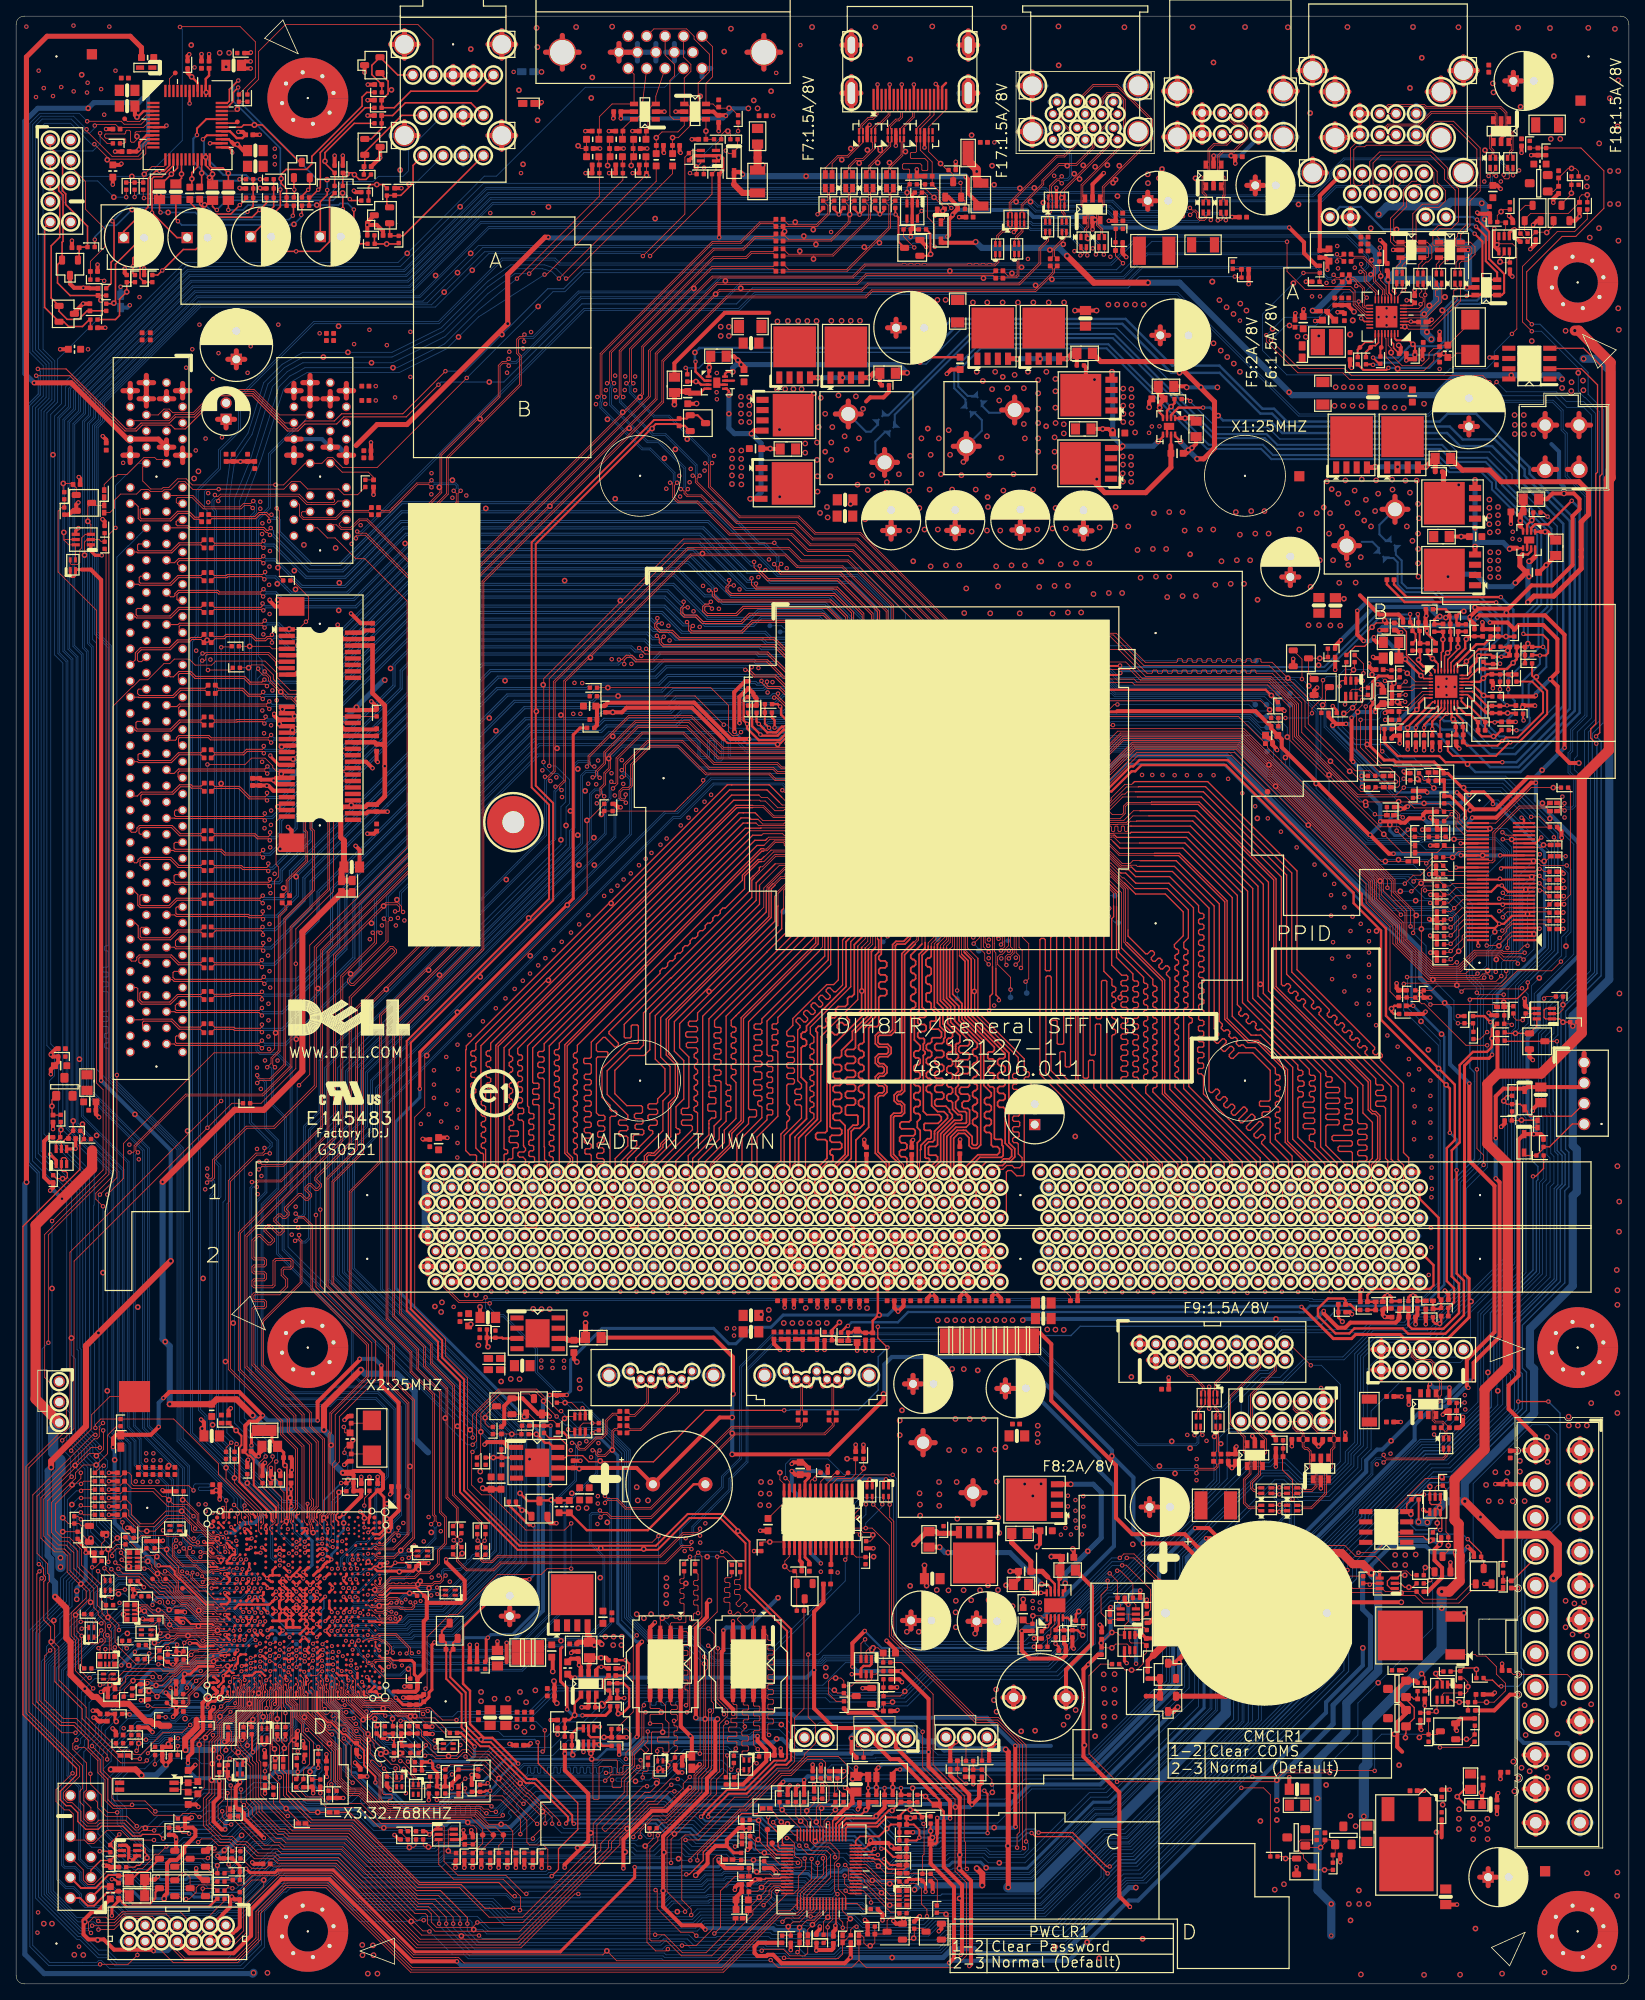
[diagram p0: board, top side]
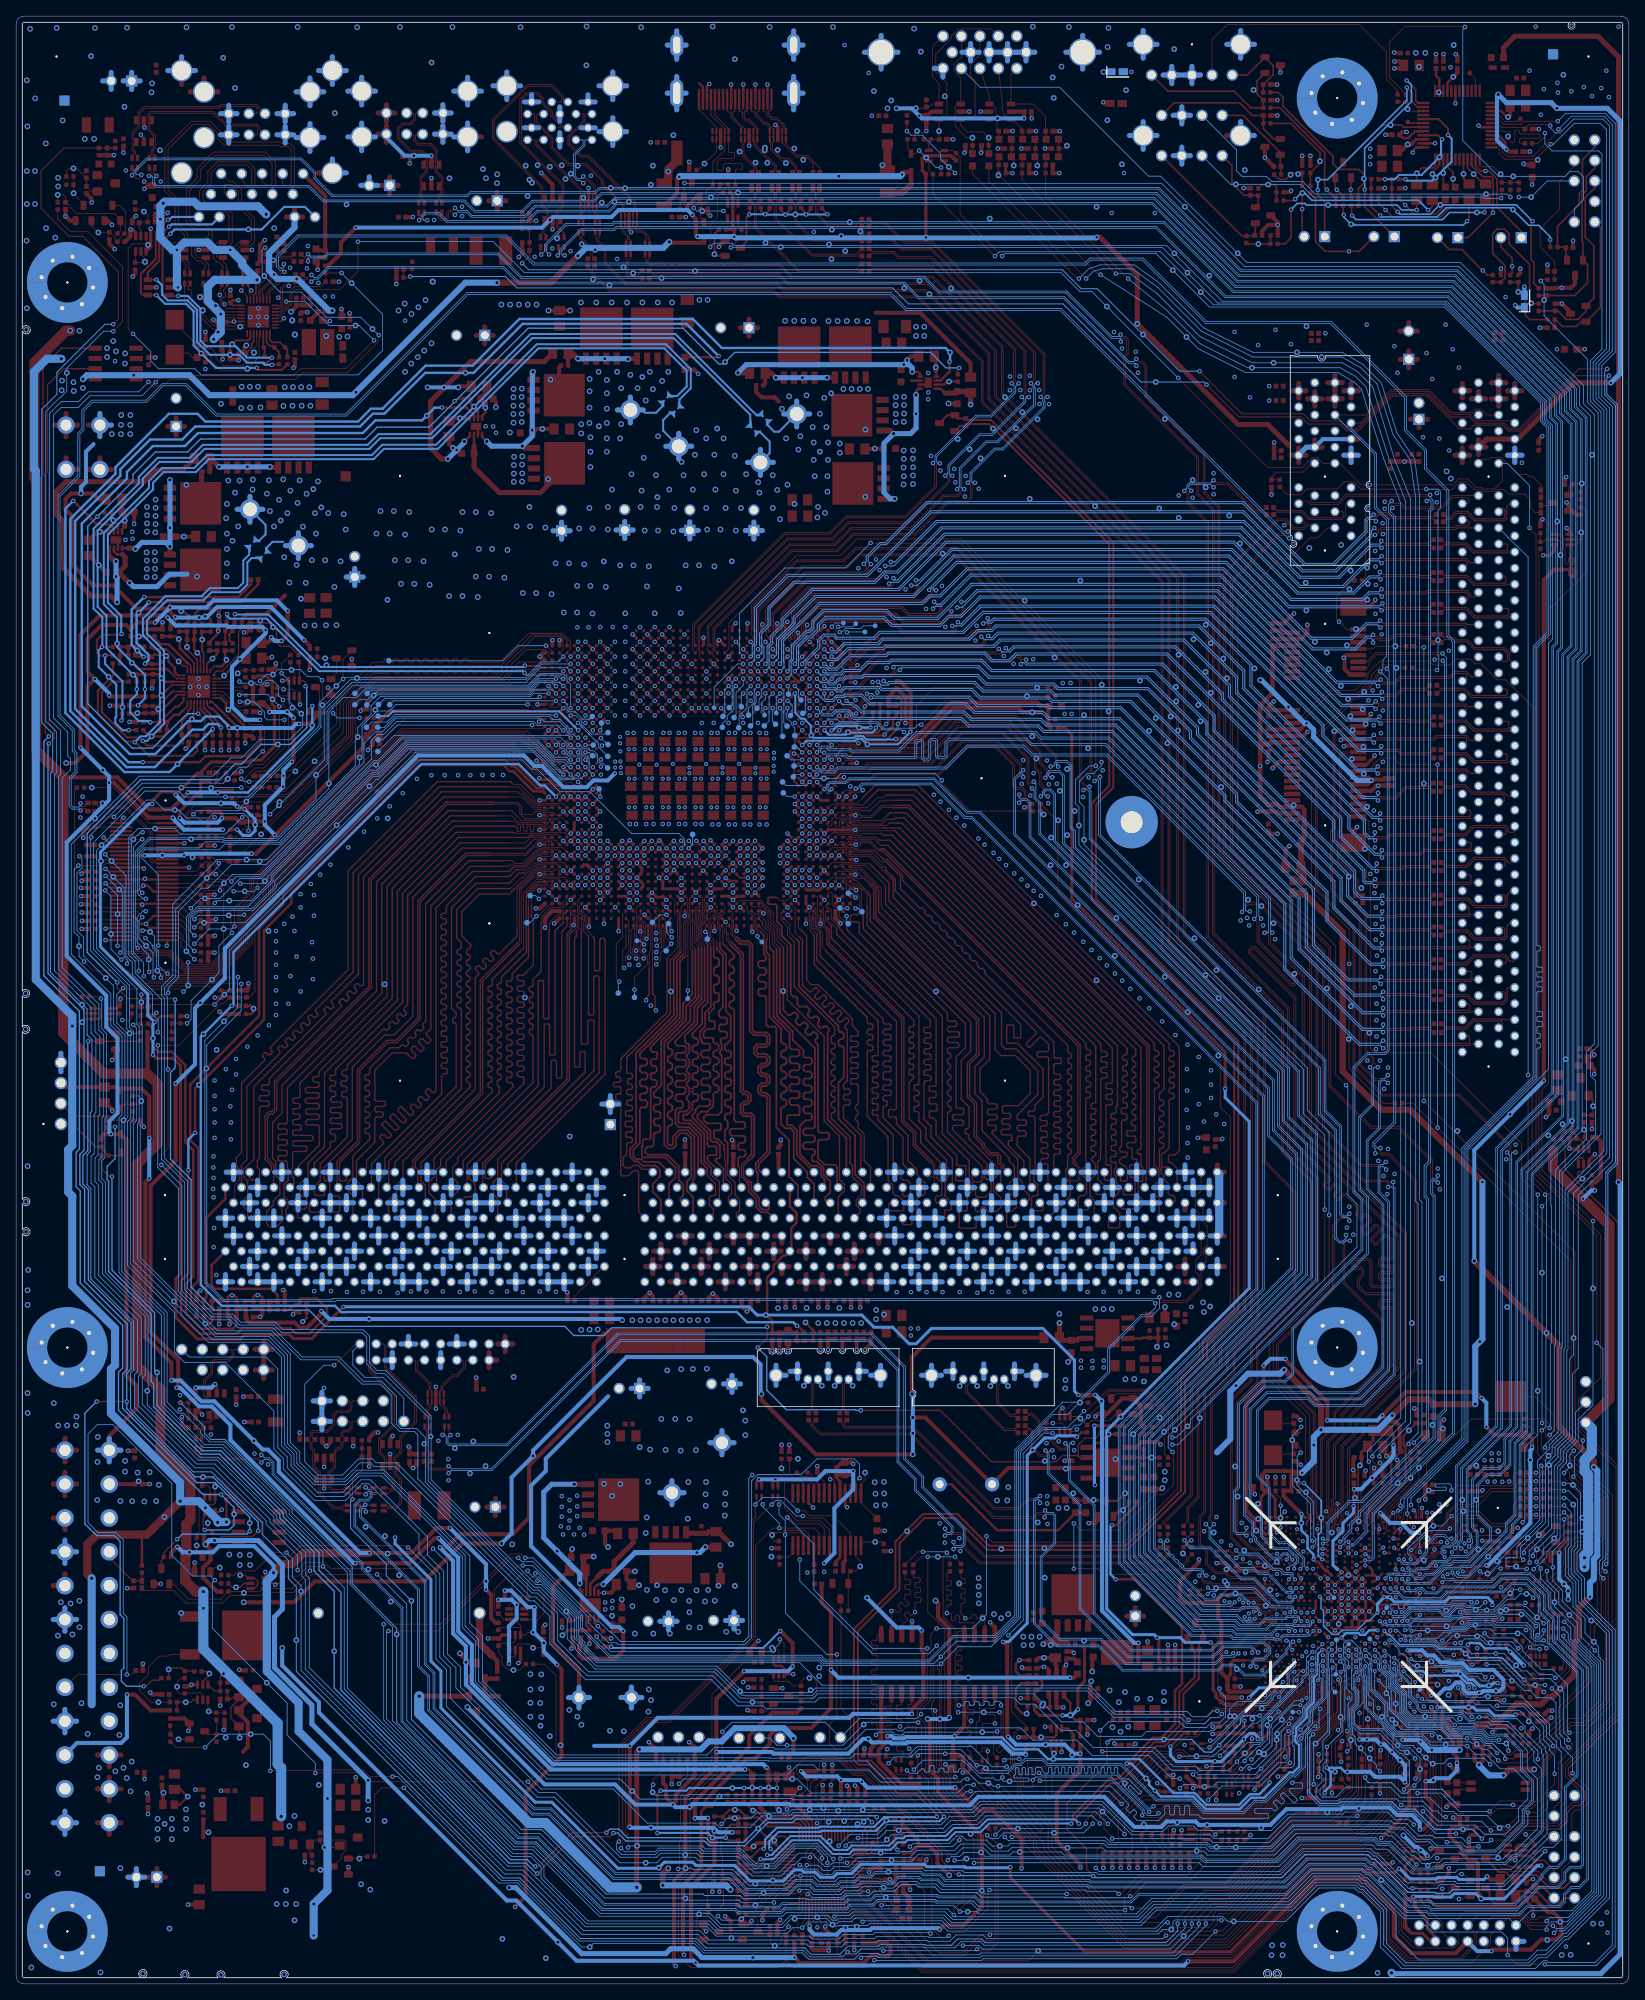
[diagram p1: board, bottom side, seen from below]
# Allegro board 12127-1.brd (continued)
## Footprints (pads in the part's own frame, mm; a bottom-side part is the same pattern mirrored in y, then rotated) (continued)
SLP2510P8-1H22
  rect 0.305x0.762 smd: 1(-1,-0.5) 5(1,-0.5) 6(1,0.5) 10(-1,0.5)
  rect 0.203x0.762 smd: 2(-0.5,-0.5) 4(0.5,-0.5) 7(0.5,0.5) 9(-0.5,0.5)
  rect 0.406x0.762 smd: 3(0,-0.5) 8(0,0.5)
SMD49-4H56
  rect 2.438x2.261 smd: 1(-2.165,0) 2(2.165,0)
SMD49-6914-0403H56
  rect 1.168x0.559 smd: 1(-3.38,-0.427) 2(3.38,-0.427) 3(3.38,0.427) 4(-3.38,0.427)
SMD-ARES4
  rect 0.356x0.66 smd: 1(-0.325,-0.599) 2(0.325,-0.599) 3(0.325,0.599) 4(-0.325,0.599)
SMD-ARES4H18
  rect 0.356x0.66 smd: 1(-0.325,-0.599) 2(0.325,-0.599) 3(0.325,0.599) 4(-0.325,0.599)
SMD-TO-252-4H94
  rect 1.6x2.997 smd: 1(-2.286,0) 3(2.286,0)
  rect 6.756x6.756 smd: 2(0,6.807)
SMD-TO-252-DGS6698H99
  rect 6.172x5.588 smd: D(0,6.808)
  rect 1.295x2.438 smd: G(-2.35,0) S(2.35,0)
SOD323AKH38
  rect 0.559x1.016 smd: A(0,1.143) K(0,-1.143)
SOD323AKH42
  rect 0.559x1.016 smd: A(0,1.143) K(0,-1.143)
SOD523AKH28
  rect 0.559x1.016 smd: A(0,0.762) K(0,-0.762)
SOIC8-1H86
  rect 0.635x1.651 smd: 1(-1.905,-3.493) 2(-0.635,-3.493) 3(0.635,-3.493) 4(1.905,-3.493) 5(1.905,3.493) 6(0.635,3.493) 7(-0.635,3.493) 8(-1.905,3.493)
SOIC8-G3530H63
  rect 0.635x1.651 smd: 1(-1.905,-2.555) 2(-0.635,-2.555) 3(0.635,-2.555) 4(1.905,-2.555) 5(1.905,2.555) 6(0.635,2.555) 7(-0.635,2.555) 8(-1.905,2.555)
  rect 3.505x2.997 smd: 9(0,0)
SOIC8H79
  rect 0.635x1.651 smd: 1(-1.905,-2.54) 2(-0.635,-2.54) 3(0.635,-2.54) 4(1.905,-2.54) 5(1.905,2.54) 6(0.635,2.54) 7(-0.635,2.54) 8(-1.905,2.54)
SOT23-2D4-312H44
  custom 0.191x0.191 smd: 1(-0.984,-0.953) 2(0.984,-0.953) 3(0,0.953)
SOT23-2D4-312H46
  custom 0.191x0.191 smd: 1(-0.984,-0.953) 2(0.984,-0.953) 3(0,0.953)
SOT23-2D4-312H48
  custom 0.191x0.191 smd: 1(-0.984,-0.953) 2(0.984,-0.953) 3(0,0.953)
SOT23CBE2D4H44
  custom 0.191x0.191 smd: B(-0.984,-0.953) C(0,0.953) E(0.984,-0.953)
SOT23DGS2D4H44
  custom 0.191x0.191 smd: D(0,0.953) G(-0.984,-0.953) S(0.984,-0.953)
SOT23DGS2D8H50
  custom 0.254x0.254 smd: D(0,1.118) G(-1.016,-1.118) S(1.016,-1.118)
SOT-6H58
  rect 0.584x1.016 smd: 1(-0.953,-1.346) 2(0,-1.346) 3(0.953,-1.346) 4(0.953,1.346) 5(0,1.346) 6(-0.953,1.346)
SOT-363H44
  rect 0.406x1.016 smd: 1(-0.65,-0.94) 2(0,-0.94) 3(0.65,-0.94) 4(0.65,0.94) 5(0,0.94) 6(-0.65,0.94)
STF256R107H132
  round 6.502 hole 2.718: 1(0,0)
T11-0061-1A40-4-U
  round 1.422 hole 1.016: 1(-5.08,-1.27) 2(-5.08,1.27) 3(-2.54,-1.27) 4(-2.54,1.27) 5(0,-1.27) 6(0,1.27) 7(2.54,-1.27) 9(5.08,-1.27) 10(5.08,1.27)
  rect 0.025x0.025 smd: 8(2.54,1.27)
TPAD24
  round 0.61 smd: 1(0,0)
TPAD28
  round 0.711 smd: 1(0,0)
TPAD385X385
  rect 3.861x3.861 smd: 1(0,0)
TSOIC28-3H44
  rect 0.356x1.524 smd: 1(-4.225,-3.669) 2(-3.575,-3.669) 3(-2.925,-3.669) 4(-2.275,-3.669) 5(-1.626,-3.669) 6(-0.975,-3.669) 7(-0.325,-3.669) 8(0.325,-3.669) 9(0.975,-3.669) 10(1.626,-3.669) 11(2.275,-3.669) 12(2.925,-3.669) 13(3.575,-3.669) 14(4.225,-3.669) 15(4.225,3.669) 16(3.575,3.669) 17(2.925,3.669) 18(2.275,3.669) 19(1.626,3.669) 20(0.975,3.669) 21(0.325,3.669) 22(-0.325,3.669) 23(-0.975,3.669) 24(-1.626,3.669) 25(-2.275,3.669) 26(-2.925,3.669) 27(-3.575,3.669) 28(-4.225,3.669)
TSOIC28H48
  rect 0.356x1.524 smd: 1(-4.225,-2.805) 2(-3.575,-2.805) 3(-2.925,-2.805) 4(-2.275,-2.805) 5(-1.626,-2.805) 6(-0.975,-2.805) 7(-0.325,-2.805) 8(0.325,-2.805) 9(0.975,-2.805) 10(1.626,-2.805) 11(2.275,-2.805) 12(2.925,-2.805) 13(3.575,-2.805) 14(4.225,-2.805) 15(4.225,2.805) 16(3.575,2.805) 17(2.925,2.805) 18(2.275,2.805) 19(1.626,2.805) 20(0.975,2.805) 21(0.325,2.805) 22(-0.325,2.805) 23(-0.975,2.805) 24(-1.626,2.805) 25(-2.275,2.805) 26(-2.925,2.805) 27(-3.575,2.805) 28(-4.225,2.805)
unnamed
  round 0.254 hole 3.099 unplated: (0,0)

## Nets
5V_DUAL: L45.2 PR83.2 Q46.D Q47.D Q51.D R736.1 R739.2
5VDDCCL: C20.1 R13.2 U24.6 VGA1.15
5VDDCCL_R: R13.1 R15.2 U4.6
5VDDCDA: C21.1 R14.2 U24.4 VGA1.12
5VDDCDA_R: R14.1 R16.2 U4.3
5VDUAL_NCH: Q49.6 R468.2 R2238.1
5VDUAL_PCH: Q49.3 R131.1 R471.2
5VDUAL_PCH_R: C96.1 Q46.G Q47.G R131.2
5VDUAL_USB_F: C410.1 F8.1 F9.2 R644.1 R734.1 U31.5 U31.6 U31.7 U31.8
5VDUAL_USB_R: C111.1 F5.1 F6.2 F18.2 U14.5 U14.6 U14.7 U14.8
+5V_VGA: C9.1 C12.1 C65.1 L4.1 U1.5 U24.5 VGA1.9
+12V: ATX1.10 ATX1.11 C121.1 C122.1 C124.1 C125.1 C146.1 C184.1 C304.1 C382.1 C408.1 D37.K FNCPU1.2 G5.2 Q38.G R352.1 R468.1 R688.1 R773.1 R2246.1 SLOT1.A2 SLOT1.A3 SLOT1.B1 SLOT1.B2 SLOT1.B3 SLOT2.A2 SLOT2.A3 SLOT2.B1 SLOT2.B2 SLOT2.B3 TC11.1
-12V: ATX1.14 C407.1
AGND: AUDF1.2 AUDF1.7 AUDJK1.1 AUDJK1.4 AUDJK1.24 AUDJK1.34 AUDJK1.G1 AUDJK1.G2 AUDJK1.G3 AUDJK1.G4 C1.2 C2.2 C3.2 C5.2 C6.2 C8.2 C13.2 C17.2 C28.2 C38.2 C55.2 C60.2 C73.1 C80.1 C82.2 C92.2 C102.2 H1.1 H1.2 H1.3 H1.4 H1.5 H1.6 H1.7 H1.8 Q9.3 Q10.3 Q11.3 Q14.3 Q17.3 R6.2 R7.2 R11.2 R12.2 R29.2 R43.2 R44.2 R77.2 R90.2 R92.2 R110.2 R117.2 R130.2 R171.2 R777.2 U2.26 U2.42
GND: ATX1.3 ATX1.5 ATX1.7 ATX1.15 ATX1.17 ATX1.18 ATX1.19 ATX1.24 ATX12V.1 ATX12V.2 BT1.2 C4.2 C9.2 C12.2 C14.2 C15.2 C18.2 C19.2 C20.2 C21.2 C22.2 C23.2 C24.2 C25.2 C26.2 C27.2 C31.2 C34.2 C35.2 C36.2 C42.2 C51.2 C53.2 C54.2 C56.2 C57.2 C59.2 C64.2 C65.2 C70.2 C71.2 C72.2 C74.2 C75.2 C76.2 C77.2 C83.2 C86.2 C88.2 C89.2 C90.2 C91.2 C93.2 C94.2 C95.2 C96.2 C97.2 C100.2 C103.2 C108.2 C111.2 C112.2 C113.2 C114.2 C119.2 C120.2 C121.2 C122.2 C123.2 C124.2 C125.2 C127.2 C128.1 C129.2 C132.2 C133.2 C134.2 C135.2 C136.2 C137.2 C139.2 C140.2 C141.2 C142.2 C143.2 C144.2 C145.2 C146.2 C151.2 C152.2 C153.2 C172.2 C174.2 C177.1 C179.2 C180.1 C181.2 C183.2 C184.2 C186.2 C187.2 C191.2 C194.2 C195.2 C198.2 C200.2 C202.2 C205.2 C213.2 C227.2 C229.2 C231.2 C232.2 C235.2 C236.2 C237.1 C239.2 C240.2 C252.2 C253.2 C254.2 C266.2 C267.2 C270.2 C271.2 C304.2 C306.2 C308.2 C310.2 C315.2 C350.2 C352.2 C353.2 C354.2 C355.2 C366.2 C368.2 C369.2 C370.2 C373.2 C374.2 C375.2 C376.2 C377.2 C378.2 C379.2 C380.2 C381.2 C382.2 C385.2 C386.2 C387.2 C388.2 C389.2 C390.2 C391.2 C392.2 C393.2 C394.2 C395.2 C396.2 C397.2 C398.2 C399.2 C400.2 C402.2 C404.2 C407.2 C408.2 C410.2 C411.2 C412.2 C414.2 C415.2 C417.2 C418.2 C420.2 C421.2 C422.2 C423.2 C424.2 C429.2 C433.2 C434.2 C435.2 C436.2 C438.2 C440.2 C441.2 C443.2 C445.2 C446.2 C447.2 C451.2 C456.2 C460.2 C461.2 C462.2 C463.2 C466.2 C467.2 C469.2 C470.2 C472.2 C475.2 C477.2 C478.2 C479.2 C483.2 C484.2 C489.2 C491.2 C496.2 C499.2 C500.2 C501.2 C502.2 C503.2 C504.2 C505.2 C506.2 C512.2 C516.2 C518.2 C520.2 C521.2 C522.2 C523.2 C524.2 C525.2 C526.2 C527.2 C528.2 C536.2 C537.2 C540.2 C541.2 C542.2 C544.2 C545.2 C546.2 C547.2 C548.2 C549.2 C550.2 C551.2 C552.2 C556.2 C557.2 C558.2 C560.2 C561.2 C562.2 C563.2 C564.2 C565.2 C566.2 C567.2 C568.2 C569.2 C570.2 C571.2 C572.2 C573.2 C574.2 C575.2 C576.2 C577.2 C578.2 C579.2 C580.2 C581.2 C582.2 C583.2 C584.2 C585.2 C586.2 C587.2 C588.2 C589.2 C590.2 C591.2 C592.2 C593.2 C594.2 C595.2 C596.2 C597.2 C598.2 C599.2 C600.2 C601.2 C602.2 C603.2 C604.2 C605.2 C606.2 C607.2 C608.2 C609.2 C610.2 C611.2 C612.2 C613.2 C614.2 C615.2 C616.2 C678.2 C680.2 C1669.2 C1671.2 C1672.2 C1673.2 C3315.2 C3316.1 C3317.1 C3318.1 C3319.1 C3320.2 C3321.2 C3322.1 C3323.1 C3324.2 C3325.2 C3326.2 C3327.2 D2.A DB1.2 DIMM1.2 DIMM1.5 DIMM1.8 DIMM1.11 DIMM1.14 DIMM1.17 DIMM1.20 DIMM1.23 DIMM1.26 DIMM1.29 DIMM1.32 DIMM1.35 DIMM1.38 DIMM1.41 DIMM1.44 DIMM1.47 DIMM1.80 DIMM1.83 DIMM1.86 DIMM1.89 DIMM1.92 DIMM1.95 DIMM1.98 DIMM1.101 DIMM1.104 DIMM1.107 DIMM1.110 DIMM1.113 DIMM1.116 DIMM1.117 DIMM1.119 DIMM1.121 DIMM1.124 DIMM1.125 DIMM1.127 DIMM1.130 DIMM1.133 DIMM1.134 DIMM1.136 DIMM1.139 DIMM1.142 DIMM1.143 DIMM1.145 DIMM1.148 DIMM1.151 DIMM1.152 DIMM1.154 DIMM1.157 DIMM1.160 DIMM1.161 DIMM1.163 DIMM1.166 DIMM1.199 DIMM1.202 DIMM1.203 DIMM1.205 DIMM1.208 DIMM1.211 DIMM1.212 DIMM1.214 DIMM1.217 DIMM1.220 DIMM1.221 DIMM1.223 DIMM1.226 DIMM1.229 DIMM1.230 DIMM1.232 DIMM1.235 DIMM1.237 DIMM1.239 DIMM2.2 DIMM2.5 DIMM2.8 DIMM2.11 DIMM2.14 DIMM2.17 DIMM2.20 DIMM2.23 DIMM2.26 DIMM2.29 DIMM2.32 DIMM2.35 DIMM2.38 DIMM2.41 DIMM2.44 DIMM2.47 DIMM2.80 DIMM2.83 DIMM2.86 DIMM2.89 DIMM2.92 DIMM2.95 DIMM2.98 DIMM2.101 DIMM2.104 DIMM2.107 DIMM2.110 DIMM2.113 DIMM2.116 DIMM2.117 DIMM2.119 DIMM2.121 DIMM2.124 DIMM2.125 DIMM2.127 DIMM2.130 DIMM2.133 DIMM2.134 DIMM2.136 DIMM2.139 DIMM2.142 DIMM2.143 DIMM2.145 DIMM2.148 DIMM2.151 DIMM2.152 DIMM2.154 DIMM2.157 DIMM2.160 DIMM2.161 DIMM2.163 DIMM2.166 DIMM2.199 DIMM2.202 DIMM2.203 DIMM2.205 DIMM2.208 DIMM2.211 DIMM2.212 DIMM2.214 DIMM2.217 DIMM2.220 DIMM2.221 DIMM2.223 DIMM2.226 DIMM2.229 DIMM2.230 DIMM2.232 DIMM2.235 DIMM2.239 DQ61.E FNCPU1.1 G7.1 H2.1 H2.2 H2.3 H2.4 H2.5 H2.6 H2.7 H2.8 H3.1 H3.2 H3.3 H3.4 H3.5 H3.6 H3.7 H3.8 H4.1 H4.2 H4.3 H4.4 H4.5 H4.6 H4.7 H4.8 H5.1 H5.2 H5.3 H5.4 H5.5 H5.6 H5.7 H5.8 H6.1 H6.2 H6.3 H6.4 H6.5 H6.6 H6.7 H6.8 H7.1 HDMI1.2 HDMI1.5 HDMI1.8 HDMI1.11 HDMI1.17 HDMI1.20 HDMI1.21 HDMI1.22 HDMI1.23 LED1.1 LEDH1.5 LEDH1.12 LPC1.12 LPC1.14 MINI1.4 MINI1.9 MINI1.15 MINI1.18 MINI1.21 MINI1.26 MINI1.27 MINI1.29 MINI1.34 MINI1.35 MINI1.43 MINI1.50 MINI1.53 MINI1.54 PC65.2 PC72.2 PC73.2 PC352.2 PR84.2 PR85.2 PR106.2 PU8.11 PWCLR1.1 Q4.S Q15.1 Q15.2 Q15.3 Q22.1 Q22.2 Q22.3 Q23.1 Q23.2 Q23.3 Q28.1 Q28.2 Q28.3 Q29.1 Q29.2 Q29.3 Q30.1 Q30.2 Q30.3 Q37.1 Q37.4 Q40.4 Q42.4 Q43.1 Q43.2 Q43.3 Q44.E Q45.E Q48.1 Q48.4 Q49.1 Q50.4 Q53.E Q54.S Q55.1 Q55.4 Q56.S Q57.E Q58.S Q59.E Q60.E Q62.1 Q62.4 Q64.1 Q64.4 Q67.1 Q70.E Q72.E Q73.1 Q73.4 Q74.E Q77.S Q78.S Q79.E Q80.S Q108.1 Q108.4 Q109.E Q110.E QF2.1 QF2.4 R11.1 R20.1 R21.1 R25.2 R29.1 R30.1 R31.1 R32.1 R67.1 R105.2 R108.2 R110.1 R111.2 R117.1 R133.1 R140.1 R145.1 R171.1 R172.1 R207.2 R209.2 R219.2 R220.2 R221.2 R225.2 R231.2 R239.2 R261.2 R288.2 R299.2 R341.1 R351.2 R358.2 R388.1 R393.2 R395.2 R398.2 R401.2 R403.2 R410.1 R412.2 R413.2 R417.2 R425.2 R426.2 R428.2 R438.2 R442.1 R445.2 R457.2 R464.2 R472.2 R476.2 R492.2 R498.2 R514.1 R518.2 R538.2 R541.2 R552.2 R554.2 R559.2 R562.2 R564.2 R571.2 R572.2 R579.1 R596.2 R597.1 R617.2 R620.2 R624.2 R633.2 R641.2 R643.2 R649.2 R650.2 R655.2 R657.2 R659.2 R661.1 R662.2 R663.1 R665.2 R668.2 R687.2 R712.2 R717.2 R736.2 R747.2 R755.2 R764.2 R793.2 R794.2 R796.2 R797.2 R798.2 R804.2 R812.2 R816.2 R818.2 R824.1 R826.1 R827.1 R828.1 R829.1 R830.1 R831.1 R832.1 R833.1 R834.1 R835.1 R836.1 R837.1 R838.1 R839.1 R840.2 R841.2 R842.1 R844.1 R845.1 R848.1 R849.1 R853.2 R856.2 R859.2 R864.2 R1248.2 R1549.2 R2215.2 R2217.2 R2219.2 R2226.2 R2231.2 RJ45.G1 RJ45.G2 RJ45.G3 RJ45.G4 RJ45.G5 RJ45.G6 RJ45.G7 RJ45.G8 RJ45.R10 RJ45.U4 RJ45.U8 RN31.3(B) RN31.4(B) RN32.3(B) RN32.4(B) RN33.1(A) RN33.2(A) RN34.3(B) RN34.4(B) SATA0.1 SATA0.4 SATA0.7 SATA0.8 SATA0.9 SATA1.1 SATA1.4 SATA1.7 SATA1.8 SATA1.9 SLOT1.A4 SLOT1.A12 SLOT1.A15 SLOT1.A18 SLOT1.B4 SLOT1.B7 SLOT1.B13 SLOT1.B16 SLOT1.B18 SLOT2.A4 SLOT2.A12 SLOT2.A15 SLOT2.A18 SLOT2.A20 SLOT2.A23 SLOT2.A24 SLOT2.A27 SLOT2.A28 SLOT2.A31 SLOT2.A34 SLOT2.A37 SLOT2.A38 SLOT2.A41 SLOT2.A42 SLOT2.A45 SLOT2.A46 SLOT2.A49 SLOT2.A51 SLOT2.A54 SLOT2.A55 SLOT2.A58 SLOT2.A59 SLOT2.A62 SLOT2.A63 SLOT2.A66 SLOT2.A67 SLOT2.A70 SLOT2.A71 SLOT2.A74 SLOT2.A75 SLOT2.A78 SLOT2.A79 SLOT2.A82 SLOT2.B4 SLOT2.B7 SLOT2.B13 SLOT2.B16 SLOT2.B18 SLOT2.B21 SLOT2.B22 SLOT2.B25 SLOT2.B26 SLOT2.B29 SLOT2.B32 SLOT2.B35 SLOT2.B36 SLOT2.B39 SLOT2.B40 SLOT2.B43 SLOT2.B44 SLOT2.B47 SLOT2.B49 SLOT2.B52 SLOT2.B53 SLOT2.B56 SLOT2.B57 SLOT2.B60 SLOT2.B61 SLOT2.B64 SLOT2.B65 SLOT2.B68 SLOT2.B69 SLOT2.B72 SLOT2.B73 SLOT2.B76 SLOT2.B77 SLOT2.B80 TC1.2 TC2.2 TC3.2 TC9.2 TC10.2 TC11.2 TC12.2 TC13.2 TC15.2 TC22.2 TC29.2 TC34.2 TC38.2 TC40.2 TC41.2 TC42.2 TC45.2 U1.2 U2.7 U6.2 U8.6 U8.9 U9.2 U10.3 U10.8 U11.2 U12.33 U13.2 U13.9 U15.3 U15.8 U16.6 U16.9 U17.2 U18.6 U18.9 U22.4 U22.11 U22.18 U23.4 U23.11 U23.18 U24.2 U25.3 U25.8 U26.2 U27.A5 U27.A7 U27.A11 U27.A13 U27.A15 U27.A17 U27.A23 U27.AA3 U27.AA6 U27.AA7 U27.AA8 U27.AA33 U27.AA35 U27.AA38 U27.AB5 U27.AB7 U27.AB34 U27.AB37 U27.AC3 U27.AC6 U27.AC7 U27.AC33 U27.AC34 U27.AC35 U27.AC36 U27.AC37 U27.AC38 U27.AC39 U27.AC40 U27.AD1 U27.AD2 U27.AD3 U27.AD4 U27.AD5 U27.AD6 U27.AD7 U27.AD8 U27.AD33 U27.AD36 U27.AE5 U27.AE8 U27.AE33 U27.AE36 U27.AE37 U27.AE40 U27.AF1 U27.AF4 U27.AF5 U27.AF8 U27.AF33 U27.AF36 U27.AG5 U27.AG8 U27.AG33 U27.AG36 U27.AG37 U27.AG38 U27.AG39 U27.AG40 U27.AH1 U27.AH2 U27.AH3 U27.AH4 U27.AH5 U27.AH8 U27.AH33 U27.AH36 U27.AJ5 U27.AJ8 U27.AJ11 U27.AJ14 U27.AJ16 U27.AJ18 U27.AJ19 U27.AJ22 U27.AJ23 U27.AJ26 U27.AJ27 U27.AJ30 U27.AJ31 U27.AJ32 U27.AJ33 U27.AJ34 U27.AJ35 U27.AJ36 U27.AJ37 U27.AJ40 U27.AK1 U27.AK4 U27.AK5 U27.AK6 U27.AK7 U27.AK8 U27.AK9 U27.AK10 U27.AK11 U27.AK12 U27.AK13 U27.AK14 U27.AK18 U27.AK19 U27.AK24 U27.AK25 U27.AK26 U27.AK27 U27.AK28 U27.AK29 U27.AK30 U27.AK36 U27.AL5 U27.AL11 U27.AL14 U27.AL17 U27.AL21 U27.AL22 U27.AL24 U27.AL27 U27.AL30 U27.AL36 U27.AL37 U27.AL38 U27.AL39 U27.AL40 U27.AM1 U27.AM2 U27.AM3 U27.AM4 U27.AM5 U27.AM11 U27.AM14 U27.AM15 U27.AM19 U27.AM24 U27.AM27 U27.AM30 U27.AM31 U27.AM32 U27.AM33 U27.AM34 U27.AM35 U27.AM36 U27.AN5 U27.AN6 U27.AN7 U27.AN8 U27.AN9 U27.AN10 U27.AN11 U27.AN14 U27.AN16 U27.AN18 U27.AN19 U27.AN22 U27.AN23 U27.AN24 U27.AN27 U27.AN30 U27.AN36 U27.AN37 U27.AN40 U27.AP1 U27.AP4 U27.AP5 U27.AP11 U27.AP14 U27.AP15 U27.AP24 U27.AP27 U27.AP30 U27.AP36 U27.AR5 U27.AR11 U27.AR14 U27.AR16 U27.AR17 U27.AR18 U27.AR19 U27.AR20 U27.AR21 U27.AR22 U27.AR23 U27.AR24 U27.AR27 U27.AR30 U27.AR31 U27.AR32 U27.AR33 U27.AR34 U27.AR35 U27.AR36 U27.AR37 U27.AR38 U27.AR39 U27.AR40 U27.AT1 U27.AT2 U27.AT3 U27.AT4 U27.AT5 U27.AT6 U27.AT7 U27.AT8 U27.AT9 U27.AT10 U27.AT11 U27.AT12 U27.AT13 U27.AT14 U27.AT15 U27.AT16 U27.AT24 U27.AT25 U27.AT26 U27.AT27 U27.AT28 U27.AT29 U27.AT30 U27.AT32 U27.AT34 U27.AT36 U27.AT38 U27.AT39 U27.AU2 U27.AU3 U27.AU5 U27.AU7 U27.AU25 U27.AU30 U27.AU34 U27.AU38 U27.AU40 U27.AV3 U27.AV7 U27.AV21 U27.AV28 U27.AV30 U27.AV34 U27.AV38 U27.AV39 U27.AW3 U27.AW7 U27.AW26 U27.AW30 U27.AW32 U27.AW34 U27.AW36 U27.AW38 U27.AY3 U27.AY5 U27.AY7 U27.AY17 U27.AY23 U27.AY26 U27.AY27 U27.AY30 U27.B4 U27.B8 U27.B10 U27.B23 U27.B24 U27.B26 U27.B28 U27.B30 U27.B32 U27.B34 U27.B36 U27.B38 U27.B39 U27.C3 U27.C4 U27.C6 U27.C12 U27.C14 U27.C16 U27.C18 U27.C19 U27.C21 U27.C23 U27.C36 U27.C40 U27.D2 U27.D5 U27.D6 U27.D7 U27.D9 U27.D11 U27.D13 U27.D15 U27.D17 U27.D23 U27.D24 U27.D26 U27.D28 U27.D30 U27.D32 U27.D34 U27.D36 U27.D37 U27.D40 U27.E3 U27.E6 U27.E7 U27.E8 U27.E10 U27.E18 U27.E20 U27.E22 U27.E23 U27.E36 U27.E38 U27.F1 U27.F4 U27.F7 U27.F12 U27.F14 U27.F16 U27.F19 U27.F21 U27.F22 U27.F24 U27.F26 U27.F28 U27.F30 U27.F32 U27.F34 U27.F36 U27.G3 U27.G6 U27.G7 U27.G9 U27.G11 U27.G12 U27.G13 U27.G14 U27.G15 U27.G16 U27.G17 U27.G21 U27.G36 U27.G37 U27.H1 U27.H4 U27.H7 U27.H8 U27.H9 U27.H10 U27.H11 U27.H13 U27.H17 U27.H18 U27.H20 U27.H21 U27.H22 U27.H24 U27.H26 U27.H28 U27.H30 U27.H32 U27.H34 U27.H36 U27.H39 U27.J3 U27.J6 U27.J7 U27.J11 U27.J14 U27.J18 U27.J19 U27.J20 U27.J36 U27.J37 U27.K1 U27.K4 U27.K7 U27.K10 U27.K14 U27.K15 U27.K16 U27.K17 U27.K18 U27.K20 U27.K22 U27.K24 U27.K26 U27.K28 U27.K30 U27.K32 U27.K34 U27.K36 U27.K40 U27.L3 U27.L6 U27.L7 U27.L8 U27.L9 U27.L11 U27.L13 U27.L14 U27.L35 U27.L36 U27.L38 U27.M1 U27.M4 U27.M5 U27.M6 U27.M7 U27.M9 U27.M12 U27.M14 U27.M16 U27.M18 U27.M20 U27.M22 U27.M24 U27.M26 U27.M28 U27.M30 U27.M32 U27.M34 U27.M35 U27.M37 U27.M40 U27.N1 U27.N2 U27.N3 U27.N4 U27.N6 U27.N7 U27.N8 U27.N33 U27.N34 U27.N39 U27.P2 U27.P5 U27.P7 U27.P34 U27.P35 U27.P38 U27.P39 U27.P40 U27.R3 U27.R5 U27.R6 U27.R7 U27.R8 U27.R35 U27.R37 U27.R38 U27.R39 U27.R40 U27.T1 U27.T2 U27.T4 U27.T5 U27.T6 U27.T7 U27.T33 U27.T36 U27.T37 U27.T38 U27.T39 U27.U2 U27.U4 U27.U7 U27.U33 U27.U34 U27.U35 U27.U36 U27.U37 U27.V3 U27.V6 U27.V8 U27.V33 U27.V34 U27.V40 U27.W1 U27.W4 U27.W7 U27.W33 U27.W35 U27.W37 U27.Y4 U27.Y5 U27.Y6 U27.Y33 U29.A12 U29.A16 U29.A21 U29.A35 U29.AA5 U29.AA8 U29.AA10 U29.AA11 U29.AA12 U29.AA14 U29.AA17 U29.AA22 U29.AA28 U29.AA30 U29.AA34 U29.AB4 U29.AB14 U29.AB28 U29.AC5 U29.AC8 U29.AC30 U29.AC31 U29.AC34 U29.AC38 U29.AD14 U29.AD26 U29.AD28 U29.AE4 U29.AE8 U29.AE12 U29.AE31 U29.AE41 U29.AF3 U29.AF14 U29.AF16 U29.AF17 U29.AF28 U29.AG2 U29.AG4 U29.AG8 U29.AG30 U29.AG34 U29.AG38 U29.AH14 U29.AH16 U29.AJ1 U29.AJ28 U29.AK9 U29.AK24 U29.AK37 U29.AL5 U29.AL11 U29.AL37 U29.AM4 U29.AM6 U29.AM8 U29.AM14 U29.AM16 U29.AM18 U29.AM20 U29.AM24 U29.AM26 U29.AM35 U29.AM38 U29.AN28 U29.AP4 U29.AP9 U29.AR11 U29.AR35 U29.AR37 U29.AT1 U29.AT7 U29.AT8 U29.AT10 U29.AT11 U29.AT14 U29.AT15 U29.AT16 U29.AT18 U29.AT20 U29.AT21 U29.AT23 U29.AT24 U29.AT28 U29.AT29 U29.AT33 U29.AT36 U29.AT38 U29.AT41 U29.AU1 U29.AU3 U29.AU39 U29.AV1 U29.AV2 U29.AV12 U29.AV17 U29.AV21 U29.AV33 U29.AV40 U29.AV41 U29.AW2 U29.AW7 U29.AW30 U29.AW40 U29.B3 U29.B25 U29.B30 U29.B33 U29.B38 U29.B40 U29.B41 U29.C6 U29.C25 U29.C37 U29.C41 U29.D1 U29.D4 U29.D6 U29.D7 U29.D8 U29.D9 U29.D12 U29.D13 U29.D14 U29.D16 U29.D18 U29.D19 U29.D20 U29.D22 U29.D24 U29.D25 U29.D26 U29.D27 U29.D28 U29.D31 U29.D32 U29.D34 U29.D37 U29.D41 U29.E3 U29.E4 U29.E5 U29.E7 U29.E12 U29.E31 U29.E35 U29.E38 U29.F18 U29.F24 U29.F35 U29.F37 U29.F38 U29.G2 U29.H4 U29.H6 U29.H8 U29.H9 U29.H14 U29.H16 U29.H20 U29.H22 U29.H26 U29.H28 U29.H33 U29.H34 U29.H38 U29.J5 U29.J31 U29.J37 U29.K4 U29.K9 U29.K31 U29.L37 U29.L41 U29.M16 U29.M18 U29.M20 U29.M22 U29.M24 U29.M26 U29.M28 U29.N4 U29.N8 U29.N31 U29.N35 U29.N38 U29.R1 U29.R8 U29.R10 U29.R34 U29.T17 U29.T22 U29.T23 U29.T25 U29.T26 U29.T28 U29.U1 U29.U4 U29.U8 U29.U31 U29.U32 U29.V26 U29.V28 U29.V38 U29.V40 U29.W3 U29.W5 U29.W8 U29.W12 U29.W20 U29.W22 U29.W28 U29.Y1 U29.Y41 U30CN1.4 U32.3 U32.8 U33.4 U34.3 U34.8 U35CN1.4 U39.4 U47.3 U47.8 U51.1 U52.33 U53.1 U53.4 U61.54 UC22.2 UC62.2 UC63.2 UC75.2 UC76.2 UC78.2 UC79.2 UC80.2 UC97.2 UC103.2 UC104.2 UC107.2 UC117.2 UC118.2 UC132.2 UC133.2 UR106.2 UR107.2 UR119.2 USB3R1.4 USB3R1.7 USB3R1.13 USB3R1.16 USB3R1.19 USB3R1.20 USB3R1.21 USB3R1.22 USBCN1.4 USBCN1.8 USBCN1.9 USBCN1.10 USBCN1.11 USBCN1.12 USBF1.7 USBF1.8 USBF2.7 USBF2.8 USBF3.4 USBF3.7 USBF3.13 USBF3.16 UTC5.2 UTC6.2 UTC7.2 UTC9.2 UU12.2 UU37.2 UU38.2 UU42.2 UU43.2 VGA1.5 VGA1.6 VGA1.7 VGA1.8 VGA1.10 VGA1.16 VGA1.17 XDPC1.1 XDPC1.2 XDPC1.7 XDPC1.8 XDPC1.13 XDPC1.14 XDPC1.19 XDPC1.20 XDPC1.25 XDPC1.26 XDPC1.31 XDPC1.32 XDPC1.37 XDPC1.38 XDPC1.49 XDPC1.50 XDPC1.59
V1P05PCH_CNTRL_INPUT: Q55.6 R243.1 R607.2
V1P05PCH_FET_CNTRL_PINS: Q55.2 Q55.3 R606.2
VBAT1: BT1.1 R392.1 TP10.1
VBAT1_R: D23.1 D26.2 R392.2 TP42.1
VBAT2: C483.1 D23.3 U61.29
VCC: ATX1.4 ATX1.6 ATX1.21 ATX1.22 ATX1.23 BZ1.1 C31.1 C456.1 C523.1 D8.A D18.A F7.2 F17.2 G6.2 LPC1.8 Q51.S R87.1 R241.2 R242.1 R293.1 R415.1 R722.1 U14.1 U31.1 U51.6
VCC3: ATX1.1 ATX1.2 ATX1.12 ATX1.13 C42.1 C54.1 C56.1 C132.1 C133.1 C134.1 C135.1 C139.1 C355.1 C366.1 C385.1 C386.1 C389.1 C394.1 C395.1 C396.1 C399.1 C402.1 C411.1 C433.1 C434.1 C467.1 C475.1 C477.1 C478.1 D21.K DIMM1.236 DIMM2.236 DIMM2.237 LPC1.4 PR134.1 Q5.G R41.1 R45.2 R50.1 R51.1 R65.1 R66.1 R78.2 R84.1 R97.2 R144.2 R257.1 R362.1 R409.2 R420.2 R423.2 R427.2 R439.2 R441.2 R458.1 R470.1 R524.2 R534.2 R560.2 R566.2 R577.1 R580.2 R583.2 R584.2 R585.2 R590.1 R593.2 R595.2 R598.1 R601.2 R609.2 R613.2 R615.2 R619.2 R627.1 R634.2 R638.1 R642.2 R647.2 R651.1 R658.2 R679.2 R683.2 R685.2 R701.1 R751.1 R752.1 R754.2 R790.1 R2218.1 R2220.1 R2235.1 R2236.1 R2243.2 RN2.5(B) RN2.6(B) RN2.7(B) RN2.8(B) RN3.5(B) RN3.6(B) RN3.7(B) RN3.8(B) RN7.5(B) RN7.6(B) RN7.7(B) RN7.8(B) RN35.3(B) RN35.4(B) RN40.1(A) RN40.2(A) RN41.1(A) RN41.2(A) RN64.3(B) RN64.4(B) RN65.3(B) RN65.4(B) RN66.3(B) RN66.4(B) SLOT1.A9 SLOT1.A10 SLOT1.B8 SLOT2.A9 SLOT2.A10 SLOT2.B8 TC13.1 U2.1 U2.9 U3.2 U3.5 U4.2 U4.5 U22.10 U22.19 U22.24 U23.10 U23.19 U23.24 U29.AF26 U29.AG1 U29.AG12 U29.AK11 U29.AM7 U29.AM9 U29.AP5 U29.AP7 U29.AR4 U29.AT5 U29.AV3 U29.AV4 U29.AW3 U29.AW4 U29.AW9 U29.U30 U29.W30 U51.5 U51.9 U61.53
VCC3_3SBREF: R537.2 R559.1 U36.1
VCC5_DDC_HDMI: C53.1 D18.K R17.1 R18.1
VCC12CPU: ATX12V.3 ATX12V.4 C179.1 C181.1 C183.1 C186.1 C200.1 C232.1 C253.1 Q13.5 Q13.6 Q13.7 Q13.8 Q16.5 Q16.6 Q16.7 Q16.8 Q26.5 Q26.6 Q26.7 Q26.8 Q27.5 Q27.6 Q27.7 Q27.8 Q31.5 Q31.6 Q31.7 Q31.8 Q32.5 Q32.6 Q32.7 Q32.8 R88.1 R182.1 R248.1 R259.1 R298.1 TC9.1 TC34.1 TC40.1
VCC_SENSE: R119.2 R229.2 R799.2 U27.E40
VCCIO2PCH: R807.2 U27.AB8
VCCST: C88.1 C141.1 R200.2 R807.1 U27.K9
VCCST_PWRGD: R2230.2 R2231.1 U27.Y7
VSS_SENSE: C130.2 R111.1 R116.2 R799.1 U27.F40
1D5V_S0_EP/SP: C266.1 C267.1 C376.1 C377.1 MINI1.6 MINI1.28 MINI1.48 R99.2 R104.2
1P05_PCH_DRV: R251.1 R283.1 U17.5
1P05_PCH_DRV_1: C208.1 R283.2
1P5_PCH_EN: R792.1 U51.8
1P05_PCH_EN: PC352.1 PR134.2 R243.2 U17.1
1P5_PCH_EN_R: Q77.D R198.2
1P05_PCH_EN_R: Q78.D R791.2
1P5_PCH_EN_R_1: C254.1 R198.1 R792.2 R2220.2
1P5_PCH_FB: PC78.2 R209.1 R222.2 U51.2
1P05_PCH_FB: C199.2 C208.2 R261.1 R279.2 U17.3
1P05_PCH_G: C209.1 Q35.4 R251.2
1P05_PCH_S1: C199.1 R277.2
1P05_PCH_S1_U: R277.1 R279.1 R287.1
1P05_PCH_SS: C194.1 U17.4
1P5V_AUX: C123.1 C202.1 L50.2 PC63.1 PR87.1 PR109.1 R173.1 R178.1 R184.1 R185.1 R186.1 R187.1 R280.1 R281.1 R290.1 TC15.1 TC42.1
100M_DMI_PCH_DN: RN33.3(B) U29.G22
100M_DMI_PCH_DP: RN33.4(B) U29.F22
5337_CTRL: C198.1 R293.2 U13.6
5337_VREF: C205.1 R286.2 R288.1 U13.3
81102_COMP: C176.2 C233.2 R139.1 U52.28
81102_COMP_1: C126.1 R126.1
81102_COMP_2: C176.1 R139.2 R212.1
81102_CSCCOMP: C185.1 C234.1 R103.2 R113.2 R120.2 U52.24
81102_CSCM_1: R113.1 R120.1 R235.1
81102_CSREF: C129.1 R96.2 R98.2 R100.2 U52.22
81102_CSSUM: C185.2 C234.2 R93.1 R94.1 R95.1 R235.2 U52.23
81102_DIFF: R126.2 R233.2 U52.30
81102_FB: C126.2 C233.1 R212.2 R220.1 R233.1 U52.29
81102_ILIM: R103.1 U52.25
81102_IOUT: C174.1 R231.1 R241.1 U52.26
81102_RAMP: C145.1 R88.2 U52.27
81102_TSENSE: C172.1 R124.1 U52.8
81102_TSENSE_R: R105.1 R124.2 R207.1
81102_VCC: C72.1 R87.2 U52.2
81102_VSN: C128.2 R116.1 U52.31
81102_VSP: C130.1 R229.1 U52.32
A20GATE: R593.1 U29.N30 U61.21
ADDR: R239.1 U16.2 U52.12
ANTI-POP_GPIO1: TP40.1 U2.4
ATX_ON*: ATX1.16 C414.1 R489.2 R495.2
AUD_AVDD: C2.1 C13.1 C17.1 U2.25 U2.38
AUD_IN_L: C11.1 U2.23
AUD_IN_LL: L16.1 R76.2 R77.1
AUD_IN_LL_1: C11.2 R76.1
AUD_IN_R: C7.1 U2.24
AUD_IN_RR: L21.1 R91.2 R92.1
AUD_IN_RR_1: C7.2 R91.1
AUD_LINK_BCLK: C59.1 RN46.2(A) U2.6
AUD_LINK_BCLK_R: RN46.7(B) U29.AV23
AUD_LINK_RST_N: RN46.3(A) U2.11
AUD_LINK_RST_R_N: RN46.6(B) U29.AU24
AUD_LINK_SDIN: R74.2 U29.AT22
AUD_LINK_SDIN_1: R74.1 U2.8
AUD_LINK_SDO: RN46.1(A) U2.5
AUD_LINK_SDO_R: Q82.C R20.2 R456.2 R618.1 RN46.8(B) U29.AU22
AUD_LINK_SDO_R1: MECLR1.2 R618.2
AUD_LINK_SYNC: RN46.4(A) U2.10
AUD_LINK_SYNC_R: RN46.5(B) U29.AV24
AUD_MIC2_L: C41.1 U2.16
AUD_MIC2_L_C: C41.2 R48.1
AUD_MIC2_R: C37.1 U2.17
AUD_MIC2_R_C: C37.2 R26.1
AUD_MIC_2L: AUDJK1.2 C73.2 FL1.2 Q17.2
AUD_MIC_2R: AUDJK1.5 C80.2 FL2.2 Q17.1
AUD_REGREF: C57.1 U2.3
AUDAMPIN_L: TC5.1 U2.35
AUDAMPIN_L_C: R53.1 TC5.2
AUDAMPIN_R: TC6.1 U2.36
AUDAMPIN_R_C: R52.1 TC6.2
AUDIN_L: AUDJK1.32 C55.1 L16.2 Q11.2
AUDIN_R: AUDJK1.35 C60.1 L21.2 Q11.1
AUDIO_VREF: C1.1 U2.27
BL_CUT1: Q40.2 R402.1
BL_CUT2: Q40.1 Q40.3 R419.2
BL_CUT3: Q40.5 R401.1 R404.2
BLUE_CRT: C22.1 L5.2 U1.3 VGA1.3
BOARD_ID_0: R650.1 R651.2 U29.M37
BOARD_ID_1: R403.1 R405.2 U29.AA40
BT_RADIO_CL: MINI1.51 R420.1 U29.AV9
BV_5VDUAL_BACKFEED_CUT_L: R465.1 R466.2 R2237.1
BV_Q49_PIN5: Q49.2 R466.1
BZ_ON: Q53.C R653.1 R654.1
BZ_ON1: BZ1.2 R653.2 R654.2
CHASSIS_ID_0: LEDH1.8 R613.1 U29.AT31
CHASSIS_ID_1: LEDH1.9 R584.1 U29.AP28
CK_14M_FLEX3: C3323.2 R153.2 U29.AU8
CK_14M_TPM: R153.1 U22.13 U23.13
CK_33M_PCI0: C3316.2 R408.2 U29.AV5
CK_33M_PCI1: C3322.2 R421.2 U29.AV7
CK_33M_PCI2: C3317.2 R396.2 U29.AU2
CK_33M_PCI3: C3318.2 R406.2 U29.AN9
CK_48M_PCH: C3319.2 R407.2 U29.AT9
CK_48M_SIO2: R407.1 U61.24
CK_96M_DREF_DN: RN34.2(A) U29.AP11
CK_96M_DREF_DP: RN34.1(A) U29.AM11
CK_100M_CPU_XDP_DN: R820.1 U29.U6
CK_100M_CPU_XDP_DP: R821.1 U29.U7
CK_CSI_PCH_IN_DN: RN31.1(A) U29.G16
CK_CSI_PCH_IN_DP: RN31.2(A) U29.F16
CK_DP_DN: U27.U5 U29.T3
CK_DP_DP: U27.U6 U29.T5
CK_DPNS_R_DN: U27.W6 U29.W2
CK_DPNS_R_DP: U27.W5 U29.U2
CK_GLAN_DN: U12.16 U29.AC11
CK_GLAN_DP: U12.15 U29.AC10
CK_M_DDR0_A_DN: DIMM1.185 U27.AY16
CK_M_DDR0_A_DP: DIMM1.184 U27.AY15
CK_M_DDR0_B_DN: DIMM2.185 U27.AM21
CK_M_DDR0_B_DP: DIMM2.184 U27.AM20
CK_M_DDR1_A_DN: DIMM1.64 U27.AV15
CK_M_DDR1_A_DP: DIMM1.63 U27.AW15
CK_M_DDR1_B_DN: DIMM2.64 U27.AP21
CK_M_DDR1_B_DP: DIMM2.63 U27.AP22
CK_P_33M_LPCP80: LPC1.1 R408.1
CK_P_33M_SIO: R406.1 U61.22
CK_P_33M_TPM: R421.1 U22.21 U23.21
CK_PCH_33M_FB: R396.1 U29.AM22
CK_PCIE_1PCIEX1_DN: SLOT1.A14 U29.R6
CK_PCIE_1PCIEX1_DP: SLOT1.A13 U29.R7
CK_PCIEX1_WLAN_DN: MINI1.11 U29.W7
CK_PCIEX1_WLAN_DP: MINI1.13 U29.W6
CK_PE_100M_16PORT_DN: SLOT2.A14 U29.AA3
CK_PE_100M_16PORT_DP: SLOT2.A13 U29.AA2
CK_PE_100M_MCP_DN: U27.V4 U29.R2
CK_PE_100M_MCP_DP: U27.V5 U29.T2
CK_REFCLK_PCH: R410.2 U29.AR7
CK_SATA_PCH_DN: RN32.1(A) U29.H35
CK_SATA_PCH_DP: RN32.2(A) U29.H36
CK_XDP_S_DN: R820.2 XDPC1.42
CK_XDP_S_DP: R821.2 XDPC1.40
CLINK_CLK: TP66.1 U29.U36
CLINK_DATA: TP67.1 U29.U35
CLINK_RST_N: TP68.1 U29.U34
COPEN*: R717.1 U61.28
CPU_FAN_CTRL_CONN: D21.A FNCPU1.4 R360.1 R362.2
CPU_FAN_CTRL_SIO: R360.2 U61.2
CPU_FAN_TACH_1: D37.A FNCPU1.3 R352.2 R356.2
CPU_FAN_TACH_L: R356.1 R357.1 R358.1
CPU_FAN_TACH_SIO: R357.2 U61.1
CPU_THERMDA: C497.1 Q12.B Q12.C U61.46
CPU_THERMTRIP_N: R127.2 R411.2 U27.F37
CPU_VSS_T8: R1248.1 U27.T8
CSN1: C103.1 C157.2 G2.2 R96.1 R240.1 U52.15
CSN2: C108.1 C164.2 G11.2 R98.1 R114.1 U52.19
CSN3: C113.1 C169.2 G9.2 R100.1 R115.1 U52.17
CSP1: G1.2 R93.2 R163.1
CSP1_R: C157.1 R163.2 R240.2 U52.14
CSP2: G10.2 R94.2 R164.1
CSP2_R: C164.1 R114.2 R164.2 U52.18
CSP3: G8.2 R95.2 R165.1
CSP3_R: C169.1 R115.2 R165.2 U52.16
DDPC_CTRL_CLK: R51.2 U3.4 U29.AN3
DDPC_CTRL_CLK_CONN: C26.1 HDMI1.15 R17.2 U3.3 U34.1 U34.10
DDPC_CTRL_DATA: R50.2 U3.1 U29.AM2
DDPC_CTRL_DATA_CONN: C27.1 HDMI1.16 R18.2 U3.6 U34.2 U34.9
DDR3_DRAMRST_N: C520.1 DIMM1.168 DIMM2.168 U27.AK22
DDR_RCOMP_0: R541.1 U27.R1
DDR_RCOMP_1: R417.1 U27.P1
DDR_RCOMP_2: R796.1 U27.R2
DDR_SHDN: R311.2 R414.2 R415.2 U53.5 U53.6
DDSP_C_HPD: Q5.S R78.1 R599.1 U29.AH5
DDSP_C_HPD_CONN: HDMI1.19 Q5.D R67.2 U34.4 U34.7
DDSP_C_TX_DN_0: C44.1 U27.E19
DDSP_C_TX_DN_1: C46.1 U27.D20
DDSP_C_TX_DN_2: C48.1 U27.E21
DDSP_C_TX_DN_3: C50.1 U27.D22
DDSP_C_TX_DP_0: C43.1 U27.D19
DDSP_C_TX_DP_1: C45.1 U27.C20
DDSP_C_TX_DP_2: C47.1 U27.D21
DDSP_C_TX_DP_3: C49.1 U27.C22
DDSP_D_TX_N0: Q4.D R57.2 R58.2 R59.2 R60.2 R61.2 R62.2 R63.2 R64.2
DDSP_D_TX_N2: Q4.G R41.2
DIMM_CA_CPU_VREF_A: C3312.1 R265.1 U27.AB38
DIMM_CA_CPU_VREF_RC: C3312.2 R793.1
DIMM_CA_VREF_A: C489.1 C607.1 C3324.1 DIMM1.67 DIMM2.67 R265.2 R851.2
DIMM_CA_VREF_A_L: R704.2 R851.1 R853.1
DIMM_DQ_CPU_VREF_A: C3310.1 R855.1 U27.AB39
DIMM_DQ_CPU_VREF_B: C3311.1 R863.1 U27.AB40
DIMM_DQ_CPU_VREF_B_RC: C3311.2 R864.1
DIMM_DQ_CPU_VREF_RC: C3310.2 R856.1
DIMM_DQ_VREF_A: C580.1 C592.1 DIMM1.1 R854.2 R855.2
DIMM_DQ_VREF_A_L: R664.2 R665.1 R854.1
DIMM_DQ_VREF_B: C591.1 C616.1 DIMM2.1 R858.2 R863.2
DIMM_DQ_VREF_B_L: R857.2 R858.1 R859.1
DISP_UTIL_CPU: TP80.1 U27.E16
DMI_IT_MR_DN0: U27.T3 U29.C20
DMI_IT_MR_DN1: U27.V1 U29.D21
DMI_IT_MR_DN2: U27.V2 U29.B22
DMI_IT_MR_DN3: U27.W3 U29.A24
DMI_IT_MR_DP0: U27.U3 U29.B20
DMI_IT_MR_DP1: U27.U1 U29.B21
DMI_IT_MR_DP2: U27.W2 U29.C22
DMI_IT_MR_DP3: U27.Y3 U29.B24
DMI_MT_IR_DN0: U27.AA5 U29.L24
DMI_MT_IR_DN1: U27.AB4 U29.G24
DMI_MT_IR_DN2: U27.AC4 U29.F26
DMI_MT_IR_DN3: U27.AC2 U29.K26
DMI_MT_IR_DP0: U27.AA4 U29.K24
DMI_MT_IR_DP1: U27.AB3 U29.H24
DMI_MT_IR_DP2: U27.AC5 U29.G26
DMI_MT_IR_DP3: U27.AC1 U29.L26
DMIRCOMP: R697.2 U29.B19
DP_COMP: R805.2 U27.R4
DRVON: C227.1 R156.2 R177.1 R203.2 U52.13
DSWVRMEN: R494.2 U29.AM41
DTR1#: R633.1 R634.1 U61.61
DUAL_V: C89.1 Q51.G R2238.2
DUAL_V_1: Q58.D R688.2 U14.2 U31.2
DUAL_V_AND: Q50.1 Q50.3
DUAL_V_AND_R: Q50.5 R486.2
DUAL_V_U: Q42.6 R459.2 U14.4 U31.4
DUAL_V_U_AND: Q42.1 Q42.3
DUAL_V_U_INV_R: Q50.2 R491.2
EAPD_DEPOP: TP48.1 U2.47
EXP_A_RX_DN0: SLOT2.A17 U27.F15
EXP_A_RX_DN1: SLOT2.A22 U27.E14
EXP_A_RX_DN2: SLOT2.A26 U27.F13
EXP_A_RX_DN3: SLOT2.A30 U27.E12
EXP_A_RX_DN4: SLOT2.A36 U27.F11
EXP_A_RX_DN5: SLOT2.A40 U27.G10
EXP_A_RX_DN6: SLOT2.A44 U27.F9
EXP_A_RX_DN7: SLOT2.A48 U27.G8
EXP_A_RX_DN8: SLOT2.A53 U27.D4
EXP_A_RX_DN9: SLOT2.A57 U27.E5
EXP_A_RX_DN10: SLOT2.A61 U27.F6
EXP_A_RX_DN11: SLOT2.A65 U27.G5
EXP_A_RX_DN12: SLOT2.A69 U27.H6
EXP_A_RX_DN13: SLOT2.A73 U27.J5
EXP_A_RX_DN14: SLOT2.A77 U27.K6
EXP_A_RX_DN15: SLOT2.A81 U27.L5
EXP_A_RX_DP0: SLOT2.A16 U27.E15
EXP_A_RX_DP1: SLOT2.A21 U27.D14
EXP_A_RX_DP2: SLOT2.A25 U27.E13
EXP_A_RX_DP3: SLOT2.A29 U27.D12
EXP_A_RX_DP4: SLOT2.A35 U27.E11
EXP_A_RX_DP5: SLOT2.A39 U27.F10
EXP_A_RX_DP6: SLOT2.A43 U27.E9
EXP_A_RX_DP7: SLOT2.A47 U27.F8
EXP_A_RX_DP8: SLOT2.A52 U27.D3
EXP_A_RX_DP9: SLOT2.A56 U27.E4
EXP_A_RX_DP10: SLOT2.A60 U27.F5
EXP_A_RX_DP11: SLOT2.A64 U27.G4
EXP_A_RX_DP12: SLOT2.A68 U27.H5
EXP_A_RX_DP13: SLOT2.A72 U27.J4
EXP_A_RX_DP14: SLOT2.A76 U27.K5
EXP_A_RX_DP15: SLOT2.A80 U27.L4
EXP_A_TX_0_C_DN: C148.2 SLOT2.B15
EXP_A_TX_0_C_DP: C149.2 SLOT2.B14
EXP_A_TX_1_C_DN: C162.2 SLOT2.B20
EXP_A_TX_1_C_DP: C158.2 SLOT2.B19
EXP_A_TX_2_C_DN: C167.2 SLOT2.B24
EXP_A_TX_2_C_DP: C165.2 SLOT2.B23
EXP_A_TX_3_C_DN: C175.2 SLOT2.B28
EXP_A_TX_3_C_DP: C173.2 SLOT2.B27
EXP_A_TX_4_C_DN: C188.2 SLOT2.B34
EXP_A_TX_4_C_DP: C193.2 SLOT2.B33
EXP_A_TX_5_C_DN: C210.2 SLOT2.B38
EXP_A_TX_5_C_DP: C207.2 SLOT2.B37
EXP_A_TX_6_C_DN: C230.2 SLOT2.B42
EXP_A_TX_6_C_DP: C216.2 SLOT2.B41
EXP_A_TX_7_C_DN: C255.2 SLOT2.B46
EXP_A_TX_7_C_DP: C244.2 SLOT2.B45
EXP_A_TX_8_C_DN: C269.2 SLOT2.B51
EXP_A_TX_8_C_DP: C265.2 SLOT2.B50
EXP_A_TX_9_C_DN: C280.2 SLOT2.B55
EXP_A_TX_9_C_DP: C279.2 SLOT2.B54
EXP_A_TX_10_C_DN: C284.2 SLOT2.B59
EXP_A_TX_10_C_DP: C281.2 SLOT2.B58
EXP_A_TX_11_C_DN: C290.2 SLOT2.B63
EXP_A_TX_11_C_DP: C291.2 SLOT2.B62
EXP_A_TX_12_C_DN: C294.2 SLOT2.B67
EXP_A_TX_12_C_DP: C292.2 SLOT2.B66
EXP_A_TX_13_C_DN: C296.2 SLOT2.B71
EXP_A_TX_13_C_DP: C295.2 SLOT2.B70
EXP_A_TX_14_C_DN: C297.2 SLOT2.B75
EXP_A_TX_14_C_DP: C299.2 SLOT2.B74
EXP_A_TX_15_C_DN: C300.2 SLOT2.B79
EXP_A_TX_15_C_DP: C301.2 SLOT2.B78
EXP_A_TX_DN0: C148.1 U27.B12
EXP_A_TX_DN1: C162.1 U27.C11
EXP_A_TX_DN2: C167.1 U27.D10
EXP_A_TX_DN3: C175.1 U27.C9
EXP_A_TX_DN4: C188.1 U27.D8
EXP_A_TX_DN5: C210.1 U27.C7
EXP_A_TX_DN6: C230.1 U27.B6
EXP_A_TX_DN7: C255.1 U27.C5
EXP_A_TX_DN8: C269.1 U27.E2
EXP_A_TX_DN9: C280.1 U27.F3
EXP_A_TX_DN10: C284.1 U27.G2
EXP_A_TX_DN11: C290.1 U27.H3
EXP_A_TX_DN12: C294.1 U27.J2
EXP_A_TX_DN13: C296.1 U27.K3
EXP_A_TX_DN14: C297.1 U27.M3
EXP_A_TX_DN15: C300.1 U27.L2
EXP_A_TX_DP0: C149.1 U27.A12
EXP_A_TX_DP1: C158.1 U27.B11
EXP_A_TX_DP2: C165.1 U27.C10
EXP_A_TX_DP3: C173.1 U27.B9
EXP_A_TX_DP4: C193.1 U27.C8
EXP_A_TX_DP5: C207.1 U27.B7
EXP_A_TX_DP6: C216.1 U27.A6
EXP_A_TX_DP7: C244.1 U27.B5
EXP_A_TX_DP8: C265.1 U27.E1
EXP_A_TX_DP9: C279.1 U27.F2
EXP_A_TX_DP10: C281.1 U27.G1
EXP_A_TX_DP11: C291.1 U27.H2
EXP_A_TX_DP12: C292.1 U27.J1
EXP_A_TX_DP13: C295.1 U27.K2
EXP_A_TX_DP14: C299.1 U27.M2
EXP_A_TX_DP15: C301.1 U27.L1
FB_AUDOUT_L: AUDJK1.22 C28.1 L14.2 Q14.2
FB_AUDOUT_R: AUDJK1.25 C38.1 L15.2 Q14.1
FB_AUDOUTR_L: L14.1 R44.1 R53.2
FB_AUDOUTR_R: L15.1 R43.1 R52.2
FB_USBF1_DET: R595.1 U29.N32 USBF1.10
FB_USBF2_DET: R685.1 U29.N34 USBF2.10 USBF3.10
FDI_CSYNC: U27.D16 U29.L2
FDI_INT: U27.D18 U29.L3
FDI_RCOMP: R694.1 U29.K2
FDI_TX_DN0: U27.B14 U29.N1
FDI_TX_DN1: U27.C13 U29.P2
FDI_TX_DP0: U27.A14 U29.N2
FDI_TX_DP1: U27.B13 U29.P3
FET_CNTRL_PIN: C470.1 Q55.5 R623.2
FP_AUD_DETECT: FL5.2 R441.1 U29.R31
FP_AUDIO_PRESENCE*_C: AUDF1.4 C82.1 FL5.1
FP_MIC1_L: C29.1 U2.21
FP_MIC1_LL: L1.1 R3.2 R6.1 R9.2
FP_MIC1_LL_1: C29.2 R3.1
FP_MIC1_R: C16.1 U2.22
FP_MIC1_RR: L2.1 R4.2 R7.1 R10.2
FP_MIC1_RR_1: C16.2 R4.1
FP_MICVREF_D1: D1.1 R49.1
FP_MICVREF_D2: D1.2 R27.1
FP_OUT_L: TC7.1 U2.14
FP_OUT_L_C: R118.1 TC7.2
FP_OUT_R: TC4.1 U2.15
FP_OUT_R_C: R75.1 TC4.2
FP_OUTR_L: AUDF1.9 C102.1 FL4.2 Q10.2
FP_OUTR_LL: FL4.1 R118.2 R130.1
FP_OUTR_R: AUDF1.5 C92.1 FL3.2 Q10.1
FP_OUTR_RR: FL3.1 R75.2 R90.1
FP_RST_DBR_N: R264.1 R761.2
FP_RST_PCH_N: LEDH1.7 R45.1 R761.1 U29.N36
FRONT_JD: AUDJK1.23 R73.2
FRONT_USB3_RX2+: L51.3 U47.4 U47.7 USBF3.17
FRONT_USB3_RX2-: L51.4 U47.5 U47.6 USBF3.18
FRONT_USB3_TX2+: L32.3 U47.1 U47.10 USBF3.14
FRONT_USB3_TX2-: L32.4 U47.2 U47.9 USBF3.15
FWH_ID0: LPC1.6 R662.1
GPIO_PCIE_RESET: R525.1 R659.1 U29.AN22
GPO50/JP1: R635.1 R643.1 U61.23
GREEN_CRT: C15.1 L7.2 U1.6 VGA1.2
H_CPURST_N: C567.1 R416.2 U27.M39
H_DRAMPWRGD: R138.1 R404.1 R2226.1 R2227.2 U29.AE38
H_DRAMPWRGD_CPU: R138.2 U27.AK21
H_PECI: R578.2 R674.1 U27.N37
H_PM_SYNC_0: U27.P36 U29.F40
H_PRDY_N: U27.L39 XDPC1.5
H_PREQ_N: U27.L37 XDPC1.3
H_PROCHOT_N: R112.2 R263.1 R340.1
H_PROCHOT_N_R: C153.1 R109.2 R112.1 U52.3
H_PROCHOT_R_N: R263.2 U27.K38
H_PWRGD: C512.1 R140.2 R519.1 U27.AB35 U29.D40
H_RSTOUT_XDP_N: R660.2 XDPC1.46
H_SKTOCC_N: Q54.G R795.1 U27.D38 U29.AE34
H_SKTOCC_VCORE: Q54.D Q56.G R298.2 R299.1
H_TCK: R663.2 U27.D39 XDPC1.57
H_TDI: R640.2 U27.F38 XDPC1.56
H_TDO: R2216.2 R2217.1 R2218.2 R2219.1 U27.F39 XDPC1.52
H_THERMTRIP_N: R127.1 U29.C40
H_TMS: R639.2 U27.E39 XDPC1.58
H_TRST_N: R661.2 U27.E37 XDPC1.54
H_VIDALERT_N: R128.2 R424.2 R516.1
H_VIDALERT_N_1: R341.2 R516.2 U27.B37
H_VIDALERT_N_VR: R128.1 R353.2 U52.5
H_VIDSCK: R136.2 R482.2 U27.C38
H_VIDSCK_VR: R136.1 R226.2 U52.6
H_VIDSOUT: R129.2 R800.2 U27.C37
H_VIDSOUT_VR: R102.2 R129.1 U52.4
H_VTTPWRGD: C71.1 R257.2 R258.2 U52.1
H_VTTPWRGD_R: Q37.3 R258.1 R790.2 U51.7
HD_LED_PWR1: LEDH1.1 R722.2
HDMI_DETECT: R445.1 R599.2 R2243.1 U29.AV29
HDMI_LANE0_DN: HDMI1.3 TR1.2 U32.2 U32.9
HDMI_LANE0_DN_C: C44.2 R58.1 TR1.1
HDMI_LANE0_DP: HDMI1.1 TR1.3 U32.1 U32.10
HDMI_LANE0_DP_C: C43.2 R57.1 TR1.4
HDMI_LANE1_DN: HDMI1.6 TR2.2 U32.5 U32.6
HDMI_LANE1_DN_C: C46.2 R60.1 TR2.1
HDMI_LANE1_DP: HDMI1.4 TR2.3 U32.4 U32.7
HDMI_LANE1_DP_C: C45.2 R59.1 TR2.4
HDMI_LANE2_DN: HDMI1.9 TR3.2 U25.2 U25.9
HDMI_LANE2_DN_C: C48.2 R62.1 TR3.1
HDMI_LANE2_DP: HDMI1.7 TR3.3 U25.1 U25.10
HDMI_LANE2_DP_C: C47.2 R61.1 TR3.4
HDMI_LANE3_DN: HDMI1.12 TR4.2 U25.5 U25.6
HDMI_LANE3_DN_C: C50.2 R64.1 TR4.1
HDMI_LANE3_DP: HDMI1.10 TR4.3 U25.4 U25.7
HDMI_LANE3_DP_C: C49.2 R63.1 TR4.4
HSI_DN3: SLOT1.A17 U29.F11
HSI_DN4: C85.2 U29.J11
HSI_DN5: MINI1.23 U29.G9
HSI_DP3: SLOT1.A16 U29.H11
HSI_DP4: C81.2 U29.L11
HSI_DP5: MINI1.25 U29.F9
HSI_LAN_DN4_R: C85.1 U12.18
HSI_LAN_DP4_R: C81.1 U12.17
HSO_C_DN3: C159.1 SLOT1.B15
HSO_C_DN4: C406.2 U29.B8
HSO_C_DN5: C539.1 MINI1.31
HSO_C_DP3: C160.1 SLOT1.B14
HSO_C_DP4: C405.2 U29.C8
HSO_C_DP5: C538.1 MINI1.33
HSO_C_LAN_DN4: C406.1 U12.14
HSO_C_LAN_DP4: C405.1 U12.13
HSO_DN3: C159.2 U29.B9
HSO_DN5: C539.2 U29.B7
HSO_DP3: C160.2 U29.A9
HSO_DP5: C538.2 U29.A7
HSW_PCUDEBUG_0: R826.2 U27.AA37 XDPC1.9
HSW_PCUDEBUG_1: R827.2 U27.Y38 XDPC1.11
HSW_PCUDEBUG_2: R828.2 U27.AA36 XDPC1.15
HSW_PCUDEBUG_3: R829.2 R867.2 U27.W38 XDPC1.17
HSW_PCUDEBUG_4: R830.2 U27.V39 XDPC1.27
HSW_PCUDEBUG_5: R831.2 U27.U39 XDPC1.29
HSW_PCUDEBUG_6: R832.2 U27.U40 XDPC1.33
HSW_PCUDEBUG_7: R833.2 U27.V38 XDPC1.35
HSW_PCUDEBUG_8: R834.2 U27.T40 XDPC1.10
HSW_PCUDEBUG_9: R835.2 U27.Y35 XDPC1.12
HSW_PCUDEBUG_10: R836.2 U27.AA34 XDPC1.16
HSW_PCUDEBUG_11: R837.2 U27.V37 XDPC1.18
HSW_PCUDEBUG_12: R838.2 U27.Y34 XDPC1.28
HSW_PCUDEBUG_13: R843.2 U27.U38 XDPC1.30
HSW_PCUDEBUG_14: R839.2 U27.W34 XDPC1.34
HSW_PCUDEBUG_15: R842.2 U27.V35 XDPC1.36
HSW_PCUSTB_0_DN: R845.2 U27.Y37 XDPC1.6
HSW_PCUSTB_0_DP: R844.2 U27.Y36 XDPC1.4
HSW_PCUSTB_1_DN: R849.2 U27.W36 XDPC1.24
HSW_PCUSTB_1_DP: R848.2 U27.V36 XDPC1.22
HSW_STRAP_13: QF2.3 R843.1
HSW_XDP_MBP_0: U27.G39 XDPC1.21
HSW_XDP_MBP_1: U27.J39 XDPC1.23
HWM_REF: C493.1 U61.47
IGC_EN_N: R71.1 R398.1 U29.AC40
IMAX: R225.1 U18.2 U52.11
INIT_3V: LPC1.2 R638.2
IO_SMI_N: R564.1 R580.1 U29.P37 U61.8
JDREF: R12.1 U2.40
KBRST_N: R609.1 U29.K36 U61.20
KCLK: RN7.3(A) U61.39
KDAT: RN7.4(A) U61.38
L_AD0: LPC1.5 RN40.3(B) RN58.4(B) U22.26 U23.26 U61.16
L_AD0_R: RN58.1(A) U29.AN24
L_AD1: LPC1.7 RN41.3(B) RN57.4(B) U22.23 U23.23 U61.17
L_AD1_R: RN57.1(A) U29.AP26
L_AD2: LPC1.9 RN40.4(B) RN58.3(B) U22.20 U23.20 U61.18
L_AD2_R: RN58.2(A) U29.AJ24
L_AD3: LPC1.11 RN41.4(B) RN57.3(B) U22.17 U23.17 U61.19
L_AD3_R: RN57.2(A) U29.AN26
L_BACKFEED_CUT: Q40.6 Q74.B R399.2
L_FRAME_N: LPC1.13 R439.1 R652.1 U22.22 U23.22 U61.15
L_FRAME_N_R: R652.2 U29.AP24
L_PWRDWN_N: R470.2 U22.28 U23.28
LAN_1P05_OUT: C120.1 L23.1 R80.1 U12.24
LAN_CONN_CVT: RJ45.R1 UC103.1 UC104.1
LAN_DISABLE_N: R107.1 RN42.3(B) U29.AL40
LAN_MDI0_DN: TR14.4 U12.2
LAN_MDI0_DN_C: RJ45.R3 TR14.3 U6.4
LAN_MDI0_DP: TR14.1 U12.1
LAN_MDI0_DP_C: RJ45.R2 TR14.2 U6.6
LAN_MDI1_DN: TR13.4 U12.5
LAN_MDI1_DN_C: RJ45.R5 TR13.3 U6.3
LAN_MDI1_DP: TR13.1 U12.4
LAN_MDI1_DP_C: RJ45.R4 TR13.2 U6.1
LAN_MDI2_DN: TR12.4 U12.7
LAN_MDI2_DN_C: RJ45.R7 TR12.3 U9.4
LAN_MDI2_DP: TR12.1 U12.6
LAN_MDI2_DP_C: RJ45.R6 TR12.2 U9.6
LAN_MDI3_DN: TR11.4 U12.10
LAN_MDI3_DN_C: RJ45.R9 TR11.3 U9.3
LAN_MDI3_DP: TR11.1 U12.9
LAN_MDI3_DP_C: RJ45.R8 TR11.2 U9.1
LAN_RSET: R172.2 U12.31
LAN_XTALI: C112.1 R162.2 U12.28 X1.1
LAN_XTALO: C97.1 R162.1 U12.29 X1.2
LANCLK_REQ_N: R132.2 R571.1 R573.1 U29.AA39
LANCLK_REQ_U_N: R132.1 U12.12
LANWAKE_N: R83.1 U29.AU34
LATCHED_BACKFEED_CUT: Q74.C R400.2 R467.2 R2237.2
LATCHED_BACKFEED_CUT_R: Q49.5 R464.1 R465.2
LED_L: LED1.2 R549.2
LINE2_JD: AUDF1.10 R8.2
LINE2_VREFO: TP1.1 U2.31
LINEIN_JD: AUDJK1.33 R79.2
LINK_ACTIVITY: RJ45.L1 U11.6 UR112.1
LINK_ACTIVITY_N: TP5.1 U12.27 UR112.2
LPC_DRQ0_N: R524.1 U29.AK22
LPC_DRQ1_N: FVS1.1 R534.1 U29.AK26
LPC_PME_N: R556.1 U29.AG31 U61.32
M_CAS_A_N: DIMM1.74 U27.AU9
M_CAS_B_N: DIMM2.74 U27.AP16
M_DATA_A0: DIMM1.3 U27.AD38
M_DATA_A1: DIMM1.4 U27.AD39
M_DATA_A2: DIMM1.9 U27.AF38
M_DATA_A3: DIMM1.10 U27.AF39
M_DATA_A4: DIMM1.122 U27.AD37
M_DATA_A5: DIMM1.123 U27.AD40
M_DATA_A6: DIMM1.128 U27.AF37
M_DATA_A7: DIMM1.129 U27.AF40
M_DATA_A8: DIMM1.12 U27.AH38
M_DATA_A9: DIMM1.13 U27.AH40
M_DATA_A10: DIMM1.18 U27.AK38
M_DATA_A11: DIMM1.19 U27.AK39
M_DATA_A12: DIMM1.131 U27.AH37
M_DATA_A13: DIMM1.132 U27.AH39
M_DATA_A14: DIMM1.137 U27.AK37
M_DATA_A15: DIMM1.138 U27.AK40
M_DATA_A16: DIMM1.21 U27.AM38
M_DATA_A17: DIMM1.22 U27.AM40
M_DATA_A18: DIMM1.27 U27.AP38
M_DATA_A19: DIMM1.28 U27.AP39
M_DATA_A20: DIMM1.140 U27.AM37
M_DATA_A21: DIMM1.141 U27.AM39
M_DATA_A22: DIMM1.146 U27.AP37
M_DATA_A23: DIMM1.147 U27.AP40
M_DATA_A24: DIMM1.30 U27.AU37
M_DATA_A25: DIMM1.31 U27.AV37
M_DATA_A26: DIMM1.36 U27.AU35
M_DATA_A27: DIMM1.37 U27.AV35
M_DATA_A28: DIMM1.149 U27.AT37
M_DATA_A29: DIMM1.150 U27.AW37
M_DATA_A30: DIMM1.155 U27.AT35
M_DATA_A31: DIMM1.156 U27.AW35
M_DATA_A32: DIMM1.81 U27.AV6
M_DATA_A33: DIMM1.82 U27.AY6
M_DATA_A34: DIMM1.87 U27.AV4
M_DATA_A35: DIMM1.88 U27.AU4
M_DATA_A36: DIMM1.200 U27.AW6
M_DATA_A37: DIMM1.201 U27.AU6
M_DATA_A38: DIMM1.206 U27.AW4
M_DATA_A39: DIMM1.207 U27.AY4
M_DATA_A40: DIMM1.90 U27.AR3
M_DATA_A41: DIMM1.91 U27.AR1
M_DATA_A42: DIMM1.96 U27.AN3
M_DATA_A43: DIMM1.97 U27.AN4
M_DATA_A44: DIMM1.209 U27.AR2
M_DATA_A45: DIMM1.210 U27.AR4
M_DATA_A46: DIMM1.215 U27.AN2
M_DATA_A47: DIMM1.216 U27.AN1
M_DATA_A48: DIMM1.99 U27.AL3
M_DATA_A49: DIMM1.100 U27.AL1
M_DATA_A50: DIMM1.105 U27.AJ3
M_DATA_A51: DIMM1.106 U27.AJ4
M_DATA_A52: DIMM1.218 U27.AL2
M_DATA_A53: DIMM1.219 U27.AL4
M_DATA_A54: DIMM1.224 U27.AJ2
M_DATA_A55: DIMM1.225 U27.AJ1
M_DATA_A56: DIMM1.108 U27.AG3
M_DATA_A57: DIMM1.109 U27.AG1
M_DATA_A58: DIMM1.114 U27.AE3
M_DATA_A59: DIMM1.115 U27.AE4
M_DATA_A60: DIMM1.227 U27.AG2
M_DATA_A61: DIMM1.228 U27.AG4
M_DATA_A62: DIMM1.233 U27.AE2
M_DATA_A63: DIMM1.234 U27.AE1
M_DATA_B0: DIMM2.3 U27.AE34
M_DATA_B1: DIMM2.4 U27.AE35
M_DATA_B2: DIMM2.9 U27.AG35
M_DATA_B3: DIMM2.10 U27.AH35
M_DATA_B4: DIMM2.122 U27.AD34
M_DATA_B5: DIMM2.123 U27.AD35
M_DATA_B6: DIMM2.128 U27.AG34
M_DATA_B7: DIMM2.129 U27.AH34
M_DATA_B8: DIMM2.12 U27.AL34
M_DATA_B9: DIMM2.13 U27.AL35
M_DATA_B10: DIMM2.18 U27.AK31
M_DATA_B11: DIMM2.19 U27.AL31
M_DATA_B12: DIMM2.131 U27.AK34
M_DATA_B13: DIMM2.132 U27.AK35
M_DATA_B14: DIMM2.137 U27.AK32
M_DATA_B15: DIMM2.138 U27.AL32
M_DATA_B16: DIMM2.21 U27.AP35
M_DATA_B17: DIMM2.22 U27.AN34
M_DATA_B18: DIMM2.27 U27.AN32
M_DATA_B19: DIMM2.28 U27.AN31
M_DATA_B20: DIMM2.140 U27.AN35
M_DATA_B21: DIMM2.141 U27.AP34
M_DATA_B22: DIMM2.146 U27.AP32
M_DATA_B23: DIMM2.147 U27.AP31
M_DATA_B24: DIMM2.30 U27.AL29
M_DATA_B25: DIMM2.31 U27.AM29
M_DATA_B26: DIMM2.36 U27.AP29
M_DATA_B27: DIMM2.37 U27.AR29
M_DATA_B28: DIMM2.149 U27.AM28
M_DATA_B29: DIMM2.150 U27.AL28
M_DATA_B30: DIMM2.155 U27.AR28
M_DATA_B31: DIMM2.156 U27.AP28
M_DATA_B32: DIMM2.81 U27.AR12
M_DATA_B33: DIMM2.82 U27.AP12
M_DATA_B34: DIMM2.87 U27.AL13
M_DATA_B35: DIMM2.88 U27.AL12
M_DATA_B36: DIMM2.200 U27.AR13
M_DATA_B37: DIMM2.201 U27.AP13
M_DATA_B38: DIMM2.206 U27.AM13
M_DATA_B39: DIMM2.207 U27.AM12
M_DATA_B40: DIMM2.90 U27.AP10
M_DATA_B41: DIMM2.91 U27.AP9
M_DATA_B42: DIMM2.96 U27.AP7
M_DATA_B43: DIMM2.97 U27.AP6
M_DATA_B44: DIMM2.209 U27.AR10
M_DATA_B45: DIMM2.210 U27.AR9
M_DATA_B46: DIMM2.215 U27.AR7
M_DATA_B47: DIMM2.216 U27.AR6
M_DATA_B48: DIMM2.99 U27.AM10
M_DATA_B49: DIMM2.100 U27.AL10
M_DATA_B50: DIMM2.105 U27.AL6
M_DATA_B51: DIMM2.106 U27.AM7
M_DATA_B52: DIMM2.218 U27.AM9
M_DATA_B53: DIMM2.219 U27.AL9
M_DATA_B54: DIMM2.224 U27.AM6
M_DATA_B55: DIMM2.225 U27.AL7
M_DATA_B56: DIMM2.108 U27.AJ6
M_DATA_B57: DIMM2.109 U27.AJ7
M_DATA_B58: DIMM2.114 U27.AF6
M_DATA_B59: DIMM2.115 U27.AE6
M_DATA_B60: DIMM2.227 U27.AH7
M_DATA_B61: DIMM2.228 U27.AH6
M_DATA_B62: DIMM2.233 U27.AF7
M_DATA_B63: DIMM2.234 U27.AE7
M_DQS_A_DN0: DIMM1.6 U27.AE38
M_DQS_A_DN1: DIMM1.15 U27.AJ38
M_DQS_A_DN2: DIMM1.24 U27.AN38
M_DQS_A_DN3: DIMM1.33 U27.AU36
M_DQS_A_DN4: DIMM1.84 U27.AW5
M_DQS_A_DN5: DIMM1.93 U27.AP2
M_DQS_A_DN6: DIMM1.102 U27.AK2
M_DQS_A_DN7: DIMM1.111 U27.AF2
M_DQS_A_DP0: DIMM1.7 U27.AE39
M_DQS_A_DP1: DIMM1.16 U27.AJ39
M_DQS_A_DP2: DIMM1.25 U27.AN39
M_DQS_A_DP3: DIMM1.34 U27.AV36
M_DQS_A_DP4: DIMM1.85 U27.AV5
M_DQS_A_DP5: DIMM1.94 U27.AP3
M_DQS_A_DP6: DIMM1.103 U27.AK3
M_DQS_A_DP7: DIMM1.112 U27.AF3
M_DQS_B_DN0: DIMM2.6 U27.AF34
M_DQS_B_DN1: DIMM2.15 U27.AK33
M_DQS_B_DN2: DIMM2.24 U27.AN33
M_DQS_B_DN3: DIMM2.33 U27.AN29
M_DQS_B_DN4: DIMM2.84 U27.AN13
M_DQS_B_DN5: DIMM2.93 U27.AR8
M_DQS_B_DN6: DIMM2.102 U27.AM8
M_DQS_B_DN7: DIMM2.111 U27.AG6
M_DQS_B_DP0: DIMM2.7 U27.AF35
M_DQS_B_DP1: DIMM2.16 U27.AL33
M_DQS_B_DP2: DIMM2.25 U27.AP33
M_DQS_B_DP3: DIMM2.34 U27.AN28
M_DQS_B_DP4: DIMM2.85 U27.AN12
M_DQS_B_DP5: DIMM2.94 U27.AP8
M_DQS_B_DP6: DIMM2.103 U27.AL8
M_DQS_B_DP7: DIMM2.112 U27.AG7
M_MAA_A0: DIMM1.188 U27.AU13
M_MAA_A1: DIMM1.181 U27.AV16
M_MAA_A2: DIMM1.61 U27.AU16
M_MAA_A3: DIMM1.180 U27.AW17
M_MAA_A4: DIMM1.59 U27.AU17
M_MAA_A5: DIMM1.58 U27.AW18
M_MAA_A6: DIMM1.178 U27.AV17
M_MAA_A7: DIMM1.56 U27.AT18
M_MAA_A8: DIMM1.177 U27.AU18
M_MAA_A9: DIMM1.175 U27.AT19
M_MAA_A10: DIMM1.70 U27.AW11
M_MAA_A11: DIMM1.55 U27.AV19
M_MAA_A12: DIMM1.174 U27.AU19
M_MAA_A13: DIMM1.196 U27.AY10
M_MAA_A14: DIMM1.172 U27.AT20
M_MAA_A15: DIMM1.171 U27.AU21
M_MAA_B0: DIMM2.188 U27.AL19
M_MAA_B1: DIMM2.181 U27.AK23
M_MAA_B2: DIMM2.61 U27.AM22
M_MAA_B3: DIMM2.180 U27.AM23
M_MAA_B4: DIMM2.59 U27.AP23
M_MAA_B5: DIMM2.58 U27.AL23
M_MAA_B6: DIMM2.178 U27.AY24
M_MAA_B7: DIMM2.56 U27.AV25
M_MAA_B8: DIMM2.177 U27.AU26
M_MAA_B9: DIMM2.175 U27.AW25
M_MAA_B10: DIMM2.70 U27.AP18
M_MAA_B11: DIMM2.55 U27.AY25
M_MAA_B12: DIMM2.174 U27.AV26
M_MAA_B13: DIMM2.196 U27.AR15
M_MAA_B14: DIMM2.172 U27.AV27
M_MAA_B15: DIMM2.171 U27.AY28
M_ODT_A0: DIMM1.195 U27.AW10
M_ODT_A1: DIMM1.77 U27.AY8
M_ODT_B0: DIMM2.195 U27.AM17
M_ODT_B1: DIMM2.77 U27.AL16
M_RAS_A_N: DIMM1.192 U27.AU12
M_RAS_B_N: DIMM2.192 U27.AM18
M_SBS_A0: DIMM1.71 U27.AV12
M_SBS_A1: DIMM1.190 U27.AY11
M_SBS_A2: DIMM1.52 U27.AT21
M_SBS_B0: DIMM2.71 U27.AK17
M_SBS_B1: DIMM2.190 U27.AL18
M_SBS_B2: DIMM2.52 U27.AW28
M_SCKE_A0: DIMM1.50 U27.AV22
M_SCKE_A1: DIMM1.169 U27.AT23
M_SCKE_B0: DIMM2.50 U27.AW29
M_SCKE_B1: DIMM2.169 U27.AY29
M_SCS_A_N0: DIMM1.193 U27.AU14
M_SCS_A_N1: DIMM1.76 U27.AV9
M_SCS_B_N0: DIMM2.193 U27.AP17
M_SCS_B_N1: DIMM2.76 U27.AN15
M_WE_A_N: DIMM1.73 U27.AU11
M_WE_B_N: DIMM2.73 U27.AK16
MCLK: RN7.1(A) U61.41
MDAT: RN7.2(A) U61.40
ME_CNTL: R636.1 R846.1 U29.W35
ME_CNTL_1: Q82.B R846.2
ME_CNTL_2: Q82.E R847.2
MEM_BOOT: PR111.1 PU8.10
MEM_BOOT_1: PC69.1 PR111.2
MEM_COMP_3: PC63.2 PR86.1
MEM_CS: PR106.1 PU8.2
MEM_EN: PU8.3 R422.2 U53.3
MEM_FB: PR85.1 PR86.2 PR87.2 PU8.4
MEM_HG: PR127.1 PU8.9
MEM_HG_1: PR126.1 PR127.2 Q34.4
MEM_LG: PU8.6 Q43.4
MEM_LX: L50.1 PC69.2 PR110.1 PR126.2 PU8.8 Q34.1 Q34.2 Q34.3 Q43.5 Q43.6 Q43.7 Q43.8
MEM_PG: PC72.1 PR109.2 PU8.1
MEM_RF: PR84.1 PU8.5
MEM_SNB: PC73.1 PR110.2
MEM_VCC: PC65.1 PR83.1 PU8.7
MEM_VIN: C144.1 L45.1 Q34.5 Q34.6 Q34.7 Q34.8 TC29.1 TC41.1
MIC1_JD: AUDF1.6 R68.2
MIC1_L: AUDF1.1 C5.1 L1.2 Q9.1
MIC1_R: AUDF1.3 C6.1 L2.2 Q9.2
MIC1_VREFO_L: R9.1 U2.28
MIC1_VREFO_R: R10.1 U2.32
MIC2-VREFO: D1.3 U2.30
MIC2_JD: AUDJK1.3 R5.2
MIC2_LL: FL1.1 R48.2 R49.2
MIC2_RR: FL2.1 R26.2 R27.2
MINI1_WAKE#: MINI1.1 R269.1
MINI_CLKREQ#_WLAN: R304.2 R554.1 R560.1 U29.P39
MINI_CLKREQ#_WLAN_C: MINI1.7 R304.1
MINI_POWER_CTRL: R713.1 R2239.1 U29.V41
MINI_POWER_CTRL_1: C680.1 Q108.5 R2239.2
MINI_POWER_CTRL_2: Q108.2 Q108.3 R368.2
MINI_POWER_CTRL_3: Q108.6 R369.2 R2240.1
MTST_ID: LEDH1.11 R565.1 U29.W34
P25_GND: R472.1 U22.25 U23.25
P_GNT_N1: R413.1 U29.AU31
P_GNT_N2: R841.1 U29.AV31
P_GNT_N3: R840.1 U29.R30
P_INTA_N: RN65.1(A) U29.AU29
P_INTB_N: RN3.4(A) U29.AU27
P_INTC_N: RN65.2(A) U29.AW28
P_INTD_N: RN3.3(A) U29.AV27
P_INTH_N: RN3.2(A) U29.AT27
P_PME#: R698.2 U29.AA31
P_REQ_N1: RN2.1(A) U29.AH26
P_REQ_N2: RN2.2(A) U29.AJ26
P_REQ_N3: RN2.3(A) U29.AW33
PCH_CONFIG_JUMPER: R683.1 U29.L38
PCH_GP8: R71.2 R458.2 R707.1
PCH_GP15: R72.2 U29.AC32
PCH_GP35: TP90.1 U29.M40
PCH_GP38: RN64.1(A) U29.H41
PCH_GP44: R395.1 RN42.4(B) U29.AA36
PCH_GP45: R655.1 R676.1 U29.W32
PCH_GP48: RN64.2(A) U29.L40
PCH_GP69: R615.1 R1549.1 U29.AV35
PCH_GP70_PU: RN35.2(A) U29.AK28
PCH_GP71_PU: RN35.1(A) U29.AT34
PCH_GP72_PU: R646.1 U29.AJ40
PCH_GP74_PU: R508.1 U29.AJ39
PCH_GPIO16: RN66.2(A) U29.M39
PCH_INTRUDER_N: R502.1 U29.AR41
PCH_INTVRMEN: R514.2 R515.2 U29.AV36
PCH_JTAG_RST_R: C1672.1 R562.1 R712.1 R765.2 U29.W37
PCH_JTAG_TCK: C575.1 R816.1 U29.Y40
PCH_JTAG_TDI: R764.1 R817.2 TP105.1 U29.W39
PCH_JTAG_TDO: R811.2 R818.1 TP87.1 U29.Y38
PCH_JTAG_TMS: R766.2 R812.1 TP104.1 U29.W40
PCH_MEPWROK_R: R581.2 U29.AA32
PCH_RI: R536.1 U29.AE36
PCH_RTCRST_DOWN: CMCLR1.1 R492.1
PCH_RTCRST_PULLUP: C422.1 CMCLR1.2 R497.1 R499.2 U29.AR38
PCH_RTCX1: C443.1 R553.1 U29.AN40 X3.1
PCH_RTCX2: C423.1 R553.2 U29.AN39 X3.4
PCH_SATA_LED_N: R583.1 R2234.1 SR732.1 U29.J39
PCH_SIO_DPWROK: R572.1 R604.1 R708.1 U61.7
PCH_SIO_DPWROK_1: R708.2 U29.AV38
PCH_SPKR1: Q53.B R648.2
PCH_SRTCRSTB_PULLUP: C420.1 R481.2 R497.2 R498.1 U29.AR39
PCH_SYSPWROK: C3315.1 R590.2 R759.2 U29.W31
PCIE_RCOMP: R695.2 U29.C13
PCIEX1_PRSNT2_N: R687.1 RN66.1(A) SLOT1.B17 U29.N40
PCIEX16_PRSNT2_N: R427.1 SLOT2.B17 U29.AT30
PCIRST1#: R568.2 R601.1 U61.10
PCIRST3#: LPC1.3 Q38.D R429.1 R756.1 U61.42
PECI_PCH: R578.1 U29.G40
PECI_REQ_N: R566.1 U29.G38
PECI_SIO_R: R674.2 U61.26
PEG_COMP: R307.2 U27.P3
PLTRST*_LPC: C484.1 R600.1 U61.13
PLTRST_CPU_N: R416.1 R660.1 U29.F41
PLTRST_LAN_N: R568.1 U12.19
PLTRST_MINI_N: MINI1.22 R478.2
PLTRST_N: R24.1 R600.2 U29.AA37
PLTRST_PCIE_SLOTS_N: R478.1 R488.2 R561.2
PLTRST_PEG_PCIE_SLOTS_N: Q44.C Q48.3 R533.1 R561.1 RN22.4(B)
PLTRST_PEG_SLOTS_N: R533.2 SLOT2.A11
PLTRST_SL_X1_N: C140.1 R488.1 SLOT1.A11
PLTRST_TPM_N: Q38.S R429.2 R442.2 U22.16 U23.16
PRIVACY_MSR_EN_N: R867.1 XDPC1.60
PS_ON_N: R489.1 U61.34
PSPWRGD: ATX1.8 C438.1 R491.1 R778.1 U61.6
PSPWRGD_INV: Q50.6 Q58.G R402.2 R477.2
PSPWRGD_INV_B1: Q42.5 R467.1
PSPWRGD_L: C3320.1 Q73.2 R778.2
PW_CLEAR: PWCLR1.2 R367.2 U29.AM36
PWM1_BT: R266.2 U16.1
PWM1_BT_1: C201.1 R266.1
PWM1_EN: R156.1 U16.3
PWM1_HG: R268.2 U16.8
PWM1_HG_1: Q27.4 Q31.4 R197.2 R268.1
PWM1_LG: Q28.4 Q30.4 U16.5
PWM1_LX: C201.2 G1.1 L27.1 Q27.1 Q27.2 Q27.3 Q28.5 Q28.6 Q28.7 Q28.8 Q30.5 Q30.6 Q30.7 Q30.8 Q31.1 Q31.2 Q31.3 R190.1 R197.1 U16.7
PWM1_SNB: C235.1 R190.2
PWM1_VCC: C237.2 R182.2 U16.4
PWM2_BT: R270.2 U8.1
PWM2_BT_1: C241.1 R270.1
PWM2_EN: R177.2 U8.3
PWM2_HG: R180.2 U8.8
PWM2_HG_1: Q13.4 Q16.4 R180.1 R181.2
PWM2_LG: Q15.4 Q29.4 U8.5
PWM2_LX: C241.2 G10.1 L40.1 Q13.1 Q13.2 Q13.3 Q15.5 Q15.6 Q15.7 Q15.8 Q16.1 Q16.2 Q16.3 Q29.5 Q29.6 Q29.7 Q29.8 R181.1 R196.1 U8.7
PWM2_SNB: C239.1 R196.2
PWM2_VCC: C180.2 R259.2 U8.4
PWM3_BT: R267.2 U18.1
PWM3_BT_1: C204.1 R267.1
PWM3_EN: R203.1 U18.3
PWM3_HG: R195.2 U18.8
PWM3_HG_1: Q26.4 Q32.4 R193.2 R195.1
PWM3_LG: Q22.4 Q23.4 U18.5
PWM3_LX: C204.2 G8.1 L39.1 Q22.5 Q22.6 Q22.7 Q22.8 Q23.5 Q23.6 Q23.7 Q23.8 Q26.1 Q26.2 Q26.3 Q32.1 Q32.2 Q32.3 R193.1 R245.1 U18.7
PWM3_SNB: C236.1 R245.2
PWM3_VCC: C177.2 R248.2 U18.4
PWM_CSN4: R242.2 U52.21
PWR_BTNJ_C: LEDH1.6 R625.2 R632.2
PWR_DEBUG: R159.2 R794.1 R806.2 U27.N40
PWR_LED_G: C479.1 LEDH1.4 Q59.C R644.2
PWR_LED_Y: C496.1 LEDH1.2 Q71.C R734.2
PWR_LEDJ2: Q59.B Q60.C R670.2
PWR_LEDJ3: Q60.B R672.1
PWRBTN_N: C472.1 R632.1 U61.33
PWRGD_3V: DB1.1 R581.1 R810.1 R866.2 R2230.1 U29.AT40
PWRGD_3V_B_1: Q79.B Q80.D R696.2
PWROK3: C516.1 Q79.C R754.1 R755.1 R866.1 U61.36
Q37_2: Q37.2 R256.2
Q37_5: Q37.5 R254.2
Q37_6: Q37.6 R254.1 R255.2
Q44_PIN2: C191.1 Q44.B R525.2
Q46_PIN2: Q67.2 R788.2
Q46_PIN3: Q67.3 Q77.G Q78.G R183.2
Q46_PIN6: Q67.4 Q67.6
Q48_PIN2: Q48.2 R24.2 R25.1
Q48_PIN5: Q48.5 Q48.6 RN22.3(B)
Q51_D: Q56.D R2233.2
Q54_B: C252.1 Q57.B R312.2
Q54_C: Q57.C R311.1
Q62_PIN2: Q62.2 R2234.2
Q62_PIN6: Q62.5 Q62.6 R2235.2
Q69_GATE: C505.1 Q69.2 Q69.5 Q73.3 R773.2
Q73_GATE: Q73.5 Q73.6 R776.2
QF2_1: QF2.2 R707.2
QF2_2: QF2.5 QF2.6 R616.2
REAR_USB3_RX0+: L22.3 U15.2 U15.9 USB3R1.15
REAR_USB3_RX0-: L22.4 U15.1 U15.10 USB3R1.14
REAR_USB3_RX1+: L19.3 U10.2 U10.9 USB3R1.6
REAR_USB3_RX1-: L19.4 U10.1 U10.10 USB3R1.5
REAR_USB3_TX0+: L24.3 U15.5 U15.6 USB3R1.18
REAR_USB3_TX0-: L24.4 U15.4 U15.7 USB3R1.17
REAR_USB3_TX1+: L18.3 U10.5 U10.6 USB3R1.9
REAR_USB3_TX1-: L18.4 U10.4 U10.7 USB3R1.8
RED_CRT: C14.1 L6.2 U1.4 VGA1.1
RI1#: R669.2 U61.63
ROSC: R219.1 U52.9
RSMRST*: R733.1 U61.43
RSMRST*_R: Q80.G R865.2
RSMRST_SIO_N: R668.1 R733.2 R757.1 R865.1 U29.AM40
RST1#: R657.1 R658.1 U61.57
RTL_ISOLATE: C76.1 Q64.2 R19.1 R21.2
RTL_ISOLATE_N: Q64.3 R144.1 R145.2 U12.20
RTL_ISOLATE_R: Q64.5 Q64.6 R134.1
SATA1GP: R538.1 R619.1 U29.J40
SATA2GP: R577.2 R597.2 U29.H40
SATA3GP: R598.2 R620.1 U29.N41
SATA_LED_OUT: LEDH1.3 Q62.3 R2236.2
SATA_RXN0_C: C363.1 SATA0.5
SATA_RXN1_C: C359.1 SATA1.3
SATA_RXP0_C: C364.1 SATA0.6
SATA_RXP1_C: C360.1 SATA1.2
SATA_TXN0_C: C362.1 SATA0.3
SATA_TXN1_C: C358.1 SATA1.5
SATA_TXP0_C: C361.1 SATA0.2
SATA_TXP1_C: C357.1 SATA1.6
SATAHDR_RX_DN0: C363.2 U29.B28
SATAHDR_RX_DN1: C359.2 U29.D30
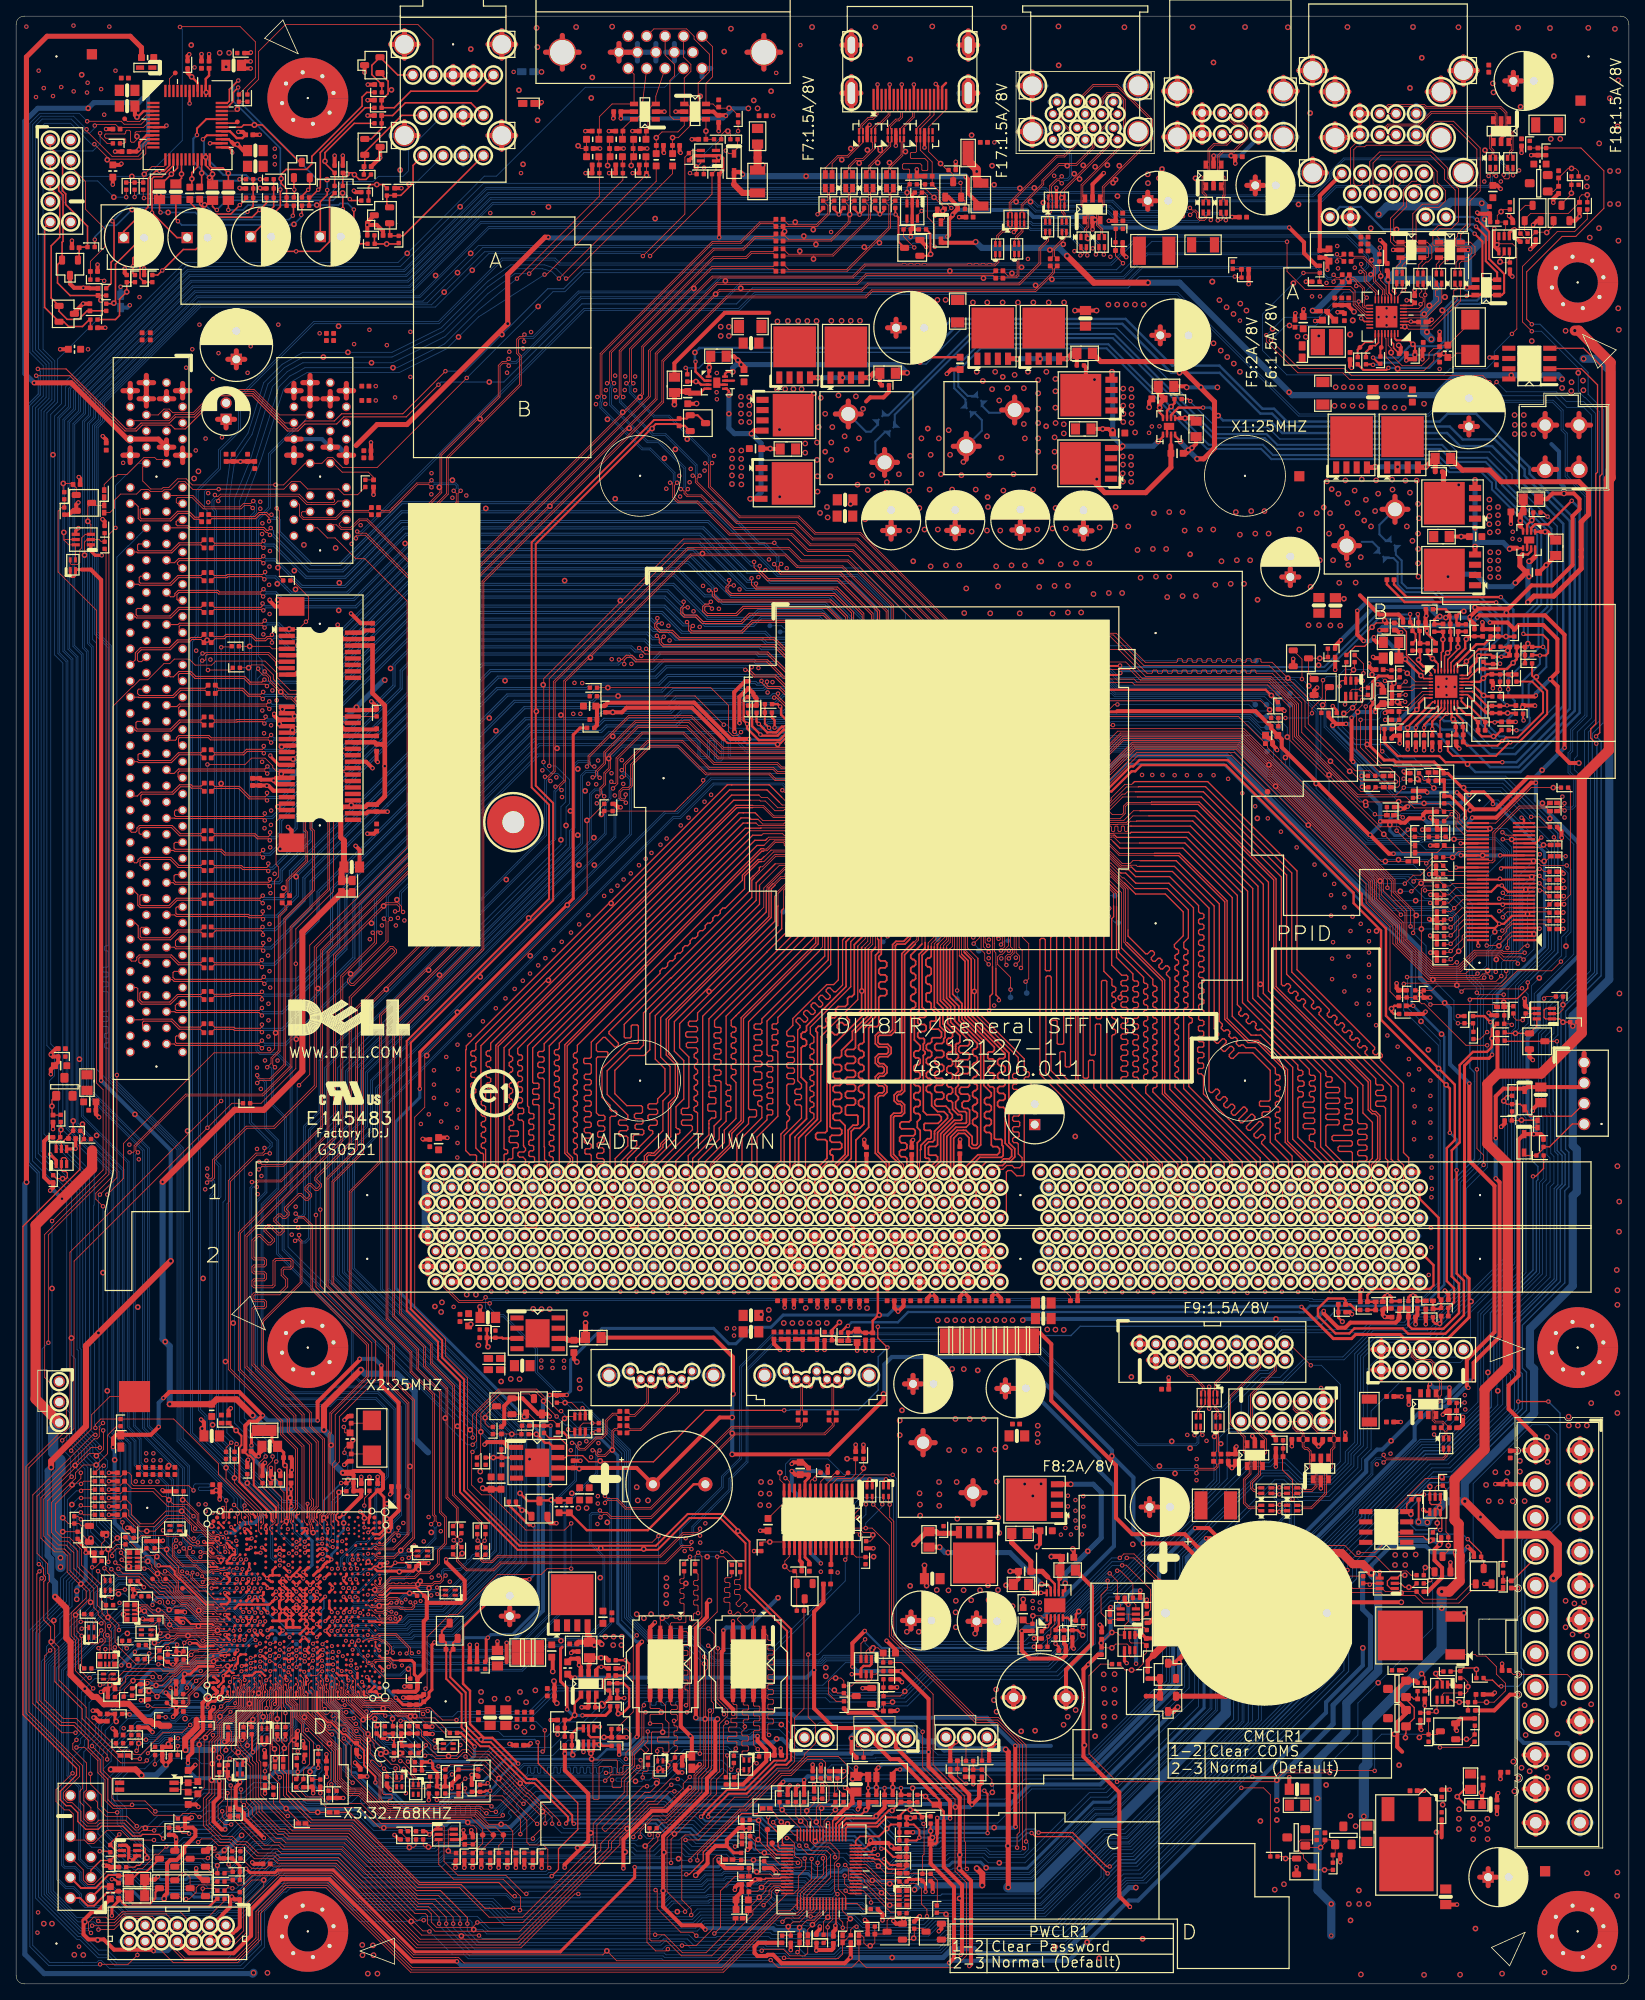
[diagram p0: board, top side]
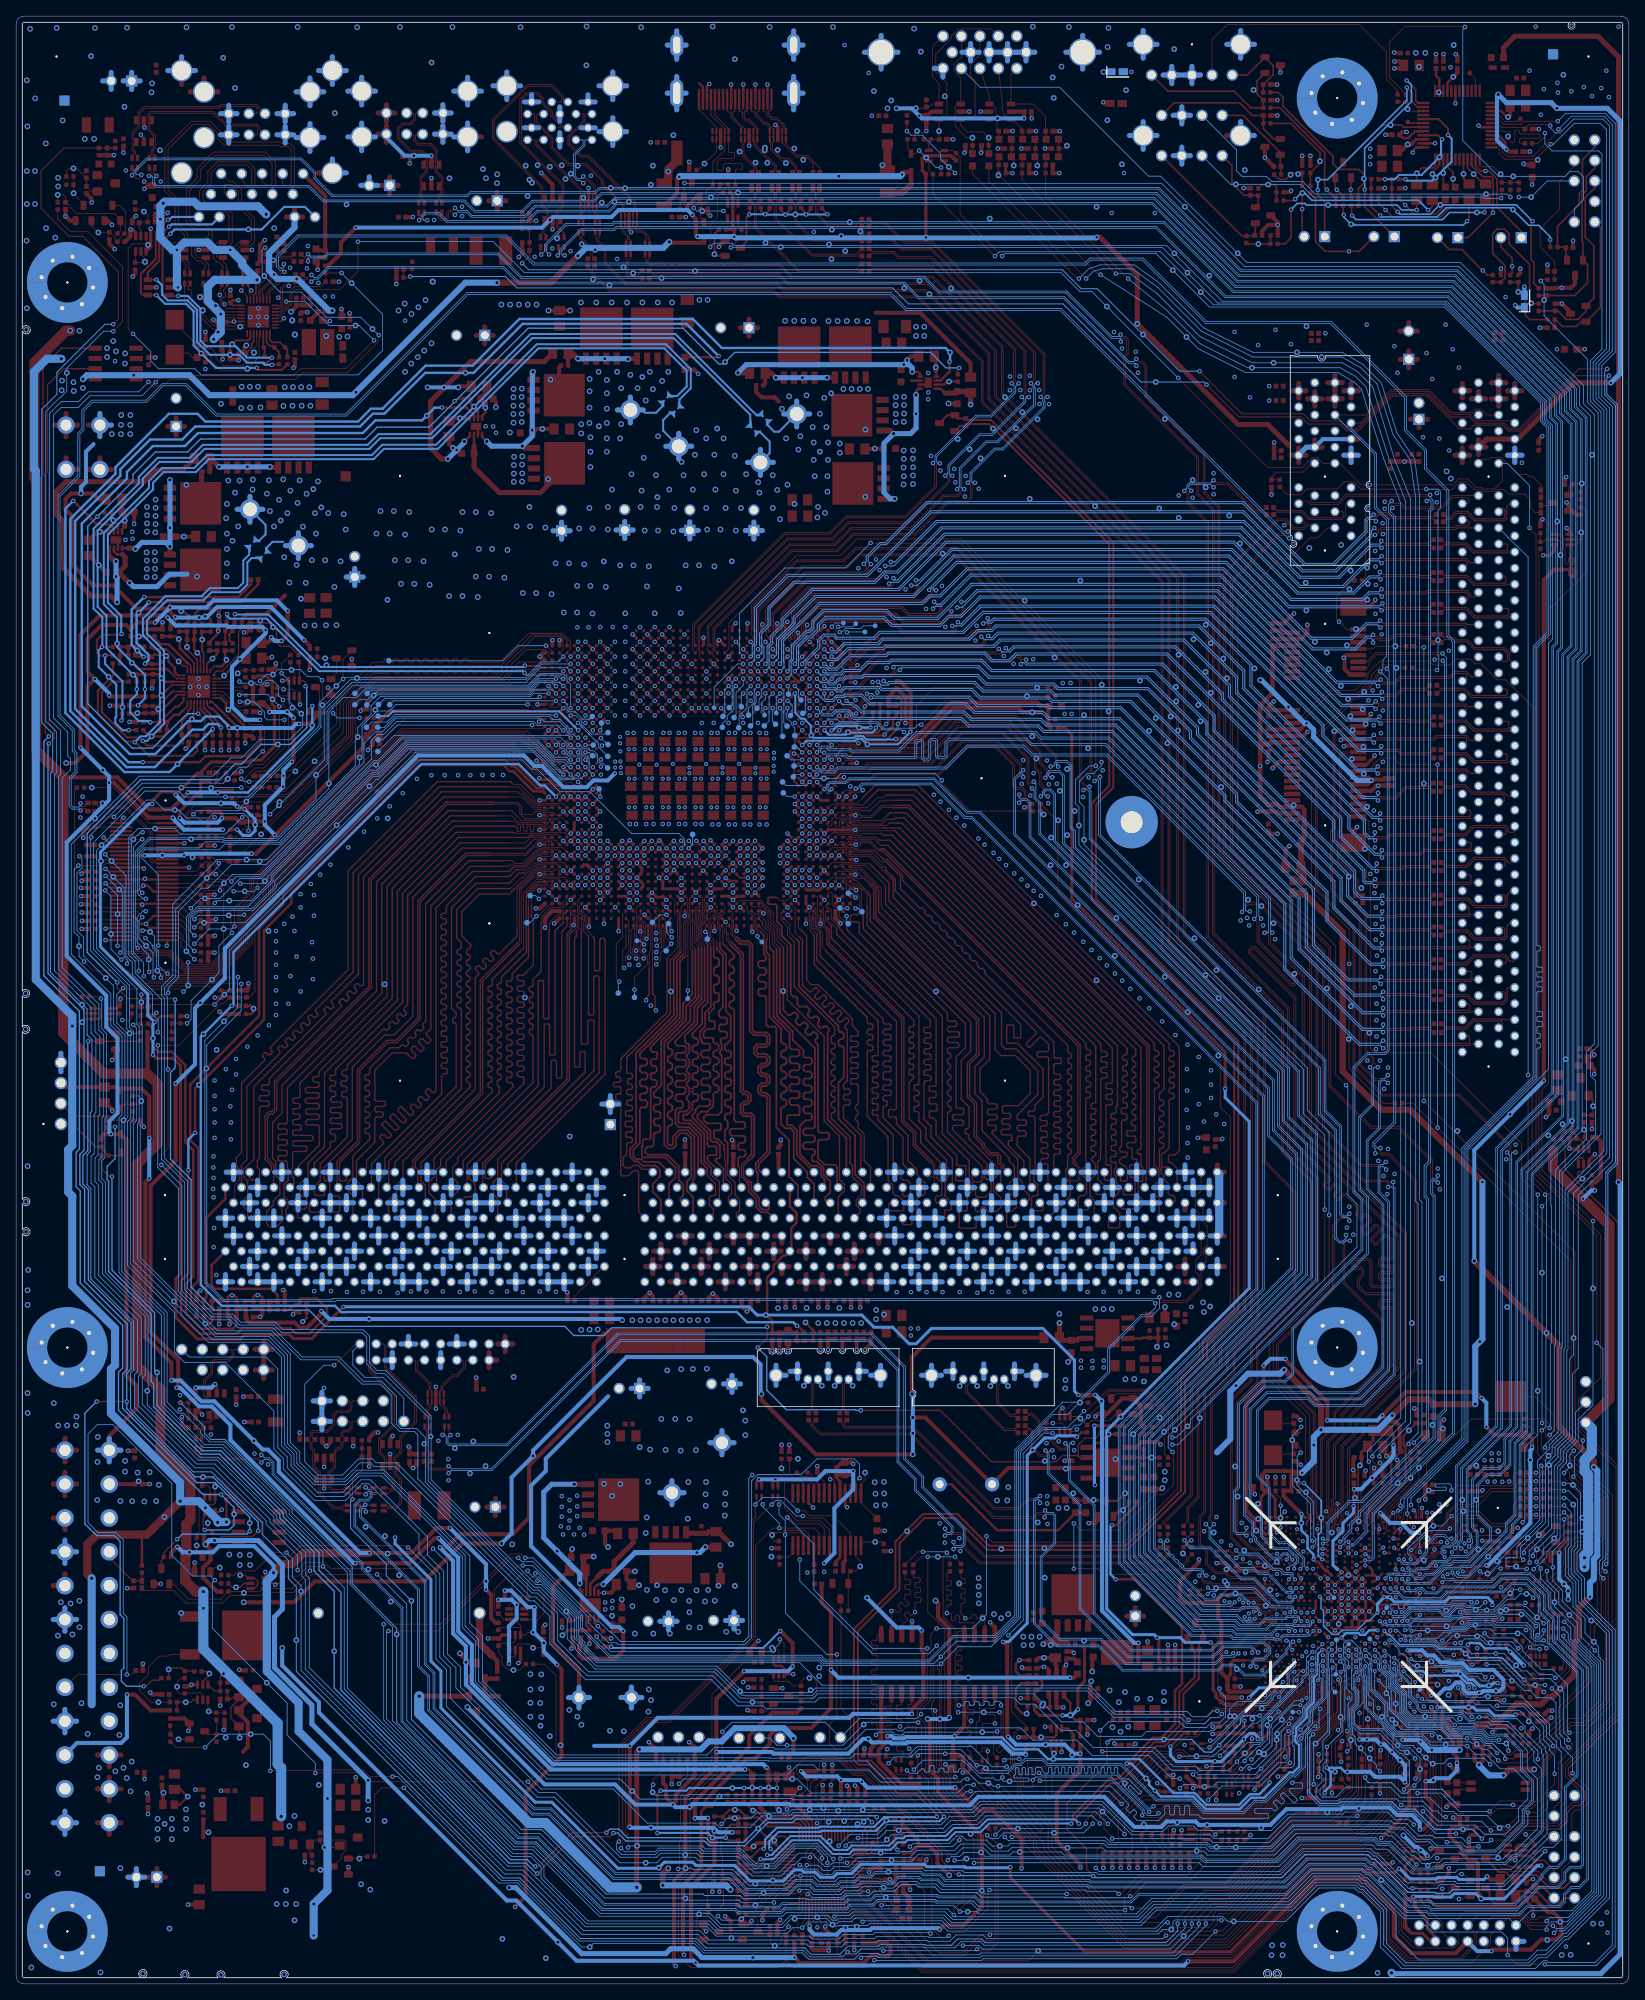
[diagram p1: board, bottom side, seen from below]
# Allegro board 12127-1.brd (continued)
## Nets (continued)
SATAHDR_RX_DP0: C364.2 U29.A28
SATAHDR_RX_DP1: C360.2 U29.C30
SATAHDR_TX_DN0: C362.2 U29.F31
SATAHDR_TX_DN1: C358.2 U29.B34
SATAHDR_TX_DP0: C361.2 U29.H31
SATAHDR_TX_DP1: C357.2 U29.C34
SATARBIAS_PCH: R576.1 U29.D33
SB3V: C310.1 C315.1 C383.1 C412.1 C436.1 C447.1 C526.1 MECLR1.3 Q6.S Q39.S Q90.D R33.2 R34.2 R69.1 R70.1 R72.1 R82.1 R134.2 R183.1 R255.1 R368.1 R369.1 R399.1 R400.1 R405.1 R419.1 R456.1 R484.2 R508.2 R526.2 R535.2 R536.2 R546.2 R550.2 R555.1 R556.2 R565.2 R570.2 R573.2 R574.2 R594.2 R607.1 R616.1 R621.2 R636.2 R669.1 R676.2 R680.1 R696.1 R698.1 R713.2 R730.1 R756.2 R757.2 R765.1 R766.1 R768.1 R776.1 R795.2 R810.2 R811.1 R817.1 R847.1 RN36.3(B) RN36.4(B) RN42.1(A) RN42.2(A) U29.AH18 U29.AH20 U29.AH22 U29.AJ20 U29.AK20 U29.AM33 U29.AN33 U29.AP35 U29.AW26 U29.P20
SB5V: L8.2 Q89.D R414.1 R422.1 R469.1 R477.1 R551.2 R606.1
SB_PWR_ON_R: R720.1 U61.31
SENSE_A: R68.1 R73.1 R79.1 U2.13
SENSE_B: R5.1 R8.1 U2.34
SER_IRQ: R585.1 U22.27 U23.27 U29.G39 U61.14
SIO_EUP_N: R605.2 U61.5
SIO_GND: C481.2 C482.2 C486.2 C490.2 C493.2 C494.2 G7.2 R710.2 R729.2 R738.2 R774.1 R775.1 U61.44
SIO_PWRLED_N: R671.2 R672.2 U61.37
SIO_SATA_LED: SR732.2 U61.64
SIO_SUSACK_N: R570.1 R602.1 R702.2 U61.9
SIO_SUSLED_N: R760.2 R767.2 U61.58
SIO_VCORE: C460.1 C461.1 U61.12
SIO_VIN0: C481.1 R684.1 U61.52
SIO_VIN0_1: G3.1 R684.2
SIO_VIN1: C482.1 R693.1 U61.51
SIO_VIN1_1: G4.1 R693.2
SIO_VIN2: C486.1 R703.1 R710.1 U61.50
SIO_VIN2_1: G5.1 R703.2
SIO_VIN3: C490.1 R723.1 R729.1 U61.49
SIO_VIN3_1: G6.1 R723.2
SIO_VIN4: C494.1 R738.1 R739.1 U61.48
SLP_A#: TP85.1 U29.AN37
SLP_LAN_B1: Q109.B Q110.C R82.2 R108.1 R705.2
SLP_LAN_B2: C3321.1 Q110.B R107.2 R705.1
SLP_LAN_G2: C64.1 C383.2 Q6.G R106.2
SLP_LAN_G3: Q109.C R70.2 R106.1
SLP_LAN_N_C: TP88.1 U29.AU36
SLP_S3_N: R256.1 R486.1 R623.1 R789.1 U29.AK40 U61.30
SLP_S3_N_Q46: Q67.5 R789.2
SLP_S4_N: R302.1 R737.2 U29.AT35 U61.35
SLP_S4_N_R: C143.1 R302.2 U53.2
SLP_S5_N: TP86.1 U29.AA35
SLP_SUS_FET: C528.1 C529.2 Q89.G Q90.G R682.2
SLP_SUS_FET_L: DQ61.C R682.1 R711.2
SLP_SUSB: R709.2 U29.AK38
SLP_SUSB_L_2: DQ61.B R709.1
SLP_WLAN_N: R563.1 U29.AL39
SMB_CLK_MAIN: DIMM1.118 DIMM2.118 Q69.4 R751.2 XDPC1.53
SMB_CLK_RESUME: MINI1.30 Q69.3 R730.2 SLOT1.B5 SLOT2.B5 U29.AG36
SMB_DATA_MAIN: DIMM1.238 DIMM2.238 Q69.1 R752.2 XDPC1.51
SMB_DATA_RESUME: MINI1.32 Q69.6 R768.2 SLOT1.B6 SLOT2.B6 U29.AG32
SMLICLK_PCH: R535.1 R667.2 U29.AK36
SMLICLK_PCH_SIO: R667.1 U61.56
SMLIDATA_PCH: R526.1 R673.2 U29.AK33
SMLIDATA_PCH_SIO: R673.1 U61.55
SMLINK0_CLK: R33.1 U29.AE32
SMLINK0_DATA: R34.1 U29.AE35
SOP_ENABLE_GP33: R423.1 R552.1 U29.AV26
SOUT1: R641.1 R642.1 U61.59
SPEED_100: RJ45.L3 U11.3 UR109.2
SPEED_100_N: TP3.1 U12.26 UR109.1
SPEED_1000: RJ45.L4 U11.1 UR108.2
SPEED_1000_N: TP4.1 U12.25 UR108.1
SPI_CLK: RN60.3(B) RN62.3(B) U29.U39
SPI_CLK_1: RN60.2(A) U30CN1.6 U33.6
SPI_CLK_2: RN62.2(A) U35CN1.6 U39.6
SPI_CS0_N: U29.R38 U30CN1.1 U33.1
SPI_CS1_N: U29.R35 U35CN1.1 U39.1
SPI_IO2: R504.2 R512.1 R542.1 U29.U40
SPI_IO3: R631.2 RN60.4(B) RN62.4(B) U29.U37
SPI_MISO: R610.1 R612.1 U29.R36
SPI_MISO_ROM_1: R610.2 U30CN1.2 U33.2
SPI_MISO_ROM_2: R612.2 U35CN1.2 U39.2
SPI_MOSI: R505.2 R629.2 U29.P40
SPI_MOSI_1: R505.1 U30CN1.5 U33.5
SPI_MOSI_2: R629.1 U35CN1.5 U39.5
SPI_WP_N_1: R512.2 U30CN1.3 U33.3
SPI_WP_N_2: R542.2 U35CN1.3 U39.3
SPKR: R648.1 R649.1 R701.2 U29.R32
SST_CTL_R: R579.2 U29.AJ31
SST_HOLDJ_1: R507.2 RN60.1(A) U30CN1.7 U33.7
SST_HOLDJ_2: R630.2 RN62.1(A) U35CN1.7 U39.7
SUS_LED4: Q71.B R767.1
SUS_LED5: Q72.B R737.1
SUS_LED6: Q71.E Q72.C
SUS_STAT_N: R594.1 U29.AD37
SUS_WARN_5VDUAL: Q70.C R769.2 R823.2
SUS_WARN_5VDUAL_L: Q49.4 R823.1 R824.2
SUS_WARNB: R666.1 R762.1 U29.AG41
SUS_WARNB_L: Q70.B R747.1 R762.2
SUS_WARNB_R: R666.2 U61.25
SUSACK_N: R702.1 U29.AJ37
SUSCLK: R2215.1 U29.W36
SW_ON_N: R637.1 R720.2 R727.2 U29.AK41
SYS_EUP_CTRL: R680.2 U61.27
SYS_FAN_CTRL_SIO: TP169.1 U61.4
SYS_FAN_TACH_SIO: TP168.1 U61.3
SYS_TEMP_SIO: C498.1 Q61.B Q61.C U61.45
TCM_BA0: R457.1 U22.9 U23.9
TCM_BA1: R476.1 U22.3 U23.3
TCM_CLK_RUN: R438.1 U22.15 U23.15
TCM_NC5#: C400.1 U22.5 U23.5
TCM_NCP: C381.1 U22.14 U23.14
TD_IREF: R133.2 U29.C3
TESTLOW_1: R798.1 U27.P6
TESTLOW_2: R804.1 U27.N5
TP_CPU_G38: TP103.1 U27.G38
TP_CPU_H37: TP107.1 U27.H37
TP_CPU_H38: TP108.1 U27.H38
TP_CPU_J38: TP109.1 U27.J38
TP_CPU_K37: TP111.1 U27.K37
TP_CPU_K39: TP110.1 U27.K39
TP_CPU_M38: TP113.1 U27.M38
TP_CPU_N36: TP165.1 U27.N36
TP_CPU_T35: TP112.1 U27.T35
TP_DISP_J12: TP76.1 U27.J12
TP_DISP_K11: TP77.1 U27.K11
TP_H_CATERR_N: TP166.1 U27.M36
TP_PCH_AE30: TP41.1 U29.AE30
TP_PCH_AN16: TP56.1 U29.AW23
TP_PCH_AT26: TP50.1 U29.AT26
TP_PCH_AV22: TP53.1 U29.AV22
TP_PCH_P19: TP51.1 U29.P19
TP_PCH_TACH2: R647.1 U29.AM28
TP_PCH_TACH3: R679.1 U29.AV34
TP_PEG_A4: TP79.1 U27.A4
TP_PEG_B3: TP78.1 U27.B3
TP_PEG_C2: TP36.1 U27.C2
TP_PEG_D1: TP35.1 U27.D1
TP_RSVD_AB6: TP167.1 U27.AB6
TP_RSVD_AB33: TP125.1 U27.AB33
TP_RSVD_AB36: TP126.1 U27.AB36
TP_RSVD_AC8: TP129.1 U27.AC8
TP_RSVD_AK20: TP160.1 U27.AK20
TP_RSVD_AT40: TP164.1 U27.AT40
TP_RSVD_AU1: TP155.1 U27.AU1
TP_RSVD_AU27: TP154.1 U27.AU27
TP_RSVD_AU39: TP153.1 U27.AU39
TP_RSVD_AV1: TP128.1 U27.AV1
TP_RSVD_AV2: TP139.1 U27.AV2
TP_RSVD_AV20: TP32.1 U27.AV20
TP_RSVD_AV24: TP152.1 U27.AV24
TP_RSVD_AV29: TP151.1 U27.AV29
TP_RSVD_AW2: TP127.1 U27.AW2
TP_RSVD_AW12: TP34.1 U27.AW12
TP_RSVD_AW23: TP150.1 U27.AW23
TP_RSVD_AW24: TP149.1 U27.AW24
TP_RSVD_AW27: TP33.1 U27.AW27
TP_RSVD_AY18: TP148.1 U27.AY18
TP_RSVD_C39: TP147.1 U27.C39
TP_RSVD_H12: TP159.1 U27.H12
TP_RSVD_H14: TP138.1 U27.H14
TP_RSVD_H15: TP136.1 U27.H15
TP_RSVD_H16: TP135.1 U27.H16
TP_RSVD_J8: TP131.1 U27.J8
TP_RSVD_J9: TP137.1 U27.J9
TP_RSVD_J10: TP141.1 U27.J10
TP_RSVD_J13: TP143.1 U27.J13
TP_RSVD_J15: TP158.1 U27.J15
TP_RSVD_J16: TP134.1 U27.J16
TP_RSVD_J17: TP157.1 U27.J17
TP_RSVD_J40: TP156.1 U27.J40
TP_RSVD_K8: TP140.1 U27.K8
TP_RSVD_K12: TP142.1 U27.K12
TP_RSVD_K13: TP130.1 U27.K13
TP_RSVD_L10: TP118.1 U27.L10
TP_RSVD_L12: TP120.1 U27.L12
TP_RSVD_M10: TP117.1 U27.M10
TP_RSVD_M11: TP119.1 U27.M11
TP_RSVD_N38: TP145.1 U27.N38
TP_RSVD_P33: TP123.1 U27.P33
TP_RSVD_P37: TP144.1 U27.P37
TP_RSVD_R33: TP122.1 U27.R33
TP_RSVD_R34: TP163.1 U27.R34
TP_RSVD_R36: TP146.1 U27.R36
TP_RSVD_T34: TP162.1 U27.T34
TP_RSVD_U8: TP124.1 U27.U8
TP_RSVD_V7: TP161.1 U27.V7
TP_RSVD_W8: TP121.1 U27.W8
TP_RSVD_Y8: TP116.1 U27.Y8
TP_TPM_PIN6: TP6.1 U22.6 U23.6
TP_TPM_PIN7: TP7.1 U22.7 U23.7
TP_V_1P05_USBSUS_INT: TP49.1 U29.AJ22
TPEV_CFG_RCOMP: R797.1 U27.H40
TSD-_1: C498.2 Q61.E R774.2
TSD-_2: C497.2 Q12.E R775.2
U17_VCC: C195.1 R2246.2 U17.6
USB3_RX0_DN: L22.1 R677.1
USB3_RX0_DP: L22.2 R681.1
USB3_RX1_DN: L19.1 U29.G18
USB3_RX1_DP: L19.2 U29.H18
USB3_RX2_DN: L51.1 R678.1
USB3_RX2_DN_P: R677.2 R678.2 U29.F20
USB3_RX2_DP: L51.2 R689.1
USB3_RX2_DP_P: R681.2 R689.2 U29.G20
USB3_TX0_C_DN: C453.1 R690.1
USB3_TX0_C_DP: C403.1 R692.1
USB3_TX0_EMI_DN: C453.2 L24.1
USB3_TX0_EMI_DP: C403.2 L24.2
USB3_TX1_C_DN: C452.1 U29.B15
USB3_TX1_C_DP: C401.1 U29.B16
USB3_TX1_EMI_DN: C452.2 L18.1
USB3_TX1_EMI_DP: C401.2 L18.2
USB3_TX2_C_DN: C430.1 R691.1
USB3_TX2_C_DN_P: R690.2 R691.2 U29.B18
USB3_TX2_C_DP: C431.1 R699.1
USB3_TX2_C_DP_P: R692.2 R699.2 U29.C18
USB3_TX2_EMI_DN: C430.2 L32.1
USB3_TX2_EMI_DP: C431.2 L32.2
USB_EXT2_DN10: C375.1 TR26.2 USBF2.3 UU38.3
USB_EXT2_DN11: C393.1 TR27.2 USBF2.4 UU38.6
USB_EXT2_DP10: C392.1 TR26.3 USBF2.5 UU38.4
USB_EXT2_DP11: C404.1 TR27.3 USBF2.6 UU38.1
USB_EXT_DN0: TR20.1 USB3R1.11 UU43.1
USB_EXT_DN1: TR19.1 USB3R1.2 UU43.4
USB_EXT_DN2: TR23.4 USBCN1.2 UU42.4
USB_EXT_DN3: TR24.4 USBCN1.6 UU42.1
USB_EXT_DN4: C373.1 TR18.1 U26.4 USBF1.4
USB_EXT_DN8: RJ45.U2 TR9.1 UU12.6
USB_EXT_DN9: RJ45.U6 TR10.1 UU12.3
USB_EXT_DN10: TR22.1 USBF3.8 UU37.1
USB_EXT_DN11: TR25.1 USBF3.12 UU37.4
USB_EXT_DP0: TR20.4 USB3R1.12 UU43.6
USB_EXT_DP1: TR19.4 USB3R1.3 UU43.3
USB_EXT_DP2: TR23.1 USBCN1.3 UU42.3
USB_EXT_DP3: TR24.1 USBCN1.7 UU42.6
USB_EXT_DP4: C374.1 TR18.4 U26.3 USBF1.6
USB_EXT_DP8: RJ45.U3 TR9.4 UU12.1
USB_EXT_DP9: RJ45.U7 TR10.4 UU12.4
USB_EXT_DP10: TR22.4 USBF3.9 UU37.6
USB_EXT_DP11: TR25.4 USBF3.11 UU37.3
USB_OC0_R_N: R521.1 U29.AE40
USB_OC1_R_N: R496.1 U29.AF37
USB_OC2_R_N: R523.1 U29.AD39
USB_OC3_R_N: R621.1 U29.AD40
USB_OC4_R_N: R493.1 U29.AF39
USB_OC5_R_N: R483.1 U29.AC41
USB_OC6_R_N: RN36.1(A) U29.AF40
USB_OC7_R_N: RN36.2(A) U29.AG40
USB_OC_01*: R521.2 UC117.1 UR99.2 UR106.1
USB_OC_23*: R496.2 UC97.1 UC107.1 UR98.2
USB_OC_45*: C390.1 R418.1 R428.1 R523.2
USB_OC_89*: R493.2 UC133.1 UR118.2 UR119.1
USB_OC_1011*: R483.2 UC118.1 UR100.1 UR107.1
USB_PCH_DN0: TR20.2 U29.AV10
USB_PCH_DN1: TR19.2 U29.AV11
USB_PCH_DN2: TR23.3 U29.AN14
USB_PCH_DN3: TR24.3 U29.AJ16
USB_PCH_DN4: TR18.2 U29.AU15
USB_PCH_DN5: MINI1.36 U29.AU12
USB_PCH_DN8: TR9.2 U29.AW16
USB_PCH_DN9: TR10.2 U29.AN16
USB_PCH_DN10: TR22.2 TR26.1 U29.AJ18
USB_PCH_DN11: TR25.2 TR27.1 U29.AP18
USB_PCH_DP0: TR20.3 U29.AU10
USB_PCH_DP1: TR19.3 U29.AW11
USB_PCH_DP2: TR23.2 U29.AP14
USB_PCH_DP3: TR24.2 U29.AK16
USB_PCH_DP4: TR18.3 U29.AV15
USB_PCH_DP5: MINI1.38 U29.AT12
USB_PCH_DP8: TR9.3 U29.AV16
USB_PCH_DP9: TR10.3 U29.AP16
USB_PCH_DP10: TR22.3 TR26.4 U29.AK18
USB_PCH_DP11: TR25.3 TR27.4 U29.AN18
USB_PWR_CRL1: R455.1 R574.1 U29.AC36
USB_PWR_CRL1_B1: Q42.2 Q45.C R455.2 R469.2
USB_PWR_CRL2: R484.1 R485.1 U61.60
USB_PWR_CRL2_B1: Q45.B R485.2
USBRBIAS_PCH: R617.1 U29.AU20 U29.AV20
USBVCC01: F5.2 UC62.1 UC75.1 UR99.1 USB3R1.1 USB3R1.10 UTC7.1 UU43.5
USBVCC23: F6.1 UC76.1 UC78.1 UR98.1 USBCN1.1 USBCN1.5 UTC6.1 UU42.5
USBVCC45: C380.1 C388.1 F9.1 R418.2 U26.5 USBF1.1 USBF1.2
USBVCC89: F18.1 RJ45.U1 RJ45.U5 UC22.1 UC132.1 UR118.1 UTC5.1 UU12.5
USBVCC1011: F8.2 UC63.1 UC79.1 UC80.1 UR100.2 USBF2.1 USBF2.2 USBF3.1 USBF3.19 UTC9.1 UU37.5 UU38.5
V_1P5_DAC_FB: R391.2 U29.AF2
V_1P5_DAC_FB_R: C353.1 C354.1 L44.2 R391.1
V_1P05_DSW_INT_C: C524.1 R2225.2
V_1P05_DSW_INT_R: R2225.1 U29.AU40 U29.AU41
V_1P05_LAN: C75.1 C77.1 C83.1 C91.1 C93.1 C100.1 C114.1 C119.1 L23.2 R80.2 U12.3 U12.8 U12.22 U12.30
V_1P05_PCH: C352.1 C445.1 C446.1 C451.1 C463.1 C466.1 C469.1 C491.1 C506.1 C527.1 C556.1 C557.1 C565.1 C566.1 C571.1 C614.1 C615.1 R109.1 R159.1 R333.1 R411.1 R532.2 R548.2 R567.2 R772.1 R788.1 R808.1 R2216.1 U29.AA16 U29.AA19 U29.AA20 U29.AA23 U29.AA25 U29.AA26 U29.AB2 U29.AB16 U29.AB17 U29.AB19 U29.AB20 U29.AB22 U29.AB23 U29.AB25 U29.AB26 U29.AC12 U29.AD16 U29.AD17 U29.AD19 U29.AD20 U29.AD22 U29.AD23 U29.AD25 U29.AF19 U29.AF20 U29.AF22 U29.AF23 U29.AF25 U29.AP22 U29.M14 U29.P14 U29.P16 U29.P17 U29.P22 U29.P23 U29.P25 U29.P26 U29.P28 U29.T16 U29.T19 U29.T20 U29.U12 U29.V14 U29.V16 U29.V17 U29.V19 U29.V20 U29.V22 U29.V23 U29.V25 U29.W14 U29.W16 U29.W17 U29.W19 U29.W23 U29.W25 U29.W26
V_1P5_PCH: C518.1 C536.1 C540.1 C541.1 C568.1 L44.1 PC78.1 R99.1 R104.1 R222.1 R547.1 R576.2 R694.2 R695.1 R697.1 R791.1 U29.A4 U29.A19 U29.A33 U29.A38 U29.A39 U29.A40 U29.B4 U29.B13 U29.B37 U29.B39 U29.C1 U29.C2 U29.K1 U29.N10 U29.N11 U29.T14 U51.3 U51.4
V_1P05_PECI_VCOM: TP133.1 U27.N35
V_1P5_RTC_INT: C415.1 U29.AW35
V_1P5_STBY_INT: C417.1 U29.AH28
V_1P05_XCK_DCB_FB_R: C544.1 C545.1 R772.2 U29.AB1
V_1P05V: C209.2 C213.1 Q35.1 Q35.2 Q35.3 R287.2 R532.1 R548.1 R567.1 TC22.1
V_3P0_BAT_VREG: C569.1 D26.3 R481.1 R494.1 R499.1 R502.2 R515.1 U29.AP33
V_3P3_A: C429.1 C462.1 C525.1 D26.1 Q90.S R83.2 R367.1 R537.1 R550.1 R563.2 R602.2 R604.2 R605.1 R625.1 R635.2 R646.2 R656.2 R670.1 R671.1 R727.1 R760.1 RN22.1(A) RN22.2(A) TC38.1 U29.AV39 U29.AW38 U29.AW39 U36.2 U61.11
V_3P3_BG: C398.1 C1673.1 R97.1 U29.AE1 U29.AW21 U29.B6
V_3P3_EPW: C572.1 C1669.1 C1671.1 R409.1 R504.1 R507.1 R630.1 R631.1 U29.R41 U30CN1.8 U33.8 U35CN1.8 U39.8
V_3P3_LAN: C51.1 C74.1 C86.1 C90.1 C3325.1 C3326.1 C3327.1 Q6.D R19.2 R69.2 R150.1 RJ45.L2 U6.5 U9.5 U11.5 U12.11 U12.32
V_3P3_LAN_VDDSREG: C94.1 C95.1 R150.2 U12.23
V_3P3_PCIVAUX: C137.1 C142.1 C231.1 C240.1 C306.1 C308.1 C418.1 C421.1 C424.1 MINI1.2 MINI1.24 MINI1.39 MINI1.41 MINI1.52 Q39.D R351.1 R555.2 SLOT1.B10 SLOT2.B10
V_5_CODEC: C3.1 C8.1 D2.K L8.1 R777.1 U2.29
V_5P0_A: ATX1.9 C435.1 C440.1 C441.1 C529.1 Q46.S Q47.S Q89.S R459.1 R471.1 R495.1 R549.1 R551.1 R711.1 R769.1 U14.3 U31.3 U36.3
V_5P0_CONN_CRT_L: F7.1 L4.2 TP2.1
V_5P0_HDMI_CONN: C4.1 HDMI1.18 L3.1
V_5P0_HDMI_CONN_L: F17.1 L3.2
V_CPU_CORE: C270.1 C271.1 C350.1 C387.1 C391.1 C397.1 C500.1 C501.1 C502.1 C503.1 C521.1 C537.1 C542.1 C546.1 C547.1 C549.1 C550.1 C552.1 C558.1 C561.1 C564.1 C573.1 G2.1 G3.2 G9.1 G11.1 L27.2 L39.2 L40.2 R119.1 TC1.1 TC2.1 TC3.1 TC10.1 TC12.1 U27.A24 U27.A25 U27.A26 U27.A27 U27.A28 U27.A29 U27.A30 U27.B25 U27.B27 U27.B29 U27.B31 U27.B33 U27.B35 U27.C24 U27.C25 U27.C26 U27.C27 U27.C28 U27.C29 U27.C30 U27.C31 U27.C32 U27.C33 U27.C34 U27.C35 U27.D25 U27.D27 U27.D29 U27.D31 U27.D33 U27.D35 U27.E24 U27.E25 U27.E26 U27.E27 U27.E28 U27.E29 U27.E30 U27.E31 U27.E32 U27.E33 U27.E34 U27.E35 U27.F23 U27.F25 U27.F27 U27.F29 U27.F31 U27.F33 U27.F35 U27.G22 U27.G23 U27.G24 U27.G25 U27.G26 U27.G27 U27.G28 U27.G29 U27.G30 U27.G31 U27.G32 U27.G33 U27.G34 U27.G35 U27.H23 U27.H25 U27.H27 U27.H29 U27.H31 U27.H33 U27.H35 U27.J21 U27.J22 U27.J23 U27.J24 U27.J25 U27.J26 U27.J27 U27.J28 U27.J29 U27.J30 U27.J31 U27.J32 U27.J33 U27.J34 U27.J35 U27.K19 U27.K21 U27.K23 U27.K25 U27.K27 U27.K29 U27.K31 U27.K33 U27.K35 U27.L15 U27.L16 U27.L17 U27.L18 U27.L19 U27.L20 U27.L21 U27.L22 U27.L23 U27.L24 U27.L25 U27.L26 U27.L27 U27.L28 U27.L29 U27.L30 U27.L31 U27.L32 U27.L33 U27.L34 U27.M8 U27.M13 U27.M15 U27.M17 U27.M19 U27.M21 U27.M23 U27.M25 U27.M27 U27.M29 U27.M33 U27.P8
V_CPU_VCCIO2PCH: C368.1 C369.1 C370.1 R200.1 R333.2 U29.C39
V_CPU_VCCIO_RIGHT: C187.1 C229.1 R102.1 R226.1 R340.2 R353.1 R424.1 R482.1 R639.1 R640.1 R800.1 R808.2 U27.L40 XDPC1.43 XDPC1.44
V_SM: C136.1 C151.1 C152.1 C499.1 C504.1 C522.1 C548.1 C551.1 C560.1 C562.1 C563.1 C570.1 C574.1 C577.1 C578.1 C581.1 C582.1 C583.1 C584.1 C585.1 C586.1 C588.1 C589.1 C590.1 C593.1 C594.1 C595.1 C596.1 C597.1 C598.1 C599.1 C600.1 C601.1 C602.1 C603.1 C604.1 C605.1 C606.1 C608.1 C609.1 C611.1 C613.1 DIMM1.51 DIMM1.54 DIMM1.57 DIMM1.60 DIMM1.62 DIMM1.65 DIMM1.66 DIMM1.69 DIMM1.72 DIMM1.75 DIMM1.78 DIMM1.170 DIMM1.173 DIMM1.176 DIMM1.179 DIMM1.182 DIMM1.183 DIMM1.186 DIMM1.189 DIMM1.191 DIMM1.194 DIMM1.197 DIMM2.51 DIMM2.54 DIMM2.57 DIMM2.60 DIMM2.62 DIMM2.65 DIMM2.66 DIMM2.69 DIMM2.72 DIMM2.75 DIMM2.78 DIMM2.170 DIMM2.173 DIMM2.176 DIMM2.179 DIMM2.182 DIMM2.183 DIMM2.186 DIMM2.189 DIMM2.191 DIMM2.194 DIMM2.197 G4.2 Q35.5 Q35.6 Q35.7 Q35.8 R173.2 R178.2 R184.2 R185.2 R186.2 R187.2 R280.2 R281.2 R286.1 R290.2 R664.1 R704.1 R857.1 R2227.1 TC45.1 U13.1 U27.AJ9 U27.AJ12 U27.AJ13 U27.AJ15 U27.AJ17 U27.AJ20 U27.AJ21 U27.AJ24 U27.AJ25 U27.AJ28 U27.AJ29 U27.AT17 U27.AT22 U27.AU15 U27.AU20 U27.AU24 U27.AV8 U27.AV10 U27.AV11 U27.AV13 U27.AV18 U27.AV23 U27.AW16 U27.AY9 U27.AY12 U27.AY14
V_SM_1: C127.1 R282.1 R284.1 U13.4
V_SM_1P5_EN: R312.1 R624.1 R627.2
V_SM_VTT: C579.1 C587.1 C610.1 C612.1 DIMM1.120 DIMM1.240 DIMM2.120 DIMM2.240 R282.2 R284.2
V_VCCIOA_LOAD: R307.1 R805.1 U27.P4
VBOOT: R221.1 R2233.1 U8.2 U52.10
VGA_BLUE: C36.1 L13.1 R32.2 R425.1 U29.AC3
VGA_BLUE_C_L: C23.1 L5.1 L13.2
VGA_DACREFSET: R393.1 U29.AF5
VGA_DDC_PU: D8.K R15.1 R16.1
VGA_DET: R596.1 RN3.1(A) U29.AV28 VGA1.4
VGA_GREEN: C35.1 L12.1 R31.2 R426.1 U29.AE2
VGA_GREEN_C_L: C25.1 L7.1 L12.2
VGA_HSYNC_3V: L17.1 R850.2
VGA_HSYNC_3V_L: C18.1 L17.2 U24.3 VGA1.13
VGA_HSYNC_3V_R: R850.1 U29.AH3
VGA_PCH_DDCSCL: R66.2 U4.1 U29.AL2
VGA_PCH_DDCSDA: R65.2 U4.4 U29.AL3
VGA_RED: C34.1 L11.1 R30.2 R412.1 U29.AC2
VGA_RED_C_L: C24.1 L6.1 L11.2
VGA_VSYNC_3V: L20.1 R852.2
VGA_VSYNC_3V_L: C19.1 L20.2 U24.1 VGA1.14
VGA_VSYNC_3V_R: R852.1 U29.AH2
VR_READY: C70.1 R84.2 R759.1 R819.1 U52.7
VREG_PCIAUX_PCH_1: C678.1 Q39.G R2240.2
W1_DETECT_USB: MINI1.37 R305.1 RN2.4(A) U29.AR30
W1_DETECT_USB_R: MINI1.40 R305.2
WAKE_N: R269.2 R656.1 SLOT1.B11 SLOT2.B11 U12.21 U29.AK34
WIFI_RF_EN: MINI1.20 R388.2 R546.1 U29.AG35
XCLK_RCOMP: R547.2 U29.R11
XDP_DBRESET_N: C576.1 R264.2 U27.G40 XDPC1.48
XDP_PLTRST_N: R637.2 XDPC1.41
XDP_PWR_DEBUG: R806.1 XDPC1.45
XDP_PWRGD: R518.1 R519.2 XDPC1.39
XDP_VR_READY: R819.2 XDPC1.47
XTAL_25M_PCH_IN: C379.1 R430.1 U29.N7 X2.1
XTAL_25M_PCH_OUT: C378.1 R430.2 U29.N6 X2.2

Pads without a net: ATX1 20; AUDF1 8; CMCLR1 3; D23 2; DIMM1 39 40 42 43 45 46 48 49 53 68 79 126 135 144 153 158 159 162 164 165 167 187 198 204 213 222 231; DIMM2 39 40 42 43 45 46 48 49 53 68 79 126 135 144 153 158 159 162 164 165 167 187 198 204 213 222 231; HDMI1 13 14; LEDH1 10; LPC1 10; MECLR1 1; MINI1 3 5 8 10 12 14 16 17 19 42 44 45 46 47 49; PWCLR1 3; SLOT1 A1 A5 A6 A7 A8 B9 B12; SLOT2 A1 A5 A6 A7 A8 A19 A32 A33 A50 B9 B12 B30 B31 B48 B81 B82; U1 1; U2 2 12 18 19 20 33 37 39 41 43 44 45 46 48; U11 4; U13 5 7 8; U22 1 2 8 12; U23 1 2 8 12; U26 1 6; U27 A16 A18 AK15 AL15 AL20 AL25 AL26 AM16 AM25 AM26 AN17 AN20 AN21 AN25 AN26 AP19 AP20 AP25 AP26 AR25 AR26 AT31 AT33 AU8 AU10 AU22 AU23 AU28 AU29 AU31 AU32 AU33 AV14 AV31 AV32 AV33 AW8 AW9 AW13 AW14 AW31 AW33 AY13 B15 B16 B17 B18 C15 C17 E17 F17 F18 F20 G18 G19 G20 H19; U29 A2 A3 A14 A26 A31 AA6 AA7 AC6 AC7 AC35 AE6 AE7 AE10 AE11 AG6 AG7 AG10 AG11 AH24 AJ2 AJ4 AJ5 AJ14 AK6 AK8 AK14 AL31 AM1 AM31 AM34 AN2 AN4 AN20 AP1 AP2 AP20 AP31 AT2 AT17 AU5 AU17 AV8 AV14 AV18 AV30 AW14 AW18 B1 B2 B11 B12 B14 B26 B27 B31 B32 B35 C11 C15 C27 C32 D2 D11 D15 D35 E1 F7 F14 F28 F33 G3 G5 G14 G28 G33 H1 H2 H7 J2 J3 K5 K6 K8 K14 K16 K18 K20 K22 K28 K33 K34 L5 L14 L16 L18 L20 L22 L28 N12 P5 R4 R12 R40 U10 U11 W10 W11 Y2 Y4; U34 5 6; U52 20; U61 62; USBF1 3 5 9; USBF2 9; USBF3 2 3 5 6 20; VGA1 11; X3 2 3; XDPC1 55

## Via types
v1: diameter 0.559, hole 0.305, TOP to BOTTOM, 2691 vias
v2: diameter 0.711, hole 0.356, TOP to BOTTOM, 916 vias
v3: diameter 0.508, hole 0.254, TOP to BOTTOM, 376 vias
v4: diameter 0.66, hole 0.33, TOP to BOTTOM, 11 vias
v5: diameter 0.762, hole 0.381, TOP to BOTTOM, 12 vias
v6: diameter 0.711, hole 0.406, TOP to BOTTOM, 708 vias

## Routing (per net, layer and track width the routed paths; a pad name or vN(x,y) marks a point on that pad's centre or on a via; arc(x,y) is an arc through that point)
5V_DUAL: length 111.4
  TOP w0.508: v1(123.9,29.51) 123.9,19.53 v1(123.95,19.48) ; v1(88.93,33.48) 88.93,34.03 87.5,35.46 87.5,41.15 87.71,41.36 v1(87.71,43.81) ; PR83.2 133.41,49.27 133.41,42.17 130.2,38.96 L45.2 ; R739.2 v1(111.23,18.8)
  TOP w0.635: L45.2 131.5,35.51 ; L45.2 130.2,34.21 ; L45.2 128.9,35.51
  BOTTOM w0.508: v1(88.93,33.48) 96.22,33.48 96.7,32.99 120.42,32.99 v1(123.9,29.51) 128.32,29.51 ; v1(111.23,18.8) 112.94,18.8 113.5,19.35 121.28,19.35 ; 121.28,19.35 v2(121.28,19.38) ; 121.28,19.35 123.83,19.35 v1(123.95,19.48) ; v1(87.71,43.81) 88.09,44.2 90.81,44.2 v2(94.49,47.88)
  BOTTOM w0.635: L45.2 131.5,35.51 ; L45.2 128.9,35.51 ; L45.2 130.2,36.81 ; L45.2 130.2,34.21
  vias: v2(132.49,29.59) v2(133.81,30.71) v2(134.98,32) v6(129.9,32.13) v6(130.4,33.12) v6(131.39,33.96) v6(134.87,38.38) v6(134.87,36.6) v6(134.87,33.1) v6(135,34.82) v6(136.22,38.4) v6(136.22,36.5) v6(136.22,34.85) v6(136.22,33.12)
5VDDCCL: length 13.9
  TOP w0.102: VGA1.15 86.36,240.22 86.36,236.47 85.55,235.66 U24.6 86.42,233.11 86.8,232.73 C20.1 87.27,232.58 v2(88.41,232.58) 88.66,232.58 R13.2
5VDDCCL_R: length 12.3
  TOP w0.102: R13.1 v1(89.53,229.74) ; U4.6 84.91,225.76 84.39,225.23 R15.2 83.69,224.41 v1(83.57,224.54)
  BOTTOM w0.102: v1(89.53,229.74) 89.03,229.24 87.63,229.24 85.34,226.95 85.34,226.31 v2(84.33,225.3) v1(83.57,224.54)
5VDDCDA: length 22.6
  TOP w0.102: R14.2 C21.1 85.55,228.74 v2(85.55,229.74) U24.4 84.9,231.2 84.58,231.52 84.58,235.71 85.97,237.1 85.97,239.28 84.07,241.17 84.07,241.5 83.15,242.42 79.1,242.42 VGA1.12
5VDDCDA_R: length 4.4
  TOP w0.102: R16.2 88.58,229.43 v2(88.27,229.74) 87.88,229.74 87.44,229.3 R14.1 86.79,228.08 U4.3
5VDUAL_NCH: length 3.7
  TOP w0.165: Q49.6 178.03,35.23 178.33,34.92 v2(178.97,34.92) R2238.1 R468.2
5VDUAL_PCH: length 4.2
  TOP w0.165: v2(174.29,38.46) 174.69,38.06 R471.2 R131.1 175.4,36.3 Q49.3
5VDUAL_PCH_R: length 8.4
  TOP w0.165: R131.2 C96.1 173.3,35.33 173.08,35.56 Q46.G 172.36,35.28 173.38,34.26 173.38,32.94 Q47.G 172.36,31.09 172.29,31.01 v2(172.29,30.53)
5VDUAL_USB_F: length 178.8
  TOP w0.381: v1(76.71,14.48) 76.71,13.21 67.48,3.98 49.46,3.98 39.33,14.11 32.42,14.11 32.1,13.79 29.01,13.79 v1(28.52,14.27)
  TOP w0.508: R734.1 R644.1 17.2,12.93 v1(17.58,13.31)
  BOTTOM w0.381: v1(17.58,13.31) 17.95,12.94 21.08,12.94 21.34,13.2 23.71,13.2 23.89,13.02 27.13,13.02 28.39,14.27 v1(28.52,14.27) ; v1(153.01,55.35) 153.01,54.58 148.56,50.14 148.56,40.03 147.32,38.79 147.32,34.22 135.63,22.53 133.58,22.53 125.39,14.34 120.36,14.34 v2(120.29,14.4) 119.61,15.09 116.1,15.09 115.71,14.69 110.91,14.69 108.98,12.76 104.86,12.76 103.49,14.14 102.6,14.14 102.32,13.86 100.9,13.86 100.27,13.22 98.65,13.22 98.19,13.68 96.4,13.68 95.24,14.83 87.38,14.83 87.08,14.53 82.4,14.53 82.32,14.45 82.27,14.4 76.78,14.4 v1(76.71,14.48)
5VDUAL_USB_R:
  vias: v1(151.76,206.25) v1(187.73,201.22) v5(148.34,211.07) v6(149.22,208.79) v6(150.11,207.9) v6(150.97,207.07) v6(151.82,208.36) v6(152.58,207.49) v6(186.49,202.18) v6(186.51,200.91) v6(187.62,202.44) v6(187.96,203.71) v6(188.72,202.82) v6(188.72,201.73) v6(190.32,228.78) v6(191.49,228.78)
+5V_VGA: length 25.8
  TOP w0.508: v1(88.01,231.65) 87.95,231.71 C65.1 86.93,231.71 86.49,232.16 U24.5 ; v1(74.99,231.32) C12.1 U1.5
  BOTTOM w0.508: v6(90.81,232.56) 88.93,232.56 v1(88.01,231.65) 87.68,231.32 v2(78.28,231.32) v1(74.99,231.32)
  BOTTOM w0.635: VGA1.9 81.63,240.6 ; VGA1.9 80.55,239.52 ; VGA1.9 82.71,239.52 ; VGA1.9 81.63,238.44
  vias: v2(87.81,239.6) v2(91.47,233.54) v6(91.95,232.56)
+12V: length 335.1
  TOP w0.305: 113.89,23.41 114.48,22.83 G5.2 114.48,21.92 115.04,21.36 115.04,20.26
  TOP w0.508: C382.1 100.11,47.31 98.96,46.15 v1(98.96,38.91) 98.96,34.16 101.4,31.72 105.61,31.72 106.55,30.78 106.55,29.74 108.43,27.86 109.44,27.86 113.89,23.41 ; v1(186.26,35.86) 185.27,35.86 183.31,33.91 R468.1 ; v1(180.75,74.83) 180.75,77.01 183.97,80.23 183.97,99.39 v1(183.49,99.87) ; v1(180.01,54.2) 180.04,54.2 180.78,53.45 R688.1 ; v1(141.73,48.9) 141.1,48.26 141.1,45.34 140.53,44.77 R773.1 ; R2246.1 68.83,37.97 v1(69.29,37.97) ; v1(183.49,104.88) 183.49,110.06 184.44,111.01 R352.1 186.91,111.01 D37.K 187.43,111.2 C304.1 193.94,111.2 FNCPU1.2 ; v1(117.14,3.61) 117.3,3.76 117.3,12.24 115.04,14.5 115.04,20.26 ; C408.1 v1(183.64,21.06) ; v1(146.2,56.52) 147.88,56.52 150.97,53.43 v1(156.19,53.43)
  TOP w0.635: SLOT2.B3 17.05,196.55 ; SLOT2.B3 16.15,195.65 ; SLOT2.B3 16.15,197.45 ; SLOT2.B3 15.25,196.55 ; 26.25,201.45 TC11.1 ; TC11.1 28.36,201.45 ; TC11.1 27.3,200.39 ; TC11.1 27.3,202.5 ; SLOT1.B2 35.35,197.55 ; SLOT1.B2 33.55,197.55 ; SLOT1.B2 34.45,196.65 ; SLOT1.B2 34.45,198.45 ; SLOT2.B2 15.05,197.55 ; SLOT2.B2 14.15,196.65 ; SLOT2.B2 13.25,197.55 ; SLOT2.B2 14.15,198.45 ; 40.05,197.55 SLOT1.A2 ; SLOT1.A2 40.95,196.65 ; SLOT1.A2 41.85,197.55 ; SLOT1.A2 40.95,198.45 ; SLOT2.A3 19.55,196.55 ; SLOT2.A3 17.75,196.55 ; SLOT2.A3 18.65,197.45 ; SLOT1.B1 37.35,198.55 ; SLOT1.B1 36.45,197.65 ; SLOT1.B1 36.45,199.45 ; SLOT1.B1 35.55,198.55 ; SLOT2.A2 21.55,197.55 ; SLOT2.A2 20.65,196.65 ; SLOT2.A2 19.75,197.55 ; SLOT2.A2 20.65,198.45 ; SLOT2.B1 17.05,198.55 ; SLOT2.B1 15.25,198.55 ; SLOT2.B1 16.15,199.45 ; SLOT2.B1 16.15,197.65 ; 38.95,195.65 SLOT1.A3 ; SLOT1.A3 38.05,196.55 ; SLOT1.A3 38.95,197.45 ; SLOT1.A3 39.85,196.55 ; SLOT1.B3 36.45,197.45 ; SLOT1.B3 36.45,195.65 ; SLOT1.B3 37.35,196.55 ; SLOT1.B3 35.55,196.55
  TOP w1.016: v6(168.07,50.98) 167,52.04 165.77,52.04 164.39,53.43 v1(156.19,53.43)
  BOTTOM w0.508: v1(186.26,35.86) 186.26,30.58 186.97,29.87 192.46,29.87 ATX1.10 ; v6(168.07,50.98) 168.07,51.89 170.46,54.28 174.83,54.28 175.59,53.52 v2(178.51,53.52) 179.33,53.52 v1(180.01,54.2) ; v1(180.75,74.83) 179.6,74.83 177.01,72.24 175.41,72.24 v2(170.51,67.34) 169.43,66.25 168.77,66.25 167.42,64.91 167.42,63.5 157.35,53.43 v1(156.19,53.43) ; v1(98.96,38.91) 98.02,37.97 v2(81.92,37.97) v1(69.29,37.97) ; v1(141.73,48.9) v2(141.73,49.91) 141.73,52.04 v1(146.2,56.52) ; v1(183.49,104.88) v1(183.49,99.87)
  BOTTOM w1.016: v6(168.07,50.98) 168.17,50.88 168.17,50.7 168.91,49.96 168.91,38.76 164.96,34.81 164.96,31.33 161.39,27.76 v2(161.39,22.99) 161.39,11.61 v2(163.09,9.91) v1(163.09,5.99)
  vias: v1(21.08,200.41) v1(21.84,202.69) v1(24.38,199.01) v1(25.1,202.21) v1(28.7,199.77) v1(29.08,203.07)
-12V: length 3.2
  TOP w0.508: ATX1.14 188.43,61.96 185.27,61.96 C407.1
AGND: length 188.2
  TOP w0.305: v1(24.04,228.23) U2.26 ; U2.42 v1(21.51,233.17)
  TOP w0.508: R90.2 v1(15.88,212.7) ; v1(11.05,205.36) C102.2 ; C60.2 45.5,217.34 44.73,218.11 v1(43.55,218.11) ; v1(29.08,237.52) 28.32,237.52 C8.2 28.43,238.38 v1(29.08,238.38) ; v1(27.71,222.69) 27.77,222.63 R7.2 ; v1(21.46,239.27) 21.26,239.06 R12.2 ; v1(29.11,239.5) 29.03,239.42 R777.2 ; v1(43.55,218.11) 43.55,218.44 Q11.3 ; v1(43.55,218.11) R92.2 ; C6.2 9.14,210.25 9.08,210.31 v1(8.33,210.31) 7.19,210.31 6.68,210.82 Q9.3 ; Q10.3 7.23,207.26 v1(8.31,208.34) C92.2 ; C80.1 v1(43.59,233.58) ; v1(41.88,222.35) 42.06,222.17 R77.2 ; v1(30.2,229.29) C3.2 ; Q14.3 v1(45.14,226.46) C28.2 ; R43.2 v1(39.5,226.69) ; v1(13.46,212.7) 13.46,212.15 R130.2 ; R44.2 v1(40.51,226.69) ; C73.1 v1(43.61,235.51) ; R29.2 v1(11.99,223.11) ; v1(5.46,202.69) R171.2 ; v1(22.99,239.29) C17.2 ; C38.2 v1(43.59,231.67) ; v1(23.93,239.29) C13.2 ; C55.2 v1(47.78,222.67) ; v1(43.22,237.01) Q17.3 ; C82.2 v1(10.1,213.18) ; C5.2 v1(6.92,216.15) ; v1(30.25,222.69) 30.31,222.63 R6.2
  TOP w0.635: 48.15,230.91 AUDJK1.G4 49.86,229.2 ; 55.62,236.7 AUDJK1.4 ; AUDJK1.4 56.69,235.63 ; AUDJK1.4 56.69,237.77 ; AUDJK1.4 57.76,236.7 ; 48.15,238.78 AUDJK1.G2 ; AUDJK1.G2 48.15,242.21 ; AUDJK1.G2 46.43,240.5 ; AUDJK1.G2 49.86,240.5 ; 54.37,231.7 AUDJK1.24 ; AUDJK1.24 56.51,231.7 ; AUDJK1.24 55.44,230.63 ; 53.12,236.7 AUDJK1.1 ; AUDJK1.1 54.19,237.77 ; AUDJK1.1 54.19,235.63 ; AUDJK1.1 55.26,236.7 ; 58.51,240.5 AUDJK1.G1 ; AUDJK1.G1 60.23,238.78 ; AUDJK1.G1 60.23,242.21 ; AUDJK1.G1 61.95,240.5 ; 60.23,227.48 AUDJK1.G3 ; AUDJK1.G3 61.95,229.2 ; AUDJK1.G3 58.51,229.2 ; AUDJK1.G3 60.23,230.91
  L3 w0.635: 58.51,240.5 AUDJK1.G1 ; AUDJK1.G1 60.23,242.21 ; AUDJK1.G1 61.95,240.5 ; AUDJK1.G1 60.23,238.78 ; AUDJK1.1 55.26,236.7 ; AUDJK1.1 53.12,236.7 ; AUDJK1.1 54.19,235.63 ; AUDJK1.1 54.19,237.77 ; H1.1 35.54,237.82 ; H1.1 36.32,237.03 ; H1.1 34.75,237.03 ; 56.69,235.63 AUDJK1.4 ; AUDJK1.4 57.76,236.7 ; AUDJK1.4 56.69,237.77 ; AUDJK1.4 55.62,236.7 ; 48.15,227.48 AUDJK1.G4 ; AUDJK1.G4 49.86,229.2 ; AUDJK1.G4 46.43,229.2 ; AUDJK1.G4 48.15,230.91 ; 54.37,231.7 AUDJK1.24 ; AUDJK1.24 55.44,230.63 ; AUDJK1.24 56.51,231.7 ; AUDJK1.24 55.44,232.77 ; H1.8 38.76,236.54 ; H1.8 37.98,237.33 ; H1.8 37.19,236.54 ; 33.58,231.14 H1.4 ; H1.4 35.15,231.14 ; H1.4 34.36,230.35 ; 32.98,232.42 H1.3 ; H1.3 32.98,233.99 ; H1.3 32.19,233.21 ; 6.77,227.57 AUDF1.2 5.7,228.64 ; AUDF1.7 4.23,222.09 ; AUDF1.7 4.23,219.95 ; AUDF1.7 5.3,221.02 ; 58.51,229.2 AUDJK1.G3 ; AUDJK1.G3 61.95,229.2 ; AUDJK1.G3 60.23,227.48 ; AUDJK1.G3 60.23,230.91 ; 55.44,225.63 AUDJK1.34 ; AUDJK1.34 56.51,226.7 ; AUDJK1.34 55.44,227.77 ; AUDJK1.34 54.37,226.7 ; 48.15,238.78 AUDJK1.G2 ; AUDJK1.G2 46.43,240.5 ; AUDJK1.G2 48.15,242.21 ; AUDJK1.G2 49.86,240.5 ; 36.8,229.86 H1.5 ; H1.5 37.59,230.65 ; H1.5 36.02,230.65 ; H1.2 33.47,236.43 ; H1.2 33.47,234.86 ; H1.2 32.68,235.65 ; 39.36,233.69 H1.7 ; H1.7 39.36,235.26 ; H1.7 40.15,234.47 ; 38.87,231.25 H1.6 ; H1.6 39.66,232.03 ; H1.6 38.87,232.82
  BOTTOM w0.508: R110.2 v1(12.95,210.44)
  BOTTOM w0.635: 48.15,238.78 AUDJK1.G2 ; AUDJK1.G2 49.86,240.5 ; AUDJK1.G2 48.15,242.21 ; AUDJK1.G2 46.43,240.5 ; AUDJK1.G1 60.23,242.21 ; AUDJK1.G1 58.51,240.5 ; AUDJK1.G1 61.95,240.5 ; AUDJK1.G1 60.23,238.78 ; AUDJK1.34 55.44,227.77 ; AUDJK1.34 56.51,226.7 ; AUDJK1.34 54.37,226.7 ; AUDJK1.34 55.44,225.63 ; 55.62,236.7 AUDJK1.4 ; AUDJK1.4 56.69,237.77 ; AUDJK1.4 56.69,235.63 ; AUDJK1.4 57.76,236.7 ; 53.12,236.7 AUDJK1.1 ; AUDJK1.1 54.19,237.77 ; AUDJK1.1 55.26,236.7 ; AUDJK1.1 54.19,235.63 ; 55.44,230.63 AUDJK1.24 ; AUDJK1.24 55.44,232.77 ; AUDJK1.24 56.51,231.7 ; AUDJK1.24 54.37,231.7 ; 48.15,230.91 AUDJK1.G4 46.43,229.2 ; AUDJK1.G3 60.23,230.91 ; AUDJK1.G3 60.23,227.48 ; AUDJK1.G3 58.51,229.2 ; AUDJK1.G3 61.95,229.2
  vias: v1(32.08,227.56) v1(32.08,226.57) v1(32.08,225.63) v1(61.7,237.08) v2(21.72,240.41) v2(41.02,224.41) v2(46.54,234.85) v2(47.62,224.92) v2(56.39,239.91) v2(62.36,234.82)
GND: length 2883.2
  TOP w0.203: U29.R1 37.28,58.34 37.53,58.59 v3(37.53,58.61) ; U29.B30 44.57,41.82 45.04,41.35 v3(45.04,41.35) ; v3(24.23,49.05) 24.31,49.13 U29.AV17 ; v3(43.66,55.98) 43.79,55.98 43.79,56.03 44.26,56.51 U29.B3 ; v3(36.14,59.54) 36.11,59.5 36.11,57.87 36.12,57.86 36.12,57.85 U29.U1 ; v3(39.98,35.43) 39.98,35.59 39.88,35.69 U29.L41 ; v1(100.69,19.94) 100.87,19.75 U61.54 ; U27.AN14 110.2,137.16 v1(109.26,137.16)
  TOP w0.216: U29.A21 46.11,47.04 46.34,47.26 v3(46.53,47.26)
  TOP w0.229: v1(121.83,129.59) 121.63,129.8 U27.AY26 ; v3(47.65,45.5) 47.65,45.2 47.24,44.79 45.32,44.79 45.26,44.85 44.65,44.85 U29.B25
  TOP w0.254: U29.AK24 29.26,45.39 29.08,45.22 29.08,45.19 v3(28.89,44.99) 28.55,45.33 U29.AM24 ; U27.AP14 110.73,136.77 111.49,136.77 U27.AP15 ; U27.G15 v1(108.91,161.84) ; v3(23.9,51.87) 24.06,51.71 24.9,51.71 U29.AV12 ; U29.AE41 32.24,34.85 v3(32.09,34.7) ; U29.AV2 25.74,56.55 U29.AU3 ; v1(101.9,168.51) 102.06,168.36 U27.A7 ; U27.U35 v1(130.32,152.7) ; U29.AG38 30.84,38.21 30.36,38.69 29.72,38.69 U29.AK37 ; U27.R38 v1(133.06,153.61) ; QF2.1 51.94,19.19 v1(51.27,18.52) 50.86,18.92 R398.2 ; v1(46.74,30.4) 46.86,30.28 R650.2 ; v1(11.88,12.98) 12.16,12.98 12.29,12.85 12.36,12.85 C479.2 ; v3(28.35,37.67) 28.26,37.75 U29.AM38 ; v3(31.11,50.29) 30.82,50.58 30.82,50.63 U29.AH14 ; v3(26.2,35.68) 26.22,35.7 U29.AT41 ; U29.Y41 34.72,36.17 34.72,35.46 v3(34.76,35.42) ; U27.U36 v1(131.23,152.7) ; v3(41.22,37.63) 41.04,37.81 U29.H38 41,38.25 U29.J37 40.03,38.25 U29.L37 ; v1(133.06,152.7) U27.T38 ; U29.AR37 26.77,38.55 U29.AT36 26.41,39.16 U29.AR35 ; v3(34.98,58.38) 34.98,58.29 34.75,58.07 U29.Y1 ; U29.V40 35.94,37.58 v3(36.07,37.7) 36.07,37.95 35.94,38.08 U29.V38 ; U27.U2 U27.V3 ; R445.2 18.1,40.45 18.61,39.94 R841.2 18.86,39.94 19.2,39.6 v1(19.45,39.6) 19.68,39.6 19.88,39.79 R413.2 ; v3(45.14,50.22) 45.14,49.63 U29.A16 ; R538.2 R597.1
  TOP w0.279: XDPC1.31 184.12,136.93 v1(184.02,137.03) 183.92,136.93 XDPC1.32 ; XDPC1.37 184.28,138.43 v1(184.15,138.3) ; XDPC1.1 188.91,129.43 v1(188.92,129.42) ; XDPC1.38 178.57,138.43 v1(178.56,138.43) ; XDPC1.20 184.24,133.93 v1(184.37,133.81) 184.49,133.93 XDPC1.19 ; XDPC1.26 182.93,135.43 183.69,136.2 v1(184.24,136.2) 185,135.43 XDPC1.25 ; XDPC1.8 183.41,130.93 v1(183.92,131.44) ; XDPC1.49 188.42,141.43 v1(189.14,142.15) ; U29.AL37 29.28,38.25 U29.AK37 ; XDPC1.14 182.93,132.43 v1(183.92,131.44) ; XDPC1.13 185.49,132.43 184.51,131.44 v1(183.92,131.44)
  TOP w0.305: U29.AG8 30.6,54.1 v3(30.47,54.1) ; Q42.4 174.84,58.52 174.56,58.8 v1(174.5,58.8) ; U29.AM18 28.87,48.88 28.87,49.15 v3(28.87,49.16) ; XDPC1.7 188.76,130.93 188.85,130.84 v1(188.92,130.84) ; U27.G17 v1(111.66,161.84) U27.H18 ; U29.AE12 31.8,51.31 U29.AF14 ; v3(39.14,46.1) 39.14,46.26 U29.M22 U29.M20 ; U18.9 87.14,198.3 U18.6 ; U29.D41 43.12,35.86 v3(43.4,35.57) ; U29.B25 43.79,44.93 U29.C25 ; U29.AC38 33.41,37.82 v3(33.56,37.67) ; v3(45.46,38.85) 45.46,39.01 U29.A35 ; v3(38,53.31) 37.64,53.31 U29.R10 ; v3(23.29,54.81) 23.44,54.67 U29.AW7 ; v1(42.67,58.55) 43.13,58.09 U29.D1 ; U29.M16 39.22,49.31 v3(39.22,49.1) 39.22,48.94 U29.M18 ; U29.AK9 30.29,53.44 v3(30.32,53.47) ; U29.AL11 28.92,51.42 v3(28.93,51.41) 28.55,51.03 U29.AM14 ; Q40.4 187.46,120.96 R401.2 ; U29.AM26 28.89,44.77 v3(28.89,44.99) ; v3(27.68,42.6) 27.68,43.07 U29.AN28 ; v3(38.35,44.98) 38.84,45.47 U29.M24 ; U29.AM38 28.9,38.21 U29.AL37 ; U27.N4 98.87,156.38 v1(98.87,156.38) ; C128.1 176.02,166.4 174.96,167.46 v1(174.96,167.77) ; U27.AY23 118.89,130.71 v1(118.72,130.54) ; U29.H22 40.63,46.22 v3(40.63,46.03) ; U29.AF17 31.21,49.05 v3(31.17,49.08) 31.17,49.28 30.83,49.63 U29.AH16 ; U29.H16 40.63,49.97 v3(40.63,50.3) 40.97,50.64 U29.H14 ; U29.AT16 26.48,49.97 U29.AT15 26.47,50.24 v3(25.89,50.82) 25.99,50.91 U29.AT14 ; U29.T22 36.85,46.63 v3(36.45,46.22) 36.85,45.82 ; U29.V28 36.05,43.4 v3(36.45,43.8) ; U29.T28 36.85,43.4 v3(36.45,43.8) ; v3(25.7,38.19) 25.7,38.21 U29.AT36 ; v3(25.7,38.19) 26.4,38.19 U29.AT38 ; v3(25.7,38.19) 25.7,37.5 ; U29.AJ28 29.93,43.23 29.59,43.56 v1(29.59,43.81) ; HDMI1.8 v1(109.83,235.52) ; Q67.1 70.58,71.05 v1(70.24,71.4) ; U29.T17 36.86,49.05 v3(36.45,48.64) ; U29.AG2 30.96,56.85 v3(30.96,56.4) 31.05,56.3 U29.AG4 ; U29.M26 38.9,44.33 v3(38.35,43.77) 38.89,43.23 U29.M28 ; U29.AG34 30.61,40.66 v3(30.26,40.66) ; U29.AT18 26.33,48.49 v3(25.91,48.49) 25.91,48.27 U29.AT20 26.47,47.43 U29.AT21 26.12,47.08 25.42,47.08 25.42,47.08 U29.AV21 ; v1(95.67,163.52) 95.98,163.22 U27.F1 ; U29.AF14 U29.AD14 ; U29.AF14 31.48,50.66 v3(31.11,50.29) 31.34,50.06 31.4,50.06 31.61,49.85 U29.AF16 ; 35.89,41.43 35.98,41.43 U29.U31 ; 35.89,41.43 v3(35.82,41.43) ; 35.89,41.43 U29.U32 ; U29.AM4 28.34,55.99 v3(28.34,56.4) 28.64,56.4 29.13,55.91 U29.AL5 ; U29.T26 36.85,44.21 v3(36.45,43.8) ; v1(186.69,144.61) 186.74,144.61 187,144.35 XDPC1.59 ; v3(38.56,37.66) 38.47,37.76 U29.N38 ; v1(114.05,235.59) 114.33,235.3 HDMI1.17 ; U29.AD26 32.67,44.21 v3(33.07,43.8) 32.66,43.4 U29.AD28 ; 34.36,46.63 v3(34.76,47.03) ; U27.AC39 133.52,146.76 v1(133.96,147.2) 134.4,146.76 U27.AC40 ; R552.2 15.07,49.95 v1(15.85,49.17) ; U29.AT23 25.99,45.85 v3(25.89,45.76) 26.47,45.18 U29.AT24 ; v3(36.02,56.4) U29.W5 ; v3(36.02,56.4) 35.9,56.51 U29.W3 ; v3(36.02,56.4) 36.11,56.3 U29.U4 ; v3(46.04,52.25) 45.94,52.14 U29.A12 ; U29.F38 U29.F37 ; U29.AB14 33.89,50.26 v3(33.91,50.26) 33.93,50.26 U29.AA14 35.22,51.55 U29.W12 ; v3(36.45,43.8) 36.05,44.21 U29.V26 35.22,43.4 U29.W28 ; XDPC1.50 v1(179.15,141.43) ; U2.7 18.44,230.23 v1(18.64,230.43) ; U29.AT28 25.97,43.32 v3(25.93,43.28) 25.93,43.19 26.47,42.65 U29.AT29 ; U29.AE8 32.36,53.74 v3(32.69,54.08) 33.02,53.74 U29.AC8 ; U27.AR40 134.92,135.78 v1(135.13,135.57) ; U53.1 106.07,39.65 105.84,39.42 105.08,39.42 104.77,39.11 U53.4 v1(103.63,38.4) ; R662.2 24.89,10.54 23.91,9.56 13.71,9.56 13.17,10.11 13.17,10.13 C496.2 ; U29.H20 40.97,47.64 v3(40.61,48) ; 103.07,161.49 U27.G9 ; 103.07,161.49 U27.H8 ; 103.07,161.49 103.78,161.49 U27.H9 ; HDMI1.11 v1(111.33,235.52) ; v3(34.76,48.64) U29.AA17 ; U29.AA34 34.09,40.32 33.83,40.06 v3(33.83,40.01) 33.52,40.32 U29.AC34 ; U27.G6 v1(101.6,161.84) ; v1(135.15,156.52) 134.86,156.82 U27.M40 ; U27.AJ32 v1(127.57,141.73) ; U27.A17 111.2,168.3 v1(110.77,168.73) ; HDMI1.5 v1(108.33,235.52) ; U29.AT7 26.48,54.33 U29.AT8 26.67,54.13 v3(27,53.8) 27.12,53.68 U29.AP9 26.83,53.22 26.48,52.87 U29.AT10 26.13,52.42 U29.AT11 26.75,52.15 U29.AR11 ; U27.B10 104.8,167.16 104.62,167.33 104.62,168.64 v1(104.37,168.89) ; U16.6 187.38,178.79 U16.9 ; U29.AF28 31.63,43.4 v3(31.19,42.97) ; U27.L11 v1(105.26,159.1) ; v1(104.34,135.33) 104.34,135.33 U27.AT10 ; XDPC1.2 181.27,128.79 v1(181.33,128.73) ; U27.R5 v1(100.68,155.44) U27.P5 ; U29.AM35 28.5,39.48 28.05,39.48 v3(27.98,39.4) ; 25.7,37.5 U29.AU39 ; 25.7,37.5 25.09,36.88 U29.AV40 ; U29.AJ1 29.64,57.99 v3(29.21,58.42) ; U29.AT1 26.4,58.44 v3(26.68,58.71) ; v1(103.55,152.56) 103.27,152.56 102.97,152.25 U27.V8 ; U29.AT33 26.07,40.79 25.91,40.64 v3(25.9,40.64) 25.88,40.64 25.79,40.73 U29.AV33 ; U27.J11 v1(106.17,160.93) ; v3(36.45,45.42) 36.85,45.01 U29.T25 ; R597.1 v1(46.74,30.4) ; U29.B40 43.84,36.27 U29.C41 U29.B41 45.02,35.81 45.11,35.81 v1(45.12,35.8) ; v3(29.1,54.09) 28.88,53.86 U29.AM8 ; U29.AM20 28.93,47.87 v3(28.93,47.99) ; v3(26.67,56.64) 26.67,56.64 27.15,56.16 U29.AP4 ; U27.AJ22 v1(118.43,141.73) ; v1(97.94,160.93) U27.J3 ; HDMI1.2 v1(106.83,235.52) ; U29.AW30 23.55,41.92 23.45,41.82 22.81,41.82 22.39,42.24 v1(21.54,42.24) ; v3(35.82,53.47) 35.84,53.47 36.11,53.74 U29.U8 ; U27.U34 v1(129.4,151.79) U27.V34 ; U29.N8 38.56,53.74 38.35,53.95 v3(37.97,53.95) 37.56,53.95 U29.R8 ; U27.AM19 v1(115.69,138.98) ; v1(102.51,149.04) U27.AA8 ; 104.85,25.96 G7.1 ; U8.6 142.72,192.88 ; U27.AL21 v1(116.6,139.9) ; U29.N4 v3(38.64,56.4) ; U29.N35 v3(39.31,39.61)
  TOP w0.356: U27.AA6 v1(100.68,149.96) U27.Y6 ; C3318.1 v1(11.51,61.29) ; U27.R3 97.98,155.4 97.98,155.4 97.94,155.45 v1(97.92,155.45) 97.92,155.47 U27.P2 ; v1(118.43,139.9) U27.AL22 v1(117.51,139.9) U27.AL21 ; U27.D34 v1(128.49,163.67) ; U27.M1 96.36,157.53 v1(95.84,157.53) ; v1(129.4,140.81) U27.AJ34 v1(129.4,141.73) ; U27.AY7 v1(102.06,131.47) ; U27.AC34 v1(129.4,147.21) U27.AC35 v1(130.32,147.21) U27.AC36 v1(131.23,147.21) ; v1(126.63,138.98) 126.66,138.95 126.7,138.95 U27.AM32 ; 121.61,134.87 121.6,134.87 v1(121.15,134.41) 121.12,134.39 121.12,134.36 U27.AU25 ; 121.61,134.87 121.2,135.28 121.19,135.28 v1(121.16,135.3) 121.13,135.28 121.12,135.28 120.71,134.87 U27.AT25 120.59,134.75 119.92,134.75 U27.AT24 119.37,134.44 v1(119.37,134.41) ; 121.61,134.87 U27.AT26 ; U27.J6 101.57,160.04 v1(101.6,160.04) ; U27.AH33 v1(127.57,142.64) ; v1(122.1,139.92) U27.AK27 v1(122.09,140.81) ; v1(121.72,163.67) U27.F28 ; U27.F34 v1(128.49,161.84) ; U27.AY27 122.54,130.6 v1(122.61,130.49) ; v1(110.17,141.73) 110.2,141.73 U27.AJ14 ; U27.AJ8 v1(103.43,141.73) ; U27.AK10 v1(105.26,140.81) ; v3(34.78,47.8) 35.14,47.43 U29.W20 ; U27.AG33 v1(127.57,143.56) ; U27.T2 U27.T1 95.79,154.07 95.55,153.83 v1(95.55,153.83) ; U27.F32 v1(126.66,161.84) ; U27.AL30 v1(124.83,139.9) U27.AK30 ; v1(127.09,131.47) 127.12,131.49 U27.AW32 ; v1(135.36,158.64) U27.K40 ; U29.T23 36.85,45.82 v3(36.45,45.42) ; v1(95.86,141.27) U27.AK1 ; U27.AD36 v1(131.23,145.39) U27.AE36 ; v1(95.82,135.62) 96.01,135.81 96.54,135.81 U27.AT1 ; v1(109.9,157.07) 109.93,157.1 109.93,157.38 U27.M16 ; U27.AK6 100.68,141.73 v1(100.68,141.76) ; v1(99.77,168.35) 100.23,167.9 U27.A5 ; v1(131.23,142.64) U27.AG36 U27.AF36 ; U27.D6 v1(100.68,164.59) U27.D5 ; U27.AG38 132.6,143.12 v1(133.06,143.56) 133.52,143.12 U27.AG39 ; U27.N3 v1(97.94,157.27) U27.N2 v1(97.03,157.27) U27.N1 ; U27.AN36 v1(131.23,138.04) 130.77,138.5 U27.AM36 ; U27.AJ31 v1(126.66,141.73) ; v1(110.2,140.81) U27.AK14 ; v1(105.61,168.67) 105.71,168.57 U27.A11 ; U27.AR27 122.54,135.79 122.28,136.05 122.28,136.43 U27.AP27 122.55,136.7 123.01,137.16 v1(123.03,137.16) 123.03,137.17 122.59,137.61 U27.AN27 122.54,137.7 122.42,137.83 122.42,138.31 122.54,138.44 U27.AM27 122.99,138.97 123.02,138.97 v1(123.03,138.98) 123,138.98 U27.AL27 122.11,139.01 122.08,139.01 v1(122.06,139) ; v1(113.86,139.9) U27.AL17 v1(112.94,139.9) ; 112.46,141.27 U27.AJ16 ; 112.46,141.27 v1(112,141.73) ; 112.46,141.27 v1(112,140.81) ; U27.D26 v1(119.89,165.5) ; U27.R40 v1(133.97,153.61) U27.T39 ; U27.AM2 v1(97.94,139.92) U27.AM3 ; v1(135.47,151.67) 135.13,151.33 U27.V40 ; v1(99.78,166.4) 99.34,165.96 U27.C4 ; U27.F19 v1(113.49,163.67) U27.E20 ; v1(131.23,147.21) U27.AC37 v1(132.14,147.21) U27.AC38 ; v1(131.23,147.21) U27.AB37 ; U27.AJ27 v1(122.09,141.73) ; U27.F24 v1(118.06,163.67) ; v1(131.23,153.61) U27.R37 ; U27.AN7 102.48,138.08 v1(102.53,138.08) ; v1(115.65,141.73) 115.23,141.31 U27.AJ19 ; U27.AV3 v1(97.97,134.41) ; v1(97.97,134.41) 97.51,134.87 U27.AU2 ; v1(97.97,134.41) 98.4,134.84 U27.AU3 ; v1(108,165.5) U27.D13 ; U27.AK12 v1(108.37,140.81) ; U27.AT30 U27.AT29 124.37,134.85 v1(123.91,134.39) ; U27.AU5 v1(99.77,134.41) ; U27.AD2 97.48,146.78 v1(97.03,147.24) ; U27.D17 v1(111.66,164.59) U27.E18 ; U27.AP36 v1(131.23,136.24) U27.AR36 ; U27.AK18 v1(114.77,140.81) U27.AK19 ; U27.C21 114.76,166.06 v1(114.76,166.93) ; U22.4 U23.4 101.73,59.62 v1(101.17,59.05) ; U27.AB5 100.66,149.02 v1(100.69,149.02) ; v1(117.09,132.41) 117.09,132.41 117.06,132.45 U27.AV21 ; U27.AJ26 v1(121.17,141.73) ; U27.AL5 100.18,140.36 99.82,139.99 99.82,139.98 99.78,139.95 99.78,139.94 v1(99.78,139.93) 99.82,139.89 99.82,139.86 100.23,139.45 U27.AM5 ; U27.AN19 115.23,137.64 114.82,138.04 114.8,138.04 v1(114.79,138.05) 114.78,138.04 114.77,138.04 U27.AN18 ; U23.18 U22.18 97.18,52.48 ; v1(95.76,151.41) 95.83,151.41 95.91,151.33 U27.W1 ; v1(118.07,160.02) 117.62,159.56 U27.K24 ; U27.AJ5 v1(99.77,141.73) U27.AK5 ; U27.AR38 132.6,135.81 v1(133.06,136.27) 133.52,135.81 U27.AR39 ; C3317.1 v1(11.51,63.37) ; v1(124.83,141.73) U27.AJ30 v1(124.83,140.81) ; U27.AT4 v1(98.86,136.24) ; U27.AW34 128.94,131.49 v1(128.97,131.09) ; v1(95.91,143.1) U27.AH1 U27.AH2 U27.AH3 U27.AH4 v1(99.77,142.64) U27.AH5 ; U27.AE8 v1(103.43,146.3) U27.AD8 ; v1(107.42,138.13) 107.46,138.17 107.55,138.17 U27.AM11 ; v1(135.09,141.27) U27.AJ40 ; U27.AD3 v1(97.94,147.24) 98.37,147.67 U27.AC3 ; U27.AR30 125.27,135.78 124.83,136.22 v1(124.83,136.25) 124.83,136.27 125.26,136.7 U27.AP30 ; U27.K4 v1(98.86,160.02) ; U27.E6 v1(101.6,163.67) U27.E7 ; U27.AF8 v1(103.43,145.39) ; U27.K30 123.1,159.56 v1(123.56,160.02) ; U27.AW36 130.77,131.37 v1(130.87,131.27) ; v1(132.14,139.94) 132.14,139.92 U27.AL37 ; v1(127.57,135.3) 128.03,135.76 U27.AR33 ; v1(95.89,159.19) 96.26,159.56 U27.K1 ; U27.G3 v1(98.86,161.84) U27.H4 ; U27.AU38 v1(133.06,134.44) 132.63,134.87 U27.AT38 ; U27.H30 v1(123.54,161.84) ; U27.L3 v1(98.86,158.19) U27.M4 ; v1(128.49,146.3) U27.AC33 ; U27.G14 v1(108.91,162.76) ; U27.AN23 118.51,137.99 118.51,138.03 v1(118.43,138.1) ; U27.AW7 v1(101.6,133.5) U27.AV7 U27.AU7 ; v1(101.6,166.42) U27.C6 ; U27.D32 v1(126.66,163.67) ; U27.AF5 v1(99.77,145.39) U27.AE5 ; v1(121.72,165.5) U27.D28 ; v1(135.09,137.61) U27.AN40 ; v1(126.62,156.46) 126.76,156.46 U27.M32 ; U27.AC40 v1(135.09,146.76) ; U27.B8 102.97,167.46 v1(103.05,167.54) ; C3316.1 v1(11.51,62.33) ; U27.M30 v1(123.54,158.19) ; U27.AJ35 v1(130.32,141.73) ; v1(135.13,149.5) 134.96,149.32 133.87,149.32 133.13,148.59 U27.AA38 ; U27.AD4 U27.AD5 v1(100.68,147.21) ; v1(96.95,59.11) 97.18,59.34 U23.11 U22.11 ; U27.G16 v1(109.83,162.76) U27.F16 ; U27.H10 v1(105.26,161.84) U27.H11 ; U27.AJ18 114.31,141.3 v1(114.75,141.73) ; U27.AP15 112.01,137.13 v1(112.01,137.13) ; U27.A13 107.54,168.49 v1(107.45,168.58) ; U27.Y4 v1(98.86,150.87) ; v1(123.54,167.33) U27.B30 ; U27.AN11 107.9,137.61 v1(107.45,137.16) 107.91,136.7 U27.AP11 ; U27.AT7 101.91,135.64 101.28,135.64 U27.AT6 ; v1(123.54,165.5) U27.D30 ; v1(125.29,130.55) U27.AY30 U27.AW30 ; U27.AR18 113.89,135.36 113.89,135.33 v1(113.88,135.32) 113.86,135.32 U27.AR17 ; U27.H24 v1(118.06,161.84) ; U27.AD6 v1(101.6,147.21) U27.AC6 ; v1(110.2,138.98) U27.AL14 v1(110.2,139.9) ; v1(98.87,139.92) 98.87,139.89 U27.AM4 ; U27.G7 v1(102.51,161.84) U27.H8 ; U27.AB7 v1(102.51,149.04) U27.AA7 ; U27.F26 v1(119.89,163.67) ; v1(133.06,153.61) U27.R39 ; U27.B32 v1(126.66,165.5) ; U29.AM16 28.83,49.91 v3(28.83,50.19) ; U27.AK29 v1(123.91,140.81) ; U27.AF33 v1(128.49,144.47) ; U27.K34 v1(128.49,158.19) ; U27.AN9 104.34,138.04 v1(104.35,138.04) ; U27.AE37 v1(132.14,145.39) ; U27.AJ11 v1(107.46,140.81) U27.AK11 ; U27.AA33 v1(128.49,148.13) U27.AB34 ; v1(104.34,165.5) U27.D9 ; U27.AT39 v1(133.97,135.33) ; U27.AV28 123.91,133.49 v1(123.93,133.49) ; U27.P39 v1(133.06,155.44) U27.P38 ; U27.AM1 95.91,139.44 v1(95.81,139.34) ; U27.AR37 v1(132.14,136.24) ; U27.AL11 107.51,139.04 v1(107.42,139.04) ; U27.T6 v1(101.6,153.61) U27.T7 ; U27.AN6 101.56,138.1 101.59,138.1 v1(101.62,138.07) ; U27.AD33 v1(127.57,145.39) U27.AE33 ; U27.AK9 v1(104.34,141.73) ; U27.V6 v1(100.68,151.79) ; U27.A15 109.37,168.49 109.29,168.56 v1(109.29,168.71) ; C3323.1 v1(11.51,59.21) ; v1(119.9,160.02) 119.44,159.56 U27.K26 ; U27.AN10 104.38,138.94 104.38,138.96 v1(104.37,138.98) ; U27.AK24 v1(120.26,140.81) U27.AK25 ; v1(97.33,149.63) 97.46,149.5 U27.AA3 ; U27.W35 v1(130.32,150.87) ; U27.AK36 131.21,139.94 131.22,139.94 v1(131.23,139.94) 131.23,139.92 130.77,139.47 U27.AL36 ; U27.AD1 96.44,146.76 v1(95.96,147.24) ; v1(111.66,161.84) U27.H17 ; U27.P40 v1(133.97,155.44) U27.N39 ; U27.AL24 v1(119.34,138.98) U27.AM24 ; U27.G11 v1(106.17,162.76) U27.F12 ; U27.K32 v1(126.66,158.19) ; v3(34.76,47.03) 35.16,46.63 U29.W22 v3(34.79,46.24) 34.4,46.63 U29.AA22 ; U27.AK28 v1(123,140.81) ; v1(121.72,167.33) U27.B28 ; U27.W37 v1(132.14,150.87) ; U27.AT14 v1(111.09,134.41) U27.AT15 ; U27.AV34 128.97,133.04 v1(129.43,133.5) 128.97,133.96 U27.AU34 ; U27.B26 v1(119.89,167.33) ; v1(102.51,141.73) U27.AK8 ; U27.AP4 99.36,137.61 99.79,138.04 v1(99.79,138.06) 99.8,138.06 100.05,138.3 100.05,138.35 U27.AN5 ; U27.AM15 v1(111.11,138.98) U27.AM14 ; U27.AH8 v1(102.51,143.56) ; v1(112.85,166.62) 113.03,166.45 U27.C19 ; U27.AH36 v1(131.23,141.73) U27.AJ36 ; v1(105.26,159.1) U27.K10 ; U27.U37 v1(132.14,152.7) ; v1(124.81,137.17) 124.81,137.17 125.26,137.61 U27.AN30 ; v1(123.54,163.67) U27.F30 ; U27.M20 v1(114.4,158.19) ; U27.AR19 v1(115.71,135.33) U27.AR20 ; v1(100.68,153.61) U27.T5 ; v1(104.34,164.59) U27.E10 ; U27.V3 v1(97.94,151.79) ; U27.AK13 v1(109.28,140.81) ; U27.AT9 v1(103.43,135.33) U27.AT8 ; U27.AG8 v1(102.51,144.47) ; v1(118.43,141.73) U27.AJ23 ; U27.AF4 v1(98.86,145.36) ; v1(101.6,141.74) 101.6,141.73 U27.AK7 ; v1(106.17,165.5) U27.D11 ; v1(110.74,166.42) U27.C16 ; U27.AJ33 v1(128.49,141.73) ; U27.E8 v1(102.51,164.59) U27.D7 ; v1(102.51,147.21) U27.AC7 ; U27.Y5 v1(99.77,150.87) U27.W4 ; U27.AY17 v1(113.4,130.57) ; U27.AR31 126.63,135.36 126.63,135.35 v1(126.64,135.34) 126.68,135.34 U27.AR32 ; U27.B34 v1(128.49,165.5) ; U27.AP1 95.99,137.61 v1(95.91,137.54) ; U27.AG37 v1(132.14,143.56) ; v1(135.09,139.44) U27.AL40 ; U27.R6 v1(100.68,155.44) ; U27.AJ37 v1(132.15,141.74) ; v3(37.97,40.77) 37.87,40.77 37.77,40.69 37.6,40.52 37.36,40.35 U29.R34 ; U27.H28 v1(121.72,161.84) ; v1(109.83,165.5) U27.D15 ; U27.H7 v1(101.6,160.93) ; U27.F4 98.9,163.63 v1(98.88,163.63) 98.88,163.65 U27.E3 ; U27.H26 v1(119.89,161.84) ; U27.U7 v1(101.6,152.7) ; U27.F14 v1(108,162.76) U27.G13 ; v1(127.57,138.07) U27.AM33 ; U27.AY5 v1(100.23,131.47) ; U27.AT36 v1(131.23,134.41) ; U27.AM31 126.66,138.07 v1(126.66,138.04) ; U27.AR21 v1(117.49,135.33) U27.AR22 U27.AR23 U27.AR24 U27.AP24 120.26,137.16 v1(120.29,137.16) 120.28,137.17 120.25,137.17 U27.AN24 ; C3319.1 v1(11.51,58.17) ; v1(103.41,138.08) 103.08,138.41 U27.AN8 ; U27.AN16 112.03,138.07 112,138.07 v1(112,138.07) ; U27.AT5 v1(99.77,136.24) U27.AR5 ; U27.AR14 v1(111.09,135.33) ; U27.H13 v1(108,161.84) ; v1(107.08,166.42) U27.C12 ; U27.AK4 v1(98.86,141.73) ; U27.AL38 132.6,139.47 132.99,139.86 132.99,139.87 v1(133.05,139.93) 133.06,139.93 133.52,139.47 U27.AL39 ; C3322.1 v1(11.51,60.25) ; U27.H34 v1(128.49,160.02) ; U27.T4 v1(98.86,153.61) ; U27.AM30 v1(124.83,138.98) ; U27.M26 v1(119.89,158.19) ; U27.K28 121.27,159.56 v1(121.73,160.02) ; U27.AT3 v1(97.94,136.24) U27.AT2 ; U27.AW26 v1(122.09,132.58) ; U27.G12 v1(106.17,161.84) ; v1(99.77,144.47) U27.AG5 ; Q49.1 v1(178.25,37.11) ; U27.AK26 v1(121.17,140.81) ; U27.AD7 v1(101.6,146.3) ; U27.AN37 v1(132.15,138.04) ; U27.H32 v1(126.66,160.02) ; U27.M18 v1(112.57,158.19) ; v1(95.91,144.93) U27.AF1 ; v1(135.09,144.93) U27.AE40 ; U27.AA35 v1(130.32,149.04) ; U27.AT12 108.42,135.27 108.39,135.27 v1(108.34,135.32) 108.32,135.31 108.32,135.28 U27.AT11 ; U27.H39 v1(133.97,160.93) ; v1(108.91,166.42) U27.C14 ; U27.W7 v1(101.6,151.79) ; v1(135.09,143.1) U27.AG40 ; U27.M24 v1(118.06,158.19) ; U27.M22 v1(116.23,158.19) ; v1(101.6,162.76) U27.F7 ; U27.M28 v1(121.72,158.19)
  TOP w0.381: v1(11.88,8.46) 11.88,9.46 12.7,10.29 C496.2 ; U27.E3 U27.D2 U27.C3 98.41,165.96 v3(98.86,166.4) 99.31,166.86 U27.B4 ; R596.2 15.85,45.14 v1(15.7,45.29) ; U27.AN22 117.97,137.65 v1(118.43,138.1) ; v3(29.21,55.24) 29.13,55.16 U29.AM6 ; U27.C18 112.15,165.96 112.82,166.62 v1(112.85,166.62) ; v1(55.47,19.05) 55.47,18.62 55.63,18.47 C575.2 55.61,18.17 55.51,18.17 55.24,17.91 54.3,17.91 QF2.4 ; Q37.4 164.87,158.73 v1(164.8,158.65) ; U27.AR16 U27.AR17 ; U27.AR11 107.81,135.78 v1(107.42,136.18) ; U27.T36 v1(131.23,153.61) ; U27.AT14 U27.AT13 ; U27.AT15 U27.AT16 ; U27.U4 v1(98.86,153.61) ; v1(76.45,224.54) R32.1 C36.2 ; v1(127.58,134.39) 127.12,134.86 U27.AT32 ; v1(38.53,25.67) 38.48,25.72 C615.2 ; Q50.4 v1(169.09,51.08) ; U27.AT5 100.26,135.78 100.41,135.64 100.91,135.64 101.06,135.78 U27.AT6 ; v1(128.49,138.04) 128.94,138.49 U27.AM34 129.15,138.74 129.65,138.74 U27.AM35 ; R620.2 v1(51.18,22.78) ; v1(167,161.59) Q37.1 ; v3(25.65,59.03) 25.68,59 U29.AU1 ; v1(101.6,160.93) U27.J7 ; U27.H1 v1(95.93,161.39) ; v1(129.01,222.71) U15.8 U15.3 ; v1(31.53,152.31) 31.53,152.21 32.58,151.15 MINI1.35 ; v1(116.23,161.86) 115.77,161.4 U27.H22 ; U27.K22 116.23,160.02 v1(116.23,160.03) ; v1(132.14,158.19) U27.L38 U27.M37 ; Q55.4 71.85,31.88 v1(72.39,31.88) ; R794.2 v1(178.8,120) ; C557.2 35.69,28.26 v1(35.69,27.53) ; v1(99.79,138.06) 100.23,137.62 U27.AP5
  TOP w0.406: Q62.1 13.66,17.19 13.97,16.88 13.97,15.49 14.1,15.37 v1(14.1,15.34) 14.12,15.37 14.49,15.37 Q62.4 ; Q64.1 185.18,217.15 185.58,217.55 v1(185.8,217.55) ; v1(183.31,217.65) 183.31,215.4 Q64.4 ; v1(147.96,71.33) U47.8 U47.3 v1(147.96,74.04) ; C680.2 v1(7.38,103.58) 7.33,103.53 Q108.4 ; Q108.1 4.96,102.12 v1(4.22,102.87) ; v3(24.54,35.74) 24.92,36.12 U29.AV41 ; v1(7.72,180.52) 7.39,180.19 Q48.4 ; Q73.1 139.73,43.26 140.14,42.84 C3320.2 ; v1(137.72,39.78) 137.45,40.05 Q73.4 ; U32.3 U32.8 105.54,230.22 v1(105.84,230.52) ; v1(123.72,217.22) 124,217.5 U10.3 U10.8 ; Q48.1 9.27,177.67 9.8,177.14 v1(10.62,177.14) ; U25.8 U25.3 v1(109.09,227.94) ; Q55.1 70.34,28.84 70.36,28.83 v1(70.36,28.75) ; v1(112.65,227.71) U34.3 U34.8
  TOP w0.432: U27.K7 v1(101.6,159.1)
  TOP w0.508: Q53.E 65.88,57.49 66.24,57.12 v1(67.01,57.12) ; R572.2 91.03,16.95 v1(90.72,16.63) ; v1(161.34,160.73) 160.96,160.35 Q56.S ; C108.2 188.34,158.52 v1(188.37,158.5) ; R105.2 170.58,154.52 170.84,154.77 C172.2 171.58,153.84 v1(171.59,153.83) ; C616.2 166.69,85.85 v1(166.88,86.04) ; v1(11.96,31.67) 12.38,31.25 C436.2 ; v1(12.27,227.2) C42.2 ; C19.2 82.28,227.16 v1(82.4,227.05) ; C478.2 104.58,21.91 104.39,21.72 v1(104.39,21.64) ; R2215.2 R840.2 v1(40.56,23.05) ; U27.C40 134.63,165.04 v1(135.08,164.6) 134.81,164.33 134.63,164.33 U27.D40 ; v1(175.39,135.05) 175.5,135.05 175.51,135.04 R838.1 R849.1 ; v1(39.88,168.53) 39.88,167.49 40.61,166.75 MINI1.4 44.13,166.75 C267.2 ; v1(65.18,233.32) 65.02,233.17 R117.1 ; C388.2 171.79,72.84 v1(171.82,72.81) ; R2231.2 74.22,146.32 74.64,145.89 v1(74.96,145.89) ; C592.2 177.61,85.53 v1(177.18,85.97) ; R833.1 191.64,137.91 v1(191.89,137.67) ; v1(94.82,29.18) 94.82,28.46 C1671.2 ; v1(184.1,222.58) 183.67,223.01 C51.2 ; v1(105.33,78.52) C489.2 ; v6(69.55,77.11) 69.16,77.5 C198.2 ; C76.2 185.61,218.76 v1(185.14,219.23) ; v1(152.84,210.77) UC97.2 UC107.2 ; v1(96.95,24.56) 96.7,24.31 R633.2 ; v1(30.86,64.62) 30.56,64.31 R426.2 ; R842.1 176.09,137.63 R839.1 175.26,137.63 v1(175.23,137.6) ; C135.2 C139.2 27.79,188.79 v1(27.81,188.76) 27.84,188.79 C134.2 C142.2 ; C568.2 48.17,36.88 v1(48.16,36.87) ; C678.2 4.57,106.84 v1(4.57,105.99) ; v1(40.72,69.93) 41.21,70.41 C378.2 ; C304.2 188.9,109.27 188.09,108.46 v1(188.09,108.25) ; v1(26.47,25.45) 26.24,25.68 R395.2 ; R67.1 v1(116.52,225.93) ; C15.2 v1(73.51,229.74) ; 104.85,25.96 104.62,25.73 C475.2 104.14,26.81 v1(104.17,26.84) ; v1(184.1,230.17) 184.1,230.33 184.15,230.38 UU12.2 ; C129.2 183.13,161.38 v1(183.13,160.65) ; v1(9.6,33.02) 9.78,33.02 10.22,32.58 C412.2 C524.2 ; Q54.S 158.37,163.39 v1(158.37,164.3) ; MINI1.34 43.39,151.55 v1(44.2,150.75) ; C376.2 44.7,151.64 v1(44.83,151.51) ; C229.2 169.49,160.86 169.21,161.14 v1(168.83,161.14) ; C528.2 v1(164.2,15.09) ; v1(16.92,31.22) 16.33,31.8 C447.2 ; C579.2 53.43,104.94 v1(53.47,104.9) ; C174.2 R231.2 181.87,167.98 C145.2 181.86,168.8 v1(181.83,168.83) ; C598.2 v1(100.52,83.87) ; C429.2 v1(178.69,9.83) ; R518.2 174.56,122.3 v1(175.37,122.3) ; C576.2 176.21,141.16 v1(175.37,141.16) ; MINI1.15 34.58,162.35 35.26,163.02 35.26,164.34 v1(35.35,164.44) 35.05,164.75 MINI1.9 ; R657.2 v1(98.78,27.18) ; R827.1 191.84,131.82 v1(191.84,131.81) ; v1(10.72,181.61) 10.72,181.6 10.97,181.34 R25.2 ; v1(161.09,206.2) 161.9,206.2 C94.2 ; R712.2 63.02,14.56 63.02,14.55 v1(63.02,14.4) ; C440.2 v1(157.89,25.63) ; v1(168.28,164.54) 168.43,164.39 C72.2 ; v1(191.68,142.11) 191.64,142.15 191.64,142.91 R663.1 ; v1(73.53,224.54) R31.1 C35.2 ; C1673.2 29.18,66.04 29.79,65.43 v1(30.07,65.43) 30.07,65.71 30.49,66.12 C544.2 ; C491.2 v1(59.69,42.46) ; v1(46.43,24.08) 45.97,24.53 R687.2 ; R812.2 57.7,14.54 57.68,14.53 v1(57.68,14.4) ; C578.2 111.06,104.48 v1(111.23,104.65) ; C443.2 21.54,26.47 v1(22.23,27.15) ; v1(169.16,216.23) 169.77,215.62 169.77,213.58 C86.2 ; C227.2 v1(176.58,152.98) ; R764.2 59.86,14.54 59.84,14.53 v1(59.84,14.4) ; MINI1.50 43.44,145.15 43.64,145.35 C266.2 46.05,145.35 v1(46.06,145.35) ; C1672.2 v1(61.97,14.4) ; R412.2 v1(31.6,63.98) ; U17.2 70.99,34.35 R261.2 v1(70.13,34.29) ; v1(185.37,181.05) C237.1 ; C231.2 44.39,142.62 v1(43.56,142.62) ; v1(100.25,78.61) 100.25,79.79 R853.2 ; v1(46.38,60.71) 46.55,60.87 C398.2 ; v1(179.43,70.31) 179.43,69.37 179.03,68.96 C374.2 ; v1(29.29,15.06) 29.46,14.88 C472.2 ; v1(97.76,131.5) 98.39,132.13 U27.AY3 U27.AW3 ; C523.2 v1(69.98,64.86) ; C379.2 41.17,64.82 40.72,64.36 v1(40.69,64.36) ; R410.1 18.29,61.09 v1(18.16,61.21) ; v1(96.19,64.48) 96.38,64.67 C389.2 97.57,64.67 C385.2 ; R797.2 157.09,158.05 v1(157.28,157.86) ; R464.2 178.46,36.89 v1(178.25,37.11) ; R2217.2 R2219.2 176.19,143.17 R661.1 176.18,144.2 175.84,144.2 175.38,144.66 v1(175.37,144.66) ; v1(121.54,29.97) 120.66,29.09 R492.2 ; R837.1 175.33,131.94 v1(175.23,132.04) ; R837.1 R836.1 ; R837.1 R848.1 ; R358.2 184.59,106.68 184.19,106.27 v1(184.15,106.27) ; C3324.2 v1(104.29,78.52) ; U1.2 v1(80.39,232.16) ; v1(174.4,201.45) 174.4,202.55 C90.2 ; MINI1.27 35.52,154.35 35.62,154.25 v1(35.72,154.25) ; v1(183.44,61.98) C407.2 ; C194.2 75.13,39.12 v1(75.26,39.24) ; R220.2 174.88,170.4 v1(174.88,169.63) 174.88,169.58 174.79,169.49 R111.2 174.79,168.3 174.92,168.17 174.92,167.8 v1(174.96,167.77) ; v1(4.3,112.8) 4.3,113.4 C306.2 5.22,114.32 R351.2 4.53,114.98 v1(4.3,115.21) 4.3,115.33 4.95,115.97 C308.2 ; R826.1 191.84,130.8 v1(191.87,130.83) ; C137.2 11.18,191.48 v1(10.74,191.91) ; C3321.2 v1(193.88,219.18) 193.33,218.63 Q109.E ; v1(165.61,200.38) 165.43,200.56 C120.2 ; R29.1 12.9,225.55 v1(13.06,225.7) ; v1(50.42,104.78) 50.49,104.7 C587.2 ; R859.2 169.67,83.76 C591.2 169.48,82.97 v1(169.72,82.73) 169.77,82.68 C590.2 ; C608.2 114.11,85.08 v1(113.59,85.6) 112.97,84.98 C593.2 ; C310.2 9.9,108.34 C315.2 9.89,107.86 v1(10.29,107.47) ; UR107.2 UC118.2 v1(156.22,64.15) ; C594.2 117.03,85.2 v1(117.55,85.72) 118.17,85.1 C589.2 ; v1(42.1,141.11) 42.58,140.63 C377.2 ; v1(70.61,224.54) R30.1 C34.2 ; R476.2 v1(105.08,66.85) ; C140.2 v1(44.32,184.66) ; C421.2 29.32,148.6 C424.2 31.05,148.6 v1(31.09,148.56) 31.29,148.56 31.91,147.95 MINI1.43 ; R438.2 v1(91.52,53.67) ; C1669.2 81.72,26.58 82.09,26.21 v1(82.6,26.21) ; C580.2 R856.2 v1(174.82,81.8) ; v1(181.2,219.63) 181.34,219.49 C74.2 182.79,219.41 R21.1 ; R796.2 R417.2 91.82,159.4 R541.2 91.44,159.78 91.44,160.02 91.24,160.22 91.22,160.22 R1248.2 90.39,160.22 90.33,160.22 89.69,159.58 89.69,156.36 v1(89.71,156.34) ; C520.2 131.64,85.72 v1(131.66,85.75) ; C14.2 v1(70.59,229.74) ; C91.2 v1(172.4,201.32) 172.54,201.46 R172.1 ; v1(162.61,212.55) 162.61,213.41 UC103.2 162.37,214.06 UC104.2 ; PR106.2 126.23,42.83 v1(126.22,42.84) ; C12.2 74.1,231.37 v1(74.05,231.32) ; v1(51.63,30.98) 51.62,30.98 51.61,30.99 50.84,30.99 C446.2 ; v1(135.51,218.62) UC62.2 136.36,219.56 UC75.2 ; R832.1 191.74,136.9 v1(191.87,136.76) ; v1(171.75,167.59) 171.45,167.59 171.17,167.87 C71.2 ; v1(116.54,29.97) 116.45,29.97 115.84,29.36 C422.2 ; v1(172.34,38.96) 172.26,38.89 R736.2 ; C526.2 20.86,46.16 v1(20.93,46.09) ; Q74.E 187.67,114.97 v1(188.09,114.55) ; v1(39.85,155.26) 40.36,154.75 MINI1.26 C240.2 ; C600.2 v1(96.46,83.87) ; R579.1 C417.2 11.05,36.58 10.67,36.2 v1(10.52,36.2) ; C65.2 v1(87.12,229.74) ; v6(133.99,207.49) C183.2 v6(131.31,207.49) ; UU38.2 v1(161.8,61.44) ; v1(105.18,104.67) 105.18,104.02 C577.2 ; C435.2 v1(174.6,23.95) ; v1(80.34,227.05) 80.28,227.11 C18.2 ; v1(133.29,131.49) 133.24,131.49 U27.AW38 ; C420.2 R498.2 v1(118.69,24.77) ; C95.2 164.55,207.29 v1(163.88,207.29) ; v1(173.43,210.06) C100.2 ; C613.2 121.02,85.28 v1(121.44,85.7) 122.13,85 C499.2 ; C354.2 26.35,71.11 v1(26.61,71.37) ; R649.2 56.52,25.88 v1(56.49,25.91) 57.11,25.91 R564.2 ; v6(67.06,34.8) 66.76,35.09 C451.2 C614.2 66.76,37.47 v6(66.7,37.54) ; v1(24.6,16.79) 23.77,16.79 Q60.E ; C180.1 140.51,196.22 v6(140.51,195.5) ; C96.2 v1(174.69,34.49) ; v1(66.17,70.36) 65.86,70.67 Q78.S 64.75,70.67 62.81,72.6 Q77.S 60.53,71.65 60.53,69.41 C254.2 ; C540.2 v1(42.8,62.87) ; v1(115.42,199.64) 115.95,200.18 R207.2 ; v1(185.95,156.49) C113.2 ; v1(191.97,133.88) 191.95,133.85 R829.1 ; v1(89.13,11.67) 89.15,11.7 89.15,11.94 89.53,12.32 C462.2 C461.2 89.28,10.73 C460.2 C484.2 ; R559.2 176.8,24.08 v1(177.77,24.08) ; R145.1 v1(159.94,211.07) ; C602.2 v1(104.58,83.87) ; C133.2 C132.2 v1(44.01,191.13) ; v1(159.66,207.67) 159.61,207.62 C114.2 ; v1(107.95,42.55) 109.05,41.44 C143.2 ; v1(28.76,64.98) 28.66,64.88 R393.2 ; v1(113.92,219.25) 114.24,219.57 C53.2 ; C59.2 v1(11.15,230) ; MINI1.53 32.15,170.8 31.45,171.5 v1(31.45,171.63) ; v1(99.24,4.14) 99.25,4.15 ; 99.25,4.15 R717.2 ; 99.25,4.15 99.29,4.19 101.12,4.19 101.35,4.42 C483.2 ; v1(35.35,153.47) 35.18,153.47 35.1,153.55 MINI1.29 ; U27.AU40 135.02,133.36 v1(135.55,133.36) ; v1(175.39,127.88) R845.1 R844.1 ; C527.2 63.58,29.59 63.8,29.82 v1(63.81,29.82) ; v1(185.8,217.55) 185.84,217.51 185.84,216.66 186.48,216.02 R108.2 ; v1(190.63,220.88) 190.63,221.35 C64.2 ; v1(36.83,23.65) 36.83,24.32 R403.2 36.64,24.38 R571.2 ; R624.2 109.21,36.75 v1(109.25,36.78) ; v1(48.01,35.5) C368.2 49.15,35.5 49.15,35.5 C369.2 49.79,35.64 50.3,35.64 50.54,35.88 C370.2 ; v1(187.88,226.76) UC133.2 UR119.2 ; PC352.2 v1(66.29,32.72) ; v1(184.07,25.4) 184.09,25.41 184.09,26.21 C456.2 ; UC22.2 v1(186.69,227.05) ; Q72.E 23.12,12.85 22.33,13.64 v1(22.33,14.33) ; R219.2 v1(172.57,153.08) ; v1(95.76,78.61) C603.2 C605.2 ; UU37.2 v1(153.62,65.68) ; v1(44.05,159.02) 44.7,158.37 R388.1 44.6,157.95 MINI1.18 ; R133.1 v1(43.81,62.87) ; R655.2 34.8,31.24 v1(34.92,31.37) ; v1(178.97,153.17) 178.57,153.57 C103.2 ; U6.2 v1(177.37,215.01) ; Q45.E v1(177.87,52.25) ; C572.2 42.21,28.54 v1(42.61,28.14) ; Q58.S v1(182.06,49.59) ; UR106.2 UC117.2 137.22,214.57 v1(137.67,214.12) ; C596.2 108.9,83.83 v1(109.37,83.36) 110.05,84.04 C609.2 ; C22.2 v1(76.43,229.74) ; PC72.2 v6(124.89,47.68) ; R824.1 174.14,31.6 v1(174.25,31.49) ; v1(117.07,104.7) 117.03,104.66 C582.2 ; C506.2 34.09,63.63 v1(34.19,63.73) 34.19,65.11 C545.2 ; C144.2 v6(112.65,51.89) ; v1(94.74,78.61) 93.98,79.38 C611.2 ; C418.2 42.74,168.72 v1(41.53,169.93) ; R457.2 v1(100.65,64.21) ; C408.2 183.64,23.51 v1(183.78,23.65) ; v1(156.37,152.99) 156.24,153.13 156.24,153.21 155.82,153.63 C567.2 155.82,154.06 155.4,154.48 155.27,154.48 C187.2 ; R818.2 55.59,14.52 55.58,14.5 v1(55.58,14.4) ; R2226.2 183.63,120.11 182.91,120.11 v1(182.61,120.41) ; C195.2 69.01,41.21 v1(68.83,41.03) ; v1(175.36,129.98) 175.43,129.91 R835.1 R834.1 ; UC79.2 151.21,64.39 v1(150.77,63.96) 150.32,64.41 UC80.2 ; UC78.2 151.17,225.76 v1(151.19,225.73) ; 97.18,52.48 97.42,52.24 R442.1 ; C541.2 v1(44.83,62.87) ; R831.1 191.97,135.88 v1(192,135.91) ; v6(84.38,195.96) 84.35,195.94 C177.1 ; R514.1 19.82,36.66 19.84,36.68 v1(19.84,36.75) C415.2 ; R665.2 173.77,82.9 C581.2 v1(173.55,81.79) ; v1(106.22,78.52) C607.2 ; R472.2 v1(106.31,54.01) ; UC76.2 150.82,219.07 v1(150.8,219.1) ; v1(25.25,60.07) 25.25,60.32 25.26,60.34 C355.2 C366.2 ; v1(158.65,207.16) 158.6,207.11 C119.2 ; v1(33.71,143.46) 34.16,143.01 MINI1.54 ; UU43.2 v1(133.49,217.56) ; v1(111.7,224.99) C26.2 C27.2 ; C410.2 v1(171.7,69.67) ; v1(191.87,132.86) 191.84,132.83 R828.1 ; C404.2 v1(158.2,66.67) ; v1(133.5,166.62) 133.52,166.6 U27.B39 ; C400.2 v1(104.11,66.85) ; R643.2 v1(96.06,4.19) ; R401.2 187.1,121.32 187.1,122.17 v1(187.05,122.17) ; v1(191.92,134.89) 191.9,134.87 R830.1 ; v1(56.44,19.05) 56.44,18.72 56.64,18.52 R816.2 ; v1(174.78,120.55) 174.5,120.27 R793.2 ; Q110.E 188.63,218.63 v1(188.11,218.11) ; U30CN1.4 78.61,44.2 79.21,44.79 v1(79.21,44.83) ; C604.2 C606.2 97.54,78.61 v1(97.54,78.61) ; v1(108.79,7.8) 109.12,7.46 Q79.E ; C441.2 181.91,23.9 v6(181.71,23.7) 181.8,23.61 LED1.1 ; C393.2 161,67.17 v1(161.52,66.65) 162.04,67.17 C392.2 ; C93.2 175.19,206.07 175.47,206.35 v1(175.54,206.35) ; R225.2 v1(174.6,152.97) ; R140.1 171.45,123.21 C512.2 171.2,123.46 v1(171.2,124.07) ; C599.2 v1(95.31,83.87) ; C445.2 v1(57.15,42.04) ; v1(178.65,31.38) 178.65,31.41 178.52,31.53 Q70.E 179.13,32.91 R747.2 ; C89.2 183.14,35.89 v1(183.36,36.12) ; C213.2 66.55,40.39 v6(66.55,38.73) ; v1(75.69,30.58) C470.2 ; v1(134.41,130.97) 134.41,132.14 U27.AV39 U27.AV38 ; R428.2 C390.2 177.42,71.08 v1(176.93,70.59) ; R659.2 6.54,182.18 7.02,182.66 Q44.E 7.45,183.43 v1(7.72,183.69) ; v1(141.5,42.84) C3320.2 ; U24.2 v1(81.79,232.16) ; C380.2 v1(172.7,71.82) ; U27.B38 132.6,166.6 v1(132.63,166.62) ; R864.2 165.41,83.29 v1(165.66,83.04) ; R641.2 v1(98.96,24.69) ; Q59.E 19.84,16.67 v1(19.84,17.91) 19.84,18.18 19.54,18.48 R554.2 ; C414.2 186.22,49.09 v1(186.26,49.05) ; R1549.2 16.19,35.29 16.06,35.15 15.49,35.15 v1(15.47,35.18) ; C597.2 v1(99.38,83.87) ; v1(109.3,33.96) 109.17,33.83 C252.2 ; U9.2 v1(170.76,215.01) ; Q4.S 112.85,215.47 v1(112.85,215.39) ; C601.2 v1(103.44,83.87) ; R239.2 v1(175.62,152.97) ; v1(114.43,6.53) 114.74,6.85 Q80.S ; U29.AW40 U29.AV41 ; U11.2 v1(182.6,210.36) ; U35CN1.4 v1(88.9,44.96) ; PR85.2 130.99,41.73 v1(131.14,41.58) ; C31.2 v1(116.94,219.07) ; R299.2 163.58,164.52 v1(163.58,162.94) ; v1(105.26,7.94) 105.6,7.59 R755.2 C516.2 ; v1(184.28,39.7) C438.2 ; R341.1 172.27,150.13 172.27,150.14 v1(172.07,150.34) ; C423.2 22.3,22.25 v1(22.61,21.95) ; v1(32,157.48) 32,157.28 32.53,156.75 MINI1.21 ; v1(56.26,42.04) C466.2 ; R20.1 R617.2 18.15,54.9 v3(18.21,54.97) ; C569.2 24.07,33.71 24.49,34.13 v1(24.49,34.32) ; U51.1 61.08,66.53 60.42,67.19 R209.2 60.17,67.18 58.39,67.18 v1(58.09,66.88) ; C595.2 C588.2 v1(99.31,78.61) ; v1(167.79,163.73) 167.79,163.35 168.17,162.97 C153.2 ; C353.2 23.29,69.62 v1(22.94,69.98) ; C111.2 v1(182.73,201.66) ; v1(104.98,36.67) Q57.E ; C191.2 7.94,186.68 v1(7.77,186.84) ; v1(169.75,157.6) 169.87,157.6 170.04,157.77 C70.2 ; R562.2 v1(65.18,14.38) ; v1(19.46,33.12) 19.46,33.12 19.85,33.52 C525.2 ; C136.2 v6(57.53,83.95) ; v1(43.54,25.72) C463.2 ; v1(32.64,63.65) 32.77,63.52 R425.2 ; R221.2 v1(173.58,152.97) ; C23.2 v1(78.26,227.58) ; v1(186.13,66.1) C399.2 ; C536.2 C518.2 58,61.33 v6(57.86,61.47) ; v1(113.67,11.42) 113.67,12.51 R668.2 ; UU42.2 v1(148.5,223.93) ; v1(30.78,28.98) 30.86,28.91 C3315.2 ; v1(142.94,75.18) UC63.2 ; C381.2 v1(92.28,56.18) ; C21.2 v1(83.79,228.73) ; C505.2 134.62,44.3 v1(134.39,44.53) ; C24.2 v1(72.42,227.58) ; C97.2 v1(176.53,204.85) ; v1(132.31,44.19) PR84.2 ; C375.2 v1(164.83,68.35) ; C25.2 v1(75.34,227.58) ; PC65.2 131.17,53.8 v6(131.04,53.92) ; DQ61.E v1(158.79,14.48)
  TOP w0.635: TC11.2 28.36,204.95 ; TC11.2 26.25,204.95 ; TC11.2 27.3,206.01 ; USBCN1.12 144.01,230.74 ; USBCN1.12 144.01,227.31 ; USBCN1.12 142.3,229.02 ; USBCN1.12 145.73,229.02 ; 90.64,239.52 VGA1.17 ; VGA1.17 92.73,241.6 ; VGA1.17 92.73,237.44 ; VGA1.17 94.81,239.52 ; RJ45.G3 165.28,228.94 ; RJ45.G3 163.56,227.23 ; RJ45.G3 161.85,228.94 ; RJ45.G3 163.56,230.66 ; RJ45.G5 165.28,234.62 ; RJ45.G5 163.56,232.91 ; RJ45.G5 163.56,236.34 ; RJ45.G5 161.85,234.62 ; 102.41,240.41 HDMI1.22 ; HDMI1.22 104.75,240.41 ; HDMI1.22 103.58,238.64 ; HDMI1.22 103.58,242.18 ; 194.45,115.38 FNCPU1.1 194.45,113.12 ; 126.01,233.64 USB3R1.20 ; USB3R1.20 124.3,235.36 ; USB3R1.20 126.01,237.07 ; 160.78,235.53 RJ45.G7 ; RJ45.G7 162.5,237.25 ; RJ45.G7 159.07,237.25 ; RJ45.G7 160.78,238.96 ; VGA1.16 67.73,241.6 ; VGA1.16 69.82,239.52 ; VGA1.16 65.65,239.52 ; VGA1.16 67.73,237.44 ; 144.01,232.99 USBCN1.10 ; USBCN1.10 144.01,236.42 ; USBCN1.10 145.73,234.7 ; USBCN1.10 142.3,234.7 ; USB3R1.22 126.01,231.4 ; USB3R1.22 124.3,229.68 ; USB3R1.22 126.01,227.97 ; USBCN1.4 148.11,231.99 ; USBCN1.4 147.08,230.96 ; USBCN1.4 146.05,231.99 ; USBCN1.4 147.08,233.02 ; 166.63,230.88 RJ45.U4 ; RJ45.U4 167.66,231.91 ; RJ45.U4 166.63,232.94 ; RJ45.U4 165.6,231.91 ; RJ45.G8 181.19,237.25 ; RJ45.G8 177.76,237.25 ; RJ45.G8 179.48,238.96 ; RJ45.G8 179.48,235.53 ; 193.95,56.33 ATX1.3 195.4,57.78 ; 75.97,239.52 VGA1.7 ; USBCN1.8 148.11,229.37 ; USBCN1.8 147.08,230.4 ; USBCN1.8 147.08,228.34 ; USBCN1.8 146.05,229.37 ; 187,19.98 ATX1.24 ; ATX1.24 189.9,19.98 ; ATX1.24 188.45,18.53 ; 193.82,189.23 ATX12V.1 192.38,187.79 ; TC38.2 186.14,13.23 ; TC38.2 185.09,14.29 ; TC38.2 185.09,12.18 ; 116.91,240.41 HDMI1.23 ; HDMI1.23 118.08,238.64 ; HDMI1.23 119.25,240.41 ; HDMI1.23 118.08,242.18 ; 155.44,234.7 USBCN1.9 ; USBCN1.9 157.15,236.42 ; USBCN1.9 158.87,234.7 ; 188.18,187.79 ATX12V.2 ; ATX12V.2 191.05,187.79 ; ATX12V.2 189.62,189.23 ; 162.5,224.57 RJ45.G1 160.78,226.29 ; 165.6,229.29 RJ45.U8 166.63,230.32 ; 193.95,50.83 ATX1.5 195.4,49.38 ; HDMI1.21 119.25,234.45 ; HDMI1.21 118.08,232.38 ; HDMI1.21 118.08,236.52 ; 74.76,238.44 VGA1.6 ; VGA1.6 74.76,240.6 ; VGA1.6 73.68,239.52 ; VGA1.6 75.84,239.52 ; HDMI1.20 103.58,236.52 ; HDMI1.20 104.75,234.45 ; HDMI1.20 103.58,232.38 ; HDMI1.20 102.41,234.45 ; RJ45.G6 176.7,236.34 ; RJ45.G6 174.98,234.62 ; RJ45.G6 178.41,234.62 ; DIMM1.2 173.94,100.65
  L3 w0.635: 9.27,14.68 LEDH1.5 ; LEDH1.5 8.22,15.73 ; LEDH1.5 9.27,16.78 ; LEDH1.5 10.32,15.73 ; 14.15,178.65 SLOT2.B18 ; SLOT2.B18 13.25,179.55 ; SLOT2.B18 14.15,180.45 ; SLOT2.B18 15.05,179.55 ; SLOT2.B76 14.15,122.45 ; SLOT2.B76 15.05,121.55 ; SLOT2.B76 13.25,121.55 ; SLOT2.B76 14.15,120.65 ; 149.14,87.05 DIMM2.145 ; DIMM2.145 150.94,87.05 ; DIMM2.145 150.04,86.15 ; DIMM2.145 150.04,87.96 ; 188.45,43.76 ATX1.18 ; ATX1.18 189.87,45.18 ; ATX1.18 188.45,46.6 ; ATX1.18 187.03,45.18 ; SLOT2.A31 18.65,167.45 ; SLOT2.A31 18.65,165.65 ; SLOT2.A31 19.55,166.55 ; SLOT2.A31 17.75,166.55 ; 170.04,89.95 DIMM2.5 ; DIMM2.5 169.14,90.85 ; DIMM2.5 170.94,90.85 ; DIMM2.5 170.04,91.76 ; 79.04,91.85 DIMM2.92 ; DIMM1.166 129.94,96.85 ; DIMM1.166 128.14,96.85 ; DIMM1.166 129.04,95.95 ; DIMM1.166 129.04,97.76 ; SLOT2.B22 14.15,176.45 ; SLOT2.B22 13.25,175.55 ; SLOT2.B22 15.05,175.55 ; SLOT2.B22 14.15,174.65 ; 19.75,119.55 SLOT2.A78 ; SLOT2.A78 20.65,120.45 ; SLOT2.A78 20.65,118.65 ; SLOT2.A78 21.55,119.55 ; DIMM2.157 138.94,87.05 ; DIMM2.157 138.04,86.15 ; DIMM2.157 137.14,87.05 ; 189.67,5.88 H2.3 ; H2.3 190.46,6.66 ; H2.3 190.46,5.09 ; RJ45.R10 176.86,221.93 ; RJ45.R10 174.83,221.93 ; RJ45.R10 175.84,220.91 ; RJ45.R10 175.84,222.95 ; 34.45,180.65 SLOT1.B16 ; SLOT1.B16 35.35,181.55 ; SLOT1.B16 33.55,181.55 ; SLOT1.B16 34.45,182.45 ; ATX12V.1 193.82,189.2 ; ATX12V.1 192.41,187.79 ; ATX12V.1 193.82,186.38 ; ATX12V.1 195.23,187.79 ; VGA1.8 79.34,240.6 ; VGA1.8 78.26,239.52 ; VGA1.8 79.34,238.44 ; VGA1.8 80.42,239.52 ; 168.04,86.15 DIMM2.127 ; DIMM2.127 168.04,87.96 ; DIMM2.127 168.94,87.05 ; DIMM2.127 167.14,87.05 ; SLOT2.B60 14.15,138.45 ; SLOT2.B60 15.05,137.55 ; SLOT2.B60 13.25,137.55 ; SLOT2.B60 14.15,136.65 ; RJ45.G5 163.56,236.34 ; RJ45.G5 163.56,232.91 ; RJ45.G5 165.28,234.62 ; RJ45.G5 161.85,234.62 ; H2.1 193.8,9.7 ; H2.1 192.23,9.7 ; H2.1 193.02,10.49 ; 33.55,179.55 SLOT1.B18 ; SLOT1.B18 34.45,178.65 ; SLOT1.B18 34.45,180.45 ; SLOT1.B18 35.35,179.55 ; BT1.2 163.6,45.97 ; BT1.2 161.47,45.97 ; BT1.2 162.53,47.04 ; BT1.2 162.53,44.91 ; 192.53,57.78 ATX1.3 ; ATX1.3 195.37,57.78 ; ATX1.3 193.95,56.36 ; ATX1.3 193.95,59.2 ; 153.35,76.41 USBF3.13 ; USBF3.13 153.35,78.29 ; USBF3.13 154.29,77.35 ; 13.01,5.27 LPC1.14 14,4.28 ; 110.36,29.42 PWCLR1.1 ; PWCLR1.1 111.43,30.48 ; PWCLR1.1 110.36,31.55 ; PWCLR1.1 109.3,30.48 ; 32.68,8.32 H3.2 ; H3.2 33.47,9.1 ; H3.2 33.47,7.53 ; 184.04,13.23 TC38.2 ; TC38.2 185.09,12.18 ; TC38.2 185.09,14.29 ; TC38.2 186.14,13.23 ; SLOT2.A23 19.55,174.55 ; SLOT2.A23 17.75,174.55 ; SLOT2.A23 18.65,175.45 ; SLOT2.A23 18.65,173.65 ; 161.04,91.85 DIMM2.14 ; SLOT2.A59 18.65,139.45 ; SLOT2.A59 18.65,137.65 ; SLOT2.A59 19.55,138.55 ; SLOT2.A59 17.75,138.55 ; TC34.2 146.44,204.42 ; TC34.2 144.33,204.42 ; TC34.2 145.39,205.47 ; TC34.2 145.39,203.36 ; DIMM2.154 141.94,88.95 ; DIMM2.154 140.14,88.95 ; DIMM2.154 141.04,88.05 ; DIMM2.154 141.04,89.86 ; 147.04,88.05 DIMM2.148 146.14,88.95 ; 128.14,88.95 DIMM2.166 ; DIMM2.166 129.04,88.05 ; DIMM2.166 129.94,88.95 ; DIMM2.166 129.04,89.86 ; 16.15,127.65 SLOT2.B69 ; SLOT2.B69 15.25,128.55 ; SLOT2.B69 17.05,128.55 ; SLOT2.B69 16.15,129.45 ; 153.04,88.05 DIMM2.142 ; DIMM2.142 153.04,89.86 ; DIMM2.142 152.14,88.95 ; 174.94,94.95 DIMM1.121 174.04,94.05 ; 16.15,143.65 SLOT2.B53 ; SLOT2.B53 17.05,144.55 ; SLOT2.B53 15.25,144.55 ; SLOT2.B53 16.15,145.45 ; 62.04,86.15 DIMM2.229 ; DIMM2.229 62.94,87.05 ; DIMM2.229 61.14,87.05 ; DIMM2.229 62.04,87.96 ; 55.04,101.56 DIMM1.116 54.14,100.65 ; H6.5 37.59,75.71 ; H6.5 36.02,75.71 ; H6.5 36.8,74.92 ; SLOT2.B16 15.05,181.55 ; SLOT2.B16 13.25,181.55 ; SLOT2.B16 14.15,180.65 ; SLOT2.B16 14.15,182.45 ; USB3R1.4 129.08,234.25 ; USB3R1.4 128.19,233.36 ; USB3R1.4 129.97,233.36 ; 18.65,169.65 SLOT2.A27 ; SLOT2.A27 18.65,171.45 ; SLOT2.A27 17.75,170.55 ; SLOT2.A27 19.55,170.55 ; 83.98,237.52 VGA1.5 ; VGA1.5 85.06,236.44 ; VGA1.5 85.06,238.6 ; VGA1.5 86.14,237.52 ; 194.67,213.68 H4.8 ; H4.8 195.46,214.47 ; H4.8 196.24,213.68 ; ATX1.7 193.95,42.4 ; ATX1.7 192.53,40.98 ; ATX1.7 193.95,39.56 ; ATX1.7 195.37,40.98 ; USBF1.7 177.99,76.13 ; USBF1.7 176.92,75.06 ; USBF1.7 175.85,76.13 ; USBF1.7 176.92,77.2 ; RJ45.U4 166.63,232.94 ; RJ45.U4 165.6,231.91 ; RJ45.U4 166.63,230.88 ; RJ45.U4 167.66,231.91 ; 156.21,221.96 UTC6.2 ; UTC6.2 155.16,223.01 ; UTC6.2 157.26,223.01 ; UTC6.2 156.21,224.07 ; 52.04,97.85 DIMM1.119 ; DIMM1.119 52.04,99.66 ; DIMM1.119 51.14,98.75 ; DIMM1.119 52.94,98.75 ; 19.75,159.55 SLOT2.A38 ; SLOT2.A38 21.55,159.55 ; SLOT2.A38 20.65,160.45 ; SLOT2.A38 20.65,158.65 ; SLOT2.A70 20.65,128.45 ; SLOT2.A70 20.65,126.65 ; SLOT2.A70 21.55,127.55 ; SLOT2.A70 19.75,127.55 ; 80,76.88 SATA1.4 80,75.05 ; TC1.2 108.51,183.81 ; TC1.2 108.51,181.7 ; TC1.2 107.45,182.75 ; 94.56,75.96 SATA0.1 ; SATA0.1 95.48,75.05 ; SATA0.1 95.48,76.88 ; SLOT2.A71 19.55,126.55 ; SLOT2.A71 17.75,126.55 ; SLOT2.A71 18.65,127.45 ; SLOT2.A71 18.65,125.65 ; SLOT2.B7 16.15,193.45 ; SLOT2.B7 15.25,192.55 ; SLOT2.B7 16.15,191.65 ; SLOT2.B7 17.05,192.55 ; 16.15,161.65 SLOT2.B35 ; SLOT2.B35 15.25,162.55 ; SLOT2.B35 16.15,163.45 ; SLOT2.B35 17.05,162.55 ; 32.98,77.48 H6.3 ; H6.3 32.19,78.27 ; H6.3 32.98,79.05 ; FNCPU1.1 194.45,115.38 ; FNCPU1.1 193.29,114.25 ; FNCPU1.1 194.45,113.12 ; FNCPU1.1 195.63,114.25 ; RJ45.G1 160.78,226.29 ; RJ45.G1 159.07,224.57 ; RJ45.G1 160.78,222.86 ; RJ45.G1 162.5,224.57 ; 82.84,239.52 VGA1.10 ; VGA1.10 85,239.52 ; VGA1.10 83.92,238.44 ; VGA1.10 83.92,240.6 ; SLOT2.A51 19.55,146.55 ; SLOT2.A51 18.65,147.45 ; SLOT2.A51 18.65,145.65 ; SLOT2.A51 17.75,146.55 ; SLOT2.A82 21.55,115.55 ; SLOT2.A82 20.65,114.65 ; SLOT2.A82 20.65,116.45 ; SLOT2.A82 19.75,115.55 ; SLOT1.B7 36.45,193.45 ; SLOT1.B7 37.35,192.55 ; SLOT1.B7 36.45,191.65 ; SLOT1.B7 35.55,192.55 ; SLOT2.A66 21.55,131.55 ; SLOT2.A66 20.65,132.45 ; SLOT2.A66 20.65,130.65 ; SLOT2.A66 19.75,131.55 ; SLOT2.B21 16.15,177.45 ; SLOT2.B21 17.05,176.55 ; SLOT2.B21 15.25,176.55 ; SLOT2.B21 16.15,175.65 ; 126.31,108.04 TC45.2 125.26,109.09 ; 53.14,98.75 DIMM1.117 54.04,99.66 ; SLOT2.A55 18.65,143.45 ; SLOT2.A55 19.55,142.55 ; SLOT2.A55 18.65,141.65 ; SLOT2.A55 17.75,142.55 ; 176.7,227.23 RJ45.G4 ; RJ45.G4 178.41,228.94 ; RJ45.G4 176.7,230.66 ; RJ45.G4 174.98,228.94 ; DIMM2.199 92.94,87.05 ; DIMM2.199 91.14,87.05 ; DIMM2.199 92.04,86.15 ; 14.15,124.65 SLOT2.B72 ; SLOT2.B72 14.15,126.45 ; SLOT2.B72 13.25,125.55 ; SLOT2.B72 15.05,125.55 ; TC13.2 26.04,197.09 ; TC13.2 24.98,196.04 ; TC13.2 27.09,196.04 ; 190.46,209.56 H4.3 ; H4.3 189.67,210.35 ; H4.3 190.46,211.13 ; 73.52,74.21 SATA1.9 ; SATA1.9 72.27,75.46 ; SATA1.9 74.77,75.46 ; SATA1.9 73.52,76.71 ; UTC9.2 143.1,60.19 ; UTC9.2 142.05,59.13 ; UTC9.2 144.16,59.13 ; UTC9.2 143.1,58.08 ; 135.04,88.05 DIMM2.160 134.14,88.95 ; H4.4 192.63,208.28 ; H4.4 191.84,207.49 ; H4.4 191.06,208.28 ; H6.4 35.15,76.2 ; H6.4 34.36,75.41 ; H6.4 33.58,76.2 ; SATA0.7 104.01,75.96 ; SATA0.7 103.1,76.88 ; SATA0.7 103.1,75.05 ; 192.23,214.17 H4.1 ; H4.1 193.8,214.17 ; H4.1 193.02,214.96 ; DIMM1.239 52.04,95.86 ; DIMM1.239 52.04,94.05 ; DIMM1.239 51.14,94.95 ; 17.75,118.55 SLOT2.A79 ; SLOT2.A79 19.55,118.55 ; SLOT2.A79 18.65,117.65 ; SLOT2.A79 18.65,119.45 ; DIMM2.143 152.04,87.96 ; DIMM2.143 151.14,87.05 ; DIMM2.143 152.04,86.15 ; DIMM2.143 152.94,87.05 ; 6.73,22.3 LEDH1.12 ; LEDH1.12 5.68,23.35 ; LEDH1.12 6.73,24.4 ; LEDH1.12 7.78,23.35 ; 20.65,194.65 SLOT2.A4 ; SLOT2.A4 21.55,195.55 ; SLOT2.A4 20.65,196.45 ; SLOT2.A4 19.75,195.55 ; 144.01,227.31 USBCN1.12 ; USBCN1.12 142.3,229.02 ; USBCN1.12 144.01,230.74 ; USBCN1.12 145.73,229.02 ; SLOT2.A49 19.55,148.55 ; SLOT2.A49 18.65,147.65 ; SLOT2.A49 17.75,148.55 ; SLOT2.A49 18.65,149.45 ; H6.7 39.36,80.32 ; H6.7 40.15,79.53 ; H6.7 39.36,78.75 ; 69.14,87.05 DIMM2.221 ; DIMM2.221 70.94,87.05 ; DIMM2.221 70.04,86.15 ; 130.14,92.75 DIMM2.44 ; DIMM2.44 131.04,91.85 ; DIMM2.44 131.94,92.75 ; DIMM2.44 131.04,93.66 ; 58.94,90.85 DIMM2.113 57.14,90.85 ; H2.4 192.63,3.81 ; H2.4 191.84,3.02 ; H2.4 191.06,3.81 ; 128.04,97.85 DIMM1.47 ; DIMM1.47 128.94,98.75 ; DIMM1.47 128.04,99.66 ; SLOT2.B32 15.05,165.55 ; SLOT2.B32 13.25,165.55 ; SLOT2.B32 14.15,166.45 ; SLOT2.B32 14.15,164.65 ; H2.6 197.14,4.7 ; H2.6 196.35,3.92 ; H2.6 196.35,5.49 ; 61.04,88.05 DIMM2.230 60.14,88.95 ; 18.65,133.65 SLOT2.A63 ; SLOT2.A63 18.65,135.45 ; SLOT2.A63 19.55,134.55 ; SLOT2.A63 17.75,134.55 ; RJ45.G3 163.56,230.66 ; RJ45.G3 163.56,227.23 ; RJ45.G3 165.28,228.94 ; RJ45.G3 161.85,228.94 ; 112.46,45.06 TC29.2 ; TC29.2 113.51,44 ; TC29.2 114.57,45.06 ; TC29.2 113.51,46.11 ; HDMI1.21 118.08,236.52 ; HDMI1.21 119.25,234.45 ; HDMI1.21 118.08,232.38 ; HDMI1.21 116.91,234.45 ; 15.25,120.55 SLOT2.B77 ; SLOT2.B77 16.15,121.45 ; SLOT2.B77 17.05,120.55 ; SLOT2.B77 16.15,119.65 ; 143.04,88.05 DIMM2.152 142.14,88.95 ; 132.58,232.75 USB3R1.7 132.58,230.97 ; DIMM2.124 171.04,89.86 ; DIMM2.124 170.14,88.95 ; DIMM2.124 171.04,88.05 ; 188.45,18.56 ATX1.24 ; ATX1.24 189.87,19.98 ; ATX1.24 187.03,19.98 ; ATX1.24 188.45,21.4 ; TC41.2 122.7,44.96 ; TC41.2 121.64,46.01 ; TC41.2 120.59,44.96 ; TC41.2 121.64,43.9 ; DB1.2 100.3,31.62 ; DB1.2 99.24,30.56 ; DB1.2 100.3,29.49 ; DB1.2 101.37,30.56 ; 147.35,76.41 USBF3.16 147.35,78.29 ; 20.65,138.65 SLOT2.A58 ; SLOT2.A58 21.55,139.55 ; SLOT2.A58 19.75,139.55 ; SLOT2.A58 20.65,140.45 ; 20.65,142.65 SLOT2.A54 ; SLOT2.A54 20.65,144.45 ; SLOT2.A54 21.55,143.55 ; SLOT2.A54 19.75,143.55 ; 15.25,168.55 SLOT2.B29 ; SLOT2.B29 16.15,167.65 ; SLOT2.B29 17.05,168.55 ; SLOT2.B29 16.15,169.45 ; H3.4 35.15,3.81 ; H3.4 33.58,3.81 ; H3.4 34.36,3.02 ; 165.6,229.29 RJ45.U8 ; RJ45.U8 167.66,229.29 ; RJ45.U8 166.63,228.26 ; RJ45.U8 166.63,230.32 ; 132.58,227.77 USB3R1.16 132.58,229.55 ; RJ45.G6 176.7,236.34 ; RJ45.G6 174.98,234.62 ; RJ45.G6 178.41,234.62 ; RJ45.G6 176.7,232.91 ; 51.14,90.85 DIMM2.119 ; DIMM2.119 52.04,89.95 ; DIMM2.119 52.04,91.76 ; DIMM2.119 52.94,90.85 ; SLOT2.B40 14.15,158.45 ; SLOT2.B40 13.25,157.55 ; SLOT2.B40 14.15,156.65 ; SLOT2.B40 15.05,157.55 ; 143.14,87.05 DIMM2.151 144.04,86.15 ; DIMM2.133 162.04,87.96 ; DIMM2.133 162.94,87.05 ; DIMM2.133 161.14,87.05 ; DIMM2.133 162.04,86.15 ; SATA1.1 83.81,76.88 ; SATA1.1 83.81,75.05 ; SATA1.1 84.73,75.96 ; USBCN1.4 147.08,233.02 ; USBCN1.4 147.08,230.96 ; USBCN1.4 146.05,231.99 ; USBCN1.4 148.11,231.99 ; 187.03,49.38 ATX1.17 ; ATX1.17 188.45,47.96 ; ATX1.17 189.87,49.38 ; ATX1.17 188.45,50.8 ; 18.65,151.65 SLOT2.A45 ; SLOT2.A45 17.75,152.55 ; SLOT2.A45 18.65,153.45 ; SLOT2.A45 19.55,152.55 ; 16.15,139.65 SLOT2.B57 ; SLOT2.B57 15.25,140.55 ; SLOT2.B57 16.15,141.45 ; SLOT2.B57 17.05,140.55 ; 157.15,227.31 USBCN1.11 ; USBCN1.11 157.15,230.74 ; USBCN1.11 155.44,229.02 ; USBCN1.11 158.87,229.02 ; 113.77,73.34 TC15.2 ; TC15.2 112.71,74.4 ; TC15.2 114.82,74.4 ; TC15.2 113.77,75.45 ; 19.75,163.55 SLOT2.A34 ; SLOT2.A34 20.65,162.65 ; SLOT2.A34 21.55,163.55 ; SLOT2.A34 20.65,164.45 ; UTC5.2 189.27,235.97 ; UTC5.2 188.21,237.02 ; UTC5.2 188.21,234.91 ; UTC5.2 187.16,235.97 ; 20.65,122.65 SLOT2.A74 ; SLOT2.A74 20.65,124.45 ; SLOT2.A74 19.75,123.55 ; SLOT2.A74 21.55,123.55 ; 40.05,179.55 SLOT1.A18 ; SLOT1.A18 40.95,178.65 ; SLOT1.A18 40.95,180.45 ; SLOT2.A20 20.65,178.45 ; SLOT2.A20 19.75,177.55 ; SLOT2.A20 21.55,177.55 ; SLOT2.A20 20.65,176.65 ; 128.19,230.16 USB3R1.13 129.97,230.16 ; H3.6 38.87,5.49 ; H3.6 39.66,4.7 ; H3.6 38.87,3.92 ; SLOT2.A67 18.65,131.45 ; SLOT2.A67 17.75,130.55 ; SLOT2.A67 19.55,130.55 ; SLOT2.A67 18.65,129.65 ; 16.15,183.65 SLOT2.B13 ; SLOT2.B13 17.05,184.55 ; SLOT2.B13 15.25,184.55 ; SLOT2.B13 16.15,185.45 ; 59.04,88.05 DIMM2.232 ; DIMM2.232 59.04,89.86 ; DIMM2.232 59.94,88.95 ; H6.2 33.47,81.49 ; H6.2 32.68,80.71 ; H6.2 33.47,79.92 ; 60.16,48.13 TC22.2 ; TC22.2 61.21,49.19 ; TC22.2 61.21,47.08 ; TC22.2 62.27,48.13 ; SLOT2.B36 15.05,161.55 ; SLOT2.B36 14.15,160.65 ; SLOT2.B36 13.25,161.55 ; SLOT2.B36 14.15,162.45 ; 20.65,150.65 SLOT2.A46 ; SLOT2.A46 20.65,152.45 ; SLOT2.A46 19.75,151.55 ; SLOT2.A46 21.55,151.55 ; RJ45.G7 160.78,238.96 ; RJ45.G7 159.07,237.25 ; RJ45.G7 160.78,235.53 ; RJ45.G7 162.5,237.25 ; 15.25,132.55 SLOT2.B65 ; SLOT2.B65 16.15,133.45 ; SLOT2.B65 16.15,131.65 ; SLOT2.B65 17.05,132.55 ; 159.94,88.95 DIMM2.136 159.04,88.05 ; 190.16,8.32 H2.2 ; H2.2 190.95,9.1 ; H2.2 190.95,7.53 ; 34.45,194.65 SLOT1.B4 ; SLOT1.B4 34.45,196.45 ; SLOT1.B4 33.55,195.55 ; SLOT1.B4 35.35,195.55 ; 27.3,203.9 TC11.2 ; TC11.2 28.36,204.95 ; TC11.2 27.3,206.01 ; TC11.2 26.25,204.95 ; 88.04,89.95 DIMM2.83 87.14,90.85 ; 196.84,6.36 H2.7 ; H2.7 196.84,7.93 ; H2.7 197.63,7.14 ; 158.01,175.94 TC12.2 ; TC12.2 156.96,176.99 ; TC12.2 159.07,176.99 ; TC12.2 158.01,178.04 ; 137.04,99.75 DIMM1.38 ; RJ45.G8 181.19,237.25 ; RJ45.G8 179.48,235.53 ; RJ45.G8 179.48,238.96 ; RJ45.G8 177.76,237.25 ; 126.01,233.64 USB3R1.20 ; USB3R1.20 124.3,235.36 ; USB3R1.20 127.73,235.36 ; USB3R1.20 126.01,237.07 ; 20.65,168.65 SLOT2.A28 ; SLOT2.A28 20.65,170.45 ; SLOT2.A28 21.55,169.55 ; SLOT2.A28 19.75,169.55 ; 13.25,129.55 SLOT2.B68 ; SLOT2.B68 14.15,128.65 ; SLOT2.B68 14.15,130.45 ; SLOT2.B68 15.05,129.55 ; H5.2 190.95,81.49 ; H5.2 190.16,80.71 ; H5.2 190.95,79.92 ; USB3R1.21 140.87,229.68 ; USB3R1.21 137.44,229.68 ; USB3R1.21 139.15,227.97 ; USB3R1.21 139.15,231.4 ; 192.53,49.38 ATX1.5 ; ATX1.5 193.95,50.8 ; ATX1.5 195.37,49.38 ; ATX1.5 193.95,47.96 ; 191.06,76.2 H5.4 ; H5.4 191.84,75.41 ; H5.4 192.63,76.2 ; TC2.2 116.46,183.82 ; TC2.2 115.4,182.77 ; TC2.2 117.51,182.77 ; TC2.2 116.46,181.71 ; DIMM2.163 132.04,87.96 ; DIMM2.163 132.04,86.15 ; DIMM2.163 132.94,87.05 ; DIMM2.163 131.14,87.05 ; 65.65,239.52 VGA1.16 ; VGA1.16 67.73,237.44 ; VGA1.16 69.82,239.52 ; VGA1.16 67.73,241.6 ; DIMM2.125 170.94,87.05 ; DIMM2.125 170.04,86.15 ; DIMM2.125 169.14,87.05 ; DIMM2.125 170.04,87.96 ; USBF3.4 146.29,79.35 ; USBF3.4 144.41,79.35 ; USBF3.4 145.35,80.29 ; 13.25,195.55 SLOT2.B4 ; SLOT2.B4 14.15,194.65 ; SLOT2.B4 15.05,195.55 ; SLOT2.B4 14.15,196.45 ; 74.04,86.15 DIMM2.217 74.94,87.05 ; SLOT2.B56 14.15,142.45 ; SLOT2.B56 14.15,140.65 ; SLOT2.B56 15.05,141.55 ; SLOT2.B56 13.25,141.55 ; ATX12V.2 189.62,189.2 ; ATX12V.2 191.03,187.79 ; ATX12V.2 189.62,186.38 ; ATX12V.2 188.21,187.79 ; SLOT1.A4 40.95,196.45 ; SLOT1.A4 41.85,195.55 ; SLOT1.A4 40.05,195.55 ; SLOT1.A4 40.95,194.65 ; SLOT2.B44 15.05,153.55 ; SLOT2.B44 14.15,154.45 ; SLOT2.B44 14.15,152.65 ; SLOT2.B44 13.25,153.55 ; H5.1 193.8,82.09 ; H5.1 192.23,82.09 ; H5.1 193.02,82.88 ; 179.48,222.86 RJ45.G2 ; RJ45.G2 179.48,226.29 ; RJ45.G2 177.76,224.57 ; RJ45.G2 181.19,224.57 ; 38.05,182.55 SLOT1.A15 ; SLOT1.A15 39.85,182.55 ; SLOT1.A15 38.95,181.65 ; SLOT1.A15 38.95,183.45 ; 188.45,39.56 ATX1.19 ; ATX1.19 188.45,42.4 ; ATX1.19 187.03,40.98 ; ATX1.19 189.87,40.98 ; 13.25,171.55 SLOT2.B26 ; SLOT2.B26 14.15,172.45 ; SLOT2.B26 15.05,171.55 ; SLOT2.B26 14.15,170.65 ; 131.14,94.95 DIMM1.163 ; DIMM1.163 132.04,94.05 ; DIMM1.163 132.04,95.86 ; 85.24,75.46 SATA1.8 ; SATA1.8 86.48,74.21 ; SATA1.8 87.73,75.46 ; SATA1.8 86.48,76.71 ; USBF3.7 151.35,80.29 ; USBF3.7 150.41,79.35 ; USBF3.7 152.29,79.35 ; 139.15,233.64 USB3R1.19 ; USB3R1.19 137.44,235.36 ; USB3R1.19 140.87,235.36 ; USB3R1.19 139.15,237.07 ; SLOT2.B49 17.05,148.55 ; SLOT2.B49 16.15,147.65 ; SLOT2.B49 15.25,148.55 ; SLOT2.B49 16.15,149.45 ; SLOT2.A12 20.65,186.45 ; SLOT2.A12 20.65,184.65 ; SLOT2.A12 19.75,185.55 ; SLOT2.A12 21.55,185.55 ; SLOT2.B43 16.15,155.45 ; SLOT2.B43 16.15,153.65 ; SLOT2.B43 17.05,154.55 ; SLOT2.B43 15.25,154.55 ; 52.04,86.15 DIMM2.239 ; DIMM2.239 52.04,87.96 ; DIMM2.239 52.94,87.05 ; DIMM2.239 51.14,87.05 ; SLOT2.B47 16.15,151.45 ; SLOT2.B47 16.15,149.65 ; SLOT2.B47 17.05,150.55 ; SLOT2.B47 15.25,150.55 ; H4.7 196.84,212.4 ; H4.7 196.84,210.83 ; H4.7 197.63,211.61 ; H2.8 196.24,9.21 ; H2.8 194.67,9.21 ; H2.8 195.46,10 ; DIMM2.235 56.04,87.96 ; DIMM2.235 55.14,87.05 ; DIMM2.235 56.94,87.05 ; DIMM2.134 161.94,88.95 ; DIMM2.134 161.04,88.05 ; DIMM2.134 160.14,88.95 ; DIMM2.134 161.04,89.86 ; TC10.2 133.41,182.73 ; TC10.2 131.3,182.73 ; TC10.2 132.36,181.67 ; TC10.2 132.36,183.78 ; SLOT2.A41 18.65,157.45 ; SLOT2.A41 19.55,156.55 ; SLOT2.A41 17.75,156.55 ; SLOT2.A41 18.65,155.65 ; 18.65,181.65 SLOT2.A15 ; SLOT2.A15 18.65,183.45 ; SLOT2.A15 17.75,182.55 ; SLOT2.A15 19.55,182.55 ; 15.25,172.55 SLOT2.B25 ; SLOT2.B25 16.15,173.45 ; SLOT2.B25 16.15,171.65 ; SLOT2.B25 17.05,172.55 ; 124.17,73.84 TC42.2 ; TC42.2 125.22,72.78 ; TC42.2 125.22,74.89 ; TC42.2 126.28,73.84 ; 99.29,76.88 SATA0.4 99.29,75.05 ; 88.14,88.95 DIMM2.202 ; SLOT1.A12 41.85,185.55 ; SLOT1.A12 40.95,184.65 ; SLOT1.A12 40.05,185.55 ; SLOT1.A12 40.95,186.45 ; DIMM2.121 174.94,87.05 ; DIMM2.121 173.14,87.05 ; DIMM2.121 174.04,87.96 ; DIMM2.121 174.04,86.15 ; 37.59,3.32 H3.5 36.02,3.32 ; VGA1.6 75.84,239.52 ; VGA1.6 73.68,239.52 ; VGA1.6 74.76,240.6 ; VGA1.6 74.76,238.44 ; 152.04,89.95 DIMM2.23 151.14,90.85 ; DIMM2.205 86.94,87.05 ; DIMM2.205 86.04,86.15 ; DIMM2.205 86.04,87.96 ; 20.65,178.65 SLOT2.A18 ; SLOT2.A18 20.65,180.45 ; SLOT2.A18 19.75,179.55 ; SLOT2.A18 21.55,179.55 ; 75.28,75.96 SATA1.7 ; SATA1.7 76.19,75.05 ; SATA1.7 76.19,76.88 ; 193.5,75.71 H5.5 ; H5.5 195.07,75.71 ; H5.5 194.28,74.92 ; SLOT2.A24 21.55,173.55 ; SLOT2.A24 19.75,173.55 ; SLOT2.A24 20.65,172.65 ; SLOT2.A24 20.65,174.45 ; 16.15,123.65 SLOT2.B73 ; SLOT2.B73 16.15,125.45 ; SLOT2.B73 17.05,124.55 ; SLOT2.B73 15.25,124.55 ; DIMM2.47 128.04,91.76 ; DIMM2.47 128.94,90.85 ; DIMM2.47 128.04,89.95 ; SLOT2.A62 20.65,136.45 ; SLOT2.A62 19.75,135.55 ; SLOT2.A62 20.65,134.65 ; SLOT2.A62 21.55,135.55 ; 133.14,90.85 DIMM2.41 134.04,89.95 ; SLOT2.B61 16.15,137.45 ; SLOT2.B61 17.05,136.55 ; SLOT2.B61 15.25,136.55 ; SLOT2.B61 16.15,135.65 ; 190.16,212.79 H4.2 ; H4.2 190.95,213.57 ; H4.2 190.95,212 ; USBF1.8 176.92,79.74 ; USBF1.8 176.92,77.6 ; USBF1.8 175.85,78.67 ; USBF1.8 177.99,78.67 ; H6.1 35.54,82.88 ; H6.1 34.75,82.09 ; H6.1 36.32,82.09 ; 196.35,76.31 H5.6 ; H5.6 197.14,77.09 ; H5.6 196.35,77.88 ; 80.04,86.15 DIMM2.211 ; DIMM2.211 79.14,87.05 ; DIMM2.211 80.94,87.05 ; 146.05,229.37 USBCN1.8 ; USBCN1.8 147.08,230.4 ; USBCN1.8 148.11,229.37 ; USBCN1.8 147.08,228.34 ; 17.75,160.55 SLOT2.A37 ; SLOT2.A37 19.55,160.55 ; SLOT2.A37 18.65,161.45 ; SLOT2.A37 18.65,159.65 ; SLOT2.B39 17.05,158.55 ; SLOT2.B39 15.25,158.55 ; SLOT2.B39 16.15,159.45 ; SLOT2.B39 16.15,157.65 ; 68.94,87.05 DIMM2.223 68.04,86.15 ; H6.8 38.76,81.6 ; H6.8 37.19,81.6 ; H6.8 37.98,82.39 ; H3.8 37.98,10 ; H3.8 38.76,9.21 ; H3.8 37.19,9.21 ; H6.6 38.87,77.88 ; H6.6 39.66,77.09 ; H6.6 38.87,76.31 ; HDMI1.23 118.08,242.18 ; HDMI1.23 118.08,238.64 ; HDMI1.23 119.25,240.41 ; HDMI1.23 116.91,240.41 ; 13.25,117.55 SLOT2.B80 ; SLOT2.B80 14.15,116.65 ; SLOT2.B80 15.05,117.55 ; SLOT2.B80 14.15,118.45 ; 63.14,90.85 DIMM2.107 ; SLOT2.B64 14.15,134.45 ; SLOT2.B64 13.25,133.55 ; SLOT2.B64 15.05,133.55 ; SLOT2.B64 14.15,132.65 ; 165.04,88.05 DIMM2.130 ; SLOT2.A75 19.55,122.55 ; SLOT2.A75 18.65,121.65 ; SLOT2.A75 17.75,122.55 ; SLOT2.A75 18.65,123.45 ; 54.04,89.95 DIMM2.117 53.14,90.85 ; 193.5,3.32 H2.5 ; H2.5 195.07,3.32 ; H2.5 194.28,2.53 ; 157.15,232.99 USBCN1.9 ; USBCN1.9 158.87,234.7 ; USBCN1.9 157.15,236.42 ; USBCN1.9 155.44,234.7 ; SLOT2.A42 20.65,156.45 ; SLOT2.A42 21.55,155.55 ; SLOT2.A42 20.65,154.65 ; SLOT2.A42 19.75,155.55 ; 154.46,71.22 USBF2.7 ; USBF2.7 154.46,73.36 ; USBF2.7 155.53,72.29 ; USBF2.7 153.39,72.29 ; 130.14,100.65 DIMM1.44 ; DIMM1.44 131.94,100.65 ; DIMM1.44 131.04,99.75 ; H4.5 195.07,207.79 ; H4.5 194.28,207 ; H4.5 193.5,207.79 ; 144.01,232.99 USBCN1.10 ; USBCN1.10 145.73,234.7 ; USBCN1.10 144.01,236.42 ; USBCN1.10 142.3,234.7 ; 180.16,195.56 TC40.2 ; TC40.2 179.11,196.62 ; TC40.2 180.16,197.67 ; TC40.2 181.22,196.62 ; 140.04,89.95 DIMM2.35 140.94,90.85 ; 187.03,57.78 ATX1.15 ; ATX1.15 188.45,56.36 ; ATX1.15 189.87,57.78 ; ATX1.15 188.45,59.2 ; H5.8 196.24,81.6 ; H5.8 195.46,82.39 ; H5.8 194.67,81.6 ; DIMM2.203 88.04,87.96 ; DIMM2.203 87.14,87.05 ; DIMM2.203 88.04,86.15 ; 196.84,78.75 H5.7 ; H5.7 197.63,79.53 ; H5.7 196.84,80.32 ; 88.04,94.05 DIMM1.203 ; USB3R1.22 127.73,229.68 ; USB3R1.22 126.01,231.4 ; USB3R1.22 126.01,227.97 ; USB3R1.22 124.3,229.68 ; DIMM2.161 134.94,87.05 ; DIMM2.161 134.04,86.15 ; DIMM2.161 133.14,87.05 ; DIMM2.161 134.04,87.96 ; H3.7 40.15,7.14 ; H3.7 39.36,6.36 ; H3.7 39.36,7.93 ; VGA1.17 92.73,241.6 ; VGA1.17 90.64,239.52 ; VGA1.17 94.81,239.52 ; VGA1.17 92.73,237.44 ; USBF2.8 155.53,69.75 ; USBF2.8 154.46,70.82 ; USBF2.8 153.39,69.75 ; USBF2.8 154.46,68.68 ; DIMM2.139 156.94,87.05 ; DIMM2.139 156.04,87.96 ; DIMM2.139 156.04,86.15 ; DIMM2.139 155.14,87.05 ; SLOT1.B13 36.45,185.45 ; SLOT1.B13 37.35,184.55 ; SLOT1.B13 35.55,184.55 ; SLOT1.B13 36.45,183.65 ; 92.8,74.21 SATA0.8 ; SATA0.8 92.8,76.71 ; SATA0.8 91.56,75.46 ; SATA0.8 94.05,75.46 ; VGA1.7 77.05,240.6 ; VGA1.7 78.13,239.52 ; VGA1.7 77.05,238.44 ; VGA1.7 75.97,239.52 ; 103.58,238.64 HDMI1.22 ; HDMI1.22 104.75,240.41 ; HDMI1.22 102.41,240.41 ; HDMI1.22 103.58,242.18 ; H7.1 61.66,145.97 ; H7.1 59.74,144.05 ; H7.1 61.66,142.13 ; H7.1 63.58,144.05 ; H3.1 36.32,9.7 ; H3.1 34.75,9.7 ; H3.1 35.54,10.49 ; 149.04,91.85 DIMM2.26 ; DIMM2.220 71.94,88.95 ; 32.98,5.09 H3.3 ; H3.3 32.19,5.88 ; H3.3 32.98,6.66 ; DIMM2.226 65.94,88.95 ; 102.41,234.45 HDMI1.20 ; HDMI1.20 103.58,232.38 ; HDMI1.20 103.58,236.52 ; HDMI1.20 104.75,234.45 ; 105.77,74.21 SATA0.9 ; SATA0.9 105.77,76.71 ; SATA0.9 104.52,75.46 ; SATA0.9 107.01,75.46 ; UTC7.2 142.88,222.16 ; UTC7.2 142.88,220.05 ; UTC7.2 143.93,221.11 ; UTC7.2 141.82,221.11 ; SLOT2.B52 14.15,146.45 ; SLOT2.B52 13.25,145.55 ; SLOT2.B52 14.15,144.65 ; SLOT2.B52 15.05,145.55 ; H4.6 197.14,209.17 ; H4.6 196.35,208.39 ; H4.6 196.35,209.96 ; TC9.2 112.62,206.41 ; TC9.2 113.68,205.36 ; TC9.2 111.57,205.36 ; TC9.2 112.62,204.3 ; 146.04,89.95 DIMM2.29 ; 16,4.28 LPC1.12 ; 124.53,181.76 TC3.2 ; TC3.2 123.48,182.82 ; TC3.2 124.53,183.87 ; TC3.2 125.59,182.82 ; 170.04,94.05 DIMM1.125 ; 190.46,77.48 H5.3 ; H5.3 189.67,78.27 ; H5.3 190.46,79.05 ; 83.04,88.05 DIMM2.208 ; DIMM1.160 135.94,96.85
  BOTTOM w0.508: v1(14.1,208.15) 13.8,207.86 R110.1
  BOTTOM w0.635: 126.31,108.04 TC45.2 ; TC45.2 125.26,109.09 ; TC45.2 127.37,109.09 ; TC45.2 126.31,110.15 ; 62.04,94.05 DIMM1.229 ; DIMM1.229 62.94,94.95 ; DIMM1.229 61.14,94.95 ; DIMM1.229 62.04,95.86 ; DIMM2.107 64.04,91.76 ; DIMM2.107 64.04,89.95 ; DIMM2.107 64.94,90.85 ; DIMM2.107 63.14,90.85 ; DIMM1.23 152.04,99.66 ; DIMM1.23 151.14,98.75 ; DIMM1.23 152.04,97.85 ; DIMM1.23 152.94,98.75 ; 59.04,88.05 DIMM2.232 ; DIMM2.232 59.04,89.86 ; DIMM2.232 58.14,88.95 ; DIMM2.232 59.94,88.95 ; 116.91,240.41 HDMI1.23 ; HDMI1.23 118.08,238.64 ; HDMI1.23 118.08,242.18 ; HDMI1.23 119.25,240.41 ; USB3R1.22 127.73,229.68 ; USB3R1.22 126.01,227.97 ; USB3R1.22 124.3,229.68 ; USB3R1.22 126.01,231.4 ; 89.04,88.05 DIMM2.202 ; DIMM2.202 89.94,88.95 ; DIMM2.202 88.14,88.95 ; DIMM2.202 89.04,89.86 ; SATA0.9 105.77,76.71 ; SATA0.9 104.52,75.46 ; SATA0.9 105.77,74.21 ; 161.14,94.95 DIMM1.133 ; DIMM1.133 162.04,94.05 ; DIMM1.133 162.04,95.86 ; DIMM1.133 162.94,94.95 ; 58.04,89.95 DIMM2.113 ; DIMM2.113 57.14,90.85 ; DIMM2.113 58.04,91.76 ; DIMM2.113 58.94,90.85 ; 150.04,86.15 DIMM2.145 ; DIMM2.145 150.04,87.96 ; DIMM2.145 149.14,87.05 ; DIMM2.145 150.94,87.05 ; 73.04,91.85 DIMM2.98 ; DIMM2.98 72.14,92.75 ; DIMM2.98 73.04,93.66 ; DIMM2.98 73.94,92.75 ; DIMM1.151 144.04,95.86 ; DIMM1.151 144.94,94.95 ; DIMM1.151 143.14,94.95 ; DIMM1.151 144.04,94.05 ; 155.44,229.02 USBCN1.11 ; USBCN1.11 158.87,229.02 ; USBCN1.11 157.15,230.74 ; USBCN1.11 157.15,227.31 ; DIMM1.199 92.94,94.95 ; DIMM1.199 92.04,94.05 ; DIMM1.199 92.04,95.86 ; DIMM1.199 91.14,94.95 ; RJ45.G3 165.28,228.94 ; RJ45.G3 163.56,227.23 ; RJ45.G3 163.56,230.66 ; RJ45.G3 161.85,228.94 ; DIMM1.8 167.04,101.56 ; DIMM1.8 167.94,100.65 ; DIMM1.8 166.14,100.65 ; DIMM1.8 167.04,99.75 ; DIMM1.125 170.04,95.86 ; DIMM1.125 170.94,94.95 ; DIMM1.125 169.14,94.95 ; DIMM1.125 170.04,94.05 ; 70.04,97.85 DIMM1.101 ; DIMM1.101 70.94,98.75 ; DIMM1.101 69.14,98.75 ; DIMM1.101 70.04,99.66 ; DIMM1.95 76.04,99.66 ; DIMM1.95 75.14,98.75 ; DIMM1.95 76.94,98.75 ; DIMM1.95 76.04,97.85 ; DIMM1.117 54.94,98.75 ; DIMM1.117 54.04,97.85 ; DIMM1.117 54.04,99.66 ; DIMM1.117 53.14,98.75 ; 156.04,86.15 DIMM2.139 ; DIMM2.139 155.14,87.05 ; DIMM2.139 156.94,87.05 ; DIMM2.139 156.04,87.96 ; 172.14,92.75 DIMM2.2 ; DIMM2.2 173.04,91.85 ; DIMM2.2 173.94,92.75 ; DIMM2.2 173.04,93.66 ; 140.14,96.85 DIMM1.154 ; DIMM1.154 141.04,95.95 ; DIMM1.154 141.94,96.85 ; DIMM1.154 141.04,97.76 ; 58.14,96.85 DIMM1.232 ; DIMM1.232 59.04,97.76 ; DIMM1.232 59.04,95.95 ; DIMM1.232 59.94,96.85 ; 134.04,94.05 DIMM1.161 ; DIMM1.161 133.14,94.95 ; DIMM1.161 134.04,95.86 ; DIMM1.161 134.94,94.95 ; 78.14,100.65 DIMM1.92 ; DIMM1.92 79.04,99.75 ; DIMM1.92 79.94,100.65 ; DIMM1.92 79.04,101.56 ; DIMM1.143 152.04,95.86 ; DIMM1.143 152.94,94.95 ; DIMM1.143 152.04,94.05 ; DIMM1.143 151.14,94.95 ; 84.14,92.75 DIMM2.86 ; DIMM2.86 85.04,91.85 ; DIMM2.86 85.94,92.75 ; DIMM2.86 85.04,93.66 ; 79.14,94.95 DIMM1.211 ; DIMM1.211 80.04,95.86 ; DIMM1.211 80.04,94.05 ; DIMM1.211 80.94,94.95 ; 85.14,94.95 DIMM1.205 ; DIMM1.205 86.94,94.95 ; DIMM1.205 86.04,95.86 ; DIMM1.205 86.04,94.05 ; DIMM1.217 74.04,95.86 ; DIMM1.217 74.94,94.95 ; DIMM1.217 74.04,94.05 ; DIMM1.217 73.14,94.95 ; 165.6,231.91 RJ45.U4 ; RJ45.U4 166.63,230.88 ; RJ45.U4 167.66,231.91 ; RJ45.U4 166.63,232.94 ; 88.04,97.85 DIMM1.83 ; DIMM1.83 88.04,99.66 ; DIMM1.83 88.94,98.75 ; DIMM1.83 87.14,98.75 ; 64.14,88.95 DIMM2.226 ; DIMM2.226 65.94,88.95 ; DIMM2.226 65.04,88.05 ; DIMM2.226 65.04,89.86 ; USBF3.13 154.29,77.35 ; USBF3.13 153.35,76.41 ; USBF3.13 153.35,78.29 ; 167.04,91.85 DIMM2.8 ; DIMM2.8 167.94,92.75 ; DIMM2.8 166.14,92.75 ; DIMM2.8 167.04,93.66 ; 165.04,88.05 DIMM2.130 ; DIMM2.130 164.14,88.95 ; DIMM2.130 165.04,89.86 ; DIMM2.130 165.94,88.95 ; 89.04,95.95 DIMM1.202 ; DIMM1.202 88.14,96.85 ; DIMM1.202 89.04,97.76 ; DIMM1.202 89.94,96.85 ; 73.52,74.21 SATA1.9 ; SATA1.9 74.77,75.46 ; SATA1.9 72.27,75.46 ; SATA1.9 73.52,76.71 ; 83.04,88.05 DIMM2.208 ; DIMM2.208 83.94,88.95 ; DIMM2.208 82.14,88.95 ; DIMM2.208 83.04,89.86 ; 85.14,87.05 DIMM2.205 ; DIMM2.205 86.94,87.05 ; DIMM2.205 86.04,87.96 ; DIMM2.205 86.04,86.15 ; DIMM2.80 91.94,92.75 ; DIMM2.80 91.04,91.85 ; DIMM2.80 90.14,92.75 ; DIMM2.80 91.04,93.66 ; 77.04,95.95 DIMM1.214 ; DIMM1.214 77.94,96.85 ; DIMM1.214 77.04,97.76 ; DIMM1.214 76.14,96.85 ; DIMM2.166 129.04,89.86 ; DIMM2.166 129.94,88.95 ; DIMM2.166 129.04,88.05 ; DIMM2.166 128.14,88.95 ; 52.04,95.86 DIMM1.239 52.94,94.95 ; USBCN1.12 145.73,229.02 ; USBCN1.12 144.01,230.74 ; USBCN1.12 144.01,227.31 ; DIMM2.217 74.04,87.96 ; DIMM2.217 73.14,87.05 ; DIMM2.217 74.94,87.05 ; DIMM2.217 74.04,86.15 ; 77.04,88.05 DIMM2.214 ; DIMM2.214 76.14,88.95 ; DIMM2.214 77.94,88.95 ; DIMM2.214 77.04,89.86 ; 130.14,92.75 DIMM2.44 ; DIMM2.44 131.94,92.75 ; DIMM2.44 131.04,91.85 ; DIMM2.44 131.04,93.66 ; 62.04,86.15 DIMM2.229 ; DIMM2.229 62.94,87.05 ; DIMM2.229 61.14,87.05 ; DIMM2.229 62.04,87.96 ; 134.14,96.85 DIMM1.160 ; DIMM1.160 135.04,95.95 ; DIMM1.160 135.94,96.85 ; DIMM1.160 135.04,97.76 ; 75.14,90.85 DIMM2.95 ; DIMM2.95 76.04,91.76 ; DIMM2.95 76.04,89.95 ; DIMM2.95 76.94,90.85 ; 134.14,88.95 DIMM2.160 ; DIMM2.160 135.94,88.95 ; DIMM2.160 135.04,89.86 ; DIMM2.160 135.04,88.05 ; VGA1.16 67.73,241.6 ; VGA1.16 67.73,237.44 ; VGA1.16 69.82,239.52 ; VGA1.16 65.65,239.52 ; DIMM2.136 159.04,89.86 ; DIMM2.136 159.04,88.05 ; DIMM2.136 158.14,88.95 ; DIMM2.136 159.94,88.95 ; 163.14,98.75 DIMM1.11 ; DIMM1.11 164.04,97.85 ; DIMM1.11 164.94,98.75 ; DIMM1.11 164.04,99.66 ; 54.04,91.76 DIMM2.117 54.94,90.85 ; 165.04,95.95 DIMM1.130 ; DIMM1.130 165.04,97.76 ; DIMM1.130 165.94,96.85 ; DIMM1.130 164.14,96.85 ; DIMM1.212 79.04,97.76 ; DIMM1.212 79.04,95.95 ; DIMM1.212 78.14,96.85 ; DIMM1.212 79.94,96.85 ; 91.04,99.75 DIMM1.80 ; DIMM1.80 90.14,100.65 ; DIMM1.80 91.04,101.56 ; DIMM1.80 91.94,100.65 ; 140.04,97.85 DIMM1.35 ; DIMM1.35 140.04,99.66 ; DIMM1.35 139.14,98.75 ; DIMM1.35 140.94,98.75 ; DIMM2.221 70.94,87.05 ; DIMM2.221 70.04,87.96 ; DIMM2.221 69.14,87.05 ; DIMM2.221 70.04,86.15 ; 155.44,234.7 USBCN1.9 ; USBCN1.9 157.15,236.42 ; USBCN1.9 157.15,232.99 ; USBCN1.9 158.87,234.7 ; 160.14,100.65 DIMM1.14 ; DIMM1.14 161.94,100.65 ; DIMM1.14 161.04,101.56 ; DIMM1.14 161.04,99.75 ; DIMM1.89 82.04,99.66 ; DIMM1.89 82.94,98.75 ; DIMM1.89 81.14,98.75 ; DIMM1.89 82.04,97.85 ; DIMM1.113 58.94,98.75 ; DIMM1.113 58.04,99.66 ; DIMM1.113 58.04,97.85 ; DIMM1.113 57.14,98.75 ; 65.04,95.95 DIMM1.226 ; DIMM1.226 65.04,97.76 ; DIMM1.226 64.14,96.85 ; DIMM1.226 65.94,96.85 ; 143.14,87.05 DIMM2.151 ; DIMM2.151 144.94,87.05 ; DIMM2.151 144.04,87.96 ; DIMM2.151 144.04,86.15 ; 159.07,224.57 RJ45.G1 160.78,226.29 ; 137.14,94.95 DIMM1.157 ; DIMM1.157 138.94,94.95 ; DIMM1.157 138.04,95.86 ; DIMM1.157 138.04,94.05 ; SATA1.8 87.73,75.46 ; SATA1.8 86.48,76.71 ; SATA1.8 86.48,74.21 ; SATA1.8 85.24,75.46 ; 160.78,235.53 RJ45.G7 ; RJ45.G7 159.07,237.25 ; RJ45.G7 162.5,237.25 ; RJ45.G7 160.78,238.96 ; 163.56,232.91 RJ45.G5 ; RJ45.G5 163.56,236.34 ; RJ45.G5 161.85,234.62 ; RJ45.G5 165.28,234.62 ; DIMM2.116 55.94,92.75 ; DIMM2.116 55.04,91.85 ; DIMM2.116 55.04,93.66 ; DIMM2.116 54.14,92.75 ; DIMM1.142 153.04,97.76 ; DIMM1.142 153.94,96.85 ; DIMM1.142 153.04,95.95 ; DIMM1.142 152.14,96.85 ; DIMM1.235 56.94,94.95 ; DIMM1.235 56.04,95.86 ; DIMM1.235 56.04,94.05 ; DIMM1.235 55.14,94.95 ; 164.04,89.95 DIMM2.11 ; DIMM2.11 163.14,90.85 ; DIMM2.11 164.04,91.76 ; DIMM2.11 164.94,90.85 ; DIMM2.32 143.04,93.66 ; DIMM2.32 142.14,92.75 ; DIMM2.32 143.94,92.75 ; DIMM2.32 143.04,91.85 ; DIMM2.230 61.04,89.86 ; DIMM2.230 61.04,88.05 ; DIMM2.230 60.14,88.95 ; DIMM2.230 61.94,88.95 ; DIMM1.5 170.04,99.66 ; DIMM1.5 170.04,97.85 ; DIMM1.5 169.14,98.75 ; DIMM1.5 170.94,98.75 ; USBCN1.10 145.73,234.7 ; USBCN1.10 144.01,236.42 ; USBCN1.10 142.3,234.7 ; USBCN1.10 144.01,232.99 ; 132.58,227.77 USB3R1.16 132.58,229.55 ; 61.04,91.85 DIMM2.110 ; DIMM2.110 61.94,92.75 ; DIMM2.110 60.14,92.75 ; DIMM2.110 61.04,93.66 ; 146.14,88.95 DIMM2.148 ; DIMM2.148 147.04,88.05 ; DIMM2.148 147.94,88.95 ; DIMM2.148 147.04,89.86 ; 147.04,95.95 DIMM1.148 ; DIMM1.148 146.14,96.85 ; DIMM1.148 147.04,97.76 ; DIMM1.148 147.94,96.85 ; DIMM2.29 146.94,90.85 ; DIMM2.29 145.14,90.85 ; DIMM2.29 146.04,89.95 ; DIMM2.29 146.04,91.76 ; DIMM2.143 152.04,87.96 ; DIMM2.143 152.94,87.05 ; DIMM2.143 152.04,86.15 ; DIMM2.143 151.14,87.05 ; 13.01,5.27 LPC1.14 14,4.28 ; 87.14,94.95 DIMM1.203 ; DIMM1.203 88.94,94.95 ; DIMM1.203 88.04,95.86 ; DIMM1.203 88.04,94.05 ; DIMM2.154 141.04,89.86 ; DIMM2.154 141.04,88.05 ; DIMM2.154 141.94,88.95 ; DIMM2.154 140.14,88.95 ; 127.14,90.85 DIMM2.47 ; DIMM2.47 128.04,89.95 ; DIMM2.47 128.04,91.76 ; DIMM2.47 128.94,90.85 ; 171.04,95.95 DIMM1.124 ; DIMM1.124 171.04,97.76 ; DIMM1.124 170.14,96.85 ; DIMM1.124 171.94,96.85 ; 171.04,88.05 DIMM2.124 ; DIMM2.124 171.04,89.86 ; DIMM2.124 171.94,88.95 ; DIMM2.124 170.14,88.95 ; DIMM2.38 137.04,93.66 ; DIMM2.38 136.14,92.75 ; DIMM2.38 137.94,92.75 ; DIMM2.38 137.04,91.85 ; DIMM2.199 92.94,87.05 ; DIMM2.199 92.04,87.96 ; DIMM2.199 92.04,86.15 ; DIMM2.199 91.14,87.05 ; DIMM2.23 152.04,91.76 ; DIMM2.23 151.14,90.85 ; DIMM2.23 152.94,90.85 ; DIMM2.23 152.04,89.95 ; 134.04,97.85 DIMM1.41 ; DIMM1.41 134.04,99.66 ; DIMM1.41 133.14,98.75 ; DIMM1.41 134.94,98.75 ; DIMM2.20 155.94,92.75 ; DIMM2.20 155.04,93.66 ; DIMM2.20 154.14,92.75 ; DIMM2.20 155.04,91.85 ; 150.41,79.35 USBF3.7 ; USBF3.7 152.29,79.35 ; USBF3.7 151.35,80.29 ; DIMM1.32 143.04,101.56 ; DIMM1.32 143.04,99.75 ; DIMM1.32 143.94,100.65 ; DIMM1.32 142.14,100.65 ; 72.14,100.65 DIMM1.98 ; DIMM1.98 73.04,101.56 ; DIMM1.98 73.04,99.75 ; DIMM1.98 73.94,100.65 ; DIMM2.220 71.94,88.95 ; DIMM2.220 71.04,88.05 ; DIMM2.220 71.04,89.86 ; DIMM2.220 70.14,88.95 ; USB3R1.4 129.97,233.36 ; USB3R1.4 129.08,234.25 ; USB3R1.4 128.19,233.36 ; 133.14,87.05 DIMM2.161 ; DIMM2.161 134.04,87.96 ; DIMM2.161 134.94,87.05 ; DIMM2.161 134.04,86.15 ; 67.14,94.95 DIMM1.223 ; DIMM1.223 68.94,94.95 ; DIMM1.223 68.04,95.86 ; DIMM1.223 68.04,94.05 ; DIMM1.2 173.04,101.56 ; DIMM1.2 172.14,100.65 ; DIMM1.2 173.94,100.65 ; DIMM1.2 173.04,99.75 ; HDMI1.20 104.75,234.45 ; HDMI1.20 103.58,232.38 ; HDMI1.20 102.41,234.45 ; HDMI1.20 103.58,236.52 ; 137.04,99.75 DIMM1.38 ; DIMM1.38 137.04,101.56 ; DIMM1.38 137.94,100.65 ; DIMM1.38 136.14,100.65 ; DIMM2.89 82.04,91.76 ; DIMM2.89 82.04,89.95 ; DIMM2.89 81.14,90.85 ; DIMM2.89 82.94,90.85 ; 82.14,96.85 DIMM1.208 ; DIMM1.208 83.04,95.95 ; DIMM1.208 83.04,97.76 ; DIMM1.208 83.94,96.85 ; DIMM1.121 174.04,95.86 ; DIMM1.121 173.14,94.95 ; DIMM1.121 174.94,94.95 ; DIMM1.121 174.04,94.05 ; HDMI1.21 119.25,234.45 ; HDMI1.21 116.91,234.45 ; HDMI1.21 118.08,232.38 ; HDMI1.21 118.08,236.52 ; 161.04,88.05 DIMM2.134 ; DIMM2.134 161.04,89.86 ; DIMM2.134 160.14,88.95 ; DIMM2.134 161.94,88.95 ; 149.04,99.75 DIMM1.26 ; DIMM1.26 149.04,101.56 ; DIMM1.26 148.14,100.65 ; DIMM1.26 149.94,100.65 ; 149.04,91.85 DIMM2.26 ; DIMM2.26 149.04,93.66 ; DIMM2.26 149.94,92.75 ; DIMM2.26 148.14,92.75 ; DIMM2.223 68.94,87.05 ; DIMM2.223 68.04,86.15 ; DIMM2.223 68.04,87.96 ; DIMM2.223 67.14,87.05 ; DIMM1.29 146.94,98.75 ; DIMM1.29 146.04,97.85 ; DIMM1.29 145.14,98.75 ; DIMM1.29 146.04,99.66 ; 66.14,100.65 DIMM1.104 ; DIMM1.104 67.94,100.65 ; DIMM1.104 67.04,99.75 ; DIMM1.104 67.04,101.56 ; DIMM1.230 61.04,97.76 ; DIMM1.230 60.14,96.85 ; DIMM1.230 61.94,96.85 ; DIMM1.230 61.04,95.95 ; 87.14,90.85 DIMM2.83 ; DIMM2.83 88.04,91.76 ; DIMM2.83 88.94,90.85 ; DIMM2.83 88.04,89.95 ; DIMM1.119 52.94,98.75 ; DIMM1.119 52.04,99.66 ; DIMM1.119 52.04,97.85 ; RJ45.G8 181.19,237.25 ; RJ45.G8 179.48,238.96 ; RJ45.G8 177.76,237.25 ; 137.14,87.05 DIMM2.157 ; DIMM2.157 138.94,87.05 ; DIMM2.157 138.04,87.96 ; DIMM2.157 138.04,86.15 ; DIMM2.17 158.94,90.85 ; DIMM2.17 157.14,90.85 ; DIMM2.17 158.04,91.76 ; DIMM2.17 158.04,89.95 ; VGA1.8 79.34,240.6 ; VGA1.8 79.34,238.44 ; VGA1.8 78.26,239.52 ; 86.14,237.52 VGA1.5 85.06,236.44 ; 156.04,94.05 DIMM1.139 ; DIMM1.139 156.04,95.86 ; DIMM1.139 156.94,94.95 ; DIMM1.139 155.14,94.95 ; 161.04,91.85 DIMM2.14 ; DIMM2.14 161.04,93.66 ; DIMM2.14 161.94,92.75 ; DIMM2.14 160.14,92.75 ; 132.04,86.15 DIMM2.163 ; DIMM2.163 132.94,87.05 ; DIMM2.163 132.04,87.96 ; DIMM2.163 131.14,87.05 ; 139.15,233.64 USB3R1.19 ; USB3R1.19 137.44,235.36 ; USB3R1.19 140.87,235.36 ; USB3R1.19 139.15,237.07 ; USBCN1.8 147.08,230.4 ; USBCN1.8 146.05,229.37 ; USBCN1.8 147.08,228.34 ; USBCN1.8 148.11,229.37 ; 174.04,86.15 DIMM2.121 ; DIMM2.121 174.04,87.96 ; DIMM2.121 174.94,87.05 ; DIMM2.121 173.14,87.05 ; 70.14,96.85 DIMM1.220 ; DIMM1.220 71.04,97.76 ; DIMM1.220 71.94,96.85 ; DIMM1.220 71.04,95.95 ; 70.04,94.05 DIMM1.221 ; DIMM1.221 70.04,95.86 ; DIMM1.221 70.94,94.95 ; DIMM1.221 69.14,94.95 ; 95.48,75.05 SATA0.1 ; SATA0.1 94.56,75.96 ; SATA0.1 95.48,76.88 ; DIMM1.136 159.94,96.85 ; DIMM1.136 158.14,96.85 ; DIMM1.136 159.04,95.95 ; DIMM1.136 159.04,97.76 ; 103.1,75.05 SATA0.7 ; SATA0.7 103.1,76.88 ; SATA0.7 104.01,75.96 ; 149.14,94.95 DIMM1.145 ; DIMM1.145 150.04,95.86 ; DIMM1.145 150.94,94.95 ; DIMM1.145 150.04,94.05 ; 142.14,96.85 DIMM1.152 ; DIMM1.152 143.04,95.95 ; DIMM1.152 143.04,97.76 ; DIMM1.152 143.94,96.85 ; 169.14,90.85 DIMM2.5 ; DIMM2.5 170.04,91.76 ; DIMM2.5 170.94,90.85 ; DIMM2.5 170.04,89.95 ; 140.04,89.95 DIMM2.35 ; DIMM2.35 139.14,90.85 ; DIMM2.35 140.04,91.76 ; DIMM2.35 140.94,90.85 ; RJ45.U8 166.63,230.32 ; RJ45.U8 167.66,229.29 ; RJ45.U8 166.63,228.26 ; RJ45.U8 165.6,229.29 ; 127.14,98.75 DIMM1.47 ; DIMM1.47 128.04,99.66 ; DIMM1.47 128.04,97.85 ; DIMM1.47 128.94,98.75 ; 146.05,231.99 USBCN1.4 ; USBCN1.4 147.08,230.96 ; USBCN1.4 147.08,233.02 ; USBCN1.4 148.11,231.99 ; 158.04,97.85 DIMM1.17 ; DIMM1.17 157.14,98.75 ; DIMM1.17 158.04,99.66 ; DIMM1.17 158.94,98.75 ; DIMM1.116 55.94,100.65 ; DIMM1.116 55.04,99.75 ; DIMM1.116 55.04,101.56 ; DIMM1.116 54.14,100.65 ; 152.14,88.95 DIMM2.142 ; DIMM2.142 153.94,88.95 ; DIMM2.142 153.04,88.05 ; DIMM2.142 153.04,89.86 ; 69.14,90.85 DIMM2.101 ; DIMM2.101 70.94,90.85 ; DIMM2.101 70.04,91.76 ; DIMM2.101 70.04,89.95 ; 155.04,99.75 DIMM1.20 ; DIMM1.20 155.04,101.56 ; DIMM1.20 154.14,100.65 ; DIMM1.20 155.94,100.65 ; DIMM1.134 161.94,96.85 ; DIMM1.134 160.14,96.85 ; DIMM1.134 161.04,95.95 ; DIMM1.134 161.04,97.76 ; TC38.2 185.09,14.29 ; TC38.2 184.04,13.23 ; TC38.2 186.14,13.23 ; TC38.2 185.09,12.18 ; DIMM1.237 54.04,95.86 ; DIMM1.237 54.94,94.95 ; DIMM1.237 54.04,94.05 ; DIMM1.237 53.14,94.95 ; 92.8,74.21 SATA0.8 ; SATA0.8 94.05,75.46 ; SATA0.8 92.8,76.71 ; 63.14,98.75 DIMM1.107 ; DIMM1.107 64.94,98.75 ; DIMM1.107 64.04,97.85 ; DIMM1.107 64.04,99.66 ; DIMM1.110 61.04,101.56 ; DIMM1.110 61.04,99.75 ; DIMM1.110 61.94,100.65 ; DIMM1.110 60.14,100.65 ; DIMM2.104 67.94,92.75 ; DIMM2.104 67.04,91.85 ; DIMM2.104 66.14,92.75 ; DIMM2.104 67.04,93.66 ; 194.45,113.12 FNCPU1.1 194.45,115.38 ; UTC6.2 156.21,224.07 ; UTC6.2 157.26,223.01 ; UTC6.2 155.16,223.01 ; 77.05,238.44 VGA1.7 ; VGA1.7 75.97,239.52 ; VGA1.7 78.13,239.52 ; VGA1.7 77.05,240.6 ; USB3R1.20 127.73,235.36 ; USB3R1.20 126.01,237.07 ; USB3R1.20 124.3,235.36 ; USB3R1.20 126.01,233.64 ; DIMM2.125 170.04,87.96 ; DIMM2.125 169.14,87.05 ; DIMM2.125 170.94,87.05 ; VGA1.6 75.84,239.52 ; VGA1.6 74.76,238.44 ; VGA1.6 74.76,240.6 ; VGA1.6 73.68,239.52 ; 131.04,99.75 DIMM1.44 ; DIMM1.44 131.94,100.65 ; DIMM1.44 131.04,101.56 ; DIMM1.44 130.14,100.65 ; 99.29,76.88 SATA0.4 99.29,75.05 ; 83.81,75.05 SATA1.1 ; SATA1.1 84.73,75.96 ; SATA1.1 83.81,76.88 ; DIMM1.166 129.94,96.85 ; DIMM1.166 129.04,97.76 ; DIMM1.166 129.04,95.95 ; DIMM1.166 128.14,96.85 ; 131.14,94.95 DIMM1.163 ; DIMM1.163 132.94,94.95 ; DIMM1.163 132.04,95.86 ; DIMM1.163 132.04,94.05 ; USBF3.4 145.35,80.29 ; USBF3.4 146.29,79.35 ; USBF3.4 144.41,79.35 ; DIMM2.211 80.04,87.96 ; DIMM2.211 80.94,87.05 ; DIMM2.211 79.14,87.05 ; DIMM2.211 80.04,86.15 ; VGA1.17 94.81,239.52 ; VGA1.17 92.73,241.6 ; VGA1.17 90.64,239.52 ; VGA1.17 92.73,237.44 ; 79.04,88.05 DIMM2.212 ; DIMM2.212 79.94,88.95 ; DIMM2.212 78.14,88.95 ; DIMM2.212 79.04,89.86 ; DIMM2.92 79.04,93.66 ; DIMM2.92 79.94,92.75 ; DIMM2.92 78.14,92.75 ; DIMM2.92 79.04,91.85 ; 132.58,230.97 USB3R1.7 132.58,232.75 ; DIMM1.86 85.94,100.65 ; DIMM1.86 84.14,100.65 ; DIMM1.86 85.04,99.75 ; DIMM1.86 85.04,101.56 ; 168.04,94.05 DIMM1.127 ; DIMM1.127 168.94,94.95 ; DIMM1.127 167.14,94.95 ; DIMM1.127 168.04,95.86 ; HDMI1.22 103.58,242.18 ; HDMI1.22 104.75,240.41 ; HDMI1.22 103.58,238.64 ; HDMI1.22 102.41,240.41 ; 147.35,76.41 USBF3.16 147.35,78.29 ; 168.04,86.15 DIMM2.127 ; DIMM2.127 168.94,87.05 ; DIMM2.127 167.14,87.05 ; DIMM2.127 168.04,87.96 ; 75.28,75.96 SATA1.7 ; SATA1.7 76.19,76.88 ; SATA1.7 76.19,75.05 ; UTC5.2 188.21,237.02 ; UTC5.2 189.27,235.97 ; UTC5.2 188.21,234.91 ; 87.14,87.05 DIMM2.203 ; DIMM2.203 88.04,87.96 ; DIMM2.203 88.04,86.15 ; DIMM2.203 88.94,87.05 ; 143.04,88.05 DIMM2.152 ; DIMM2.152 142.14,88.95 ; DIMM2.152 143.94,88.95 ; DIMM2.152 143.04,89.86 ; 80,75.05 SATA1.4 80,76.88 ; 162.04,86.15 DIMM2.133 ; DIMM2.133 162.04,87.96 ; DIMM2.133 161.14,87.05 ; DIMM2.133 162.94,87.05 ; 128.19,230.16 USB3R1.13 129.97,230.16 ; 134.04,89.95 DIMM2.41 ; DIMM2.41 134.94,90.85 ; DIMM2.41 134.04,91.76 ; DIMM2.41 133.14,90.85
  vias: v1(1.27,242.7) v1(2.46,233.96) v1(2.64,6.35) v1(2.72,8.86) v1(2.79,237.24) v1(3.43,235.08) v1(4.57,234.09) v1(5.59,235.2) v1(7.11,242.82) v1(7.14,234.67) v1(7.8,4.62) v1(8.79,234.52) v1(8.86,235.74) v1(8.92,202.69) v1(10.54,234.95) v1(10.92,231.78) v1(11.56,242.7) v1(12.32,237.24) v1(14.05,104.06) v1(14.83,62.3) v1(15.21,102.25) v1(15.3,209.16) v1(15.7,62.26) v1(16.64,62.28) v1(17.53,62.28) v1(18.21,56.24) v1(22.33,165.32) v1(22.73,205.74) v1(23.44,98.53) v1(23.7,101.09) v1(23.82,184.86) v1(23.83,183.72) v1(24.09,164.21) v1(29.06,100.43) v1(29.87,113.61) v1(29.87,103.53) v1(29.96,97.93) v1(30.27,183.78) v1(30.28,182.92) v1(30.35,110.97) v1(30.42,100.18) v1(30.54,181.12) v1(30.5,179.78) v1(30.53,157.9) v1(30.51,151.54) v1(30.66,167.34) v1(30.74,155.08) v1(30.8,143.3) v1(30.86,114.5) v1(31.06,102.06) v1(31.24,127.51) v1(31.29,121.54) v1(31.29,119.48) v1(31.29,117.47) v1(31.42,175.74) v1(31.37,173.48) v1(31.43,169.87) v1(31.37,133.48) v1(31.42,131.42) v1(31.39,129.49) v1(31.42,125.58) v1(31.37,115.91) v1(31.47,177.67) v1(31.5,140.93) v1(31.55,135.25) v1(31.51,123.54) v1(31.62,156.07) v1(31.62,145.49) v1(31.6,143.71) v1(31.78,160.38) v1(32.06,137.64) v1(32.31,159.16) v1(32.42,114.49) v1(32.51,205.74) v1(34.18,92.9) v1(34.67,96.37) v1(34.98,93.78) v1(37.64,204.67) v1(41.61,178.56) v1(41.91,203.33) v1(42.72,180.87) v1(43.81,205.1) v1(43.87,129.54) v1(44.6,198.12) v1(44.6,196.34) v1(45.36,131.25) v1(45.97,203.2) v1(46.86,54.99) v1(46.99,196.72) v1(47.09,131.24) v1(47.35,132.18) v1(48.01,57.15) v1(48.15,131.87) v1(48.9,204.85) v1(48.9,199.26) v1(50.19,106.63) v1(50.55,54.86) v1(51.18,107.82) v1(51.16,57.89) v1(51.51,187.32) v1(51.49,184.71) v1(51.54,50.39) v1(51.47,48.17) v1(51.82,113.28) v1(51.82,111.51) v1(51.82,109.86) v1(52.7,106.93) v1(52.67,56.13) v1(53.34,114.94) v1(53.34,109.09) v1(53.79,49.87) v1(54.1,184.28) v1(54.25,83.95) v1(54.74,116.46) v1(54.66,106.17) v1(54.74,104.27) v1(54.71,102.46) v1(54.81,113.44) v1(54.79,110.77) v1(54.84,108.38) v1(55.09,29.62) v1(55.83,184.56) v1(56.24,117.65) v1(57.89,119.35) v1(58.8,219.58) v1(58.93,85.85) v1(59.49,120.98) v1(60.68,122.2) v1(60.88,199.78) v1(60.88,85.83) v1(61.16,202.38) v1(61.82,123.38) v1(62.61,224.54) v1(62.84,124.39) v1(62.86,202.79) v1(63.07,85.83) v1(63.73,125.28) v1(63.85,204.83) v1(64.14,219.58) v1(64.74,126.3) v1(65.13,85.83) v1(65.13,77.29) v1(65.13,76.43) v1(65.26,150.48) v1(65.63,127.19) v1(66.52,77.24) v1(66.52,76.38) v1(66.65,128.2) v1(66.99,149.61) v1(67.13,85.8) v1(67.7,147.17) v1(67.66,129.22) v1(67.94,77.27) v1(67.94,76.4) v1(68.81,130.36) v1(68.79,66.17) v1(69.09,157.48) v1(69.24,161.32) v1(69.82,131.38) v1(69.98,157.48) v1(70.2,161.3) v1(70.71,67.28) v1(70.94,148.82) v1(70.97,132.52) v1(71.3,65.3) v1(71.91,195.88) v1(71.94,148.75) v1(72.01,146.39) v1(72.14,60.48) v1(72.14,59.56) v1(72.09,57.02) v1(72.17,151.7) v1(72.21,67.06) v1(72.92,134.91) v1(73.14,197.62) v1(73.08,195.91) v1(73.83,150.12) v1(73.81,135.54) v1(73.86,164.26) v1(74.24,147.36) v1(74.28,199.42) v1(74.28,197.61) v1(74.57,136.18) v1(74.93,85.83) v1(75.11,151.75) v1(75.29,148.79) v1(75.33,136.94) v1(75.53,199.33) v1(75.48,197.63) v1(76.22,137.7) v1(76.3,163.68) v1(76.76,199.31) v1(76.76,197.61) v1(76.94,85.83) v1(77.24,138.72) v1(77.52,164.67) v1(78.08,139.5) v1(78.79,140.24) v1(78.99,85.8) v1(79.91,141.26) v1(80.62,185.4) v1(80.67,142.02) v1(80.8,85.7) v1(80.89,168.4) v1(81.04,166.58) v1(82.25,186.99) v1(82.34,184.43) v1(82.42,143.64) v1(82.91,53.67) v1(82.98,85.78) v1(83.03,55.27) v1(83.39,144.61) v1(83.52,186.2) v1(83.66,187.86) v1(84,170.2) v1(84.33,145.57) v1(84.78,168.26) v1(84.84,54.71) v1(85.12,85.78) v1(85.18,173.35) v1(85.38,187.64) v1(85.37,146.59) v1(85.47,57.1) v1(86.18,147.45) v1(86.55,189.47) v1(86.89,199.75) v1(86.87,197.36) v1(86.9,196.49) v1(87.1,85.78) v1(87.15,170.51) v1(88.14,81.28) v1(89.03,85.78) v1(89.03,80.39) v1(89.06,81.28) v1(89.71,172.92) v1(90.81,85.78) v1(92.05,163.17) v1(92.05,174.44) v1(92.91,175.31) v1(93.19,160.13) v1(93.37,176.63) v1(93.8,161.42) v1(93.88,231.65) v1(94.26,236.96) v1(95.55,175.54) v1(96.55,148.49) v1(97.26,240.41) v1(99.8,51.1) v1(100.68,159.1) v1(100.72,157.3) v1(101.07,217.23) v1(101.6,158.19) v1(101.6,157.27) v1(101.88,51) v1(102.51,156.36) v1(102.51,155.44) v1(103.43,156.36) v1(107.08,158.19) v1(108.91,160.02) v1(108.91,159.1) v1(111.66,160.02) v1(112.59,160) v1(114.4,162.75) v1(114.4,161.84) v1(114.4,160.02) v1(116.23,163.67) v1(117.13,167.33) v1(117.14,165.51) v1(117.14,164.59) v1(120.64,129.49) v1(120.61,127.19) v1(121.31,228.35) v1(121.29,121.31) v1(122.17,127.15) v1(123.04,134.41) v1(123.11,128.12) v1(123.98,127.24) v1(125.48,213.89) v1(125.71,133.5) v1(126.06,47.47) v1(126.09,46.61) v1(126.95,47.29) v1(126.95,46.43) v1(127.35,153.55) v1(127.48,151.82) v1(127.48,150.93) v1(127.48,149.94) v1(128.49,156.36) v1(128.49,155.44) v1(128.47,150.86) v1(128.73,224.21) v1(129.4,157.27) v1(129.4,156.36) v1(129.4,154.53) v1(129.57,55.7) v1(130.12,56.54) v1(130.32,166.42) v1(130.32,165.5) v1(130.32,164.59) v1(130.32,163.67) v1(130.32,162.76) v1(130.32,161.84) v1(130.32,160.93) v1(130.32,160.02) v1(130.34,159.11) v1(130.32,158.19) v1(130.43,60.53) v1(130.43,59.21) v1(130.43,57.99) v1(130.81,55.73) v1(131.24,214.86) v1(131.23,164.59) v1(131.23,161.84) v1(131.37,59.99) v1(131.37,58.67) v1(131.37,57.45) v1(131.5,56.54) v1(132.14,162.76) v1(132.14,160.02) v1(132.14,153.61) v1(132.18,55.73) v1(132.33,60.48) v1(132.33,59.16) v1(132.33,57.94) v1(132.44,56.74) v1(133.07,85.83) v1(133.51,215.21) v1(135.08,85.85) v1(135.7,214.16) v1(137.17,85.77) v1(139.12,85.85) v1(139.62,149.9) v1(140.49,192.33) v1(140.84,193.12) v1(140.89,149.9) v1(141.05,85.78) v1(141.78,193.14) v1(142.16,149.9) v1(143.13,85.88) v1(143.67,149.88) v1(144.7,220.37) v1(144.7,219.2) v1(144.98,85.8) v1(145.19,149.88) v1(145.24,68.07) v1(146.41,65.07) v1(146.38,62.46) v1(146.84,149.88) v1(147.09,85.85) v1(147.62,67.34) v1(148.16,218.72) v1(148.49,149.88) v1(149.12,85.85) v1(150.3,149.42) v1(151.03,85.85) v1(152.05,147.65) v1(152.69,85.68) v1(153.66,146.02) v1(154.89,85.83) v1(155.22,144.52) v1(156.85,142.87) v1(156.97,85.83) v1(158.8,140.92) v1(158.98,85.8) v1(160.71,209.25) v1(161.02,138.79) v1(160.96,85.9) v1(161.7,209.25) v1(162.31,137.54) v1(162.51,210.92) v1(163.04,85.9) v1(163.07,135) v1(163.07,132.46) v1(163.19,127.13) v1(163.19,124.59) v1(163.31,129.17) v1(163.45,136.4) v1(163.83,215.49) v1(163.93,212.72) v1(164.72,135.13) v1(164.72,133.48) v1(164.72,123.06) v1(165.23,127.38) v1(165.48,130.56) v1(165.74,132.33) v1(166.01,212.8) v1(165.99,124.97) v1(166.24,121.54) v1(166.75,131.44) v1(167.77,130.56) v1(167.77,129.29) v1(167.77,127.89) v1(167.77,126.36) v1(167.77,124.84) v1(167.77,123.19) v1(167.77,121.54) v1(167.77,120.14) v1(168.66,118.87) v1(168.75,64.42) v1(168.96,206.68) v1(169.95,207.77) v1(169.95,206.73) v1(169.95,205.66) v1(170.05,117.6) v1(170.44,65.75) v1(170.97,206.68) v1(171.32,116.2) v1(172.72,114.68) v1(172.72,112.78) v1(173.23,110.87) v1(173.43,108.81) v1(173.35,106.81) v1(173.36,104.73) v1(173.99,113.41) v1(175.18,87.91) v1(175.39,112.01) v1(175.39,110.11) v1(175.39,108.46) v1(175.39,106.81) v1(175.39,104.9) v1(175.51,102.62) v1(175.54,101.22) v1(175.51,99.95) v1(175.51,97.54) v1(175.45,93.74) v1(175.5,91.35) v1(175.57,98.58) v1(175.84,68.12) v1(176.38,160.82) v1(176.53,200.25) v1(177.34,160.86) v1(177.39,161.84) v1(177.39,159.8) v1(178.41,160.82) v1(179.65,73) v1(179.71,71.23) v1(182.07,223.49) v1(184.12,223.49) v1(185.6,180.06) v1(185.57,179.2) v1(186.38,224.87) v1(186.44,179.07) v1(191.76,147.22) v1(192.02,144.63) v2(8.13,236.73) v2(10.12,5.45) v2(11.3,226.19) v2(62.87,225.63) v2(64.67,231.09) v2(66.01,124.43) v2(71.32,233.86) v2(71.45,236.4) v2(73.79,133.99) v2(78.18,224.26) v2(84.84,234.06) v2(85.93,123.06) v2(92.58,225.53) v2(93.62,234.7) v2(104.88,123.11) v2(107.14,227.69) v2(110.87,238.66) v2(118.82,123.06) v2(121.03,225.45) v2(129.29,237.9) v2(131.34,105.08) v2(136.91,122.3) v2(138.3,75.26) v2(139.7,5.59) v2(146.25,223.9) v2(148.49,238.25) v2(153.92,144.53) v2(154.31,123.95) v2(154.31,20.19) v2(160.48,231.98) v2(165.48,7.87) v2(168.71,130.56) v2(174.32,238.84) v2(175.13,115.82) v2(176.15,18.8) v2(180.97,6.86) v2(183.64,215.65) v2(190.7,239.04) v3(20.22,53.62) v3(20.37,54.61) v3(20.59,51.16) v3(21.95,53.54) v3(22.48,50.79) v3(24.38,58.42) v3(25.02,58.44) v3(32.69,51.89) v3(32.72,42.18) v3(33.7,56.39) v3(33.83,53.39) v3(33.78,51.94) v3(33.91,42.97) v3(34.75,53.39) v3(39.17,51.46) v3(39.16,41.88) v3(39.88,46.02) v3(40.01,41.17) v3(40.44,54.89) v3(40.37,53.62) v3(40.51,40.64) v3(40.56,49.1) v3(40.64,43.81) v3(40.89,42.55) v3(41.15,56.39) v3(41.55,40.13) v3(41.73,41.43) v3(42.24,39.14) v3(42.67,46) v3(43.63,53.34) v3(43.63,50.83) v3(43.61,48.26) v3(43.61,43.26) v3(43.62,40.71) v3(43.66,45.82) v3(47.13,45.93) v3(47.6,40.97) v3(47.85,39.49) v3(47.88,52.7) v3(48.31,47.67) v3(49.37,54.38) v3(49.92,41.14) v3(50.16,47.47) v3(106.91,153.09) v3(106.92,149.46) v3(107.04,145.89) v3(107.64,149.46) v3(107.67,153.09) v3(107.75,145.89) v3(108.94,153.09) v3(108.94,149.44) v3(109.05,145.89) v3(109.65,153.09) v3(109.65,149.44) v3(109.76,145.89) v3(110.92,153.12) v3(110.97,149.46) v3(111.05,145.89) v3(111.63,153.12) v3(111.68,149.46) v3(111.77,145.89) v3(113,153.09) v3(112.95,149.44) v3(113.09,145.89) v3(113.71,153.09) v3(113.66,149.44) v3(113.8,145.89) v3(115.04,153.09) v3(115.04,145.89) v3(115.07,149.44) v3(115.75,153.09) v3(115.75,145.89) v3(115.78,149.44) v3(117.14,153.09) v3(117.07,149.44) v3(117.07,145.9) v3(117.78,149.44) v3(117.78,145.9) v3(117.85,153.09) v3(119.15,153.09) v3(119.1,149.44) v3(119.08,145.89) v3(119.81,149.44) v3(119.8,145.89) v3(119.86,153.09) v3(121.13,149.47) v3(121.14,145.89) v3(121.28,153.09) v3(121.84,149.47) v3(121.85,145.89) v3(121.99,153.09) v3(123.32,153.09) v3(123.29,149.44) v3(123.27,145.89) v3(124.03,153.09) v3(124,149.44) v3(123.99,145.89) v6(3.43,7.47) v6(4.45,7.47) v6(7.21,3.61) v6(8.33,3.58) v6(42.93,4.83) v6(42.95,3.56) v6(44.25,4.78) v6(44.32,3.56) v6(57.33,79.2) v6(62.08,31.88) v6(63.04,31.27) v6(64.03,31.83) v6(64.54,242.54) v6(64.64,240.16) v6(65.15,237.08) v6(69.44,242.65) v6(69.72,59.01) v6(70.36,237.74) v6(70.74,59) v6(73.08,43.05) v6(73.91,242.7) v6(74.04,42.01) v6(74.09,43.05) v6(75.11,43.05) v6(75.06,42.01) v6(87.38,205.49) v6(87.38,204.34) v6(88.39,205.49) v6(88.39,204.34) v6(88.65,242.44) v6(88.77,190.16) v6(88.79,189.14) v6(88.77,188.06) v6(88.77,187.05) v6(88.77,185.98) v6(89.89,196.8) v6(89.89,195.78) v6(89.89,194.72) v6(89.92,193.7) v6(89.93,190.14) v6(89.92,189.1) v6(89.95,188.03) v6(89.92,186.94) v6(89.94,185.93) v6(90.91,196.77) v6(90.94,195.76) v6(90.91,194.67) v6(90.93,193.65) v6(98.7,242.65) v6(99.69,182.4) v6(100.56,183.13) v6(100.64,181.84) v6(106.55,242.65) v6(113.61,242.72) v6(114.25,208.81) v6(115.27,208.81) v6(122.5,242.62) v6(126.7,69.22) v6(126.68,68.2) v6(126.68,67.18) v6(127.87,81.14) v6(128.89,81.13) v6(129.26,242.72) v6(129.92,81.1) v6(137.24,189.41) v6(137.23,187.3) v6(137.29,197.81) v6(137.32,196.8) v6(137.29,195.71) v6(137.32,194.69) v6(137.3,193.68) v6(137.26,188.39) v6(137.26,186.29) v6(137.44,242.62) v6(138.31,197.76) v6(138.33,196.74) v6(138.33,195.68) v6(138.33,194.66) v6(138.31,193.58) v6(138.25,189.36) v6(138.28,188.34) v6(138.28,187.27) v6(138.28,186.26) v6(138.48,54.51) v6(138.76,192.38) v6(145.9,242.65) v6(152.4,242.65) v6(157.71,242.62) v6(160.27,168.48) v6(161.57,168.48) v6(162.99,168.45) v6(163.64,197.99) v6(164.21,168.43) v6(164.65,197.99) v6(165.1,242.65) v6(165.67,197.99) v6(166.68,197.99) v6(166.77,1.17) v6(168,217.7) v6(170,198.04) v6(171.02,198.04) v6(172.03,198.04) v6(173.23,242.65) v6(174.6,1.12) v6(178.87,242.62) v6(179.07,1.14) v6(182.7,184.05) v6(182.7,183.03) v6(182.7,182.02) v6(182.7,181) v6(182.75,179.98) v6(182.8,177.52) v6(182.78,176.49) v6(182.77,175.48) v6(182.8,174.46) v6(183.77,183.13) v6(183.77,182.12) v6(183.77,181.1) v6(183.77,180.09) v6(183.82,177.51) v6(183.79,176.49) v6(183.79,175.44) v6(183.82,174.43) v6(184.28,1.27) v6(186.26,242.57) v6(187.07,14.35) v6(189.54,1.42) v6(190.22,242.52) v6(194.23,231.06) v6(194.82,13.72) v6(194.97,242.54) v6(195.15,216.53) v6(195.33,72.01) v6(196.32,228.22) v6(196.29,217.7) v6(197.64,233.81) v6(197.66,224.79) v6(197.66,220.7) v6(198.12,2.03) v6(198.27,242.42) v6(198.5,88.52) v6(198.54,10.91) v6(198.6,230.33) v6(198.58,101.4) v6(198.58,86) v6(198.58,84.2) v6(198.58,73.26) v6(198.57,70.79) v6(198.58,13.82) v6(198.68,236.04) v6(198.68,224.79) v6(198.68,220.7) v6(198.7,216.15) v6(198.68,207.77) v6(198.75,205.1) v6(198.83,122.81) v6(198.83,118.36) v6(198.81,97) v6(198.78,93.27)
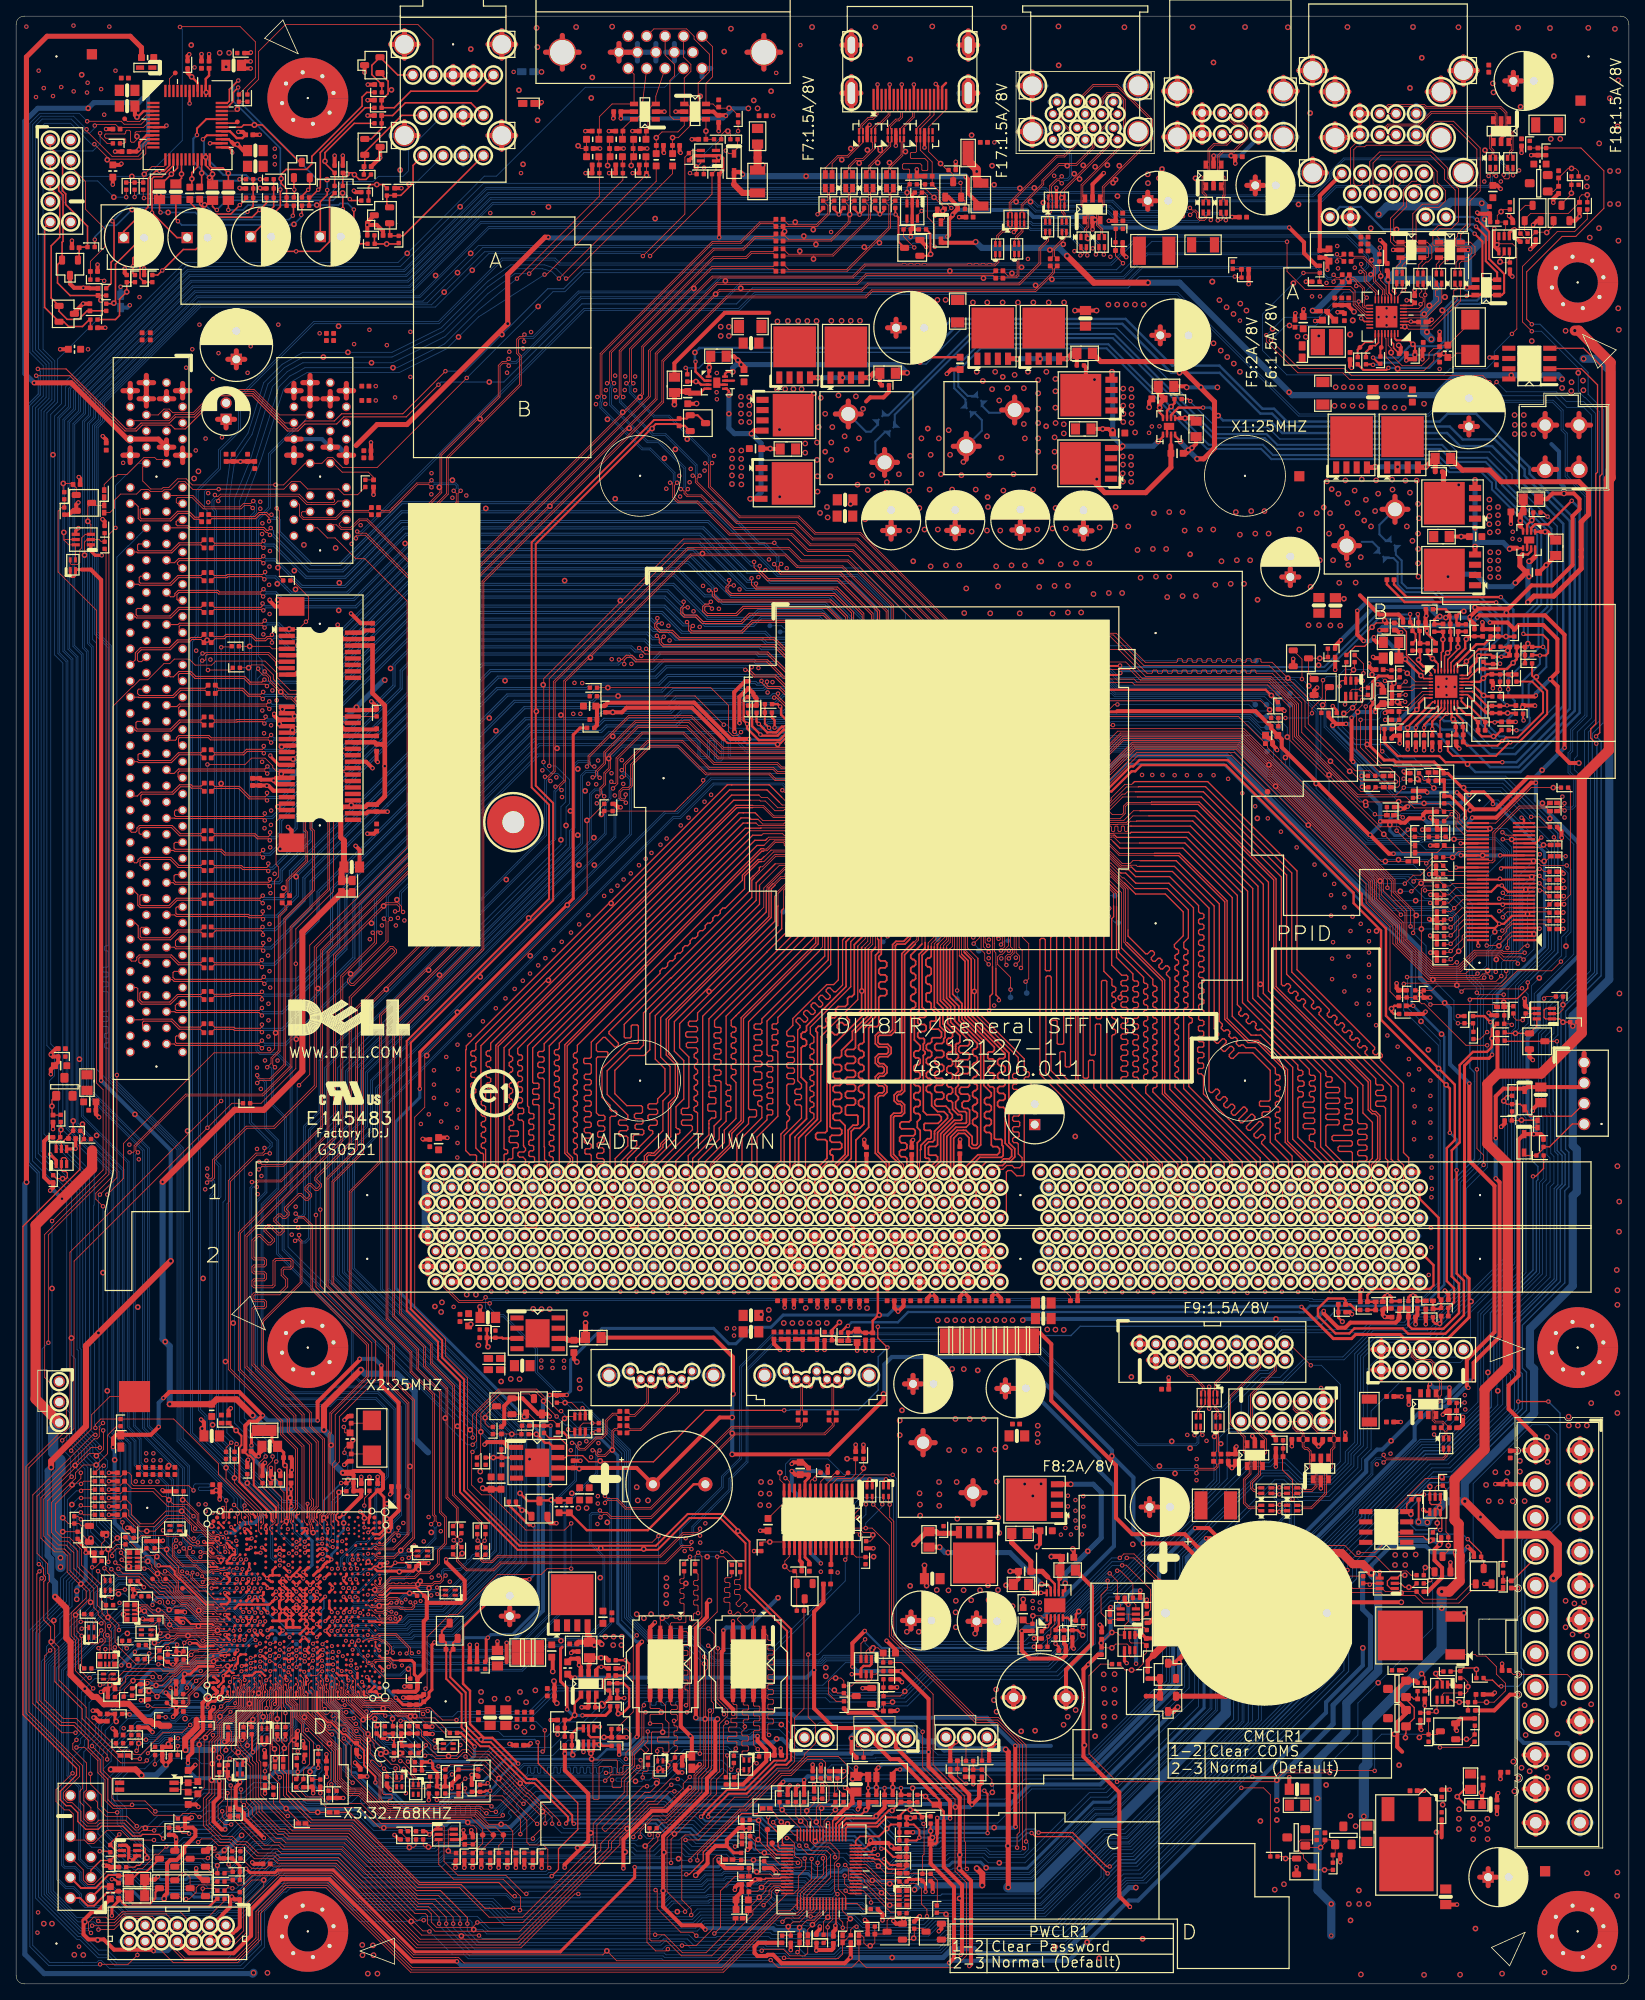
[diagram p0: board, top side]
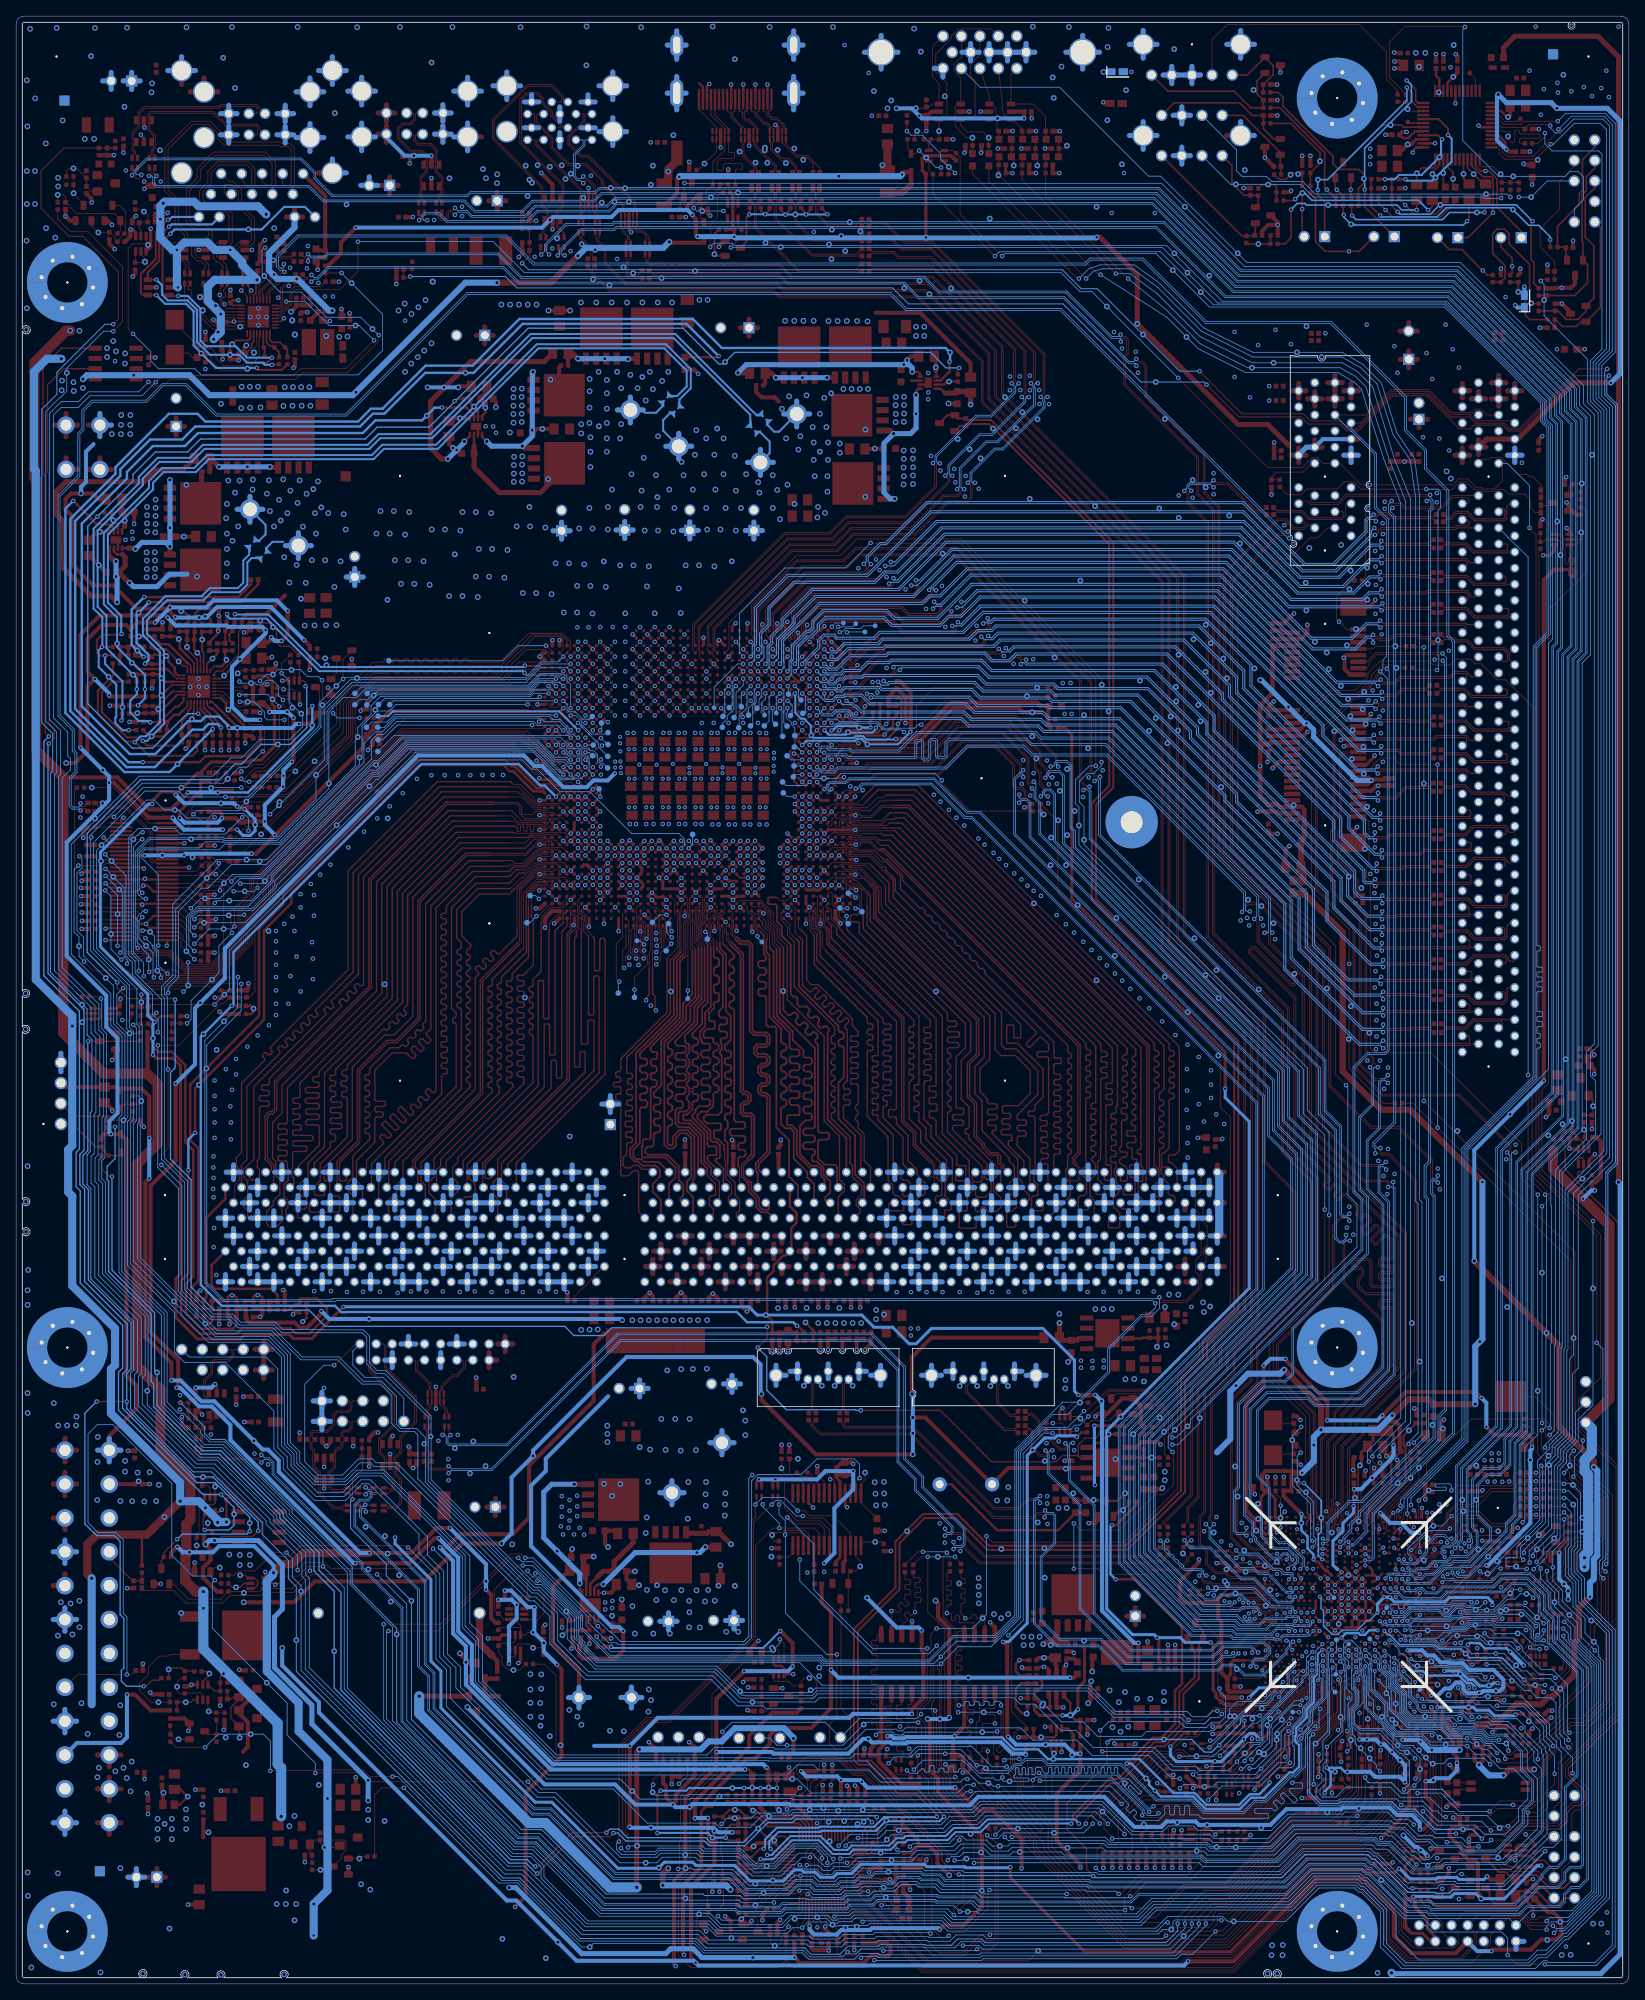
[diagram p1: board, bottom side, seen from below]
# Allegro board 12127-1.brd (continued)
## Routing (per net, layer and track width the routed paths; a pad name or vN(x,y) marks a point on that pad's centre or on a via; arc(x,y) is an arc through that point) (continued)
V1P05PCH_CNTRL_INPUT: length 4.4
  TOP w0.305: Q55.6 69.58,31.67 68.92,31.01 R243.1 R607.2 68.92,28.51 v2(69.04,28.4)
V1P05PCH_FET_CNTRL_PINS: length 5
  TOP w0.305: Q55.2 70.99,28.86 v2(71.28,28.57) 71.64,28.93 Q55.3 72.39,29.79 72.67,29.51 R606.2
VBAT1: length 8.1
  TOP w0.559: TP10.1 140.34,40.06 R392.1
  TOP w0.889: TP10.1 142.53,42.25 BT1.1
VBAT1_R: length 5.5
  TOP w0.559: R392.2 D23.1 D26.2 140.14,35.67 TP42.1
VBAT2: length 74.5
  TOP w0.203: U61.29 101.67,7.29 v1(101.6,7.21)
  TOP w0.508: v6(84.29,33.02) 84.29,44.11 85.66,45.48 85.66,47.21 v6(85.98,47.52) ; v1(101.6,7.21) 101.6,6.73 101.35,6.48 C483.1 ; v1(85.47,6.73) 84.94,7.26 82.53,7.26 80.24,9.56 80.24,18.32 85.67,23.75 85.67,25.48 86.7,26.51 86.7,32.58 v6(86.97,32.84)
  TOP w0.635: v6(144.96,40.98) 143.74,39.76 D23.3
  BOTTOM w0.508: v1(101.6,7.21) 101.6,6.71 101.02,6.12 98.24,6.12 97.68,6.68 94.11,6.68 93.88,6.91 85.65,6.91 v1(85.47,6.73) ; v6(86.97,32.84) v2(85.45,32.84) 84.47,32.84 v6(84.29,33.02)
VCC: length 612.9
  TOP w0.305: 113.41,16.76 G6.2 114,17.35 114.22,17.58 114.22,18.62
  TOP w0.508: v1(17.04,4.06) 16.87,4.24 12.14,4.24 10.87,5.51 8.97,5.51 8.36,6.13 8.36,7.87 9.37,8.89 10.03,8.89 R722.1 ; v1(182.77,168.81) 184.95,168.81 R241.2 186.35,168.5 189.38,168.5 191.13,166.75 191.13,162.69 v1(190.25,161.8) 191.16,160.88 191.16,152.88 192.66,151.38 v6(193.8,151.38) ; v6(88.8,70.23) 87.25,70.23 BZ1.1 76.94,63.97 C523.1 69.06,63.99 U51.6 ; 113.41,16.76 113.41,14.91 116.31,12.01 116.31,3.2 v1(115.72,2.62) ; v1(166.32,170.26) 166.32,167.31 v1(167.11,166.52) ; v1(115.82,20.52) 115.82,22.63 109.09,29.36 109.09,30.76 106.22,33.63 103.19,33.63 R415.1 ; R242.1 188.34,159.64 v1(188.47,159.77) ; LPC1.8 21.47,3.8 26.97,3.8 29.13,5.96 29.13,9.23 32.89,12.98 38.86,12.98 49.04,2.79 v1(54.66,2.79) ; v6(107.57,73.15) 107.57,72.42 100.81,65.66 v6(88.8,65.66) ; v6(119,216.01) 118.89,215.9 114.94,215.9 D18.A ; v1(117.77,224.07) 118.03,223.81 118.03,222.05 F17.2 ; v6(139.8,54.61) 144.7,54.61 149.4,49.91 162.97,49.91 165.56,47.32 v6(171.78,47.32) ; v6(88.9,73.15) 88.9,77.72 86.49,80.14 R293.1 ; v1(114.22,20.57) 114.22,18.62 ; v1(168.38,166.98) 168.38,166.73 168.76,166.34 R87.1
  TOP w0.559: v1(90.12,224.36) 89.82,224.66 D8.A 89.03,223.14
  TOP w0.635: ATX1.6 193.95,46.63 ; ATX1.6 193.95,43.73 ; ATX1.6 192.5,45.18 ; ATX1.6 195.4,45.18 ; ATX1.23 188.45,25.63 ; ATX1.23 187,24.18 ; ATX1.23 189.9,24.18 ; ATX1.23 188.45,22.73 ; ATX1.22 189.9,28.38 ; ATX1.22 187,28.38 ; ATX1.22 188.45,26.93
  TOP w0.762: 89.03,223.14 90.09,222.08 F7.2 ; v6(140.36,210.95) 133.65,210.95 v6(130.33,214.27)
  BOTTOM w0.508: v1(188.47,159.77) 188.47,160.02 v1(190.25,161.8) ; v6(167,41.66) 167,39.48 162.45,34.92 162.45,33.64 139.14,10.34 137.97,10.34 v2(132.81,5.18) 130.5,2.87 115.98,2.87 v1(115.72,2.62) 115.39,2.29 55.17,2.29 v1(54.66,2.79) ; v6(88.8,65.66) v2(88.8,68.28) v6(88.8,70.23) 88.8,73.1 88.85,73.15 v6(88.9,73.15) ; v1(17.04,4.06) 18.79,4.06 LPC1.8 ; v6(107.57,73.15) 107.68,73.26 107.68,76.81 108.6,77.73 124.3,77.73 135.89,66.14 v2(135.89,65.46) 138.56,62.79 138.56,55.85 v6(139.8,54.61) ; v1(167.11,166.52) 167.92,166.52 v1(168.38,166.98) ; v1(115.82,20.52) 115.77,20.57 v1(114.22,20.57) ; v1(166.32,170.26) 166.37,170.26 167.67,171.55 175.52,171.55 176.39,170.68 v2(180.91,170.68) 182.49,169.11 182.49,169.09 v1(182.77,168.81)
  BOTTOM w0.635: 193.95,43.73 ATX1.6 ; ATX1.6 193.95,46.63 ; ATX1.6 192.5,45.18 ; ATX1.6 195.4,45.18 ; 193.95,52.13 ATX1.4 ; ATX1.4 193.95,55.03 ; ATX1.4 192.5,53.58 ; ATX1.4 195.4,53.58
  BOTTOM w0.762: v6(130.33,214.27) 129.34,215.26 119.74,215.26 v6(119,216.01) ; v1(90.12,224.36) 90.33,224.16 v2(97.97,224.16) 117.69,224.16 v1(117.77,224.07) ; v6(140.36,210.95) 144.29,210.95 158.24,197 176,197 178.48,199.47 v2(185.42,199.47) 191.23,199.47 v6(191.72,198.98)
  vias: v2(171.75,48.49) v6(171.02,53.19) v6(170.99,51.94) v6(172.26,53.19) v6(172.26,51.94) v6(173.56,53.24) v6(185.67,27.56) v6(185.8,23.88) v6(186.28,25.53) v6(186.69,26.8) v6(187.69,26.37) v6(189.74,26.8) v6(189.92,25.63) v6(191.72,197.89) v6(192.15,47.5) v6(192.15,44.22) v6(192.53,70.33) v6(192.56,69.24) v6(192.89,198.61) v6(192.85,197.51) v6(193.01,43.33) v6(193.24,47.17) v6(193.68,69.24) v6(194.31,198.81) v6(194.36,197.61) v6(194.44,47.33) v6(194.79,69.24) v6(194.82,43.18)
VCC3: length 688.9
  TOP w0.203: 101.59,20.52 101.27,20.2 U61.53
  TOP w0.254: v1(30.81,58.37) 30.81,58.29 31.05,58.05 U29.AG1 ; R701.1 58.29,24.7 v1(58.48,24.89)
  TOP w0.305: U2.9 16.17,229.23 15.27,228.32 15.27,227.53 v1(15.21,227.48) ; U29.W30 35.22,42.52 v3(35.64,42.94) 35.8,42.94 U29.U30 ; R427.2 19.88,41.97 v1(19.96,42.06) ; R566.2 55.16,31.11 55.46,30.82 v1(56.86,29.42) ; v1(24.1,53.87) 24.1,53.61 24.32,53.4 U29.AW9 ; v3(31.17,43.84) 31.23,43.84 31.6,44.21 U29.AF26 ; R615.2 14.62,36.64 15.15,37.17 R679.2
  TOP w0.356: U23.10 U22.10 97.83,62.3 98.27,62.74 C385.1 ; RN41.1 108.2,62.24 v1(107.87,62.56) 107.55,62.24 RN41.2 ; RN40.2 105.52,62.24 v1(105.84,62.56) 106.17,62.24 RN40.1 ; U23.24 U22.24 101.08,52.05 C402.1 ; C386.1 98.37,52.35 97.83,52.89 U22.19 U23.19
  TOP w0.381: v1(54.03,24.26) 53.84,24.45 53.21,24.45 ; v1(46.92,18.47) 46.96,18.42 46.96,18.4 47.46,17.91 R458.1 ; 53.21,24.45 R45.2 53.21,25.67 R595.2 ; 53.21,24.45 52.2,24.45 R593.2 52.2,25.67 R598.1 52.24,26.2 51.66,26.77 51.66,27.28 v1(51.33,27.61) 51.21,27.48 R683.2 50.27,27.42 50.27,26.53 R685.2 ; 27.28,6.6 26.95,6.27 25.58,6.27 24.57,5.27 LPC1.4 24,5.81 24.99,6.81 24.99,8 25.59,8.6 ; R583.2 R609.2 R651.1 47.75,29.65 v1(47.75,30.35) R577.1 R613.2 R585.2 ; v1(66.28,69.21) R790.1 64.4,69.21 64.38,69.22 R2220.1 ; R619.2 45.33,30.43 45.97,30.43 v1(46.02,30.38) ; v1(16.28,37.3) 16.12,37.13 15.46,37.13 R679.2
  TOP w0.406: R51.1 111.12,217.74 U3.5 U3.2 111.12,221.81 R50.1 ; R51.1 R41.1 ; R51.1 v1(110.93,216.64) ; v1(87.19,216.56) R66.1 87.63,224.85 87.63,226.38 87.32,226.69 U4.2 U4.5 84.1,226.69 83.8,226.39 83.71,226.39 R65.1
  TOP w0.508: v1(10.87,14.67) 11.21,14.67 11.25,14.63 11.47,14.63 R2236.1 11.77,14.5 12.73,14.5 12.76,14.48 R2235.1 ; v1(96.19,63.59) 96.63,63.14 C389.1 98.21,63.14 C385.1 ; 188.45,67.63 188.45,67.94 185.09,71.3 185.09,74.19 186.31,75.41 186.31,104.67 D21.K v1(188.22,105.37) 189.1,105.37 189.41,105.05 R362.1 ; v1(169.06,167.87) R257.1 ; v1(13.79,56.55) 14.13,56.55 14.52,56.17 R420.2 ; R84.1 v1(169.77,156.74) ; R2218.1 175.18,143.12 v1(174.38,143.12) ; v1(181.2,169.42) 181.47,169.7 189.61,169.7 192.02,167.28 v1(192.02,153.29) ; R601.2 87.93,14.35 87.12,15.16 v1(87.12,15.42) ; Q5.G 115.63,221.55 116.78,220.41 R78.2 116.64,219.95 116.64,219.94 116.2,219.51 116.2,219.44 v1(116.12,219.36) 116.12,219.25 115.7,218.82 115.7,216.87 v1(115.49,216.66) ; v6(18.35,10.57) 18.41,10.63 18.41,10.94 18.72,11.24 18.72,14.96 19.13,15.37 19.91,15.37 20.85,16.31 20.85,16.97 22.23,18.34 22.23,19.05 21.89,19.38 R560.2 R441.2 21.56,20.5 21.69,20.62 v1(21.79,20.62) ; v1(109.86,37.41) 109.5,37.77 R627.1 ; v1(157.89,217.78) 159.72,215.95 159.72,214.6 161.28,213.04 R144.2 ; R658.2 v1(99.8,27.18) ; R752.1 v1(140.21,47.62) ; R642.2 v1(99.97,24.66) ; R590.1 30.86,23.63 30.87,23.63 v1(30.86,23.62) ; v1(102.79,24.31) 102.95,24.31 103.45,23.8 C475.1 103.7,23.36 C478.1 103.06,21.84 102.92,21.84 101.59,20.52 ; v1(54.03,24.26) 54.03,24.85 R580.2 ; v1(180.57,144.61) 183.55,144.61 187.88,148.95 v1(188.47,148.95) ; R751.1 137.48,47.46 v1(137.92,47.01) ; C42.1 14.94,227.2 v1(15.21,227.48) ; PR134.1 v1(67.14,30.91) ; R409.2 84.26,26.73 v1(84.76,27.23) ; v1(95.96,24.59) 95.68,24.31 R634.2 ; 27.28,6.6 27.74,7.06 R638.1 27.07,10.48 v1(26.73,10.81) 26.54,10.62 26.54,9.55 25.59,8.6
  TOP w0.635: SLOT2.A10 21.55,189.55 ; SLOT2.A10 20.65,188.65 ; SLOT2.A10 19.75,189.55 ; SLOT2.A10 20.65,190.45 ; 35.35,191.55 SLOT1.B8 33.55,191.55 ; DIMM2.236 55.94,88.95 ; DIMM2.236 55.04,88.05 ; DIMM2.236 55.04,89.86 ; SLOT1.A9 39.85,190.55 ; SLOT1.A9 38.05,190.55 ; SLOT1.A9 38.95,191.45 ; ATX1.13 188.45,67.63 ; ATX1.13 187,66.18 ; ATX1.13 189.9,66.18 ; ATX1.13 188.45,64.73 ; TC13.1 27.09,194.01 ; TC13.1 26.04,192.95 ; TC13.1 24.98,194.01 ; 40.05,189.55 SLOT1.A10 ; SLOT1.A10 40.95,188.65 ; SLOT1.A10 41.85,189.55 ; SLOT1.A10 40.95,190.45 ; 42.16,190.75 44.77,193.36 48.46,193.36 60.83,205.73 60.83,205.74 v2(60.96,205.87) 60.96,211.96 65.58,216.59 v1(65.99,216.59) ; SLOT2.A9 17.65,191.55 SLOT2.B8 13.8,191.55 6.83,198.53 v1(2.24,198.53) ; SLOT2.A9 19.55,190.55 ; SLOT2.A9 18.65,191.45 ; SLOT2.A9 18.65,189.65 ; SLOT2.A9 17.75,190.55 ; 192.5,61.98 ATX1.2 ; ATX1.2 193.95,63.43 ; ATX1.2 193.95,60.53 ; ATX1.2 195.4,61.98 ; ATX1.1 195.4,66.18 ; ATX1.1 193.95,64.73 ; ATX1.1 193.95,67.63 ; ATX1.1 192.5,66.18 ; DIMM2.237 54.94,87.05 ; 55.04,95.95 DIMM1.236
  TOP w0.762: v6(119.81,12.22) 119.81,13.64 v6(119.13,14.33)
  BOTTOM w0.305: v1(19.96,42.06) 19.76,42.27 18.53,42.27 18.38,42.11 18.37,42.11 17.86,41.61 15.15,41.61 v1(14.72,41.17) ; v3(35.64,42.94) 35.08,43.5 33.51,43.5 33.3,43.28 32.74,43.28 32.19,43.84 v3(31.17,43.84)
  BOTTOM w0.381: v1(56.86,29.42) 56.86,28.31 56.11,27.56 52.67,27.56 52.62,27.61 v1(51.33,27.61) 51.29,27.57 50.53,27.57 v1(47.75,30.35) 47.05,31.05 46.47,31.05 46.02,30.61 v1(46.02,30.38) ; v1(66.22,61.85) 66.28,61.91 v1(66.28,69.21) ; v1(26.73,10.81) 26.69,10.85 24.31,10.85 24.23,10.77 22.07,10.77 21.64,11.2 18.98,11.2 v6(18.35,10.57) 15.43,10.57 11.33,14.67 v1(10.87,14.67) ; v1(16.28,37.3) 16.81,37.3 17.17,36.94 18.52,36.94 19.32,37.74 19.93,37.74 20.99,38.81 v1(22.89,38.81)
  BOTTOM w0.508: v1(188.22,105.37) 188.44,105.58 188.44,106.97 187.43,107.98 187.43,117.26 188.82,118.65 188.82,122.55 193.72,127.45 193.72,141.54 188.47,146.8 v1(188.47,148.95) 188.47,149.73 v2(189.24,150.5) v1(192.02,153.29) ; v1(157.89,217.78) 134.77,217.78 v2(133.8,218.75) 133.45,219.1 127.35,219.1 126.15,219.1 125.29,219.96 116.73,219.96 v1(116.12,219.36) ; SLOT1.A9 38.94,190.55 37.94,191.55 SLOT1.B8 ; v1(138.89,39.7) 138.89,44.35 137.92,45.31 v1(137.92,47.01) 138.53,47.62 v1(140.21,47.62) ; v1(26.04,55.96) 27.02,55.96 28.21,57.15 29.59,57.15 v1(30.81,58.37) ; v1(15.21,227.48) 16.36,228.63 16.36,234.14 v6(16.21,234.29) ; v1(107.87,62.56) v1(105.84,62.56) 100.66,62.56 99.63,63.59 v1(96.19,63.59) 96.19,61.32 98.53,58.98 98.53,53.42 v1(99.8,52.15) ; v1(13.04,39.5) v1(14.72,41.17) ; v1(169.77,156.74) 171.58,156.74 173.23,158.39 173.23,163.31 v2(172.27,164.26) 169.06,167.48 v1(169.06,167.87) 169.47,168.28 173.74,168.28 173.89,168.43 180.2,168.43 v1(181.2,169.42) ; v1(174.38,143.12) 179.19,143.12 180.47,144.4 180.47,144.51 v1(180.57,144.61)
  BOTTOM w0.635: 188.45,64.73 ATX1.13 ; ATX1.13 187,66.18 ; ATX1.13 188.45,67.63 ; ATX1.13 189.9,66.18 ; ATX1.12 193.95,21.43 ; ATX1.12 195.4,19.98 ; ATX1.12 192.5,19.98 ; ATX1.12 193.95,18.53 ; v1(65.99,216.59) 66.08,216.5 87.12,216.5 v1(87.19,216.56) 87.24,216.51 110.81,216.51 v1(110.93,216.64) 110.96,216.66 v1(115.49,216.66) ; SLOT1.A9 40.01,190.55 40.74,189.81 40.74,189.76 SLOT1.A10 ; v1(2.24,198.53) 1.08,199.68 1.08,230.97 2.67,232.57 v2(8.93,232.57) 9.64,233.27 15.19,233.27 v6(16.21,234.29)
  BOTTOM w0.762: v6(111.41,11.68) 111.94,12.22 v6(119.81,12.22)
  vias: v1(12.83,47.24) v1(16.13,65.79) v1(16.13,64.92) v1(17.02,65.79) v1(17.02,64.92) v1(17.91,64.92) v1(22.28,190.14) v1(22.63,59.46) v1(23.5,191.62) v1(23.5,59.46) v1(23.5,58.6) v1(25.53,191.77) v1(27.3,54.94) v1(48.34,23.65) v2(56.39,81.79) v2(77.83,53.92) v2(179.53,45.97) v2(181.58,19.84) v2(184.81,62.33) v6(55.88,85.47) v6(57.02,85.47) v6(61.34,75.01) v6(62.43,74.98) v6(69.87,74.87) v6(69.9,73.84) v6(76.96,61.59) v6(76.96,45.85) v6(77.09,59.94) v6(77.85,45.34) v6(78.36,59.94) v6(78.74,45.85) v6(100.41,39.22) v6(100.41,38.15) v6(178.94,21.64) v6(178.92,20.47) v6(178.92,19.2) v6(180.7,20.47) v6(180.7,19.2) v6(180.7,17.93) v6(182.3,61.87) v6(182.45,20.47) v6(182.45,19.2) v6(182.47,17.96) v6(182.63,59.87) v6(183.44,63.45) v6(184.1,59.82) v6(184.94,63.4) v6(185.6,59.84) v6(186.49,64.85) v6(186.49,63.53) v6(187.07,59.87) v6(189.87,67.82) v6(189.92,64.72) v6(189.94,59.99)
VCC3_3SBREF:
  vias: v2(176.91,22.23)
VCC5_DDC_HDMI: length 6.9
  TOP w0.102: D18.K 115.13,218.88 C53.1 115.13,220.24 v2(113.84,221.53) 112.71,222.65 R18.1 R17.1
VCC12CPU: length 107.7
  TOP w0.508: v6(145.16,197.97) 145.03,198.09 R259.1 ; 93.4,207.21 87.88,207.21 81.64,200.96 R248.1 ; v1(164.29,166.62) 163.56,165.9 R298.1 ; R182.1 189.81,184.1 190.53,184.81 v6(191.95,184.81) 193.17,184.81 193.88,184.1 193.88,182.86 193.01,181.99 193.01,175.95 190.47,173.41 187.93,173.41 185.06,170.54 181.31,170.54 v1(180.26,169.49) 180.26,169.19 180.85,168.61 R88.1
  TOP w0.635: 140.83,204.42 TC34.1 ; TC34.1 141.89,205.47 ; TC34.1 141.89,203.36 ; TC34.1 142.94,204.42 ; TC40.1 180.16,194.17 ; TC40.1 181.22,193.12 ; TC40.1 179.11,193.12 ; TC40.1 180.16,192.06 ; ATX12V.4 189.62,194.72 ; ATX12V.4 189.62,191.85 ; ATX12V.4 191.05,193.29 ; ATX12V.4 188.18,193.29 ; TC9.1 109.12,206.41 ; TC9.1 110.18,205.36 ; TC9.1 108.07,205.36 ; TC9.1 109.12,204.3 ; 192.38,193.29 ATX12V.3 ; ATX12V.3 193.82,191.85 ; ATX12V.3 193.82,194.72 ; ATX12V.3 195.25,193.29
  BOTTOM w0.508: 190.4,190.93 191.34,189.99 191.34,186.23 191.95,185.62 v6(191.95,184.81) ; v1(180.26,169.49) 180.19,169.42 v2(177.29,169.42) 176.4,169.42 175.08,170.74 168.41,170.74 v1(164.29,166.62) ; v6(145.16,197.97) v2(146.94,197.97) v6(148.97,197.97)
  BOTTOM w0.635: ATX12V.4 189.62,194.72 ; ATX12V.4 189.62,191.85 ; ATX12V.4 188.18,193.29
  vias: v2(157.86,197.36) v6(94.41,206.15) v6(95.71,206.2) v6(96.98,206.2) v6(98.12,206.2) v6(99.26,206.2) v6(101.09,206.22) v6(102.36,206.22) v6(103.5,206.22) v6(104.65,206.22) v6(118.66,208.49) v6(120.43,208.49) v6(122.34,208.49) v6(124.24,208.49) v6(126.15,208.49) v6(128.05,208.49) v6(129.96,208.49) v6(135.46,208.23) v6(136.55,208.23) v6(137.64,208.23) v6(138.73,208.23) v6(139.83,208.23) v6(148.49,203.43) v6(149.39,202.53) v6(150.19,201.72) v6(151,200.91) v6(151.76,199.9) v6(163.5,195.68) v6(164.59,195.68) v6(165.74,195.68) v6(166.85,195.66) v6(169.7,195.48) v6(170.99,195.45) v6(172.09,195.4) v6(174.6,195.94) v6(185.83,194.54) v6(185.85,193.32) v6(185.85,192.18) v6(186.97,194.54) v6(186.99,193.32) v6(186.99,192.18) v6(188.14,192.18)
VCC_SENSE: length 45.7
  TOP w0.254: v1(136.9,163.47) 136.86,163.42 135.13,163.42 134.92,163.22 U27.E40 ; R229.2 173.55,166.61 173.55,167.39 R799.2 173.16,168.54 R119.2 172.89,169.84 v1(172.87,169.85)
  BOTTOM w0.254: v2(161.52,163.53) 161.52,163.29 ; 161.52,163.29 137.08,163.29 v1(136.9,163.47) ; 161.52,163.29 162.21,163.29 168.72,169.8 172.82,169.8 v1(172.87,169.85)
VCCIO2PCH: length 39.2
  TOP w0.229: 87.73,154.33 88.21,153.86 94.83,153.86 95.48,154.5 103.15,154.5 103.43,154.23 103.43,153.42 104.06,152.79 104.06,152.33 103.5,151.77 103.5,149.12 U27.AB8
  TOP w0.508: 87.73,154.33 83.82,158.24 75.69,158.24 75.12,157.67 v2(73.99,157.67) R807.2
VCCST: length 41.8
  TOP w0.305: U27.K9 v1(103.43,160.02)
  TOP w0.508: v1(90.91,154.36) 88.6,154.36 84.08,158.88 73.37,158.88 R807.1 72.94,158.45 C88.1 72.03,158.3 C141.1 72.03,156.07 R200.2
  BOTTOM w0.254: v1(90.91,154.36) 90.96,154.31 94.54,154.31 94.95,154.71 95.91,154.71 96.12,154.5 101.07,154.5 v2(101.39,154.82) 101.45,154.88 101.45,156.03 102.3,156.88 102.64,156.88 103.38,157.62 103.38,159.97 v1(103.43,160.02)
VCCST_PWRGD: length 31.9
  TOP w0.102: v1(85.2,149.24) 85.2,148.95 84.83,148.59 83.3,147.05 83.29,147.04 82.75,146.5 82.74,146.49 82.03,145.78 81.67,145.43 R2231.1 73.97,145.43 R2230.2 ; U27.Y7 v1(101.6,149.96)
  BOTTOM w0.102: v1(85.2,149.24) 86.03,150.08 97.68,150.08 98.27,149.48 v2(99.82,149.48) 101.12,149.48 v1(101.6,149.96)
VSS_SENSE: length 47.6
  TOP w0.254: v1(173.82,169.85) 173.82,169.65 173.9,169.57 R111.1 173.9,167.92 R799.1 174.05,166.26 C130.2 R116.2 ; v1(136.94,162.55) 136.68,162.3 U27.F40
  BOTTOM w0.254: v2(169.72,169.05) 169.72,169.29 ; 169.72,169.29 168.94,169.29 162.42,162.78 137.16,162.78 v1(136.94,162.55) ; 169.72,169.29 173.49,169.29 173.82,169.62 v1(173.82,169.85)
1D5V_S0_EP/SP: length 42.5
  TOP w0.559: 43.6,146.24 43.31,145.95 MINI1.48 40.59,145.95 40.26,145.62 40.26,144.91 ; 45.3,153.71 44.73,153.71 C376.1 44.49,153.95 MINI1.28 ; 45.72,153.42 45.43,153.71
  TOP w0.584: MINI1.6 44.17,165.95 C267.1 44.2,160.05 45.72,158.52 v1(45.72,151) 45.72,147.26 C266.1 43.6,146.24 ; 45.43,153.71 45.3,153.71
  TOP w0.635: 40.26,144.91 40.26,142.16 40.65,141.77
  TOP w0.762: R104.2 R99.2 40.36,138.19 C377.1 40.65,141.77
1P05_PCH_DRV: length 4.4
  TOP w0.508: R283.1 73.16,40.44 v2(72.54,40.44) R251.1 71.12,39.62 70.99,39.5 U17.5
1P05_PCH_DRV_1: length 4.7
  TOP w0.305: R283.2 75.55,40.13 v1(75.56,40.14) 76.02,39.69 76.02,38.73 75.51,38.23 C208.1
1P05_PCH_EN: length 6.4
  TOP w0.305: R243.2 PR134.2 PC352.1 68.63,32.72 v2(69.27,33.35) 69.27,34.85 70.04,35.62 U17.1
1P5_PCH_EN: length 4.3
  TOP w0.305: U51.8 66.65,66.53 66.09,67.08 65.59,67.08 v2(64.52,68.16) R792.1
1P5_PCH_EN_R: length 4
  TOP w0.102: R198.2 58.58,69.06 58.17,69.47 v2(58.17,70.21) 58.17,70.48 59.3,71.62 Q77.D
1P05_PCH_EN_R: length 13.5
  TOP w0.102: R791.2 57.61,65.72 57.61,68.35 57.63,68.38 v2(57.63,68.45) 57.63,70.76 60.04,73.16 63.63,73.16 Q78.D
1P5_PCH_EN_R_1: length 4.7
  TOP w0.102: R198.1 59.15,68.19 C254.1 61.44,68.19 v2(61.47,68.17) 62.66,68.17 R792.2 62.67,69.16 R2220.2
1P05_PCH_FB: length 7.6
  TOP w0.305: C208.2 72.77,37.53 72.77,36.83 73.22,36.39 R279.2 73.67,36.25 C199.2 72.95,34.71 72.95,34.67 v2(72.77,34.49) 72.57,34.29 R261.1 71.82,35.74 U17.3
1P5_PCH_FB: length 4.9
  TOP w0.305: R222.2 v2(59.18,65.26) PC78.2 ; R209.1 60.18,65.33 PC78.2 ; U51.2 62.06,65.26 PC78.2
1P05_PCH_G: length 5.5
  TOP w0.635: C209.1 69.74,42.37 R251.2 ; R251.2 72.36,42.37 v2(72.62,42.11) ; R251.2 71.12,43.05 70.87,43.31 Q35.4
1P05_PCH_S1: length 1.8
  TOP w0.305: R277.2 74.56,36.37 C199.1 v1(75.41,35.43)
1P05_PCH_S1_U: length 7.7
  TOP w0.305: R287.1 74.56,33.62 v2(74.68,33.5) 75.16,33.5 76.02,34.37 76.02,36.6 75.35,37.27 R277.1 R279.1
1P05_PCH_SS: length 2.2
  TOP w0.305: C194.1 73.17,39.12 72.98,39.3 v1(72.57,39.3) 72.22,39.3 71.95,39.03 U17.4
1P5V_AUX: length 79.4
  TOP w0.508: PR87.1 129.95,42.19 130.19,41.95 PC63.1 130.19,40.76 129.77,40.34 125.7,40.34 124.71,41.33 v1(124.71,43.76) PR109.1
  TOP w0.635: 122.68,72.78 TC42.1 ; TC42.1 123.74,73.84 ; TC42.1 121.63,73.84 ; TC42.1 122.68,74.89 ; 110.17,74.4 TC15.1 ; TC15.1 111.23,75.45 ; TC15.1 111.23,73.34 ; TC15.1 112.28,74.4 ; 112.47,65.61 L50.2 ; L50.2 110.97,67.11 ; L50.2 113.97,67.11 ; L50.2 112.47,68.61
  BOTTOM w0.508: v1(124.71,43.76) 124.71,43.75 125.23,44.27 126.14,44.27 136.14,54.28 136.14,61.77 134.32,63.6 134.32,65.13 126.57,72.87
  BOTTOM w0.635: 122.68,72.78 TC42.1 ; TC42.1 121.63,73.84 ; TC42.1 123.74,73.84 ; TC42.1 122.68,74.89 ; L50.2 112.47,68.61 ; L50.2 113.97,67.11 ; L50.2 110.97,67.11 ; L50.2 112.47,65.61 ; TC15.1 111.23,75.45 ; TC15.1 111.23,73.34 ; TC15.1 112.28,74.4 ; TC15.1 110.17,74.4
  vias: v2(109.86,71.12) v2(119.25,76.07) v2(122.68,66.55) v6(109.58,69.85) v6(109.58,68.05) v6(114.35,76.28) v6(115.7,66.19) v6(116.08,76.25) v6(116.48,70.05) v6(117.53,76.23) v6(117.58,66.13) v6(118.26,70.05) v6(119.46,66.22) v6(119.99,70.05) v6(121.39,66.26)
100M_DMI_PCH_DN: length 14.7
  TOP w0.102: U29.G22 41.68,46.44 v3(41.35,46.1) ; v3(52.2,49.15) 52.51,48.84 RN33.3
  BOTTOM w0.102: v3(52.2,49.15) 51.93,48.88 51.31,48.88 51.01,49.17 49.81,49.17 ; 49.81,49.17 v2(49.81,49.53) ; 49.81,49.17 46.53,49.17 44.22,46.86 41.78,46.86 41.56,46.64 41.56,46.31 v3(41.35,46.1)
100M_DMI_PCH_DP: length 14.2
  TOP w0.102: v3(42,46.09) 42.39,46.49 U29.F22 ; RN33.4 52.37,48.19 v3(52.22,48.34)
  BOTTOM w0.102: 44.82,47.1 46.63,48.92 50.91,48.92 51.2,48.62 51.93,48.62 v3(52.22,48.34) ; 44.82,47.1 v2(45.03,46.89) ; 44.82,47.1 44.32,46.61 41.89,46.61 41.81,46.53 41.81,46.27 v3(42,46.09)
5337_CTRL: length 5.4
  TOP w0.635: U13.6 68.2,80.04 68.43,79.81 C198.1 70.28,79.81 R293.2 v2(70.61,81.97)
5337_VREF: length 6
  TOP w0.305: v2(58.52,78.99) 58.38,79.13 C205.1 ; R288.1 C205.1 ; C205.1 R286.2 60.26,80.12 60.35,80.04 U13.3
81102_COMP: length 6.4
  TOP w0.203: v2(178.8,165.76) 178.8,165.48 177.54,164.22 U52.28
  TOP w0.305: v2(178.8,165.76) C233.2 178.8,167.68 C176.2 R139.1
81102_COMP_1: length 2.6
  TOP w0.305: C126.1 175.93,168.63 R126.1 175.87,169.16 176.27,169.56 v2(176.56,169.56)
81102_COMP_2: length 3.2
  TOP w0.305: v2(179.53,170.2) 179.22,170.2 R212.1 178.63,168.77 C176.1 R139.2
81102_CSCCOMP: length 33.1
  TOP w0.203: 180.09,162.42 179.92,162.26 U52.24
  TOP w0.305: R103.2 184.12,165.77 C234.1 C185.1 185,164.55 v1(184.19,164.55) 183.16,164.55 R113.2 182.88,164.82 181.58,164.82 181.1,164.34 181.1,163.96 180.34,163.19 180.34,162.67 180.09,162.42 ; v1(184.12,171.96) 172.44,171.96 170.88,173.52 R120.2
  BOTTOM w0.305: v1(184.12,171.96) 185.67,170.41 185.67,166.03 v2(184.97,165.33) v1(184.19,164.55)
81102_CSCM_1: length 26.3
  TOP w0.305: v1(183.54,171.3) 183.49,171.35 172.19,171.35 169.99,173.55 R120.1 ; R235.1 182.24,163.66 183.15,163.66 R113.1 183.97,163.65 v1(184.02,163.7)
  BOTTOM w0.305: v1(184.02,163.7) 183.58,164.14 183.58,164.81 184.33,165.56 184.33,165.59 184.71,165.96 184.74,165.96 185.06,166.29 185.06,169.78 v2(184.82,170.02) 184.81,170.02 v1(183.54,171.3)
81102_CSREF: length 7.2
  TOP w0.203: U52.22 180.44,161.46
  TOP w0.305: R96.2 R100.2 R98.2 183.03,162.37 C129.1 182.46,162.39 v2(181.96,161.89) 181.52,161.46 180.44,161.46
81102_CSSUM: length 12.4
  TOP w0.203: 180.95,162.73 180.08,161.86 U52.23
  TOP w0.305: R93.1 R94.1 187.11,165.77 187.11,165.77 ; 187.11,165.77 R95.1 ; 187.11,165.77 C234.2 C185.2 186.09,164.25 v2(185.65,163.81) 184.89,163.04 R235.2 181.27,163.04 180.95,162.73
81102_DIFF: length 6.1
  TOP w0.203: U52.30 176.74,165.08 176.96,165.3 176.94,165.33
  TOP w0.305: R126.2 175.88,167.66 R233.2 176.96,166.73 v2(176.94,166.7) 176.94,165.33
81102_FB: length 9.9
  TOP w0.203: U52.29 177.14,164.67 v2(177.52,165.05)
  TOP w0.305: R220.1 177.27,170.46 177.74,169.99 R212.2 177.84,169.51 C126.2 177.85,168.62 R233.1 177.91,167.6 C233.1 177.91,165.44 v2(177.52,165.05)
81102_ILIM: length 6
  TOP w0.203: 181.38,165.5 v2(179.85,163.98) 179.32,163.45 179.02,163.45 178.74,163.17 U52.25
  TOP w0.305: 181.38,165.5 182.89,165.5 R103.1
81102_IOUT: length 9.8
  TOP w0.203: 178.66,163.74 178.34,163.42 U52.26
  TOP w0.305: R241.1 v2(184.76,167.07) 184.68,167.07 184.66,167.09 C174.1 R231.1 182.83,166.88 182.07,166.11 181.09,166.11 178.71,163.74 178.66,163.74
81102_RAMP: length 7
  TOP w0.203: 178.59,164.48 177.94,163.83 U52.27
  TOP w0.305: C145.1 R88.2 180.17,167.09 v2(179.83,166.75) 179.71,166.62 179.71,165.6 178.59,164.48
81102_TSENSE: length 6.9
  TOP w0.203: 174.63,159.46 U52.8
  TOP w0.305: R124.1 170.65,155.65 171.15,155.65 171.16,155.66 C172.1 171.58,155.88 v2(173.69,158) 173.96,158.27 173.96,158.79 174.63,159.46
81102_TSENSE_R: length 148
  TOP w0.305: v1(112.88,201.85) 113.03,201.7 R207.1 ; v1(184.3,151.49) 177.24,151.49 176.48,152.25 171.35,152.25 169.69,153.9 R105.1 R124.2
  BOTTOM w0.305: v1(184.3,151.49) 186.06,151.49 192.67,158.1 192.67,181.4 187.07,187 187.07,187.81 183.37,191.51 179.39,191.51 177.78,193.12 157.34,193.12 155.75,194.71 154.31,194.71 149.25,199.77 v2(144.27,199.77) 143.26,199.77 137.19,205.84 116.87,205.84 v1(112.88,201.85)
81102_VCC: length 7
  TOP w0.203: U52.2 174.58,161.86 v2(174.21,162.22)
  TOP w0.305: v2(174.21,162.22) 172.05,164.39 C72.1 R87.2
81102_VSN: length 4.1
  TOP w0.203: U52.31 176.34,163.67 176.1,163.91
  TOP w0.305: 176.1,163.91 175.68,164.34 v2(175.64,164.34) 175.06,164.92 R116.1 176.01,165.33 C128.2
81102_VSP: length 5
  TOP w0.203: 175.08,163.37 175.44,163.37 175.94,162.87 U52.32
  TOP w0.305: R229.1 C130.1 174.09,164.36 v2(173.92,164.18) 173.92,163.95 174.5,163.37 175.08,163.37
A20GATE: length 93.1
  TOP w0.102: U29.N30 38.34,42.45 38,42.12 v3(37.99,42.12) ; R593.1 52.17,23.58 v1(52.17,22.81) 60.12,22.81 62.53,20.4 v1(62.53,18.57) ; U61.21 98.47,10.64 100.99,13.16 100.99,16.03 100.51,16.51 98.63,16.51 v1(97.99,17.14)
  BOTTOM w0.102: v3(37.99,42.12) 38.83,41.28 38.83,40.03 38.89,39.97 38.89,38.62 39.39,38.12 39.39,37.32 39.36,37.29 39.36,35.06 40.27,34.15 40.27,33.16 41.56,31.87 41.56,31.09 41.69,30.96 41.69,29.56 41.48,29.35 41.48,27.18 41.86,26.8 43.43,26.8 45.7,24.54 50.44,24.54 v1(52.17,22.81) ; v1(62.53,18.57) 62.53,18.62 v2(65.28,21.37) 65.71,21.79 80.11,21.79 81.18,20.73 84.29,20.73 85.28,19.74 91.99,19.74 93.18,18.54 96.6,18.54 v1(97.99,17.14)
ADDR: length 61.9
  TOP w0.203: 177.14,158.06 177.14,158.2 177.14,158.2 U52.12
  TOP w0.267: 175.62,156.54 177.14,158.06
  TOP w0.305: 175.62,156.54 v1(175.62,155.61) R239.1 ; U16.2 187.88,180.51 188.08,180.71 188.09,180.71 188.35,180.97 189.99,180.97 v1(192.91,183.9)
  BOTTOM w0.305: v1(175.62,155.61) v2(179.99,151.24) 180.96,150.27 186.56,150.27 193.89,157.6 193.89,182.92 v1(192.91,183.9)
ANTI-POP_GPIO1: length 4
  TOP w0.102: U2.4 16.11,231.73 15.33,230.95 13.78,230.95 TP40.1
ATX_ON*: length 7
  TOP w0.165: ATX1.16 188.45,52.87 185.55,49.97 C414.1 R489.2 R495.2
AUD_AVDD: length 4.7
  TOP w0.305: C13.1 23.93,236.63 23.51,236.21 U2.38 ; U2.25 26.35,227.73 26.8,227.28 v1(26.8,227.08)
  vias: v1(22.12,237.64) v2(23.57,234.54)
AUD_IN_L: length 3.5
  TOP w0.203: C11.1 v2(24.36,224.41) 24.36,224.65 23.76,225.25 23.76,225.25 23.51,225.5 U2.23
AUD_IN_LL: length 4.3
  TOP w0.203: R76.2 R77.1 43.7,222.86 43.95,223.11 v2(44.73,223.11) 45.5,223.11 L16.1
AUD_IN_LL_1: length 20.7
  TOP w0.203: v1(24.89,219.96) 24.8,219.96 24.36,220.4 C11.2 ; R76.1 41.55,221.13 v1(41.38,221.31)
  BOTTOM w0.203: v1(41.38,221.31) 40.61,222.07 v2(40.49,222.07) 40.21,222.07 39.29,221.16 26.09,221.16 v1(24.89,219.96)
AUD_IN_R: length 4.9
  TOP w0.203: U2.24 24.01,225.47 24.31,225.17 25.65,225.17 v2(26.31,224.51) C7.1
AUD_IN_RR: length 4.1
  TOP w0.203: R92.1 44.44,215.8 R91.2 44.49,215.75 v2(45.95,215.75) 47.33,215.75 L21.1
AUD_IN_RR_1: length 22.9
  TOP w0.203: R91.1 42.65,215.77 41.88,216.53 v1(41.88,220.01) ; v1(26.31,219.96) C7.2
  BOTTOM w0.203: v1(26.31,219.96) 28.14,219.96 28.75,220.57 v2(37.29,220.57) 39.98,220.57 40.19,220.78 41.12,220.78 v1(41.88,220.01)
AUD_LINK_BCLK: length 200.6
  TOP w0.102: U2.6 16.33,230.73 15.8,230.2 13.09,230.2 C59.1 12.89,230.01 12.34,230.56 9.88,230.56 v1(9.75,230.43) ; RN46.2 13.54,52.83 13,53.37 v1(13,53.47)
  BOTTOM w0.102: v1(13,53.47) 13,53.8 v2(11.18,55.63) 9.98,56.82 9.98,64.7 9.16,65.53 9.16,66.52 9.16,66.53 7.7,67.98 7.7,78.53 7.55,78.68 7.55,98.18 2.74,102.98 2.74,195.26 4.08,196.59 4.08,200.94 2.41,202.61 2.41,230.42 3.22,231.23 6.84,231.23 8.28,229.79 8.28,229.78 8.55,229.51 9.13,229.51 9.75,230.14 v1(9.75,230.43)
AUD_LINK_BCLK_R: length 15.1
  TOP w0.102: RN46.7 15.79,52.83 16.1,53.14 17.3,53.14 v2(17.45,52.98) 17.2,52.73 17.2,51.73 18.22,50.7 18.99,50.7 19.94,49.75 19.94,48.75 20.76,47.93 21.54,47.93 23.3,46.17 24.62,46.17 24.93,45.85 U29.AV23
AUD_LINK_RST_N: length 201.9
  TOP w0.102: v1(13.09,52.59) 13.35,52.33 RN46.3 ; U2.11 16.34,228.23 16.08,227.97 16.08,226.95 15.39,226.26 11.56,226.26 v1(9.7,228.12)
  BOTTOM w0.102: v1(13.09,52.59) 13.46,52.96 13.46,54.1 10.34,57.22 10.34,65.1 v2(9.96,65.48) 9.51,65.93 9.51,66.67 8.06,68.13 8.06,78.67 7.9,78.83 7.9,98.47 3.1,103.28 3.1,195.11 4.43,196.44 4.43,201.09 2.77,202.75 2.77,229.92 3.56,230.71 6.76,230.71 9.35,228.12 v1(9.7,228.12)
AUD_LINK_RST_R_N: length 14.4
  TOP w0.102: RN46.6 16.26,52.33 v2(16.33,52.4) 16.82,51.91 16.82,51.6 18.06,50.36 18.06,50.02 18.34,49.73 18.77,49.73 19.53,48.97 19.53,48.58 20.61,47.5 21.34,47.5 23.29,45.54 25.18,45.54 25.54,45.18 U29.AU24
AUD_LINK_SDIN: length 206.4
  TOP w0.102: U29.AT22 26.27,46.54 25.97,46.24 24.85,46.24 24.62,46.48 23.28,46.48 21.62,48.13 20.84,48.13 20.14,48.83 20.14,49.83 18.82,51.16 v1(18.47,51.16) ; v1(10.41,229.49) 10.41,229.08 11.28,228.22 R74.2
  BOTTOM w0.102: v1(10.41,229.49) 10.41,228.18 9.51,227.28 3.73,227.28 3.34,226.89 3.34,202.68 4.79,201.24 4.79,196.29 3.45,194.96 3.45,105.39 8.26,100.58 8.26,78.97 8.41,78.82 8.41,68.27 9.03,67.65 9.04,67.65 9.87,66.82 9.87,66.33 11.32,64.88 11.32,64.01 11.05,63.73 11.05,57.51 15.9,52.66 15.9,52.26 17.28,50.88 v2(17.53,50.88) 18.18,50.88 v1(18.47,51.16)
AUD_LINK_SDIN_1: length 13.2
  TOP w0.102: U2.8 15.43,229.73 15.37,229.67 14.88,229.67 14.76,229.54 14.76,229.31 v2(14.99,229.08) 14.99,228.73 14.62,228.36 14.3,228.36 14.17,228.49 14.17,229.72 14.05,229.84 13.72,229.84 13.59,229.72 13.59,229.51 13.46,229.39 11.1,229.39 10.97,229.26 10.97,229.03 11.15,228.85 13.46,228.85 13.59,228.73 13.59,228.37 13.44,228.22 R74.1
AUD_LINK_SDO: length 202.6
  TOP w0.102: v1(11.9,53.06) 11.9,53.4 12.45,53.95 13.23,53.95 13.7,53.48 RN46.1 ; U2.5 16.14,231.23 15.51,230.59 13.4,230.59 13.03,230.96 v1(8.81,230.96)
  BOTTOM w0.102: v1(11.9,53.06) 11.9,53.37 v2(11.4,53.87) 9.25,56.03 9.25,64.19 8.45,64.99 8.45,65.94 8.45,66.23 6.99,67.68 6.99,75.63 6.27,76.35 6.27,97.8 2.03,102.04 2.03,195.55 3.37,196.88 3.37,200.65 1.7,202.31 1.7,230.72 2.93,231.95 7.83,231.95 v1(8.81,230.96)
AUD_LINK_SDO_R: length 23.1
  TOP w0.102: Q82.C 10.99,54.97 10.6,54.58 R456.2 10.72,53.47 v2(12.55,55.3) 12.64,55.38 R618.1 15.04,53.91 RN46.8 15.62,53.48 R20.2 16.19,54.01 16.66,53.54 17.83,53.54 19.95,51.43 19.95,50.89 20.32,50.51 20.43,50.51 23.57,47.37 24.62,47.37 25.24,46.75 25.57,46.75 U29.AU22
AUD_LINK_SDO_R1: length 26
  TOP w0.102: v1(11.44,52.33) 11.44,53.44 12.5,54.5 R618.2
  BOTTOM w0.102: v1(11.44,52.33) 10.64,53.13 10.64,53.87 v2(9.27,55.24) 8.89,55.62 8.89,57.72 8.89,64.03 8.09,64.83 8.09,65.74 8.09,66.08 6.64,67.54 6.64,70.84 MECLR1.2
AUD_LINK_SYNC: length 204.7
  TOP w0.102: v1(12.3,52.24) 12.57,51.97 12.93,51.97 13.22,51.68 RN46.4 ; U2.10 16.33,228.73 15.72,228.12 15.72,227.2 15.14,226.62 11.89,226.62 8.74,229.77 v1(8.74,229.97)
  BOTTOM w0.102: v1(12.3,52.24) 12.36,52.31 12.36,53.68 9.6,56.44 9.6,64.46 8.8,65.27 8.8,66.08 8.8,66.08 8.8,66.38 8.59,66.59 8.59,66.59 7.35,67.83 7.35,77.49 6.86,77.98 v2(6.86,80.09) 6.86,98.02 2.39,102.49 2.39,195.4 3.72,196.74 3.72,200.79 2.06,202.46 2.06,230.57 3.08,231.59 7.12,231.59 v1(8.74,229.97)
AUD_LINK_SYNC_R: length 12.9
  TOP w0.102: U29.AV24 24.82,45.33 23.12,45.33 21.18,47.27 20.55,47.27 19.07,48.75 19.07,48.93 18.62,49.38 18.19,49.38 17.7,49.87 17.7,50.21 16.42,51.5 v1(15.9,51.5) 15.84,51.5 15.66,51.68 RN46.5
AUD_MIC2_L: length 4.1
  TOP w0.203: U2.16 20.01,225.17 v2(19.25,224.41) 18.03,223.19 C41.1
AUD_MIC2_L_C: length 19.9
  TOP w0.203: R48.1 34.39,220.46 34.39,219.33 v1(34.32,219.25) ; C41.2 17.78,219.78 v1(17.91,219.66)
  BOTTOM w0.203: v1(17.91,219.66) v2(18.85,219.66) 22.23,219.66 23.12,218.77 33.83,218.77 v1(34.32,219.25)
AUD_MIC2_R: length 3.3
  TOP w0.203: C37.1 20.51,223.89 v2(20.51,224.42) U2.17
AUD_MIC2_R_C: length 20.1
  TOP w0.203: v1(35.36,219.35) 35.45,219.44 R26.1 ; v1(20.07,218.57) 19.81,218.82 C37.2
  BOTTOM w0.203: v1(35.36,219.35) 35.36,219.09 34.45,218.19 v2(34.45,218.19) 34.06,218.19 33.97,218.1 20.54,218.1 v1(20.07,218.57)
AUD_MIC_2L: length 10.3
  TOP w0.203: AUDJK1.2 47.33,236.7 Q17.2 44.12,237.9 44.12,236.74 C73.2 FL1.2
AUD_MIC_2R: length 20.6
  TOP w0.203: AUDJK1.5 57.19,234.7 48.95,234.7 46.89,232.64 FL2.2 C80.2 46.13,234.38 46.13,235.93 Q17.1
AUD_REGREF: length 3.8
  TOP w0.305: v2(14.99,231.48) 15.07,231.48 15.82,232.23 U2.3
  TOP w0.508: v2(14.99,231.48) 14.73,231.74 C57.1
AUDAMPIN_L: length 27.8
  TOP w0.203: 37.72,216.66 37.72,220.98 38.58,221.84 v1(38.58,222.43) ; v1(27.53,235.15) 26.9,234.52 26.9,233.4 26.49,232.99 26.49,232.98 26.24,232.73 U2.35
  BOTTOM w0.203: v1(38.58,222.43) 38.58,223.7 v2(38.56,223.72) 37.36,223.72 27.53,233.55 v1(27.53,235.15)
AUDAMPIN_L_C: length 5.5
  TOP w0.203: R53.1 v1(40.51,220.07) 40.51,216.92 TC5.2
AUDAMPIN_R: length 27.6
  TOP w0.203: v1(32.77,222.5) 32.77,220.37 29.08,216.69 TC6.1 ; v1(27.55,236.02) 26.44,234.9 26.44,233.48 26.19,233.23 U2.36
  BOTTOM w0.203: v1(27.55,236.02) 27.51,236.02 26.97,235.48 26.97,233.4 32.77,227.61 v1(32.77,222.5)
AUDAMPIN_R_C: length 14.8
  TOP w0.203: R52.1 38.86,221.42 38.86,216.03 37.67,214.83 v1(34.72,214.83) 33.45,214.83 TC6.2
AUDIN_L: length 9.4
  TOP w0.203: Q11.2 45.97,220.63 L16.2 46,221.78 C55.1 47.71,221.78 49.23,223.29 49.23,225.49 AUDJK1.32
AUDIN_R: length 17.2
  TOP w0.203: AUDJK1.35 47.99,216.75 L21.2 46.46,216.75 C60.1 46.32,216.89 Q11.1
AUDIO_VREF: length 3.8
  TOP w0.305: U2.27 26.39,228.73 26.73,228.38
  TOP w0.508: 26.73,228.38 27.03,228.09 v2(27.43,228.09) 28.19,227.33 C1.1
BL_CUT1: length 3.2
  TOP w0.102: Q40.2 191.3,120.31 191.83,120.84 v2(191.83,121.41) R402.1
BL_CUT2: length 5.5
  TOP w0.165: R419.2 v2(191.82,119.25) 191.41,119.66 Q40.1 189.66,119.66 189.48,119.84 189.48,120.75 189.69,120.96 Q40.3
BL_CUT3: length 4.1
  TOP w0.102: R404.2 185.67,119.89 186.06,119.51 v1(186.83,119.51) 187.2,119.88 R401.1 187.22,120.31 Q40.5
BLUE_CRT: length 9.6
  TOP w0.102: VGA1.3 79.32,234.06 U1.3 79.06,233.11 78.61,232.66 78.36,231.78 78.36,229.93 C22.1 78.11,229.68 L5.2
BOARD_ID_0: length 15
  TOP w0.102: R651.2 R650.1 45.99,28.64 v2(43.64,30.99) 43.08,31.55 43.05,31.55 42.76,31.84 42.76,32.69 41.31,34.13 40.4,34.13 39.36,35.17 39.36,36.47 39.45,36.56 39.45,37.95 U29.M37
BOARD_ID_1: length 13.8
  TOP w0.102: U29.AA40 34.1,36.73 34.1,35.2 34.72,34.57 34.72,33.17 35.61,32.28 35.61,31.19 36.86,29.95 36.86,27.05 36.45,26.64 v2(36.45,26.31) 36.45,25.59 R403.1 R405.2
BT_RADIO_CL: length 116.7
  TOP w0.102: MINI1.51 32.86,144.75 32.23,144.12 32.23,138.81 32.52,138.53 32.52,137.27 32.03,136.78 32.03,115.93 31.56,115.46 24.55,115.46 13.31,104.22 13.31,99.87 v1(11.3,97.87) ; U29.AV9 25.22,53.44 24.33,54.33 22.76,54.33 22.72,54.3 22.35,54.3 22.32,54.33 21.89,54.33 21.72,54.5 21.58,54.5 20.57,55.5 18.67,55.5 18.57,55.6 15.52,55.6 15.2,55.28 R420.1 14.41,55.28 13.18,56.52 v1(13.18,57.23)
  BOTTOM w0.102: v1(13.18,57.23) 12.9,57.51 12.9,66.51 11.3,68.11 v2(11.3,73.53) v1(11.3,97.87)
BV_5VDUAL_BACKFEED_CUT_L: length 4.5
  TOP w0.165: R2237.1 v2(181.09,38.99) 180.91,39.17 179.46,39.17 R465.1 177.95,38.8 R466.2
BV_Q49_PIN5: length 2.8
  TOP w0.165: Q49.2 176.86,37.47 176.05,38.28 v2(176.05,38.48) 176.3,38.73 R466.1
BZ_ON: length 6.5
  TOP w0.305: R653.1 R654.1 64.96,59.94 Q53.C 63.44,59.88 v2(62.48,60.83)
BZ_ON1: length 21.4
  TOP w0.305: BZ1.2 84.02,61.95 78.33,56.26 70.76,56.26 R653.2 R654.2
CHASSIS_ID_0: length 129.2
  TOP w0.102: v1(17.65,39.62) 18.11,39.62 18.47,39.27 18.91,39.27 19.03,39.15 19.63,39.15 19.89,39.41 19.89,39.42 20.25,39.78 21.35,39.78 22.27,40.69 23.78,40.69 24.08,40.99 24.59,40.99 24.61,40.97 25.04,40.97 25.25,41.02 25.26,41.02 25.54,41.1 26.09,41.1 U29.AT31 ; v1(17.09,17.83) 17.08,17.82 14.24,17.82 13.02,19.04 11.28,19.04 9.63,17.39 8.91,17.39 8.47,17.83 7.17,17.83 LEDH1.8 7.09,18.63 7.09,21.06 6.58,21.57 5.99,21.57 4.95,22.61 4.95,24.09 6.98,26.11 v1(7,26.11) ; v1(64.08,18.01) 64.08,18.21 65.1,19.23 65.1,20.82 63.12,22.81 62.97,22.81 61.22,24.56 61.22,24.58 58.16,27.65 56.27,27.65 v1(55.73,28.19) ; v1(47.68,32.62) 48.41,32.62 48.77,32.26 R613.1
  BOTTOM w0.102: v1(17.65,39.62) 16.24,39.62 12.99,36.37 12.27,36.37 11.38,35.48 9.67,35.48 9.04,34.86 9.04,30.77 8.47,30.2 8.47,29.53 7,28.06 v1(7,26.11) ; v1(55.73,28.19) 55.69,28.23 v2(53.62,28.23) 51.51,28.23 50.66,29.08 50.59,29.08 47.68,31.98 v1(47.68,32.62) ; v1(64.08,18.01) 52.09,18.01 51.61,17.53 44.6,17.53 41.91,20.21 29.51,20.21 29.2,19.9 27.6,19.9 26.11,18.41 24.41,18.41 24.14,18.15 20.73,18.15 20.03,17.45 19.65,17.45 19.57,17.53 17.4,17.53 v1(17.09,17.83)
CHASSIS_ID_1: length 40.3
  TOP w0.102: v3(27.05,42.55) 27.12,42.63 U29.AP28 ; v1(16.51,40.98) 15.94,40.4 R584.1 ; v1(7.48,30.25) 7.02,29.79 7.02,29.1 8.72,27.4 8.72,24.04 8.39,23.71 8.39,22.75 9.27,21.87 LEDH1.9
  BOTTOM w0.102: v1(7.48,30.25) 7.49,30.26 7.49,30.58 8.08,31.17 8.08,36.17 v2(8.51,36.6) 9.78,37.87 11.71,37.87 12.65,38.81 13.33,38.81 15.49,40.98 v1(16.51,40.98) 19.51,40.98 20.32,41.78 23.42,41.78 24.05,42.42 26.92,42.42 v3(27.05,42.55)
CK_14M_FLEX3: length 21.2
  TOP w0.102: U29.AU8 25.78,53.7 v3(25.93,53.54) ; v1(22.2,56.46) 22.2,56.68 20.81,58.06 18.54,58.06 17.17,56.69 15.31,56.69 13.97,58.03 13.97,58.69 C3323.2 12.97,58.72 11.14,58.72 R153.2
  BOTTOM w0.102: v3(25.93,53.54) 25.93,54.99 24.71,56.21 22.33,56.21 22.2,56.34 v1(22.2,56.46)
CK_14M_TPM: length 331.8
  TOP w0.102: v1(137.73,52.82) 138.62,52.82 147.68,43.76 v1(153.82,43.76) ; v1(8.03,59.33) 8.15,59.21 R153.1 ; U23.13 U22.13 95.88,62.31 95.48,62.71 v1(95.4,62.71)
  BOTTOM w0.102: v1(137.73,52.82) 137.26,52.35 135.9,52.35 129.05,45.51 129.05,44.8 128.07,43.82 128.03,43.82 126.5,42.29 125.58,42.29 125.37,42.09 109.63,42.09 108.79,42.93 108.79,62.36 107.98,63.17 102.62,63.17 100.69,65.1 96.06,65.1 95.4,64.44 v1(95.4,62.71) ; v1(153.82,43.76) 154.06,43.52 154.06,32.85 138.2,16.99 135.77,16.99 127.51,8.74 113.96,8.74 112.56,7.34 105.11,7.34 103.98,8.47 99.33,8.47 98.76,7.9 98.26,7.9 98.08,8.08 96.57,8.08 96.11,8.53 84.91,8.53 83.98,7.61 60.63,7.61 58.73,9.51 41.91,9.51 41.24,10.18 41.24,10.18 38.82,12.6 33.71,12.6 33.21,12.09 32.9,12.09 30.07,9.27 30.07,5 27.68,2.6 12.41,2.6 11.42,3.59 10.3,3.59 8.02,5.87 7.69,5.87 2.77,10.79 2.77,43.45 4.38,45.06 v2(4.67,45.06) 6.58,46.96 6.58,49.8 7.3,50.52 7.51,50.73 7.51,53.97 7.16,54.31 7.16,58.47 v1(8.03,59.33)
CK_33M_PCI0: length 18.2
  TOP w0.102: U29.AV5 24.92,55.45 24.18,55.45 22.45,57.18 22.45,58.21 21.2,59.46 19.51,59.46 v2(18.95,60.02) 18.55,60.41 18.12,60.41 17.12,61.42 14.36,61.42 C3316.2 12.97,61.85 11.14,61.85 R408.2
CK_33M_PCI1: length 19.4
  TOP w0.102: U29.AV7 25.03,55.03 24.86,55.03 24.64,55.24 24.08,55.24 20.7,58.62 v2(20.52,58.62) 18.57,58.62 16.99,57.05 15.46,57.05 14.33,58.18 14.33,59.37 C3322.2 12.97,59.77 11.14,59.77 R421.2
CK_33M_PCI2: length 24.8
  TOP w0.102: U29.AU2 26.05,57.49 26.05,58.84 26.07,58.86 26.07,59.2 26.05,59.22 v1(26.05,59.94) ; R396.2 11.14,62.89 12.97,62.89 C3317.2 14,63.37 14.33,63.04 14.33,62.03 14.58,61.77 21.41,61.77 v1(22,61.19)
  BOTTOM w0.102: v1(26.05,59.94) v2(24.81,61.19) 22.73,61.19 22.61,61.31 22.61,61.48 22.73,61.59 23.93,61.59 24.03,61.7 24.03,61.9 23.93,62 22.2,62 22,61.8 v1(22,61.19)
CK_33M_PCI3: length 22.6
  TOP w0.102: U29.AN9 27.21,52.65 v3(27.05,52.65) ; v1(22,57.99) 20.8,59.18 18.83,59.18 16.97,61.04 13.7,61.04 C3318.2 12.97,60.81 11.14,60.81 R406.2
  BOTTOM w0.102: v1(22,57.99) 23.2,56.78 v2(24.24,56.78) 24.52,56.78 26.7,54.61 26.79,54.61 27.42,53.98 27.42,53.33 27.05,52.96 v3(27.05,52.65)
CK_48M_PCH: length 20.2
  TOP w0.102: U29.AT9 26.44,53.67 26.09,54.03 26.09,54.26 25.91,54.44 25.65,54.44 25.57,54.36 25.24,54.36 24.59,55.01 23.98,55.01 22.99,56.01 22,56.01 21.74,56.26 21.74,56.85 20.9,57.68 18.75,57.68 17.2,56.13 v2(16.21,56.13) 15.37,56.13 13.45,58.05 C3319.2 12.97,57.68 11.14,57.68 R407.2
CK_48M_SIO2: length 161.3
  TOP w0.102: R407.1 8.33,58.17 v1(8.03,58.47) ; U61.24 99.67,8.94 99.09,8.36 v1(98.53,8.36)
  BOTTOM w0.102: v1(8.03,58.47) 7.54,57.99 7.54,54.43 7.86,54.12 7.86,50.58 7.44,50.17 6.93,49.66 6.93,46.82 5.44,45.32 5.44,43.51 v2(4.34,42.42) 3.76,41.83 3.76,40.61 3.12,39.97 3.12,10.93 7.83,6.22 8.17,6.22 10.21,4.18 11.34,4.18 12.56,2.96 26.05,2.96 28.85,5.77 28.85,8.55 32.75,12.45 33.06,12.45 33.61,13 38.92,13 42.05,9.87 58.88,9.87 60.78,7.97 83.84,7.97 84.8,8.93 96.22,8.93 96.68,8.47 98.41,8.47 v1(98.53,8.36)
CK_96M_DREF_DN: length 12.2
  TOP w0.102: v1(22.02,55.22) 21.72,55.22 20.94,56 20.94,56.65 20.76,56.84 RN34.2 ; v3(27.88,52.63) 27.44,52.19 U29.AP11
  BOTTOM w0.102: 24.74,54.96 v2(24.97,55.19) ; 24.74,54.96 23.96,55.74 22.84,55.74 22.32,55.22 v1(22.02,55.22) ; 24.74,54.96 25.25,54.45 25.25,53.51 26.54,52.22 27.75,52.22 27.88,52.35 v3(27.88,52.63)
CK_96M_DREF_DP: length 12.6
  TOP w0.102: RN34.1 20.39,56.19 20.76,55.82 21.84,54.74 v1(22.54,54.74) ; U29.AM11 28.2,52.31 v3(28.53,52.64)
  BOTTOM w0.102: v1(22.54,54.74) 22.54,55.07 22.95,55.49 23.85,55.49 24.99,54.35 24.99,53.41 25.65,52.75 ; v3(28.53,52.64) 27.86,51.96 26.44,51.96 25.65,52.75 ; 25.65,52.75 v2(25.43,52.53)
CK_100M_CPU_XDP_DN: length 374.3
  TOP w0.102: R820.1 191.56,145.97 191.87,145.97 192.01,146.11 v1(192.01,146.39) ; v3(35.79,54.84) 36.17,55.22 U29.U6 ; v1(23.7,100.22) 23.7,99.92 23.8,99.82 24.13,99.82 24.35,100.04 24.35,102.18 28.52,106.35 31.95,106.35 36.97,111.37 36.97,128.56 49.15,140.74 49.15,173.79 43.31,179.63 42.21,179.63 42.13,179.55 v1(42.13,179.25)
  BOTTOM w0.102: 57.3,194.28 70.51,207.49 89.67,207.49 91.65,209.47 143.97,209.47 159.03,194.41 175.21,194.41 178.97,198.17 181.76,198.17 183.81,196.12 190.51,196.12 191.59,195.04 191.59,192.68 192.1,192.18 192.1,186.92 194.55,184.47 194.55,157.32 192.79,155.56 192.79,152.97 192.46,152.64 192.46,150.19 193.17,149.48 193.17,146.16 192.93,145.92 192.22,145.92 192.01,146.14 v1(192.01,146.39) ; 57.3,194.28 v2(57.53,194.06) ; 57.3,194.28 42.26,179.25 v1(42.13,179.25) ; v1(23.7,100.22) 23.7,99.95 23.83,99.82 24.31,99.82 24.58,99.55 24.58,97.98 24.28,97.68 24.28,67.78 33.53,58.54 33.53,58.14 34.67,57 34.67,56.16 35.46,55.37 35.46,54.99 35.61,54.84 v3(35.79,54.84)
CK_100M_CPU_XDP_DP: length 374.3
  TOP w0.102: v1(23.68,99.36) 23.89,99.57 24.24,99.57 24.6,99.93 24.6,102.07 28.63,106.1 32.05,106.1 37.22,111.26 37.22,128.46 49.4,140.64 49.4,173.89 43.41,179.88 42.51,179.88 v1(42.3,180.09) ; v3(35.79,54.15) 36.09,54.45 U29.U7 ; v1(192.02,145.5) 191.8,145.72 191.39,145.72 R821.1
  BOTTOM w0.102: v1(23.68,99.36) 23.89,99.57 24.21,99.57 24.33,99.45 24.33,98.09 24.03,97.79 24.03,67.68 33.27,58.43 33.27,58.04 33.73,57.58 ; v1(42.3,180.09) 42.75,180.09 70.4,207.75 89.57,207.75 91.55,209.73 144.07,209.73 159.13,194.67 175.11,194.67 178.87,198.42 181.86,198.42 183.92,196.37 190.61,196.37 191.85,195.14 191.85,192.79 192.35,192.28 192.35,187.02 194.81,184.57 194.81,157.22 193.04,155.45 193.04,152.87 192.71,152.54 192.71,150.3 193.42,149.58 193.42,146.05 193.04,145.67 192.19,145.67 v1(192.02,145.5) ; 33.73,57.58 34.42,56.89 34.42,56.05 35.2,55.27 35.2,54.74 v3(35.79,54.15) ; 33.73,57.58 v2(33.5,57.35)
CK_CSI_PCH_IN_DN: length 11.3
  TOP w0.102: RN31.1 49.47,53.69 49.19,53.42 49.03,53.42 v1(48.69,53.75) ; U29.G16 41.68,49.87 v3(41.39,50.16)
  BOTTOM w0.102: v2(47.7,53.75) 47.7,53.42 ; 47.7,53.42 48.35,53.42 v1(48.69,53.75) ; 47.7,53.42 45.94,53.42 44.07,51.54 43.26,51.54 42.74,51.02 41.92,51.02 41.66,50.75 41.66,50.42 v3(41.39,50.16)
CK_CSI_PCH_IN_DP: length 10.8
  TOP w0.102: U29.F16 42.4,49.92 v3(42.16,50.16) ; v1(48.69,52.83) 49.03,53.16 49.31,53.16 49.43,53.04 RN31.2
  BOTTOM w0.102: v2(45.14,51.82) 44.92,52.03 ; 44.92,52.03 44.17,51.28 43.36,51.28 42.84,50.76 42.03,50.76 41.91,50.64 41.91,50.41 v3(42.16,50.16) ; 44.92,52.03 46.05,53.16 48.35,53.16 v1(48.69,52.83)
CK_DP_DN: length 156.7
  TOP w0.102: v1(99.78,152.68) 100.1,152.68 100.23,152.81 U27.U5 ; v1(45.19,130.33) 44.96,130.56 44.78,130.56 44.68,130.45 44.68,129.05 40.51,124.89 40.51,104.55 28.63,92.66 28.63,76.57 29.38,75.81 34.7,70.5 34.7,68.87 36.65,66.92 36.65,60.25 36.88,60.02 36.88,59.17 36.59,58.88 36.59,57.59 36.55,57.51 36.52,57.35 36.54,57.28 36.65,57 36.72,56.79 36.76,56.65 U29.T3
  BOTTOM w0.102: 73.99,155.02 73.61,155.02 72.94,154.35 64.55,154.35 44.68,134.47 44.68,130.45 44.81,130.33 v1(45.19,130.33) ; 73.99,155.02 88.26,155.02 90.54,152.74 96.49,152.74 96.65,152.9 99.16,152.9 99.5,153.24 100.02,153.24 100.23,153.03 100.23,152.76 100.15,152.68 v1(99.78,152.68) ; 73.99,155.02 v2(73.99,154.69)
CK_DP_DP: length 156.7
  TOP w0.102: U27.U6 v1(100.68,152.7) ; v1(44.22,130.35) 44.42,130.15 44.42,129.16 40.26,124.99 40.26,104.65 28.37,92.76 28.37,76.46 29.96,74.87 34.44,70.39 34.44,68.77 36.4,66.81 36.4,60.14 36.63,59.91 36.63,59.28 36.39,59.04 36.39,57.67 36.32,57.52 36.31,57.32 36.32,57.23 36.36,57.14 36.45,56.94 36.45,56.92 36.47,56.72 36.47,56.14 U29.T5
  BOTTOM w0.102: v1(44.22,130.35) 44.42,130.56 44.42,131.52 ; 44.42,131.52 44.42,134.58 64.45,154.6 72.83,154.6 73.5,155.28 88.36,155.28 90.65,152.99 96.38,152.99 96.55,153.16 99.06,153.16 99.39,153.49 100.13,153.49 100.48,153.14 100.48,152.9 v1(100.68,152.7) ; 44.42,131.52 v2(44.07,131.52)
CK_DPNS_R_DN: length 156.8
  TOP w0.102: U29.W2 35.45,57.33 35.45,66.61 33.63,68.43 33.63,70.02 27.56,76.09 27.56,93.17 39.37,104.98 39.37,127.61 45.82,134.06 47.35,134.06 47.8,133.6 47.8,133.1 v1(47.98,132.92) ; U27.W6 101.59,150.88 v1(101.6,150.88)
  BOTTOM w0.102: 73.48,152.25 74.05,152.25 75.15,153.36 81.94,153.36 84.67,150.63 98.08,150.63 98.55,150.16 100.15,150.16 100.4,150.41 101.14,150.41 v1(101.6,150.88) ; 73.48,152.25 v2(73.48,151.94) ; 73.48,152.25 64.79,152.25 48.02,135.49 47.8,135.27 47.8,133.1 v1(47.98,132.92)
CK_DPNS_R_DP: length 156.8
  TOP w0.102: U27.W5 100.54,151.33 100.68,151.18 v1(100.68,150.87) ; v1(47,132.99) 47.46,132.99 47.55,133.07 47.55,133.5 47.24,133.81 45.92,133.81 39.62,127.51 39.62,104.88 27.81,93.07 27.81,76.2 33.88,70.13 33.88,68.54 35.7,66.72 35.7,57.52 35.76,57.45 35.76,57.29 U29.U2
  BOTTOM w0.102: v1(47,132.99) 47.39,132.99 47.55,133.15 47.55,134.44 ; v1(100.68,150.87) 100.48,150.67 100.3,150.67 100.05,150.42 98.66,150.42 98.19,150.89 84.78,150.89 82.05,153.61 75.05,153.61 73.94,152.51 64.68,152.51 47.55,135.38 47.55,134.44 ; 47.55,134.44 v2(47.22,134.44)
CK_GLAN_DN: length 309.9
  TOP w0.102: U12.16 168.55,209.42 168.62,209.5 168.62,209.66 167.18,211.1 167.18,212.11 167,212.29 v1(166.71,212.29) ; v3(32.7,52.53) 32.91,52.32 U29.AC11
  BOTTOM w0.102: v3(32.7,52.53) 31.85,52.53 31.57,52.8 31.57,58.26 21.62,68.22 21.62,105.77 ; v1(166.71,212.29) 166.87,212.45 167.23,212.45 167.74,212.95 167.74,214.23 165.1,216.87 139.21,216.87 135.73,213.39 67.47,213.39 66.86,214 60.22,214 52.34,206.12 36.88,206.12 27.58,196.82 27.58,192.71 25.1,190.22 25.1,187.96 22.33,185.2 22.33,167.23 21.62,166.52 21.62,105.77 ; 21.62,105.77 v2(21.26,105.77)
CK_GLAN_DP: length 310
  TOP w0.102: v1(166.8,213.26) 166.8,212.85 167.44,212.22 167.44,211.21 168.88,209.77 168.88,209.5 168.95,209.42 U12.15 ; U29.AC10 33.13,52.93 32.87,52.93 32.69,53.11 v3(32.69,53.29)
  BOTTOM w0.102: 39.98,205.87 v2(39.98,205.55) ; 39.98,205.87 52.45,205.87 60.32,213.74 66.75,213.74 67.36,213.13 135.84,213.13 139.32,216.61 165,216.61 167.49,214.12 167.49,213.06 167.13,212.7 166.95,212.7 166.8,212.85 v1(166.8,213.26) ; 39.98,205.87 36.99,205.87 27.84,196.72 27.84,192.6 25.35,190.12 25.35,187.86 22.58,185.09 22.58,167.13 21.87,166.42 21.87,68.33 31.83,58.37 31.83,52.91 31.95,52.78 32.23,52.78 32.36,52.91 32.36,53.16 32.49,53.29 v3(32.69,53.29)
CK_M_DDR0_A_DN: length 42.1
  TOP w0.102: U27.AY16 112.13,130.86 112.13,130.44 111.91,130.21 111.91,129.43 111.53,129.05 111.53,128.95 111.51,128.93
  TOP w0.152: 109.29,102.38 109.32,102.35 109.32,102.29 110.05,101.56 110.05,100.1 109.37,99.42 109.37,99.36 109.35,99.33
  TOP w0.216: 111.51,128.93 110.18,127.6 110.18,110.7 109.76,110.29 109.44,110.29 109.23,110.07 109.23,109.64 109.44,109.42 109.76,109.42 110.18,109.01 110.18,108 109.8,107.62 108.96,107.62 108.81,107.46 108.81,102.86 109.29,102.38 ; DIMM1.185 106.76,95.67 107.57,95.67 108.24,96.34 108.24,96.62 108.24,97.36 109.17,98.29 109.17,99.15 109.35,99.33
CK_M_DDR0_A_DP: length 42
  TOP w0.102: 111.26,129.17 111.28,129.19 111.38,129.19 111.7,129.51 111.7,130.3 111.93,130.53 111.93,131.11 111.83,131.21 U27.AY15
  TOP w0.152: 109.1,99.58 109.13,99.6 109.19,99.6 109.79,100.2 109.79,101.45 109.14,102.11 109.07,102.11 109.05,102.14
  TOP w0.216: 111.26,129.17 109.83,127.74 109.83,110.85 109.62,110.63 109.3,110.63 108.88,110.21 108.88,109.5 109.3,109.08 109.62,109.08 109.83,108.86 109.83,108.14 109.66,107.96 108.82,107.96 108.46,107.61 108.46,102.72 108.62,102.56 108.67,102.51 108.78,102.4 109.05,102.14 ; DIMM1.184 106.63,96.44 106.63,96.13 106.75,96.01 107.43,96.01 107.89,96.48 107.89,97.5 108.82,98.43 108.82,99.3 108.95,99.42 109.1,99.58
CK_M_DDR0_B_DN: length 64.6
  TOP w0.216: U27.AM21 v1(117.51,138.98)
  L3 w0.102: v1(117.51,138.98) 117.17,138.64 117.17,138.4 118.19,137.39 118.19,132.09 117.81,131.71 117.81,131.63 117.79,131.61
  L3 w0.191: 117.79,131.61 117.44,131.27 117.44,125.68 112.77,121.01 112.36,120.6 112.36,114.93 112.03,114.6 111.6,114.6 111.41,114.41 111.41,114.03 111.6,113.84 112.03,113.84 112.38,113.49 112.38,112.79 112.03,112.44 111.6,112.44 111.41,112.25 111.41,111.87 111.6,111.68 112.03,111.68 112.38,111.33 112.38,110.63 112.03,110.28 111.59,110.28 111.4,110.09 111.4,105.82 111.59,105.63 111.92,105.63 112.36,105.19 112.36,102.3 111.68,101.63 110.89,101.63 110.24,100.98 110.24,100.09 109.19,99.03 109.19,98.35 108.15,97.31 108.15,96.4 107.13,95.39 107.13,94.43 108.21,93.35 108.21,92.24 109.16,91.29 109.16,91.03 109.16,90.42 108.13,89.4 108.13,88.37 107.29,87.53 106.52,87.53 DIMM2.185
CK_M_DDR0_B_DP: length 64.6
  TOP w0.216: U27.AM20 v1(116.6,138.98)
  L3 w0.102: v1(116.6,138.98) 116.97,138.62 116.97,138.32 117.98,137.3 117.98,132.18 117.66,131.86 117.58,131.86 117.56,131.84
  L3 w0.191: 117.56,131.84 117.13,131.4 117.13,125.81 112.64,121.33 112.04,120.73 112.04,115.06 111.9,114.92 111.47,114.92 111.09,114.54 111.09,113.9 111.47,113.52 111.9,113.52 112.06,113.36 112.06,112.93 111.9,112.76 111.47,112.76 111.09,112.38 111.09,111.74 111.47,111.36 111.9,111.36 112.06,111.2 112.06,110.77 111.9,110.6 111.46,110.6 111.08,110.22 111.08,105.68 111.46,105.31 111.79,105.31 112.04,105.05 112.04,102.43 111.55,101.94 110.76,101.94 109.92,101.11 109.92,100.22 108.87,99.17 108.87,98.48 107.83,97.44 107.83,96.53 106.81,95.52 106.81,94.3 107.89,93.22 107.89,92.11 108.84,91.16 108.84,90.55 107.82,89.53 107.82,88.5 107.16,87.85 106.87,87.85 106.55,88.16 106.55,88.46 DIMM2.184
CK_M_DDR1_A_DN: length 42.9
  TOP w0.102: U27.AV15 111.34,133.04 111.21,132.91 111.21,132.06 111.01,131.86 111.01,130.93 111.15,130.79 111.15,130.25 110.71,129.81 110.61,129.81 110.59,129.79
  TOP w0.216: 110.59,129.79 110.08,129.28 109.11,129.28 108.69,128.86 108.69,118.3 108.36,117.97 106.92,117.97 106.55,117.6 106.55,116.59 106.96,116.17 107.96,116.17 108.17,115.96 108.17,115.52 107.96,115.31 106.96,115.31 106.55,114.89 106.55,114.18 106.96,113.76 107.43,113.76 107.65,113.54 107.65,113.11 107.43,112.9 106.96,112.9 106.55,112.48 106.55,111.76 106.96,111.35 107.43,111.35 107.65,111.13 107.65,110.7 107.43,110.48 106.96,110.48 106.55,110.07 106.55,103.01 107.92,101.63 107.92,100.92 107.66,100.65 DIMM1.64
CK_M_DDR1_A_DP: length 43
  TOP w0.102: U27.AW15 111.21,131.77 111.21,131.01 111.36,130.87 111.36,130.17 110.86,129.67 110.86,129.57 110.84,129.55
  TOP w0.216: 110.84,129.55 110.22,128.94 109.25,128.94 109.03,128.72 109.03,118.16 108.5,117.63 107.06,117.63 106.89,117.45 106.89,116.73 107.1,116.51 108.1,116.51 108.51,116.1 108.51,115.38 108.1,114.97 107.1,114.97 106.89,114.75 106.89,114.32 107.1,114.1 107.58,114.1 107.99,113.69 107.99,112.97 107.58,112.55 107.1,112.55 106.89,112.34 106.89,111.9 107.1,111.69 107.58,111.69 107.99,111.27 107.99,110.56 107.58,110.14 107.1,110.14 106.89,109.92 106.89,103.15 108.27,101.77 108.27,100.78 108.04,100.55 108.04,98.75 DIMM1.63
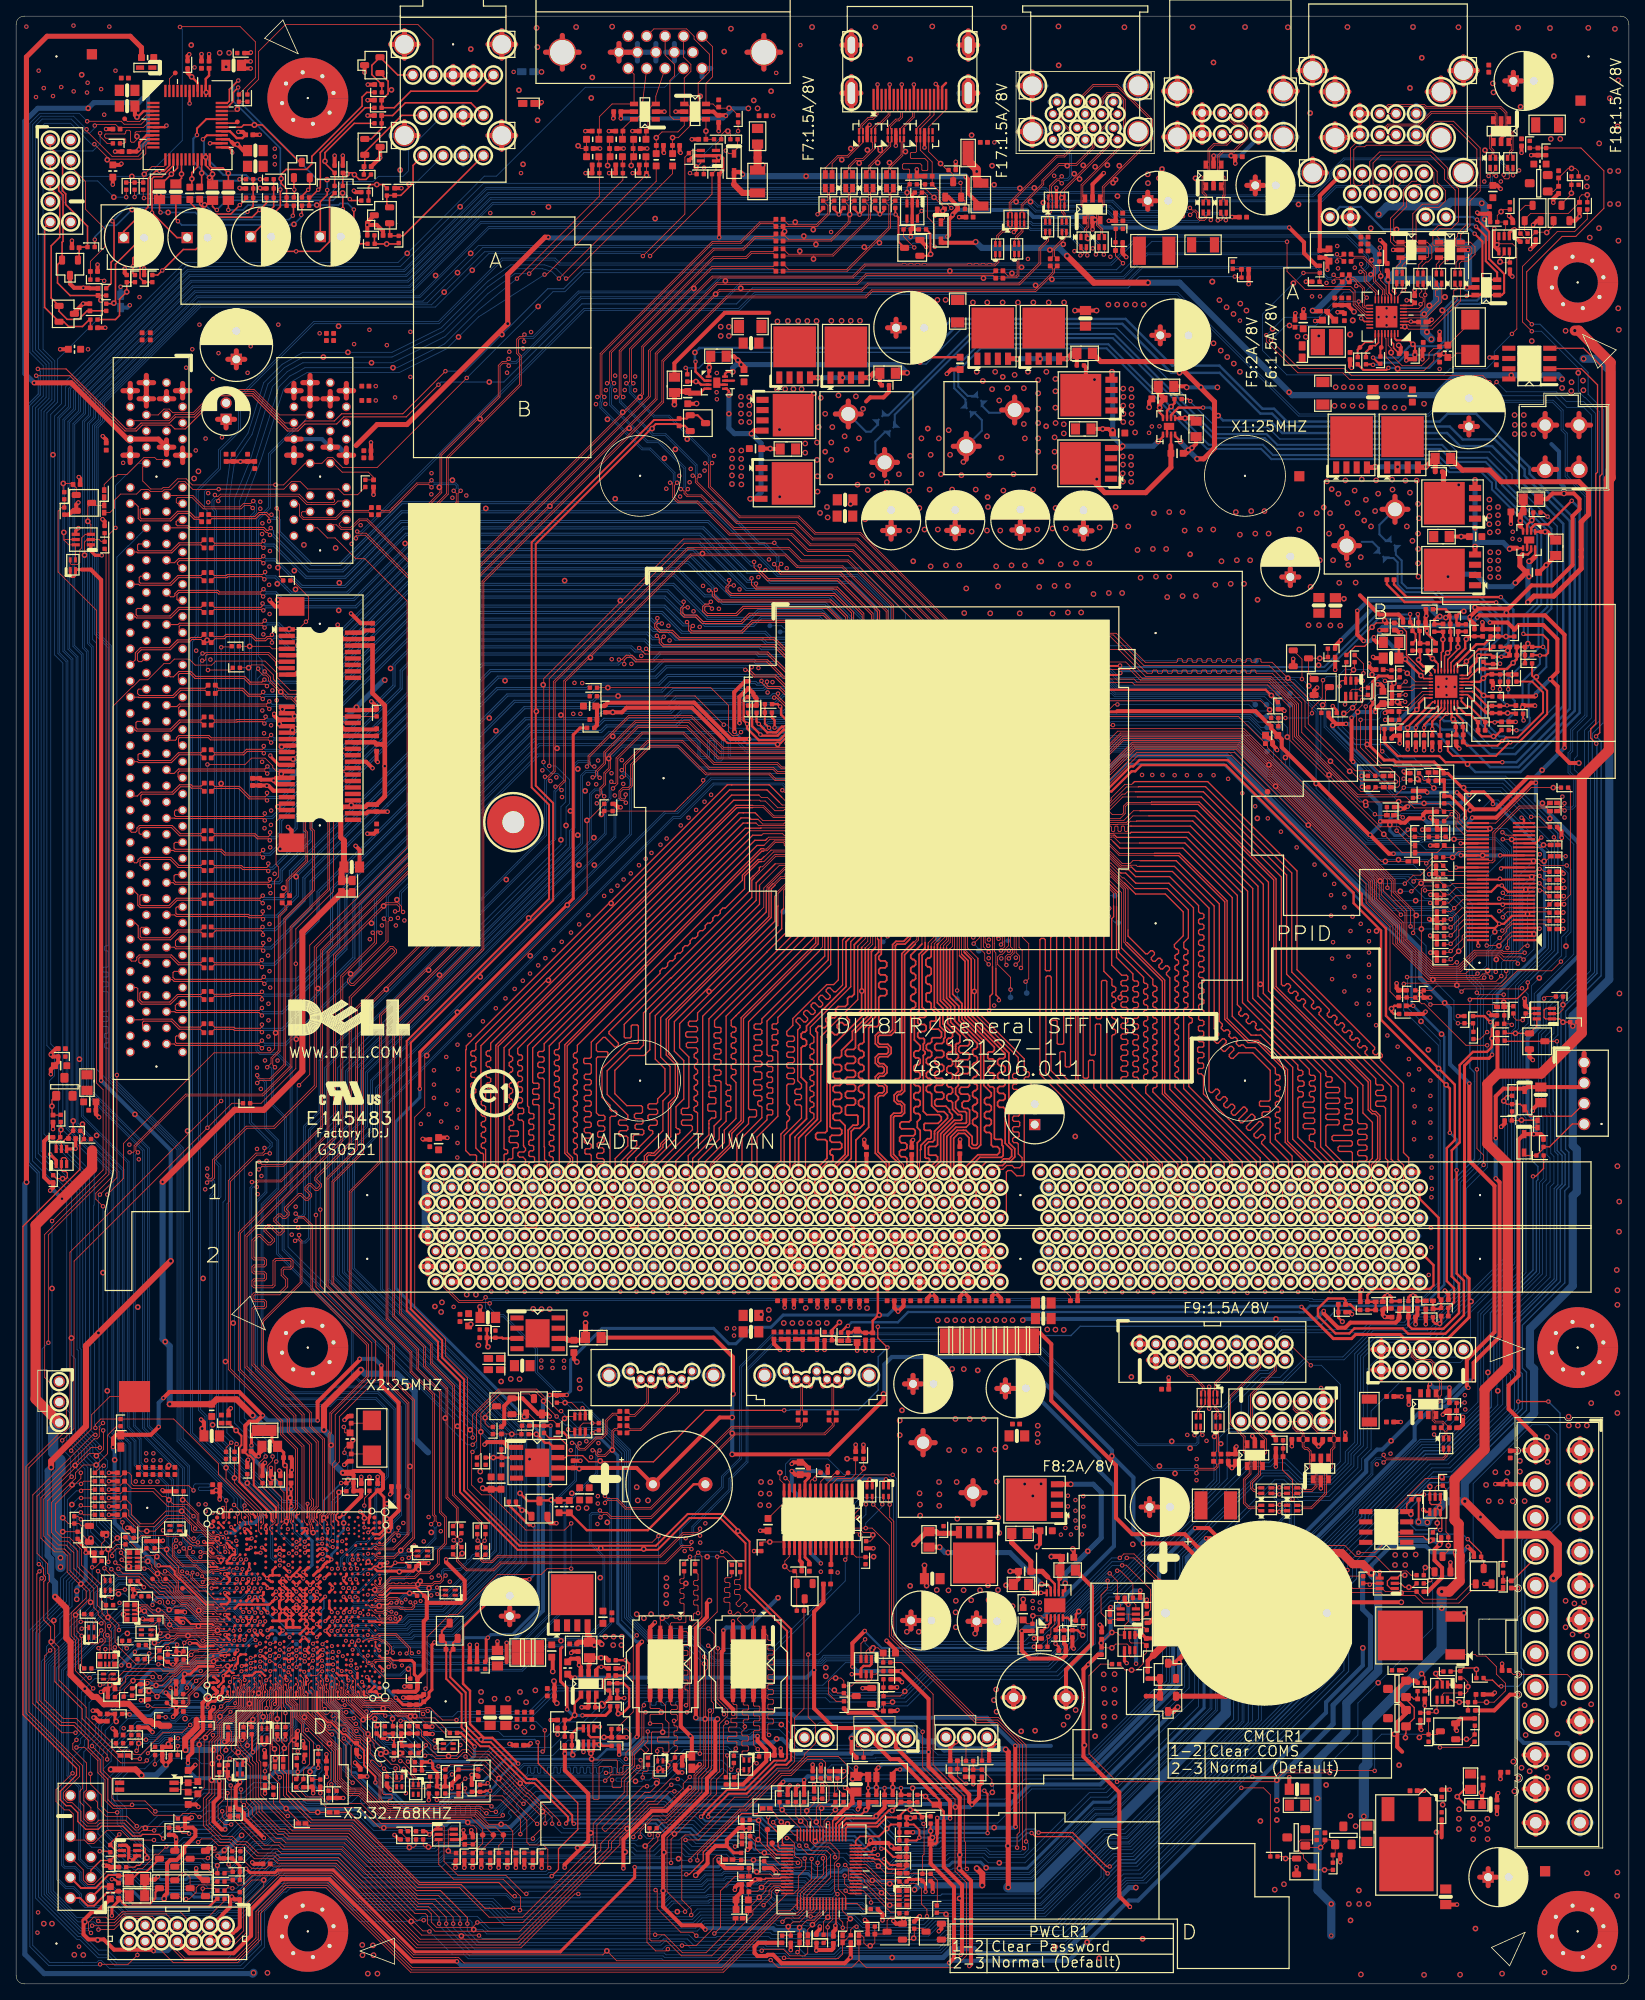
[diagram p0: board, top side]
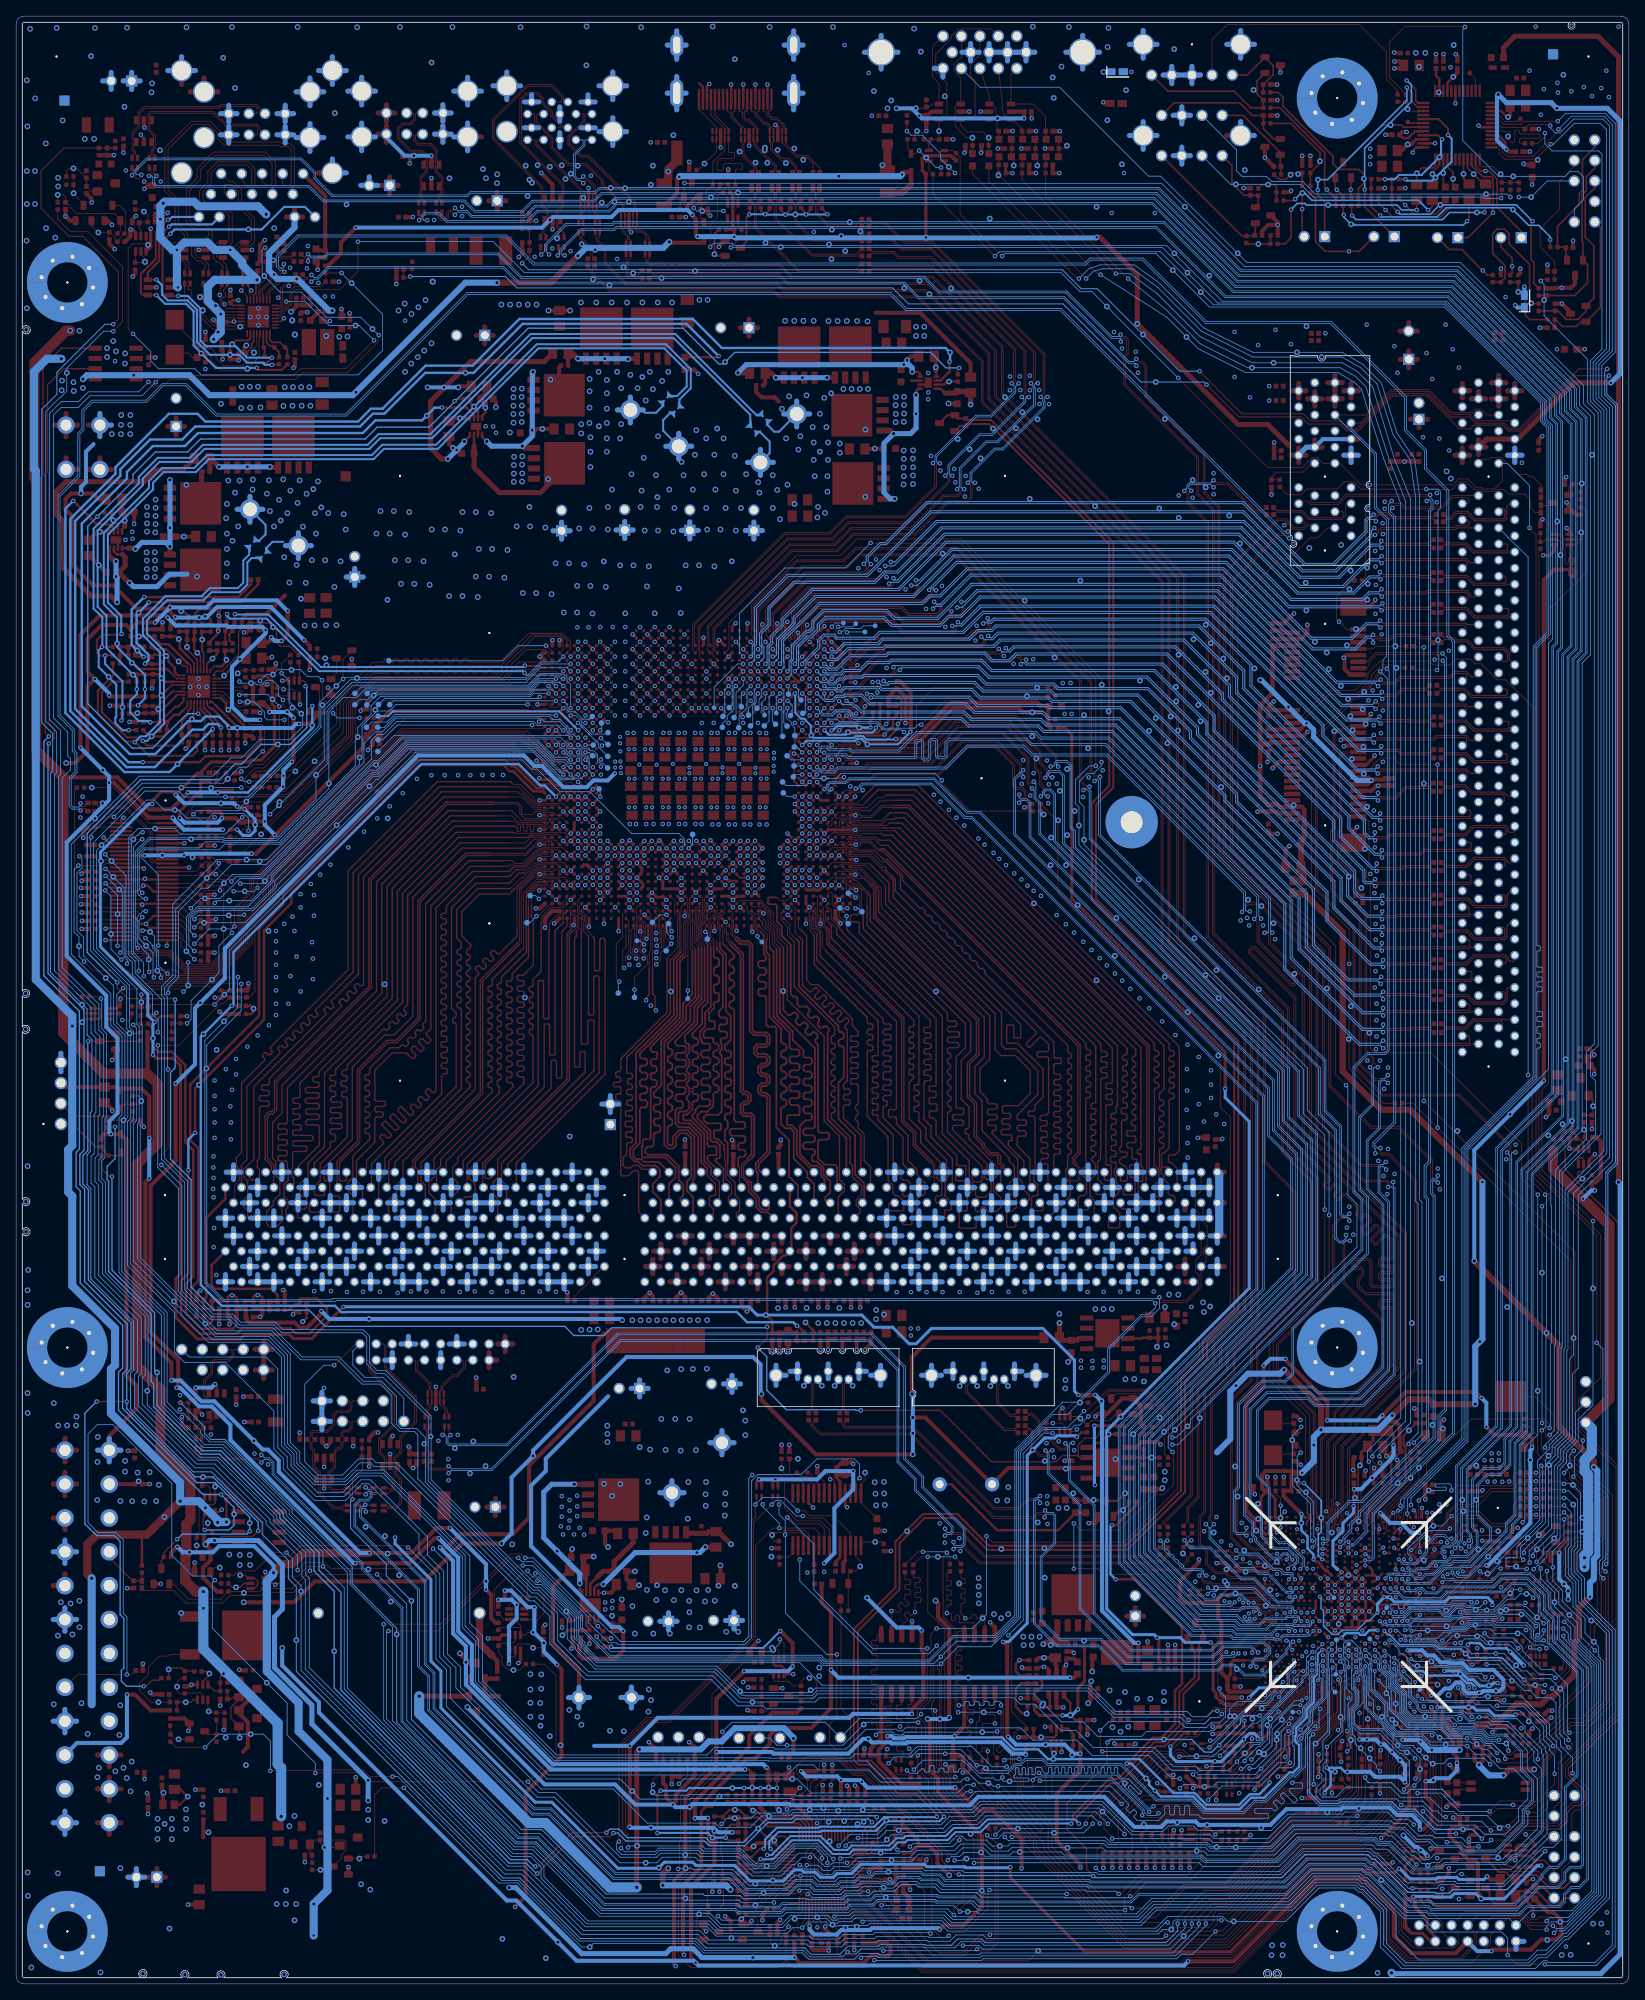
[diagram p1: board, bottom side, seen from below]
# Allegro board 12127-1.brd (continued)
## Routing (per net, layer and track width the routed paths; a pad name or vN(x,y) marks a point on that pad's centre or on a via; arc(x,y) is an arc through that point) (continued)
CK_M_DDR1_B_DN: length 60.1
  TOP w0.216: U27.AP21 117.49,136.27 v1(117.49,136.24)
  L3 w0.191: DIMM2.64 107.54,92.25 107.54,91.69 107.38,91.53 106.9,91.53 106.27,92.16 106.27,93.6 105.22,94.65 105.22,95.24 106.27,96.29 106.27,97.22 107.27,98.22 107.27,98.26 107.27,99.25 107.96,99.94 108.15,100.13 108.15,101.17 107.69,101.63 107.69,102.32 108.09,102.72 108.75,102.72 109.57,101.89 110.11,101.89 110.56,102.35 110.56,102.88 110.31,103.13 110.31,115.43 110.5,115.62 110.95,115.62 111.33,116 111.33,116.64 110.95,117.02 110.5,117.02 110.31,117.21 110.31,117.92 110.5,118.1 110.95,118.1 111.33,118.48 111.33,119.12 110.95,119.5 110.53,119.5 110.34,119.69 110.34,120.05 116.53,126.24 116.53,136.63 116.72,136.82 117.12,136.82 117.49,136.45 v1(117.49,136.24)
CK_M_DDR1_B_DP: length 60.2
  TOP w0.216: v1(117.5,137.14) 117.53,137.14 U27.AP22
  L3 w0.191: v1(117.5,137.14) 116.59,137.14 116.21,136.76 116.21,126.37 110.03,120.18 110.03,119.56 110.4,119.18 110.82,119.18 111.01,118.99 111.01,118.61 110.82,118.42 110.36,118.42 110,118.05 110,117.08 110.37,116.7 110.82,116.7 111.01,116.51 111.01,116.13 110.82,115.94 110.37,115.94 110,115.56 110,103 110.25,102.75 110.25,102.48 109.98,102.21 109.71,102.21 108.88,103.04 107.96,103.04 107.37,102.45 107.37,101.5 107.83,101.04 107.83,100.26 106.96,99.39 106.96,98.35 105.96,97.35 105.96,96.42 104.9,95.37 104.9,94.52 105.95,93.47 105.95,92.03 106.77,91.21 107.68,91.21 DIMM2.63
CK_P_33M_LPCP80: length 91.4
  TOP w0.102: v1(15.04,3.58) 13.88,2.43 v1(10.41,2.43) ; v1(8.05,62) 8.38,62.33 R408.1
  BOTTOM w0.102: LPC1.1 25.2,7.27 24.36,6.43 15.77,6.43 15.04,5.69 v1(15.04,3.58) ; v1(8.05,62) 7.98,62.08 7.14,62.08 v2(6.93,61.87) 5.99,60.93 5.99,53.97 6.44,53.53 6.44,51.26 5.51,50.34 5.51,47.7 1.7,43.89 1.7,4.63 4.04,2.29 10.27,2.29 v1(10.41,2.43)
CK_P_33M_SIO: length 170.6
  TOP w0.102: v1(8.05,61.14) 8.2,61.29 R406.1 ; U61.22 98.87,9.28 98.64,9.04 97.97,9.04 97.08,8.15 95.48,8.15 v1(95.03,7.71)
  BOTTOM w0.102: v1(95.03,7.71) 94.92,7.82 85.2,7.82 84.99,7.61 84.28,6.9 58.66,6.9 57.21,8.35 50.35,8.35 49.75,7.75 v2(49,7.75) 42.57,7.75 38.43,11.89 34.01,11.89 33.5,11.38 33.19,11.38 30.78,8.97 30.78,4.55 28.13,1.89 11.59,1.89 10.6,2.88 10.22,2.88 9.98,2.64 8.24,2.64 8.24,2.64 4.19,2.64 2.06,4.78 2.06,43.74 5.87,47.55 5.87,50.19 6.79,51.12 6.79,53.67 6.35,54.12 6.35,60.02 7.47,61.14 v1(8.05,61.14)
CK_P_33M_TPM: length 333
  TOP w0.102: R421.1 v1(8.05,60.25) ; v1(136.87,52.82) 137.36,53.31 138.63,53.31 147.35,44.6 v1(154.42,44.6) ; v1(108.71,63.12) 105.23,63.12 104.7,62.59 104.7,59 103.1,57.4 100.26,57.4 99.13,56.28 U23.21 U22.21
  BOTTOM w0.102: v1(8.05,60.25) 7.72,60.25 v2(6.91,59.44) 6.71,59.23 6.71,54.27 7.15,53.82 7.15,50.88 6.22,49.95 6.22,47.41 2.41,43.6 2.41,10.64 7.54,5.51 7.88,5.51 10.15,3.24 11.28,3.24 12.27,2.25 27.83,2.25 30.43,4.85 30.43,9.12 33.05,11.74 33.35,11.74 33.86,12.24 38.67,12.24 41.76,9.16 58.58,9.16 60.48,7.26 84.13,7.26 85.05,8.18 95.97,8.18 96.42,7.72 97.93,7.72 98.11,7.54 98.91,7.54 99.48,8.12 103.84,8.12 104.97,6.99 112.71,6.99 114.1,8.38 127.66,8.38 135.92,16.64 138.35,16.64 154.42,32.7 v1(154.42,44.6) ; v1(108.71,63.12) 109.14,62.69 109.14,43.08 109.78,42.44 125.02,42.44 126.23,43.65 126.39,43.65 127.63,44.89 127.93,44.89 135.86,52.82 v1(136.87,52.82)
CK_PCH_33M_FB: length 40.7
  TOP w0.102: v3(28.9,46.1) 28.55,46.46 U29.AM22 ; v1(19.51,47.32) 19.51,47.49 18.35,48.64 17.93,48.64 17.09,49.48 16.81,49.48 15.39,50.9 13.24,50.9 v1(12.67,51.46) ; v1(10.87,64.25) 10.65,64.25 R396.1
  BOTTOM w0.102: v1(10.87,64.25) 10.69,64.08 10.69,57.37 13.89,54.17 13.89,52.98 14.02,52.86 15.11,52.86 15.24,52.73 15.24,51.89 15.11,51.77 v2(13.97,51.77) 13.67,51.46 v1(12.67,51.46) ; v1(19.51,47.32) 19.68,47.5 21.79,47.5 22.26,47.03 26.54,47.03 27.79,47.03 27.91,46.9 27.91,46.65 28.04,46.52 28.45,46.52 28.57,46.65 28.57,46.9 28.7,47.03 29.41,47.03 29.54,46.9 29.54,46.51 29.13,46.1 v3(28.9,46.1)
CK_PCIE_1PCIEX1_DN: length 154.6
  TOP w0.102: v1(25.07,183.87) 25.07,184.11 25.43,184.47 34.99,184.47 36.02,183.44 36.55,183.44 36.56,183.44 39.48,183.44 39.91,183.87 40.63,183.87 SLOT1.A14 ; v3(37.97,55.22) 37.92,55.16 U29.R6
  BOTTOM w0.102: v2(33.99,60.27) 33.99,59.94 ; 33.99,59.94 34.7,59.94 37.44,57.21 37.44,55.11 37.56,54.99 37.74,54.99 v3(37.97,55.22) ; 33.99,59.94 33.16,59.94 25.1,68 25.1,97.28 25.39,97.58 25.39,101.47 24.84,102.03 24.84,182.68 24.54,182.99 24.54,183.87 24.71,184.05 24.89,184.05 v1(25.07,183.87)
CK_PCIE_1PCIEX1_DP: length 154.7
  TOP w0.102: v1(24.65,184.62) 24.83,184.44 25.04,184.44 25.32,184.72 35.1,184.72 36.12,183.69 36.66,183.69 39.37,183.69 39.5,183.82 39.5,184 SLOT1.A13 ; v3(37.95,54.58) 37.82,54.45 U29.R7
  BOTTOM w0.102: 37.19,55.96 37.19,57.1 34.6,59.69 33.05,59.69 24.84,67.9 24.84,97.39 25.14,97.69 25.14,101.37 24.59,101.92 24.59,182.58 24.28,182.88 24.28,183.98 24.65,184.34 v1(24.65,184.62) ; 37.19,55.96 37.19,55.01 37.46,54.74 37.8,54.74 v3(37.95,54.58) ; 37.19,55.96 v2(36.83,55.96)
CK_PCIEX1_WLAN_DN: length 128.3
  TOP w0.102: U29.W7 35.12,54.45 v3(34.77,54.1) ; v1(23.12,164.97) 23.41,164.97 23.54,165.1 31.34,165.1 32.5,163.95 MINI1.11
  BOTTOM w0.102: v2(23.06,68.86) 23.42,68.86 ; 23.42,68.86 23.42,70.33 22.62,71.13 22.62,164.48 v1(23.12,164.97) ; 23.42,68.86 23.42,67.34 32.46,58.29 32.46,55.95 34.13,54.28 34.59,54.28 v3(34.77,54.1)
CK_PCIEX1_WLAN_DP: length 128.2
  TOP w0.102: v3(34.77,54.81) 35.12,54.81 35.22,54.91 U29.W6 ; v1(23.08,164.09) 23.39,164.09 23.52,164.21 23.52,164.72 23.65,164.85 31.24,164.85 32.18,163.91 32.18,163.5 32.53,163.15 MINI1.13
  BOTTOM w0.102: 22.87,87.48 22.87,71.23 23.67,70.43 23.67,67.44 32.72,58.4 32.72,56.06 34.24,54.53 34.65,54.53 34.77,54.66 v3(34.77,54.81) ; 22.87,87.48 v2(23.19,87.48) ; 22.87,87.48 22.87,163.88 v1(23.08,164.09)
CK_PE_100M_16PORT_DN: length 146.6
  TOP w0.102: SLOT2.A14 20.02,183.55 19.86,183.7 19.86,184.15 20.02,184.3 21.81,184.3 23.21,182.91 27.89,182.91 28.3,183.31 29.03,183.31 v1(29.33,183.01) ; 26.31,77.17 26.31,99.6 29.74,103.02 30.57,103.02 30.8,103.25 v1(30.8,103.64) ; 26.31,77.17 v2(25.96,77.17) ; 26.31,77.17 26.31,76.19 32.82,69.69 32.82,68.09 34.64,66.28 34.64,59.05 34.17,58.58 34.17,57.62 34.01,57.45 34.01,57.2 34.27,56.94 U29.AA3
  BOTTOM w0.102: v1(29.33,183.01) 29.54,182.8 29.54,182.53 28.92,181.91 28.92,106.77 31.5,104.19 31.5,103.95 31.19,103.64 v1(30.8,103.64)
CK_PE_100M_16PORT_DP: length 146.7
  TOP w0.102: 26.57,81.94 26.57,76.29 33.07,69.79 33.07,68.2 34.89,66.38 34.89,58.94 34.43,58.48 34.43,57.43 U29.AA2 ; 26.57,81.94 v2(26.92,81.94) ; 26.57,81.94 26.57,99.49 29.84,102.77 30.67,102.77 30.89,102.99 v1(31.45,102.99) ; SLOT2.A13 19.88,184.55 19.89,184.56 21.92,184.56 23.32,183.16 27.79,183.16 28.19,183.57 29.11,183.57 v1(29.41,183.87)
  BOTTOM w0.102: v1(29.41,183.87) 29.79,183.49 29.79,182.42 29.17,181.8 29.17,106.87 31.75,104.3 31.75,103.84 31.45,103.55 v1(31.45,102.99)
CK_PE_100M_MCP_DN: length 212.1
  TOP w0.102: U27.V4 99.31,152.24 98.86,151.79 v1(98.86,151.79) ; v1(46.46,132.05) 46.12,131.71 46.12,129.25 41.34,124.47 41.34,124.29 41.59,124.04 41.77,124.04 46.38,128.64 46.73,128.64 47.17,128.21 47.17,127.85 41.55,122.24 41.55,104.17 37.29,99.9 37.29,99.76 37.87,99.18 37.87,98.83 37.43,98.39 37.08,98.39 36.5,98.97 36.36,98.97 36.07,98.68 36.07,98.54 36.65,97.96 36.65,97.61 36.21,97.17 35.86,97.17 35.28,97.75 35.14,97.75 33.54,96.15 33.54,96.01 33.86,95.68 33.86,95.33 33.43,94.89 33.07,94.89 32.75,95.22 32.61,95.22 32.21,94.82 32.21,94.68 33.24,93.64 33.24,93.29 32.81,92.85 32.45,92.85 31.42,93.89 31.28,93.89 30.99,93.6 30.99,93.46 32.02,92.42 32.02,92.07 31.59,91.63 31.23,91.63 30.2,92.67 30.05,92.67 29.49,92.1 29.49,90.12 29.59,90.02 30.81,90.02 31.06,89.77 31.06,89.15 30.81,88.9 29.59,88.9 29.49,88.8 29.49,88.4 29.59,88.29 30.81,88.29 31.06,88.04 31.06,87.43 30.81,87.18 29.59,87.18 29.49,87.08 29.49,86.67 29.59,86.57 31.72,86.57 31.85,86.69 31.85,89.67 32.13,89.94 34.07,89.94 34.34,89.67 34.34,88.9 34.07,88.62 33.25,88.62 33.12,88.49 33.12,87.96 33.68,87.4 33.68,86.44 32.69,85.45 29.59,85.45 29.49,85.35 29.49,84.94 29.59,84.84 30.81,84.84 31.06,84.59 31.06,83.97 30.81,83.72 29.59,83.72 29.49,83.62 29.49,76.86 35.71,70.63 35.71,69.01 37.47,67.26 37.47,59.18 37,58.72 37,57.68 37.16,57.52 37.34,57.34 U29.R2
  BOTTOM w0.102: v1(98.86,151.79) 99.18,151.79 99.29,151.89 99.29,152.12 99.13,152.27 97.17,152.27 96.82,151.92 88.56,151.92 88.31,152.17 88.31,153.97 88.21,154.08 87.8,154.08 87.7,153.97 87.7,151.91 87.42,151.64 86.86,151.64 86.58,151.91 86.58,154.05 86.45,154.18 86.1,154.18 85.97,154.05 85.97,152.19 85.7,151.92 84.83,151.92 84.56,152.19 84.56,153.84 84.19,154.21 74.8,154.21 74.13,153.54 67.08,153.54 ; 67.08,153.54 v2(67.08,153.21) ; 67.08,153.54 64.92,153.54 46.15,134.77 46.15,132.36 v1(46.46,132.05)
CK_PE_100M_MCP_DP: length 212.1
  TOP w0.102: v1(45.6,132.08) 45.87,131.81 45.87,129.36 41.09,124.58 41.09,124.19 41.49,123.79 41.88,123.79 46.48,128.39 46.63,128.39 46.91,128.1 46.91,127.96 41.3,122.35 41.3,104.27 37.04,100.01 37.04,99.65 37.61,99.08 37.61,98.93 37.33,98.64 37.18,98.64 36.61,99.22 36.25,99.22 35.81,98.79 35.81,98.43 36.39,97.85 36.39,97.71 36.1,97.42 35.96,97.42 35.38,98 35.03,98 33.29,96.26 33.29,95.9 33.61,95.58 33.61,95.44 33.32,95.15 33.18,95.15 32.85,95.47 32.5,95.47 31.96,94.93 31.96,94.57 32.99,93.54 32.99,93.4 32.7,93.11 32.56,93.11 31.52,94.14 31.17,94.14 30.73,93.7 30.73,93.35 31.77,92.32 31.77,92.17 31.48,91.89 31.34,91.89 30.3,92.92 29.95,92.92 29.24,92.21 29.24,90.02 29.49,89.77 30.71,89.77 30.81,89.67 30.81,89.26 30.71,89.16 29.49,89.16 29.24,88.91 29.24,88.29 29.49,88.04 30.71,88.04 30.81,87.94 30.81,87.53 30.71,87.43 29.49,87.43 29.24,87.18 29.24,86.56 29.49,86.31 31.83,86.31 32.11,86.59 32.11,89.56 32.23,89.69 33.96,89.69 34.09,89.56 34.09,89 33.96,88.87 33.14,88.87 32.87,88.6 32.87,87.85 33.43,87.3 33.43,86.54 32.59,85.7 29.49,85.7 29.24,85.45 29.24,84.84 29.49,84.59 30.71,84.59 30.81,84.48 30.81,84.08 30.71,83.98 29.49,83.98 29.24,83.73 29.24,76.75 35.46,70.53 35.46,68.9 37.21,67.15 37.21,59.22 36.8,58.8 36.8,57.6 36.86,57.54 U29.T2 ; v1(99.77,151.79) U27.V5
  BOTTOM w0.102: v2(45.57,133.65) 45.9,133.65 ; 45.9,133.65 45.9,132.38 v1(45.6,132.08) ; 45.9,133.65 45.9,134.87 64.82,153.79 74.03,153.79 74.7,154.46 84.3,154.46 84.81,153.95 84.81,152.3 84.94,152.17 85.59,152.17 85.72,152.3 85.72,154.16 85.99,154.43 86.56,154.43 86.83,154.16 86.83,152.02 86.96,151.89 87.32,151.89 87.44,152.02 87.44,154.08 87.69,154.33 88.31,154.33 88.56,154.08 88.56,152.28 88.66,152.18 96.72,152.18 97.07,152.53 99.24,152.53 99.54,152.22 99.54,152.02 v1(99.77,151.79)
CK_REFCLK_PCH: length 10.2
  TOP w0.102: R410.2 20.65,60.97 v2(20.65,60.02) 20.93,60.02 22.66,58.29 22.66,57.28 22.96,56.97 24.28,55.65 24.8,55.65 24.86,55.71 25.14,55.71 25.28,55.58 25.77,55.58 25.95,55.4 25.95,55.15 26.11,54.99 26.51,54.99 U29.AR7
CK_SATA_PCH_DN: length 17.4
  TOP w0.102: U29.H35 41.47,39.55 v3(41.52,39.49) ; RN32.1 52.3,29.79 v1(51.92,30.17)
  BOTTOM w0.102: v2(48.9,33.17) 48.69,32.97 ; 48.69,32.97 51.49,30.17 v1(51.92,30.17) ; 48.69,32.97 46.91,34.75 45.02,34.75 44.37,35.4 44.37,35.71 43.76,36.32 43.23,36.32 42.39,37.16 42.39,38.38 41.52,39.25 v3(41.52,39.49)
CK_SATA_PCH_DP: length 17.3
  TOP w0.102: v1(52,29.31) 52.17,29.14 RN32.2 ; v3(41.47,38.69) 41.26,38.89 U29.H36
  BOTTOM w0.102: 45.52,34.49 44.91,34.49 44.12,35.29 44.12,35.6 43.65,36.07 43.13,36.07 42.14,37.06 42.14,38.28 41.73,38.69 v3(41.47,38.69) ; 45.52,34.49 v2(45.52,34.16) ; 45.52,34.49 46.81,34.49 51.91,29.39 51.92,29.39 v1(52,29.31)
CK_XDP_S_DN: length 14.3
  TOP w0.102: R820.2 189.83,146.06 189.28,146.06 ; XDPC1.42 182.54,139.43 182.7,139.27 183,139.27 183.13,139.4 183.13,142.8 186.39,146.06 189.28,146.06 ; 189.28,146.06 v2(189.28,146.41)
CK_XDP_S_DP: length 14.9
  TOP w0.102: XDPC1.40 182.55,138.93 182.63,139.01 183.11,139.01 183.39,139.29 183.39,142.69 186.5,145.8 189.83,145.8 R821.2 v2(190.21,144.5)
CLINK_CLK: length 3.8
  TOP w0.102: U29.U36 36.29,38.85 36.63,39.19 36.69,39.19 v3(36.72,39.22)
  BOTTOM w0.102: v3(36.72,39.22) 36.83,39.11 36.83,36.58 TP66.1
CLINK_DATA: length 2.6
  TOP w0.102: v3(36.81,40.08) 36.76,40.08 U29.U35
  BOTTOM w0.102: v3(36.81,40.08) 36.3,39.56 36.3,38.43 TP67.1
CLINK_RST_N: length 2.8
  TOP w0.102: v3(36.8,40.74) 36.71,40.74 U29.U34
  BOTTOM w0.102: v3(36.8,40.74) 36.27,41.26 TP68.1
COPEN*: length 5.3
  TOP w0.102: R717.1 100.63,5.58 v1(100.63,7.01) 100.63,7.37 101.27,8 U61.28
CPU_FAN_CTRL_CONN: length 9.4
  TOP w0.165: D21.A 187,102.91 187.2,102.72 R360.1 189.41,103.6 R362.2 190.15,103.79 192.99,106.63 FNCPU1.4
CPU_FAN_CTRL_SIO: length 165.1
  TOP w0.165: v1(93.27,20.68) 93.27,19.94 94.49,18.72 94.49,17.02 94.71,16.8 U61.2 ; R360.2 189.42,101.12 188.43,100.13 v1(188.11,100.13) ; v1(126.79,18.76) 131.03,18.76 135.23,14.55 v1(135.61,14.55)
  BOTTOM w0.165: v1(126.79,18.76) 126.36,19.19 125.25,19.19 124.19,18.13 114.47,18.13 113.88,17.55 109.81,17.55 106.91,20.44 103.87,20.44 103.46,20.85 93.44,20.85 v1(93.27,20.68) ; v1(188.11,100.13) 188.11,100.13 188.11,88.51 182.83,83.23 182.83,76.12 v2(182.52,75.82) 182.52,71.7 176.93,66.11 174.6,66.11 166.87,58.38 166.87,57.93 162.44,53.5 162.44,51.29 159.72,48.56 159.72,36.43 138.68,15.4 136.6,15.4 135.75,14.55 v1(135.61,14.55)
CPU_FAN_TACH_1: length 13.1
  TOP w0.165: R352.2 184.82,110.12 184.48,109.78 v2(184.48,109.47) 184.87,109.08 R356.2 186.55,109.08 D37.A 187.43,108.2 187.43,107.9 187.73,107.59 192.87,107.59 FNCPU1.3
CPU_FAN_TACH_L: length 4.4
  TOP w0.165: R356.1 185.48,108.15 R358.1 186.64,107.06 v2(186.68,107.11) 188.64,107.11 R357.1
CPU_FAN_TACH_SIO: length 168.2
  TOP w0.165: v1(187.73,106.27) 187.82,106.18 R357.2 ; v1(125.93,18.7) 126.37,18.26 130.78,18.26 v1(135.36,13.69) ; v1(93.88,20.04) 95.02,18.9 95.02,17.48 95.3,17.2 U61.1
  BOTTOM w0.165: v1(135.36,13.69) 135.48,13.69 136.77,14.98 138.86,14.98 160.55,36.68 v2(160.55,41.25) 160.55,48.69 163.07,51.21 163.07,53.54 167.29,57.76 167.29,58.21 174.78,65.69 177.11,65.69 182.94,71.53 182.94,74.41 183.25,74.71 183.25,83.05 188.53,88.34 188.53,99.54 188.72,99.73 188.72,101.35 187.73,102.34 v1(187.73,106.27) ; v1(125.93,18.7) 125.36,18.7 124.36,17.71 114.64,17.71 114.06,17.13 109.64,17.13 106.74,20.02 103.69,20.02 103.29,20.43 94.27,20.43 v1(93.88,20.04)
CPU_THERMDA: length 267.9
  TOP w0.203: U61.46 106.09,16.4
  TOP w0.254: 106.09,16.4 v1(106.43,16.74) ; Q12.C 84.51,194.51 Q12.B 83.17,194.09 C497.1 82.05,193.93 79.11,193.93 63.93,178.75 63.93,148.36 66.09,146.2 66.09,134.57 48.44,116.92 48.44,83.48 52.32,79.59 52.32,77.44 55.04,74.73 55.04,60.98 62.2,53.82 79.55,53.82 83.49,57.76 87.33,57.76 90.45,54.64 90.45,48.92 95.61,43.76 95.61,27.97 95.32,27.69 93.99,27.69 90.39,24.08 88.17,24.08 85.32,21.24 85.32,21.11 v1(84.94,20.73)
  BOTTOM w0.254: v1(84.94,20.73) 85.5,20.17 92.17,20.17 93.36,18.97 100.18,18.97 100.3,18.85 105.45,18.85 106.24,18.06 ; v1(106.43,16.74) 106.43,16.74 106.6,16.91 106.6,17.7 106.24,18.06 ; 106.24,18.06 v2(105.97,17.78)
CPU_THERMTRIP_N: length 51.8
  TOP w0.102: v1(168.5,145.03) 168.63,144.91 R127.2 R411.2 ; U27.F37 v1(131.23,162.76)
  BOTTOM w0.102: v1(131.23,162.76) 131.67,163.2 134.98,163.2 136.79,161.39 158.38,161.39 161.8,157.98 161.8,151.74 v2(167.39,146.14) v1(168.5,145.03)
CPU_VSS_T8: length 22.5
  TOP w0.381: U27.T8 v1(102.51,153.61)
  TOP w0.508: R1248.1 90.41,161.53 89.05,160.17 89.05,155.3 v1(89.1,155.24)
  BOTTOM w0.254: v1(102.51,153.61) 101.98,154.15 95.97,154.15 95.76,154.36 95.1,154.36 v2(94.44,153.7) 90.65,153.7 v1(89.1,155.24)
CSN1: length 60
  TOP w0.203: U52.15 178.34,158.22
  TOP w0.254: R96.1 188.01,161.48 189.36,160.13 189.36,157.67 186.24,154.56 184.78,154.56 184.35,154.13 v1(184.3,154.13) 183.71,153.54 179.93,153.54 C103.1 C157.2 179.46,155.8 R240.1 179.41,156.63 178.66,157.38 178.66,157.9 178.34,158.22
  BOTTOM w0.254: G2.2 170.79,176.81 171.32,176.28 171.32,173.53 172.28,172.57 175.76,172.57 176.76,171.57 181.28,171.57 181.8,171.05 183.77,169.08 183.77,167.44 181.66,165.33 181.66,164.67 ; v1(184.3,154.13) 183.77,154.13 182.59,155.31 181.66,156.24 181.66,164.67 ; 181.66,164.67 v2(181.38,164.67)
CSN2: length 121.9
  TOP w0.203: U52.19 180.61,160.26
  TOP w0.254: R98.1 v1(184.02,160.53) ; C108.1 184.9,158.52 v1(184.89,158.53) 184.82,158.47 C164.2 R114.1 182.4,158.47 180.61,160.26
  BOTTOM w0.254: v1(184.89,158.53) 184.02,159.4 v1(184.02,160.53) 184.02,162.31 187.48,165.76 v2(187.48,166.19) 187.48,169.42 189.13,171.07 189.13,179.92 183.53,185.52 183.53,186.34 181.91,187.96 177.92,187.96 176.31,189.57 155.87,189.57 154.6,190.85 147.91,190.85 135.45,203.31 119.41,203.31 116.33,200.24 116.33,197.87 117.73,196.47 G11.2
CSN3: length 133
  TOP w0.203: U52.17 179.23,159.05
  TOP w0.254: R115.1 C169.2 ; R115.1 180.26,158.38 179.89,158.38 179.23,159.05 ; R115.1 183.32,156.46 v1(183.36,156.42) 183.43,156.49 C113.1 ; v1(185.04,160.53) R100.1
  BOTTOM w0.254: G9.2 108.96,194.58 118.46,204.08 136,204.08 148.41,191.66 154.86,191.66 156.19,190.33 176.63,190.33 178.24,188.72 182.22,188.72 184.29,186.66 184.29,185.83 189.89,180.23 189.89,170.75 188.8,169.66 188.8,165.63 v2(185.51,162.34) 185.04,161.87 v1(185.04,160.53) 185.04,159.92 185.85,159.11 185.85,157.66 184.78,156.59 183.53,156.59 v1(183.36,156.42)
CSP1: length 60
  TOP w0.254: R93.2 188,162.21 189.87,160.34 189.87,157.46 186.45,154.05 185.39,154.05 v1(185.29,153.96) 185.2,153.96 183.51,152.27 178.16,152.27 177.55,152.88 R163.1
  BOTTOM w0.254: v1(185.29,153.96) 184.56,154.69 183.93,154.69 182.95,155.67 182.17,156.45 182.17,158.06 ; 182.17,158.06 182.17,165.12 184.28,167.23 184.28,169.29 182.31,171.26 182.31,171.26 181.49,172.08 176.97,172.08 175.98,173.08 172.49,173.08 171.83,173.74 171.83,176.49 171.11,177.21 G1.2 ; 182.17,158.06 v2(182.4,158.06)
CSP1_R: length 5.4
  TOP w0.203: 178.03,157.65 177.94,157.73 U52.14
  TOP w0.305: R163.2 178.5,154.81 C157.1 178.57,155.8 R240.2 178.52,156.5 v2(178.21,156.82) 178.03,157 178.03,157.65
CSP2: length 117.7
  TOP w0.254: v1(186.92,167.4) 187.03,167.28 189.34,167.28 189.99,166.64 189.99,165.02 189.69,164.72 v1(188.97,164.72) 188.93,164.76 R94.2 ; R164.1 186.88,156.73 v1(186.94,156.67)
  BOTTOM w0.254: G10.2 118.02,196.9 117.38,197.53 116.84,198.08 116.84,200.03 119.62,202.81 135.23,202.81 147.7,190.34 154.39,190.34 155.66,189.06 176.1,189.06 177.71,187.45 181.7,187.45 183.02,186.13 183.02,185.31 188.62,179.71 188.62,171.28 186.97,169.63 186.97,167.45 v1(186.92,167.4) ; v1(188.97,164.72) 188.97,163.67 186.82,161.52 v2(186.82,158.29) 186.82,156.79 v1(186.94,156.67)
CSP2_R: length 7.7
  TOP w0.203: U52.18 180.01,159.86 180.19,159.68
  TOP w0.305: R164.2 185.92,157.58 v2(184.96,157.58) C164.1 R114.2 182.29,157.58 180.19,159.68
CSP3: length 127.5
  TOP w0.254: v1(186.06,155.45) 186.03,155.47 R165.1 ; v1(189.36,165.78) R95.2
  BOTTOM w0.254: v1(186.06,155.45) 186.8,155.45 187.71,156.35 187.71,156.98 187.58,157.11 187.58,161.11 v2(188.53,162.07) 189.76,163.3 189.76,165.38 v1(189.36,165.78) 189.31,165.83 189.31,169.45 190.4,170.54 190.4,180.44 184.8,186.04 184.8,186.87 182.43,189.23 178.45,189.23 176.84,190.84 156.4,190.84 155.07,192.17 148.62,192.17 136.21,204.58 118.25,204.58 108.23,194.56 G8.2
CSP3_R: length 8.7
  TOP w0.203: U52.16 178.74,158.46 179.27,157.93
  TOP w0.305: R165.2 183.43,154.69 v2(183.21,154.69) 181.74,154.69 181.29,155.13 C169.1 R115.2 180.4,157.36 179.84,157.36 179.27,157.93
DDPC_CTRL_CLK: length 268
  TOP w0.102: U29.AN3 27.76,56.78 27.45,57.1 27.45,58.29 v1(27.47,58.31) ; v1(111.38,215.32) 110.05,216.65 R51.2 110.47,217.98 U3.4
  BOTTOM w0.102: v1(27.47,58.31) 27.47,60.16 20.2,67.43 20.2,103.52 11.4,112.32 11.4,115.95 11.3,116.05 11.07,116.05 10.97,116.15 10.97,116.56 11.07,116.66 11.3,116.66 11.4,116.76 11.4,117.16 11.3,117.27 11.07,117.27 10.97,117.37 10.97,117.77 11.07,117.88 11.3,117.88 11.4,117.98 11.4,118.62 11.3,118.72 10.82,118.72 10.72,118.82 10.72,119.23 10.82,119.33 11.3,119.33 11.4,119.43 11.4,119.84 11.3,119.94 10.82,119.94 10.72,120.04 10.72,120.45 10.82,120.55 11.3,120.55 11.4,120.65 11.4,122.93 11.3,123.03 10.85,123.03 10.74,123.13 10.74,123.54 10.85,123.64 11.3,123.64 11.4,123.74 11.4,124.15 11.3,124.25 10.85,124.25 10.74,124.35 10.74,124.76 10.85,124.86 11.3,124.86 11.4,124.96 11.4,125.37 11.3,125.47 10.85,125.47 10.74,125.57 10.74,125.98 10.85,126.08 11.3,126.08 11.4,126.18 11.4,128 11.3,128.1 11.07,128.1 10.97,128.2 10.97,128.61 11.07,128.71 11.3,128.71 11.4,128.81 11.4,165.68 9.7,167.39 9.7,193.16 10.48,193.94 10.48,196.2 22.71,208.43 50.98,208.43 v2(54.74,212.19) 57.86,215.32 v1(111.38,215.32)
DDPC_CTRL_CLK_CONN: length 21.6
  TOP w0.102: U3.3 110.47,222.11 v2(110.49,222.12) 110.49,222.82 R17.2 C26.1 110.81,224.92 110.71,225.02 110.03,225.02 109.93,225.12 109.93,225.6 110.03,225.7 112.12,225.7 112.32,225.5 112.32,224.94 112.42,224.84 112.95,224.84 113.06,224.94 113.06,225.98 112.7,226.34 111,226.34 110.9,226.44 110.9,227 111,227.1 111.55,227.1 111.65,227.2 U34.1 U34.10 111.65,230.04 113.33,231.72 HDMI1.15
DDPC_CTRL_DATA: length 268.6
  TOP w0.102: U3.1 111.78,221.57 R50.2 112.65,222.12 113.03,221.74 113.03,219.07 113.92,218.19 v1(113.92,215.39) ; v1(27.03,59.39) 27.03,59.39 27.94,58.47 27.94,57.73 28.43,57.24 U29.AM2
  BOTTOM w0.102: v1(113.92,215.39) 113.46,215.85 111.23,215.85 110.92,215.54 57.33,215.54 v2(56.37,214.58) 50.44,208.66 22.62,208.66 10.25,196.29 10.25,194.03 9.47,193.26 9.47,166.73 9.96,166.24 9.96,113.44 19.96,103.44 19.96,67.29 27.03,60.22 v1(27.03,59.39)
DDPC_CTRL_DATA_CONN: length 21.1
  TOP w0.102: HDMI1.16 113.83,231.76 112.13,230.06 U34.9 U34.2 112.13,227.38 113.6,225.91 C27.1 R18.2 114.43,222.31 114.43,221.26 114.96,220.73 115.44,220.73 115.95,220.22 v1(115.98,220.22) ; U3.6 111.78,219.32 v1(112.29,219.84)
  BOTTOM w0.102: v1(112.29,219.84) v2(114.91,219.84) 115.6,219.84 v1(115.98,220.22)
DDR3_DRAMRST_N: length 66.7
  TOP w0.102: C520.1 130.75,85.23 128.75,87.22 128.75,87.35 127.15,88.95 DIMM2.168 ; U27.AK22 v1(118.43,140.81)
  L3 w0.102: v1(118.43,140.81) 119.04,141.43 119.56,141.43 119.81,141.17 119.81,140.26 122.02,138.05 122.02,133.78 121.53,133.29 121.53,130.92 124.46,127.99 124.46,127.46 125.73,126.19 125.73,123.09 125.32,122.68 125.32,110.72 123.04,108.43 123.04,105.18 124.54,103.68 124.54,101.47 127.04,98.97 DIMM1.168 127.04,96.85 127.04,93.81 127.79,93.07 127.79,92.46 127.04,91.71 DIMM2.168
DDR_RCOMP_0: length 11.2
  TOP w0.305: U27.R1 95.44,154.99 94.68,154.22 92.11,154.22 90.65,155.68 v1(90.65,156.24) 90.22,156.67 90.22,159.18 90.6,159.56 R541.1
DDR_RCOMP_1: length 6.7
  TOP w0.305: R417.1 91.82,156.51 v1(92.1,156.24) 93.14,155.19 93.14,155.19 94.25,155.19 94.97,155.9 U27.P1
DDR_RCOMP_2: length 9
  TOP w0.305: U27.R2 97.03,155.44 95.1,155.44 94.44,154.78 92.44,154.78 v1(92.3,154.91) 91.26,155.96 91.26,156.84 90.78,157.33 R796.1
DDR_SHDN: length 13.6
  TOP w0.102: U53.5 105.42,37.52 ; 105.42,37.52 104.19,37.52 103.62,36.94 R311.2 102.65,37.56 102.29,37.92 v2(101.63,37.92) 101.17,37.92 100.76,37.52 100.76,35.97 101.69,35.04 R415.2 ; 105.42,37.52 105.84,37.52 106.07,37.74 U53.6 106.63,38.4 107.01,38.79 R414.2
DDSP_C_HPD: length 285.9
  TOP w0.102: R78.1 117.67,221.08 Q5.S 117.19,223.25 v1(117.12,223.32) ; U29.AH5 30.11,56.08 30.11,56.25 30.06,56.3 30.06,57.92 29.95,58.02 29.95,58.31 25.1,63.16 25.1,64.49 19.55,70.04 R599.1 10.5,70.04 9.83,69.37 v1(9.83,68.94)
  BOTTOM w0.102: v1(9.83,68.94) 9.73,69.03 9.73,79.37 9.58,79.52 9.58,96.48 9.68,96.58 9.68,98.79 9.68,101.03 9.68,101.03 9.68,101.98 5.79,105.86 5.79,163.78 4.78,164.8 4.78,194.41 6.11,195.75 6.11,198.01 21.05,212.95 47.65,212.95 v2(55.06,220.36) 57.96,223.27 117.06,223.27 v1(117.12,223.32)
DDSP_C_HPD_CONN: length 12.5
  TOP w0.102: Q5.D 116.2,224.35 R67.2 115.44,224.92 v2(114.64,225.72) 113.17,227.19 U34.4 U34.7 113.17,230.26 115.33,232.42 HDMI1.19
DDSP_C_TX_DN_0: length 94.1
  TOP w0.102: U27.E19 113.58,164.68 113.58,165.52 113.58,168.06 103.81,177.83 98.24,177.83 96.21,179.86 88.52,179.86 84.51,183.87 82.13,183.87 81.64,184.37 81.64,185.82 v1(81.96,186.14) ; C44.1 93.87,218.26 92.3,218.26 89.88,215.84 86.4,215.84 72.64,202.08 72.64,197.07 v1(72.94,196.77)
  BOTTOM w0.102: v2(80.4,189.17) 80.17,188.94 ; 80.17,188.94 78.67,190.44 77.69,190.44 72.62,195.5 72.62,196.11 72.69,196.19 72.69,196.53 v1(72.94,196.77) ; 80.17,188.94 81.7,187.4 81.7,186.4 v1(81.96,186.14)
DDSP_C_TX_DN_1: length 90.8
  TOP w0.102: v1(74.15,198.48) 73.83,198.8 73.83,202.27 86.55,215 90.22,215 91.68,216.46 93.87,216.46 C46.1 ; U27.D20 114.3,165.4 114.3,168.35 104.1,178.55 98.54,178.55 96.51,180.58 89.06,180.58 85.01,184.63 83.29,184.63 83.05,184.87 83.05,185.1 v1(83.29,185.35)
  BOTTOM w0.102: 75,194.66 78.34,191.32 79.72,191.32 83.03,188.01 83.03,185.61 v1(83.29,185.35) ; 75,194.66 73.83,195.84 73.83,197.83 73.9,197.9 73.9,198.23 v1(74.15,198.48) ; 75,194.66 v2(75.23,194.89)
DDSP_C_TX_DN_2: length 89
  TOP w0.102: C48.1 93.89,214.59 91.22,214.59 90.59,213.96 86.53,213.96 75.01,202.44 75.01,197.05 v1(75.28,196.77) ; U27.E21 115.21,164.49 115.21,165.1 115.43,165.31 115.43,168.24 104.4,179.27 98.84,179.27 96.81,181.3 89.42,181.3 84.44,186.28 84.44,186.69 v1(84.77,187.01)
  BOTTOM w0.102: v1(75.28,196.77) 75.02,196.51 75.02,196.23 78.63,192.62 ; 78.63,192.62 v2(78.87,192.86) ; 78.63,192.62 79.04,192.21 80.57,192.21 81.36,191.42 81.37,191.42 84.44,188.34 84.44,187.34 v1(84.77,187.01)
DDSP_C_TX_DN_3: length 85.9
  TOP w0.102: C50.1 93.87,212.72 86.34,212.72 76.3,202.69 76.3,198.71 v1(76.54,198.48) ; U27.D22 116.1,165.38 116.1,168.58 104.7,179.98 99.14,179.98 97.1,182.02 89.77,182.02 86.08,185.71 86.08,188.36 v1(86.31,188.59)
  BOTTOM w0.102: v1(76.54,198.48) 76.25,198.19 76.25,197.41 77.14,196.52 ; 77.14,196.52 79.15,194.51 81.01,194.51 86.05,189.47 86.05,188.84 v1(86.31,188.59) ; 77.14,196.52 v2(77.37,196.75)
DDSP_C_TX_DP_0: length 94.3
  TOP w0.102: v1(72.08,196.77) 72.33,196.77 72.43,196.88 72.43,202.17 86.31,216.05 89.79,216.05 92.21,218.48 93.9,218.48 C43.1 ; v1(81.1,186.14) 81.1,186.14 81.3,186.14 81.42,186.02 81.42,184.28 82.04,183.66 84.42,183.66 88.44,179.65 96.12,179.65 98.15,177.61 103.72,177.61 113.36,167.97 113.36,165.52 113.36,165.38 U27.D19
  BOTTOM w0.102: 73.57,194.25 72.4,195.41 72.4,196.2 72.48,196.28 72.48,196.67 72.38,196.77 v1(72.08,196.77) ; 73.57,194.25 v2(73.33,194.01) ; 73.57,194.25 77.6,190.22 78.58,190.22 81.49,187.31 81.49,186.22 81.41,186.14 81.1,186.14 v1(81.1,186.14)
DDSP_C_TX_DP_1: length 90.8
  TOP w0.102: v1(73.29,198.48) 73.51,198.48 73.61,198.58 73.61,202.36 86.46,215.21 90.13,215.21 91.59,216.67 93.9,216.67 C45.1 ; U27.C20 114.08,166.1 114.08,168.26 109.05,173.3 104.01,178.33 98.45,178.33 96.42,180.36 88.97,180.36 84.92,184.41 83.2,184.41 82.83,184.78 82.83,185.12 82.6,185.35 v1(82.43,185.35)
  BOTTOM w0.102: 76.25,193.11 78.25,191.11 79.63,191.11 82.82,187.92 82.82,185.57 82.6,185.35 v1(82.43,185.35) ; 76.25,193.11 v2(76.02,192.89) ; 76.25,193.11 73.61,195.75 73.61,197.92 73.69,197.99 73.69,198.37 73.58,198.48 v1(73.29,198.48)
DDSP_C_TX_DP_2: length 89
  TOP w0.102: C47.1 93.88,214.81 91.14,214.81 90.5,214.17 86.44,214.17 74.79,202.53 74.79,196.88 74.67,196.76 v1(74.42,196.76) ; v1(83.9,187.01) 84.14,187.01 84.23,186.92 84.23,186.19 89.33,181.08 96.72,181.08 98.75,179.05 104.31,179.05 115.21,168.15 115.21,165.4 U27.D21
  BOTTOM w0.102: 81.97,190.5 84.23,188.25 84.23,187.11 84.13,187.01 v1(83.9,187.01) ; 81.97,190.5 v2(81.75,190.28) ; 81.97,190.5 81.15,191.33 80.48,191.99 78.95,191.99 78.61,192.33 75.18,195.76 75.06,195.88 74.94,196 74.8,196.14 74.8,196.67 74.72,196.76 v1(74.42,196.76)
DDSP_C_TX_DP_3: length 85.9
  TOP w0.102: U27.C22 115.89,166.07 115.89,168.49 104.61,179.77 99.05,179.77 97.01,181.8 89.68,181.8 85.86,185.62 85.86,188.37 85.69,188.54 v1(85.44,188.54) ; v1(75.67,198.48) 75.84,198.48 76.09,198.72 76.09,202.78 86.25,212.94 93.88,212.94 C49.1
  BOTTOM w0.102: v1(75.67,198.48) 76.03,198.11 76.03,197.32 79.06,194.29 80.92,194.29 83.45,191.77 ; v2(83.22,191.55) 83.45,191.77 ; 83.45,191.77 85.84,189.38 85.84,188.67 85.71,188.54 v1(85.44,188.54)
DDSP_D_TX_N0: length 22.6
  TOP w0.254: R57.2 100.08,220.12 v1(99.39,219.43) ; R64.2 109.03,219.45 v1(109.07,219.41) 109.42,219.05 109.42,216.01 Q4.D ; R61.2 105.16,219.94 v1(104.6,219.38) 103.97,220.01 R60.2 ; R58.2 101.46,219.98 v1(102.03,219.41) 102.31,219.69 102.31,219.89 R59.2 ; R63.2 107.64,219.87 107.2,219.43 v1(107.11,219.43) 106.54,220.01 R62.2
  BOTTOM w0.254: v1(99.39,219.43) 99.42,219.41 v1(102.03,219.41) v2(103.38,219.41) 104.57,219.41 v1(104.6,219.38) 107.06,219.38 v1(107.11,219.43) 109.04,219.43 v1(109.07,219.41)
DDSP_D_TX_N2: length 4.7
  TOP w0.254: R41.2 113.39,217 113.39,214.5 v2(113.41,214.48) 113.21,214.28 Q4.G
DIMM_CA_CPU_VREF_A: length 173.1
  TOP w0.305: C3312.1 v1(173.25,121.28) ; v1(103.15,81.58) 103.05,81.58 102.3,80.84 R265.1 ; v1(133.06,147.21) 133.06,147.23 132.62,147.67 U27.AB38
  BOTTOM w0.305: v1(133.06,147.21) 134.43,148.59 135,148.59 137.67,151.26 149.73,151.26 173.05,127.93 173.05,121.49 v1(173.25,121.28) v2(176.77,117.77) 177.1,117.44 177.1,86.68 174.5,84.08 160.46,84.08 159.67,83.29 159.14,83.29 159.12,83.31 110.62,83.31 109.35,82.04 103.61,82.04 v1(103.15,81.58)
DIMM_CA_CPU_VREF_RC: length 2.5
  TOP w0.305: C3312.2 170.92,121.28 v2(170.56,120.93) 170.56,120.57 170.87,120.27 R793.1
DIMM_CA_VREF_A: length 24.6
  TOP w0.305: DIMM1.67 104.04,96.42 103.22,95.6 103.22,94.37 103.87,93.72 103.87,91.03 DIMM2.67 104.58,90.32 104.85,90.32 106.05,89.12 106.05,88.42 106.87,87.59 106.87,82.86 106.22,82.22 C607.1 C489.1 104.94,80.73 104.62,81.05 C3324.1 103.91,81.05 103.63,80.77 R265.2 R851.2
DIMM_CA_VREF_A_L: length 3.8
  TOP w0.305: v2(102.11,82.02) 101.16,81.06 R704.2 R853.1 101.17,79.82 102.23,79.82 R851.1
DIMM_DQ_CPU_VREF_A: length 100.1
  TOP w0.305: U27.AB39 134.11,148.27 135.49,148.27 138.19,150.97 138.52,150.97 139.3,151.75 150.28,151.75 166.88,135.14 166.88,133.86 169.88,130.86 169.88,120.04 v2(176.4,113.51) 178.41,111.51 178.41,104.62 177.42,103.63 177.42,87.15 178.32,86.25 178.32,84.53 177.9,84.11 R855.1 C3310.1
DIMM_DQ_CPU_VREF_B: length 125.5
  TOP w0.305: U27.AB40 134.62,147.86 135.84,147.86 138.34,150.36 138.78,150.36 139.56,151.14 150.02,151.14 165.86,135.3 165.86,134.01 169.27,130.61 169.27,119.54 176.32,112.49 176.33,112.49 v2(177.34,111.48) 177.8,111.02 v1(177.8,105.54) ; v1(178.64,100.89) 178.64,88.09 179.54,87.18 179.54,82.91 177.25,80.62 172.62,80.62 171.96,81.28 165.96,81.28 165.34,80.66 163.62,80.66 161.44,82.84 161.44,83.73 162.69,84.98 164.67,84.98 164.86,84.8 C3311.1 165.46,84.25 166.14,83.57 R863.1
  BOTTOM w0.305: v1(178.64,100.89) 178.64,104.7 v1(177.8,105.54)
DIMM_DQ_CPU_VREF_B_RC: length 2.3
  TOP w0.305: v4(164.47,82.12) 163.97,82.61 R864.1 C3311.2
DIMM_DQ_CPU_VREF_RC: length 2.5
  TOP w0.305: R856.1 175.7,82.16 176,81.86 v4(176.53,81.86) 176.72,82.05 C3310.2
DIMM_DQ_VREF_A: length 18.1
  TOP w0.305: R854.2 C580.1 176.59,83.69 R855.2 C592.1 176.4,85.15 176.4,95 174.04,97.36 DIMM1.1
DIMM_DQ_VREF_A_L: length 3.3
  TOP w0.305: R854.1 174.78,84.67 R665.1 173.77,85.13 173.53,85.37 v1(173.23,85.37) 172.9,85.37 172.66,85.13 R664.2
DIMM_DQ_VREF_B: length 17.5
  TOP w0.305: DIMM2.1 175.77,89.13 175.77,86.61 175.34,86.18 168.35,86.18 167.58,85.41 C616.1 R858.2 C591.1 R863.2
DIMM_DQ_VREF_B_L: length 3.4
  TOP w0.305: R857.2 171.57,84.65 R859.1 170.56,85.19 170.36,85.39 v1(170.05,85.39) 169.75,85.39 169.48,85.13 R858.1
DISP_UTIL_CPU: length 8
  TOP w0.102: U27.E16 v1(109.83,163.67)
  BOTTOM w0.102: v1(109.83,163.67) 110.55,163.67 113.44,160.78 TP80.1
DMI_IT_MR_DN0: length 173.1
  TOP w0.102: v3(47.82,47.26) 47.61,47.47 47.61,47.61 47.31,47.92 46.22,47.92 45.98,47.68 44.8,47.68 44.7,47.78 44.45,47.78 44.19,47.52 U29.C20 ; U27.T3 98.04,153.72 96.13,153.72 95.74,153.33 87.72,153.33 83.78,157.26 75.93,157.26 70.93,152.26 70.93,151.08 v1(70.79,150.95)
  BOTTOM w0.102: 69.3,150.65 v2(69.66,150.65) ; 69.3,150.65 69.3,143.34 68.85,142.89 68.85,140.9 41.06,113.11 41.06,107.61 38.82,105.37 38.82,87.34 58.96,67.2 58.96,53.95 52.53,47.51 51.04,47.51 50.44,48.11 48.12,48.11 47.82,47.81 v3(47.82,47.26) ; 69.3,150.65 69.3,151.04 69.74,151.47 70.88,151.47 70.99,151.36 70.99,151.15 v1(70.79,150.95)
DMI_IT_MR_DN1: length 171
  TOP w0.102: U29.D21 43.71,46.97 44.02,46.66 44.68,46.66 44.83,46.51 46.28,46.51 46.38,46.61 47.45,46.61 47.64,46.42 49.12,46.42 49.43,46.72 49.43,47.23 v3(49.52,47.32) ; U27.V1 96.26,152.55 87.27,152.55 83.41,156.41 76.85,156.41 73.1,152.66 73.1,151.31 72.09,150.3 72.09,149.83 v1(72.36,149.56)
  BOTTOM w0.102: 70.02,142.44 70.02,141.49 42.1,113.57 42.1,107.56 39.23,104.69 39.23,87.64 59.37,67.5 59.37,53.78 52.63,47.04 49.8,47.04 v3(49.52,47.32) ; 70.02,142.44 70.02,149.87 70.59,150.44 71.89,150.44 72.19,150.15 72.19,149.73 v1(72.36,149.56) ; 70.02,142.44 v2(69.65,142.44)
DMI_IT_MR_DN2: length 171.4
  TOP w0.102: v1(72.06,147.25) 72.24,147.25 72.4,147.41 72.4,148.31 72.89,148.8 72.89,150.17 73.3,150.58 73.3,150.58 73.51,150.79 73.51,152.46 77.06,156.01 83.24,156.01 87.12,152.12 96.11,152.12 96.34,151.89 97.13,151.89 U27.V2 ; v3(46.53,46.15) 46.13,46.15 45.97,46.3 45.62,46.3 45.5,46.19 44.71,46.19 U29.B22
  BOTTOM w0.102: 71.31,142.14 71.31,141.6 42.94,113.23 42.94,106.95 40.07,104.08 40.07,87.99 60.21,67.85 60.21,53.43 52.98,46.2 48.25,46.2 47.85,46.6 46.22,46.6 46.08,46.46 46.08,46.28 46.2,46.15 v3(46.53,46.15) ; 71.31,142.14 71.31,147.46 71.8,147.95 72.32,147.95 72.5,147.76 72.5,147.48 72.28,147.25 v1(72.06,147.25) ; 71.31,142.14 v2(71.65,142.14)
DMI_IT_MR_DN3: length 169.1
  TOP w0.102: U27.W3 98.4,151.32 98.06,150.97 97.07,150.97 96.98,150.89 94.99,150.89 94.45,151.43 86.59,151.43 82.82,155.21 77.6,155.21 74.4,152 74.4,148.92 74.32,148.84 74.04,148.84 v1(73.81,149.07) ; U29.A24 45.07,45.49 45.21,45.35 45.86,45.35 46.22,45.71 46.76,45.71 47.04,45.43 v3(47.04,45.28)
  BOTTOM w0.102: 72.95,145.01 72.95,142.66 43.35,113.06 43.35,106.39 40.47,103.52 40.47,88.18 60.61,68.04 60.61,53.26 53.15,45.8 48.56,45.8 47.84,45.07 47.24,45.07 v3(47.04,45.28) ; 72.95,145.01 v2(72.57,145.01) ; 72.95,145.01 72.95,146.48 73.55,147.08 73.55,148.81 v1(73.81,149.07)
DMI_IT_MR_DP0: length 173.1
  TOP w0.102: v1(71.7,150.95) 71.43,150.95 71.15,151.24 71.15,152.17 76.02,157.05 83.69,157.05 87.63,153.11 95.83,153.11 96.22,153.5 98.06,153.5 U27.U3 ; v3(47.17,47.26) 47.31,47.26 47.4,47.35 47.4,47.52 47.22,47.7 46.3,47.7 46.07,47.46 U29.B20
  BOTTOM w0.102: v1(71.7,150.95) 71.4,150.95 71.21,151.15 71.21,151.45 70.97,151.69 69.65,151.69 69.09,151.13 69.09,145.44 ; 69.09,145.44 69.09,143.43 68.63,142.98 68.63,140.99 40.84,113.2 40.84,107.7 38.61,105.46 38.61,87.25 58.75,67.11 58.75,54.04 52.44,47.73 51.13,47.73 50.53,48.32 48.03,48.32 47.61,47.9 47.61,47.73 47.48,47.6 47.3,47.6 47.17,47.47 v3(47.17,47.26) ; 69.09,145.44 v2(68.73,145.44)
DMI_IT_MR_DP1: length 171
  TOP w0.102: U29.B21 44.23,46.88 44.77,46.88 44.92,46.72 46.19,46.72 46.29,46.82 47.54,46.82 47.73,46.63 49.04,46.63 49.21,46.81 49.21,46.99 v3(48.88,47.32) ; v1(71.5,149.61) 71.75,149.61 71.87,149.72 71.87,150.39 72.89,151.4 72.89,152.75 76.76,156.63 83.5,156.63 87.36,152.77 96.18,152.77 U27.U1
  BOTTOM w0.102: 70.23,147.93 v2(70.57,147.93) ; 70.23,147.93 70.23,149.78 70.68,150.22 71.81,150.22 71.97,150.06 71.97,149.82 71.75,149.61 v1(71.5,149.61) ; 70.23,147.93 70.23,141.4 42.32,113.49 42.32,107.47 39.45,104.6 39.45,87.73 59.58,67.59 59.58,53.69 52.72,46.82 49.38,46.82 v3(48.88,47.32)
DMI_IT_MR_DP2: length 171.3
  TOP w0.102: U29.C22 44.12,46.35 44.5,45.97 45.69,45.97 v3(45.79,45.88) ; v1(72.92,147.25) 72.62,147.55 72.62,148.22 73.11,148.71 73.11,150.08 73.51,150.49 73.51,150.49 73.72,150.7 73.72,152.37 77.15,155.79 83.15,155.79 87.03,151.9 96.02,151.9 96.25,151.68 97.14,151.68 U27.W2
  BOTTOM w0.102: 71.1,144.27 71.1,141.69 42.72,113.32 42.72,107.04 39.85,104.17 39.85,87.9 59.99,67.76 59.99,53.52 52.89,46.42 48.34,46.42 47.94,46.81 46.13,46.81 45.86,46.55 45.86,45.95 v3(45.79,45.88) ; 71.1,144.27 71.1,147.55 71.71,148.17 72.41,148.17 72.72,147.85 72.72,147.45 v1(72.92,147.25) ; 71.1,144.27 v2(70.78,144.27)
DMI_IT_MR_DP3: length 169.1
  TOP w0.102: v3(46.4,45.29) 46.1,45.29 45.95,45.14 44.98,45.14 44.44,45.68 U29.B24 ; U27.Y3 98.06,150.76 97.16,150.76 97.07,150.67 94.9,150.67 94.36,151.21 86.51,151.21 82.73,154.99 77.69,154.99 74.61,151.91 74.61,148.83 v1(74.02,148.23)
  BOTTOM w0.102: v1(74.02,148.23) 73.76,147.98 73.76,146.99 73.16,146.39 73.16,142.57 69.56,138.97 ; v3(46.4,45.29) 46.83,44.86 47.93,44.86 48.65,45.58 53.24,45.58 60.83,53.17 60.83,68.13 40.69,88.27 40.69,103.43 43.56,106.3 43.56,112.97 69.56,138.97 ; 69.56,138.97 v2(69.8,138.73)
DMI_MT_IR_DN0: length 178.1
  TOP w0.102: U27.AA5 99.64,150.08 98.12,150.08 97.89,150.32 94.44,150.32 93.95,150.81 86.03,150.81 82.63,154.2 78.31,154.2 75.35,151.24 75.35,150.75 v1(75.11,150.5) ; U29.L24 39.55,45.27 v3(39.22,44.93)
  BOTTOM w0.102: 54.5,120.71 76.28,142.5 76.28,149.45 75.48,150.25 75.35,150.25 v1(75.11,150.5) ; 54.5,120.71 44.81,111.02 44.81,105.13 41.95,102.28 41.95,88.76 62.07,68.65 62.07,52.66 53.75,44.34 49.03,44.34 48.55,43.85 44.95,43.85 44.36,44.44 41.78,44.44 41.64,44.3 39.6,44.3 39.36,44.53 39.36,44.79 v3(39.22,44.93) ; 54.5,120.71 v2(54.72,120.49)
DMI_MT_IR_DN1: length 175.5
  TOP w0.102: v3(41.39,44.95) 41.39,45.21 U29.G24 ; v1(75.61,146.47) 75.35,146.72 75.03,146.72 74.76,146.99 74.76,147.92 75.18,148.34 75.9,148.34 76.21,148.65 76.21,151.22 78.57,153.58 82.15,153.58 85.59,150.14 93.49,150.14 94.2,149.43 96.59,149.43 96.86,149.16 98.74,149.16 U27.AB4
  BOTTOM w0.102: 57.32,125.11 v2(57.56,124.87) ; 57.32,125.11 74.37,142.16 74.37,146.4 74.69,146.72 75.35,146.72 v1(75.61,146.47) ; 57.32,125.11 44.18,111.98 44.18,105.78 41.31,102.91 41.31,88.53 61.45,68.39 61.45,52.92 53.49,44.96 48.87,44.96 48.26,44.35 45.78,44.35 44.95,45.17 42.51,45.17 42.25,45.43 41.19,45.43 41.07,45.31 41.07,45.09 41.2,44.95 v3(41.39,44.95)
DMI_MT_IR_DN2: length 163.5
  TOP w0.102: v1(98.87,148.15) 99.17,148.15 99.31,148.01 U27.AC4 ; v3(42.14,43.74) 42.01,43.86 42.01,44.31 42.14,44.43 U29.F26
  BOTTOM w0.102: v1(98.87,148.15) 98.87,148.01 98.99,147.88 99.19,147.88 99.31,148.01 99.31,148.59 99.07,148.83 97.12,148.83 96.63,149.33 86.23,149.33 82.07,145.16 80.52,145.16 50.7,115.34 ; 50.7,115.34 v2(50.93,115.11) ; 50.7,115.34 45.43,110.07 45.43,86.17 62.7,68.9 62.7,52.4 54.01,43.71 49.23,43.71 48.77,43.26 44.32,43.26 43.64,43.94 42.34,43.94 v3(42.14,43.74)
DMI_MT_IR_DN3: length 161.7
  TOP w0.102: U27.AC2 97.15,148 96.1,148 v1(95.88,148.22) ; v3(39.87,43.76) 40.26,44.15 U29.K26
  BOTTOM w0.102: 63.98,127.25 v2(63.75,127.48) ; 63.98,127.25 81.46,144.74 82.29,144.74 86.45,148.89 95.12,148.89 95.47,148.55 95.47,148.31 95.56,148.22 v1(95.88,148.22) ; 63.98,127.25 46.04,109.31 46.04,86.14 63.1,69.07 63.1,52.23 54.15,43.28 49.35,43.28 49.01,42.94 43.98,42.94 43.88,42.84 43.34,42.84 42.89,43.29 39.89,43.29 39.74,43.45 39.74,43.63 v3(39.87,43.76)
DMI_MT_IR_DP0: length 178
  TOP w0.102: U29.K24 40.26,45.38 v3(39.87,44.99) ; v1(75.11,149.64) 75.47,149.64 75.56,149.73 75.56,151.15 78.4,153.98 82.55,153.98 85.94,150.59 93.86,150.59 94.35,150.1 97.8,150.1 98.03,149.87 99.55,149.87 99.7,149.72 99.7,149.61 99.6,149.5 U27.AA4
  BOTTOM w0.102: 71.96,138.48 76.07,142.59 76.07,149.36 75.4,150.04 75.18,150.04 75.11,149.96 v1(75.11,149.64) ; 71.96,138.48 v2(71.7,138.73) ; 71.96,138.48 44.59,111.11 44.59,105.22 41.74,102.37 41.74,88.68 61.86,68.56 61.86,52.75 53.66,44.55 48.95,44.55 48.46,44.07 45.03,44.07 44.45,44.65 41.69,44.65 41.55,44.51 39.69,44.51 39.58,44.62 39.58,44.7 v3(39.87,44.99)
DMI_MT_IR_DP1: length 175.4
  TOP w0.102: v3(40.63,44.99) 40.97,45.33 U29.H24 ; v1(75.59,147.47) 75.59,147.04 75.49,146.94 75.12,146.94 74.98,147.08 74.98,147.83 75.27,148.12 75.98,148.12 76.43,148.56 76.43,151.13 78.66,153.36 82.06,153.36 85.5,149.92 93.4,149.92 94.11,149.21 96.5,149.21 96.77,148.95 98.65,148.95 98.78,148.81 98.78,148.69 98.67,148.59 U27.AB3
  BOTTOM w0.102: 63.82,131.91 74.16,142.25 74.16,146.49 74.6,146.94 75.44,146.94 75.59,147.09 v1(75.59,147.47) ; 63.82,131.91 v2(63.56,132.18) ; 63.82,131.91 43.97,112.06 43.97,105.87 41.1,103 41.1,88.44 61.24,68.3 61.24,53 53.4,45.17 48.78,45.17 48.17,44.56 45.87,44.56 45.04,45.39 42.6,45.39 42.34,45.64 41.1,45.64 40.86,45.4 40.86,45.22 v3(40.63,44.99)
DMI_MT_IR_DP2: length 163.5
  TOP w0.102: U29.G26 41.68,44.05 v3(41.39,43.76) ; v1(99.77,148.15) 100.23,147.7 U27.AC5
  BOTTOM w0.102: v1(99.77,148.15) 99.53,148.39 99.53,148.68 99.16,149.05 97.21,149.05 96.72,149.54 86.14,149.54 81.98,145.38 80.43,145.38 68.59,133.54 ; 68.59,133.54 v2(68.35,133.78) ; 68.59,133.54 45.21,110.16 45.21,86.08 62.48,68.81 62.48,52.49 53.92,43.93 49.14,43.93 48.68,43.47 44.41,43.47 43.73,44.16 41.92,44.16 41.52,43.76 v3(41.39,43.76)
DMI_MT_IR_DP3: length 161.7
  TOP w0.102: v3(39.11,43.77) 39.55,44.22 U29.L26 ; v1(95.02,148.01) 95.26,147.77 96.08,147.77 96.1,147.79 96.47,147.79 96.57,147.69 U27.AC1
  BOTTOM w0.102: 63.32,65.07 63.32,52.14 54.24,43.06 49.44,43.06 49.1,42.72 44.07,42.72 43.97,42.62 43.26,42.62 42.8,43.08 39.8,43.08 v3(39.11,43.77) ; 63.32,65.07 63.32,69.16 46.25,86.23 46.25,109.22 81.55,144.52 82.38,144.52 86.54,148.68 95.03,148.68 95.25,148.46 95.25,148.24 v1(95.02,148.01) ; 63.32,65.07 v2(63.67,65.07)
DMIRCOMP: length 6
  TOP w0.102: 45.83,47.95 45.79,47.92 44.9,47.92 44.61,48.21 U29.B19
  TOP w0.203: R697.2 49.41,48.45 v2(48.79,48.45) 46.32,48.45 45.83,47.95
DP_COMP: length 7.8
  TOP w0.305: R805.2 93.73,157.02 94.06,156.69 v1(94.06,155.78) ; U27.R4 v1(98.87,155.43)
  BOTTOM w0.305: v1(94.06,155.78) v2(95.45,155.78) 95.67,155.99 98.14,155.99 98.71,155.43 v1(98.87,155.43)
DRVON: length 169.5
  TOP w0.165: C227.1 176.58,156.67 v1(177.42,157.51) 177.54,157.63 U52.13 ; R177.1 145.36,196.52 v1(145.62,196.27) ; R156.2 189.41,182.45 v1(189.92,181.94) ; R203.2 83.24,200.18 v1(83.03,200.38)
  BOTTOM w0.165: v1(83.03,200.38) 84.68,200.38 86.61,202.31 110.87,202.31 v2(112.07,201.11) 112.32,200.86 112.85,200.86 117.29,205.3 136.5,205.3 145.54,196.27 v1(145.62,196.27) 145.62,196.19 148.77,193.03 155.22,193.03 156.7,191.56 177.14,191.56 178.75,189.95 182.73,189.95 185.52,187.16 185.52,186.34 v1(189.92,181.94) 191.12,180.74 191.12,158.75 185.61,153.24 183.06,153.24 178.79,157.51 v1(177.42,157.51)
DSWVRMEN: length 10.7
  TOP w0.102: U29.AM41 28.2,34.38 26.74,32.92 26.4,32.92 25.45,31.97 25.45,30.58 24.99,30.12 24.99,28.24 v2(25.17,28.07) 25.2,28.04 R494.2
DTR1#: length 5.7
  TOP w0.102: R634.1 R633.1 96.7,20.78 v2(97.29,20.18) 98.07,19.4 U61.61
DUAL_V: length 14.6
  TOP w0.102: C89.1 180.94,35.79 R2238.2 v2(182.35,34.92) 183.29,34.92 184.68,36.32 184.68,36.68 184.69,36.69 184.69,37.28 183.57,38.4 183.57,39.34 182.26,40.65 181.15,40.65 180.94,40.86 Q51.G
DUAL_V_1: length 177.4
  TOP w0.165: v1(180.01,55.14) 181.67,53.48 R688.2 181.67,52.77 181.99,52.45 Q58.D ; v1(195.96,153.8) 195.28,154.48 195.28,155.63 195.9,156.25 195.9,187.24 196.11,187.45 196.11,198.27 194.11,200.28 U14.2 ; U31.2 171.14,56.02 v1(171.04,56.12)
  BOTTOM w0.165: v1(195.96,153.8) 196.04,153.72 196.04,125.3 191.59,120.85 191.59,103.36 192.09,102.85 192.09,99.11 191.5,98.51 191.5,87.1 186.23,81.83 186.23,76.19 186.79,75.63 186.79,71.36 177.59,62.15 175.31,62.15 171.04,57.88 v2(171.04,57.15) v1(171.04,56.12) 171.39,55.77 179.39,55.77 v1(180.01,55.14)
DUAL_V_AND: length 4.1
  TOP w0.165: Q50.1 170.46,49.02 170.05,49.43 170.05,49.94 170.44,50.32 Q50.3 171.25,50.32 171.6,50.67 v2(172.21,50.67)
DUAL_V_AND_R: length 2.2
  TOP w0.165: R486.2 167.7,49.67 v1(167.87,49.5) 167.97,49.5 168.14,49.67 Q50.5
DUAL_V_U: length 173.3
  TOP w0.165: U31.4 172.45,59.49 R459.2 173.65,60.68 v1(174.58,60.68) ; v1(195.94,154.69) 196.39,155.14 196.39,186.94 196.67,187.22 196.67,200.53 194.38,202.82 U14.4 ; Q42.6 176.62,57.95 176.8,57.77 176.8,56.48 v1(176.6,56.28)
  BOTTOM w0.165: v1(195.94,154.69) 196.56,154.06 196.56,125 192.15,120.6 192.15,103.52 192.56,103.12 192.56,98.85 192.05,98.34 192.05,86.92 186.79,81.67 186.79,76.36 187.31,75.85 187.31,71.14 176.84,60.68 v1(174.58,60.68) 172.97,59.07 v2(172.97,58.24) 172.97,56.89 173.58,56.28 v1(176.6,56.28)
DUAL_V_U_AND: length 4.3
  TOP w0.165: v2(175.32,61.66) Q42.3 175.32,59.63 175.51,59.44 176.49,59.44 176.66,59.6 176.66,60.37 Q42.1
DUAL_V_U_INV_R: length 3.1
  TOP w0.165: Q50.2 171.69,49.67 172.19,49.17 v2(172.72,49.17) 173.19,49.17 R491.2
EAPD_DEPOP: length 2.5
  TOP w0.102: TP48.1 19.01,236.23 U2.47
EXP_A_RX_DN0: length 107.9
  TOP w0.127: SLOT2.A17 21.29,180.55 21.5,180.34 30.63,180.34 30.98,179.99 31.15,179.99 v1(31.47,179.67) ; v1(108.91,163.67) U27.F15
  BOTTOM w0.127: v1(31.47,179.67) 31.68,179.67 36.25,175.09 40.55,175.09 47.86,182.41 49.56,182.41 ; 49.56,182.41 86.5,182.41 94.38,174.53 104.23,174.53 108.19,170.57 108.19,166.08 108.27,166 108.35,165.92 108.46,165.81 108.46,164.13 v1(108.91,163.67) ; 49.56,182.41 v2(49.56,182.06)
EXP_A_RX_DN1: length 105.1
  TOP w0.127: v1(30.67,176.16) 30.35,176.48 20.26,176.48 20,176.22 20,176.06 20.51,175.55 SLOT2.A22 ; U27.E14 v1(108,163.67)
  BOTTOM w0.127: v1(30.67,176.16) 30.96,176.45 32.08,176.45 32.69,175.84 ; 32.69,175.84 v2(32.46,175.62) ; 32.69,175.84 32.79,175.74 35.38,173.15 40.83,173.15 48.1,180.42 85.17,180.42 90.65,174.94 92.22,174.94 93.49,173.67 103.47,173.67 106.5,170.63 106.5,168.45 107.55,167.4 107.55,166.07 107.26,165.78 107.26,164.41 v1(108,163.67)
EXP_A_RX_DN2: length 102.2
  TOP w0.127: v1(30.63,172.03) 30.33,172.34 25.12,172.34 24.92,172.54 20.2,172.54 19.94,172.29 19.94,171.68 20.07,171.55 SLOT2.A26 ; U27.F13 v1(107.08,162.76)
  BOTTOM w0.127: v2(32.43,171.62) 32.66,171.85 ; 32.66,171.85 32.15,172.36 30.95,172.36 v1(30.63,172.03) ; 32.66,171.85 32.97,171.54 41.95,171.54 49.05,178.65 84.65,178.65 90.51,172.78 101.21,172.78 104.88,169.11 104.88,168.36 106.18,167.06 106.18,166.18 106.44,165.92 106.63,165.74 106.63,163.22 v1(107.08,162.76)
EXP_A_RX_DN3: length 100.5
  TOP w0.127: SLOT2.A30 20.35,167.55 20.22,167.68 20.22,168.34 20.35,168.46 30.53,168.46 v1(30.81,168.19) ; U27.E12 v1(106.17,163.67)
  BOTTOM w0.127: v2(38.94,166.42) 38.94,166.73 ; 38.94,166.73 39.45,166.73 49.64,176.92 83.63,176.92 88.63,171.91 100.81,171.91 103.4,169.32 103.4,168.89 103.4,168.68 105.45,166.64 105.45,164.4 v1(106.17,163.67) ; 38.94,166.73 34.29,166.73 32.5,168.52 31.14,168.52 v1(30.81,168.19)
EXP_A_RX_DN4: length 101.2
  TOP w0.127: SLOT2.A36 20.27,161.55 20.12,161.7 20.12,162.32 20.29,162.49 21.56,162.49 22.17,161.87 28.24,161.87 28.96,161.16 30.87,161.16 v1(31.11,160.92) ; U27.F11 v1(105.26,162.76)
  BOTTOM w0.127: v1(31.11,160.92) 31.46,161.28 35.71,161.28 ; 35.71,161.28 36.28,161.28 50.35,175.34 81.98,175.34 85.34,171.98 86.67,171.98 87.6,171.05 100.29,171.05 104.82,166.52 104.82,163.93 104.78,163.88 104.78,163.24 v1(105.26,162.76) ; 35.71,161.28 v2(35.71,160.93)
EXP_A_RX_DN5: length 100.8
  TOP w0.127: SLOT2.A40 20.32,157.55 20.17,157.7 20.17,158.26 20.36,158.44 31.04,158.44 v1(31.39,158.09) ; U27.G10 104.79,162.3 104.37,161.88 104.37,161.87 v1(104.36,161.86)
  BOTTOM w0.127: v1(104.36,161.86) 103.88,162.34 103.88,163.9 103.61,164.18 103.61,165.88 101.95,167.54 101.65,167.54 101.07,168.12 101.07,168.93 99.84,170.15 92.08,170.15 91.12,169.19 85.68,169.19 81.46,173.41 50.68,173.41 35.68,158.41 33.02,158.41 ; 33.02,158.41 31.71,158.41 v1(31.39,158.09) ; 33.02,158.41 v2(33.02,158.04)
EXP_A_RX_DN6: length 99.6
  TOP w0.127: v1(31.62,153.92) 31.29,154.25 24.11,154.25 23.83,154.54 20.26,154.54 20.13,154.41 20.13,153.68 20.26,153.55 SLOT2.A44 ; U27.F9 v1(103.43,162.76)
  BOTTOM w0.127: v1(103.43,162.76) 102.97,163.22 102.97,165.73 102.62,166.07 101.8,166.9 101.39,166.9 100.37,167.92 100.37,168.5 99.6,169.27 92.42,169.27 91.47,168.33 85.39,168.33 84.25,169.47 82.75,169.47 80.38,171.84 74.93,171.84 ; v1(31.62,153.92) 31.94,154.24 33.82,154.24 34.66,155.08 51.42,171.84 74.93,171.84 ; v2(74.93,171.53) 74.93,171.84
EXP_A_RX_DN7: length 98
  TOP w0.127: v1(31.14,150.08) 30.83,150.39 20.25,150.39 20.08,150.22 20.08,149.68 20.21,149.55 SLOT2.A48 ; U27.G8 v1(102.51,162.76)
  BOTTOM w0.127: 32.88,150.4 33.73,150.4 38.06,154.72 38.06,156.02 51.97,169.93 80.04,169.93 82.5,167.46 92.83,167.46 93.57,166.73 98.22,166.73 98.6,167.11 99.77,167.11 100.34,166.54 100.34,165.63 102.06,163.91 102.06,163.22 v1(102.51,162.76) ; 32.88,150.4 31.46,150.4 v1(31.14,150.08) ; 32.88,150.4 v2(32.88,150.04)
EXP_A_RX_DN8: length 95
  TOP w0.127: SLOT2.A53 19.66,144.55 19.71,144.5 30.61,144.5 v1(30.84,144.27) ; U27.D4 99.34,165.04 v1(99.78,165.49)
  BOTTOM w0.127: 51.59,166.49 53.17,168.07 53.17,168.07 53.34,168.25 78.44,168.25 79,167.69 80.67,167.69 81.74,166.62 92.48,166.62 93.04,166.07 97.21,166.07 98.12,165.15 98.22,165.05 99.34,165.05 v1(99.78,165.49) ; 51.59,166.49 v2(51.84,166.24) ; 51.59,166.49 47.88,162.78 47.88,160.58 31.82,144.52 31.08,144.52 v1(30.84,144.27)
EXP_A_RX_DN9: length 96.4
  TOP w0.127: U27.E5 v1(99.78,164.57) ; SLOT2.A57 19.52,140.55 19.63,140.44 25.37,140.44 25.83,139.98 30.3,139.98 v1(30.61,139.67)
  BOTTOM w0.127: v1(30.61,139.67) 30.89,139.95 31.54,139.95 32.54,140.94 ; v2(32.75,140.74) 32.54,140.94 ; 32.54,140.94 34.85,143.25 34.85,144.78 49.66,159.59 49.66,160.93 55.23,166.5 77.92,166.5 78.69,165.74 92.12,165.74 92.42,165.44 96.77,165.44 98.1,164.11 99.32,164.11 v1(99.78,164.57)
EXP_A_RX_DN10: length 99.1
  TOP w0.127: SLOT2.A61 19.48,136.55 19.68,136.35 31.22,136.35 v1(31.46,136.11) ; U27.F6 v1(100.68,163.67)
  BOTTOM w0.127: v2(71.22,164.47) 71.22,164.78 ; 71.22,164.78 75.94,164.78 76.78,163.94 78.99,163.94 79.93,164.87 91.76,164.87 92.06,164.57 96.51,164.57 98.19,162.9 99.26,162.9 99.58,163.22 100.23,163.22 v1(100.68,163.67) ; 71.22,164.78 57.33,164.78 36.73,144.17 36.73,141.76 32.99,138.02 32.99,136.72 32.68,136.41 31.75,136.41 v1(31.46,136.11)
EXP_A_RX_DN11: length 99.7
  TOP w0.127: U27.G5 v1(100.68,162.76) ; SLOT2.A65 19.67,132.55 19.86,132.36 28.72,132.36 28.88,132.21 30.43,132.21 v1(30.62,132.02)
  BOTTOM w0.127: v2(53.12,156.55) 52.92,156.76 ; 52.92,156.76 58.88,162.72 79.07,162.72 80.36,164.01 91.4,164.01 91.7,163.71 94.37,163.71 95.35,162.73 97.29,162.73 97.72,162.3 U27.G5 v1(100.68,162.76) ; 52.92,156.76 52.46,156.3 52.46,154.95 35,137.49 35,134.87 32.4,132.27 30.87,132.27 v1(30.62,132.02)
EXP_A_RX_DN12: length 100.4
  TOP w0.127: SLOT2.A69 19.6,128.55 19.81,128.35 30.41,128.35 v1(30.63,128.12) ; U27.H6 v1(100.68,161.84)
  BOTTOM w0.127: v1(100.68,161.84) 100.23,161.39 99.96,161.39 99.96,161.39 99.47,161.39 99.47,161.39 99.14,161.06 98.53,161.06 97.91,161.68 97.3,161.68 97.06,161.92 95.01,161.92 94.82,162.11 80.83,162.11 79.76,161.05 71.38,161.05 70.82,160.48 59.69,160.48 56.59,157.39 ; 56.59,157.39 v2(56.82,157.16) ; 56.59,157.39 54.5,155.3 54.5,154.45 46.11,146.06 46.1,146.06 41.29,141.24 41.29,141.23 36.7,136.65 36.7,133.37 31.65,128.32 30.83,128.32 v1(30.63,128.12)
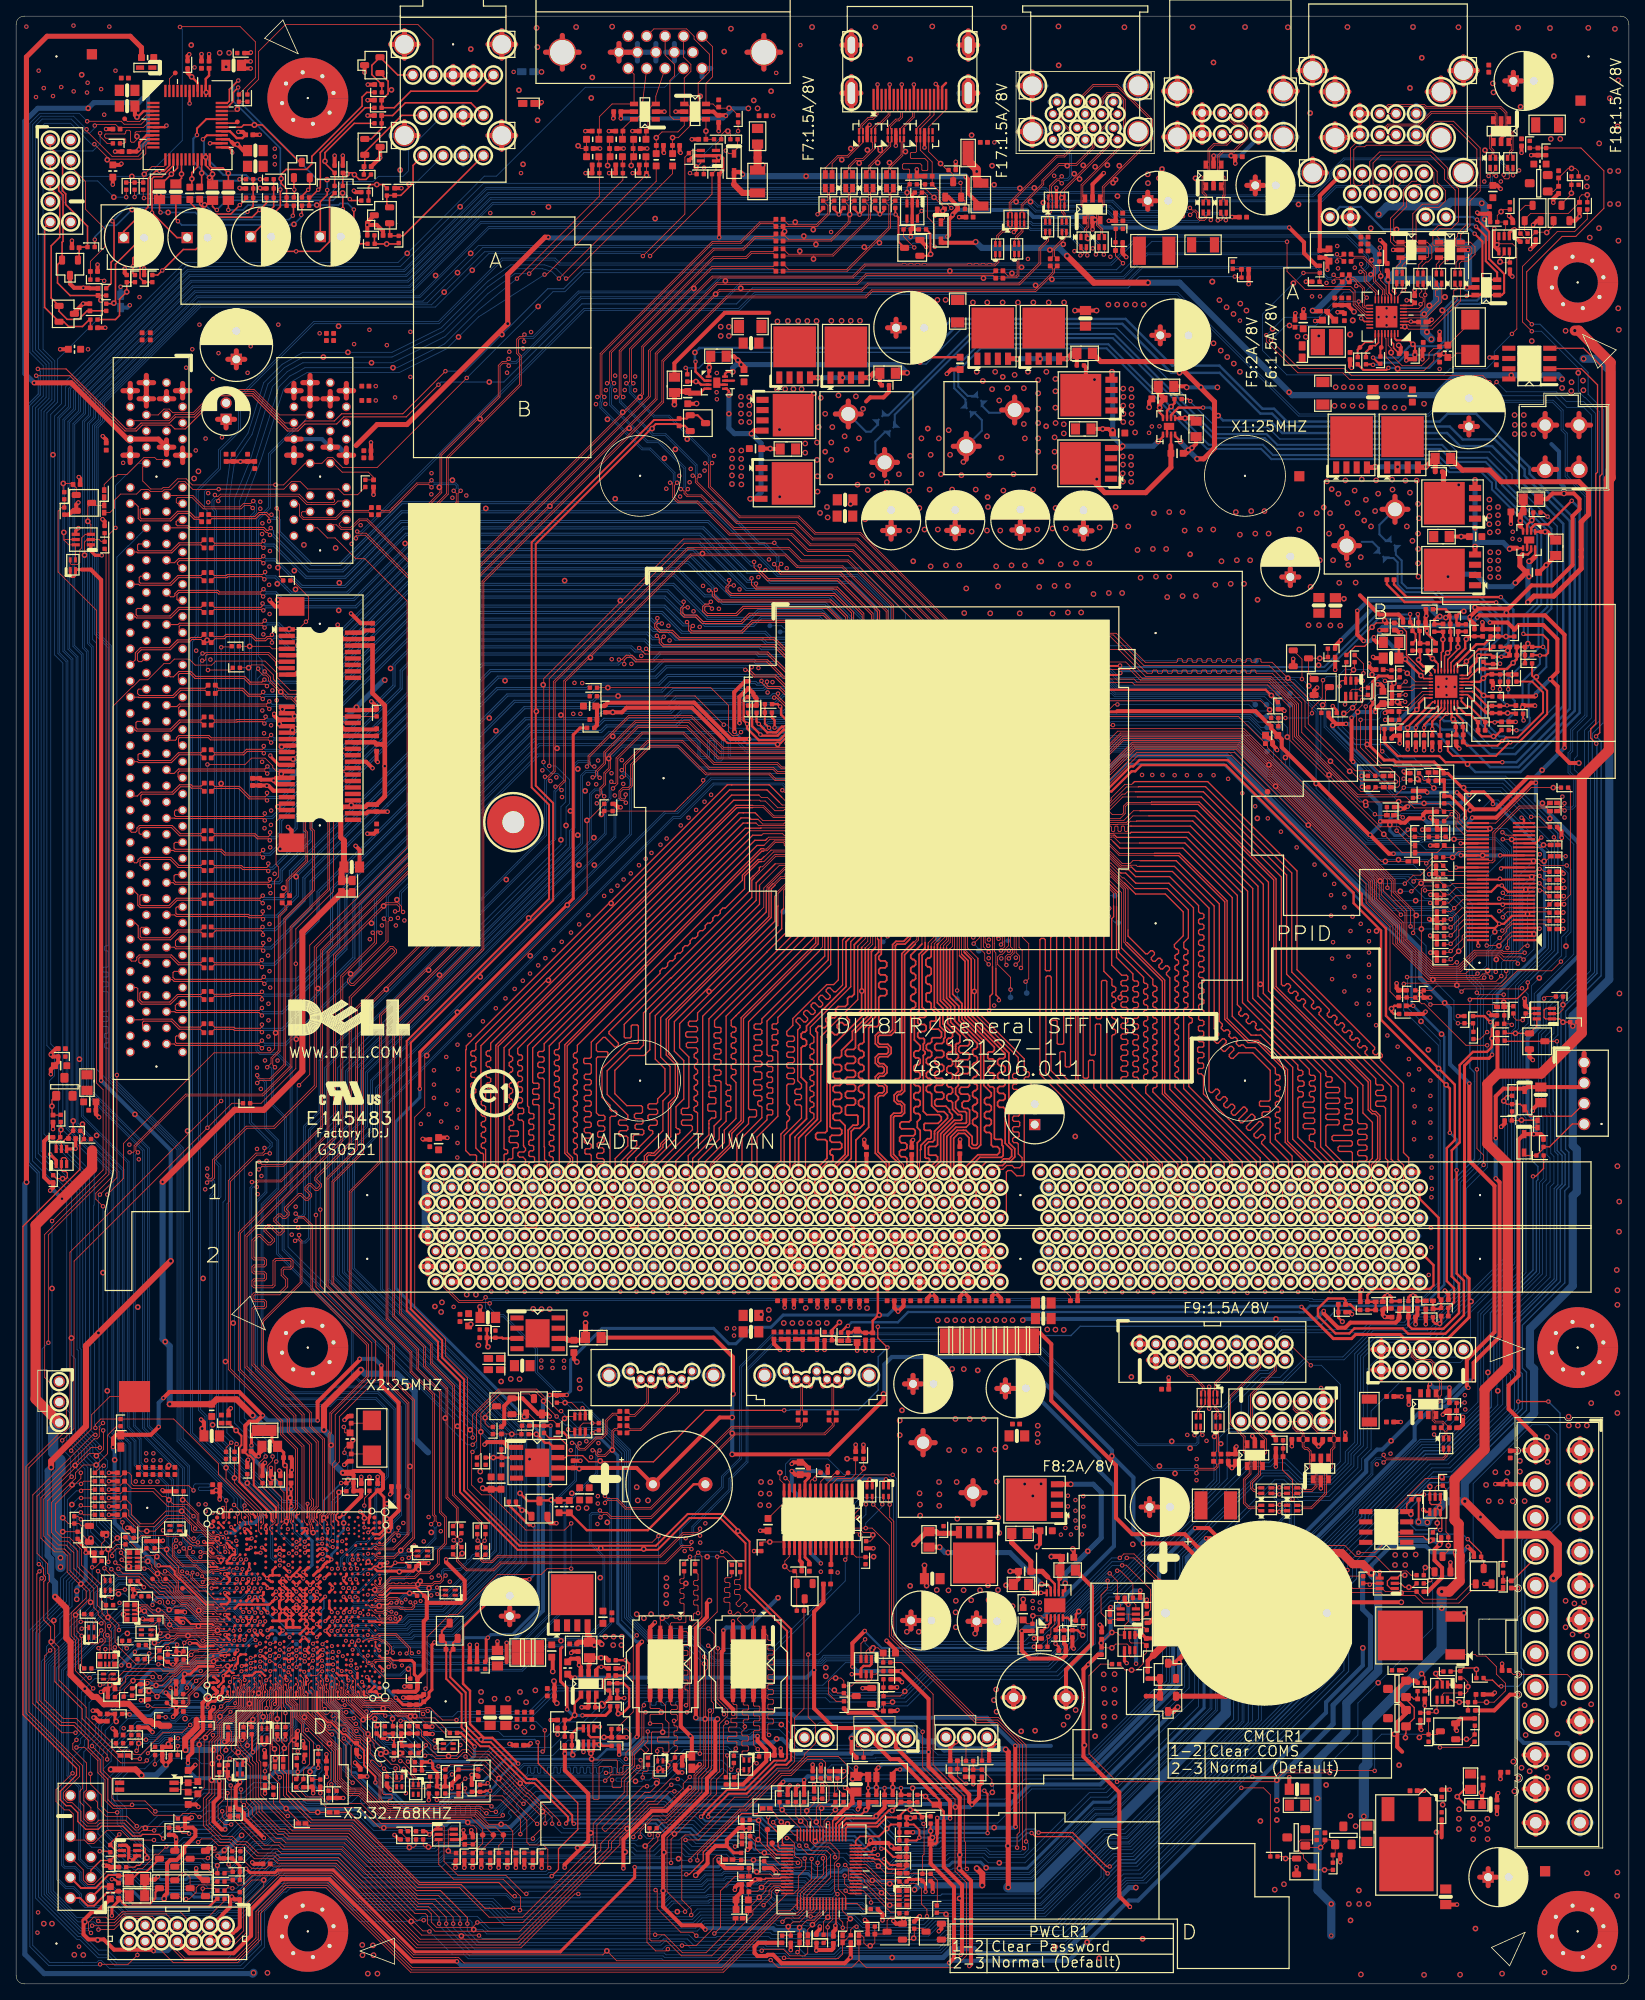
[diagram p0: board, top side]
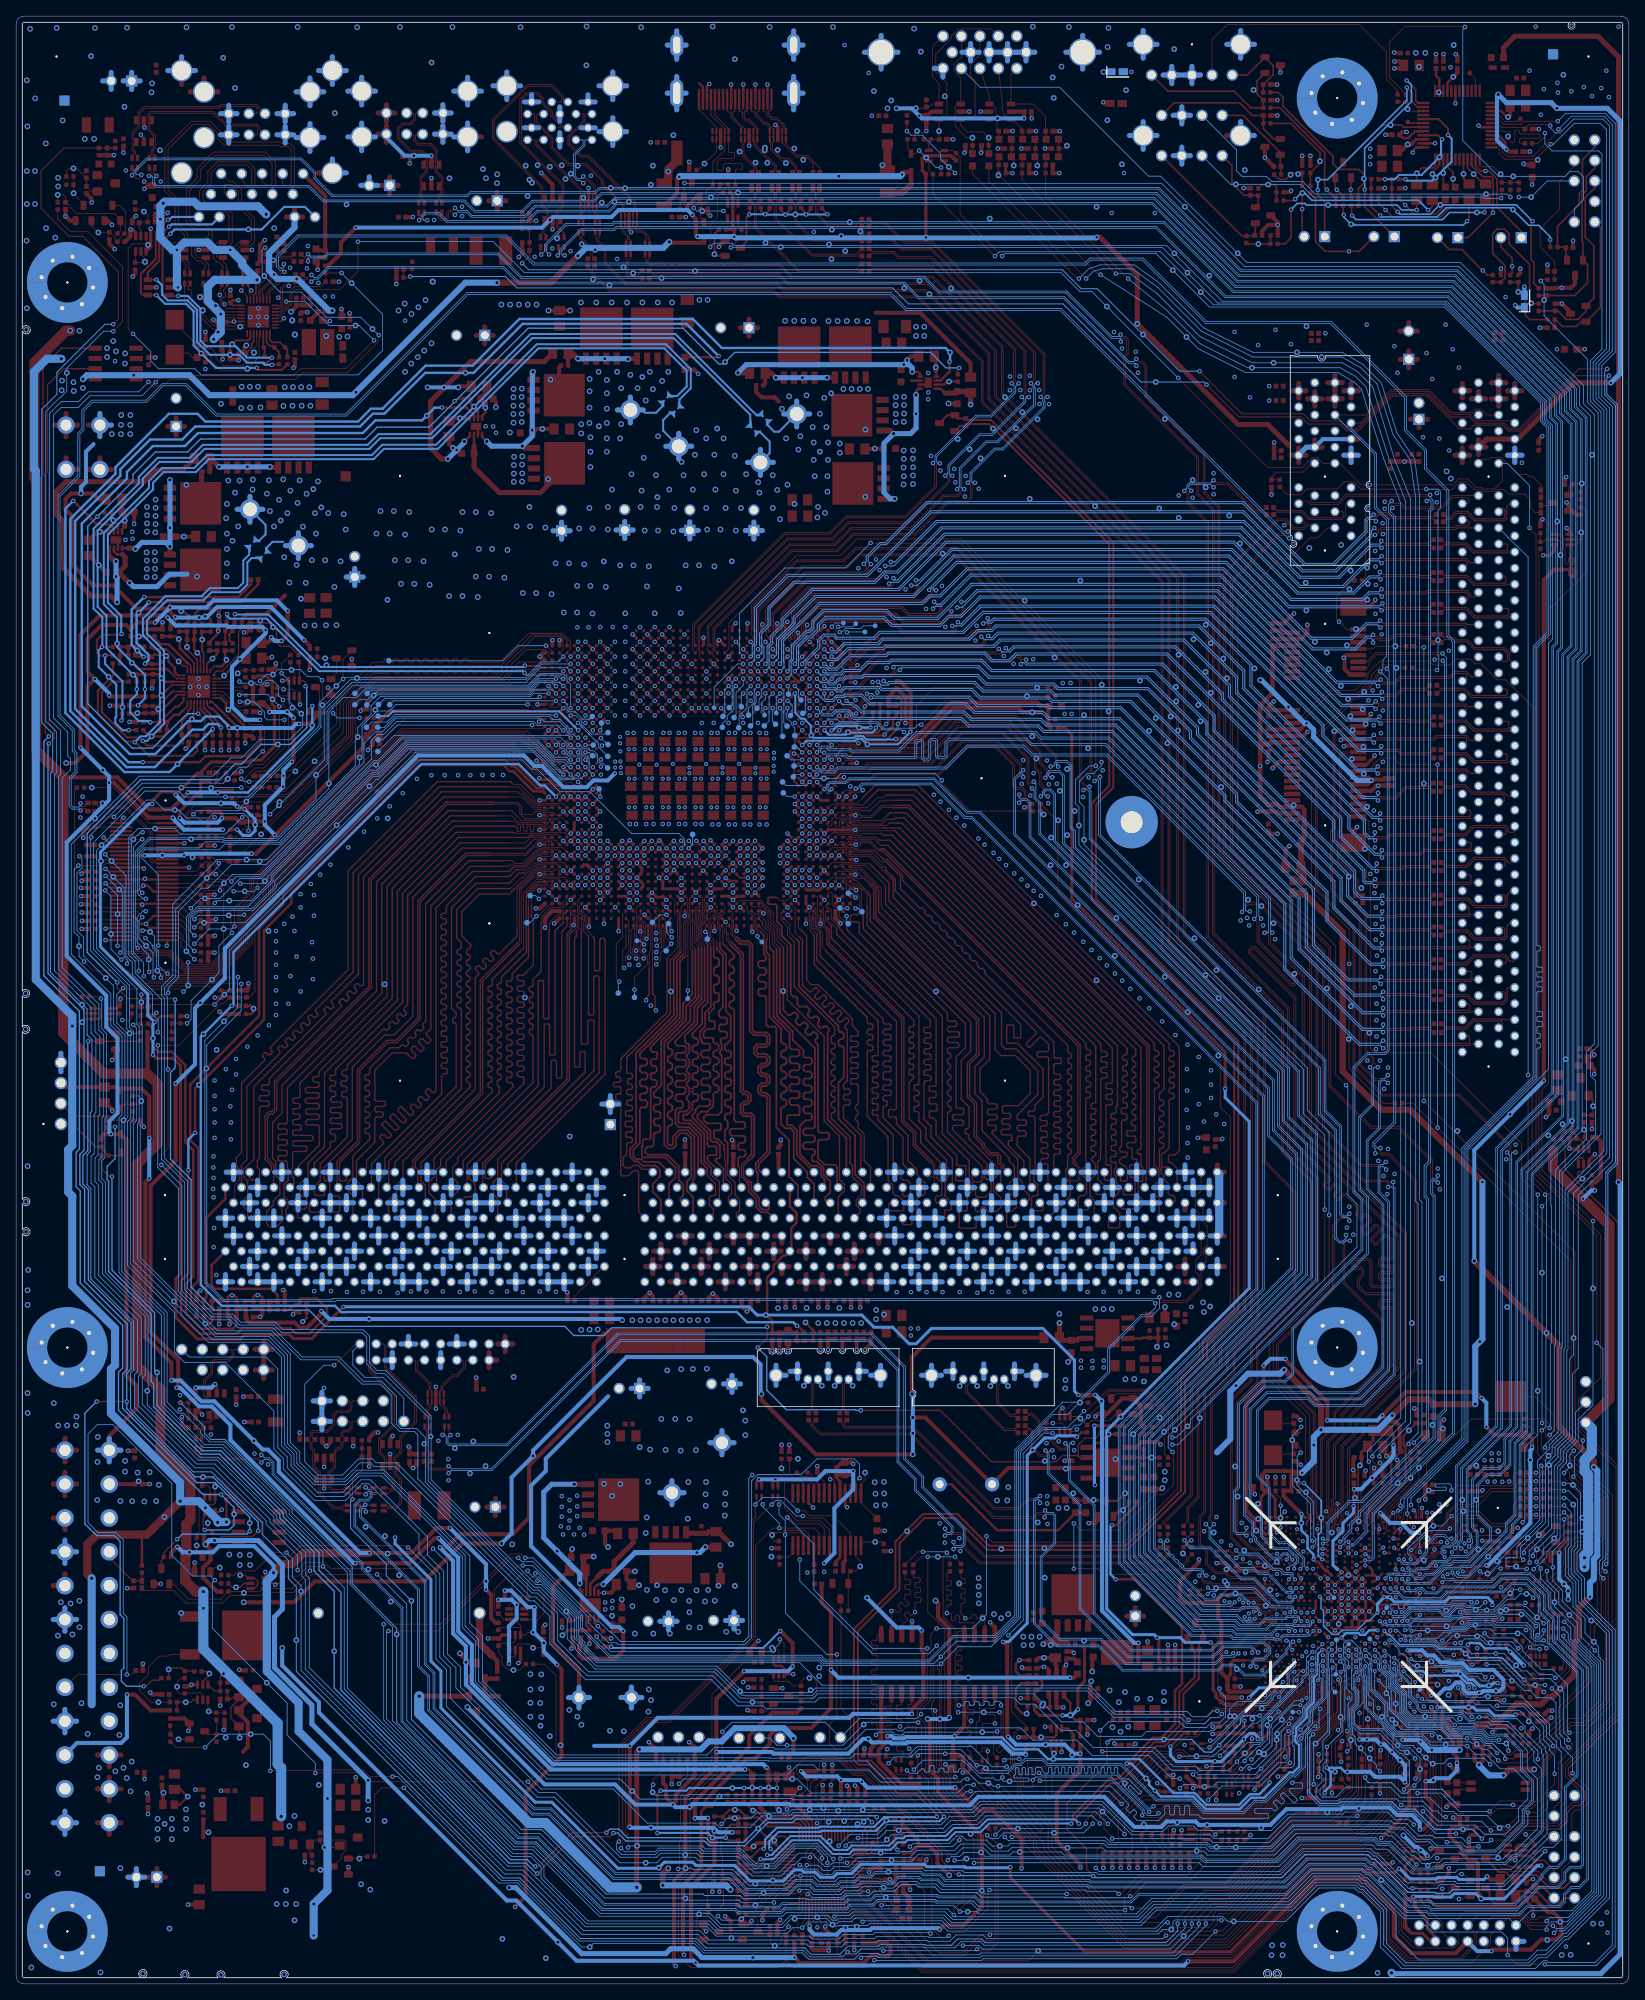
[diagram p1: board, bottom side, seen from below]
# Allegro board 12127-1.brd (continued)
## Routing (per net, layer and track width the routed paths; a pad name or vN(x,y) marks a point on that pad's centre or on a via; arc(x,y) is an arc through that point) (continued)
EXP_A_RX_DN13: length 103.3
  TOP w0.127: U27.J5 v1(100.68,160.93) ; SLOT2.A73 19.34,124.55 19.58,124.31 30.49,124.31 v1(30.78,124.01)
  BOTTOM w0.127: 57.02,154.07 50.22,147.27 50.22,146.69 39.24,135.71 39.24,128.75 34.85,124.36 31.14,124.36 v1(30.78,124.01) ; 57.02,154.07 61.86,158.91 71.58,158.91 71.99,159.32 80.48,159.32 81.55,160.39 92.72,160.39 92.93,160.59 97.24,160.59 97.64,160.19 98.25,160.19 98.53,160.47 U27.J5 v1(100.68,160.93) ; 57.02,154.07 v2(57.23,153.85)
EXP_A_RX_DN14: length 104
  TOP w0.127: v1(100.68,160.02) U27.K6 ; v1(30.48,120.08) 30.11,120.45 19.78,120.45 19.68,120.55 SLOT2.A77
  BOTTOM w0.127: 34.22,121.47 v2(34.48,121.22) ; 34.22,121.47 41.02,128.27 41.02,134.55 63.22,156.75 71.94,156.75 72.73,157.54 81.22,157.54 82.28,158.61 94.15,158.61 95.21,159.67 97.12,159.67 97.26,159.54 98.15,159.54 98.68,159.01 99.68,159.01 v1(100.68,160.02) ; 34.22,121.47 33.05,120.29 30.69,120.29 v1(30.48,120.08)
EXP_A_RX_DN15: length 106.2
  TOP w0.127: U27.L5 v1(100.68,158.19) ; SLOT2.A81 19.61,116.55 19.79,116.37 30.13,116.37 v1(30.48,116.02)
  BOTTOM w0.127: v2(34.75,117.14) 34.48,117.41 ; 34.48,117.41 42.8,125.73 42.8,133.85 64.12,155.18 72.59,155.18 73.28,155.86 81.91,155.86 82.84,156.79 96.11,156.79 96.57,157.25 96.57,157.46 96.84,157.73 98.27,157.73 98.78,157.23 100.01,157.23 100.37,157.59 100.37,157.87 v1(100.68,158.19) ; 34.48,117.41 33.45,116.38 30.84,116.38 v1(30.48,116.02)
EXP_A_RX_DP0: length 107.9
  TOP w0.127: v1(31.57,180.53) 31.29,180.24 31.09,180.24 30.74,180.59 21.61,180.59 21.4,180.8 19.99,180.8 19.84,180.96 19.84,181.31 20.08,181.55 SLOT2.A16 ; v1(108.91,164.59) U27.E15
  BOTTOM w0.127: v1(31.57,180.53) 31.93,180.17 31.93,179.78 36.36,175.35 40.44,175.35 47.76,182.66 58.24,182.66 ; v1(108.91,164.59) 108.71,164.79 108.71,165.91 108.53,166.1 108.44,166.18 108.44,170.68 104.34,174.78 94.49,174.78 86.61,182.66 58.24,182.66 ; 58.24,182.66 v2(58.24,182.96)
EXP_A_RX_DP1: length 105.1
  TOP w0.127: v1(30.66,177.04) 30.35,176.73 20.15,176.73 19.65,176.23 18.97,176.23 SLOT2.A21 ; U27.D14 v1(108,164.59)
  BOTTOM w0.127: v2(40.08,173.74) 40.08,173.41 ; 40.08,173.41 40.73,173.41 47.99,180.67 85.27,180.67 90.75,175.19 92.32,175.19 93.59,173.92 103.57,173.92 106.76,170.74 106.76,168.55 107.81,167.5 107.81,165.96 107.52,165.67 107.52,165.07 v1(108,164.59) ; 40.08,173.41 35.48,173.41 32.18,176.71 30.99,176.71 v1(30.66,177.04)
EXP_A_RX_DP2: length 102.2
  TOP w0.127: SLOT2.A25 18.65,172.5 19.15,172 19.55,172 19.69,172.14 19.69,172.4 20.09,172.8 25.02,172.8 25.23,172.59 30.33,172.59 v1(30.68,172.94) ; U27.E13 v1(107.08,163.67)
  BOTTOM w0.127: 48.45,178.4 41.84,171.8 33.07,171.8 32.26,172.61 31.01,172.61 v1(30.68,172.94) ; 48.45,178.4 48.95,178.9 84.75,178.9 90.62,173.03 101.32,173.03 105.13,169.22 105.13,168.47 106.43,167.17 106.43,166.29 106.88,165.84 106.88,163.88 v1(107.08,163.67) ; 48.45,178.4 v2(48.23,178.61)
EXP_A_RX_DP3: length 100.5
  TOP w0.127: v1(30.84,169.05) 30.51,168.72 20.24,168.72 20.07,168.55 SLOT2.A29 ; U27.D12 v1(106.17,164.59)
  BOTTOM w0.127: 33.62,167.75 32.6,168.77 31.12,168.77 30.84,169.05 v1(30.84,169.05) ; 33.62,167.75 34.39,166.98 39.34,166.98 49.53,177.17 83.74,177.17 88.74,172.17 100.91,172.17 103.66,169.42 103.66,168.79 105.7,166.74 105.7,164.78 105.9,164.59 v1(106.17,164.59) ; 33.62,167.75 v2(33.86,168)
EXP_A_RX_DP4: length 101.2
  TOP w0.127: SLOT2.A35 18.65,162.54 19.12,162.07 19.51,162.07 20.18,162.74 21.67,162.74 22.28,162.13 28.35,162.13 28.78,161.7 29.06,161.42 30.48,161.42 v1(30.79,161.73) ; U27.E11 v1(105.26,163.67)
  BOTTOM w0.127: 37.44,162.79 36.18,161.53 30.98,161.53 v1(30.79,161.73) ; 37.44,162.79 50.24,175.6 82.09,175.6 85.39,172.3 85.45,172.24 86.77,172.24 87.7,171.3 100.4,171.3 105.08,166.62 105.08,163.85 v1(105.26,163.67) ; 37.44,162.79 v2(37.21,163.02)
EXP_A_RX_DP5: length 100.8
  TOP w0.127: v1(31.39,159.03) 31.06,158.7 20.25,158.7 19.93,158.38 18.82,158.38 SLOT2.A39 ; U27.F10 v1(104.34,162.76)
  BOTTOM w0.127: v2(68.02,174.01) 68.02,173.67 ; 68.02,173.67 50.57,173.67 35.57,158.66 31.76,158.66 v1(31.39,159.03) ; 68.02,173.67 81.56,173.67 85.78,169.45 91.01,169.45 91.97,170.41 99.95,170.41 101.32,169.04 101.32,168.22 101.75,167.79 102.06,167.79 103.86,165.99 103.86,164.29 104.14,164.01 104.14,162.96 v1(104.34,162.76)
EXP_A_RX_DP6: length 99.7
  TOP w0.127: U27.E9 v1(103.43,163.67) ; SLOT2.A43 18.99,154.21 19.75,154.21 19.88,154.34 19.88,154.51 20.16,154.79 23.93,154.79 24.21,154.51 31.27,154.51 v1(31.62,154.86)
  BOTTOM w0.127: v1(31.62,154.86) 31.99,154.49 33.71,154.49 34.48,155.26 ; 34.48,155.26 34.55,155.33 34.55,155.33 51.31,172.09 80.49,172.09 82.86,169.72 84.35,169.72 85.49,168.58 91.37,168.58 92.31,169.53 99.71,169.53 100.62,168.61 100.62,168.03 101.5,167.15 101.9,167.15 102.8,166.25 103.02,166.04 103.22,165.83 103.22,163.88 v1(103.43,163.67) ; 34.48,155.26 v2(34.26,155.47)
EXP_A_RX_DP7: length 98
  TOP w0.127: U27.F8 v1(102.51,163.67) ; SLOT2.A47 19.1,150.1 19.6,150.1 20.14,150.65 30.85,150.65 v1(31.16,150.96)
  BOTTOM w0.127: v2(34.35,151.87) 34.6,151.62 ; 34.6,151.62 37.81,154.83 37.81,156.12 51.86,170.18 80.14,170.18 82.61,167.72 92.94,167.72 93.67,166.99 98.11,166.99 98.5,167.37 99.88,167.37 100.6,166.65 100.6,165.73 102.07,164.25 102.51,163.82 v1(102.51,163.67) ; 34.6,151.62 33.63,150.65 31.47,150.65 v1(31.16,150.96)
EXP_A_RX_DP8: length 94.9
  TOP w0.127: v1(30.84,145.14) 30.84,144.91 30.68,144.75 19.82,144.75 19.63,144.94 19.63,145.4 19.79,145.55 SLOT2.A52 ; v1(98.88,165.51) 98.42,165.04 U27.D3
  BOTTOM w0.127: v1(98.88,165.51) 98.68,165.3 98.33,165.3 97.31,166.32 93.14,166.32 92.58,166.88 81.84,166.88 80.78,167.94 79.1,167.94 78.54,168.5 53.24,168.5 52.91,168.18 52.91,168.17 47.62,162.89 47.62,160.68 32.68,145.74 ; v1(30.84,145.14) 30.84,144.94 31,144.77 31.71,144.77 32.68,145.74 ; 32.68,145.74 v2(32.45,145.96)
EXP_A_RX_DP9: length 96.4
  TOP w0.127: SLOT2.A56 19.74,141.55 19.58,141.4 19.58,140.84 19.74,140.69 25.48,140.69 25.93,140.23 30.26,140.23 v1(30.63,140.6) ; U27.E4 v1(98.87,164.57)
  BOTTOM w0.127: v2(49.85,161.9) 50.06,161.7 ; 50.06,161.7 49.4,161.04 49.4,159.69 34.59,144.89 34.59,143.36 31.44,140.2 30.76,140.2 30.63,140.33 v1(30.63,140.6) ; 50.06,161.7 55.12,166.76 78.03,166.76 78.8,165.99 92.22,165.99 92.52,165.69 96.88,165.69 98.21,164.36 98.66,164.36 v1(98.87,164.57)
EXP_A_RX_DP10: length 99.1
  TOP w0.127: v1(99.77,163.67) U27.F5 ; SLOT2.A60 19.74,137.55 19.58,137.4 19.58,136.81 19.79,136.6 31.34,136.6 31.47,136.73 v1(31.47,136.98)
  BOTTOM w0.127: v1(99.77,163.67) 99.68,163.67 99.16,163.15 98.29,163.15 96.62,164.83 92.17,164.83 91.87,165.13 79.82,165.13 78.89,164.19 76.88,164.19 76.04,165.03 57.23,165.03 52.07,159.87 ; 52.07,159.87 36.47,144.28 36.47,141.86 32.74,138.13 32.74,136.83 32.58,136.66 31.79,136.66 v1(31.47,136.98) ; 52.07,159.87 v2(51.84,160.1)
EXP_A_RX_DP11: length 99.7
  TOP w0.127: U27.G4 v1(99.77,162.76) ; v1(30.58,132.99) 30.58,132.61 30.43,132.46 28.98,132.46 28.83,132.61 19.96,132.61 19.81,132.77 19.81,133.4 19.96,133.55 SLOT2.A64
  BOTTOM w0.127: 56.41,160.61 52.2,156.41 52.2,155.05 34.75,137.6 34.75,134.98 32.29,132.53 30.67,132.53 30.58,132.61 v1(30.58,132.99) ; 56.41,160.61 58.77,162.98 78.96,162.98 80.25,164.26 91.51,164.26 91.81,163.96 94.48,163.96 95.45,162.99 97.39,162.99 97.82,162.56 99.57,162.56 v1(99.77,162.76) ; 56.41,160.61 v2(56.2,160.82)
EXP_A_RX_DP12: length 100.5
  TOP w0.127: v1(30.64,129.07) 30.64,128.71 30.53,128.6 19.91,128.6 19.76,128.75 19.76,129.32 20,129.55 SLOT2.A68 ; U27.H5 v1(99.77,161.84)
  BOTTOM w0.127: 65.36,160.74 70.71,160.74 71.27,161.3 79.66,161.3 80.73,162.37 94.92,162.37 95.12,162.17 97.17,162.17 97.41,161.93 98.01,161.93 98.63,161.31 99.03,161.31 99.56,161.84 v1(99.77,161.84) ; 65.36,160.74 59.59,160.74 54.25,155.4 54.25,154.55 46.01,146.31 46,146.31 41.03,141.35 41.03,141.34 36.45,136.75 36.45,133.48 31.55,128.57 30.83,128.57 30.64,128.77 v1(30.64,129.07) ; 65.36,160.74 v2(65.36,161.09)
EXP_A_RX_DP13: length 103.2
  TOP w0.127: v1(30.71,124.87) 30.4,124.56 19.69,124.56 19.46,124.79 19.46,125.4 19.61,125.55 SLOT2.A72 ; U27.J4 v1(99.77,160.93)
  BOTTOM w0.127: 50.79,148.2 49.96,147.37 49.96,146.79 38.99,135.82 38.99,128.85 34.75,124.61 30.97,124.61 v1(30.71,124.87) ; 50.79,148.2 61.75,159.16 71.47,159.16 71.88,159.57 80.37,159.57 81.44,160.64 92.62,160.64 92.82,160.85 97.34,160.85 97.74,160.45 98.14,160.45 98.42,160.73 99.57,160.73 v1(99.77,160.93) ; 50.79,148.2 v2(50.57,148.41)
EXP_A_RX_DP14: length 104
  TOP w0.127: v1(30.48,121.02) 30.16,120.7 19.89,120.7 19.74,120.85 19.74,121.31 19.97,121.55 SLOT2.A76 ; v1(99.77,160.02) U27.K5
  BOTTOM w0.127: v1(99.77,160.02) 99.77,159.46 99.57,159.27 98.78,159.27 98.26,159.79 97.36,159.79 97.23,159.93 95.1,159.93 94.04,158.86 82.18,158.86 81.11,157.79 72.62,157.79 71.83,157 67.56,157 ; 67.56,157 v2(67.56,157.34) ; 67.56,157 63.11,157 40.77,134.66 40.77,128.38 34.04,121.65 32.94,120.55 30.61,120.55 30.48,120.68 v1(30.48,121.02)
EXP_A_RX_DP15: length 106.2
  TOP w0.127: U27.L4 v1(99.77,158.19) ; SLOT2.A80 19.88,117.55 19.76,117.42 19.76,116.77 19.9,116.63 30.15,116.63 v1(30.48,116.96)
  BOTTOM w0.127: v1(30.48,116.96) 30.8,116.64 33.35,116.64 41.72,125.01 ; v2(41.48,125.25) 41.72,125.01 ; 41.72,125.01 42.55,125.84 42.55,133.96 64.02,155.43 72.49,155.43 73.18,156.12 81.81,156.12 82.74,157.05 96.01,157.05 96.32,157.36 96.32,157.57 96.73,157.98 98.38,157.98 98.88,157.48 99.9,157.48 100.11,157.69 100.11,157.84 v1(99.77,158.19)
EXP_A_TX_0_C_DN: length 10.6
  TOP w0.127: C148.2 22.67,181.86 22.17,181.86 21.44,182.6 20.02,182.6 19.08,181.66 15.54,181.66 15.39,181.81 15.39,182.8 15.54,182.96 16,182.96 16.15,182.8 SLOT2.B15
EXP_A_TX_0_C_DP: length 11.4
  TOP w0.127: C149.2 22.69,181.61 22.07,181.61 21.33,182.35 20.12,182.35 19.18,181.41 15.44,181.41 15.14,181.71 15.14,183.18 14.77,183.55 SLOT2.B14
EXP_A_TX_1_C_DN: length 9.8
  TOP w0.127: SLOT2.B20 14.98,177.55 15.08,177.44 19.31,177.44 20.3,178.44 22.92,178.44 C162.2
EXP_A_TX_1_C_DP: length 10.6
  TOP w0.127: SLOT2.B19 15.19,178.55 15.06,178.42 15.06,177.83 15.19,177.7 19.2,177.7 20.19,178.69 22.92,178.69 C158.2
EXP_A_TX_2_C_DN: length 9.8
  TOP w0.127: C167.2 22.92,174.37 20.15,174.37 19.21,173.43 15.31,173.43 15.19,173.55 SLOT2.B24
EXP_A_TX_2_C_DP: length 10.2
  TOP w0.127: C165.2 22.92,174.62 20.04,174.62 19.1,173.69 15.42,173.69 15.27,173.84 15.27,174.4 15.42,174.55 16.15,174.55 SLOT2.B23
EXP_A_TX_3_C_DN: length 9.8
  TOP w0.127: SLOT2.B28 14.75,169.55 14.93,169.37 19.18,169.37 20.25,170.43 22.92,170.43 C175.2
EXP_A_TX_3_C_DP: length 11
  TOP w0.127: SLOT2.B27 15.04,170.55 14.88,170.4 14.88,169.77 15.04,169.62 19.08,169.62 20.14,170.69 22.92,170.69 C173.2
EXP_A_TX_4_C_DN: length 11.2
  TOP w0.127: C188.2 22.92,166.95 21.69,166.95 21.39,166.65 19.99,166.65 19.02,165.68 15.41,165.68 14.78,165.05 14.78,164.18 SLOT2.B34
EXP_A_TX_4_C_DP: length 11.4
  TOP w0.127: C193.2 22.92,166.7 21.8,166.7 21.49,166.4 20.09,166.4 19.13,165.43 15.52,165.43 15.04,164.95 15.04,164.13 15.21,163.96 15.56,163.96 SLOT2.B33
EXP_A_TX_5_C_DN: length 10.2
  TOP w0.127: C210.2 23.43,160.4 20.43,160.4 19.85,159.83 19.52,159.5 15.2,159.5 15.15,159.55 SLOT2.B38
EXP_A_TX_5_C_DP: length 10.9
  TOP w0.127: SLOT2.B37 15.21,160.55 15.06,160.4 15.06,160 15.31,159.75 19.42,159.75 20.32,160.66 23.43,160.66 C207.2
EXP_A_TX_6_C_DN: length 9.9
  TOP w0.127: C230.2 22.92,156.46 20.35,156.46 19.23,155.35 14.91,155.35 14.7,155.55 SLOT2.B42
EXP_A_TX_6_C_DP: length 11.1
  TOP w0.127: C216.2 22.92,156.72 20.24,156.72 19.13,155.6 15.01,155.6 14.86,155.75 14.86,156.4 15.01,156.55 SLOT2.B41
EXP_A_TX_7_C_DN: length 9.8
  TOP w0.127: SLOT2.B46 15.05,151.55 15.16,151.43 19.26,151.43 20.22,152.4 22.92,152.4 C255.2
EXP_A_TX_7_C_DP: length 10.5
  TOP w0.127: C244.2 22.92,152.65 20.12,152.65 19.15,151.69 15.27,151.69 15.11,151.84 15.11,152.4 15.27,152.55 SLOT2.B45
EXP_A_TX_8_C_DN: length 9.9
  TOP w0.127: SLOT2.B51 15.62,146.55 15.47,146.7 15.47,147.37 15.62,147.52 19.46,147.52 20.37,148.44 21.59,148.44 21.76,148.26 22.95,148.26 C269.2
EXP_A_TX_8_C_DP: length 10.1
  TOP w0.127: C265.2 22.95,148.51 21.87,148.51 21.69,148.69 20.27,148.69 19.35,147.78 15.52,147.78 15.03,147.29 14.41,147.29 SLOT2.B50
EXP_A_TX_9_C_DN: length 10.2
  TOP w0.127: SLOT2.B55 15.39,142.55 15.24,142.7 15.24,143.23 15.39,143.38 19.25,143.38 20.27,142.37 22.92,142.37 C280.2
EXP_A_TX_9_C_DP: length 11
  TOP w0.127: C279.2 22.92,142.62 20.37,142.62 19.35,143.64 15.29,143.64 14.99,143.34 14.99,142.98 14.81,142.8 14.3,142.8 14.15,142.95 SLOT2.B54
EXP_A_TX_10_C_DN: length 10
  TOP w0.127: C284.2 22.92,138.43 20.09,138.43 19.1,139.42 15.52,139.42 15.37,139.27 15.37,138.7 15.52,138.55 SLOT2.B59
EXP_A_TX_10_C_DP: length 10.3
  TOP w0.127: SLOT2.B58 14.69,139.01 14.96,139.01 15.11,139.17 15.11,139.37 15.41,139.67 19.2,139.67 20.19,138.68 22.92,138.68 C281.2
EXP_A_TX_11_C_DN: length 10.9
  TOP w0.127: C290.2 22.92,134.62 19.86,134.62 18.95,133.71 15.49,133.71 15.34,133.86 15.34,134.9 15.49,135.05 16,135.05 16.15,134.9 SLOT2.B63
EXP_A_TX_11_C_DP: length 11.3
  TOP w0.127: C291.2 22.92,134.37 19.97,134.37 19.05,133.45 15.39,133.45 15.09,133.75 15.09,135.08 14.61,135.55 SLOT2.B62
EXP_A_TX_12_C_DN: length 10.7
  TOP w0.127: C294.2 22.92,130.68 20.02,130.68 19.05,129.72 15.54,129.72 15.39,129.87 15.39,130.86 15.54,131.01 16,131.01 16.15,130.86 SLOT2.B67
EXP_A_TX_12_C_DP: length 11.4
  TOP w0.127: C292.2 22.92,130.43 20.12,130.43 19.16,129.46 15.44,129.46 15.14,129.76 15.14,131.19 14.78,131.55 SLOT2.B66
EXP_A_TX_13_C_DN: length 10.2
  TOP w0.127: C296.2 22.92,126.36 20.11,126.36 19.15,127.33 15.37,127.33 15.21,127.18 15.21,126.7 15.37,126.55 SLOT2.B71
EXP_A_TX_13_C_DP: length 10.8
  TOP w0.127: C295.2 22.92,126.62 20.22,126.62 19.25,127.58 15.26,127.58 14.96,127.28 14.96,126.97 14.81,126.82 14.3,126.82 14.15,126.97 SLOT2.B70
EXP_A_TX_14_C_DN: length 10.7
  TOP w0.127: C297.2 22.92,122.68 19.99,122.68 19.05,121.74 15.62,121.74 15.34,122.02 15.34,122.86 15.49,123.01 16,123.01 16.15,122.86 SLOT2.B75
EXP_A_TX_14_C_DP: length 11.4
  TOP w0.127: C299.2 22.92,122.43 20.1,122.43 19.16,121.49 15.52,121.49 15.09,121.92 15.09,123.4 14.94,123.55 SLOT2.B74
EXP_A_TX_15_C_DN: length 9.3
  TOP w0.127: C300.2 22.85,118.38 20.22,118.38 19.22,119.38 15.82,119.38 15.67,119.23 15.67,118.7 15.82,118.55 SLOT2.B79
EXP_A_TX_15_C_DP: length 9.8
  TOP w0.127: C301.2 22.85,118.63 20.33,118.63 19.33,119.63 15.72,119.63 15.64,119.55 SLOT2.B78
EXP_A_TX_DN0: length 100.8
  TOP w0.127: v1(94.88,176.08) 94.59,175.79 94.59,175.39 94.92,175.06 102.25,175.06 107.09,170.23 107.09,169.11 106.98,169.01 106.98,167.23 U27.B12 ; v1(31.66,182.17) 31.34,182.17 31.07,182.45 30.1,182.45 29.59,181.94 24.14,181.94 C148.1
  BOTTOM w0.127: v1(31.66,182.17) 31.97,181.86 32.41,181.86 32.73,181.55 32.73,180.11 36.7,176.14 40.12,176.14 47.77,183.79 74.3,183.79 ; 74.3,183.79 v2(74.3,184.15) ; 74.3,183.79 87.13,183.79 92.21,178.71 92.86,178.71 94.59,176.99 94.59,176.36 v1(94.88,176.08)
EXP_A_TX_DN1: length 96.4
  TOP w0.102: U27.C11 106.25,166.49 106.25,168.37 106.27,168.4 106.27,169.92 106.15,170.05
  TOP w0.127: v1(92.22,175.82) 92.22,175.3 92.56,174.96 93,174.51 93.27,174.24 101.95,174.24 106.15,170.05 ; C162.1 24.52,178.38 30.36,178.38 v1(30.67,178.07)
  BOTTOM w0.127: v1(92.22,175.82) 91.16,175.82 85.78,181.2 47.77,181.2 40.86,174.29 35.89,174.29 34.72,175.46 ; 34.72,175.46 v2(34.49,175.23) ; 34.72,175.46 31.9,178.28 30.88,178.28 v1(30.67,178.07)
EXP_A_TX_DN2: length 94.9
  TOP w0.102: 105.07,169.99 105.13,169.93 105.13,167.57 105.36,167.34 105.36,165.61 U27.D10
  TOP w0.127: 105.07,169.99 101.85,173.2 91.85,173.2 91.75,173.3 v1(91.75,173.63) ; C167.1 24.57,174.37 26.14,174.37 26.27,174.5 30.45,174.5 v1(30.78,174.17)
  BOTTOM w0.127: 32.6,173.83 v2(32.38,173.61) ; 32.6,173.83 33.35,173.08 34.1,172.33 41.12,172.33 48.42,179.63 84.79,179.63 90.63,173.79 91.59,173.79 91.74,173.63 v1(91.75,173.63) ; 32.6,173.83 32.09,174.34 30.95,174.34 v1(30.78,174.17)
EXP_A_TX_DN3: length 92.5
  TOP w0.127: v1(30.66,170.31) 30.54,170.43 24.57,170.43 C175.1 ; v1(89,173.41) 88.55,173.41 88.28,173.14 88.28,172.84 88.7,172.42 101.53,172.42 103.86,170.08 103.86,168.51 104.24,168.13 104.24,166.69 103.88,166.34 U27.C9
  BOTTOM w0.127: 40.01,170.63 30.97,170.63 v1(30.66,170.31) ; 40.01,170.63 v2(40.01,170.31) ; 40.01,170.63 42.18,170.63 49.28,177.73 83.94,177.73 88.27,173.41 88.42,173.41 v1(89,173.41)
EXP_A_TX_DN4: length 93.6
  TOP w0.102: 103,169.67 103.07,169.6 103.07,168.45 103.71,167.81 103.71,167.26 103.5,167.06 103.5,165.58 U27.D8
  TOP w0.127: C188.1 24.47,167.06 25.73,167.06 26.01,167.34 29.26,167.34 29.79,166.8 30.84,166.8 31.1,167.07 31.51,167.07 v1(31.72,167.28) ; 103,169.67 101.06,171.61 87.19,171.61 86.59,172.22 86.59,172.69 v1(86.76,172.87)
  BOTTOM w0.127: v1(31.72,167.28) 31.88,167.13 32.51,167.13 33.99,165.66 34.96,165.66 ; v1(86.76,172.87) 86.54,173.1 86.54,173.25 83.41,176.38 49.89,176.38 39.16,165.66 34.96,165.66 ; 34.96,165.66 v2(34.96,165.99)
EXP_A_TX_DN5: length 93.6
  TOP w0.102: U27.C7 102.4,166.31 102.4,167.32 102.59,167.5 102.59,168.86 102.58,168.88
  TOP w0.127: C210.1 25.08,160.4 28.03,160.4 28.77,159.66 30.25,159.66 v1(30.58,159.33) ; 102.58,168.88 100.64,170.81 90.14,170.81 89.26,169.93 85.75,169.93 85.39,170.29 85.39,170.68 85.55,170.84 85.98,170.84 v1(86.29,170.53)
  BOTTOM w0.127: v1(86.29,170.53) 86,170.81 85.3,170.81 81.56,174.56 50.68,174.56 35.76,159.64 34.82,159.64 ; 34.82,159.64 30.9,159.64 v1(30.58,159.33) ; 34.82,159.64 v2(34.82,159.33)
EXP_A_TX_DN6: length 90.7
  TOP w0.127: U27.B6 101.14,167.21 101.52,167.59 101.52,168.07 101.4,168.2 101.4,168.76 100.2,169.95 90.91,169.95 89.89,168.94 85.2,168.94 84.4,169.73 82.95,169.73 82.68,170 82.68,170.51 82.86,170.69 v1(83.29,170.69) ; C230.1 24.57,156.46 27.39,156.46 27.44,156.51 30.56,156.51 v1(30.78,156.29)
  BOTTOM w0.127: 32.64,156.59 v2(32.64,156.24) ; 32.64,156.59 31.09,156.59 v1(30.78,156.29) ; 32.64,156.59 35.06,156.59 51.09,172.63 80.74,172.63 82.68,170.69 v1(83.29,170.69)
EXP_A_TX_DN7: length 90.2
  TOP w0.102: U27.C5 100.23,166.19 100.76,166.73 100.76,168.5 100.7,168.57
  TOP w0.127: 100.7,168.57 100.18,169.09 91.26,169.09 89.94,167.77 83.82,167.77 83.65,167.94 83.65,168.11 v1(83.92,168.38) ; C255.1 24.57,152.4 28.22,152.4 28.66,152.83 30.48,152.83 v1(30.71,152.6)
  BOTTOM w0.127: v2(36.54,155.33) 36.32,155.55 ; 36.32,155.55 51.49,170.71 80.37,170.71 82.69,168.38 v1(83.92,168.38) ; 36.32,155.55 33.6,152.83 30.95,152.83 v1(30.71,152.6)
EXP_A_TX_DN8: length 88.7
  TOP w0.127: U27.E2 97.05,164.57 96.42,164.57 94.06,166.93 82.32,166.93 81.41,167.84 79.89,167.84 79.45,168.28 79.45,168.53 79.59,168.68 v1(80.07,168.68) ; v1(31.11,146.75) 30.93,146.94 28.9,146.94 27.6,148.23 24.57,148.23 C269.1
  BOTTOM w0.127: v1(31.11,146.75) 31.35,146.99 33.04,146.99 46.99,160.93 46.99,163.52 52.24,168.77 ; 52.24,168.77 52.56,169.1 78.71,169.1 79.07,168.73 79.51,168.73 79.63,168.86 79.9,168.86 v1(80.07,168.68) ; 52.24,168.77 v2(52.48,168.53)
EXP_A_TX_DN9: length 90.4
  TOP w0.102: U27.F3 97.83,163.78 96.35,163.78 95.86,164.26 95.86,164.3 95.85,164.32
  TOP w0.127: C280.1 24.57,142.36 29.54,142.36 29.92,141.99 31.27,141.99 v1(31.46,141.8) ; v1(80.31,167.06) 80.01,166.75 80.01,166.4 80.34,166.07 94.1,166.07 95.85,164.32
  BOTTOM w0.127: 53.75,166.97 54.15,167.37 78.2,167.37 78.89,166.67 79.93,166.67 v1(80.31,167.06) ; 53.75,166.97 v2(54,166.73) ; 53.75,166.97 48.77,161.99 48.77,160.05 32.93,144.21 32.93,142.68 32.24,141.99 31.65,141.99 v1(31.46,141.8)
EXP_A_TX_DN10: length 88.9
  TOP w0.127: U27.G2 97.12,162.66 95.73,162.66 93.24,165.15 78.52,165.15 v1(78.13,165.55) ; C284.1 24.55,138.4 27.86,138.4 28.09,138.18 31.08,138.18 v1(31.27,137.99)
  BOTTOM w0.127: v1(31.27,137.99) 31.48,138.2 31.88,138.2 35.86,142.19 35.86,144.53 50.55,159.21 50.55,159.91 55.55,164.92 55.55,164.93 55.64,165.01 55.64,165.01 ; v2(55.85,164.81) 55.64,165.01 ; 55.64,165.01 55.64,165.02 55.73,165.1 55.73,165.1 56.29,165.66 76.23,165.66 76.73,165.15 77.73,165.15 v1(78.13,165.55)
EXP_A_TX_DN11: length 91.5
  TOP w0.102: U27.H3 97.83,161.95 96.37,161.95 96.27,162.05 95.29,162.05 95.03,162.32 95.03,162.35 95.01,162.37
  TOP w0.127: v1(74.75,164.21) 75.12,164.21 75.65,164.74 76.41,164.74 76.97,164.19 93.19,164.19 94.81,162.57 95.01,162.37 ; C290.1 24.57,134.62 30.27,134.62 v1(30.58,134.93)
  BOTTOM w0.127: v1(74.75,164.21) 74.75,163.91 74.62,163.78 57.78,163.78 51.31,157.31 51.31,155.45 41.79,145.94 ; 41.79,145.94 v2(41.56,146.17) ; 41.79,145.94 33.88,138.03 33.88,135.49 33.09,134.7 30.82,134.7 v1(30.58,134.93)
EXP_A_TX_DN12: length 91.2
  TOP w0.127: v1(91.22,163.28) 91.04,163.09 91.04,162.89 91.62,162.31 94.19,162.31 95.63,160.86 96.98,160.86 97.36,160.47 U27.J2 ; C294.1 24.42,130.84 30.33,130.84 v1(30.56,131.06)
  BOTTOM w0.127: v1(30.56,131.06) 30.77,130.85 32.05,130.85 35.56,134.35 35.56,137.18 53.37,154.99 53.37,155.81 56.36,158.8 ; v1(91.22,163.28) 91.05,163.45 80.59,163.45 79.3,162.16 59.72,162.16 56.36,158.8 ; 56.36,158.8 v2(56.14,159.03)
EXP_A_TX_DN13: length 93.3
  TOP w0.102: 95.94,160.14 95.96,160.14 95.99,160.12 97.44,160.12 98,159.56 U27.K3
  TOP w0.127: v1(93.12,161.47) 93.12,161.07 93.3,160.88 94.7,160.88 95.44,160.14 95.94,160.14 ; C296.1 24.57,126.36 30.2,126.36 v1(30.48,126.09)
  BOTTOM w0.127: v1(93.12,161.47) 92.68,161.04 91.86,161.04 91.64,161.25 81.19,161.25 80.12,160.18 71.74,160.18 71.25,159.7 60.97,159.7 58.46,157.18 ; v1(30.48,126.09) 30.71,126.31 32.08,126.31 37.57,131.8 37.57,135.33 48.77,146.53 48.77,147.49 58.46,157.18 ; 58.46,157.18 v2(58.67,156.96)
EXP_A_TX_DN14: length 95.4
  TOP w0.102: U27.M3 98.05,157.73 97.51,158.27 96.22,158.27 96.19,158.29 96.16,158.29
  TOP w0.127: C297.1 24.55,122.71 26.51,122.71 26.62,122.81 30.27,122.81 v1(30.48,123.02) ; 96.16,158.29 95.86,158.29 94.48,159.67 v1(94.48,159.99)
  BOTTOM w0.127: v1(30.48,123.02) 30.77,122.73 33.98,122.73 39.88,128.63 39.88,135.27 59.75,155.14 ; 59.75,155.14 62.99,158.38 71.8,158.38 72.08,158.66 80.75,158.66 81.77,159.68 93.51,159.68 93.83,159.99 v1(94.48,159.99) ; 59.75,155.14 v2(59.5,155.38)
EXP_A_TX_DN15: length 96.2
  TOP w0.127: v1(97.94,159.07) 97.91,159.07 U27.L2 ; v1(30.48,118.01) 30.26,118.24 27.05,118.24 26.92,118.36 24.59,118.36 C300.1
  BOTTOM w0.127: v1(30.48,118.01) 30.7,118.24 32.18,118.24 ; v2(32.18,117.93) 32.18,118.24 ; 32.18,118.24 33.07,118.24 42.01,127.18 42.01,134.29 63.68,155.96 72.27,155.96 72.98,156.68 81.58,156.68 82.48,157.58 95.2,157.58 95.89,158.28 96.04,158.28 96.39,158.62 97.5,158.62 v1(97.94,159.07)
EXP_A_TX_DP0: length 99.9
  TOP w0.127: C149.1 24.27,181.69 29.7,181.69 30.2,182.19 30.96,182.19 31.37,181.79 31.37,181.78 v1(31.37,181.36) ; v1(94,176.05) 94.34,175.71 94.34,175.29 94.82,174.8 102.15,174.8 106.83,170.12 106.83,169.22 106.73,169.12 106.73,167.89 U27.A12
  BOTTOM w0.127: 66.19,183.54 47.88,183.54 40.22,175.88 36.6,175.88 32.48,180 32.48,181.44 32.3,181.61 31.61,181.61 v1(31.37,181.36) ; 66.19,183.54 v2(66.19,183.24) ; 66.19,183.54 87.02,183.54 92.1,178.46 92.76,178.46 94.34,176.88 94.34,176.38 v1(94,176.05)
EXP_A_TX_DP1: length 95.6
  TOP w0.102: U27.B11 106.04,167.2 106.04,168.45 106.07,168.48 106.07,169.77 105.97,169.87
  TOP w0.127: C158.1 24.63,178.64 30.4,178.64 v1(30.7,178.94) ; 105.97,169.87 101.85,173.99 93.17,173.99 91.52,175.64 v1(91.52,176.33)
  BOTTOM w0.127: v1(91.52,176.33) 91.01,176.33 85.88,181.46 55.83,181.46 ; 55.83,181.46 47.66,181.46 40.76,174.55 35.99,174.55 32,178.54 30.86,178.54 30.7,178.69 v1(30.7,178.94) ; 55.83,181.46 v2(55.83,181.79)
EXP_A_TX_DP2: length 94.6
  TOP w0.102: 104.86,169.84 104.93,169.77 104.93,167.49 105.16,167.26 105.16,166.32 U27.C10
  TOP w0.127: v1(30.88,175.07) 30.56,174.75 26.16,174.75 26.04,174.62 24.57,174.62 C165.1 ; v1(91.2,174.3) 91.2,173.49 91.74,172.95 101.75,172.95 104.86,169.84
  BOTTOM w0.127: 34.65,172.58 41.02,172.58 48.32,179.88 84.9,179.88 90.74,174.04 90.94,174.04 v1(91.2,174.3) ; 34.65,172.58 34.2,172.58 33.61,173.17 33.61,173.17 32.2,174.59 31.03,174.59 30.88,174.74 v1(30.88,175.07) ; 34.65,172.58 v2(34.65,172.92)
EXP_A_TX_DP3: length 91.3
  TOP w0.127: C173.1 24.57,170.69 30.35,170.69 30.56,170.9 v1(30.56,171.17) ; v1(88.42,174.05) 88.42,173.64 88.03,173.24 88.03,172.73 88.6,172.16 101.42,172.16 103.6,169.98 103.6,168.4 103.99,168.02 103.99,166.98 U27.B9
  BOTTOM w0.127: 84.89,177.14 84.05,177.99 49.18,177.99 42.07,170.88 30.85,170.88 v1(30.56,171.17) ; 84.89,177.14 87.98,174.05 v1(88.42,174.05) ; 84.89,177.14 v2(85.12,177.37)
EXP_A_TX_DP4: length 93.4
  TOP w0.102: 102.77,169.54 102.87,169.45 102.87,168.36 103.5,167.73 103.5,167.35 103.3,167.14 103.3,166.29 U27.C8
  TOP w0.127: 102.77,169.54 100.95,171.36 87.09,171.36 86.33,172.11 86.33,172.62 86.16,172.8 v1(85.9,172.8) ; C193.1 24.68,166.8 25.84,166.8 26.11,167.08 29.16,167.08 29.69,166.55 30.95,166.55 31.21,166.81 31.57,166.81 31.72,166.66 v1(31.72,166.32)
  BOTTOM w0.127: 37.47,165.4 v2(37.47,165.07) ; 37.47,165.4 39.27,165.4 49.99,176.13 83.3,176.13 86.28,173.15 86.28,172.95 86.13,172.8 v1(85.9,172.8) ; 37.47,165.4 33.88,165.4 32.41,166.88 31.98,166.88 31.72,166.62 v1(31.72,166.32)
EXP_A_TX_DP5: length 92.9
  TOP w0.102: U27.B7 102.06,167.26 102.39,167.59 102.39,168.71 102.29,168.81
  TOP w0.127: v1(86.16,171.38) 85.87,171.09 85.45,171.09 85.14,170.79 85.14,170.18 85.65,169.67 89.36,169.67 90.25,170.56 100.53,170.56 101.17,169.92 102.29,168.81 ; v1(30.64,160.2) 30.35,159.92 28.88,159.92 28.14,160.66 25.08,160.66 C207.1
  BOTTOM w0.127: v2(32.82,160.22) 32.82,159.89 ; 32.82,159.89 30.75,159.89 30.64,160 v1(30.64,160.2) ; 32.82,159.89 35.66,159.89 50.57,174.81 81.66,174.81 85.4,171.07 85.85,171.07 v1(86.16,171.38)
EXP_A_TX_DP6: length 89.4
  TOP w0.127: v1(82.78,171.38) 82.78,170.97 82.42,170.61 82.42,169.9 82.84,169.48 84.29,169.48 85.09,168.68 90,168.68 91.01,169.7 100.1,169.7 101.14,168.65 U27.A6 ; v1(30.94,157.14) 30.94,156.9 30.81,156.77 27.33,156.77 27.28,156.72 24.57,156.72 C216.1
  BOTTOM w0.127: v1(82.78,171.38) 82.34,171.38 80.84,172.88 50.99,172.88 34.95,156.84 34.53,156.84 ; 34.53,156.84 31.23,156.84 v1(30.94,157.14) ; 34.53,156.84 v2(34.53,157.2)
EXP_A_TX_DP7: length 89.5
  TOP w0.102: 100.48,168.43 100.56,168.35 100.56,167.21 U27.B5
  TOP w0.127: v1(30.71,153.49) 30.71,153.24 30.56,153.09 28.55,153.09 28.12,152.65 24.57,152.65 C244.1 ; v1(83.2,168.86) 83.4,168.66 83.4,167.83 83.71,167.51 90.05,167.51 91.37,168.83 100.07,168.83 100.48,168.43
  BOTTOM w0.127: 32.92,153.09 33.5,153.09 51.38,170.97 80.47,170.97 82.8,168.64 82.98,168.64 v1(83.2,168.86) ; 32.92,153.09 30.86,153.09 30.71,153.24 v1(30.71,153.49) ; 32.92,153.09 v2(32.92,153.39)
EXP_A_TX_DP8: length 88.5
  TOP w0.127: v1(79.52,169.35) 79.52,168.97 79.19,168.64 79.19,168.18 79.41,167.96 79.41,167.96 79.51,167.86 79.78,167.59 81.3,167.59 82.22,166.67 93.95,166.67 96.5,164.13 U27.E1 ; v1(31.11,147.69) 31.11,147.42 30.89,147.19 29,147.19 27.71,148.49 24.63,148.49 C265.1
  BOTTOM w0.127: v1(31.11,147.69) 31.11,147.38 31.25,147.24 32.94,147.24 46.74,161.04 46.74,163.12 ; 46.74,163.12 46.74,163.63 52.46,169.35 78.81,169.35 79.17,168.99 79.4,168.99 79.52,169.11 v1(79.52,169.35) ; 46.74,163.12 v2(46.43,163.12)
EXP_A_TX_DP9: length 89.7
  TOP w0.102: 95.67,164.14 95.69,164.12 95.72,164.12 96.27,163.58 97.12,163.58 U27.F2
  TOP w0.127: v1(79.46,167.15) 79.76,166.86 79.76,166.29 80.24,165.81 93.99,165.81 95.67,164.14 ; v1(31.49,142.78) 31.49,142.47 31.27,142.24 30.02,142.24 29.65,142.61 24.58,142.61 C279.1
  BOTTOM w0.127: 50.53,164.1 54.05,167.62 78.3,167.62 79,166.93 79.23,166.93 v1(79.46,167.15) ; 50.53,164.1 v2(50.29,164.34) ; 50.53,164.1 48.51,162.09 48.51,160.15 32.68,144.31 32.68,142.78 32.13,142.24 31.7,142.24 31.49,142.44 v1(31.49,142.78)
EXP_A_TX_DP10: length 88.5
  TOP w0.127: v1(31.27,138.92) 31.27,138.62 31.08,138.43 28.2,138.43 27.97,138.66 24.6,138.66 C281.1 ; U27.G1 96.46,162.41 95.63,162.41 93.14,164.9 78.01,164.9 v1(77.27,165.64)
  BOTTOM w0.127: v1(31.27,138.92) 31.27,138.68 31.5,138.46 31.77,138.46 35.61,142.3 35.61,144.63 50.29,159.32 50.29,160.02 52.73,162.46 ; v2(52.5,162.68) 52.73,162.46 ; 52.73,162.46 55.3,165.03 55.3,165.03 55.62,165.35 55.63,165.35 56.18,165.91 76.33,165.91 76.84,165.4 77.03,165.4 v1(77.27,165.64)
EXP_A_TX_DP11: length 91.1
  TOP w0.102: 94.83,162.19 94.85,162.17 94.88,162.17 95.21,161.85 96.18,161.85 96.28,161.75 97.12,161.75 U27.H2
  TOP w0.127: v1(30.58,134) 30.22,134.37 24.57,134.37 C291.1 ; v1(75.41,163.65) 75.4,163.66 75.4,164.13 75.76,164.49 76.3,164.49 76.86,163.93 93.09,163.93 94.83,162.19
  BOTTOM w0.127: 53.18,158.81 57.89,163.53 74.73,163.53 75.03,163.83 75.23,163.83 v1(75.41,163.65) ; 53.18,158.81 51.56,157.2 51.56,155.35 34.14,137.92 34.14,135.38 33.2,134.44 30.68,134.44 30.58,134.34 v1(30.58,134) ; 53.18,158.81 v2(53.4,158.59)
EXP_A_TX_DP12: length 90.5
  TOP w0.127: C292.1 24.73,130.58 30.43,130.58 30.61,130.4 v1(30.61,130.07) ; U27.J1 96.44,160.6 95.53,160.6 94.08,162.05 91.52,162.05 90.63,162.94 v1(90.42,162.94)
  BOTTOM w0.127: 60.63,161.91 79.41,161.91 80.69,163.2 90.17,163.2 v1(90.42,162.94) ; 60.63,161.91 v2(60.63,161.59) ; 60.63,161.91 59.82,161.91 53.62,155.7 53.62,154.88 35.81,137.08 35.81,134.25 32.16,130.59 30.77,130.59 30.61,130.43 v1(30.61,130.07)
EXP_A_TX_DP13: length 92.6
  TOP w0.102: U27.K2 97.48,159.79 97.36,159.91 95.99,159.91 95.96,159.89 95.94,159.89
  TOP w0.127: 95.94,159.89 95.33,159.89 94.59,160.63 93.19,160.63 92.43,161.39 v1(92.43,161.57) ; C295.1 24.57,126.62 30.15,126.62 v1(30.48,126.95)
  BOTTOM w0.127: v2(55.9,155.41) 56.11,155.2 ; 56.11,155.2 60.87,159.95 71.15,159.95 71.63,160.44 80.02,160.44 81.08,161.5 91.75,161.5 91.96,161.29 92.15,161.29 v1(92.43,161.57) ; 56.11,155.2 48.51,147.6 48.51,146.64 37.31,135.43 37.31,131.9 31.98,126.57 30.61,126.57 30.48,126.7 v1(30.48,126.95)
EXP_A_TX_DP14: length 94.7
  TOP w0.102: 96.16,158.04 96.19,158.04 96.22,158.06 97.43,158.06 97.48,158.01 U27.M2
  TOP w0.127: v1(30.48,122.09) 30.48,122.4 30.33,122.56 26.72,122.56 26.62,122.45 24.6,122.45 C299.1 ; v1(94.01,159.5) 94.3,159.5 95.75,158.04 96.16,158.04
  BOTTOM w0.127: 64.52,158.12 71.9,158.12 72.19,158.4 80.86,158.4 81.88,159.42 93.93,159.42 v1(94.01,159.5) ; 64.52,158.12 v2(64.52,157.78) ; 64.52,158.12 63.09,158.12 40.13,135.16 40.13,128.52 34.09,122.48 30.61,122.48 30.48,122.35 v1(30.48,122.09)
EXP_A_TX_DP15: length 95.8
  TOP w0.127: C301.1 24.62,118.62 27.03,118.62 27.15,118.49 30.3,118.49 30.48,118.67 v1(30.48,118.95) ; U27.L1 v1(97.03,159.1)
  BOTTOM w0.127: v1(97.03,159.1) 96.8,158.88 96.28,158.88 95.94,158.53 95.79,158.53 95.09,157.84 82.37,157.84 81.47,156.93 72.87,156.93 72.16,156.22 63.58,156.22 41.76,134.4 41.76,127.28 37.67,123.2 ; 37.67,123.2 32.97,118.49 30.61,118.49 30.48,118.62 v1(30.48,118.95) ; 37.67,123.2 v2(37.44,123.43)
FB_AUDOUT_L: length 11.9
  TOP w0.203: L14.2 43.14,224.38 C28.1 43.24,225.44 Q14.2 43.24,227.1 47.84,231.7 AUDJK1.22
FB_AUDOUT_R: length 18.1
  TOP w0.203: Q14.1 44.04,228.77 45.33,230.06 L15.2 C38.1 46.69,231.67 48.26,233.25 56.39,233.25 AUDJK1.25
FB_AUDOUTR_L: length 5.7
  TOP w0.203: R53.2 R44.1 41.72,224.57 v2(41.95,224.34) 42.55,223.75 43.4,223.75 L14.1
FB_AUDOUTR_R: length 12.3
  TOP w0.203: L15.1 41.94,230.71 38.3,227.08 v2(38.3,226.01) 38.3,225.77 R43.1 R52.2
FB_USBF1_DET: length 193.4
  TOP w0.102: v1(62.92,22.33) 62.77,22.33 60.74,24.36 60.74,24.38 57.96,27.17 53.82,27.17 R595.1 52.77,26.58 v1(52.37,26.97) ; U29.N32 39.12,41.03 v3(39.26,41.17)
  BOTTOM w0.102: v1(52.37,26.97) 52.35,26.95 50.28,26.95 47.29,29.93 45.84,29.93 45.58,30.2 45.58,32.54 43.17,34.95 43.15,34.95 40.64,37.45 40.64,37.85 39.96,38.53 39.96,40.47 v3(39.26,41.17) ; USBF1.10 178.51,77.72 169.01,77.72 167.55,76.26 167.55,66.51 166.38,65.34 166.38,64.02 162.79,60.43 159.33,60.43 157.25,62.5 156.08,62.5 149,55.42 149,53.19 146.98,51.17 146.98,40.69 145.47,39.18 145.47,36.71 134.17,25.42 125.11,25.42 v2(123.6,23.9) 122.61,22.91 116.48,22.91 116.41,22.99 103.84,22.99 103.68,22.83 82.02,22.83 80.97,23.88 78.05,23.88 64.47,23.88 v1(62.92,22.33)
FB_USBF2_DET: length 187.8
  TOP w0.102: U29.N34 39.17,40.32 v3(39.26,40.4) ; v1(48.59,27.56) 49.44,26.71 R685.1 ; USBF3.10 157.91,79.35 v1(160.55,76.71)
  BOTTOM w0.102: USBF2.10 151.92,72.63 154.5,75.21 156.74,75.21 158.24,76.71 158.24,78.46 USBF3.10 ; v3(39.26,40.4) 39.75,39.92 39.75,38.38 40.44,37.69 40.44,37.37 43.06,34.74 43.09,34.74 45.38,32.45 45.38,30.11 45.82,29.67 46.53,29.67 v2(47.6,28.6) 48.59,27.61 v1(48.59,27.56) 49.68,26.47 53.18,26.47 53.64,26.92 56.47,26.92 58.84,29.3 66.43,29.3 68.55,31.42 70.41,31.42 73.69,34.7 75.46,34.7 76.25,35.48 100.38,35.48 100.91,34.95 110.35,34.95 113.6,38.2 129.17,38.2 133.32,42.36 133.32,45.78 135.53,47.98 136.19,47.98 152.83,64.62 155.36,64.62 155.83,65.09 157.54,65.09 159.54,63.09 162.55,63.09 164.21,64.76 164.21,74.35 161.85,76.71 v1(160.55,76.71)
FDI_CSYNC: length 184.8
  TOP w0.102: U29.L2 39.34,58.16 39.45,58.27 39.45,64.09 40.08,64.72 40.08,70.33 44.59,74.84 44.59,79.71 37.72,86.58 v1(37.72,96.01) ; v1(66.12,151.03) 66.12,161.85 82.91,178.64 93.99,178.64 v1(94.03,178.68) ; U27.D16 v1(109.83,164.59)
  BOTTOM w0.102: v1(94.03,178.68) 97.14,175.57 104.64,175.57 110.29,169.93 U27.D16 v1(109.83,164.59) ; v1(66.12,151.03) 66.91,151.03 68.64,149.3 68.64,146.36 68.2,145.92 v2(68.2,143.64) 68.2,141.24 40.36,113.4 40.36,107.9 37.72,105.26 v1(37.72,96.01)
FDI_INT: length 186.4
  TOP w0.102: v1(65.4,151.51) 65.43,151.54 65.43,161.85 82.75,179.16 95.72,179.16 97.76,177.11 103.22,177.11 111.6,168.74 111.6,165.56 U27.D18 ; U29.L3 39.33,56.66 39.04,56.96 39.04,58.15 39.22,58.33 39.22,64.49 39.57,64.85 39.57,70.57 44.11,75.1 44.11,79.51 37.18,86.43 v1(37.18,95.34)
  BOTTOM w0.102: v1(65.4,151.51) 65.43,151.48 65.43,151.03 66.39,150.07 67.18,150.07 68.15,149.1 68.15,146.56 67.56,145.97 v2(67.56,141.86) 67.56,141.28 39.88,113.6 39.88,108.33 37.18,105.63 v1(37.18,95.34)
FDI_RCOMP: length 5.3
  TOP w0.203: U29.K2 39.97,57.29 39.65,57.6 39.65,58.12 39.88,58.34 39.88,60.81 v2(40.03,60.96) 40.16,61.09 R694.1
FDI_TX_DN0: length 180.7
  TOP w0.102: v1(34.67,95.5) 35,95.17 35.69,95.17 36.77,94.09 36.77,86.21 39.2,83.79 43.7,79.29 43.7,75.27 39.13,70.7 39.13,68.31 38.91,68.1 38.91,58.31 38.64,58.04 U29.N1 ; v1(65.58,149.68) 65.89,149.68 66.62,150.41 66.62,161.49 83.25,178.11 95.88,178.11 97.43,176.56 103.2,176.56 108.82,170.94 108.82,167.24 U27.B14
  BOTTOM w0.102: v2(45.9,123.32) 46.13,123.09 ; 46.13,123.09 62.17,139.13 65.54,142.51 65.54,149.29 65.58,149.33 v1(65.58,149.68) ; 46.13,123.09 37.57,114.53 37.57,108.28 35.64,106.35 35.64,95.5 35.37,95.24 34.94,95.24 v1(34.67,95.5)
FDI_TX_DN1: length 179.7
  TOP w0.102: U29.P2 37.97,57.34 37.88,57.43 37.88,58.05 38.24,58.42 38.24,67.58 36.6,69.22 36.6,70.84 33.58,73.86 30.68,76.76 30.68,82.14 35.45,86.91 35.45,92.16 35.09,92.52 v1(35.09,92.85) ; U27.C13 108.11,166.53 108.11,170.24 102.52,175.83 96.91,175.83 95.44,177.3 83.65,177.3 67.92,161.57 67.92,149.25 67.12,148.45 v1(66.89,148.45)
  BOTTOM w0.102: 54.1,129.44 66.7,142.04 66.7,147.9 66.89,148.09 v1(66.89,148.45) ; 54.1,129.44 38.27,113.6 38.27,107.91 36.26,105.91 36.26,92.52 35.83,92.09 35.45,92.09 35.09,92.45 v1(35.09,92.85) ; 54.1,129.44 v2(53.87,129.67)
FDI_TX_DP0: length 180.7
  TOP w0.102: v1(34.67,94.62) 35.01,94.95 35.6,94.95 36.56,94 36.56,86.13 36.62,86.06 39.04,83.64 43.48,79.2 43.48,75.36 38.91,70.79 38.91,68.4 38.7,68.19 38.7,58.4 38.35,58.05 38.35,57.49 38.58,57.25 U29.N2 ; v1(66.26,149.15) 66.05,149.37 66.05,149.53 66.84,150.32 66.84,161.4 83.34,177.9 95.79,177.9 97.34,176.35 103.11,176.35 108.61,170.85 108.61,167.94 108.46,167.79 U27.A14
  BOTTOM w0.102: v1(34.67,94.62) 34.67,94.92 34.77,95.02 35.46,95.02 35.85,95.42 35.85,106.26 37.78,108.19 37.78,114.44 44.47,121.13 60.53,137.19 ; 60.53,137.19 v2(60.78,136.93) ; 60.53,137.19 65.76,142.42 65.76,149.2 65.89,149.33 66.09,149.33 v1(66.26,149.15)
FDI_TX_DP1: length 179.6
  TOP w0.102: v1(67.64,148.03) 67.39,148.28 67.39,148.41 67.93,148.96 68.13,149.16 68.13,161.48 83.74,177.09 95.35,177.09 96.82,175.62 102.43,175.62 107.9,170.15 107.9,168.07 107.9,168.07 107.9,167.23 U27.B13 ; U29.P3 37.97,56.75 37.66,57.05 37.66,58.14 38.02,58.51 38.02,67.49 36.39,69.13 36.39,70.75 33.43,73.7 30.46,76.67 30.46,82.23 35.23,87 35.23,92.07 34.98,92.33 34.78,92.33 v1(34.59,92.14)
  BOTTOM w0.102: v1(34.59,92.14) 35.09,92.14 35.36,91.87 35.92,91.87 36.47,92.43 36.47,105.82 38.48,107.82 38.48,113.51 50.91,125.95 ; 50.91,125.95 66.92,141.95 66.92,147.82 67.26,148.16 67.51,148.16 v1(67.64,148.03) ; 50.91,125.95 v2(51.16,125.7)
FET_CNTRL_PIN: length 4.8
  TOP w0.305: R623.2 73.83,30.61 C470.1 v2(72.9,30.58) 71.27,30.58 70.99,30.86 Q55.5
FP_AUD_DETECT: length 257.3
  TOP w0.102: FL5.2 10.77,211.33 v1(10.92,211.18) ; v1(10.39,66.5) 9.3,66.5 3.07,60.27 3.07,55.27 4.78,53.57 5.86,53.57 5.98,53.45 5.98,53.45 6.32,53.11 6.32,51.08 8.69,48.72 8.69,47.85 6.83,45.99 6.83,43.14 7.36,42.61 7.36,38.83 v1(9.56,36.64) ; U29.R31 37.17,41.74 v3(36.86,41.43) ; v1(7.48,29.31) 8.51,29.31 10.13,27.69 10.13,26.18 11.02,25.3 11.02,22.73 12.01,21.74 16.27,21.74 17.11,20.9 19.65,20.9 R441.1 20.69,21.13 22.15,21.13 22.58,20.7 v1(22.73,20.7)
  BOTTOM w0.102: v1(10.92,211.18) 10.52,210.77 v2(10.52,208.79) 10.52,206.83 5.14,201.46 5.14,196.15 3.81,194.81 3.81,116.35 4.76,115.4 4.76,112.61 4.12,111.97 4.12,105.23 8.62,100.73 8.62,79.12 8.77,78.97 8.77,68.42 9.18,68.01 10.39,66.8 v1(10.39,66.5) ; v1(9.56,36.64) 8.56,35.64 8.56,30.97 7.99,30.4 7.99,29.82 v1(7.48,29.31) ; v3(36.86,41.43) 37.23,41.05 37.23,39.2 37.13,39.1 37.13,30.97 37.95,30.15 37.95,27.82 38.4,27.37 38.4,26.23 38.07,25.9 38.07,25.04 38.79,24.33 38.79,23.72 38.79,23.32 38.15,22.68 36.12,22.68 35.87,22.94 28.82,22.94 28.54,22.66 25.58,22.66 24.36,21.44 23.77,21.44 23.04,20.7 v1(22.73,20.7)
FP_AUDIO_PRESENCE*_C: length 17.3
  TOP w0.102: FL5.1 C82.1 9.21,213.59 11,215.38 11,217.65 8.61,220.04 8.61,223.49 6.77,225.34 AUDF1.4
FP_MIC1_L: length 3.9
  TOP w0.203: U2.21 22.51,225.32 21.79,224.61 v2(21.79,223.82) 21.79,223.04 C29.1
FP_MIC1_LL: length 29.3
  TOP w0.203: v1(9.75,216.28) 9.74,216.27 L1.1 ; v1(30.84,219.28) 31.94,220.38 R3.2 R6.1 R9.2
  BOTTOM w0.203: v1(9.75,216.28) 9.75,216.64 11.18,218.06 12.42,218.06 v2(14.38,220.01) 14.6,220.24 22.65,220.24 23.79,219.1 30.66,219.1 v1(30.84,219.28)
FP_MIC1_LL_1: length 12
  TOP w0.203: C29.2 21.54,220.93 23.42,219.05 29.26,219.05 v1(30.18,219.96) 31.05,220.84 R3.1
FP_MIC1_R: length 3.5
  TOP w0.203: U2.22 v2(23.01,224.54) 23.01,223.06 C16.1
FP_MIC1_RR: length 31.3
  TOP w0.203: v1(11.94,218.57) 12.14,218.36 12.14,213.84 11.77,213.47 11.77,210.85 L2.1 ; R10.2 R7.1 R4.2 29.4,220.46 v1(28.68,219.74)
  BOTTOM w0.203: v1(11.94,218.57) 13.97,220.6 v2(23.37,220.6) 23.44,220.6 24.61,219.43 28.37,219.43 v1(28.68,219.74)
FP_MIC1_RR_1: length 7.8
  TOP w0.203: C16.2 22.76,220.65 23.95,219.46 26.62,219.46 v1(27.74,220.57) 28.51,221.35 R4.1
FP_MICVREF_D1: length 2.5
  TOP w0.203: D1.1 34.45,222.52 v1(34.49,222.48) 34.49,221.58 R49.1
FP_MICVREF_D2: length 2.9
  TOP w0.203: R27.1 35.45,221.69 v1(36.22,222.47) 36.42,222.66 D1.2
FP_OUT_L: length 12.6
  TOP w0.203: TC7.1 13.34,217.3 16.36,220.32 16.36,223.83 17.32,224.79 v1(17.78,224.79) 18.32,224.79 19.01,225.48 U2.14
FP_OUT_L_C: length 5.3
  TOP w0.203: TC7.2 15.88,215.39 14.48,214 v1(14.48,212.98) 14.48,212.15 R118.1
FP_OUT_R: length 13.9
  TOP w0.203: U2.15 19.51,225.5 18.93,224.92 18.92,224.92 18.08,224.08 17.08,224.08 16.85,223.86 v1(16.85,219.63) 19.95,216.53 TC4.1
FP_OUT_R_C: length 8.8
  TOP w0.203: R75.1 17.56,211.9 v1(18.12,212.46) 20.73,215.06 22.28,215.06 TC4.2
FP_OUTR_L: length 18.9
  TOP w0.203: C102.1 FL4.2 9.09,206.38 8.23,205.51 6.5,205.51 5.91,206.1 Q10.2 3.53,207.89 3.53,217.78 AUDF1.9
FP_OUTR_LL: length 8.5
  TOP w0.203: R118.2 R130.1 v2(13.72,209.8) 12.83,208.91 12.83,206.88 12.32,206.38 FL4.1
FP_OUTR_R: length 24.2
  TOP w0.203: FL3.2 C92.1 8.8,207.45 7.75,206.4 6.32,206.4 5.32,207.4 Q10.1 4.34,209.05 4.34,215.52 5.41,216.59 5.41,221.51 4.23,222.69 AUDF1.5
FP_OUTR_RR: length 21.1
  TOP w0.203: FL3.1 12.05,208.34 v2(12.12,208.41) 12.32,208.61 12.32,213.23 14.86,215.77 14.86,217.04 15.41,217.59 16.34,217.59 16.89,217.04 16.89,214.58 15.37,213.06 15.37,211.52 R90.1 R75.2
FP_RST_DBR_N: length 257.3
  TOP w0.102: R761.2 54.86,24.61 v1(55.7,25.45) ; v1(171.2,143) 173.04,141.16 R264.1
  BOTTOM w0.102: v1(55.7,25.45) 56.68,25.45 59.56,28.33 66.56,28.33 68.45,30.23 73.91,30.23 75.44,31.75 89.74,31.75 90.12,31.37 90.59,31.37 90.8,31.57 94.61,31.57 97.08,29.11 105.85,29.11 106.05,29.31 113.39,29.31 114.31,28.39 132.98,28.39 142.16,37.57 142.16,43.15 143.74,44.73 143.74,53.06 154.37,63.7 157.75,63.7 159.19,62.26 162.9,62.26 165.19,64.55 165.19,65.84 166.36,67 166.36,77.99 168.64,80.27 175.3,80.27 184.96,89.93 184.96,106.63 184.73,106.86 184.73,118.67 185.02,118.96 185.02,123.39 190.04,128.41 190.04,140.54 183.78,146.8 182.87,146.8 181.64,145.57 v2(180.31,145.57) 179.86,145.57 178.87,144.58 176.1,144.58 175.56,145.11 171.77,145.11 171.2,144.54 v1(171.2,143)
FP_RST_PCH_N: length 111.3
  TOP w0.102: v1(66.12,14.38) 65.94,14.55 65.94,16.66 65.38,17.22 63.68,17.22 63.33,17.56 63.33,20.28 60.3,23.32 56.08,23.32 55.68,23.72 v1(55.68,24.24) 54.99,23.56 R761.1 53.26,23.56 R45.1 ; U29.N36 v3(39.31,38.89)
  BOTTOM w0.102: LEDH1.7 9.82,18.27 15.65,12.45 21.29,12.45 21.54,12.7 23.51,12.7 23.69,12.52 27.51,12.52 31.19,16.21 31.5,16.21 32.05,16.76 40.48,16.76 43.32,13.92 65.66,13.92 v1(66.12,14.38) ; v1(55.68,24.24) 55.21,24.71 53.7,24.71 53.42,24.43 v2(52.63,24.43) 51.61,24.43 51.03,25.02 45.9,25.02 43.48,27.43 42.67,27.43 42.06,28.04 42.06,29.25 42.17,29.36 42.17,30.76 41.76,31.17 41.76,31.96 40.47,33.24 40.47,34.23 39.56,35.15 39.56,35.61 39.59,35.64 39.59,38.21 39.31,38.49 v3(39.31,38.89)
FRONT_JD: length 44.9
  TOP w0.102: v1(14.69,221.56) R73.2
  BOTTOM w0.102: v1(14.69,221.56) 15.06,221.93 v2(17.7,221.93) 38.87,221.93 40.44,223.49 44.3,223.49 44.93,224.13 47.98,224.13 48.67,224.82 48.67,227.43 AUDJK1.23
FRONT_USB3_RX2+: length 9.6
  TOP w0.102: USBF3.17 144.71,77.35 144.49,77.13 144.49,76.44 145.36,75.56 145.87,75.56 147.32,74.12 147.32,73.58 147.45,73.45 U47.4 U47.7 147.45,71.86 146.72,71.13 146.72,70.8 146.88,70.64 L51.3
FRONT_USB3_RX2-: length 9.6
  TOP w0.102: L51.4 146.33,70.64 146.51,70.82 146.51,71.22 146.96,71.67 U47.6 U47.5 146.96,73.46 147.1,73.61 147.1,74.03 145.78,75.35 145.28,75.35 144.27,76.35 144.27,77.22 144.14,77.35 USBF3.18
FRONT_USB3_TX2+: length 8.8
  TOP w0.102: USBF3.14 150.6,77.35 150.47,77.22 150.47,76.07 148.81,74.41 148.81,73.61 148.95,73.46 U47.1 U47.10 148.95,71.99 148.79,71.83 148.79,71.49 149.12,71.16 149.12,70.82 149.32,70.62 L32.3
FRONT_USB3_TX2-: length 8.8
  TOP w0.102: USBF3.15 150.13,77.35 150.25,77.23 150.25,76.16 148.59,74.5 148.59,73.64 148.46,73.51 U47.2 U47.9 148.46,71.92 148.58,71.79 148.58,71.4 148.91,71.07 148.91,70.8 148.77,70.67 L32.4
FWH_ID0: length 6.9
  TOP w0.102: LPC1.6 23.16,6.43 23.16,7.62 23.65,8.11 25.84,10.3 R662.1
GPIO_PCIE_RESET: length 160.8
  TOP w0.102: v3(28.17,46.11) 27.84,46.44 U29.AN22 ; v1(4.45,94.59) 10.79,100.93 10.79,110.88 9.96,111.71 9.96,170.33 5.21,175.08 5.21,182.63 5.65,183.07 R659.1 R525.1 ; v1(11.81,51.42) 12.69,50.55 15.24,50.55 16.66,49.12 16.92,49.12 17.76,48.29 18.21,48.29 18.82,47.67 v1(18.82,47.32)
  BOTTOM w0.102: v1(11.81,51.42) 11.36,51.88 11.25,51.88 10.16,52.96 10.16,53.6 8.53,55.22 8.53,57.57 8.53,58.16 8.53,58.16 8.53,63.86 7.73,64.66 7.73,65.94 6.28,67.39 6.28,69.99 5.02,71.25 4.97,71.25 4.45,71.77 v2(4.45,86.23) v1(4.45,94.59) ; v1(18.82,47.32) 18.85,47.32 19.29,46.88 20,46.88 20.27,47.14 21.77,47.14 22.09,46.82 26.63,46.82 26.63,46.83 27.13,46.83 27.15,46.82 27.87,46.11 v3(28.17,46.11)
GPO50/JP1: length 7.4
  TOP w0.102: U61.23 99.27,9.28 98.81,8.81 98.3,8.81 97.16,7.67 96.32,7.67 v2(95.75,7.1) 95.76,7.09 95.76,6.73 96.06,6.43 R643.1 R635.1
GREEN_CRT: length 10.1
  TOP w0.102: L7.2 75.18,229.68 C15.1 75.25,230.06 76.39,231.2 U1.6 76.9,231.2 77.47,231.78 77.72,232.54 77.72,233.57 VGA1.2
H_CPURST_N: length 46.9
  TOP w0.102: R416.2 v2(169.8,139.19) 169.29,139.19 155.19,153.29 155.19,153.53 C567.1 151.58,157.15 134.1,157.15 133.77,156.82 U27.M39
H_DRAMPWRGD: length 262
  TOP w0.102: v1(185.48,118.92) 185.35,119.05 R2227.2 R2226.1 184.54,121.15 R138.1 184.61,121.22 R404.1 ; U29.AE38 32.17,37.6 32.48,37.29 32.48,36.98 32.36,36.85 32.36,36.6 32.52,36.43 32.52,34.54 31.93,33.95 31.93,33.39 31.85,33.32 31.85,32.64 31.95,32.54 31.95,30.2 32.66,29.48 32.66,26.4 33.04,26.02 33.15,25.91 33.15,23.37 36.56,19.97 41.75,19.97 49.79,11.93 54.99,11.93 58.66,8.27 62.81,8.27 71.56,17.02 71.56,19.89 75.41,23.73 75.41,25.17 v1(77.17,26.92)
  BOTTOM w0.102: v1(185.48,118.92) 185.09,118.52 185.09,107.01 185.46,106.64 185.46,89.66 180.43,84.62 v2(180.43,84.62) 180.43,84.62 175.72,79.91 168.78,79.91 166.71,77.84 166.71,66.86 165.54,65.69 165.54,64.4 163.04,61.9 159.04,61.9 157.6,63.34 154.52,63.34 144.32,53.14 144.32,44.37 142.65,42.7 142.65,37.55 133.12,28.03 106.6,28.03 106.56,27.99 96.49,27.99 95.99,28.5 89.17,28.5 88.26,29.41 81.46,29.41 78.97,26.92 v1(77.17,26.92)
H_DRAMPWRGD_CPU: length 88.1
  TOP w0.102: R138.2 183.37,121.44 v1(175.39,121.44) ; U27.AK21 v1(117.51,140.81)
  BOTTOM w0.102: v1(117.51,140.81) 117.08,141.25 117.08,141.92 117.81,142.65 123.68,142.65 128.85,147.83 132.59,147.83 135.38,150.62 136.08,150.62 137.23,151.76 149.94,151.76 173.56,128.14 173.56,123.27 v2(174.17,122.66) v1(175.39,121.44)
H_PECI: length 294.1
  TOP w0.102: v1(92.46,4.11) 92.63,4.29 95.15,4.29 95.96,3.48 97.82,3.48 98.17,3.84 R674.1 ; v1(132.14,155.44) U27.N37 ; v1(184.48,122.66) 181.39,122.66 v1(181.14,122.91) ; v1(80.82,4.31) 80.6,4.09 79.3,4.09 78.23,5.16 78.23,17.26 79.01,18.03 79.01,18.87 R578.2 80.1,19.96 80.65,19.96 84.65,23.97 84.65,25.65 85.86,26.86 85.86,33.72 v1(86.03,33.88)
  BOTTOM w0.102: v1(132.14,155.44) 132.29,155.44 132.92,156.08 135.35,156.08 135.81,156.53 152.8,156.53 154.42,154.91 155.24,154.91 155.91,154.24 155.91,151.88 168.98,138.81 173.26,138.81 176.22,135.85 177.01,135.85 179.86,133.01 179.86,124.77 181.14,123.49 v1(181.14,122.91) ; v1(184.48,122.66) v2(184.48,121.72) 184.48,118.92 184.38,118.82 184.38,106.72 184.61,106.49 184.61,90.08 175.16,80.63 168.49,80.63 166,78.14 166,67.15 164.83,65.98 164.83,64.7 162.75,62.61 159.34,62.61 157.34,64.61 156.03,64.61 155.56,64.14 153.03,64.14 136.39,47.5 135.73,47.5 133.81,45.58 133.81,42.16 129.37,37.72 113.8,37.72 110.55,34.47 107.37,34.47 107.01,34.11 86.26,34.11 v1(86.03,33.88) ; v1(80.82,4.31) 81.02,4.11 v1(92.46,4.11)
H_PM_SYNC_0: length 281.6
  TOP w0.102: v1(51.04,33.85) 50.95,33.94 47.69,33.94 46.51,35.12 43.26,35.12 42.77,35.61 42.77,36.66 42.39,37.05 U29.F40 ; U27.P36 v1(130.32,154.53)
  BOTTOM w0.102: v1(51.04,33.85) 51.57,33.85 52.3,33.12 54.13,33.12 54.79,33.78 63.63,33.78 66.88,37.03 100.04,37.03 102.84,39.83 127.97,39.83 129.92,41.77 129.92,42.06 130.2,42.34 130.74,42.88 130.74,45.39 134.89,49.53 135.18,49.53 135.55,49.53 135.58,49.56 135.58,49.56 148.54,62.52 148.54,70.43 154.15,76.05 155.22,76.05 156.16,76.99 156.16,80.31 156.94,81.1 161.85,81.1 161.88,81.13 166.91,81.13 167.83,82.05 172.15,82.05 173.16,83.06 175.58,83.06 178.74,86.22 178.74,99.53 181.62,102.41 181.62,122.23 181.96,122.57 181.96,123.68 180.57,125.07 180.57,133.9 175.07,139.4 v2(171.42,139.4) 168.89,139.4 156.87,151.42 156.87,153.78 155.38,155.27 154.57,155.27 152.88,156.95 135.35,156.95 135.34,156.97 134.97,156.97 134.52,156.51 132.59,156.51 131.69,155.62 131.69,155.27 131.4,154.99 130.96,154.99 130.5,154.53 v1(130.32,154.53)
H_PRDY_N: length 79.3
  TOP w0.102: v1(136.58,158.65) 136.18,158.65 135.61,158.09 134.2,158.09 133.84,157.73 U27.L39 ; XDPC1.5 185.44,130.43 183.77,128.76 v1(182.37,128.76)
  BOTTOM w0.102: v1(182.37,128.76) 182.37,137.56 184.51,139.69 184.51,140.17 184.05,140.62 174.84,140.62 174.14,141.33 167.29,141.33 157.4,151.21 v2(157.4,152.07) 157.1,152.37 157.1,156 155.26,157.84 153.7,157.84 152.89,158.65 v1(136.58,158.65)
H_PREQ_N: length 88.5
  TOP w0.102: XDPC1.3 185.47,129.93 184.94,129.4 v1(184.94,128.45) ; U27.L37 v1(131.23,158.19)
  BOTTOM w0.102: v1(184.94,128.45) 185.22,128.73 185.22,140.43 183.53,142.12 174.28,142.12 174.17,142.01 167.73,142.01 162.81,146.93 v2(162.81,149.91) 161.44,151.28 161.44,157.83 158.23,161.04 136.52,161.04 136.13,161.42 135.06,162.49 132.51,162.49 132.33,162.31 131.99,162.31 131.69,162.02 131.69,161.62 131.23,161.16 v1(131.23,158.19)
H_PROCHOT_N: length 21
  TOP w0.102: R112.2 171.47,162.01 170.88,161.42 169.9,161.42 v1(169.75,161.57) ; v1(160.7,157.56) 160.7,158.16 161.98,159.44 161.98,161.56 v1(162.07,161.66) ; R340.1 R263.1 v1(157.4,156.97)
  BOTTOM w0.102: v1(169.75,161.57) 168.96,162.36 v2(168.15,162.36) 167.54,162.97 164.74,162.97 163.87,162.09 162.5,162.09 v1(162.07,161.66) ; v1(157.4,156.97) 160.12,156.97 v1(160.7,157.56)
H_PROCHOT_N_R: length 6.6
  TOP w0.102: C153.1 170.03,162.97 170.09,162.9 R109.2 R112.1 172.13,162.9 v2(172.52,162.51) 173.57,161.46 U52.3
H_PROCHOT_R_N: length 25
  TOP w0.102: U27.K38 132.97,158.28 133.67,158.28 134.04,158.64 134.04,158.77 134.35,159.08 135.15,159.08 135.18,159.11 154.33,159.11 v2(155.45,157.99) 155.64,157.8 R263.2
H_PWRGD: length 279
  TOP w0.102: U29.D40 43.12,37.22 v3(42.9,37.44) ; U27.AB35 130.38,148.19 130.98,148.19 131.02,148.24 133.25,148.24 133.87,148.86 135.15,148.86 138.97,152.69 151.09,152.69 167.41,136.37 167.41,134.04 170.38,131.07 170.38,123.05 171.08,122.35 171.41,122.35 C512.1 171.45,122.32 R140.2 173.48,122.32 173.49,122.31 R519.1 174.28,121.54 174.65,121.54 175.21,120.98 179.8,116.38 v1(182.43,116.38)
  BOTTOM w0.102: v1(182.43,116.38) 182.43,101.76 182.45,101.74 182.45,101.24 179.86,98.65 179.86,85.83 175.01,80.98 168.27,80.98 164.67,77.38 160.1,77.38 157.09,74.37 154.85,74.37 153.49,73.02 153.49,69.56 152.44,68.51 150.62,68.51 150.18,68.07 150.18,62.65 135.99,48.46 135.33,48.46 132.84,45.98 132.84,42.56 128.97,38.68 113.4,38.68 110.15,35.43 101.11,35.43 100.58,35.97 73.84,35.97 v2(72.62,34.75) 70.36,32.49 67.67,32.49 65.87,30.69 60.43,30.69 59.82,31.3 51.97,31.3 51.82,31.45 51.42,31.45 50.99,31.88 50.57,31.88 49.54,32.91 49.54,34.05 48.56,35.03 45.27,35.03 44.67,35.63 44.67,35.7 42.93,37.44 v3(42.9,37.44)
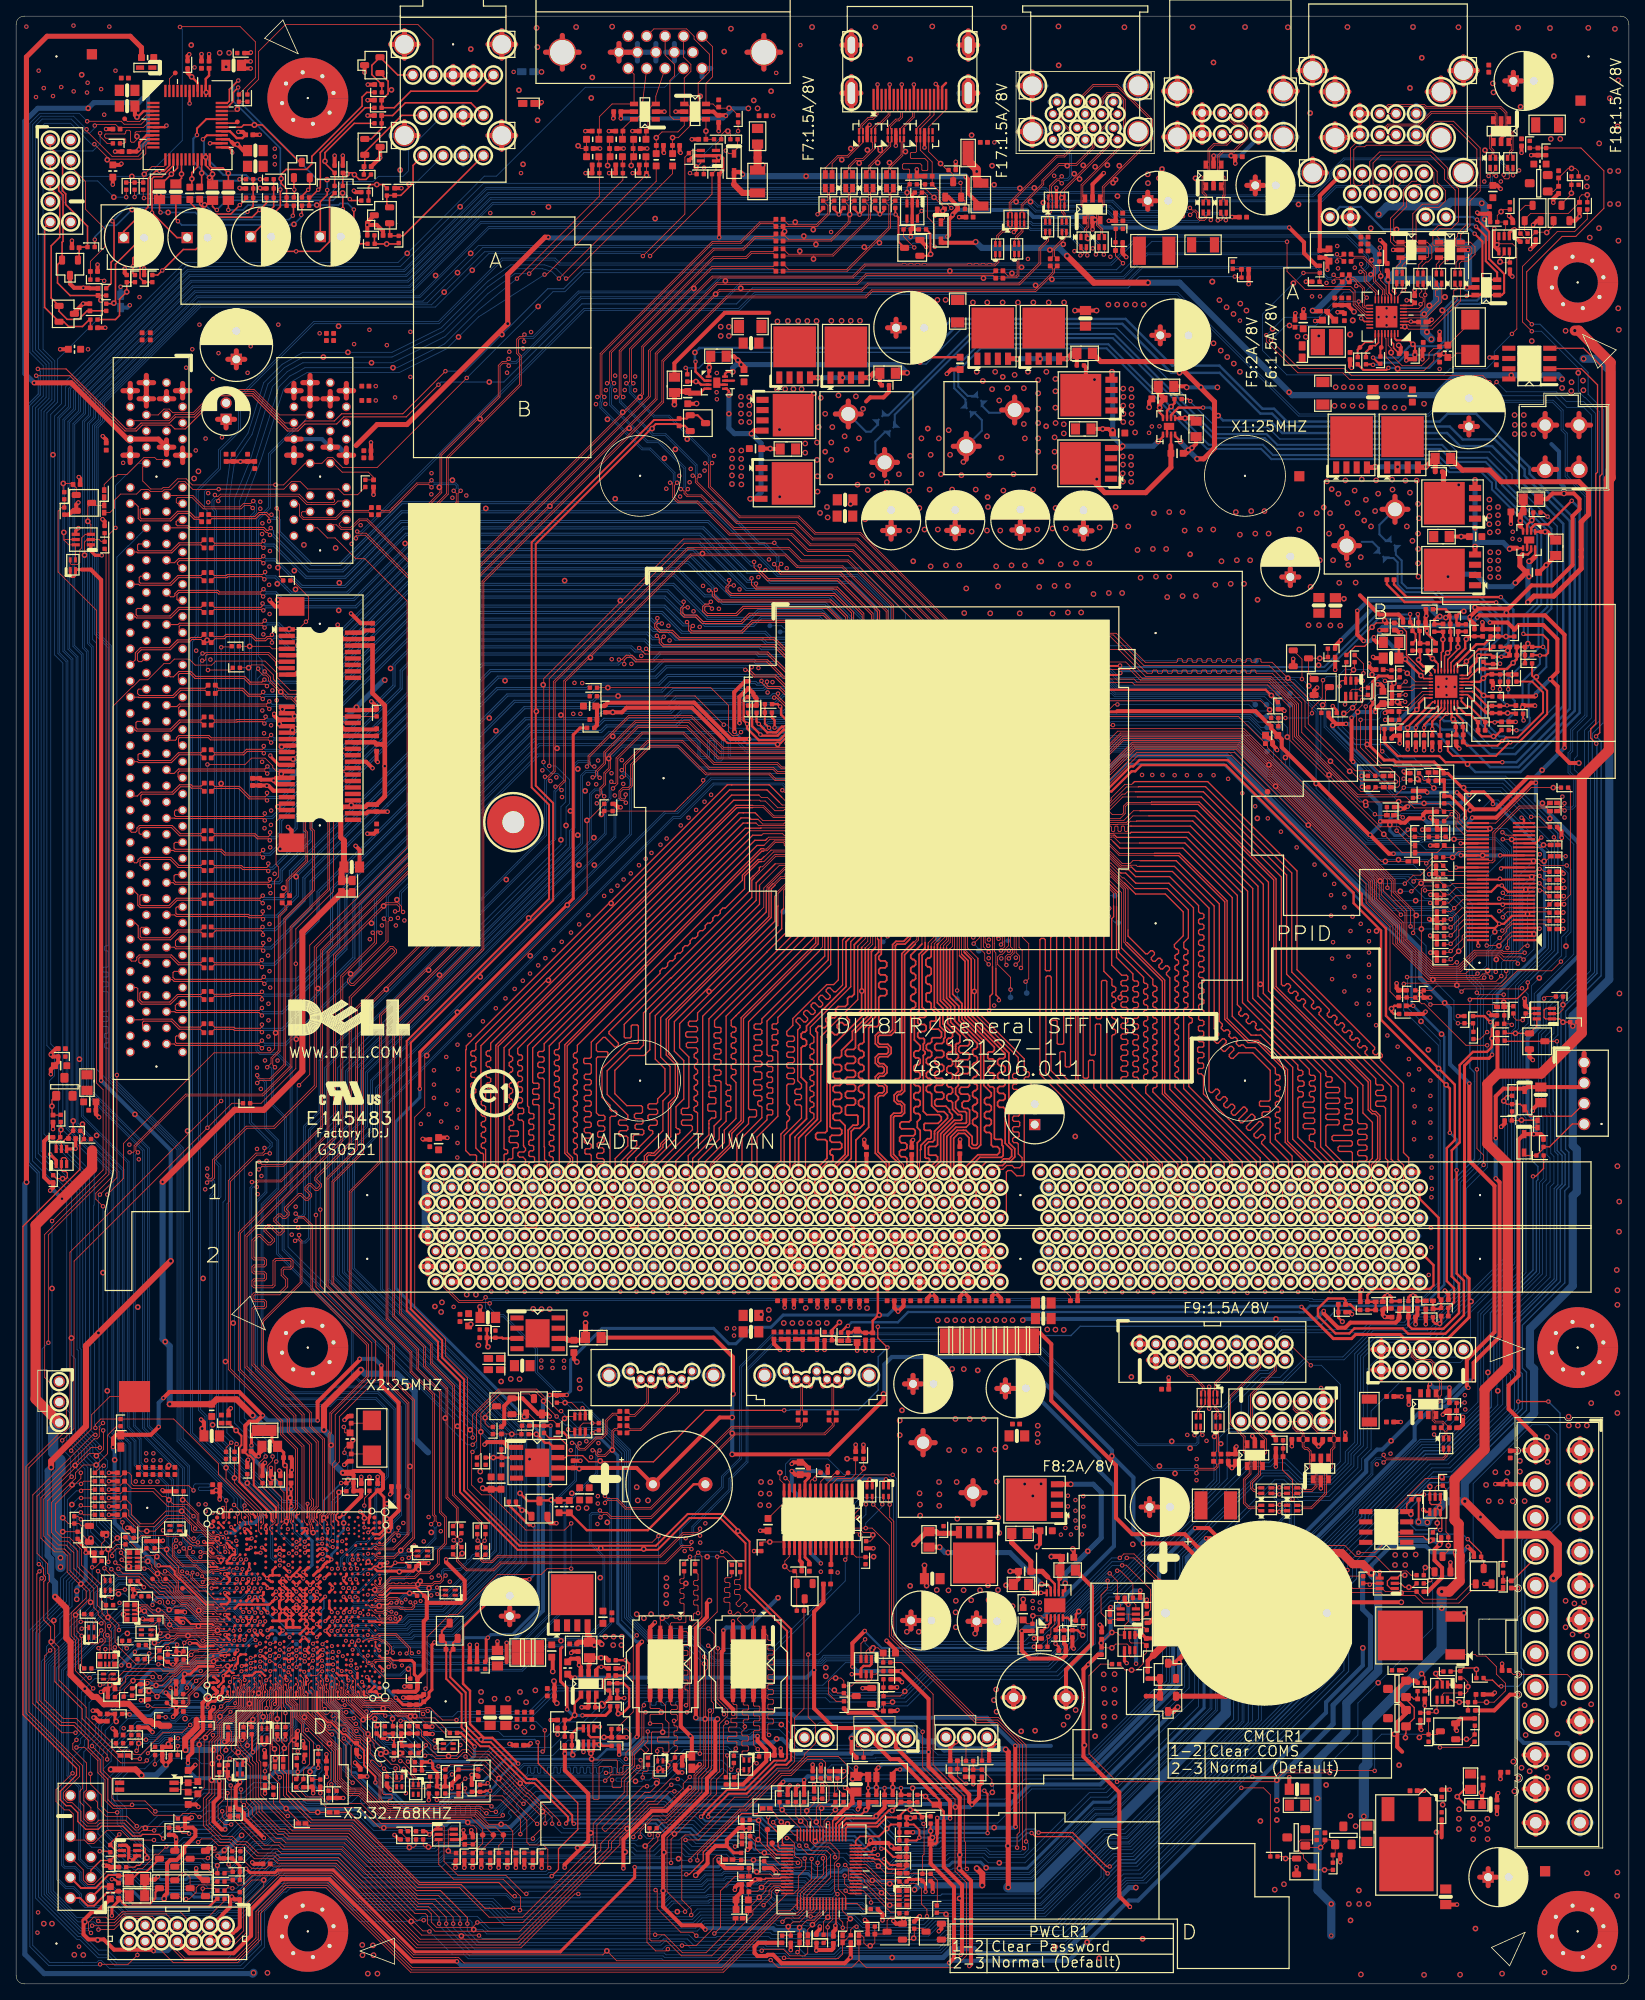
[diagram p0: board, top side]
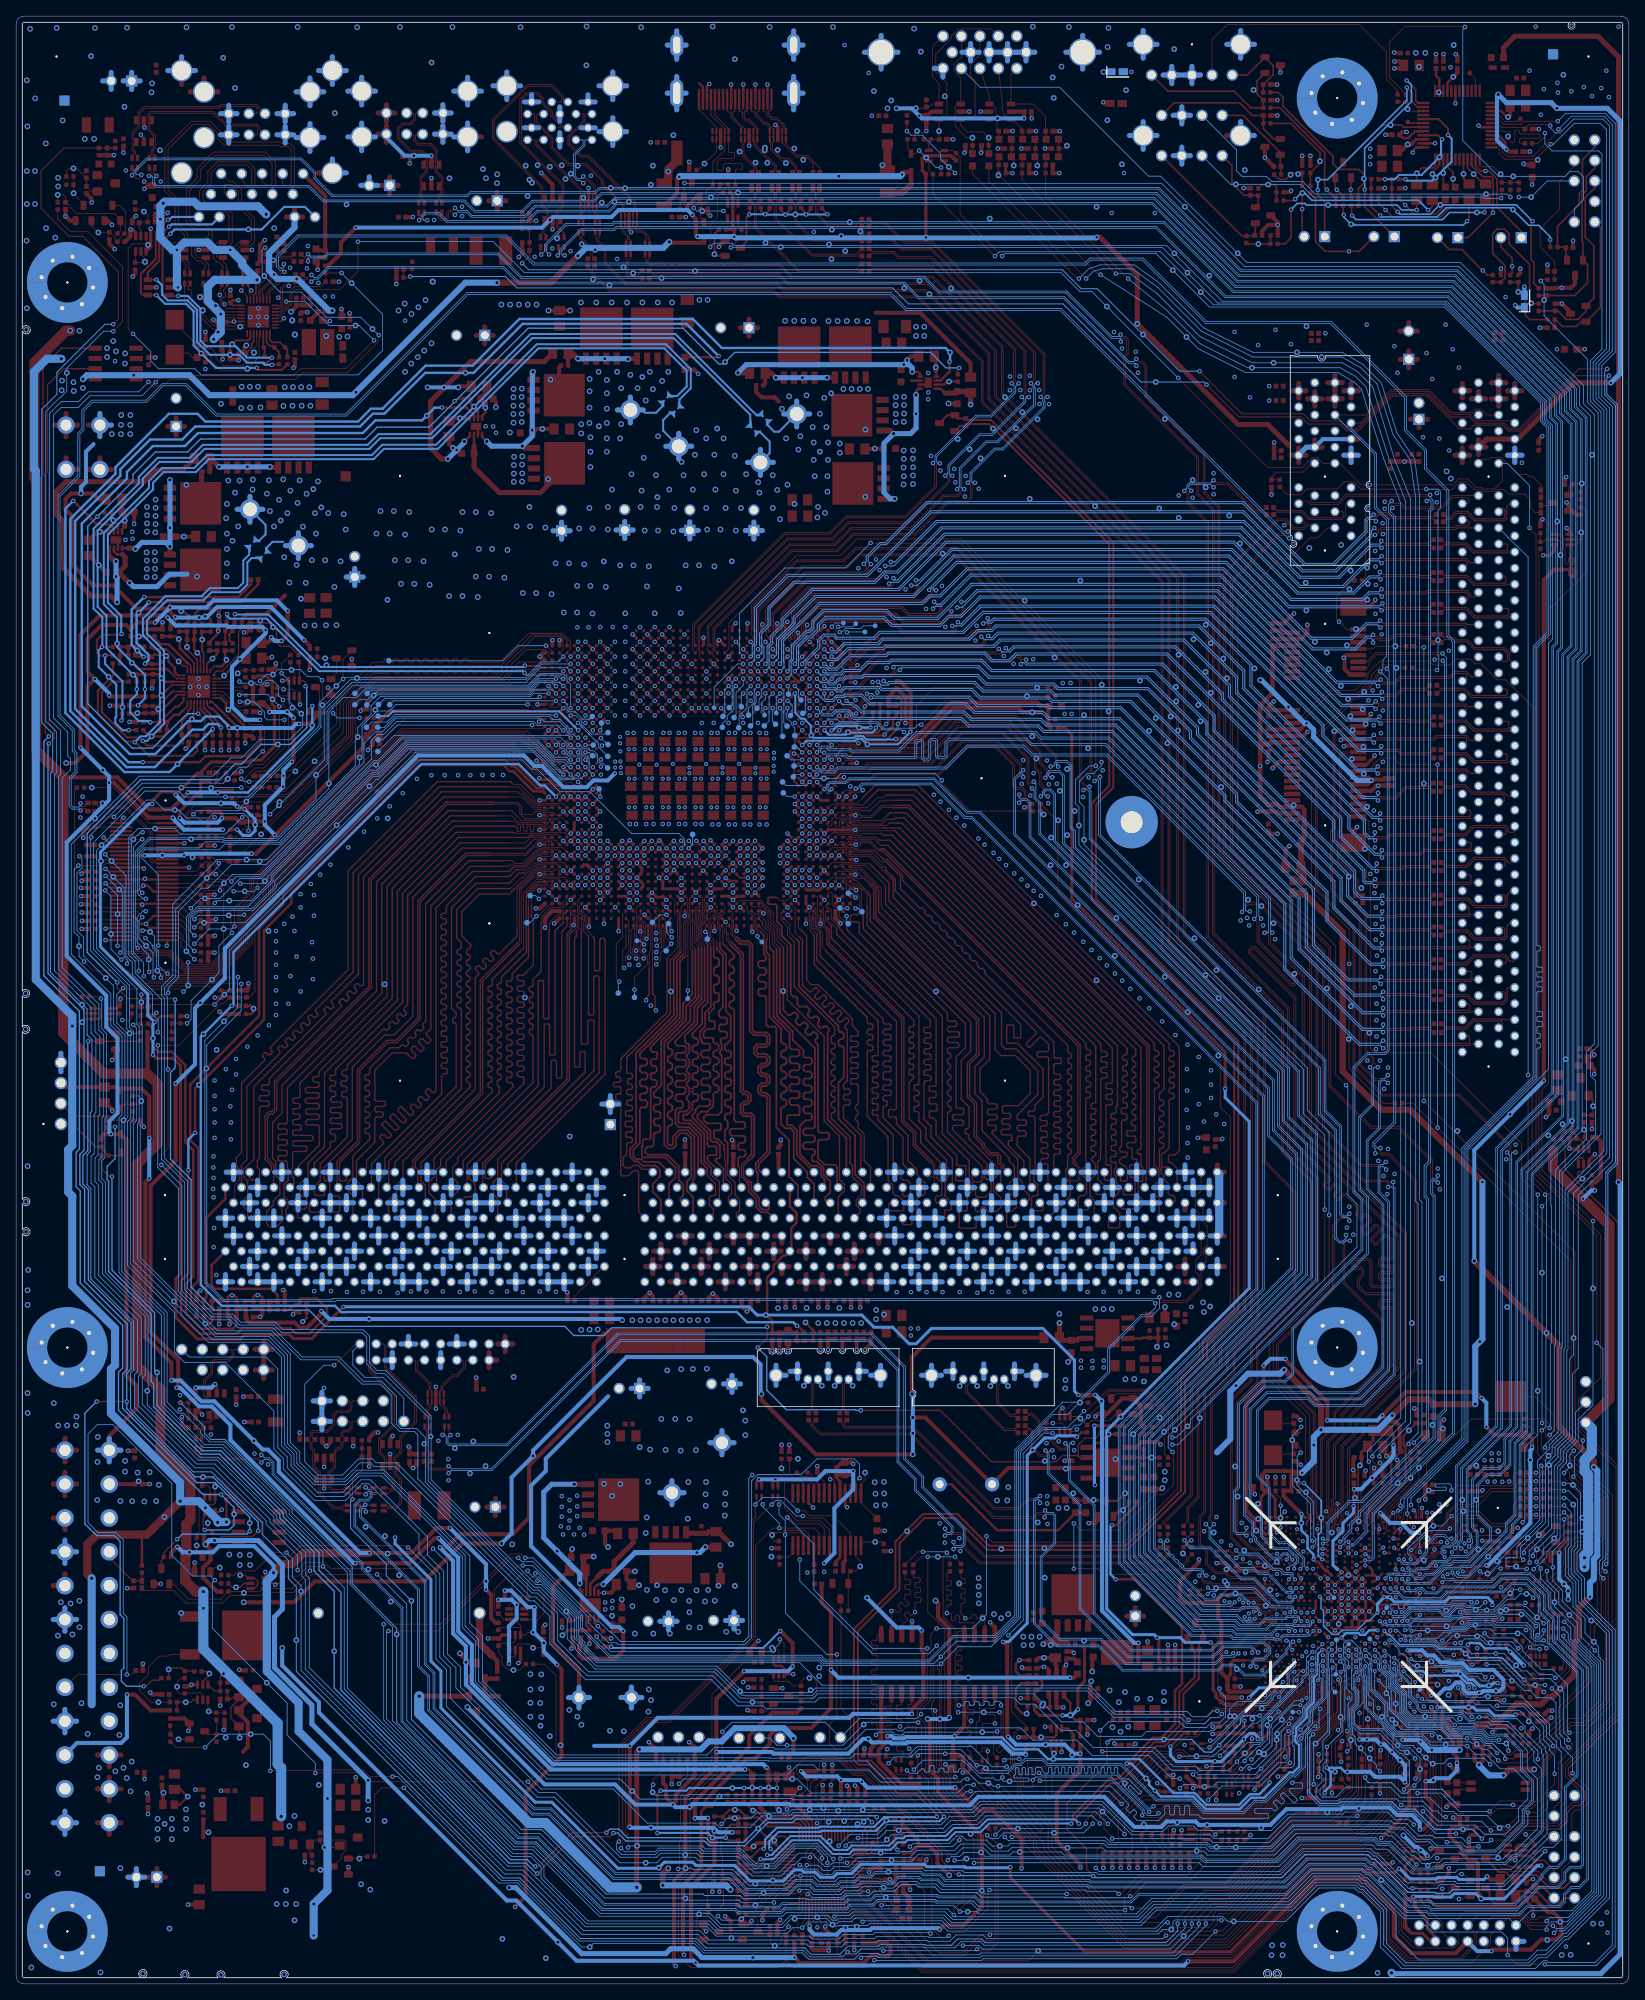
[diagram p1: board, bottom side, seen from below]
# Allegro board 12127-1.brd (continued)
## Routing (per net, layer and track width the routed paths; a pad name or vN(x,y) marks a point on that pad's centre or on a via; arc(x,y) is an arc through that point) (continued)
H_RSTOUT_XDP_N: length 4.6
  TOP w0.102: R660.2 v2(178.13,139.69) 178.87,140.43 XDPC1.46
H_SKTOCC_N: length 379.8
  TOP w0.102: U29.AE34 32.51,40.66 v3(32.6,40.66) ; v1(159.46,161.8) 159.46,164.27 Q54.G ; v1(24.41,30.84) 24.41,30.52 23.93,30.04 23.93,23.72 23.22,23.01 23.22,19.62 25.31,17.53 26.54,17.53 27.15,16.92 28.14,16.92 29.54,15.52 31.85,15.52 32.41,14.96 39.68,14.96 49.81,4.83 62.44,4.83 74.88,17.27 74.88,18.11 78.67,21.89 80.33,21.89 82.73,24.29 82.73,24.84 v1(83.54,25.65) ; v1(174.04,147.18) 173.91,147.05 R795.1 ; U27.D38 v1(132.14,164.59)
  BOTTOM w0.102: v1(24.41,30.84) 24.66,31.09 28.75,31.09 30.33,32.66 30.33,34.66 32.14,36.47 32.14,39.06 32.08,39.12 32.08,39.73 32.1,39.75 32.1,40.16 v3(32.6,40.66) ; v1(83.54,25.65) 83.69,25.5 92.35,25.5 94.49,27.64 106.71,27.64 106.74,27.68 133.27,27.68 143.05,37.46 143.05,42.57 144.67,44.19 144.67,52.99 154.66,62.99 157.45,62.99 159.53,60.91 162.59,60.91 165.9,64.22 165.9,65.54 167.07,66.71 167.07,77.7 168.93,79.56 176.13,79.56 185.82,89.25 185.82,106.78 185.45,107.16 185.45,118.08 185.94,118.57 185.94,123.8 190.4,128.26 190.4,141.54 184.04,147.9 179.86,147.9 179.13,147.18 v1(174.04,147.18) 171.22,147.18 162.43,155.96 162.43,158.83 v2(160.31,160.95) v1(159.46,161.8) 159.28,161.98 136.85,161.98 134.9,163.92 132.81,163.92 v1(132.14,164.59)
H_SKTOCC_VCORE: length 6.4
  TOP w0.102: Q56.G 160.28,162.47 Q54.D v2(161.67,164.37) 162.52,164.37 R299.1 R298.2
H_TCK: length 72.9
  TOP w0.102: XDPC1.57 190.18,143.43 R663.2 188.96,144.71 v1(187.89,144.71) ; v1(172.09,148.34) 171.2,147.46 166.39,147.46 159.02,154.83 159.02,158.71 155.62,162.11 140.08,162.11 136.74,165.45 134.26,165.45 134,165.19 134,164.61 U27.D39
  BOTTOM w0.102: v1(187.89,144.71) 184.25,148.34 v2(179.5,148.34) v1(172.09,148.34)
H_TDI: length 60.1
  TOP w0.102: U27.F38 133.07,162.77 135.13,162.77 135.35,163 138.08,163 139.43,161.65 155.43,161.65 158.55,158.54 158.55,154.66 166.65,146.56 v2(167.34,146.56) 172.65,146.56 173.39,145.82 176.61,145.82 R640.2 177.22,145.49 178.22,145.49 178.79,144.92 178.79,144.1 179.96,142.93 XDPC1.56
H_TDO: length 58.6
  TOP w0.102: U27.F39 134.01,161.81 138.61,161.81 139,161.42 155.33,161.42 158.32,158.44 158.32,154.34 169.18,143.48 171.48,143.48 172.72,142.24 R2216.2 R2218.2 R2219.1 R2217.1 177.58,141.93 v2(178.31,141.93) XDPC1.52
H_THERMTRIP_N: length 244.6
  TOP w0.102: R127.1 171.7,144.91 v1(171.96,144.65) ; v1(54.61,32.72) 52.88,32.72 52.05,33.54 52.05,33.55 51.76,33.84 51.75,33.85 51.31,34.29 50.86,34.29 50.71,34.14 47.77,34.14 46.56,35.36 44.21,35.36 43.48,36.08 43.48,36.58 U29.C40
  BOTTOM w0.102: v1(54.61,32.72) 55.32,33.43 63.77,33.43 67.03,36.68 100.87,36.68 101.4,36.14 109.85,36.14 113.1,39.4 128.04,39.4 130.27,41.63 130.27,41.91 131.18,42.82 131.18,45.32 135.03,49.17 135.7,49.17 148.89,62.37 148.89,70.29 154.3,75.69 155.37,75.69 156.51,76.84 156.51,80.17 157.09,80.74 167.02,80.74 167.97,81.69 172.3,81.69 173.31,82.7 175.73,82.7 179.09,86.07 179.09,99.39 181.97,102.27 181.97,122.08 185.24,125.35 185.24,126.82 186.03,127.6 186.03,142.11 184.88,143.25 v2(182.78,143.25) 180.31,143.25 179.62,142.56 174.05,142.56 v1(171.96,144.65)
H_TMS: length 59.2
  TOP w0.102: XDPC1.58 180,143.43 179.02,144.41 179.02,145.01 177.65,146.39 R639.2 v2(174.6,146.39) 173.15,146.39 172.34,147.19 166.33,147.19 158.78,154.75 158.78,158.63 155.52,161.88 139.64,161.88 137.61,163.91 135.08,163.91 134.81,163.63 133.93,163.63 U27.E39
H_TRST_N: length 62.8
  TOP w0.102: R661.2 177.93,145.03 v1(178.03,145.03) 178.56,144.5 178.56,143.52 179.64,142.43 XDPC1.54 ; U27.E37 v1(131.23,163.67)
  BOTTOM w0.102: v1(178.03,145.03) 177.59,145.47 172.45,145.47 172.14,145.78 172.14,145.86 172.11,145.88 172.11,145.95 v2(171.45,146.61) 171.42,146.61 162.2,155.83 162.2,158.07 158.53,161.75 136.76,161.75 134.83,163.67 v1(131.23,163.67)
H_VIDALERT_N: length 3.9
  TOP w0.102: R424.2 174.6,149.2 174.45,149.35 174.45,149.65 R516.1 ; R424.2 R128.2 ; R424.2 175.15,148.96 v2(175.82,148.29)
H_VIDALERT_N_1: length 52.8
  TOP w0.102: U27.B37 131.69,166.6 132.36,167.27 136.07,167.27 139.86,163.47 155.4,163.47 159.84,159.04 159.84,155.89 v2(165.37,150.36) 165.55,150.36 166.78,149.13 171.04,149.13 v1(171.09,149.07) ; v1(172.07,149.45) 172.27,149.25 172.27,149.24 R341.2 R516.2
  BOTTOM w0.102: v1(171.09,149.07) 171.7,149.07 v1(172.07,149.45)
H_VIDALERT_N_VR: length 25.9
  TOP w0.102: R128.1 176.03,150.33 175.41,150.95 170.87,150.95 170.61,151.21 169.41,151.21 167.36,153.25 v1(167.36,158.39) ; v1(172.31,159.83) 172.27,159.79 R353.2 172.11,160.39 173.16,160.39 173.43,160.66 U52.5
  BOTTOM w0.102: v1(172.31,159.83) 172.25,159.89 168.82,159.89 v2(168.2,159.28) 167.36,158.44 v1(167.36,158.39)
H_VIDSCK: length 56
  TOP w0.102: R136.2 168.6,148.38 R482.2 168.08,147.86 166.75,147.86 163,151.61 v2(162.99,151.61) 159.43,155.17 159.43,158.87 155.79,162.52 153.84,162.52 153.74,162.62 153.74,162.81 153.63,162.92 153.23,162.92 153.13,162.81 153.13,162.62 153.02,162.52 152.62,162.52 152.52,162.62 152.52,162.81 152.41,162.92 152.01,162.92 151.91,162.81 151.91,162.62 151.8,162.52 151.4,162.52 151.3,162.62 151.3,162.81 151.2,162.92 150.79,162.92 150.69,162.81 150.69,162.62 150.59,162.52 150.18,162.52 150.08,162.62 150.08,162.81 149.98,162.92 149.57,162.92 149.47,162.81 149.47,162.62 149.37,162.52 148.96,162.52 148.86,162.62 148.86,162.81 148.76,162.92 148.35,162.92 148.25,162.81 148.25,162.62 148.15,162.52 147.74,162.52 147.64,162.62 147.64,162.81 147.54,162.92 147.13,162.92 147.03,162.81 147.03,162.62 146.93,162.52 146.52,162.52 146.42,162.62 146.42,162.81 146.32,162.92 145.91,162.92 145.81,162.81 145.81,162.62 145.71,162.52 145.3,162.52 145.2,162.62 145.2,162.81 145.1,162.92 144.69,162.92 144.59,162.81 144.59,162.62 144.49,162.52 144.08,162.52 143.98,162.62 143.98,162.81 143.88,162.92 143.47,162.92 143.37,162.81 143.37,162.62 143.27,162.52 142.86,162.52 142.76,162.62 142.76,162.81 142.66,162.92 142.25,162.92 142.15,162.81 142.15,162.62 142.05,162.52 141.64,162.52 141.54,162.62 141.54,162.81 141.44,162.92 141.04,162.92 140.93,162.81 140.93,162.62 140.83,162.52 140.24,162.52 135.7,167.07 132.44,167.07 132.18,166.8 132.18,165.46 U27.C38
H_VIDSCK_VR: length 24.5
  TOP w0.102: v1(172.26,158.97) 171.71,158.97 R226.2 171.9,158.38 172.49,158.38 174.36,160.26 U52.6 ; R136.1 171.34,148.38 171.55,148.59 171.55,149.6 170.37,150.77 169.26,150.77 166.73,153.31 v1(166.73,156.74)
  BOTTOM w0.102: v1(172.26,158.97) v2(171.3,158.97) 170.46,158.97 169.21,157.72 169.21,157.1 168.86,156.74 v1(166.73,156.74)
H_VIDSOUT: length 55.1
  TOP w0.102: U27.C37 131.28,165.45 131.28,166.48 132.27,167.47 136.44,167.47 140.03,163.88 143.9,163.88 144.01,163.98 144.01,164.21 144.11,164.31 144.51,164.31 144.61,164.21 144.61,163.98 144.72,163.88 145.12,163.88 145.22,163.98 145.22,164.21 145.33,164.31 145.73,164.31 145.83,164.21 145.83,163.98 145.94,163.88 146.34,163.88 146.44,163.98 146.44,164.21 146.55,164.31 146.95,164.31 147.05,164.21 147.05,163.98 147.15,163.88 147.56,163.88 147.66,163.98 147.66,164.21 147.76,164.31 148.17,164.31 148.27,164.21 148.27,163.98 148.37,163.88 148.78,163.88 148.88,163.98 148.88,164.21 148.98,164.31 149.39,164.31 149.49,164.21 149.49,163.98 149.59,163.88 150,163.88 150.1,163.98 150.1,164.21 150.2,164.31 150.61,164.31 150.71,164.21 150.71,163.98 150.81,163.88 151.22,163.88 151.32,163.98 151.32,164.21 151.42,164.31 151.83,164.31 151.93,164.21 151.93,163.98 152.03,163.88 152.44,163.88 152.54,163.98 152.54,164.21 152.64,164.31 153.05,164.31 153.15,164.21 153.15,163.98 153.25,163.88 153.66,163.88 153.76,163.98 153.76,164.21 153.86,164.31 154.27,164.31 154.37,164.21 154.37,163.98 154.47,163.88 155.75,163.88 v2(157.72,161.91) 160.24,159.39 160.24,156.24 166.06,150.43 167.9,150.43 R800.2 168.55,149.78 R129.2
H_VIDSOUT_VR: length 24.8
  TOP w0.102: R129.1 170.47,150.11 170.21,150.37 168.97,150.37 166.24,153.1 166.24,157.89 166.91,158.55 v1(166.91,159.21) ; v1(172.31,161.48) 172.19,161.48 R102.2 172.9,160.8 173.15,161.06 U52.4
  BOTTOM w0.102: v1(172.31,161.48) 172.12,161.29 v2(170.87,161.29) 170.36,161.29 170.15,161.09 169.54,161.09 168.99,161.65 168.2,161.65 167.49,160.93 167.49,159.79 v1(166.91,159.21)
H_VTTPWRGD: length 17.5
  TOP w0.165: U52.1 175.46,162.49 175.16,162.79 174.42,162.79 172.42,164.8 172.42,167.69 171.83,168.28 171.7,168.28 171.22,168.76 C71.1 R257.2 168.68,168.76 v2(168.15,168.22) 167.72,167.79 167.72,166.34 167.23,165.86 166.05,165.86 R258.2
H_VTTPWRGD_R: length 238.8
  TOP w0.165: R258.1 164.87,163.79 Q37.3 164.34,161.59 164.11,161.36 v1(164.11,160.91) ; 68.3,65.46 68.1,65.26 U51.7 ; 68.3,65.46 68.3,66.84 67.45,67.69 66.09,67.69 R790.2 ; 68.3,65.46 68.35,65.51 70.24,65.51 71.01,64.74 79.04,64.74 85.42,71.12 v1(95.25,71.12) ; v1(108.05,78.91) 106.86,80.1 v1(106.86,81.48) ; v1(187.46,124.17) 187.46,123.47 186.16,122.17 180.41,122.17 v1(180.28,122.05)
  BOTTOM w0.165: v1(180.28,122.05) 180.28,113.58 180.85,113.01 180.85,111.9 180.85,102.27 178.3,99.71 178.3,86.4 175.44,83.54 163.68,83.54 161.67,81.53 131.95,81.53 130.81,80.39 127.09,80.39 126.14,81.35 106.99,81.35 v1(106.86,81.48) ; v1(187.46,124.17) 191.19,127.9 191.19,142.66 184.54,149.32 174.8,149.32 172.87,151.26 172.03,151.26 169.6,153.69 v2(167.54,153.69) 166.06,153.69 163.95,155.79 163.95,160.75 v1(164.11,160.91) ; v1(95.25,71.12) 95.89,71.12 95.95,71.19 104.46,71.19 106.91,73.63 106.91,77.77 v1(108.05,78.91)
HD_LED_PWR1: length 3
  TOP w0.254: LEDH1.1 10.69,12.06 11.68,12.06
HDMI_DETECT: length 52.8
  TOP w0.102: R2243.1 16.57,41.53 17.59,41.53 R445.1 ; U29.AV29 24.77,42.84 23.49,42.84 23.32,43.01 20.08,43.01 19.46,42.39 19.2,42.39 18.9,42.09 18.53,42.09 R445.1 ; R445.1 17.78,41.27 16.15,39.65 14.86,39.65 12.73,41.78 12.73,41.93 12.27,42.39 12.27,44.33 10.66,45.94 10.66,46.34 10.11,46.89 10.11,49.25 7.64,51.71 7.64,53.65 6.41,54.89 5.46,54.89 4.39,55.96 4.39,59.72 7.37,62.69 7.37,63.38 8.32,64.34 v2(9.93,64.34) 11.33,65.74 11.33,68.02 12.46,69.15 R599.2
HDMI_LANE0_DN: length 13.5
  TOP w0.102: 102.39,226.52 101.98,226.52 101.2,225.73 TR1.2 ; 102.39,226.52 103.2,226.52 105.02,228.33 U32.2 U32.9 105.02,230.01 104.9,230.12 104.9,230.38 105.11,230.58 105.73,231.2 106.29,231.2 106.89,231.8 106.89,232.05 106.99,232.16 107.23,232.16 107.33,232.26 HDMI1.3 ; 102.39,226.52 v2(102.39,226.19)
HDMI_LANE0_DN_C: length 10.8
  TOP w0.102: 98.86,217.91 99.31,217.91 100.88,219.49 100.88,220.54 R58.1 101.11,221.11 100.88,221.34 100.88,222.1 101.2,222.41 TR1.1 ; 98.86,217.91 C44.2 ; 98.86,217.91 v2(98.86,217.52)
HDMI_LANE0_DP: length 13.5
  TOP w0.102: 103.73,227.36 103.11,226.73 101.89,226.73 100.35,225.19 TR1.3 ; 103.73,227.36 v2(103.5,227.58) ; 103.73,227.36 104.54,228.16 U32.1 U32.10 104.54,229.97 104.69,230.12 104.69,230.47 104.89,230.67 105.64,231.42 106.2,231.42 106.67,231.89 106.67,232.15 106.33,232.5 HDMI1.1
HDMI_LANE0_DP_C: length 10.8
  TOP w0.102: C43.2 95.78,218.13 96.62,218.13 ; v2(96.62,218.46) 96.62,218.13 ; 96.62,218.13 99.22,218.13 100.67,219.58 100.67,220.51 R57.1 100.56,221.1 100.67,221.2 100.67,222.1 100.35,222.41 TR1.4
HDMI_LANE1_DN: length 12.9
  TOP w0.102: TR2.2 103.73,224.62 103.43,224.92 103.43,225.35 104.19,226.11 104.55,226.11 ; 104.55,226.11 105.05,226.11 106.44,227.49 106.44,228.32 106.54,228.42 U32.5 U32.6 106.54,230.19 106.96,230.61 107.26,230.61 108.37,231.71 108.37,232.05 108.47,232.16 108.73,232.16 108.83,232.26 HDMI1.6 ; 104.55,226.11 v2(104.55,225.78)
HDMI_LANE1_DN_C: length 14.7
  TOP w0.102: TR2.1 103.73,222.42 103.41,222.11 103.41,221.33 103.63,221.11 R60.1 103.41,220.55 103.41,218.41 101.11,216.11 99.19,216.11 ; v2(99.19,215.69) 99.19,216.11 ; 99.19,216.11 C46.2
HDMI_LANE1_DP: length 12.9
  TOP w0.102: 105.8,227.17 104.96,226.33 104.1,226.33 103.21,225.44 103.21,224.96 102.88,224.62 TR2.3 ; 105.8,227.17 v2(105.56,227.41) ; 105.8,227.17 106.22,227.58 106.22,228.29 106.06,228.46 U32.4 U32.7 106.06,230.01 106.87,230.82 107.17,230.82 108.15,231.8 108.15,232.05 108.05,232.16 107.93,232.16 107.83,232.26 HDMI1.4
HDMI_LANE1_DP_C: length 14.7
  TOP w0.102: TR2.4 102.88,222.42 103.2,222.1 103.2,221.2 103.1,221.1 R59.1 103.2,220.55 103.2,218.5 101.02,216.33 97.69,216.33 ; 97.69,216.33 v2(97.69,216.73) ; 97.69,216.33 95.78,216.33 C45.2
HDMI_LANE2_DN: length 12
  TOP w0.102: v2(106.85,225.82) 106.62,226.04 ; 106.62,226.04 105.97,225.39 105.97,224.89 106.27,224.59 TR3.2 ; 106.62,226.04 108.46,227.88 108.46,228.37 108.57,228.49 U25.2 U25.9 108.57,229.96 108.42,230.11 108.42,230.26 109.17,231.01 109.5,231.01 109.92,231.43 109.92,232.05 110.02,232.16 110.23,232.16 110.33,232.26 HDMI1.9
HDMI_LANE2_DN_C: length 17.8
  TOP w0.102: 98.88,214.26 C48.2 ; 98.88,214.26 101.33,214.26 105.95,218.88 105.95,220.53 R62.1 106.14,221.11 105.95,221.3 105.95,222.15 106.27,222.46 TR3.1 ; 98.88,214.26 v2(98.88,213.88)
HDMI_LANE2_DP: length 12
  TOP w0.102: 107.4,227.12 108.24,227.97 108.24,228.33 108.09,228.48 U25.1 U25.10 108.09,230.01 108.2,230.12 108.2,230.35 109.08,231.23 109.41,231.23 109.7,231.52 109.7,232.08 109.6,232.18 109.43,232.18 109.33,232.28 HDMI1.7 ; 107.4,227.12 v2(107.16,227.36) ; 107.4,227.12 105.75,225.48 105.75,224.93 105.42,224.6 TR3.3
HDMI_LANE2_DP_C: length 17.8
  TOP w0.102: C47.2 95.78,214.47 97.18,214.47 ; 97.18,214.47 101.24,214.47 105.74,218.97 105.74,220.52 R61.1 105.64,221.1 105.74,221.2 105.74,222.12 105.42,222.44 TR3.4 ; 97.18,214.47 v2(97.18,214.87)
HDMI_LANE3_DN: length 11.4
  TOP w0.102: HDMI1.12 111.83,232.23 111.73,232.13 111.47,232.13 111.37,232.03 111.37,231.46 110.09,230.19 U25.6 U25.5 110.09,228.53 109.96,228.4 109.96,227.2 ; 109.96,227.2 109.96,226.73 108.45,225.21 108.45,224.98 108.78,224.65 TR4.2 ; 109.96,227.2 v2(110.29,227.2)
HDMI_LANE3_DN_C: length 21.6
  TOP w0.102: 106.83,216.13 103.07,212.37 C50.2 ; 106.83,216.13 v2(107.06,215.9) ; 106.83,216.13 108.44,217.74 108.44,220.53 R64.1 108.66,221.11 108.47,221.3 108.47,222.11 108.78,222.42 TR4.1
HDMI_LANE3_DP: length 11.3
  TOP w0.102: TR4.3 107.94,224.65 108.23,224.94 108.23,225.3 108.53,225.6 ; 108.53,225.6 v2(108.31,225.83) ; 108.53,225.6 109.75,226.81 109.75,228.4 109.61,228.53 U25.4 U25.7 109.61,230.01 111.15,231.55 111.15,232.05 111.05,232.16 110.93,232.16 110.83,232.26 HDMI1.10
HDMI_LANE3_DP_C: length 21.7
  TOP w0.102: 105.47,215.07 108.23,217.83 108.23,220.52 R63.1 108.12,221.1 108.25,221.23 108.25,222.07 107.94,222.39 TR4.4 ; 105.47,215.07 v2(105.18,215.37) ; 105.47,215.07 102.98,212.59 95.81,212.59 C49.2
HSI_DN3: length 169.6
  TOP w0.102: v1(30.15,101.93) 30.48,101.6 33.07,101.6 37.78,106.31 37.78,128.21 50.03,140.45 50.03,174.89 43.48,181.43 42.62,181.43 41.53,180.34 40.3,180.34 39.71,180.92 39.32,180.92 SLOT1.A17 ; U29.F11 42.09,51.68 v3(42.28,51.49)
  BOTTOM w0.102: 45.64,57.66 v2(45.97,57.66) ; 45.64,57.66 45.64,55.42 44.07,53.85 42.32,53.85 41.21,52.74 41.21,52.39 41.68,51.92 41.85,51.92 v3(42.28,51.49) ; 45.64,57.66 45.64,58.41 47.08,59.84 47.08,71.29 44.95,73.42 39.48,73.42 38.71,72.64 33.35,72.64 29.91,76.09 29.91,96.93 31.09,98.11 31.09,101.32 30.82,101.59 30.49,101.59 v1(30.15,101.93)
HSI_DN4: length 294.2
  TOP w0.102: v1(29.85,98.82) 29.85,99.28 30.02,99.45 32.87,99.45 38.79,105.36 38.79,127.89 50.94,140.04 50.94,183.06 52.78,184.9 52.78,189.56 60.01,196.79 60.01,200.6 60.37,200.96 60.99,200.96 61.09,200.86 v1(61.09,200.63) ; U29.J11 40.67,51.54 v3(40.74,51.46) ; v1(163.38,211.06) 163.38,211.26 163.51,211.39 164.12,211.39 C85.2
  BOTTOM w0.102: 89.64,210.49 88.14,208.99 70.1,208.99 62.06,200.96 61.24,200.96 61.09,200.81 v1(61.09,200.63) ; 89.64,210.49 v2(89.87,210.26) ; 89.64,210.49 89.94,210.79 137.69,210.79 139.65,212.75 161.21,212.75 162.58,211.39 163.06,211.39 v1(163.38,211.06) ; v3(40.74,51.46) 40.42,51.78 40.42,52.72 42.32,54.61 43.48,54.61 44.72,55.84 44.72,61.43 46.19,62.9 46.19,71.16 44.67,72.68 39.73,72.68 38.88,71.83 32.94,71.83 29.21,75.56 29.21,98.64 29.39,98.82 v1(29.85,98.82)
HSI_DN5: length 132.5
  TOP w0.102: MINI1.23 34.71,155.95 35,155.66 36.03,155.66 36.66,155.03 36.66,143.32 36.98,143 36.98,135.58 33.43,132.02 33.43,113.91 31.52,112.01 30.2,112.01 v1(29.9,111.71) ; v3(41.73,52.6) 41.68,52.65 U29.G9
  BOTTOM w0.102: 46.53,56.21 v2(46.2,56.21) ; 46.53,56.21 46.53,57.15 47.57,58.19 47.57,71.48 45.14,73.91 39.29,73.91 38.57,73.19 33.57,73.19 30.39,76.37 30.39,96.69 32.35,98.64 32.35,104.53 30.84,106.05 30.84,111.73 30.51,112.06 30.25,112.06 v1(29.9,111.71) ; 46.53,56.21 46.53,55.68 46.19,55.33 46.19,54.98 44.12,52.91 43.41,52.91 42.88,53.44 42.34,53.44 41.96,53.06 41.96,52.83 v3(41.73,52.6)
HSI_DP3: length 169.6
  TOP w0.102: v3(41.5,51.49) 41.5,51.99 U29.H11 ; SLOT1.A16 40.56,181.55 40.07,181.06 40.07,180.87 40.39,180.56 41.44,180.56 42.53,181.65 43.57,181.65 50.24,174.98 50.24,140.36 38,128.12 38,106.22 33.16,101.38 30.49,101.38 v1(30.1,100.99)
  BOTTOM w0.102: v3(41.5,51.49) 41.5,51.79 41,52.3 41,52.83 42.23,54.06 43.98,54.06 45.43,55.51 45.43,58.5 46.23,59.3 ; 46.23,59.3 46.86,59.93 46.86,71.2 44.86,73.2 39.57,73.2 38.8,72.43 33.26,72.43 29.69,76 29.69,97.02 30.87,98.2 30.87,101.23 30.73,101.37 30.48,101.37 v1(30.1,100.99) ; 46.23,59.3 v2(46,59.54)
HSI_DP4: length 294.3
  TOP w0.102: v1(61.09,201.5) 60.76,201.17 60.28,201.17 59.79,200.69 59.79,196.88 52.57,189.65 52.57,184.99 50.72,183.15 50.72,140.13 38.57,127.98 38.57,105.45 32.78,99.66 29.93,99.66 29.69,99.43 v1(29.23,99.43) ; C81.2 164.12,211.6 163.71,211.6 v1(163.38,211.92) ; U29.L11 39.9,52.07 v3(39.9,51.49)
  BOTTOM w0.102: v1(163.38,211.92) 163.06,211.6 162.67,211.6 161.3,212.97 139.56,212.97 137.6,211.01 89.85,211.01 88.05,209.21 86.74,209.21 ; v3(39.9,51.49) 40.21,51.79 40.21,52.81 42.23,54.83 43.4,54.83 44.5,55.93 44.5,61.52 45.97,62.99 45.97,71.07 44.58,72.47 39.82,72.47 38.97,71.62 32.85,71.62 28.99,75.48 28.99,98.73 29.23,98.97 v1(29.23,99.43) ; v1(61.09,201.5) 61.41,201.17 61.97,201.17 70.01,209.21 86.74,209.21 ; 86.74,209.21 v2(86.74,209.52)
HSI_DP5: length 132.5
  TOP w0.102: v1(29.9,112.67) 29.9,112.34 30.01,112.23 31.43,112.23 33.21,114 33.21,132.11 36.77,135.67 36.77,142.91 36.45,143.23 36.45,154.94 35.94,155.45 34.93,155.45 34.63,155.15 MINI1.25 ; U29.F9 42.4,52.65 v3(42.44,52.6)
  BOTTOM w0.102: 43.66,52.69 43.32,52.69 42.79,53.23 42.43,53.23 42.18,52.97 42.18,52.87 v3(42.44,52.6) ; 43.66,52.69 44.21,52.69 46.41,54.89 46.41,55.24 46.75,55.59 46.75,57.06 47.79,58.1 47.79,71.57 45.23,74.13 39.2,74.13 38.48,73.41 33.66,73.41 30.61,76.46 30.61,96.6 32.56,98.55 32.56,104.62 31.05,106.13 31.05,111.82 30.6,112.28 30.29,112.28 v1(29.9,112.67) ; 43.66,52.69 v2(43.66,52.32)
HSI_LAN_DN4_R: length 5.7
  TOP w0.102: U12.18 167.5,207.73 167.41,207.82 167.18,207.82 166.97,208.04 166.97,210.21 166.64,210.54 v1(166.19,210.54) 166.19,210.98 165.82,211.36 165.65,211.36 C85.1
HSI_LAN_DP4_R: length 5.7
  TOP w0.102: U12.17 167.48,208.13 167.39,208.04 167.27,208.04 167.18,208.13 167.18,208.79 v1(167.49,209.09) 167.18,209.4 167.18,210.3 165.91,211.57 165.71,211.57 C81.1
HSO_C_DN3: length 10.8
  TOP w0.102: C159.1 43.71,182.71 40.52,182.71 39.6,181.8 35.68,181.8 35.37,182.11 35.37,182.43 35.49,182.55 SLOT1.B15
HSO_C_DN4: length 276.2
  TOP w0.102: v1(163.8,213.59) 163.8,213.91 163.88,213.99 164.25,213.99 C406.2 ; v1(62.99,203.64) 62.99,203.98 62.9,204.07 62.51,204.07 62.29,203.85 62.29,202.25 62.64,201.9 62.64,198.25 53.58,189.2 53.58,184.71 51.64,182.77 51.64,130.23 42.33,120.92 42.33,103.47 38.68,99.82 38.68,86.6 46.19,79.09 46.19,74.59 48.7,72.08 48.7,55.69 46.84,53.82 44.67,53.82 U29.B8
  BOTTOM w0.102: 87.96,211.49 137.4,211.49 140.32,214.41 161.35,214.41 161.74,214.03 163.72,214.03 163.8,213.94 v1(163.8,213.59) ; 87.96,211.49 87.39,211.49 85.59,209.69 69.81,209.69 64.17,204.05 63.06,204.05 62.99,203.98 v1(62.99,203.64) ; 87.96,211.49 v2(87.96,211.18)
HSO_C_DN5: length 21.4
  TOP w0.102: 34.48,137.53 33.71,136.75 33.71,135.14 C539.1 ; 34.48,137.53 v2(34.72,137.29) ; 34.48,137.53 36.15,139.2 36.15,142.82 35.9,143.07 35.9,152.31 35.46,152.75 MINI1.31
HSO_C_DP3: length 11.8
  TOP w0.102: SLOT1.B14 35.03,183.55 35.15,183.42 35.15,182.02 35.59,181.58 39.69,181.58 40.61,182.5 43.74,182.5 C160.1
HSO_C_DP4: length 276.1
  TOP w0.102: C405.2 164.39,214.21 164.07,214.21 v1(163.8,214.48) ; v1(63.04,204.51) 62.82,204.28 62.43,204.28 62.08,203.94 62.08,202.16 62.42,201.81 62.42,198.34 53.37,189.29 53.37,184.8 51.42,182.86 51.42,130.31 42.11,121.01 42.11,103.56 38.47,99.91 38.47,86.51 45.97,79 45.97,74.5 48.49,71.99 48.49,55.78 46.75,54.04 44.88,54.04 44.68,54.25 44.42,54.25 44.11,53.94 U29.C8
  BOTTOM w0.102: v1(163.8,214.48) 163.57,214.24 161.83,214.24 161.44,214.63 140.23,214.63 137.31,211.71 87.3,211.71 85.5,209.91 84.05,209.91 ; 84.05,209.91 69.72,209.91 64.08,204.27 63.28,204.27 v1(63.04,204.51) ; 84.05,209.91 v2(84.05,210.24)
HSO_C_DP5: length 21.4
  TOP w0.102: 33.49,135.89 33.49,136.84 35.94,139.29 35.94,142.73 35.69,142.98 35.69,152.22 35.37,152.53 34.96,152.53 34.37,151.95 MINI1.33 ; 33.49,135.89 v2(33.17,135.89) ; 33.49,135.89 33.49,135.43 C538.1
HSO_C_LAN_DN4: length 8.3
  TOP w0.102: U12.14 169.35,209.41 169.44,209.5 169.44,210.01 168.34,211.11 168.34,211.96 ; 168.34,211.96 v4(168,211.96) ; 168.34,211.96 168.34,212.73 167.06,214.01 165.96,214.01 C406.1
HSO_C_LAN_DP4: length 8.5
  TOP w0.102: 167.87,213.51 v4(168.1,213.74) ; 167.87,213.51 167.15,214.22 165.8,214.22 C405.1 ; 167.87,213.51 168.55,212.82 168.55,211.2 169.66,210.1 169.66,209.5 169.75,209.4 U12.13
HSO_DN3: length 160.1
  TOP w0.102: C159.2 45.3,182.71 46.29,182.71 46.63,183.06 49.69,186.12 51.19,186.12 v1(51.51,186.44) ; U29.B9 44.41,53.33 44.5,53.24 44.5,53.06 44.78,52.78 46.91,52.78 49.42,55.28 49.42,72.4 46.93,74.89 46.93,79.35 39.38,86.89 39.38,99.4 43.07,103.09 43.07,120.48 52.34,129.76 52.34,181.19 54.8,183.65 54.8,184.82 v1(55.12,185.14)
  BOTTOM w0.102: 54.1,186.12 54.52,186.12 54.8,185.84 54.8,185.46 v1(55.12,185.14) ; 54.1,186.12 51.84,186.12 v1(51.51,186.44) ; 54.1,186.12 v2(54.1,186.46)
HSO_DN5: length 94.9
  TOP w0.102: v1(32.1,113.67) 31.83,113.94 31.83,114.73 32.73,115.63 32.73,132.37 33.57,133.21 33.57,133.71 C539.2 ; v1(47.43,55.6) 47.2,55.82 47,55.82 45.53,54.34 44.93,54.34 44.7,54.57 U29.B7
  BOTTOM w0.102: 48.5,64.16 48.5,61.63 49.05,61.09 49.05,56.16 48.6,55.71 47.65,55.71 47.53,55.6 v1(47.43,55.6) ; 48.5,64.16 v2(48.84,64.16) ; 48.5,64.16 48.5,71.9 45.56,74.84 42.63,74.84 41.78,75.69 41.78,81.33 32.51,90.6 32.51,97.48 33.5,98.48 33.5,107.45 31.87,109.09 31.87,113.43 v1(32.1,113.67)
HSO_DP3: length 159.1
  TOP w0.102: v1(51.51,185.58) 51.19,185.9 49.78,185.9 46.72,182.84 46.38,182.5 45.27,182.5 C160.2 ; v1(54.26,185.14) 54.58,184.82 54.58,183.74 52.12,181.28 52.12,129.84 42.85,120.57 42.85,103.17 39.17,99.49 39.17,86.8 46.71,79.26 46.71,74.8 49.2,72.31 49.2,55.37 46.82,53 44.87,53 44.72,53.15 44.72,53.33 44.8,53.41 U29.A9
  BOTTOM w0.102: 52.48,185.9 51.84,185.9 v1(51.51,185.58) ; 52.48,185.9 54.43,185.9 54.58,185.75 54.58,185.46 v1(54.26,185.14) ; 52.48,185.9 v2(52.48,185.57)
HSO_DP5: length 94.8
  TOP w0.102: U29.A7 45.2,54.56 45.44,54.56 46.91,56.03 47.34,56.03 47.43,56.12 v1(47.43,56.56) ; v1(31.13,113.67) 31.61,114.14 31.61,114.82 32.51,115.72 32.51,132.46 33.35,133.3 33.35,133.69 C538.2
  BOTTOM w0.102: v1(47.43,56.56) 47.43,56.22 47.72,55.93 48.51,55.93 48.83,56.25 48.83,60.43 ; v1(31.13,113.67) 31.55,113.67 31.65,113.56 31.65,109 33.29,107.37 33.29,98.56 32.3,97.57 32.3,90.51 41.57,81.24 41.57,75.6 42.54,74.63 45.47,74.63 48.29,71.81 48.29,61.54 48.83,61 48.83,60.43 ; v2(48.51,60.43) 48.83,60.43
HSW_PCUDEBUG_0: length 79.8
  TOP w0.102: U27.AA37 131.98,148.59 132.34,148.94 133.02,148.94 134.03,149.95 135.7,149.95 138.79,153.04 151.3,153.04 167.77,136.58 167.77,134.19 170.74,131.22 170.74,128.99 175.15,124.58 181.87,124.58 v1(182.06,124.77) ; v1(183.97,129.69) 184.03,129.69 184.81,130.47 184.81,130.76 185.48,131.43 XDPC1.9 189.52,131.43 R826.2
  BOTTOM w0.102: v1(183.97,129.69) 183.06,128.78 183.06,128.48 182.58,127.99 182.58,125.74 v2(182.48,125.64) 182.06,125.22 v1(182.06,124.77)
HSW_PCUDEBUG_1: length 78.5
  TOP w0.102: U27.Y38 133.46,150.36 135.46,150.36 138.6,153.5 151.49,153.5 168.22,136.77 168.22,134.38 171.32,131.28 171.32,129.06 175.34,125.03 180.96,125.03 181.19,125.27 v1(181.23,125.27) ; R827.2 190.04,131.93 XDPC1.11 185.65,131.93 184.36,130.64 184.34,130.64 v1(184.3,130.61)
  BOTTOM w0.102: v1(184.3,130.61) 183.54,130.61 v2(183.38,130.45) 182.83,129.9 182.83,128.57 182.35,128.09 182.35,126.26 181.36,125.27 v1(181.23,125.27)
HSW_PCUDEBUG_2: length 83.5
  TOP w0.102: v1(184.37,132.26) 184.38,132.27 184.38,132.39 184.92,132.93 XDPC1.15 190.06,132.93 R828.2 ; U27.AA36 131.13,148.95 131.84,148.95 132.04,149.14 132.9,149.14 133.91,150.16 135.58,150.16 138.69,153.27 151.4,153.27 167.99,136.68 167.99,134.29 171.09,131.19 171.09,128.96 175.25,124.8 181.45,124.8 181.87,125.23 182.49,125.23 v1(182.92,124.79)
  BOTTOM w0.102: v1(184.37,132.26) 184.76,131.86 184.76,129.59 v2(183.89,128.72) 183.02,127.85 183.02,124.89 v1(182.92,124.79)
HSW_PCUDEBUG_3: length 98.9
  TOP w0.102: R867.2 192.75,148.06 192.75,135.07 192.04,134.37 190.67,134.37 R829.2 189.74,133.43 XDPC1.17 184.64,133.43 184.22,133.02 v1(183.92,133.02) ; U27.W38 132.81,150.62 135.4,150.62 138.5,153.73 151.59,153.73 168.45,136.86 168.45,134.48 171.55,131.38 171.55,129.15 175.44,125.26 179.75,125.26 180.21,125.73 183.26,125.73 v1(183.49,125.49)
  BOTTOM w0.102: v1(183.49,125.49) 183.56,125.55 v2(183.56,127.03) 183.56,127.58 184.48,128.5 184.48,128.64 184.99,129.15 184.99,132.28 184.25,133.02 v1(183.92,133.02)
HSW_PCUDEBUG_4: length 83.2
  TOP w0.102: v1(186.94,127.01) 186.61,127.34 184.48,127.34 184.11,127.71 181.01,127.71 179.02,125.72 175.63,125.72 172.01,129.34 172.01,131.63 169.04,134.6 169.04,136.93 151.78,154.19 137.34,154.19 134.83,151.68 134.23,151.68 133.87,151.33 U27.V39 ; R830.2 189.98,134.87 189.26,135.59 v1(188.95,135.59) 188.6,135.93 XDPC1.27
  BOTTOM w0.102: v1(186.94,127.01) 188.24,128.31 v2(188.24,130.18) 188.24,134.87 v1(188.95,135.59)
HSW_PCUDEBUG_5: length 83.1
  TOP w0.102: U27.U39 134.07,152.8 134.65,152.8 136.95,155.1 152.16,155.1 170.54,136.72 170.54,135 172.46,133.08 172.46,129.53 175.82,126.18 178.83,126.18 180.82,128.17 184.3,128.17 184.47,127.99 186.28,127.99 187.02,128.73 v1(187.43,128.73) ; R831.2 189.51,135.88 v1(188.91,136.47) 188.56,136.47 188.52,136.43 XDPC1.29
  BOTTOM w0.102: v1(188.91,136.47) 187.43,134.99 v2(187.43,132.66) v1(187.43,128.73)
HSW_PCUDEBUG_6: length 83.2
  TOP w0.102: R832.2 189.4,136.9 v1(188.91,137.39) 188.87,137.43 XDPC1.33 ; v1(187.07,127.86) 186.97,127.76 184.38,127.76 184.2,127.94 180.91,127.94 178.92,125.95 175.72,125.95 172.24,129.44 172.24,132.84 169.54,135.53 169.54,137.06 151.97,154.64 137.16,154.64 134.76,152.24 U27.U40
  BOTTOM w0.102: v1(187.07,127.86) 186.84,128.09 186.84,135.32 v2(187.22,135.69) v1(188.91,137.39)
HSW_PCUDEBUG_7: length 87.1
  TOP w0.102: v1(186.23,126.51) 186.23,126.64 186,126.87 184.51,126.87 183.9,127.48 181.11,127.48 179.12,125.49 175.53,125.49 171.78,129.25 171.78,131.48 168.68,134.58 168.68,136.96 151.68,153.96 138.41,153.96 135.45,151 133.29,151 132.96,151.33 U27.V38 ; XDPC1.35 188.37,137.93 188.68,138.25 v1(188.93,138.25) 189.14,138.25 189.48,137.91 R833.2
  BOTTOM w0.102: v1(186.23,126.51) 186.23,126.97 186.51,127.25 186.61,127.36 186.61,135.94 v2(187.95,137.28) v1(188.93,138.25)
HSW_PCUDEBUG_8: length 63
  TOP w0.102: v1(172.92,131.12) 172.92,133.18 170.77,135.33 170.77,136.81 152.25,155.33 136.6,155.33 U27.T40 ; XDPC1.10 181.27,131.43 179.73,131.43 178.92,130.61 178.92,129.98 v1(177.9,128.96) 177.83,128.89 R834.2
  BOTTOM w0.102: v1(177.9,128.96) 176.05,130.81 v2(174.27,130.81) 173.23,130.81 v1(172.92,131.12)
HSW_PCUDEBUG_9: length 66.7
  TOP w0.102: v1(130.32,149.96) U27.Y35 ; R835.2 177.81,129.91 v1(177.9,130) 178.66,130.77 178.66,131.12 179.47,131.93 XDPC1.12
  BOTTOM w0.102: v1(177.9,130) 178.36,130.46 178.36,132.2 178.09,132.47 177.95,132.47 177.5,132.91 177.3,133.11 170.6,133.11 167.69,136.02 167.69,136.25 v2(160.25,143.69) 150.95,152.98 135.8,152.98 132.33,149.51 131.03,149.51 130.58,149.96 v1(130.32,149.96)
HSW_PCUDEBUG_10: length 65.8
  TOP w0.102: XDPC1.16 179.84,132.93 v1(177.9,131) 177.83,130.93 R836.2 ; v1(129.41,149.98) 129.41,149.98 129.41,149.05 U27.AA34
  BOTTOM w0.102: v1(177.9,131) 177.32,131.58 v2(176.68,131.58) 171.6,131.58 150.43,152.75 135.88,152.75 132.43,149.31 130.91,149.31 130.72,149.5 129.9,149.5 129.42,149.98 v1(129.41,149.98)
HSW_PCUDEBUG_11: length 62.8
  TOP w0.102: R837.2 177.83,131.94 v1(177.9,132.01) 179.32,133.43 XDPC1.18 ; v1(171.73,132.57) 171.73,132.62 169.29,135.06 169.29,136.99 151.87,154.41 137.28,154.41 134.75,151.89 134,151.89 133.8,151.68 132.87,151.68 132.86,151.7 132.05,151.7 U27.V37
  BOTTOM w0.102: v1(177.9,132.01) 177.42,132.49 v2(173.63,132.49) 171.8,132.49 v1(171.73,132.57)
HSW_PCUDEBUG_12: length 65.4
  TOP w0.102: XDPC1.28 178.58,135.93 177.69,135.04 R838.2 176.53,135.59 v1(174.72,135.59) ; U27.Y34 v1(128.49,149.96)
  BOTTOM w0.102: v1(174.72,135.59) 174.72,136 v2(174.23,136.48) 173.15,137.57 169.72,137.57 155.58,151.71 155.15,151.71 152.27,154.58 132.49,154.58 131.69,153.79 131.69,153.44 131.41,153.16 130.15,153.16 129.86,152.87 129.86,152.53 129.56,152.23 129.22,152.23 128.94,151.96 128.94,150.41 v1(128.49,149.96)
HSW_PCUDEBUG_13: length 59.5
  TOP w0.102: U27.U38 132.96,152.24 133.29,151.91 133.7,151.91 133.99,152.2 133.99,152.32 134.27,152.6 134.73,152.6 137.01,154.87 152.06,154.87 170.05,136.88 v1(170.05,135.92) ; XDPC1.30 178.11,136.43 177.83,136.14 R843.2 176.59,136.65 174.24,136.65 173.08,135.48 v1(173.02,135.48)
  BOTTOM w0.102: v1(173.02,135.48) v2(171.65,135.48) 170.48,135.48 v1(170.05,135.92)
HSW_PCUDEBUG_14: length 62.5
  TOP w0.102: U27.W34 v1(129.4,150.87) ; v1(173.3,136.7) 173.57,136.96 176.3,136.96 R839.2 177.16,137.43 XDPC1.34
  BOTTOM w0.102: v1(129.4,150.87) 129.86,151.33 129.86,151.96 130.16,152.26 131.41,152.26 131.69,152.53 131.69,152.87 131.99,153.17 132.33,153.17 132.6,153.44 132.6,153.79 133.17,154.36 152.18,154.36 v2(155.36,151.17) 155.4,151.13 155.84,151.13 169.68,137.29 172.72,137.29 v1(173.3,136.7)
HSW_PCUDEBUG_15: length 61.8
  TOP w0.102: v1(172.21,136.42) 173.26,137.47 174.16,137.47 175.8,139.12 176.52,139.12 R842.2 177.7,137.93 XDPC1.36 ; U27.V35 v1(130.32,151.79)
  BOTTOM w0.102: v1(172.21,136.42) 169.46,136.42 v2(169.15,136.74) 168.78,137.11 168.78,137.31 155.85,150.24 155.22,150.24 151.56,153.9 135.3,153.9 133.24,151.84 131.93,151.84 131.43,151.34 130.76,151.34 v1(130.32,151.79)
HSW_PCUSTB_0_DN: length 67.5
  TOP w0.102: v1(132.14,149.96) U27.Y37 ; R845.2 177.7,127.88 v1(177.9,128.07) 179.32,129.5 179.32,129.93 179.83,130.43 XDPC1.6
  BOTTOM w0.102: v1(177.9,128.07) 178.59,128.76 178.59,132.3 178.18,132.7 178.04,132.7 177.4,133.34 170.69,133.34 167.92,136.11 167.92,136.77 v2(156.18,148.51) 155.34,149.35 155.14,149.35 151.28,153.21 135.58,153.21 132.56,150.19 132.37,150.19 v1(132.14,149.96)
HSW_PCUSTB_0_DP: length 70.5
  TOP w0.102: R844.2 177.7,126.86 v1(177.9,127.06) 179.55,128.71 179.55,129.6 179.89,129.93 XDPC1.4 ; v1(131.23,149.96) U27.Y36
  BOTTOM w0.102: v1(131.23,149.96) 131.69,150.41 132.46,150.41 135.49,153.44 151.37,153.44 155.08,149.73 155.71,149.73 168.15,137.3 168.15,136.66 171.24,133.57 177.49,133.57 178.14,132.93 178.28,132.93 178.89,132.32 v2(178.89,128.05) v1(177.9,127.06)
HSW_PCUSTB_1_DN: length 61.1
  TOP w0.102: XDPC1.24 178.54,134.93 177.64,134.03 R849.2 176.62,133.56 175.84,133.56 v1(175.36,134.04) ; U27.W36 v1(131.23,150.87)
  BOTTOM w0.102: v1(131.23,150.87) 131.5,150.87 132.15,151.53 133.25,151.53 135.39,153.67 151.47,153.67 155.15,149.99 155.78,149.99 168.38,137.39 168.38,136.76 170.82,134.32 v2(173.56,134.32) 175.09,134.32 v1(175.36,134.04)
HSW_PCUSTB_1_DP: length 62.1
  TOP w0.102: R848.2 177.94,132.98 v1(178.33,133.38) 179.39,134.43 XDPC1.22 ; U27.V36 v1(131.23,151.79)
  BOTTOM w0.102: v1(178.33,133.38) 177.12,134.59 v2(176.58,134.59) 174.7,134.59 172.24,137.06 169.58,137.06 156.15,150.5 155.29,150.5 151.65,154.13 135.2,154.13 133.18,152.1 131.78,152.1 131.47,151.79 v1(131.23,151.79)
HSW_STRAP_13: length 252
  TOP w0.102: v1(179.25,123.04) 179.58,123.37 186.67,123.37 v1(186.75,123.45) ; R843.1 174.62,136.14 174.26,135.78 174.26,128.05 175.91,126.41 178.18,126.41 178.45,126.67 v1(178.67,126.67) ; v1(62.48,9.14) 62.56,9.22 62.56,10.82 60.4,12.98 54.25,12.98 52.41,14.82 52.41,17.88 QF2.3
  BOTTOM w0.102: v1(178.67,126.67) v2(178.67,123.83) 178.67,123.62 v1(179.25,123.04) ; v1(62.48,9.14) 80.66,9.14 81.55,10.02 85.91,10.02 86.11,10.21 93.11,10.21 93.68,9.64 96.52,9.64 96.97,9.18 104.64,9.18 105.08,8.75 110.54,8.75 110.88,9.09 127.37,9.09 135.62,17.35 138.06,17.35 153.34,32.63 153.34,44.28 158.57,49.52 158.57,51.19 165.77,58.39 165.77,58.54 165.77,58.54 165.77,58.83 174.15,67.21 176.01,67.21 177.11,68.31 177.11,68.63 179.24,70.76 179.9,70.76 181.28,72.15 181.28,83.23 186.53,88.48 186.53,107.08 186.16,107.45 186.16,117.78 187.5,119.13 187.5,122.7 v1(186.75,123.45)
HSW_XDP_MBP_0: length 76.7
  TOP w0.102: U27.G39 v1(133.06,161.84) ; v1(183.91,134.56) 184.4,134.56 184.52,134.43 XDPC1.21
  BOTTOM w0.102: v1(133.06,161.84) 135.13,161.84 136.39,160.58 156.67,160.58 157.77,159.49 159.44,159.49 161.21,157.71 v2(161.21,148.84) 161.21,148.21 167.64,141.79 174.27,141.79 174.37,141.89 183.43,141.89 184.96,140.36 184.96,135.24 184.29,134.57 183.93,134.57 v1(183.91,134.56)
HSW_XDP_MBP_1: length 70.8
  TOP w0.102: XDPC1.23 184.68,134.93 184.68,134.98 v1(184.37,135.29) ; U27.J39 v1(133.97,160.02)
  BOTTOM w0.102: v1(133.97,160.02) 134.88,160.02 134.89,160.03 135.79,160.03 136.21,159.61 154.83,159.61 155.98,158.46 155.98,157.44 157.63,155.79 v2(157.63,154.61) 157.63,154.46 157.94,154.15 157.94,151 167.39,141.56 174.36,141.56 174.42,141.61 176.53,141.61 177.29,140.85 184.15,140.85 184.73,140.27 184.73,135.66 v1(184.37,135.29)
HWM_REF: length 6
  TOP w0.203: 105.77,17.3 105.27,16.8 U61.47
  TOP w0.508: C493.1 108.84,16.76 v2(108.55,17.05) 108.13,17.48 105.94,17.48 105.77,17.3
IGC_EN_N: length 30.9
  TOP w0.102: R398.1 R71.1 48.09,19.41 47.37,19.41 47.32,19.35 v2(45.59,19.35) 45.09,19.35 42.58,21.87 38.48,21.87 37.65,22.71 35.65,22.71 34.29,24.06 34.29,24.74 34.32,24.76 34.32,25.02 34.29,25.05 34.29,25.75 34.32,25.78 34.32,33 34.29,33.03 34.29,34.39 33.69,34.99 33.69,36.42 33.55,36.56 33.55,36.98 U29.AC40
IMAX: length 179.7
  TOP w0.203: 176.74,158.25 U52.11
  TOP w0.267: R225.1 v1(174.6,155.77) 174.6,156.11 176.74,158.25
  TOP w0.305: v1(84.25,201.16) 84.25,199.92 85.37,198.8 U18.2
  BOTTOM w0.305: v1(174.6,155.77) 175.06,156.22 176.14,156.22 176.83,155.52 178.13,155.52 182.78,150.88 186.31,150.88 193.28,157.85 193.28,181.65 187.68,187.25 187.68,188.06 181.05,194.69 177.5,194.69 176.53,193.73 157.6,193.73 156,195.32 154.57,195.32 149.22,200.66 143.38,200.66 137.59,206.45 116.08,206.45 112.48,202.85 84.73,202.85 v2(84.17,202.3) 84.17,201.23 v1(84.25,201.16)
INIT_3V: length 13.7
  TOP w0.102: R638.2 29.25,12.88 v2(30.71,12.88) 30.71,12.09 28.22,9.6 28.22,6.58 26.91,5.27 LPC1.2
IO_SMI_N: length 77.6
  TOP w0.102: U29.P37 37.78,37.98 38.13,37.63 38.13,37.03 38.17,37 38.17,36.99 arc(38.21,36.92) 38.23,36.83 38.23,36.45 38.21,36.4 38.19,36.38 38.19,34.87 40.65,32.41 41.02,32.41 42.07,31.36 v1(42.2,31.36) ; v1(64.62,19.84) 64.58,19.84 57.81,26.61 R564.1 54.89,26.61 R580.1 54.66,26.38 54.58,26.38 54.17,25.97 v1(54.05,25.97) ; v1(95.58,18.08) 95.89,18.08 96.55,17.42 96.55,15.9 96.77,15.68 96.97,15.68 97.43,15.21 97.43,14.66 97.18,14.4 U61.8
  BOTTOM w0.102: v1(42.2,31.36) 42.65,30.91 42.65,28.98 46.13,25.5 53.58,25.5 v1(54.05,25.97) ; v1(95.58,18.08) 95.55,18.06 92.98,18.06 92.02,19.02 v2(90.55,19.02) 90.32,19.25 85.08,19.25 84.09,20.24 80.98,20.24 79.91,21.31 66.09,21.31 v1(64.62,19.84)
JDREF: length 3.3
  TOP w0.305: v2(21.77,236.47) 22.51,235.73 U2.40
  TOP w0.508: R12.1 21.27,237.52 21.27,236.97 v2(21.77,236.47)
KBRST_N: length 82
  TOP w0.102: U61.20 98.07,10.94 100.51,13.38 100.51,15.77 100.25,16.03 98.25,16.03 v1(97.13,17.14) ; R609.1 49.11,28.64 49.56,28.19 50.62,28.19 v1(50.72,28.29) 50.85,28.42 51.56,28.42 52.03,27.96 54.72,27.96 55.44,28.68 55.95,28.68 56.5,28.13 58.36,28.13 61.7,24.78 61.7,24.76 63.17,23.29 63.32,23.29 65.61,21 v1(65.61,19.89) ; v3(40.38,38.79) 39.97,39.2 U29.K36
  BOTTOM w0.102: v1(65.61,19.89) 66.55,20.83 79.71,20.83 80.78,19.76 83.89,19.76 84.88,18.77 90.05,18.77 90.33,18.49 91.41,18.49 v2(92.02,17.89) 92.33,17.58 96.7,17.58 v1(97.13,17.14) ; v1(50.72,28.29) 50.69,28.29 46.65,32.32 46.08,32.32 43.26,35.15 43.23,35.15 41.64,36.74 41.64,37.8 40.65,38.79 v3(40.38,38.79)
KCLK: length 6.9
  TOP w0.102: U61.39 105.02,13.6 105.64,12.98 105.64,12.61 105.95,12.29 106.32,12.29 v2(107.31,11.3) 108.2,10.42 RN7.3
KDAT: length 6.9
  TOP w0.102: RN7.4 v2(108.33,9.77) 108.08,9.77 105.21,12.64 105.21,12.88 104.9,13.2 U61.38
L_AD0: length 240.7
  TOP w0.102: RN40.3 105.52,59.59 v1(105.38,59.46) ; v1(97.79,15.54) 97.92,15.42 97.92,14.27 97,13.36 97,11.76 96.44,11.2 U61.16 87.02,2.59 55.55,2.59 54.86,3.28 54.46,3.28 49.24,3.28 39.06,13.46 32.69,13.46 28.65,9.43 28.65,9.37 28.52,9.24 28.52,6.32 26.66,4.46 21.66,4.46 21.19,4.93 21.19,6.46 LPC1.5 20.32,8.95 13.15,8.95 12.21,8 11.4,8 11.13,8.28 9.63,8.28 8.97,7.62 8.97,6.63 v1(9.28,6.32) ; v1(98.23,40.84) 98.23,33.09 99.11,32.21 99.11,29.82 97.75,28.45 97.75,28.19 95.95,26.39 94.59,26.39 90.15,21.95 88.73,21.95 84.63,17.86 v1(83.01,17.86) ; RN58.4 11.03,50.31 v1(10.16,51.18) ; U22.26 U23.26 102.38,55.62 102.69,55.93 104.42,55.93 v1(104.65,55.7)
  BOTTOM w0.102: v1(97.79,15.54) 97.66,15.67 96.52,15.67 96.02,16.17 90.53,16.17 90.29,16.41 89.12,16.41 88.48,17.04 83.82,17.04 v1(83.01,17.86) ; v1(9.28,6.32) 9.02,6.58 7.98,6.58 3.48,11.08 3.48,39.82 3.63,39.98 3.63,39.98 6.4,42.75 6.4,44.78 v2(7.37,45.75) 8.7,47.08 8.7,48.56 10.16,50.02 v1(10.16,51.18) ; v1(105.38,59.46) 105.38,58.21 104.62,57.44 104.62,55.73 v1(104.65,55.7) 104.57,55.63 104.57,45.96 99.45,40.84 v1(98.23,40.84)
L_AD0_R: length 20.9
  TOP w0.102: v1(11.86,47.88) 11.38,47.88 11.03,48.23 RN58.1 ; v3(28.13,44.99) 28.13,45.21 U29.AN24
  BOTTOM w0.102: v3(28.13,44.99) 28.12,44.99 26.89,46.22 23.61,46.22 22.95,45.55 22.34,45.55 21.36,46.53 20.73,46.53 20.31,46.11 16.65,46.11 15.06,47.7 14.12,47.7 13.46,48.36 v2(12.7,48.36) 12.34,48.36 v1(11.86,47.88)
L_AD1: length 244.2
  TOP w0.102: v1(98.65,15.49) 98.65,13.02 96.87,11.24 U61.17 95.98,9.07 94.54,9.07 87.48,2.01 49.15,2.01 38.66,12.5 33.27,12.5 29.74,8.97 29.74,5.71 27.22,3.19 20.93,3.19 19.19,4.93 19.19,6.46 LPC1.7 18.6,8.67 13.27,8.67 12.18,7.58 10.4,7.58 v1(10.19,7.8) ; RN57.4 8.26,44.19 v1(8.13,44.05) ; RN41.3 107.55,59.59 v1(107.42,59.46) ; v1(124.13,16.89) 124.13,18.52 124.41,18.8 124.41,29.65 121.65,32.41 118.93,32.41 108.28,43.06 108.28,54.39 106.15,56.52 v1(105.36,56.52) 101.04,56.52 100.43,55.91 U23.23 U22.23
  BOTTOM w0.102: v1(98.65,15.49) 98.74,15.49 100.62,17.37 103.6,17.37 103.91,17.06 106.09,14.88 108.25,14.88 110.1,16.74 114.53,16.74 114.9,17.11 v2(122.99,17.11) 123.91,17.11 v1(124.13,16.89) ; v1(8.13,44.05) 7.52,43.44 7.52,42.68 4.32,39.48 4.32,11.43 7.52,8.23 9.75,8.23 v1(10.19,7.8) ; v1(107.42,59.46) 107.42,59.18 105.36,57.12 v1(105.36,56.52)
L_AD1_R: length 21.5
  TOP w0.102: v3(26.96,43.77) 26.96,44.26 U29.AP26 ; RN57.1 9,42.41 9.25,42.16 10.13,42.16 v1(10.57,42.6)
  BOTTOM w0.102: v1(10.57,42.6) 10.67,42.49 11.63,42.49 12.12,42.98 12.12,43.88 12.71,44.48 16.51,44.48 16.8,44.77 19.81,44.77 20.43,44.15 21.95,44.15 22.28,43.81 v2(24.97,43.81) 26.49,43.81 26.53,43.77 v3(26.96,43.77)
L_AD2: length 258.3
  TOP w0.102: v1(99.39,15.01) 99.39,13.34 97.27,11.22 U61.18 97.27,9.24 96.82,8.79 94.65,8.79 87.59,1.73 49.03,1.73 38.54,12.22 33.38,12.22 30.02,8.86 30.02,8.63 30.02,5.59 27.34,2.91 20.82,2.91 18.88,4.84 18.88,6.39 LPC1.9 16.88,8.39 13.38,8.39 12.21,7.21 v1(9.42,7.21) ; RN58.3 11.68,50.8 v1(10.95,51.53) ; v1(124.99,16.83) 124.99,16.87 124.79,17.07 124.79,29.67 121.74,32.72 119.02,32.72 108.56,43.18 108.56,57.18 v1(106.3,59.44) 106.17,59.57 RN40.4 ; v1(102.44,58.01) 102.11,58.01 101.85,57.76 99.91,57.76 98.48,56.33 U23.20 U22.20
  BOTTOM w0.102: v1(102.44,58.01) 103.25,58.01 105.18,59.94 105.79,59.94 v1(106.3,59.44) ; v1(9.42,7.21) 9.07,6.86 8.1,6.86 3.76,11.2 3.76,39.71 6.68,42.63 6.68,44.25 9.23,46.81 v2(9.23,47.32) 9.23,48.55 10.95,50.27 v1(10.95,51.53) ; v1(99.39,15.01) 99.39,15.72 100.76,17.09 103.48,17.09 105.97,14.61 108.37,14.61 110.22,16.46 114.81,16.46 115.18,16.83 120.33,16.83 120.77,16.38 124.55,16.38 v1(124.99,16.83)
L_AD2_R: length 21
  TOP w0.102: v1(13.49,48.9) 12.5,48.9 12.41,48.8 RN58.2 ; v3(29.59,45) 29.97,45.38 U29.AJ24
  BOTTOM w0.102: v3(29.59,45) 29.17,45.43 27.97,45.43 26.98,46.42 23.53,46.42 22.87,45.76 22.42,45.76 21.45,46.74 20.64,46.74 20.3,46.39 16.77,46.39 v2(14.72,48.44) 14.26,48.9 v1(13.49,48.9)
L_AD3: length 254.6
  TOP w0.102: RN41.4 108.2,59.57 v1(108.33,59.44) 108.33,57.86 108.84,57.36 108.84,43.29 119.11,33.02 121.83,33.02 125.25,29.61 v1(125.25,17.65) ; v1(8.01,44.91) 9.4,44.91 9.65,44.66 RN57.3 ; v1(10.21,6.73) 12.12,6.73 13.5,8.11 15.16,8.11 LPC1.11 17.16,6.11 17.16,4.96 19.49,2.63 27.45,2.63 30.3,5.48 30.3,8.74 33.5,11.94 38.43,11.94 48.92,1.45 87.71,1.45 94.77,8.51 96.94,8.51 97.67,9.25 U61.19 97.67,11.14 100.13,13.59 100.13,15.49 v1(100.05,15.57) ; U22.17 U23.17 96.53,55.89 98.68,58.04 101.57,58.04 102.2,58.67 v1(103.07,58.67)
  BOTTOM w0.102: v1(125.25,17.65) 125.55,17.35 125.55,16.69 124.92,16.05 120.71,16.05 120.21,16.55 115.4,16.55 115.01,16.15 110.31,16.15 108.48,14.33 105.86,14.33 103.37,16.81 100.88,16.81 100.05,15.99 v1(100.05,15.57) ; v1(103.07,58.67) 104.72,60.33 107.44,60.33 v1(108.33,59.44) ; v1(10.21,6.73) 10.21,7.11 9.63,7.69 v2(8.53,7.69) 7.66,7.69 4.04,11.31 4.04,39.59 7.21,42.77 7.21,44.11 v1(8.01,44.91)
L_AD3_R: length 21.9
  TOP w0.102: v3(27.76,43.87) 27.84,43.94 U29.AN26 ; RN57.2 10.04,42.99 10.31,43.26 10.31,43.6 v1(10.55,43.84)
  BOTTOM w0.102: v1(10.55,43.84) 10.55,43.36 11.14,42.77 11.52,42.77 11.84,43.09 11.84,43.99 12.62,44.78 16.41,44.78 16.68,45.05 19.82,45.05 20.52,44.35 v2(22.61,44.35) 27,44.35 27.48,43.87 v3(27.76,43.87)
L_BACKFEED_CUT: length 5.3
  TOP w0.165: R399.2 184.71,117.86 v2(185.93,117.86) Q74.B 188.58,118.77 Q40.6
L_FRAME_N: length 212.7
  TOP w0.102: R652.1 7.77,45.85 7.54,45.62 7.54,43.74 v1(8.13,43.15) 8.13,39.43 R439.1 ; v1(104.37,57.84) 104.11,57.84 103.33,57.05 100.41,57.05 99.78,56.42 U23.22 U22.22 ; v1(92.68,9.75) 93.65,10.72 93.65,11.46 94.14,11.94 94.59,11.94 94.93,11.6 U61.15 ; v1(82.96,8.95) 82.96,9.19 80.72,11.43 80.72,18.12 86.16,23.55 86.16,25.28 87.22,26.35 87.22,32.23 88.24,33.25 88.24,34.04 87.02,35.26 v1(87.02,41.61)
  BOTTOM w0.102: v1(87.02,41.61) 93.8,41.61 101.07,48.87 101.07,54.53 v1(104.37,57.84) ; v1(8.13,43.15) 8.13,42.89 4.6,39.36 4.6,11.54 7.07,9.07 12.2,9.07 LPC1.13 14.83,8.1 24.97,8.1 25.31,8.44 27.74,8.44 32.46,13.16 32.76,13.16 33.31,13.71 39.22,13.71 42.35,10.58 59.17,10.58 61.07,8.68 80.6,8.68 80.87,8.95 v2(81.99,8.95) v1(82.96,8.95) 83.75,9.74 92.67,9.74 v1(92.68,9.75)
L_FRAME_N_R: length 21.2
  TOP w0.102: U29.AP24 27.36,45.21 27.36,45.15 v3(27.48,45.03) ; R652.2 9.33,45.59 10.24,44.68 10.55,44.68 v1(10.56,44.7)
  BOTTOM w0.102: v1(10.56,44.7) 11.31,45.45 v2(11.4,45.45) 12.73,46.79 13.02,46.79 13.22,46.99 15.38,46.99 16.53,45.83 20.56,45.83 20.75,45.64 21.96,45.64 22.27,45.34 26.07,45.34 26.07,45.34 27.02,45.34 27.32,45.03 v3(27.48,45.03)
L_PWRDWN_N: length 4.3
  TOP w0.102: U23.28 U22.28 103.68,53.42 104.18,52.92 R470.2 106.29,52.92 v2(106.34,52.97)
LAN_1P05_OUT:
  vias: v5(165.43,204.52)
LAN_CONN_CVT: length 11.9
  TOP w0.508: UC103.1 162.62,214.95 UC104.1 161.67,221.73 RJ45.R1
LAN_DISABLE_N: length 384.7
  TOP w0.102: v1(82.04,25.4) 81.13,25.4 78.84,23.11 78.2,23.11 72.5,17.42 72.5,16.58 62.45,6.53 51.94,6.53 51,7.47 51,8.46 50.72,8.74 49.46,8.74 40.72,17.48 33.45,17.48 32.9,18.03 32.25,18.03 29.29,20.99 29.29,21.82 28.54,22.56 28.54,26.76 RN42.3 28.07,27.63 27.13,28.57 27.13,28.58 26.68,29.03 26.68,29.76 27,30.09 27,30.67 27.15,30.83 27.15,32.47 28.93,34.24 28.93,36.44 28.93,36.45 U29.AL40 ; v1(165.1,51.31) 164.16,52.25 161.75,52.25 160.99,51.48 150.91,51.48 150.82,51.57 150.7,51.57 v1(148.3,53.97) ; R107.1 194.84,218.85 193.27,217.27 191.11,217.27 186.82,212.98 186.82,206.07 v1(187.96,204.93)
  BOTTOM w0.102: v1(82.04,25.4) 82.55,25.4 82.93,25.02 92.79,25.02 94.28,26.52 100.48,26.52 101.12,27.15 103.12,27.15 104.38,25.9 133.97,25.9 144.91,36.83 144.91,39.3 146.49,40.89 146.49,52.17 v1(148.3,53.97) ; v1(187.96,204.93) 189.15,204.93 193.73,200.35 v2(193.73,199.77) 193.73,197.49 194.52,196.7 194.59,196.7 196.33,194.96 196.33,156.59 194.97,155.23 194.97,150.19 195.25,149.91 195.25,125.63 190.7,121.09 190.7,117.88 190.11,117.28 190.11,108.03 190.32,107.82 190.32,103 190.7,102.61 190.7,99.29 190.24,98.83 190.24,87.63 184.96,82.35 184.96,75.9 185.32,75.53 185.32,71.49 177.82,63.98 175.57,63.98 169,57.41 169,57 165.1,53.1 v1(165.1,51.31)
LAN_MDI0_DN: length 11.1
  TOP w0.102: TR14.4 178.43,210.69 178.7,210.41 178.7,210.18 178.58,210.05 178.38,210.05 178.28,209.95 178.28,209.34 178.38,209.24 178.58,209.24 178.7,209.11 178.7,208.84 177.12,207.26 ; U12.2 172.68,205.73 172.82,205.59 175.45,205.59 177.12,207.26 ; 177.12,207.26 v5(176.86,207.52)
LAN_MDI0_DN_C: length 44.5
  TOP w0.102: RJ45.R3 166.95,223.22 166.75,223.01 166.12,223.01 165.89,223.24 165.89,227.45 166.24,227.8 167.25,227.8 167.43,227.99 174.16,227.99 175.08,228.91 175.08,229.51 176.12,230.56 178.09,230.56 181.15,227.49 181.15,222.49 179.88,221.22 179.88,218.18 178.74,217.03 178.74,216.65 178.49,216.39 178.49,215.6 178.61,215.47 180.27,215.47 180.52,215.22 180.52,214.63 179.95,214.06 U6.4 178.56,213.48 178.56,212.75 178.43,212.61 TR14.3
LAN_MDI0_DP: length 11.1
  TOP w0.102: 174.96,205.18 175.62,205.18 179.11,208.67 TR14.1 ; 174.96,205.18 172.65,205.18 172.5,205.33 U12.1 ; 174.96,205.18 v5(174.96,204.83)
LAN_MDI0_DP_C: length 44.6
  TOP w0.102: TR14.2 179.11,212.61 178.97,212.75 178.97,213.31 179.28,213.61 180.08,213.61 180.92,214.46 180.92,215.39 180.35,215.96 U6.6 179.15,216.87 180.29,218.01 180.29,221.06 181.56,222.33 181.56,227.66 178.26,230.96 175.96,230.96 174.68,229.68 174.68,229.08 173.99,228.4 167.26,228.4 167.08,228.21 166.07,228.21 165.48,227.62 165.48,223.07 166.04,222.51 166.04,222.28 RJ45.R2
LAN_MDI1_DN: length 8.2
  TOP w0.102: U12.5 172.03,206.93 172.03,206.94 174.61,206.94 175.52,207.84 ; v5(175.26,208.1) 175.52,207.84 ; 175.52,207.84 176.39,208.72 176.39,209.14 176.29,209.25 176.12,209.25 176.02,209.35 176.02,209.96 176.12,210.06 176.29,210.06 176.39,210.16 176.39,210.43 176.12,210.7 TR13.4
LAN_MDI1_DN_C: length 33.4
  TOP w0.102: RJ45.R5 169.49,223.55 169.01,223.06 168.48,223.06 168.28,223.27 168.28,225.78 169.24,226.75 175.36,226.75 177.14,224.97 177.14,223.76 178.46,222.44 178.46,218.68 177.81,218.03 176.36,218.03 175.69,217.36 175.69,215.7 175.87,215.52 177.51,215.52 177.83,215.2 177.83,214.53 177.36,214.06 U6.3 176.45,213.55 176.12,213.22 TR13.3
LAN_MDI1_DP: length 8.3
  TOP w0.102: 176.8,209.17 v5(177.19,209.17) ; 176.8,209.17 176.8,208.55 174.84,206.59 172.6,206.59 172.54,206.53 U12.4 ; 176.8,209.17 TR13.1
LAN_MDI1_DP_C: length 33.4
  TOP w0.102: TR13.2 176.8,212.53 176.52,212.81 176.52,213.05 177.13,213.65 177.52,213.65 178.23,214.36 178.23,215.37 177.64,215.96 U6.1 176.45,216.46 176.1,216.81 176.1,217.2 176.53,217.63 177.98,217.63 178.87,218.52 178.87,222.61 177.55,223.93 177.55,225.14 175.53,227.15 169.07,227.15 167.87,225.95 167.87,223.1 168.22,222.74 RJ45.R4
LAN_MDI2_DN: length 5.9
  TOP w0.102: TR12.4 173.8,210.53 174.32,210.02 174.32,209.85 174.02,209.55 174.02,209.3 174.16,209.15 174.38,209.15 174.5,209.03 174.5,208.61 v1(174.17,208.28) 174.22,208.23 174.22,208.04 173.91,207.74 172.55,207.74 172.54,207.73 U12.7
LAN_MDI2_DN_C: length 27.9
  TOP w0.102: TR12.3 173.8,212.62 173.94,212.75 173.94,213.17 174.37,213.6 U9.4 175.04,214.06 175.16,214.17 175.16,215.24 174.91,215.49 173.67,215.49 173.2,215.95 173.2,219.5 174.38,220.68 176.26,220.68 176.83,221.25 176.83,222.22 175.82,223.24 175.82,224.56 174.85,225.53 171.37,225.53 170.79,224.94 170.79,223.16 171.04,222.91 171.33,222.91 172.03,223.62 RJ45.R7
LAN_MDI2_DP: length 5.9
  TOP w0.102: U12.6 174.08,207.33 174.7,207.95 174.7,209.39 v1(174.74,209.43) 174.74,210.17 174.49,210.43 TR12.1
LAN_MDI2_DP_C: length 27.9
  TOP w0.102: RJ45.R6 170.76,222.61 170.38,223 170.38,225.11 171.21,225.93 175.02,225.93 176.23,224.73 176.23,223.41 177.24,222.39 177.24,221.08 176.43,220.27 174.55,220.27 173.61,219.33 173.61,216.12 173.76,215.96 U9.6 175.01,215.96 175.56,215.41 175.56,214 175.07,213.51 174.85,213.51 174.35,213 174.35,212.78 174.49,212.64 TR12.2
LAN_MDI3_DN: length 2.4
  TOP w0.102: TR11.4 171.21,210.33 v1(170.86,209.97) 171.12,209.71 171.12,209.59 170.95,209.43 U12.10
LAN_MDI3_DN_C: length 16.8
  TOP w0.102: RJ45.R9 173.63,223.52 173.08,223.52 172.03,222.47 172.03,220.54 170.43,218.94 170.43,216.03 170.94,215.52 172.2,215.52 172.49,215.22 172.49,214.27 172.28,214.06 U9.3 171.68,213.45 171.21,212.98 TR11.3
LAN_MDI3_DP: length 2.4
  TOP w0.102: TR11.1 171.89,210.16 v1(172.08,209.98) 171.36,209.26 171.36,208.82 U12.9
LAN_MDI3_DP_C: length 16.9
  TOP w0.102: RJ45.R8 174.05,221.93 174.19,222.07 174.19,223.01 174.09,223.11 173.25,223.11 172.44,222.3 172.44,220.37 170.84,218.77 170.84,216.2 171.07,215.96 U9.1 172.33,215.96 172.9,215.39 172.9,214.1 171.89,213.09 TR11.2
LAN_RSET: length 4.2
  TOP w0.203: U12.31 170.95,204.04 171.06,203.93
  TOP w0.254: R172.2 173.48,203.05 v2(173.22,203.31) 172.73,203.8 171.19,203.8 171.06,203.93
LAN_XTALI: length 15.9
  TOP w0.102: X1.1 180.16,202.21 178.64,202.21 178.1,201.68 R162.2 177.23,201.99 C112.1 176.36,202.16 176.02,202.16 175.82,201.96 175.82,201.27 174.59,200.04 171.56,200.04 v5(171.32,200.28) 169.88,201.72 169.88,204 169.75,204.13 U12.28
LAN_XTALO: length 16.1
  TOP w0.102: X1.2 180.34,205.99 R162.1 176.72,203.2 C97.1 176.29,202.77 175.77,202.77 175.21,202.21 175.21,201.57 174.28,200.65 171.88,200.65 170.51,202.01 v5(170.51,202.29) 170.51,202.82 170.15,203.17 U12.29
LANCLK_REQ_N: length 409.6
  TOP w0.102: v1(183.59,198.63) 183.08,198.12 181.74,198.12 180.92,198.93 165.38,198.93 164.54,199.77 158.95,199.77 155.03,203.69 v1(155.03,204.44) ; v1(169.11,215.29) 169.06,215.24 R132.2 ; v1(79.3,11.63) 79.5,11.43 79.5,9.32 82.42,6.4 83.92,6.4 v1(84.35,5.97) ; v1(63.27,11.16) 63.03,11.16 60.73,13.46 54.78,13.46 53.06,15.18 53.06,17.32 53.09,17.35 53.09,19.47 52.67,19.89 45.24,19.89 42.77,22.36 38.67,22.36 37.85,23.19 35.93,23.19 R571.1 35.62,25.27 R573.1 35.62,26.5 36.37,27.25 36.37,30.01 35.38,31 35.38,32.22 34.49,33.11 34.49,34.49 33.89,35.09 33.89,36.5 33.78,36.61 33.78,37.25 U29.AA39
  BOTTOM w0.102: v1(63.27,11.16) 63.59,11.48 67.19,11.48 67.34,11.63 v1(79.3,11.63) ; v1(84.35,5.97) 84.56,5.77 86.79,5.77 86.89,5.87 93.32,5.87 93.55,5.64 97.25,5.64 97.81,5.08 101.45,5.08 101.8,5.44 114.05,5.44 115.22,6.6 129.63,6.6 137.13,14.11 139.22,14.11 164.13,39.03 164.13,50.12 164.57,50.55 164.57,53.3 168.52,57.25 168.52,57.61 175.37,64.47 177.62,64.47 184.84,71.69 184.84,75.33 184.47,75.7 184.47,82.55 189.76,87.83 189.76,99.03 190.22,99.49 190.22,102.41 189.83,102.8 189.83,107.62 189.63,107.83 189.63,117.48 190.22,118.08 190.22,121.29 194.77,125.83 194.77,149.71 194.49,149.99 194.49,155.43 195.85,156.79 195.85,194.75 194.38,196.22 192.24,196.22 191.05,197.41 184.8,197.41 v1(183.59,198.63) ; v1(155.03,204.44) v2(155.81,205.21) 157.25,206.65 161.51,206.65 164.64,209.78 167.26,209.78 169.49,212.01 169.49,214.96 169.16,215.29 v1(169.11,215.29)
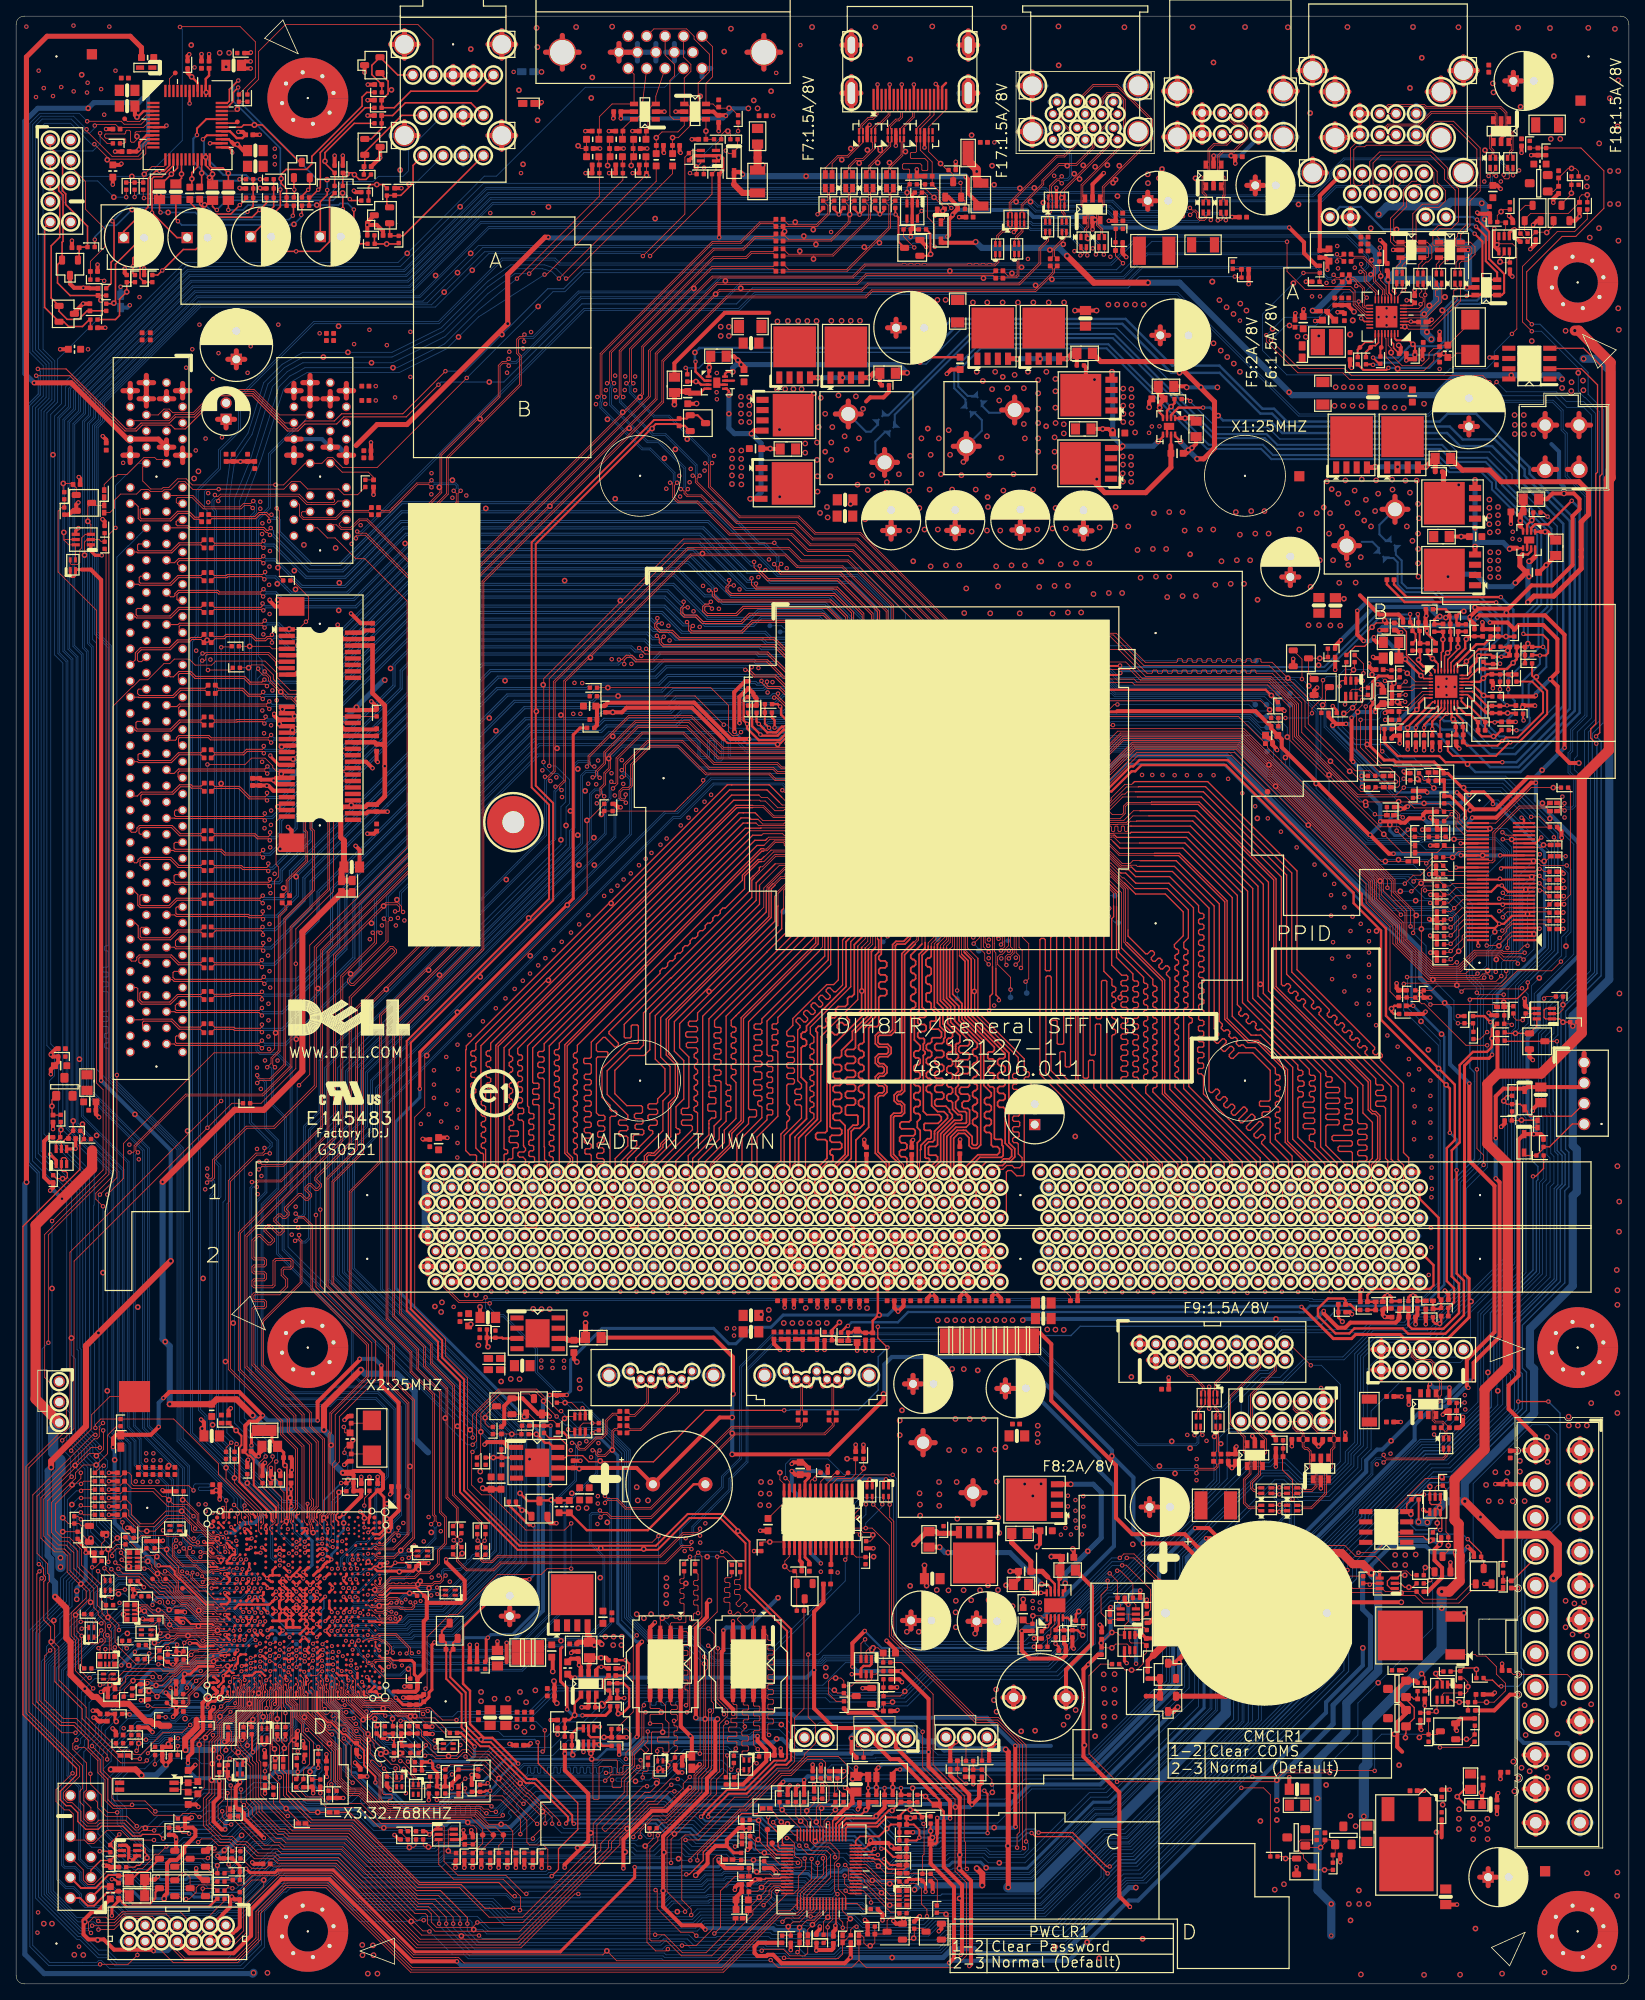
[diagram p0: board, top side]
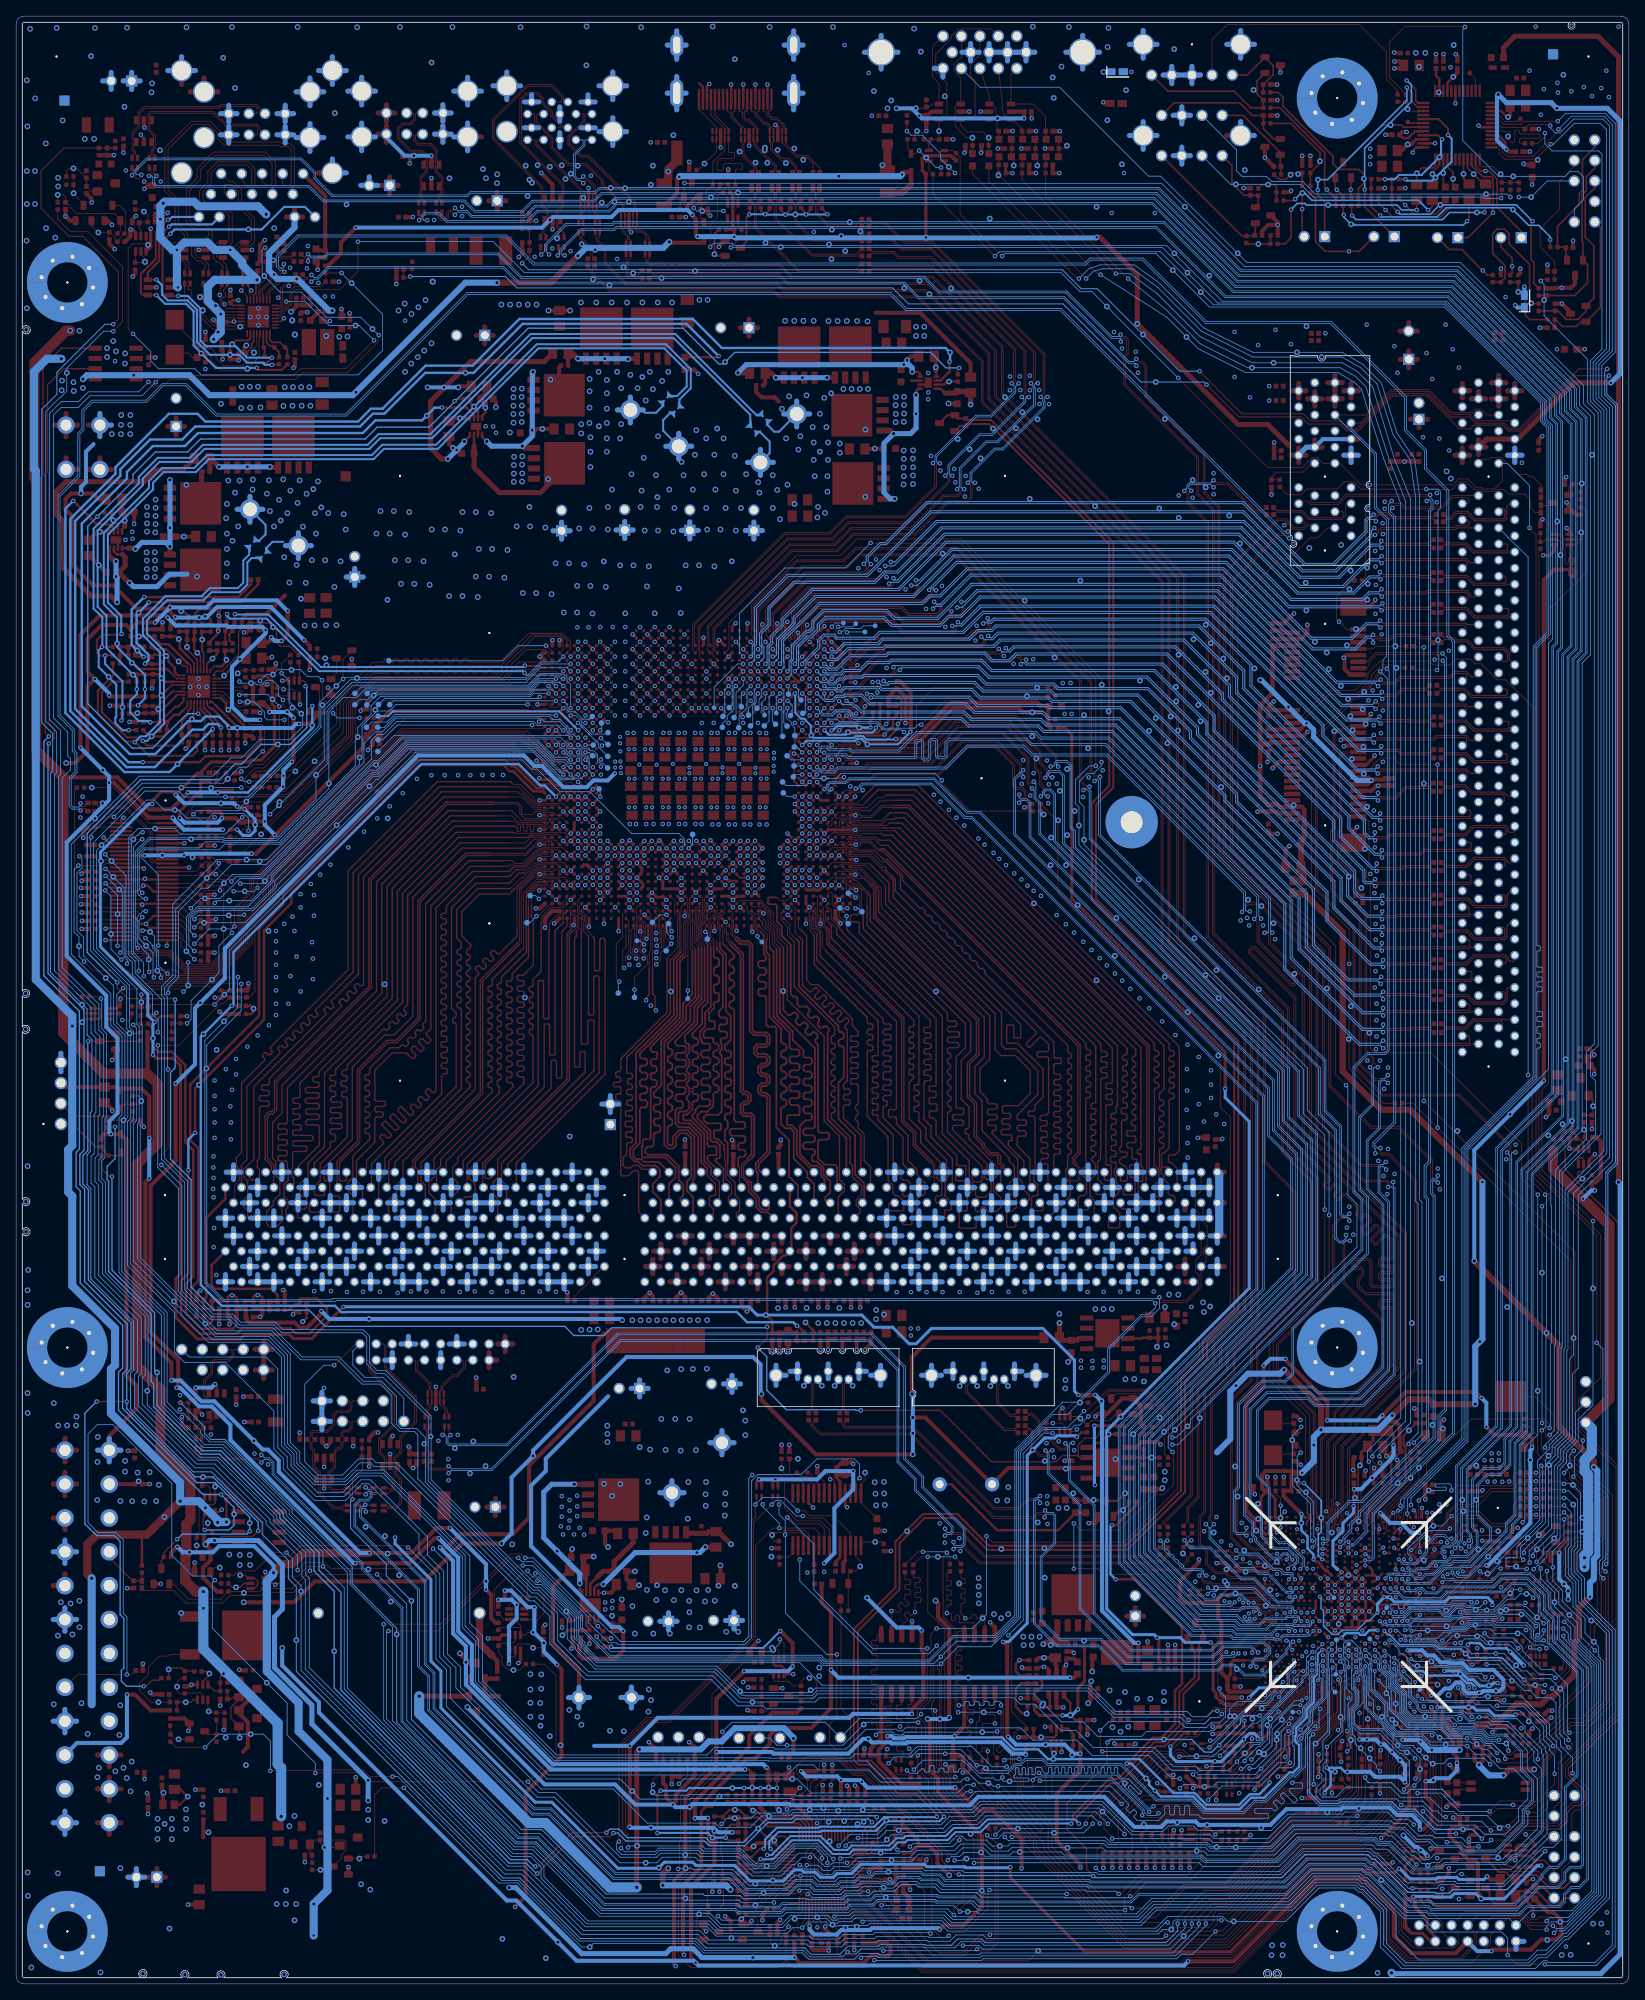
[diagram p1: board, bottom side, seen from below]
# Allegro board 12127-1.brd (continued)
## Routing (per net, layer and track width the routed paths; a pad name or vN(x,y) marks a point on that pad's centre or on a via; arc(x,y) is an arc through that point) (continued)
LANCLK_REQ_U_N: length 5.2
  TOP w0.102: U12.12 170.15,209.35 169.89,209.61 169.89,210.55 169.23,211.22 v2(169.23,211.77) 169.23,212.29 169.06,212.46 R132.1
LANWAKE_N: length 15.2
  TOP w0.102: U29.AU34 25.54,40.12 25.24,40.42 24.84,40.42 24.75,40.33 24.58,40.33 24.38,40.13 22.28,40.13 21.52,39.37 20.44,39.37 19.65,38.58 19.02,38.58 17.98,37.54 16.77,37.54 16.55,37.76 14.67,37.76 v2(14.5,37.59) 14.5,37.59 13.41,36.5 13.41,35.7 R83.1
LATCHED_BACKFEED_CUT: length 132.5
  TOP w0.165: R2237.2 182.24,37.66 183.09,37.66 183.85,36.9 v1(184.18,36.9) ; v1(191.07,116.88) Q74.C 184.68,116.88 R400.2 ; v1(186.28,72.21) v1(190.02,72.21) ; v1(169.98,56.18) 170.68,55.48 174.5,55.48 174.88,55.09 R467.2
  BOTTOM w0.165: v1(169.98,56.18) 169.98,57.27 175.57,62.87 v2(176.81,62.87) 177.82,62.87 186.28,71.33 v1(186.28,72.21) 186.28,75.69 185.75,76.23 185.75,82.02 191.03,87.3 191.03,98.5 191.72,99.19 191.72,102.72 191.11,103.33 191.11,116.84 v1(191.07,116.88) ; v1(190.02,72.21) 191.47,70.76 191.47,57.04 190.03,55.59 187.82,55.59 187.1,54.88 187.1,45.79 186.65,45.33 186.65,39.16 186.96,38.85 186.96,37.55 186.3,36.9 v1(184.18,36.9)
LATCHED_BACKFEED_CUT_R: length 6.3
  TOP w0.102: R465.2 179.54,37.91 180.04,37.41 v2(180.04,36.86) 180.04,36.3 179.74,36 R464.1 179.03,36.07 177.06,36.07 176.86,35.86 Q49.5
LED_L: length 4.1
  TOP w0.254: R549.2 179.6,24.1 v2(178.71,23.22) 179.71,22.23 LED1.2
LINE2_JD: length 55.1
  TOP w0.102: v1(20.32,242.65) 20.36,242.7 27.79,242.7 29.67,240.82 29.67,236.37 27.64,234.34 R8.2
  BOTTOM w0.102: v1(20.32,242.65) 20.6,242.37 20.6,228.57 16.15,224.13 v2(14.35,224.13) 7.9,224.13 7.32,224.71 6.25,224.71 5.61,224.08 5.61,221.26 6.77,220.1 AUDF1.10
LINE2_VREFO: length 2
  TOP w0.203: U2.31 27.28,230.73 TP1.1
LINEIN_JD: length 40.4
  TOP w0.102: v1(15.85,221.44) 15.76,221.53 R79.2
  BOTTOM w0.102: AUDJK1.33 49.38,223.14 v2(48.74,223.14) 40.7,223.14 39.13,221.56 18.09,221.56 17.92,221.4 15.89,221.4 v1(15.85,221.44)
LINK_ACTIVITY: length 48
  TOP w0.267: v1(168.28,201.65) 169.02,200.9 UR112.1 ; v1(179.88,209.31) 180.87,209.31 U11.6 181.52,209.41 181.84,209.73 181.84,216.05 v1(180.87,217.02)
  BOTTOM w0.267: v1(168.28,201.65) 171.38,201.65 172.8,203.07 176.45,203.07 177.15,203.78 177.15,207.75 178.71,209.31 v1(179.88,209.31) ; RJ45.L1 164.18,220.34 166.75,220.34 169.54,217.55 v2(171.2,217.55) 180.34,217.55 v1(180.87,217.02)
LINK_ACTIVITY_N: length 2.9
  TOP w0.203: U12.27 169.35,202.98 TP5.1
  TOP w0.267: UR112.2 169.19,202.82 TP5.1
LPC_DRQ0_N: length 15.6
  TOP w0.102: U29.AK22 29.26,46.44 29.65,46.05 v3(29.65,46.03) ; R524.1 16.62,48.06 17.36,47.32 v1(17.81,47.32)
  BOTTOM w0.102: v1(17.81,47.32) 18.45,46.67 20.18,46.67 20.45,46.94 21.68,46.94 22.33,46.29 v2(22.64,46.29) 22.97,46.62 26.71,46.62 27.06,46.62 28,45.68 29.3,45.68 v3(29.65,46.03)
LPC_DRQ1_N: length 57.9
  TOP w0.102: FVS1.1 11.61,72.82 9.37,70.59 9.37,68.83 6.83,66.29 v1(6.83,66.12) ; v1(12.75,43.87) 12.75,44.53 11.33,45.95 11.33,46.33 11.14,46.52 R534.1 10.59,47.51 10.59,49.45 8.13,51.91 8.13,53.85 6.61,55.37 5.69,55.37 4.88,56.18 4.88,59.52 8.03,62.67 v1(8.03,63.37) ; v3(28.9,43.79) 29.26,44.15 U29.AK26
  BOTTOM w0.102: v1(12.75,43.87) 13.08,44.2 16.64,44.2 16.93,44.49 19.13,44.49 19.17,44.53 19.73,44.53 20.32,43.94 21.87,43.94 22.2,43.61 22.96,43.61 23.71,42.86 26.32,42.86 26.7,43.23 28.09,43.23 28.65,43.79 v3(28.9,43.79) ; v1(6.83,66.12) 7.32,65.63 v2(7.32,64.29) 7.32,64.08 v1(8.03,63.37)
LPC_PME_N: length 142.9
  TOP w0.102: R556.1 104.98,9.27 104.29,9.96 U61.32 102.87,10.84 101.96,11.76 v1(101.96,14.73) ; v3(30.32,41.29) 30.36,41.29 30.8,41.74 U29.AG31
  BOTTOM w0.102: v3(30.32,41.29) 30.3,41.29 29.54,40.54 29.54,38.9 28.97,38.32 28.97,37.29 27.79,36.11 27.79,35.77 27.79,33.89 26.91,33.01 21.82,33.01 21.07,32.27 19.14,32.27 18.85,31.98 17.62,31.98 17.33,31.69 15.32,31.69 12.6,28.96 12.6,26.67 11.34,25.42 11.34,19.25 14.08,16.51 14.58,16.51 15.57,15.52 23.05,15.52 23.51,15.06 24.44,15.06 24.56,14.94 25.66,14.94 26.66,15.94 26.96,15.94 29.38,18.35 29.84,18.35 30.15,18.66 41.27,18.66 43.96,15.98 52.25,15.98 52.73,16.46 64.86,16.46 65.27,16.87 v2(69.62,16.87) 69.65,16.89 76.53,16.89 76.96,16.46 78.99,16.46 79.88,17.35 82.83,17.35 83.62,16.56 88.28,16.56 89.16,15.69 95.59,15.69 96.75,14.53 98.54,14.53 99,14.07 99.91,14.07 100.55,14.71 101.93,14.71 v1(101.96,14.73)
M_CAS_A_N: length 44.3
  TOP w0.102: U27.AU9 104.43,134.32 105.29,134.32 105.69,134.72
  TOP w0.216: 105.69,134.72 106.63,134.72 106.76,134.59 106.76,134 106.63,133.87 105.83,133.87 105.64,133.68 105.64,131.72 105.03,131.11 105.03,129.95 103.94,128.86 103.94,122.73 103.63,122.42 103.32,122.42 103.11,122.21 103.11,121.47 102.83,121.19 101.94,121.19 101.63,120.89 101.63,120.58 101.81,120.4 101.81,120.1 101.5,119.79 101.2,119.79 101.02,119.97 100.72,119.97 100.41,119.66 100.41,119.36 100.59,119.18 100.59,118.88 100.28,118.57 99.98,118.57 99.8,118.75 99.49,118.75 99.19,118.44 99.19,118.14 99.36,117.96 99.36,107.2 97.04,104.88 97.04,101.07 DIMM1.74
M_CAS_B_N: length 61.2
  TOP w0.216: U27.AP16 112.48,136.67 v1(112.05,136.24)
  L3 w0.102: v1(112.05,136.24) 112.05,132.82 111.16,131.93
  L3 w0.191: DIMM2.74 97.04,92.75 96.67,92.75 96.55,92.88 96.55,94.21 96.67,94.34 96.85,94.34 96.98,94.46 96.98,95.41 98.01,96.44 98.01,97.31 98.9,98.2 98.9,99.17 99.99,100.26 99.99,101.43 99.8,101.63 99.42,101.63 99.29,101.75 99.29,102.21 99.42,102.34 100.5,102.34 100.69,102.53 100.69,103.59 103.69,106.59 104.03,106.59 104.22,106.78 104.22,107.12 104.41,107.31 104.79,107.31 104.98,107.12 104.98,106.78 105.17,106.59 105.91,106.59 106.03,106.72 106.03,107.64 105.84,107.83 105.64,107.83 105.45,108.02 105.45,108.4 105.64,108.59 105.84,108.59 106.03,108.79 106.03,109.17 105.84,109.36 105.64,109.36 105.45,109.55 105.45,109.93 105.64,110.12 105.84,110.12 106.03,110.31 106.03,110.69 105.84,110.88 105.64,110.88 105.45,111.07 105.45,111.45 105.64,111.64 105.84,111.64 106.03,111.83 106.03,112.21 105.84,112.4 105.64,112.4 105.45,112.6 105.45,112.98 105.64,113.17 105.84,113.17 106.03,113.36 106.03,113.74 105.84,113.93 105.64,113.93 105.45,114.12 105.45,114.5 105.64,114.69 105.84,114.69 106.03,114.88 106.03,115.26 105.84,115.45 105.64,115.45 105.45,115.64 105.45,116.02 105.64,116.21 105.84,116.21 106.03,116.41 106.03,116.79 105.84,116.98 105.64,116.98 105.45,117.17 105.45,117.55 105.64,117.74 105.84,117.74 106.03,117.93 106.03,118.31 105.84,118.5 105.64,118.5 105.45,118.69 105.45,119.07 105.64,119.26 105.84,119.26 106.03,119.45 106.03,119.83 105.84,120.02 105.64,120.02 105.45,120.22 105.45,120.6 105.64,120.79 105.84,120.79 106.03,120.98 106.03,122.68 111.16,127.81 111.16,131.93
M_DATA_A0: length 81.1
  TOP w0.102: U27.AD38 132.93,146.17 134.7,146.17 134.78,146.1 135.36,146.1 137.69,148.42 139.17,148.42 139.2,148.45
  TOP w0.165: 139.2,148.45 147.5,148.45 158.2,137.75 158.2,125.46 162.86,120.8 162.86,120.57 162.6,120.31 162.6,120.08 162.84,119.84 163.07,119.84 163.33,120.1 163.56,120.1 163.79,119.87 163.79,119.63 163.54,119.37 163.54,119.14 163.77,118.91 164.01,118.91 164.26,119.16 164.5,119.16 164.73,118.93 164.73,118.69 164.48,118.44 164.48,118.2 164.71,117.97 164.94,117.97 165.2,118.22 165.44,118.22 165.67,117.99 165.67,117.76 165.41,117.5 165.41,117.26 165.65,117.03 165.88,117.03 166.14,117.29 166.37,117.29 166.61,117.05 166.61,116.82 166.35,116.56 166.35,116.33 166.59,116.09 166.82,116.09 167.05,116.32 167.28,116.32 167.52,116.09 167.52,115.85 167.29,115.62 167.29,115.39 171.38,111.3 171.38,102.2 172.06,101.52 172.06,98.91 172.04,98.88 DIMM1.3
M_DATA_A1: length 80.5
  TOP w0.102: U27.AD39 133.86,145.84 134.19,145.51 134.72,145.51 134.8,145.59 135.64,145.59 137.23,147.18 139.08,147.18
  TOP w0.165: DIMM1.4 171.04,99.95 170.74,99.65 170.09,99.65 169.82,99.92 169.82,101 170.1,101.28 170.1,102.09 169.82,102.37 169.82,108.59 169.6,108.81 168.77,108.81 168.6,108.98 168.6,109.31 168.77,109.48 169.7,109.48 169.87,109.64 169.87,109.97 169.7,110.14 168.77,110.14 168.6,110.3 168.6,110.64 168.77,110.8 169.39,110.8 169.56,110.97 169.56,111.3 169.39,111.46 168.77,111.46 168.6,111.63 168.6,112.25 159.66,121.19 159.66,121.43 159.9,121.67 159.9,121.9 159.66,122.13 159.43,122.13 159.19,121.9 158.95,121.9 158.72,122.13 158.72,122.36 158.96,122.61 158.96,122.84 158.73,123.08 158.49,123.08 158.25,122.83 158.02,122.83 157.78,123.07 157.78,123.3 158.04,123.56 158.04,123.79 157.8,124.03 157.57,124.03 157.31,123.77 157.08,123.77 156.91,123.94 156.91,137.25 146.98,147.18 139.08,147.18
M_DATA_A2: length 80.7
  TOP w0.102: 138.96,144.2 138.93,144.17 138.17,144.17 137.8,143.8 136.63,143.8 136.6,143.77 136.12,143.77 136.12,143.76 134.72,143.76 134.59,143.64 134.26,143.64 134.04,143.87 134.04,144.02 133.71,144.35 133.7,144.34 132.93,144.34 U27.AF38
  TOP w0.165: 138.96,144.2 145.92,144.2 154.01,136.11 154.01,122.49 164.81,111.69 164.81,110.01 164.97,109.85 165.52,109.85 165.68,109.68 165.68,109.35 165.52,109.19 164.97,109.19 164.81,109.02 164.81,108.69 164.97,108.52 165.54,108.52 165.71,108.36 165.71,108.03 165.54,107.86 164.97,107.86 164.81,107.7 164.81,107.36 164.97,107.2 165.54,107.2 165.71,107.03 165.71,106.7 165.54,106.53 164.81,106.53 164.64,106.37 164.64,106.04 164.81,105.87 165.54,105.87 165.71,105.71 165.71,105.37 165.54,105.21 163.35,105.21 163.19,105.04 163.19,104.71 163.35,104.55 165.54,104.55 165.71,104.38 165.71,104.05 165.54,103.88 164.1,103.88 163.94,103.72 163.94,103.39 164.1,103.22 165.54,103.22 165.71,103.06 165.71,101.16 165.79,101.08 165.79,100.16 165.57,99.95 165.57,99.22 DIMM1.9
M_DATA_A3: length 79.9
  TOP w0.102: 138.25,143.56 137.97,143.56 137.86,143.46 137.86,142.99 137.76,142.89 137.56,142.89 137.46,142.99 137.46,143.46 137.36,143.56 137.15,143.56 137.05,143.46 137.05,142.99 136.95,142.89 136.75,142.89 136.64,142.99 136.64,143.46 136.54,143.56 136.34,143.56 136.24,143.46 136.24,142.99 136.14,142.89 135.93,142.89 135.83,142.99 135.83,143.46 135.73,143.56 134.9,143.56 134.77,143.43 133.76,143.43 133.52,143.68 U27.AF39
  TOP w0.165: DIMM1.10 165.04,101.37 162.42,103.99 162.42,106.34 162.59,106.51 163.91,106.51 164.07,106.67 164.07,107.01 163.91,107.17 162.59,107.17 162.42,107.34 162.42,107.68 162.59,107.85 163.9,107.85 164.07,108.01 164.07,108.35 163.9,108.51 162.59,108.51 162.42,108.68 162.42,109.01 162.59,109.18 163.95,109.18 164.12,109.34 164.12,109.67 163.95,109.84 162.59,109.84 162.42,110 162.42,110.34 162.59,110.5 163.95,110.5 164.12,110.67 164.12,111 163.95,111.16 162.59,111.16 162.42,111.33 162.42,111.66 162.59,111.83 163.04,111.83 163.2,111.99 163.2,112.32 163.04,112.49 162.59,112.49 162.42,112.66 162.42,113.14 153.35,122.21 153.35,135.83 145.62,143.56 138.25,143.56 138.25,143.56
M_DATA_A4: length 81.8
  TOP w0.102: DIMM1.122 172.94,96.96 172.94,99.02 172.32,99.64 172.32,100.99 172.33,101 ; U27.AD37 132.22,146.38 134.8,146.38 134.88,146.3 135.28,146.3 135.79,146.81 135.79,147.04 137.49,148.74 138.35,148.74 138.49,148.88
  TOP w0.165: 138.49,148.88 138.69,149.09 147.77,149.09 158.84,138.01 158.84,125.77 168.47,116.14 168.47,115.9 168.25,115.68 168.25,115.45 168.48,115.21 168.72,115.21 168.96,115.45 169.19,115.45 169.42,115.22 169.42,114.98 169.19,114.74 169.19,114.51 172.05,111.65 172.05,103.08 172.7,102.43 172.7,101.38 172.33,101.01 172.33,101
M_DATA_A5: length 79.1
  TOP w0.102: 138.81,147.82 137.79,147.82 137.5,147.53 137.16,147.53 135.47,145.83 134.53,145.83 U27.AD40
  TOP w0.165: 138.81,147.82 147.24,147.82 157.56,137.5 157.56,125.2 160.9,121.86 160.9,121.63 160.64,121.37 160.64,121.14 160.87,120.9 161.11,120.9 161.33,121.13 161.57,121.13 161.8,120.89 161.8,120.66 161.57,120.43 161.57,120.2 170.52,111.25 170.52,102.25 171.8,100.97 171.8,100.11 171.29,99.6 171.29,97.7 171.8,97.19 171.8,96.39 171.27,95.86 171.27,95.08 171.4,94.95 DIMM1.123
M_DATA_A6: length 81.5
  TOP w0.102: 139.37,145.47 138.56,145.47 137.37,144.28 134.72,144.28 134.63,144.37 134.04,144.37 133.86,144.55 132.23,144.55 U27.AF37
  TOP w0.165: DIMM1.128 167.04,94.55 167.76,93.84 168.48,93.84 168.93,94.28 168.93,95.77 168.1,96.6 168.1,97.1 167.29,97.92 167.29,99.72 167.8,100.23 167.8,101.97 168.19,102.37 168.19,106.82 167.02,107.99 167.02,111.42 155.3,123.14 155.3,136.61 146.44,145.47 139.37,145.47
M_DATA_A7: length 78.8
  TOP w0.102: U27.AF40 137.68,144.01 138.5,144.83 140.47,144.83
  TOP w0.14: 166.35,97.23 166.3,97.18 166.3,96.27 166.55,96.02 166.55,95.46 DIMM1.129
  TOP w0.165: 166.35,97.23 166.8,97.68 166.8,99.12 166.27,99.65 166.27,101.15 166.36,101.25 166.36,101.86 166.53,102.03 167.36,102.03 167.52,102.19 167.52,102.52 167.36,102.69 166.53,102.69 166.36,102.85 166.36,103.19 166.53,103.35 167.36,103.35 167.52,103.52 167.52,103.85 167.36,104.01 166.53,104.01 166.36,104.18 166.36,104.51 166.53,104.68 167.36,104.68 167.52,104.84 167.52,105.18 167.36,105.34 166.53,105.34 166.36,105.51 166.36,105.84 166.53,106 167.36,106 167.52,106.17 167.52,106.5 167.36,106.67 166.53,106.67 166.36,106.83 166.36,111.12 154.66,122.82 154.66,136.35 146.18,144.83 140.47,144.83
M_DATA_A8: length 72.2
  TOP w0.102: 136.22,142.45 136.1,142.45 136.09,142.44 134.8,142.44 134.7,142.54 132.96,142.54 U27.AH38
  TOP w0.165: 136.22,142.45 136.5,142.16 145.15,142.16 152.08,135.23 152.08,121.68 160.38,113.39 160.38,112.82 160.54,112.65 160.94,112.65 161.11,112.49 161.11,112.16 160.94,111.99 160.54,111.99 160.38,111.83 160.38,111.49 160.54,111.33 160.96,111.33 161.12,111.16 161.12,110.83 160.96,110.67 160.54,110.67 160.38,110.5 160.38,110.17 160.54,110 160.81,110 160.97,109.84 160.97,109.5 160.81,109.34 159.78,109.34 159.61,109.17 159.61,108.84 159.78,108.68 160.86,108.68 161.02,108.51 161.02,108.18 160.86,108.01 159.86,108.01 159.7,107.85 159.7,107.52 159.86,107.35 160.87,107.35 161.03,107.19 161.03,106.85 160.87,106.69 159.78,106.69 159.62,106.52 159.62,106.19 159.78,106.03 160.89,106.03 161.06,105.86 161.06,105.53 160.89,105.36 160.54,105.36 160.38,105.2 160.38,104.64 160.54,104.47 160.88,104.47 161.06,104.29 161.06,103.74 163.04,101.76 DIMM1.12
M_DATA_A9: length 69.8
  TOP w0.102: 139.33,141.47 136.87,141.47 136.12,142.21 135.84,142.21 135.81,142.18 U27.AH40
  TOP w0.165: DIMM1.13 161.77,98.48 161.77,97.89 161.9,97.76 162.86,97.76 162.99,97.89 162.99,98.91 162.29,99.61 162.29,101.66 158.94,105.01 158.94,109.81 159.11,109.98 159.46,109.98 159.62,110.14 159.62,110.47 159.46,110.64 159.11,110.64 158.94,110.8 158.94,111.14 159.11,111.3 159.55,111.3 159.72,111.47 159.72,111.8 159.55,111.96 159.11,111.96 158.94,112.13 158.94,112.46 159.11,112.63 159.41,112.63 159.57,112.79 159.57,113.12 159.41,113.29 159.11,113.29 158.94,113.45 158.94,113.92 154.48,118.38 154.25,118.38 154.15,118.28 153.92,118.28 153.68,118.52 153.68,118.75 153.78,118.85 153.78,119.08 153.53,119.34 153.29,119.34 153.03,119.07 152.79,119.07 152.56,119.3 152.56,119.54 152.83,119.81 152.83,120.04 152.59,120.27 152.36,120.27 152.09,120 151.85,120 151.62,120.24 151.62,120.47 151.89,120.74 151.89,120.98 151.45,121.42 151.45,134.96 144.95,141.47 139.33,141.47
M_DATA_A10: length 70.6
  TOP w0.102: 138.33,138.48 137.01,138.48 135.39,140.1 134.72,140.1 134.64,140.03 134.24,140.03 134.04,140.23 134.04,140.35 133.7,140.69 132.93,140.69 U27.AK38
  TOP w0.165: 138.33,138.48 138.87,137.93 143.39,137.93 147.93,133.39 147.93,110.72 148.12,110.53 148.35,110.53 148.77,110.94 149,110.94 149.24,110.71 149.24,110.47 148.82,110.06 148.82,109.83 149.06,109.59 149.29,109.59 149.71,110.01 149.94,110.01 150.18,109.77 150.18,109.54 149.76,109.12 149.76,108.89 150,108.65 150.23,108.65 150.64,109.07 150.88,109.07 151.11,108.83 151.11,108.6 150.7,108.18 150.7,107.95 150.93,107.71 151.17,107.71 152.18,108.73 152.36,108.73 152.65,108.44 152.65,108.26 151.64,107.25 151.64,107.01 151.87,106.78 152.11,106.78 153.15,107.83 153.33,107.83 153.62,107.54 153.62,107.36 152.57,106.31 152.57,106.07 152.81,105.84 153.04,105.84 154.14,106.94 154.32,106.94 154.61,106.65 154.61,106.47 153.51,105.37 153.51,105.14 153.75,104.9 153.98,104.9 154.4,105.32 154.63,105.32 154.86,105.08 154.86,104.85 154.45,104.43 154.45,104.2 156.53,102.11 156.53,101.16 DIMM1.18
M_DATA_A11: length 70
  TOP w0.102: U27.AK39 133.52,140.04 133.76,139.8 134.8,139.8 134.9,139.9 135.3,139.9 137.05,138.15 137.65,138.15
  TOP w0.165: DIMM1.19 155.93,98.86 155.93,101.67 147.24,110.36 147.24,112.58 146.97,112.85 146.66,112.85 146.53,112.98 146.53,113.39 146.66,113.51 147.13,113.51 147.26,113.64 147.26,114.05 147.13,114.18 146.68,114.18 146.56,114.3 146.56,114.71 146.68,114.84 147.13,114.84 147.3,115 147.3,115.34 147.13,115.5 146.65,115.5 146.52,115.63 146.52,116.04 146.65,116.17 147.16,116.17 147.29,116.29 147.29,116.7 147.16,116.83 146.72,116.83 146.59,116.96 146.59,117.36 146.72,117.49 147.14,117.49 147.27,117.62 147.27,118.03 147.14,118.15 146.74,118.15 146.62,118.28 146.62,118.69 146.74,118.82 147.13,118.82 147.3,118.98 147.3,119.31 147.13,119.48 146.8,119.48 146.64,119.65 146.64,119.98 146.8,120.14 147.13,120.14 147.3,120.31 147.3,120.64 147.13,120.81 146.8,120.81 146.64,120.97 146.64,121.3 146.8,121.47 147.13,121.47 147.3,121.63 147.3,121.97 147.13,122.13 146.8,122.13 146.64,122.3 146.64,122.63 146.8,122.79 147.13,122.79 147.3,122.96 147.3,123.29 147.13,123.46 146.8,123.46 146.64,123.62 146.64,123.96 146.8,124.12 147.13,124.12 147.3,124.29 147.3,124.62 147.13,124.78 146.8,124.78 146.64,124.95 146.64,125.28 146.8,125.45 147.13,125.45 147.3,125.61 147.3,125.94 147.13,126.11 146.8,126.11 146.64,126.27 146.64,126.61 146.8,126.77 147.13,126.77 147.3,126.94 147.3,127.27 147.13,127.44 146.8,127.44 146.64,127.6 146.64,127.93 146.8,128.1 147.13,128.1 147.3,128.26 147.3,128.6 147.13,128.76 146.8,128.76 146.64,128.93 146.64,129.26 146.8,129.42 147.13,129.42 147.3,129.59 147.3,129.92 147.13,130.09 146.8,130.09 146.64,130.25 146.64,130.58 146.8,130.75 147.13,130.75 147.3,130.92 147.3,131.25 147.13,131.41 146.8,131.41 146.64,131.58 146.64,131.91 146.8,132.08 147.13,132.08 147.3,132.24 147.3,132.57 147.13,132.74 146.86,132.74 146.64,132.96 146.64,133.71 143.04,137.3 138.82,137.3 137.97,138.15 137.65,138.15
M_DATA_A12: length 72.7
  TOP w0.102: U27.AH37 131.69,142.51 131.91,142.73 132.75,142.73 132.77,142.75 134.8,142.75 134.89,142.65 136.02,142.65 136.05,142.68 138.16,142.68
  TOP w0.165: 138.16,142.68 138.28,142.8 145.41,142.8 152.72,135.49 152.72,121.94 161.77,112.89 161.77,103.8 163.8,101.78 163.8,99.98 164.21,99.56 164.46,99.56 164.79,99.23 164.79,97.87 164.58,97.67 164.18,97.67 163.98,97.47 163.98,96.34 164.26,96.06 164.95,96.06 165.1,95.9 165.1,95.11 164.94,94.95 DIMM1.131
M_DATA_A13: length 71.4
  TOP w0.102: 136.07,141.63 135.77,141.93 134.72,141.93 134.64,141.85 134.22,141.85 134,142.07 133.63,142.07 U27.AH39
  TOP w0.165: 136.07,141.63 136.87,140.83 144.69,140.83 150.81,134.7 150.81,119.98 153.15,117.64 153.76,117.64 154.32,117.64 158.31,113.66 158.31,104.74 161.8,101.25 161.8,99.81 161.56,99.57 161.27,99.57 161.09,99.38 161.09,97.86 160.92,97.7 160.03,97.7 159.87,97.53 159.87,95.91 160.06,95.71 163.5,95.71 163.63,95.84 163.63,96.67 163.44,96.85 DIMM1.132
M_DATA_A14: length 71.2
  TOP w0.102: U27.AK37 132.23,140.89 133.88,140.89 134,140.78 134.01,140.78 134.08,140.71 134.63,140.71 134.76,140.58 135.51,140.58 137.16,138.94 138.15,138.94 138.5,139.29 139.29,139.29 139.31,139.27 139.47,139.27
  TOP w0.165: DIMM1.137 158.24,95.15 158.24,97.77 158.8,98.33 158.8,99.43 158.24,99.99 158.24,102.64 156.16,104.72 156.16,105.27 156.33,105.44 156.57,105.44 156.73,105.6 156.73,105.94 156.57,106.1 156.33,106.1 156.16,106.27 156.16,106.6 156.33,106.77 156.57,106.77 156.73,106.93 156.73,107.26 156.57,107.43 156.33,107.43 156.16,107.59 156.16,107.93 156.33,108.09 156.57,108.09 156.73,108.26 156.73,108.59 156.57,108.75 156.33,108.75 156.16,108.92 156.16,109.25 156.33,109.42 156.57,109.42 156.73,109.58 156.73,109.92 156.57,110.08 156.33,110.08 156.16,110.25 156.16,110.58 156.33,110.74 156.57,110.74 156.73,110.91 156.73,111.24 156.57,111.41 156.33,111.41 156.16,111.57 156.16,111.9 156.33,112.07 156.57,112.07 156.73,112.23 156.73,112.57 156.57,112.73 156.33,112.73 156.16,112.9 156.16,113.54 153.62,116.08 152.5,116.08 152.16,116.42 151.93,116.42 151.79,116.29 151.61,116.29 151.32,116.58 151.32,116.76 151.46,116.89 151.46,117.13 151.22,117.36 150.99,117.36 150.87,117.24 150.69,117.24 150.4,117.53 150.4,117.71 150.52,117.83 150.52,118.07 150.28,118.3 150.05,118.3 149.93,118.18 149.75,118.18 149.46,118.46 149.46,118.64 149.58,118.77 149.58,119 149.2,119.38 149.2,133.93 143.86,139.27 139.47,139.27
M_DATA_A15: length 68.6
  TOP w0.102: U27.AK40 135.44,140.36 136.07,139.73 136.07,139.71 137.08,138.7 138.22,138.7 138.23,138.72 138.89,138.72 139.03,138.57 139.27,138.57
  TOP w0.165: DIMM1.138 157.04,98.82 157.8,99.58 157.8,102.08 155.53,104.35 155.53,107.31 155.36,107.48 154.67,107.48 154.51,107.64 154.51,107.97 154.67,108.14 155.36,108.14 155.53,108.3 155.53,108.64 155.36,108.8 154.32,108.8 154.19,108.93 154.19,109.34 154.32,109.47 155.36,109.47 155.53,109.63 155.53,113.28 153.36,115.44 151.6,115.44 150.91,114.75 150.68,114.75 150.45,114.99 150.45,115.22 151,115.77 151,116.01 150.76,116.24 150.53,116.24 149.91,115.62 149.73,115.62 149.44,115.91 149.44,116.09 150.06,116.71 150.06,116.95 149.82,117.18 149.59,117.18 149.05,116.64 148.87,116.64 148.58,116.93 148.58,117.11 149.12,117.65 149.12,117.88 148.57,118.44 148.57,133.65 143.65,138.57 139.27,138.57
M_DATA_A16: length 57.8
  TOP w0.102: 138.71,135.82 137.38,137.14 137.21,137.14 135.59,138.76 134.82,138.76 134.72,138.86 132.94,138.86 U27.AM38
  TOP w0.165: 138.71,135.82 142.73,135.82 145.37,133.18 145.37,129.7 144.8,129.14 144.8,128.5 145,128.3 145.15,128.3 145.32,128.13 145.32,127.8 145.15,127.63 144.95,127.63 144.79,127.47 144.79,127.14 144.95,126.97 145.15,126.97 145.32,126.81 145.32,126.47 145.15,126.31 144.95,126.31 144.79,126.14 144.79,125.81 144.95,125.64 145.15,125.64 145.32,125.48 145.32,125.15 145.15,124.98 144.95,124.98 144.79,124.82 144.79,124.48 144.95,124.32 145.15,124.32 145.32,124.15 145.32,123.82 145.15,123.66 144.95,123.66 144.79,123.49 144.79,123.16 144.95,122.99 145.15,122.99 145.32,122.83 145.32,122.49 145.15,122.33 144.95,122.33 144.79,122.16 144.79,121.83 144.95,121.67 145.15,121.67 145.32,121.5 145.32,121.17 145.15,121 144.95,121 144.79,120.84 144.79,111.02 153.8,102.01 153.8,99 DIMM1.21
M_DATA_A17: length 55.7
  TOP w0.102: U27.AM40 134.48,138.48 135.45,138.48 137.42,136.5 137.47,136.5
  TOP w0.165: 137.47,136.5 138.83,135.15 142.5,135.15 144.73,132.92 144.73,129.96 143.64,128.87 143.64,128.55 143.87,128.32 143.99,128.32 144.15,128.15 144.15,127.82 143.99,127.66 143.87,127.66 143.71,127.49 143.71,127.16 143.87,126.99 143.99,126.99 144.15,126.83 144.15,126.5 143.99,126.33 143.87,126.33 143.71,126.17 143.71,125.83 143.87,125.67 143.99,125.67 144.15,125.5 144.15,125.17 143.99,125 143.87,125 143.71,124.84 143.71,124.51 143.87,124.34 143.99,124.34 144.15,124.18 144.15,123.84 143.99,123.68 143.87,123.68 143.71,123.51 143.71,123.18 143.87,123.02 143.99,123.02 144.15,122.85 144.15,122.52 143.99,122.35 143.87,122.35 143.71,122.19 143.71,121.85 143.87,121.69 143.99,121.69 144.15,121.52 144.15,121.19 143.99,121.03 143.87,121.03 143.71,120.86 143.71,120.53 143.87,120.36 143.99,120.36 144.15,120.2 144.15,119.87 143.99,119.7 143.87,119.7 143.71,119.54 143.71,119.2 143.87,119.04 143.99,119.04 144.15,118.87 144.15,118.54 143.99,118.37 143.87,118.37 143.71,118.21 143.71,117.88 143.87,117.71 143.99,117.71 144.15,117.55 144.15,117.21 143.99,117.05 143.87,117.05 143.71,116.88 143.71,116.55 143.87,116.39 143.99,116.39 144.15,116.22 144.15,115.89 143.99,115.72 143.87,115.72 143.71,115.56 143.71,115.23 143.87,115.06 143.99,115.06 144.15,114.9 144.15,114.56 143.99,114.4 143.87,114.4 143.71,114.23 143.71,113.9 143.87,113.73 143.99,113.73 144.15,113.57 144.15,113.24 143.99,113.07 143.87,113.07 143.71,112.91 143.71,112.57 143.87,112.41 143.99,112.41 144.15,112.24 144.15,111.91 143.99,111.75 143.87,111.75 143.71,111.58 143.71,111.2 153.04,101.87 DIMM1.22
M_DATA_A18: length 56.3
  TOP w0.102: U27.AP38 132.6,136.87 132.76,137.03 133.7,137.03 134.02,136.71 134.02,136.59 134.24,136.37 135.27,136.37 136.46,135.17 136.46,133.6
  TOP w0.165: DIMM1.27 147.85,98.94 147.85,100.91 147.35,101.42 147.35,102.28 138.41,111.21 138.41,111.58 138.59,111.76 139.02,111.76 139.19,111.93 139.19,112.26 139.02,112.42 138.66,112.42 138.49,112.59 138.49,112.92 138.66,113.09 139.02,113.09 139.19,113.25 139.19,113.58 139.02,113.75 138.66,113.75 138.49,113.91 138.49,114.25 138.66,114.41 139.02,114.41 139.19,114.58 139.19,114.91 139.02,115.07 138.66,115.07 138.49,115.24 138.49,115.57 138.66,115.74 139.02,115.74 139.19,115.9 139.19,116.24 139.02,116.4 138.66,116.4 138.49,116.57 138.49,116.9 138.66,117.06 139.02,117.06 139.19,117.23 139.19,117.56 139.02,117.73 138.66,117.73 138.49,117.89 138.49,118.22 138.66,118.39 139.02,118.39 139.19,118.55 139.19,118.89 139.02,119.05 138.66,119.05 138.49,119.22 138.49,119.55 138.66,119.72 139.02,119.72 139.19,119.88 139.19,120.21 139.02,120.38 138.66,120.38 138.49,120.54 138.49,120.88 138.66,121.04 139.02,121.04 139.19,121.21 139.19,121.54 139.02,121.7 138.66,121.7 138.49,121.87 138.49,122.2 138.66,122.37 139.02,122.37 139.19,122.53 139.19,122.86 139.02,123.03 138.66,123.03 138.49,123.2 138.49,123.53 138.66,123.69 139.02,123.69 139.19,123.86 139.19,124.19 139.02,124.36 138.66,124.36 138.49,124.52 138.49,125.24 136.46,127.27 136.46,133.6
M_DATA_A19: length 55.7
  TOP w0.102: 136.1,133.67 136.1,135.25 135.2,136.14 133.72,136.14 133.52,136.35 U27.AP39
  TOP w0.165: DIMM1.28 146.69,101 146.69,102.02 137.02,111.7 137.02,112.32 137.18,112.48 137.69,112.48 137.86,112.65 137.86,112.98 137.69,113.15 137.18,113.15 137.02,113.31 137.02,113.64 137.18,113.81 137.69,113.81 137.86,113.97 137.86,114.31 137.69,114.47 137.18,114.47 137.02,114.64 137.02,114.97 137.18,115.13 137.69,115.13 137.86,115.3 137.86,115.63 137.69,115.8 137.18,115.8 137.02,115.96 137.02,116.3 137.18,116.46 137.69,116.46 137.86,116.63 137.86,116.96 137.69,117.12 137.18,117.12 137.02,117.29 137.02,117.62 137.18,117.79 137.69,117.79 137.86,117.95 137.86,118.28 137.69,118.45 137.18,118.45 137.02,118.61 137.02,118.95 137.18,119.11 137.69,119.11 137.86,119.28 137.86,119.61 137.69,119.77 137.18,119.77 137.02,119.94 137.02,120.27 137.18,120.44 137.69,120.44 137.86,120.6 137.86,120.94 137.69,121.1 137.18,121.1 137.02,121.27 137.02,121.6 137.18,121.76 137.69,121.76 137.86,121.93 137.86,122.26 137.69,122.43 137.18,122.43 137.02,122.59 137.02,122.92 137.18,123.09 137.69,123.09 137.86,123.25 137.86,123.59 137.69,123.75 137.18,123.75 137.02,123.92 137.02,124.25 137.18,124.42 137.69,124.42 137.86,124.58 137.86,124.91 137.69,125.08 137.1,125.08 135.86,126.32 135.86,132.08 136.1,132.32 136.1,133.67
M_DATA_A20: length 58.2
  TOP w0.102: U27.AM37 132.23,139.06 134.82,139.06 134.9,138.98 135.77,138.98 137.01,137.75
  TOP w0.165: 137.01,137.75 137.01,137.74 137.59,137.74 138.85,136.48 142.96,136.48 146,133.44 146,120.96 145.42,120.38 145.42,119.97 145.59,119.81 145.73,119.81 145.85,119.68 145.85,119.27 145.73,119.15 145.59,119.15 145.42,118.98 145.42,111.28 154.29,102.42 154.29,100.34 155.04,99.58 155.04,96.85 DIMM1.140
M_DATA_A21: length 57.1
  TOP w0.102: U27.AM39 133.85,138.2 134.72,138.2 134.8,138.28 135.36,138.28 137.89,135.75 137.89,130.68
  TOP w0.165: DIMM1.141 153.85,95.15 153.85,97.13 152.81,98.17 152.81,99.06 152.04,99.82 152.04,101.97 143.07,110.94 143.07,124.73 142.66,125.15 142.66,125.38 143.04,125.77 143.04,126 142.8,126.23 142.57,126.23 142.19,125.85 141.95,125.85 141.72,126.09 141.72,126.32 142.1,126.7 142.1,126.94 141.87,127.17 141.63,127.17 141.25,126.79 141.02,126.79 140.78,127.03 140.78,127.26 141.16,127.64 141.16,127.88 140.93,128.11 140.69,128.11 140.31,127.73 140.08,127.73 137.89,129.92 137.89,130.68
M_DATA_A22: length 56.8
  TOP w0.102: 137.08,128.45 137.08,135.32 135.47,136.93 134.76,136.93 134.63,137.05 134.05,137.05 133.88,137.23 132.05,137.23 131.69,136.87 U27.AP37
  TOP w0.165: DIMM1.146 149.26,97.07 149.26,99.04 149.81,99.59 149.81,101.77 140.96,110.61 140.96,110.97 141.13,111.13 141.31,111.13 141.47,111.3 141.47,111.63 141.31,111.79 141.13,111.79 140.96,111.96 140.96,112.29 141.13,112.46 141.31,112.46 141.47,112.62 141.47,112.95 141.31,113.12 141.13,113.12 140.96,113.28 140.96,113.62 141.13,113.78 141.31,113.78 141.47,113.95 141.47,114.28 141.31,114.45 141.13,114.45 140.96,114.61 140.96,114.94 141.13,115.11 141.31,115.11 141.47,115.27 141.47,115.61 141.31,115.77 141.13,115.77 140.96,115.94 140.96,116.27 141.13,116.43 141.31,116.43 141.47,116.6 141.47,116.93 141.31,117.1 141.13,117.1 140.96,117.26 140.96,117.59 141.13,117.76 141.31,117.76 141.47,117.92 141.47,118.26 141.31,118.42 141.13,118.42 140.96,118.59 140.96,118.92 141.13,119.09 141.31,119.09 141.47,119.25 141.47,119.58 141.31,119.75 141.13,119.75 140.96,119.91 140.96,120.25 141.13,120.41 141.31,120.41 141.47,120.58 141.47,120.91 141.31,121.07 141.13,121.07 140.96,121.24 140.96,121.57 141.13,121.74 141.31,121.74 141.47,121.9 141.47,122.24 141.31,122.4 141.13,122.4 140.96,122.57 140.96,122.9 141.13,123.06 141.31,123.06 141.47,123.23 141.47,123.56 141.31,123.73 141.13,123.73 140.96,123.89 140.96,124.57 137.08,128.45
M_DATA_A23: length 54.5
  TOP w0.102: U27.AP40 134.62,136.7
  TOP w0.165: 134.62,136.7 134.65,136.68 135.29,136.68 136.73,135.24 136.73,127.9 139.82,124.81 139.82,124.22 139.99,124.05 140.16,124.05 140.33,123.89 140.33,123.55 140.16,123.39 139.99,123.39 139.82,123.22 139.82,122.89 139.99,122.73 140.16,122.73 140.33,122.56 140.33,122.23 140.16,122.06 139.99,122.06 139.82,121.9 139.82,121.57 139.99,121.4 140.16,121.4 140.33,121.24 140.33,120.9 140.16,120.74 139.99,120.74 139.82,120.57 139.82,120.24 139.99,120.07 140.16,120.07 140.33,119.91 140.33,119.58 140.16,119.41 139.99,119.41 139.82,119.25 139.82,118.91 139.99,118.75 140.16,118.75 140.33,118.58 140.33,118.25 140.16,118.09 139.99,118.09 139.82,117.92 139.82,117.59 139.99,117.42 140.16,117.42 140.33,117.26 140.33,116.93 140.16,116.76 139.99,116.76 139.82,116.59 139.82,116.26 139.99,116.1 140.16,116.1 140.33,115.93 140.33,115.6 140.16,115.43 139.99,115.43 139.82,115.27 139.82,114.94 139.99,114.77 140.16,114.77 140.33,114.61 140.33,114.27 140.16,114.11 139.99,114.11 139.82,113.94 139.82,113.61 139.99,113.45 140.16,113.45 140.33,113.28 140.33,112.95 140.16,112.78 139.99,112.78 139.82,112.62 139.82,112.28 139.99,112.12 140.16,112.12 140.33,111.95 140.33,111.49 140.08,111.24 140.08,110.47 148.18,102.37 148.18,100.05 148.8,99.43 148.8,98.09 148.04,97.33 DIMM1.147
M_DATA_A24: length 49
  TOP w0.102: U27.AU37 132.17,133.47 132.17,132.9 132.46,132.61 132.82,132.61 133.84,131.58 133.84,130.73
  TOP w0.165: 133.84,130.73 133.93,130.64 133.93,119.8 134.06,119.67 134.47,119.67 134.6,119.8 134.6,124.29 134.72,124.42 135.13,124.42 135.26,124.29 135.26,111.37 144.55,102.08 144.55,101.14 DIMM1.30
M_DATA_A25: length 47.6
  TOP w0.165: DIMM1.31 144.06,98.78 144.06,101.63 134.51,111.19 134.51,118.89 134.38,119.02 133.97,119.02 133.84,118.89 133.84,115.3 133.72,115.17 133.31,115.17 133.18,115.3 133.18,130.55 132.16,131.57 132.16,132.55 131.95,132.76 131.69,133.02 U27.AV37
M_DATA_A26: length 49.4
  TOP w0.102: 129.03,129.92 129.63,130.52 129.63,131.67 129.53,131.77 129.53,132.31 129.79,132.58 129.92,132.58 130.19,132.85 130.19,133.63 U27.AU35
  TOP w0.165: 129.03,129.92 129.03,120.27 128.91,120.15 128.5,120.15 128.37,120.27 128.37,124.82 128.2,124.99 127.87,124.99 127.71,124.82 127.71,112.98 139.04,101.64 DIMM1.36
M_DATA_A27: length 48.6
  TOP w0.102: 128.43,129.85 129.43,130.85 129.43,131.27 129.33,131.38 129.33,132.51 U27.AV35
  TOP w0.165: DIMM1.37 137.97,98.82 137.97,101.8 126.96,112.81 126.96,129.47 127.13,129.64 127.46,129.64 127.63,129.47 127.63,125.76 127.75,125.63 128.16,125.63 128.29,125.76 128.29,129.71 128.43,129.85
M_DATA_A28: length 49.8
  TOP w0.102: 134.85,131.64 134.82,131.67 134.82,132.31 133.66,133.47 132.57,133.47 132.19,133.85 132.19,134.08 131.69,134.58 U27.AT37
  TOP w0.165: DIMM1.149 146.04,97.47 145.26,98.26 145.26,99.37 145.87,99.98 145.87,101.22 145.24,101.84 145.24,102.45 135.89,111.79 135.89,117.55 136.06,117.71 136.2,117.71 136.36,117.88 136.36,118.21 136.2,118.38 136.06,118.38 135.89,118.54 135.89,118.87 136.06,119.04 136.2,119.04 136.36,119.2 136.36,119.54 136.2,119.7 136.06,119.7 135.89,119.87 135.89,120.2 136.06,120.36 136.2,120.36 136.36,120.53 136.36,120.86 136.2,121.03 136.06,121.03 135.89,121.19 135.89,121.53 136.06,121.69 136.2,121.69 136.36,121.86 136.36,122.19 136.2,122.35 136.06,122.35 135.89,122.52 135.89,122.85 136.06,123.02 136.2,123.02 136.36,123.18 136.36,123.51 136.2,123.68 136.06,123.68 135.89,123.84 135.89,124.56 134.89,125.56 134.89,131.6 134.85,131.64
M_DATA_A29: length 46.7
  TOP w0.165: DIMM1.150 144.29,97.6 143.58,97.6 143.1,98.09 143.1,99.19 143.8,99.89 143.8,100.95 133.65,111.1 133.65,114.4 133.52,114.53 133.11,114.53 132.99,114.4 132.99,112.43 132.86,112.3 132.45,112.3 132.32,112.43 132.32,130.5 131.69,131.14 U27.AW37
M_DATA_A30: length 50.3
  TOP w0.102: U27.AT35 130.39,134.34 130.39,132.73 130.21,132.55 130.21,130.88 130.52,130.57
  TOP w0.165: DIMM1.155 140.29,95.2 140.29,97.35 140.8,97.86 140.8,99.46 140.29,99.97 140.29,102.23 129.44,113.08 129.44,115.48 129.56,115.6 129.97,115.6 130.1,115.48 130.1,113.82 130.23,113.7 130.64,113.7 130.76,113.82 130.76,129.62 130.52,129.86 130.52,130.57
M_DATA_A31: length 47.6
  TOP w0.102: U27.AW35 129.91,132.08 129.91,130.8
  TOP w0.165: DIMM1.156 139.17,96.98 139.17,98.96 139.8,99.59 139.8,101.78 128.34,113.24 128.34,119.37 128.47,119.5 128.97,119.5 129.1,119.37 129.1,116.64 129.23,116.51 129.78,116.51 129.91,116.64 129.91,130.8
M_DATA_A32: length 50.5
  TOP w0.102: U27.AV6 101.14,133.59 100.81,133.26 100.81,132.85 101.08,132.59 101.2,132.59 101.47,132.31 101.47,131.9 101.37,131.8 101.37,130.84 100.71,130.18
  TOP w0.165: DIMM1.81 90.04,97.82 89.92,97.69 89.23,97.69 89.1,97.82 89.1,99.29 89.46,99.64 89.93,99.64 90.29,100 90.29,100.97 91.24,101.92 91.24,105.27 93.12,107.15 93.12,107.62 93.24,107.75 93.7,107.75 93.83,107.87 93.83,108.25 93.7,108.38 93.24,108.38 93.12,108.51 93.12,108.97 93.28,109.13 93.73,109.13 93.83,109.24 93.83,109.69 93.73,109.79 93.28,109.79 93.12,109.96 93.12,110.29 93.28,110.45 93.73,110.45 93.83,110.56 93.83,111.01 93.73,111.12 93.28,111.12 93.12,111.28 93.12,111.61 93.28,111.78 93.68,111.78 93.8,111.9 93.8,112.31 93.68,112.44 93.28,112.44 93.12,112.6 93.12,112.93 93.28,113.1 93.7,113.1 93.83,113.22 93.83,113.63 93.7,113.76 93.28,113.76 93.12,113.92 93.12,114.25 93.28,114.42 93.7,114.42 93.83,114.54 93.83,114.95 93.7,115.08 93.28,115.08 93.12,115.24 93.12,119.39 100.71,126.98 100.71,130.18
M_DATA_A33: length 48.3
  TOP w0.102: 100.44,130.46 100.82,130.84 101.07,130.84 101.14,130.91 U27.AY6
  TOP w0.165: DIMM1.82 90.02,101.63 90.02,104.94 92.48,107.41 92.48,108.71 92.35,108.84 92.16,108.84 91.97,109.03 91.97,109.37 92.1,109.5 92.35,109.5 92.48,109.63 92.48,109.98 92.32,110.14 91.63,110.14 91.47,110.31 91.47,110.64 91.63,110.8 92.32,110.8 92.48,110.97 92.48,111.3 92.32,111.46 91.63,111.46 91.47,111.63 91.47,111.96 91.63,112.12 92.32,112.12 92.48,112.29 92.48,112.93 92.32,113.09 91.68,113.09 91.52,113.26 91.52,113.59 91.68,113.75 92.32,113.75 92.48,113.92 92.48,114.25 92.32,114.41 91.68,114.41 91.52,114.58 91.52,114.91 91.68,115.07 92.32,115.07 92.48,115.24 92.48,115.57 92.32,115.73 91.68,115.73 91.52,115.9 91.52,116.23 91.68,116.39 92.32,116.39 92.48,116.56 92.48,116.89 92.32,117.05 91.68,117.05 91.52,117.22 91.52,117.55 91.68,117.71 92.32,117.71 92.48,117.88 92.48,118.21 92.32,118.37 91.68,118.37 91.52,118.54 91.52,118.87 91.68,119.03 92.32,119.03 92.48,119.2 92.48,119.65 100.28,127.45 100.28,130.3 100.44,130.46
M_DATA_A34: length 49.7
  TOP w0.102: 98.04,131.09 98.16,131.21 98.16,131.25 98.92,132.01 98.92,133.18 99.16,133.42 99.45,133.42 99.57,133.54 99.57,133.7 U27.AV4
  TOP w0.165: 98.04,131.09 97.89,130.94 97.89,130.87 97.76,130.74 97.75,130.74 97.62,130.61 97.62,130.47 86.61,119.46 86.61,118.73 86.74,118.6 87.3,118.6 87.41,118.49 87.41,118.05 87.3,117.94 86.72,117.94 86.55,117.78 86.55,117.45 86.72,117.28 87.24,117.28 87.41,117.11 87.41,116.78 87.24,116.62 86.72,116.62 86.55,116.45 86.55,116.12 86.72,115.96 87.24,115.96 87.41,115.79 87.41,115.46 87.24,115.3 86.72,115.3 86.55,115.13 86.55,114.8 86.72,114.64 87.24,114.64 87.41,114.47 87.41,114.14 87.24,113.98 86.72,113.98 86.55,113.81 86.55,113.48 86.72,113.32 87.24,113.32 87.41,113.15 87.41,112.82 87.24,112.66 86.72,112.66 86.55,112.49 86.55,112.16 86.72,112 87.24,112 87.41,111.83 87.41,107.24 86.55,106.38 86.55,105.01 83.9,102.35 83.9,98.9 DIMM1.87
M_DATA_A35: length 51
  TOP w0.102: U27.AU4 99.31,135.2 99.19,135.33 98.92,135.33 98.79,135.2 98.79,133.83 98.49,133.53 97.99,133.53 97.92,133.45 97.92,132.37 97.32,131.77
  TOP w0.165: 97.32,131.77 96.99,131.44 96.99,130.73 85.92,119.66 85.92,112.42 85.92,111.48 86.04,111.35 86.65,111.35 86.77,111.23 86.77,110.79 86.65,110.67 86.04,110.67 85.92,110.54 85.92,110.03 86.04,109.91 86.65,109.91 86.77,109.78 86.77,109.25 86.65,109.12 85.9,109.12 85.78,108.99 85.78,108.36 85.9,108.23 86.64,108.23 86.77,108.1 86.77,107.5 86.63,107.36 86.26,107.36 85.92,107.02 85.92,106.64 85.92,105.27 83.35,102.7 83.35,101.6 83.22,101.47 82.35,101.47 82.22,101.35 82.22,99.72 82.35,99.59 83.36,99.59 83.49,99.72 83.49,100.21 DIMM1.88
M_DATA_A36: length 49.2
  TOP w0.102: 101.03,130.04 101.57,130.58 101.57,131.72 101.67,131.82 101.67,132.82 101.45,133.04 U27.AW6
  TOP w0.165: 101.03,130.04 101.02,130.02 101.02,126.39 94.46,119.84 94.46,119.2 94.3,119.04 93.88,119.04 93.75,118.91 93.75,118.5 93.88,118.38 94.3,118.38 94.46,118.21 94.46,117.88 94.3,117.72 93.88,117.72 93.75,117.59 93.75,117.18 93.88,117.06 94.3,117.06 94.46,116.89 94.46,116.56 94.3,116.4 93.88,116.4 93.75,116.27 93.75,115.86 93.88,115.74 94.3,115.74 94.46,115.57 94.46,107.59 91.87,105 91.87,100.28 91.87,99.65 91.29,99.07 91.29,98.09 90.93,97.74 90.63,97.74 89.92,97.03 89.92,95.99 90.04,95.86 91.64,95.86 91.77,95.99 91.77,96.73 91.64,96.85 DIMM1.200
M_DATA_A37: length 51.4
  TOP w0.102: 99.64,128.13 99.64,128.23 100,128.58 100,130.37 100.32,130.69 100.39,130.69 100.73,131.04 100.74,131.04 100.86,131.17 100.86,131.17 100.89,131.19 100.89,131.74 100.86,131.76 100.86,131.89 100.81,131.94 100.81,132.53 100.61,132.74 100.61,134.75 100.73,134.87 U27.AU6
  TOP w0.165: 99.64,128.13 90.83,119.31 90.83,108.53 90.96,108.41 91.69,108.41 91.82,108.28 91.82,107.65 91.67,107.49 90.96,107.49 90.83,107.37 90.83,106.66 89.38,105.21 89.38,102.06 88.27,100.94 88.27,100.3 87.29,99.33 87.29,98.01 87.55,97.74 87.97,97.74 88.27,97.45 88.27,96.34 88.9,95.71 88.9,94.26 89.03,94.13 89.92,94.13 90.04,94.26 90.04,94.95 DIMM1.201
M_DATA_A38: length 48.7
  TOP w0.102: U27.AW4 99.52,133.04 99.64,132.91 99.64,131.9 99.1,131.35
  TOP w0.165: 99.1,131.35 98.89,131.15 98.89,129.69 89.64,120.43 88.68,119.47 88.68,118.84 88.84,118.67 89.1,118.67 89.27,118.51 89.27,118.18 89.1,118.01 88.84,118.01 88.68,117.85 88.68,117.52 88.84,117.35 89.1,117.35 89.27,117.19 89.27,116.86 89.1,116.69 88.84,116.69 88.68,116.53 88.68,116.2 88.84,116.03 89.1,116.03 89.27,115.87 89.27,115.54 89.1,115.37 88.84,115.37 88.68,115.21 88.68,114.88 88.84,114.71 89.1,114.71 89.27,114.55 89.27,114.22 89.1,114.05 88.84,114.05 88.68,113.89 88.68,113.56 88.84,113.39 89.14,113.39 89.27,113.26 89.27,112.86 89.14,112.73 88.84,112.73 88.68,112.56 88.68,112.36 89.27,111.77 89.27,107.3 87.82,105.86 87.82,104.33 85.45,101.95 85.45,101.32 85.8,100.97 85.8,100.97 85.8,99.9 85.22,99.32 85.22,97.82 85.34,97.69 85.85,97.69 85.98,97.56 85.98,96.98 85.85,96.85 DIMM1.206
M_DATA_A39: length 47.8
  TOP w0.102: 98.23,130.82 99.31,131.9 U27.AY4
  TOP w0.165: 98.23,130.82 98.23,130.76 98.26,130.73 98.26,130.21 88.04,120 88.04,111.62 88.21,111.46 88.49,111.46 88.62,111.33 88.62,110.93 88.49,110.8 88.21,110.8 88.04,110.63 88.04,110.3 88.21,110.14 88.49,110.14 88.62,110.01 88.62,109.61 88.49,109.48 88.21,109.48 88.04,109.31 88.04,108.98 88.21,108.82 88.51,108.82 88.63,108.69 88.63,108.28 88.51,108.16 88.21,108.16 88.04,107.99 88.04,106.98 87.19,106.12 87.19,104.74 84.62,102.18 84.62,101.3 84.29,100.97 84.29,100.34 84.62,100.01 84.62,99.61 84.8,99.43 84.8,97.68 84.04,96.92 84.04,96.06 84.17,95.94 84.73,95.94 84.86,95.81 84.86,95.08 84.73,94.95 DIMM1.207
M_DATA_A40: length 58.5
  TOP w0.102: 95.17,133.34 95.18,133.35 95.18,135.63 95.69,136.14 96.64,136.14 96.98,136.48 96.98,136.71 97.3,137.03 98.27,137.03 98.4,136.9 U27.AR3
  TOP w0.165: DIMM1.90 81.4,100.29 81.4,99.61 81.24,99.44 80.38,99.44 80.21,99.61 80.21,101.36 84.51,105.66 84.51,107.99 84.34,108.15 84.23,108.15 84.07,108.32 84.07,108.65 84.23,108.81 84.34,108.81 84.51,108.98 84.51,109.31 84.34,109.47 84.24,109.47 84.07,109.64 84.07,109.97 84.24,110.13 84.34,110.13 84.51,110.3 84.51,110.63 84.34,110.79 84.25,110.79 84.09,110.96 84.09,111.29 84.25,111.45 84.34,111.45 84.51,111.62 84.51,111.95 84.34,112.11 84.25,112.11 84.08,112.28 84.08,112.61 84.25,112.77 84.34,112.77 84.51,112.94 84.51,113.27 84.34,113.44 84.29,113.44 84.12,113.6 84.12,113.93 84.29,114.1 84.34,114.1 84.51,114.26 84.51,114.59 84.34,114.76 84.25,114.76 84.08,114.92 84.08,115.25 84.25,115.42 84.34,115.42 84.51,115.58 84.51,115.91 84.34,116.08 83.28,116.08 83.11,116.24 83.11,116.57 83.28,116.74 84.34,116.74 84.51,116.9 84.51,117.23 84.34,117.4 83.2,117.4 83.04,117.56 83.04,117.89 83.2,118.06 84.34,118.06 84.5,118.22 84.5,118.55 84.34,118.72 83.54,118.72 83.37,118.88 83.37,119.21 83.54,119.38 84.34,119.38 84.51,119.54 84.51,120.4 94.95,130.84 94.95,133.12 95.16,133.34 95.17,133.34
M_DATA_A41: length 56.1
  TOP w0.102: 94.49,133.65 94.49,135.22 95.66,136.39 96.26,136.39 U27.AR1
  TOP w0.165: DIMM1.91 80.76,98.75 81.02,98.49 81.02,97.77 80.81,97.56 79.81,97.56 79.09,98.28 79.09,99.58 79.28,99.77 79.7,99.77 79.94,100.02 79.94,100.82 79.58,101.19 79.58,101.63 83.87,105.92 83.87,106.29 83.7,106.45 82.68,106.45 82.51,106.62 82.51,106.95 82.68,107.12 83.7,107.12 83.87,107.28 83.87,107.61 83.7,107.78 82.66,107.78 82.49,107.94 82.49,108.41 82.66,108.57 83.28,108.57 83.43,108.72 83.43,114.93 82.28,116.08 82.28,119.07 94.46,131.25 94.46,133.63 94.49,133.65
M_DATA_A42: length 59.6
  TOP w0.102: U27.AN3 98.02,138.53 97.69,138.86 96.36,138.86 96.19,138.68 94.64,138.68 92.19,136.23
  TOP w0.165: 92.19,136.23 92.19,133.88 81.75,123.44 81.74,123.44 78.59,120.29 78.59,115.82 77.87,115.11 76.09,115.11 74.25,113.27 74.25,110.38 75.73,108.9 77.51,108.9 77.68,108.73 77.68,108.11 77.51,107.94 76.84,107.94 76.67,107.78 76.67,107.44 76.84,107.28 77.58,107.28 77.74,107.11 77.74,106.78 77.58,106.62 76.92,106.62 76.75,106.45 76.75,106.12 76.92,105.95 77.67,105.95 77.84,105.79 77.84,105.44 77.67,105.28 76.69,105.28 76.52,105.11 76.52,104.67 76.65,104.54 76.86,104.54 76.96,104.44 76.96,103.99 75.04,102.07 75.04,101.09 DIMM1.96
M_DATA_A43: length 60.6
  TOP w0.102: U27.AN4 98.77,139.06 96.27,139.06 96.09,138.89 94.13,138.89
  TOP w0.165: DIMM1.97 74.29,99 74.29,102.34 75.86,103.91 75.86,104.95 75.68,105.13 74.91,105.13 74.75,105.29 74.75,105.62 74.91,105.79 75.69,105.79 75.86,105.96 75.86,106.29 75.69,106.45 74.86,106.45 74.7,106.62 74.7,106.95 74.86,107.12 75.68,107.12 75.86,107.29 75.86,107.72 73.29,110.29 73.29,113.22 76.03,115.95 77.35,115.95 77.8,116.4 77.8,120.4 81.48,124.08 81.49,124.08 91.77,134.36 91.77,136.53 94.13,138.89
M_DATA_A44: length 57.3
  TOP w0.102: U27.AR2 97.05,136.26 97.05,135.74 96.65,135.34 96.43,135.34 96.25,135.16 95.7,135.16 95.41,134.87 95.41,132.85 95.42,132.84
  TOP w0.165: DIMM1.209 81.16,94.95 80.95,94.74 80.95,93.83 81.08,93.7 82.93,93.7 83.06,93.83 83.06,95.73 82.93,95.86 82.17,95.86 82.04,95.99 82.04,97.67 81.29,98.43 81.29,99.07 81.81,99.6 81.81,102.06 85.14,105.39 85.14,119.99 93.09,127.94 93.09,127.97 95.44,130.31 95.44,131.55 95.56,131.67 96.39,131.67 96.52,131.8 96.52,132.46 96.39,132.59 95.67,132.59 95.42,132.84
M_DATA_A45: length 58.8
  TOP w0.102: U27.AR4 98.78,137.23 97.13,137.23 96.96,137.05 96.37,137.05 96.23,136.92 96.17,136.89 95.76,136.78 94.25,135.27
  TOP w0.165: 94.25,135.27 94.25,135.01 94.08,134.85 94.08,131.77 81.63,119.31 81.63,115.65 82.79,114.49 82.79,109.72 81.83,108.76 81.83,106.2 82,106.04 82.15,106.04 82.31,105.87 82.31,105.54 82.15,105.38 82,105.38 81.83,105.21 81.83,104.78 78.29,101.23 78.29,100.34 78.81,99.82 78.81,98.39 77.9,97.49 77.9,96.28 78.42,95.77 79.52,95.77 79.69,95.94 79.69,96.16 79.86,96.32 80.19,96.32 80.36,96.16 80.36,95.94 80.53,95.77 80.88,95.77 81.04,95.93 81.04,96.67 DIMM1.210
M_DATA_A46: length 59
  TOP w0.102: 93.02,135.58 93.12,135.68 93.12,135.99 93.14,136.02 95.32,138.2 97.15,138.2 U27.AN2
  TOP w0.165: DIMM1.215 76.04,93.98 76.21,93.82 77.01,93.82 77.17,93.98 77.17,95.55 76.86,95.86 76.41,95.86 75.93,96.34 75.93,97.27 76.8,98.13 76.8,99.33 76.43,99.7 76.42,99.7 76.2,99.92 76.2,101.4 76.85,102.04 76.85,102.42 80.21,105.78 80.21,109.49 81.1,110.37 81.1,113.76 79.93,114.92 79.93,119.83 93.02,132.91 93.02,135.58
M_DATA_A47: length 57.9
  TOP w0.102: 92.24,133.03 92.72,133.51 92.72,135.88 95.27,138.43 96.47,138.43 U27.AN1
  TOP w0.165: DIMM1.216 74.79,96.85 74.35,97.29 74.35,97.79 75.24,98.67 75.24,99.47 75.8,100.03 75.8,102.3 78.95,105.45 78.95,105.72 78.85,105.82 78.64,105.82 78.45,106.02 78.45,106.27 78.63,106.46 79.35,106.46 79.51,106.62 79.51,106.97 79.35,107.14 78.52,107.14 78.36,107.3 78.36,107.64 78.52,107.8 79.39,107.8 79.55,107.97 79.55,108.3 79.39,108.46 78.52,108.46 78.36,108.63 78.36,108.96 78.52,109.13 79.39,109.13 79.55,109.29 79.55,109.73 80.46,110.64 80.46,113.46 79.26,114.67 79.26,120.05 92.24,133.03
M_DATA_A48: length 68.5
  TOP w0.102: U27.AL3 98.07,140.69 97.3,140.69 97.03,140.42 97.03,140.3 96.76,140.03 94.33,140.03 94.3,140.06 94.11,140.06 92.57,138.52 92.29,138.52
  TOP w0.165: DIMM1.99 72.04,101.49 72.23,101.68 72.76,101.68 72.92,101.84 72.92,102.18 72.76,102.34 72.15,102.34 71.99,102.5 71.99,102.84 72.16,103.01 72.72,103.01 72.88,103.17 72.88,103.5 72.72,103.67 72.23,103.67 72.06,103.83 72.06,104.17 72.23,104.33 72.76,104.33 72.92,104.5 72.92,104.83 72.76,104.99 72.23,104.99 72.11,105.11 72.11,105.56 72.28,105.72 72.83,105.72 72.99,105.89 72.99,106.22 72.83,106.38 72.28,106.38 72.11,106.55 72.11,106.88 72.28,107.04 72.85,107.04 73.02,107.21 73.02,107.54 72.85,107.7 72.28,107.7 71.96,108.02 71.96,114.77 72.12,114.94 73.22,114.94 73.38,115.1 73.38,115.47 73.25,115.6 72.12,115.6 71.96,115.77 71.96,116.51 72.81,117.37 73.05,117.37 74.23,116.18 74.46,116.18 74.7,116.42 74.7,116.65 73.51,117.83 73.51,118.07 90.97,135.52 90.97,136.96 91.42,137.41 91.46,137.41 92.17,138.12 92.17,138.39 92.29,138.52
M_DATA_A49: length 66
  TOP w0.102: U27.AL1 93.93,140.36 92.72,139.15 92.44,139.15
  TOP w0.165: DIMM1.100 71.32,100.93 71.32,102.73 71.16,102.89 70.66,102.89 70.54,103.02 70.54,103.43 70.66,103.56 71.16,103.56 71.32,103.72 71.32,104.05 71.16,104.22 70.62,104.22 70.46,104.38 70.46,104.71 70.62,104.88 71.16,104.88 71.32,105.04 71.32,105.37 71.16,105.54 70.62,105.54 70.46,105.7 70.46,106.03 70.62,106.2 71.16,106.2 71.32,106.36 71.32,106.69 71.16,106.86 70.62,106.86 70.46,107.02 70.46,107.35 70.62,107.52 71.16,107.52 71.32,107.68 71.32,108.01 71.16,108.18 70.62,108.18 70.46,108.34 70.46,108.67 70.62,108.84 71.16,108.84 71.32,109 71.32,109.33 71.16,109.5 70.62,109.5 70.46,109.66 70.46,109.99 70.62,110.16 71.16,110.16 71.32,110.32 71.32,110.65 71.16,110.82 70.62,110.82 70.46,110.98 70.46,111.31 70.62,111.48 71.16,111.48 71.32,111.64 71.32,111.98 71.16,112.14 70.62,112.14 70.46,112.31 70.46,112.64 70.62,112.8 71.16,112.8 71.32,112.97 71.32,113.95 71.16,114.12 70.51,114.12 70.38,114.24 70.38,114.65 70.51,114.78 71.16,114.78 71.32,114.94 71.32,116.77 79.85,125.3 79.85,125.54 79.85,125.62 80.16,125.93 80.39,125.93 80.48,125.93 80.79,126.24 80.79,126.47 80.79,126.56 81.09,126.86 81.33,126.86 81.41,126.86 81.72,127.17 81.72,127.4 81.72,127.49 82.03,127.8 82.26,127.8 82.35,127.8 82.66,128.11 82.66,128.34 82.66,128.43 82.96,128.73 83.2,128.73 83.28,128.73 83.59,129.04 83.59,129.27 83.59,129.36 83.9,129.67 84.13,129.67 84.22,129.67 84.52,129.97 84.52,130.21 84.52,130.29 84.83,130.6 85.06,130.6 85.15,130.6 85.46,130.91 85.46,131.14 85.46,131.23 85.77,131.54 86,131.54 86.09,131.54 86.39,131.84 86.39,132.08 86.39,132.16 86.7,132.47 86.93,132.47 87.02,132.47 87.33,132.78 87.33,133.01 87.33,133.1 87.63,133.4 87.87,133.4 87.95,133.4 90.33,135.78 90.33,137.36 92.13,139.15 92.44,139.15
M_DATA_A50: length 68.6
  TOP w0.102: U27.AJ3 98.04,142.54 96.37,142.54 96.24,142.41 95.26,142.41 95.05,142.62 92.64,142.62 92.46,142.44
  TOP w0.165: DIMM1.105 66.04,98.32 66.04,97.99 65.92,97.87 65.15,97.87 65.02,97.99 65.02,98.93 65.86,99.77 65.86,101.98 65.74,102.1 65.66,102.1 65.53,102.23 65.53,103.75 65.48,103.8 65.48,112.15 65.32,112.31 64.86,112.31 64.69,112.48 64.69,112.81 64.86,112.98 65.32,112.98 65.48,113.14 65.48,113.47 65.32,113.64 64.86,113.64 64.69,113.8 64.69,114.13 64.86,114.3 65.32,114.3 65.48,114.46 65.48,114.79 65.32,114.96 64.86,114.96 64.69,115.12 64.69,115.45 64.86,115.62 65.32,115.62 65.48,115.78 65.48,116.57 91.35,142.44 92.46,142.44
M_DATA_A51: length 68.6
  TOP w0.102: U27.AJ4 98.77,142.73 98.25,142.73 98.23,142.74 96.2,142.74 96.07,142.62 95.74,142.62 95.38,142.98 91,142.98
  TOP w0.165: 91,142.98 64.06,116.05 64.06,111.81 64.19,111.68 64.72,111.68 64.85,111.55 64.85,111.12 64.72,111 64.19,111 64.06,110.87 64.06,110.44 64.19,110.31 64.72,110.31 64.85,110.19 64.85,109.8 64.72,109.68 64.19,109.68 64.06,109.55 64.06,109.14 64.19,109.02 64.72,109.02 64.85,108.89 64.85,101.68 64.72,101.55 64.34,101.55 64.21,101.42 64.21,99.77 64.34,99.64 64.92,99.64 65.04,99.77 65.04,100.13 65.04,100.13 DIMM1.106
M_DATA_A52: length 67.5
  TOP w0.102: U27.AL2 97.4,140.36 96.87,139.82 94.2,139.82 91.53,137.15
  TOP w0.165: DIMM1.218 72.6,96.42 72.6,96.03 72.77,95.86 73.86,95.86 74.07,96.07 74.07,97.48 73.81,97.74 73.41,97.74 73.29,97.87 73.29,99.07 73.8,99.58 73.8,100.97 73.65,101.11 73.65,107.42 73.82,107.58 74.33,107.58 74.49,107.75 74.49,108.08 74.33,108.25 73.82,108.25 73.65,108.41 73.65,108.95 72.66,109.94 72.66,113.48 75.77,116.59 75.77,116.59 75.82,116.64 77.04,116.64 77.17,116.76 77.17,118.77 77.04,118.9 76.4,118.9 76.28,118.77 76.28,117.42 76.15,117.3 75.54,117.3 75.41,117.42 75.41,118.98 81.16,124.71 81.23,124.71 91.23,134.72 91.23,136.85 91.53,137.15
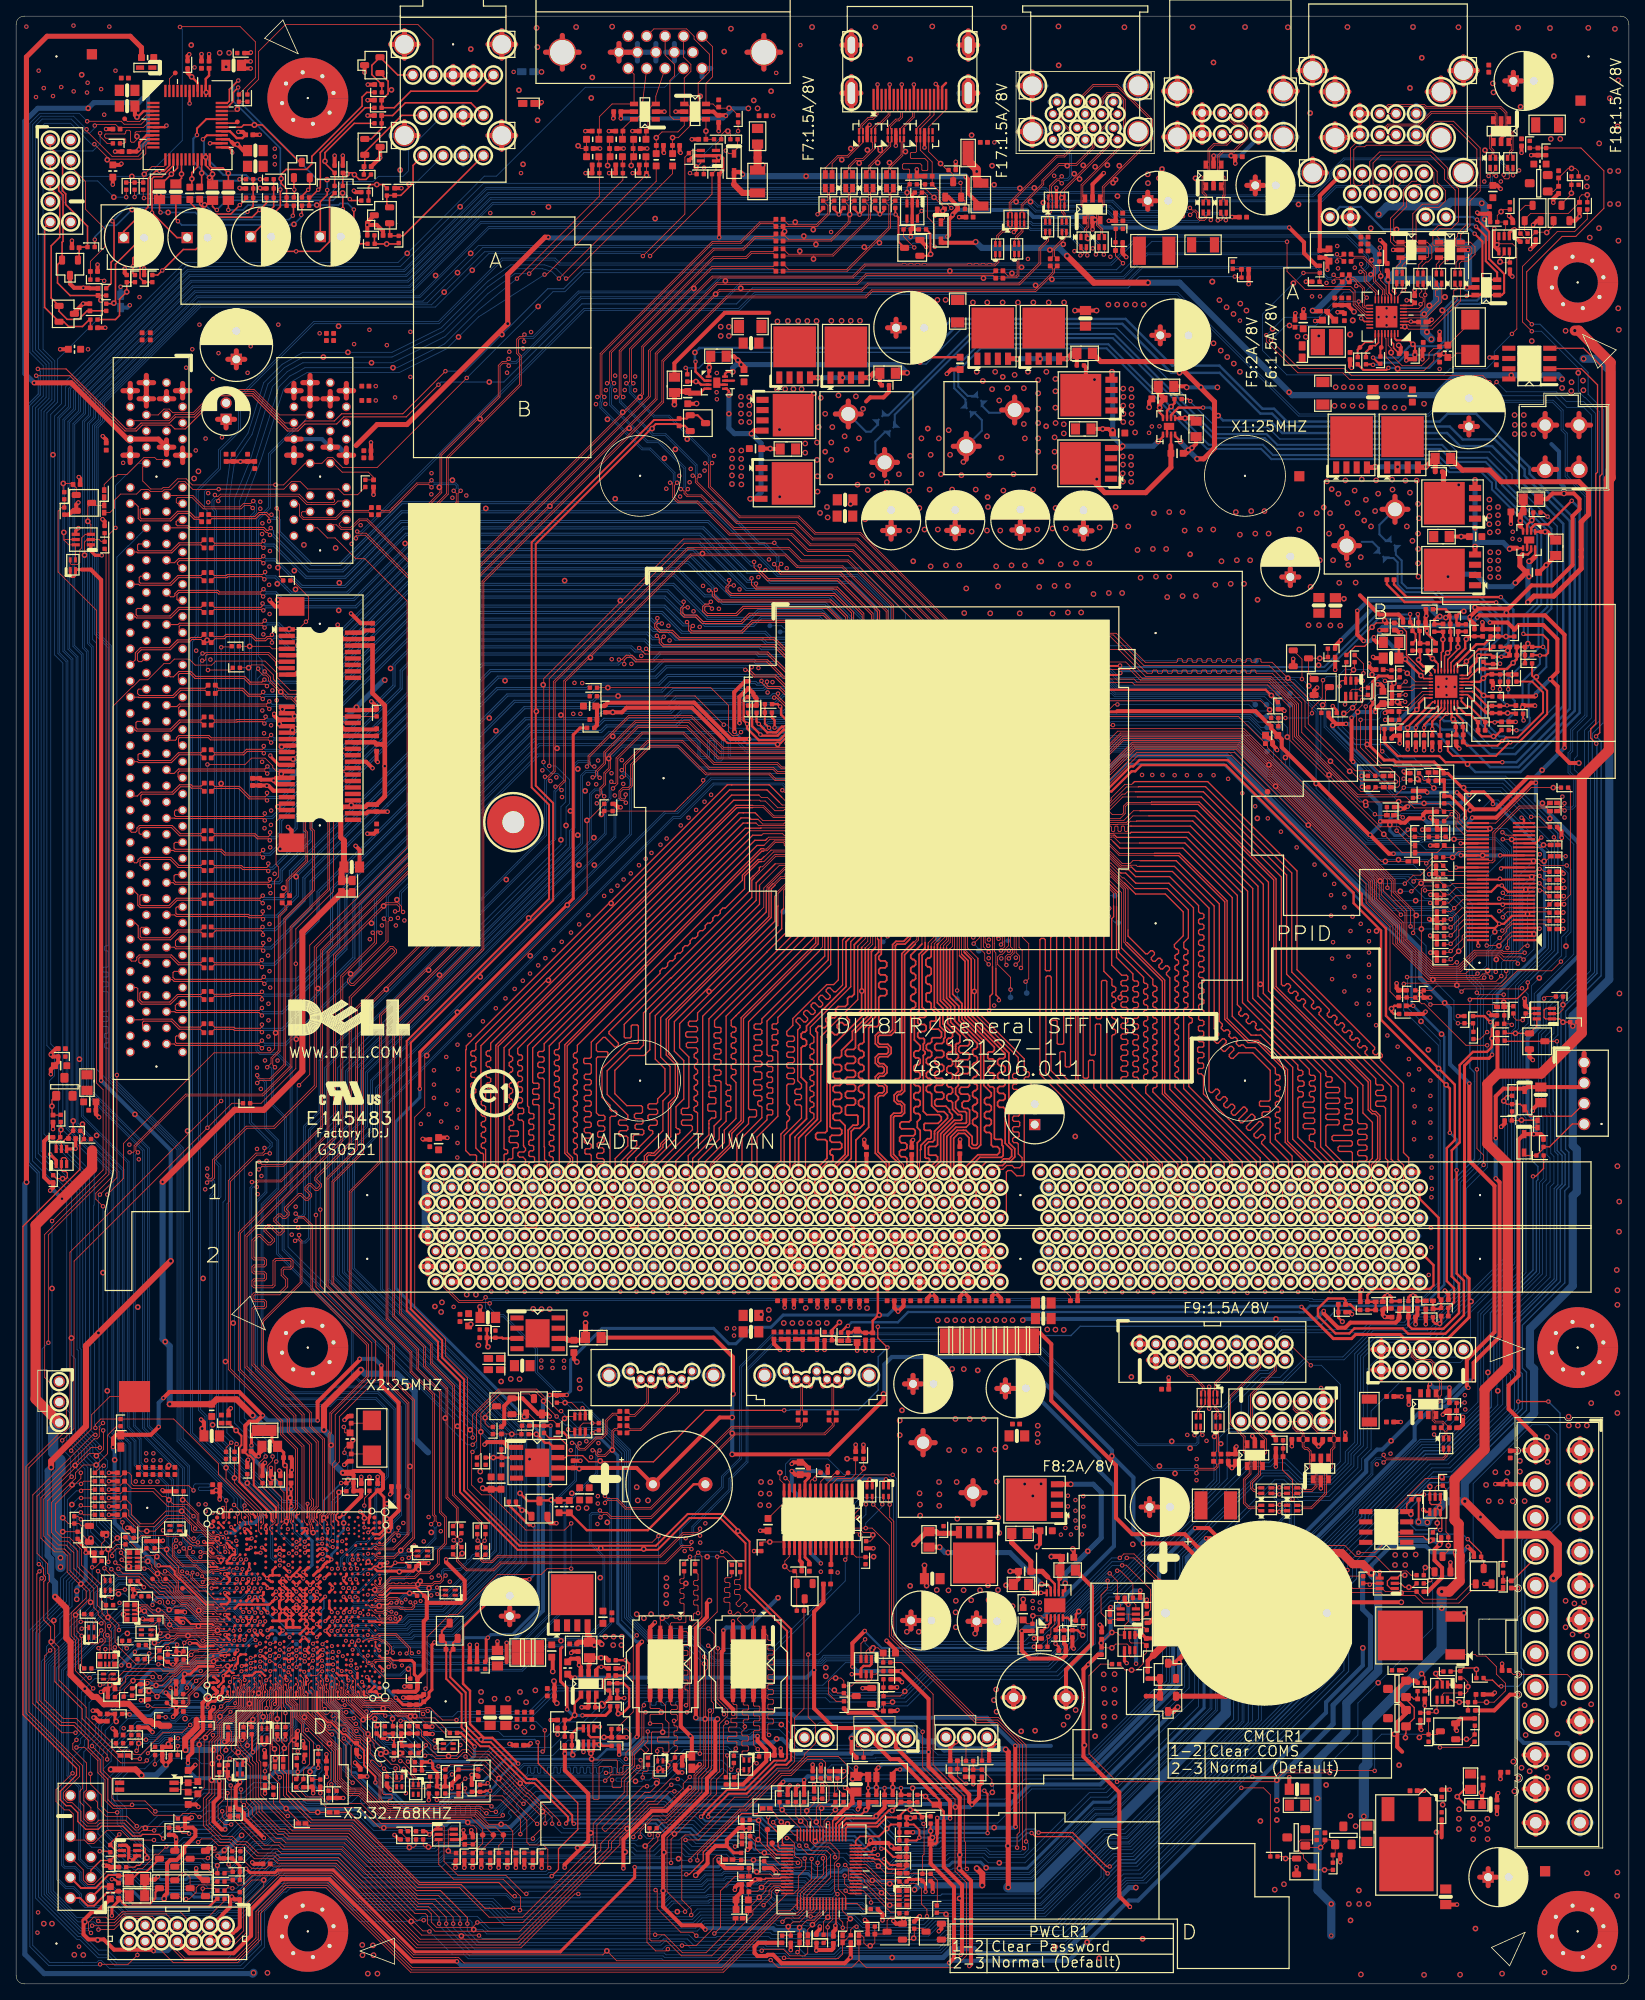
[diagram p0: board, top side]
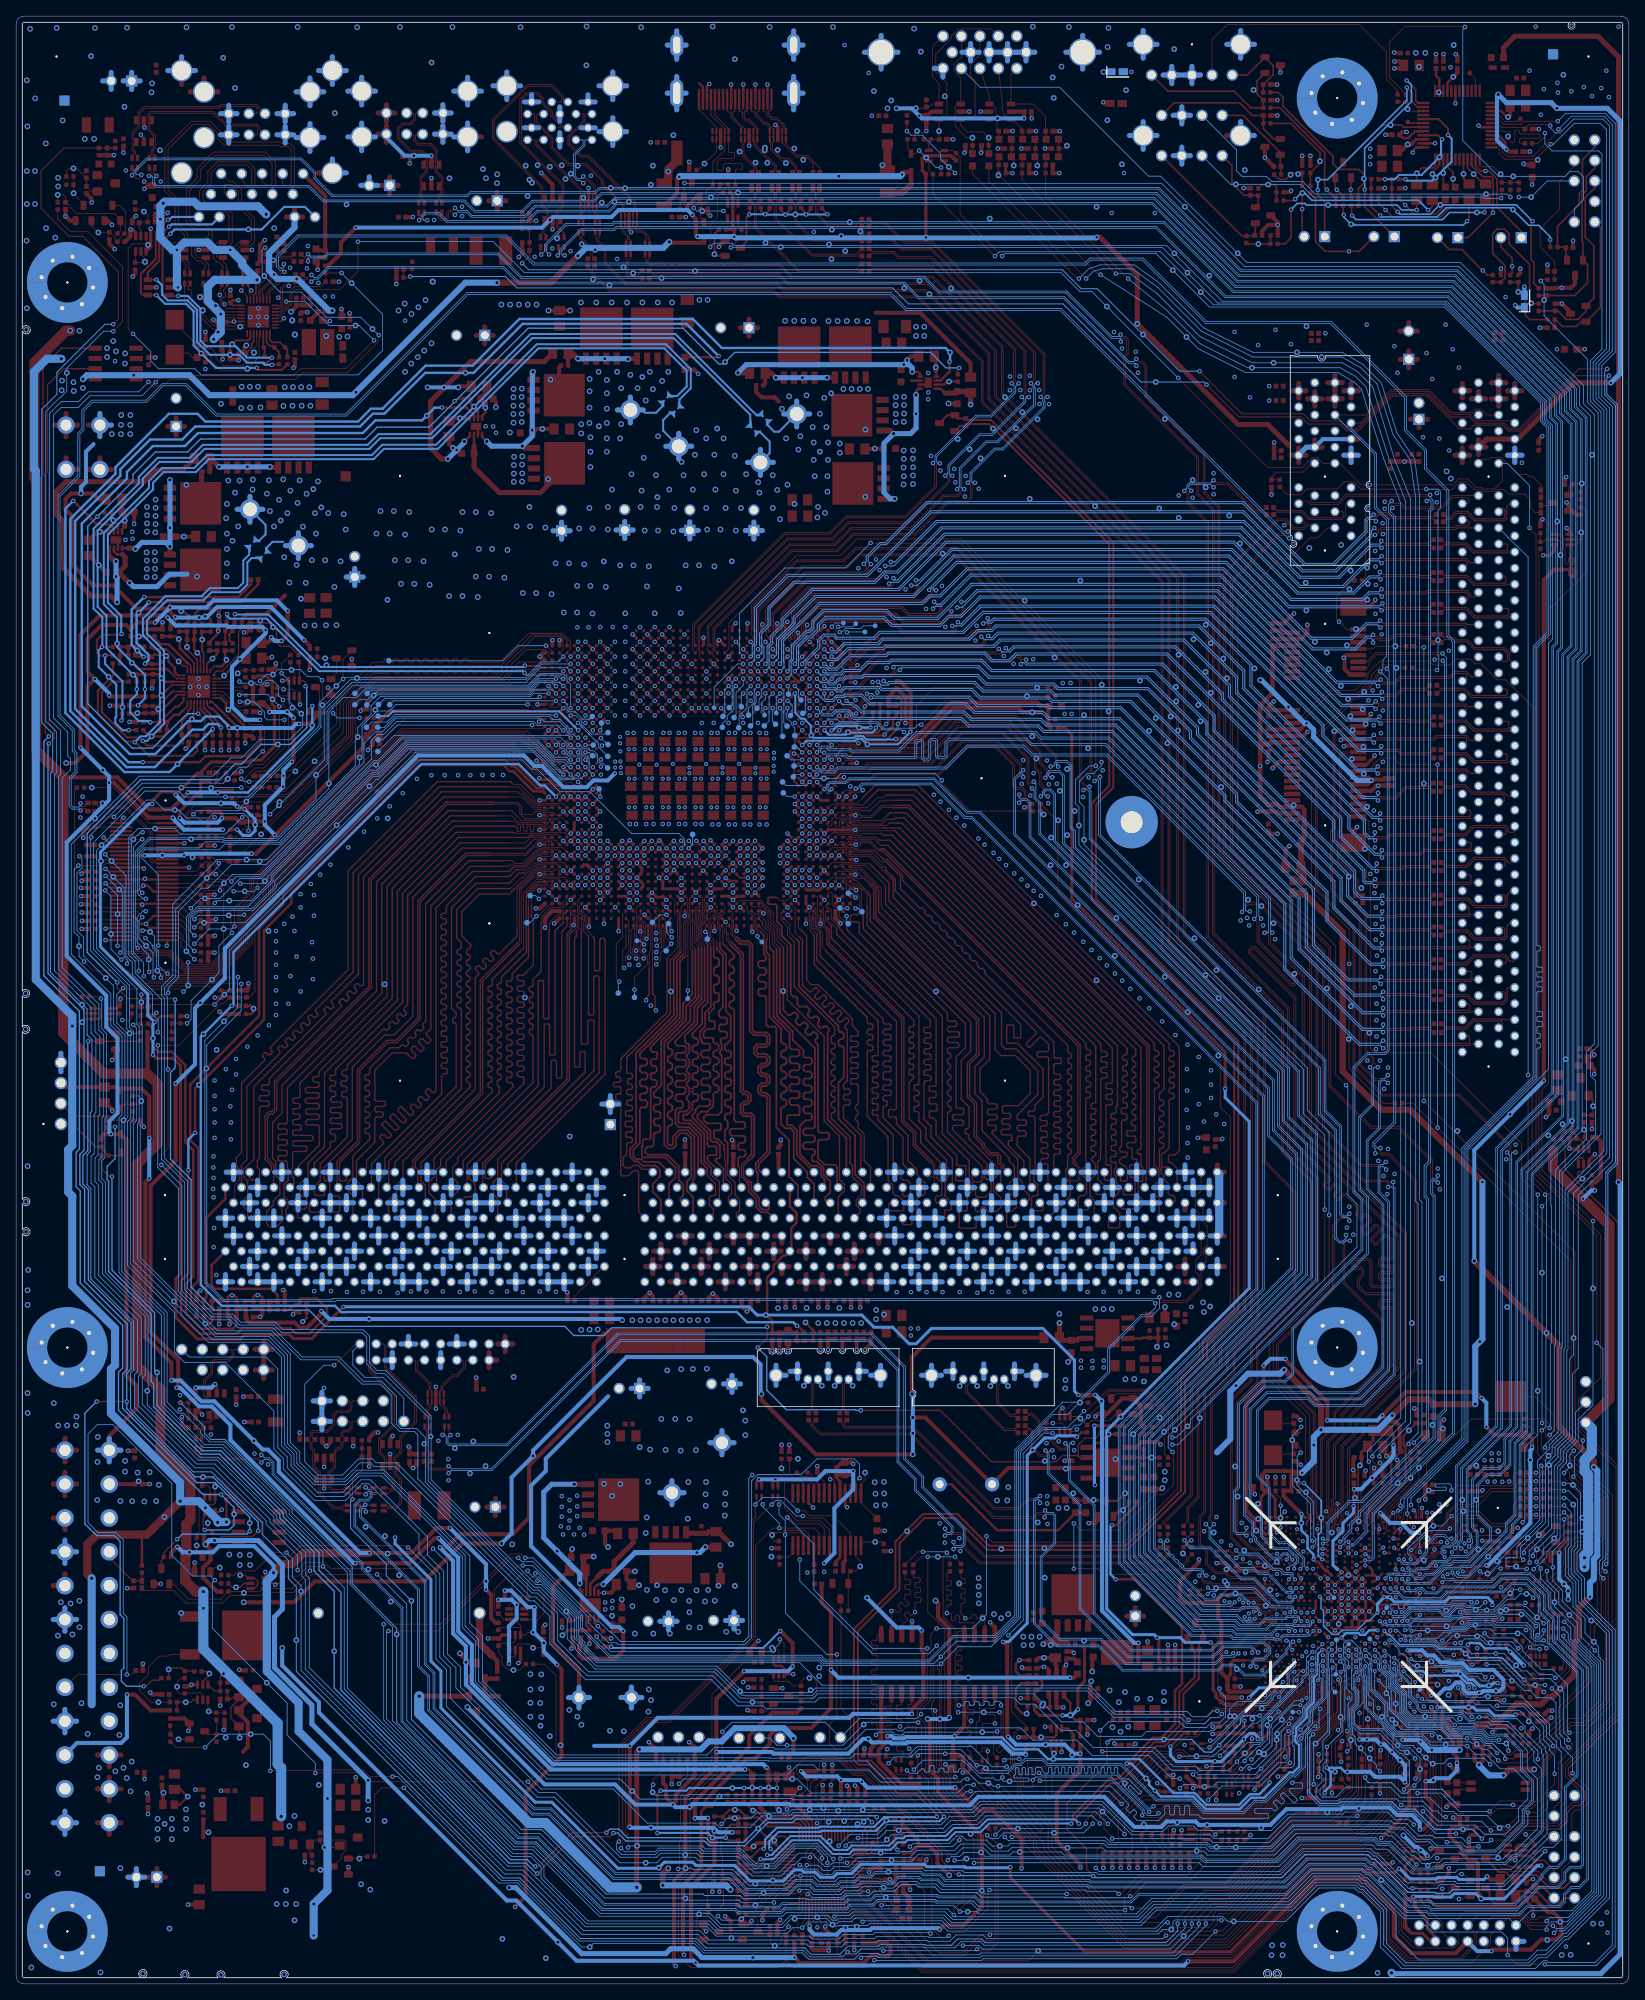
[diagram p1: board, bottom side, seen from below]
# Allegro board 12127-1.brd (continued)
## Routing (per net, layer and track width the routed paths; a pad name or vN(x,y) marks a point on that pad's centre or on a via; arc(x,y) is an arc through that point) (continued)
M_DATA_A53: length 69.1
  TOP w0.102: U27.AL4 98.78,140.89 97.16,140.89 96.98,140.71 96.45,140.71 96.14,140.59 93.62,140.59 92.84,139.8 92.79,139.8
  TOP w0.165: DIMM1.219 71.36,95.64 70.9,96.1 70.73,96.1 70.29,96.54 70.29,96.71 69.29,97.71 69.29,99.32 69.56,99.6 69.8,99.83 69.8,100.97 69.6,101.17 69.6,102.73 69.43,102.9 69.32,102.9 69.19,103.02 69.19,103.43 69.32,103.56 69.43,103.56 69.6,103.72 69.6,104.05 69.43,104.22 69.28,104.22 69.11,104.38 69.11,104.71 69.28,104.88 69.43,104.88 69.6,105.04 69.6,105.37 69.43,105.54 69.28,105.54 69.11,105.7 69.11,106.03 69.28,106.2 69.43,106.2 69.6,106.36 69.6,106.69 69.43,106.86 69.28,106.86 69.11,107.03 69.11,107.36 69.28,107.52 69.43,107.52 69.6,107.69 69.6,108.02 69.43,108.18 69.28,108.18 69.11,108.35 69.11,108.68 69.28,108.84 69.43,108.84 69.6,109.01 69.6,109.34 69.43,109.5 69.28,109.5 69.11,109.67 69.11,110 69.28,110.16 69.43,110.16 69.6,110.33 69.6,110.66 69.43,110.82 69.28,110.82 69.11,110.99 69.11,111.32 69.28,111.48 69.43,111.48 69.6,111.65 69.6,111.98 69.43,112.14 69.28,112.14 69.11,112.31 69.11,112.64 69.28,112.8 69.43,112.8 69.6,112.97 69.6,113.3 69.43,113.46 69.28,113.46 69.11,113.63 69.11,113.96 69.28,114.12 69.43,114.12 69.6,114.29 69.6,114.62 69.43,114.78 69.28,114.78 69.11,114.95 69.11,115.28 69.28,115.45 69.43,115.45 69.6,115.61 69.6,116.38 90.07,136.85 90.07,137.47 92.02,139.42 92.4,139.42 92.79,139.8
M_DATA_A54: length 68.7
  TOP w0.102: 92.73,141.17 93.49,141.93 96.27,141.93 96.35,141.85 96.82,141.85 97.16,142.18 U27.AJ2
  TOP w0.165: 92.73,141.17 91.88,141.17 67.36,116.65 67.36,116.01 67.19,115.85 66.92,115.85 66.75,115.68 66.75,115.35 66.92,115.19 67.19,115.19 67.36,115.02 67.36,114.69 67.19,114.53 66.92,114.53 66.75,114.36 66.75,114.03 66.92,113.87 67.19,113.87 67.36,113.7 67.36,113.37 67.19,113.21 66.92,113.21 66.75,113.04 66.75,112.71 66.92,112.55 67.19,112.55 67.36,112.38 67.36,112.05 67.19,111.88 66.92,111.88 66.75,111.72 66.75,111.39 66.92,111.22 67.19,111.22 67.36,111.06 67.36,110.73 67.19,110.56 66.92,110.56 66.75,110.4 66.75,110.07 66.92,109.9 67.19,109.9 67.36,109.74 67.36,101.41 67.8,100.97 67.8,100.34 67.26,99.8 67.26,98.02 67.54,97.74 68.02,97.74 68.28,97.49 68.28,96.09 68.15,95.96 67.17,95.96 67.04,96.09 DIMM1.224
M_DATA_A55: length 67.8
  TOP w0.102: 93.12,141.99 93.32,142.18 95.37,142.18 95.38,142.19 96.56,142.19 U27.AJ1
  TOP w0.14: DIMM1.225 66.29,95.2 66.29,97.17 66.35,97.23
  TOP w0.165: 93.12,141.99 92.93,141.8 91.61,141.8 66.12,116.31 66.12,109.35 66.28,109.19 66.55,109.19 66.67,109.06 66.67,108.65 66.55,108.53 66.28,108.53 66.12,108.36 66.12,108.03 66.28,107.86 66.62,107.86 66.72,107.77 66.72,107.3 66.62,107.2 66.28,107.2 66.12,107.04 66.12,106.71 66.28,106.54 66.6,106.54 66.72,106.42 66.72,106.01 66.6,105.88 66.28,105.88 66.12,105.72 66.12,105.39 66.28,105.22 66.55,105.22 66.67,105.1 66.67,104.69 66.55,104.56 66.28,104.56 66.12,104.4 66.12,104.07 66.28,103.9 66.57,103.9 66.7,103.78 66.7,103.37 66.57,103.24 66.28,103.24 66.12,103.08 66.12,102.75 66.28,102.58 66.44,102.58 66.6,102.42 66.6,102.09 66.13,101.61 66.13,100.34 66.84,99.63 66.84,97.72 66.35,97.23
M_DATA_A56: length 75.3
  TOP w0.102: 91.74,143.94 92.07,143.62 95.45,143.62 95.61,143.79 96.24,143.79 96.37,143.66 96.81,143.66 96.98,143.82 96.98,144.06 97.29,144.37 97.68,144.37 97.89,144.16 97.89,143.62 98.04,143.47 98.25,143.47 98.4,143.62 U27.AG3
  TOP w0.165: DIMM1.108 63.04,100.08 63.04,99.67 62.92,99.54 62.33,99.54 62.2,99.67 62.2,101.07 62.62,101.49 62.8,101.49 63.17,101.85 63.17,102.21 62.87,102.51 62.43,102.51 62.23,102.72 62.23,103 62.38,103.15 62.97,103.15 63.17,103.35 63.17,103.61 62.95,103.83 62.95,103.92 62.92,103.95 62.92,106.91 62.71,107.11 62.38,107.11 62.26,107.24 62.26,107.77 62.38,107.9 62.81,107.9 62.94,108.03 62.94,108.46 62.81,108.58 62.37,108.58 62.2,108.75 62.2,109.08 62.37,109.24 62.62,109.24 62.79,109.41 62.79,109.74 62.62,109.9 62.37,109.9 62.2,110.07 62.2,110.4 62.37,110.56 62.62,110.56 62.79,110.73 62.79,111.06 62.62,111.22 62.37,111.22 62.2,111.39 62.2,111.72 62.37,111.89 62.62,111.89 62.79,112.05 62.79,112.38 62.62,112.55 62.37,112.55 62.2,112.71 62.2,113.04 62.37,113.21 62.62,113.21 62.79,113.37 62.79,113.7 62.62,113.87 62.37,113.87 62.2,114.03 62.2,114.36 62.37,114.53 62.62,114.53 62.79,114.69 62.79,115.02 62.62,115.19 62.37,115.19 62.2,115.35 62.2,115.99 90.16,143.94 90.69,143.94 90.69,143.94 91.74,143.94
M_DATA_A57: length 77
  TOP w0.102: U27.AG1 95.36,144.01 95.17,143.82 92.58,143.82 92,144.4
  TOP w0.165: DIMM1.109 62.44,98.75 62.71,98.48 62.71,97.97 62.59,97.84 61.37,97.84 61.24,97.97 61.24,99.78 61.48,100.02 61.75,100.02 61.87,100.15 61.87,101.44 61.75,101.56 61.11,101.56 60.99,101.69 60.99,102.16 61.11,102.29 61.47,102.29 61.59,102.41 61.59,103.56 61.72,103.68 62.15,103.68 62.28,103.81 62.28,104.11 62.08,104.32 61.27,104.32 61.14,104.44 61.14,104.95 61.31,105.12 62.15,105.12 62.28,105.24 62.28,105.65 62.15,105.78 61.31,105.78 61.14,105.94 61.14,106.27 61.31,106.44 61.57,106.44 61.7,106.57 61.7,106.9 61.5,107.1 61.31,107.1 61.14,107.26 61.14,107.59 61.31,107.76 61.4,107.76 61.57,107.92 61.57,108.25 61.4,108.42 61.31,108.42 61.14,108.58 61.14,108.92 61.31,109.08 61.4,109.08 61.57,109.25 61.57,109.58 61.4,109.74 61.31,109.74 61.14,109.91 61.14,110.24 61.31,110.4 61.4,110.4 61.57,110.57 61.57,110.9 61.4,111.06 61.31,111.06 61.14,111.23 61.14,111.56 61.31,111.72 61.4,111.72 61.57,111.89 61.57,112.22 61.4,112.38 61.31,112.38 61.14,112.55 61.14,112.88 61.31,113.04 61.4,113.04 61.57,113.21 61.57,113.54 61.4,113.7 61.31,113.7 61.14,113.87 61.14,114.2 61.31,114.36 61.4,114.36 61.57,114.53 61.57,114.86 61.4,115.02 61.31,115.02 61.14,115.19 61.14,115.82 89.9,144.58 90.95,144.58 91.13,144.4 92,144.4
M_DATA_A58: length 76.8
  TOP w0.102: 94.65,146.52 95,146.18 98.06,146.18 U27.AE3
  TOP w0.165: 94.65,146.52 93.13,148.05 88.46,148.05 57.01,116.59 57.01,115.86 56.84,115.7 56.55,115.7 56.39,115.53 56.39,115.2 56.55,115.04 56.84,115.04 57.01,114.87 57.01,114.54 56.84,114.38 56.55,114.38 56.39,114.21 56.39,113.88 56.55,113.72 56.84,113.72 57.01,113.55 57.01,113.22 56.84,113.06 56.55,113.06 56.39,112.89 56.39,112.56 56.55,112.4 56.84,112.4 57.01,112.23 57.01,111.9 56.84,111.74 56.55,111.74 56.39,111.57 56.39,111.24 56.55,111.08 56.84,111.08 57.01,110.91 57.01,110.58 56.84,110.42 56.55,110.42 56.39,110.25 56.39,109.92 56.55,109.76 56.84,109.76 57.01,109.59 57.01,103.65 57.66,102.99 57.83,102.99 57.95,102.87 57.95,101.4 57.83,101.27 57.17,101.27 57.04,101.14 57.04,100.89 DIMM1.114
M_DATA_A59: length 77.2
  TOP w0.102: 94.95,147.14 95.68,146.4 98.23,146.4 98.4,146.23 98.93,146.23 U27.AE4
  TOP w0.165: 94.95,147.14 93.4,148.68 88.72,148.68 88.72,148.68 88.2,148.68 55.83,116.31 55.83,115.87 55.75,115.8 55.75,103.33 56.29,102.79 56.97,102.79 57.1,102.67 57.1,101.98 56.97,101.85 56.74,101.85 56.04,101.15 56.04,98.75 DIMM1.115
M_DATA_A60: length 76.9
  TOP w0.102: 92.37,143.34 95.46,143.34 95.7,143.58 96.12,143.58 96.25,143.45 97.46,143.45 97.59,143.58 97.59,143.91 U27.AG2
  TOP w0.165: 92.37,143.34 92.34,143.31 90.42,143.31 63.42,116.31 63.42,108.88 63.58,108.72 63.58,108.09 63.75,107.92 64.08,107.92 64.21,107.79 64.21,107.39 64.08,107.26 63.75,107.26 63.58,107.09 63.58,106.76 63.75,106.6 64.06,106.6 64.19,106.47 64.19,106.07 64.06,105.94 63.75,105.94 63.58,105.77 63.58,105.38 63.71,105.26 64.06,105.26 64.19,105.13 64.19,104.75 64.06,104.62 63.75,104.62 63.58,104.45 63.58,104.09 63.71,103.96 64.06,103.96 64.19,103.84 64.19,103.42 64.06,103.3 63.75,103.3 63.58,103.13 63.58,102.72 63.71,102.59 64.16,102.59 64.29,102.46 64.29,102.01 64.16,101.88 63.71,101.88 63.58,101.75 63.58,101.18 63.8,100.97 63.8,100.34 63.58,100.12 63.58,99.36 63.28,99.07 63.28,98.11 63.93,97.46 63.93,96.39 63.14,95.61 63.14,93.88 63.27,93.75 64.41,93.75 64.54,93.88 64.54,94.45 DIMM1.227
M_DATA_A61: length 77.3
  TOP w0.102: U27.AG4 99.34,144.01 99.47,143.89 99.47,143.71 99.34,143.59 98.96,143.59 98.83,143.71 98.83,144.43 98.7,144.56 98.25,144.56 98.23,144.57 97.2,144.57 96.97,144.34 96.38,144.34 96.28,144.24 92.61,144.24 91.97,144.88
  TOP w0.165: 91.97,144.88 91.64,145.21 90.16,145.21 89.63,145.21 60.51,116.09 60.51,103.58 60.64,103.45 60.83,103.45 60.96,103.32 60.96,103.04 60.83,102.92 60.64,102.92 60.51,102.79 60.51,101.43 60.29,101.21 60.29,99.64 60.41,99.52 60.73,99.52 60.86,99.39 60.86,97.74 60.73,97.61 60.73,97.61 60.29,97.17 60.29,96.54 60.73,96.1 62.82,96.1 63.04,96.32 DIMM1.228
M_DATA_A62: length 77.3
  TOP w0.102: U27.AE2 97.48,145.84 97.12,145.84 96.77,145.49 96.37,145.49 96.24,145.61 95.29,145.61 95.15,145.47 94.1,145.47 92.9,146.67 92.31,146.67 92.21,146.78 91.05,146.78
  TOP w0.165: 91.05,146.78 88.99,146.78 58.85,116.64 58.85,115.86 58.69,115.7 58.46,115.7 58.29,115.53 58.29,115.2 58.46,115.04 58.69,115.04 58.85,114.87 58.85,114.54 58.69,114.38 58.46,114.38 58.29,114.21 58.29,113.88 58.46,113.72 58.69,113.72 58.85,113.55 58.85,113.22 58.69,113.06 58.46,113.06 58.29,112.89 58.29,112.56 58.46,112.4 58.69,112.4 58.85,112.23 58.85,111.9 58.69,111.74 58.46,111.74 58.29,111.57 58.29,111.24 58.46,111.08 58.69,111.08 58.85,110.91 58.85,101.53 58.29,100.97 58.29,100.87 58.28,100.86 58.28,99.59 58.8,99.07 58.8,97.93 58.27,97.39 58.27,95.18 DIMM1.233
M_DATA_A63: length 77.2
  TOP w0.102: U27.AE1 94.45,145.84 93.18,147.11 92.42,147.11 92.11,147.41
  TOP w0.165: DIMM1.234 56.52,96.85 56.31,97.06 56.31,97.56 56.52,97.76 56.92,97.76 57.12,97.97 57.12,99.21 57.64,99.73 57.64,100.19 58.01,100.55 58.01,101.07 58.22,101.28 58.22,103.46 58.05,103.63 57.85,103.63 57.68,103.79 57.68,104.12 57.85,104.29 58.05,104.29 58.22,104.45 58.22,104.78 58.05,104.95 57.85,104.95 57.68,105.11 57.68,105.44 57.85,105.61 58.05,105.61 58.22,105.77 58.22,106.1 58.05,106.27 57.85,106.27 57.68,106.43 57.68,106.76 57.85,106.93 58.05,106.93 58.22,107.09 58.22,107.42 58.05,107.59 57.85,107.59 57.68,107.76 57.68,108.09 57.85,108.25 58.05,108.25 58.22,108.42 58.22,108.75 58.05,108.91 57.85,108.91 57.68,109.08 57.68,109.41 57.85,109.57 58.05,109.57 58.22,109.74 58.22,110.37 57.64,110.95 57.64,116.33 88.72,147.41 92.11,147.41
M_DATA_B0: length 91
  TOP w0.14: U27.AE34 v1(129.4,145.39)
  L3 w0.102: 135.28,146.28 135.16,146.15 130.83,146.15 130.53,145.84 129.86,145.84 v1(129.4,145.39)
  L3 w0.152: DIMM2.3 172.04,91.62 171.8,91.87 171.8,93.56 171.26,94.09 171.26,95.3 172.26,96.29 172.26,97.41 171.29,98.38 171.29,99.28 172.05,100.04 172.05,101.61 165.32,108.34 165.32,109.62 165.47,109.78 165.57,109.78 165.73,109.93 165.73,110.27 165.57,110.43 165.47,110.43 165.32,110.58 165.32,110.92 165.47,111.08 165.57,111.08 165.73,111.23 165.73,111.58 165.57,111.73 165.47,111.73 165.32,111.88 165.32,112.23 165.47,112.38 165.57,112.38 165.73,112.53 165.73,112.88 165.57,113.03 165.47,113.03 165.32,113.18 165.32,113.6 165.07,113.85 164.84,113.85 164.68,114 164.68,114.35 164.84,114.5 165.17,114.5 165.32,114.65 165.32,115 165.17,115.15 164.84,115.15 164.68,115.3 164.68,115.65 164.84,115.8 165.17,115.8 165.32,115.95 165.32,116.24 160.34,121.22 160.34,133.96 146.28,148.02 137.02,148.02 135.28,146.28
M_DATA_B1: length 91.8
  TOP w0.14: U27.AE35 v1(130.32,145.39)
  L3 w0.102: v1(130.32,145.39) 130.54,145.39 131.1,145.95 135.37,145.95 135.65,146.23
  L3 w0.152: 135.65,146.23 136.8,147.37 146.01,147.37 159.69,133.69 159.69,120.9 162.73,117.86 162.73,113.53 162.86,113.4 163.26,113.4 163.38,113.53 163.38,116.54 163.51,116.67 163.91,116.67 164.03,116.54 164.03,113.35 164.67,112.72 164.67,108.07 165.06,107.68 165.06,107.46 165.01,107.42 165.01,107.2 165.26,106.96 165.47,106.96 165.52,107 165.74,107 165.98,106.76 165.98,106.54 165.93,106.5 165.93,106.28 166.18,106.04 166.39,106.04 166.44,106.08 166.66,106.08 166.9,105.84 166.9,105.62 166.85,105.58 166.85,105.36 167.1,105.12 167.31,105.12 167.36,105.16 167.58,105.16 171.79,100.95 171.79,100.15 171.04,99.39 171.04,98.27 172,97.31 172,96.39 171.01,95.4 171.01,93.98 171.04,93.96 171.04,92.76 DIMM2.4
M_DATA_B2: length 92.5
  TOP w0.14: v1(129.4,142.64) U27.AG35
  L3 w0.102: 136.22,143.89 134.47,143.89 133.66,143.08 131.75,143.08 131.52,143.31 130.07,143.31 v1(129.4,142.64)
  L3 w0.152: DIMM2.9 165.85,91.04 165.85,93.62 165.19,94.28 165.19,95.27 166.26,96.34 166.26,97.38 166.79,97.91 166.79,99.26 166.06,100 166.06,102.03 159.85,108.24 159.85,114.84 158.3,116.39 158.3,116.57 158.58,116.85 158.76,116.85 159.36,116.26 159.54,116.26 159.82,116.54 159.82,116.72 155.15,121.38 155.15,122.18 155.31,122.33 155.68,122.33 155.84,122.48 155.84,122.83 155.68,122.98 155.31,122.98 155.15,123.13 155.15,123.48 155.31,123.63 155.68,123.63 155.84,123.78 155.84,124.13 155.68,124.28 155.31,124.28 155.15,124.43 155.15,124.78 155.31,124.93 155.68,124.93 155.84,125.09 155.84,125.43 155.68,125.58 155.31,125.58 155.15,125.74 155.15,126.08 155.31,126.23 155.68,126.23 155.84,126.39 155.84,126.73 155.68,126.88 155.31,126.88 155.15,127.04 155.15,127.38 155.31,127.53 155.68,127.53 155.84,127.69 155.84,128.03 155.68,128.18 155.31,128.18 155.15,128.34 155.15,128.68 155.31,128.83 155.68,128.83 155.84,128.99 155.84,129.33 155.68,129.48 155.31,129.48 155.15,129.64 155.15,129.98 155.31,130.13 155.68,130.13 155.84,130.29 155.84,130.63 155.68,130.78 155.31,130.78 155.15,130.94 155.15,131.28 155.31,131.44 155.68,131.44 155.84,131.59 155.84,131.93 155.68,132.09 155.31,132.09 155.15,132.24 155.15,132.58 155.31,132.74 155.68,132.74 155.84,132.89 155.84,133.23 155.68,133.39 155.31,133.39 155.15,133.54 155.15,134.14 144.79,144.5 136.83,144.5 136.22,143.89
M_DATA_B3: length 91.2
  TOP w0.14: v1(130.32,142.64) U27.AH35
  L3 w0.102: 136.72,143.85 136.41,143.54 134.76,143.54 134.09,142.88 131.63,142.88 131.4,143.1 130.78,143.1 v1(130.32,142.64)
  L3 w0.152: DIMM2.10 165.04,93.45 164.94,93.56 164.94,95.38 166.01,96.44 166.01,97.36 165.27,98.09 165.27,99.31 165.79,99.83 165.79,101.36 159.2,107.95 159.2,114.58 154.37,119.41 154.37,119.59 154.65,119.87 154.83,119.87 157.66,117.03 157.84,117.03 158.12,117.31 158.12,117.49 154.35,121.26 154.35,125.61 153.85,126.11 153.85,126.59 154.01,126.74 154.36,126.74 154.49,126.87 154.49,127.27 154.36,127.39 154.01,127.39 153.85,127.55 153.85,127.89 154.01,128.04 154.37,128.04 154.49,128.17 154.49,128.57 154.37,128.69 154.01,128.69 153.85,128.85 153.85,129.19 154.01,129.34 154.37,129.34 154.5,129.47 154.5,129.87 154.37,129.99 154.01,129.99 153.85,130.15 153.85,130.49 154.01,130.64 154.37,130.64 154.5,130.77 154.5,131.17 154.37,131.29 154.01,131.29 153.85,131.45 153.85,131.79 154.01,131.95 154.37,131.95 154.5,132.07 154.5,132.47 154.37,132.6 154.01,132.6 153.85,132.75 153.85,133.09 154.01,133.25 154.38,133.25 154.5,133.37 154.5,133.77 154.38,133.9 154.01,133.9 153.85,134.05 153.85,134.52 144.52,143.85 136.72,143.85 136.72,143.85
M_DATA_B4: length 94
  TOP w0.14: U27.AD34 v1(129.4,146.3)
  L3 w0.102: 134.84,147.44 134.14,146.74 129.85,146.74 v1(129.4,146.3)
  L3 w0.152: 134.84,147.44 136.71,149.31 146.82,149.31 161.64,134.5 161.64,121.76 167.03,116.37 167.03,111.47 167.19,111.32 167.27,111.32 167.42,111.17 167.42,110.82 167.27,110.67 167.19,110.67 167.03,110.52 167.03,110.17 167.19,110.02 167.27,110.02 167.42,109.87 167.42,109.52 167.27,109.37 167.19,109.37 167.03,109.22 167.03,108.67 174.26,101.44 174.26,100.05 173.2,98.98 173.2,98.45 174.19,97.46 174.19,96.49 173.07,95.38 173.07,94.31 174.03,93.34 174.03,92.01 173.22,91.2 173.22,89.13 DIMM2.122
M_DATA_B5: length 93.2
  TOP w0.14: U27.AD35 v1(130.32,146.3)
  L3 w0.102: 135.35,147.42 134.91,147.22 134.08,146.39 130.4,146.39 v1(130.32,146.3)
  L3 w0.152: DIMM2.123 172.04,89.54 172.97,90.47 172.97,91.26 172.05,92.18 172.05,93.32 172.81,94.08 172.81,95.27 172.81,95.48 173.93,96.6 173.93,97.35 172.94,98.34 172.94,99.09 174.01,100.16 174.01,100.75 166.39,108.37 166.39,116.1 160.99,121.49 160.99,134.23 146.55,148.67 136.59,148.67 135.35,147.42
M_DATA_B6: length 93.3
  TOP w0.14: U27.AG34 v1(128.49,143.56)
  L3 w0.102: v1(128.49,143.56) 128.85,143.92 130.58,143.92 131.14,144.48 135.68,144.48 135.78,144.58
  L3 w0.127: 168.05,99.82 167.33,99.1 167.33,99.08 167.31,99.06 167.31,98.45 167.31,98.44 167.31,98.32 167.75,97.88
  L3 w0.152: 167.75,97.88 168.06,97.57 168.06,96.42 167.12,95.48 167.12,94.46 168.01,93.57 168.01,92.15 167.18,91.31 167.18,90.12 167.04,89.99 DIMM2.128 ; 168.05,99.82 168.27,100.04 168.27,101.69 161.15,108.81 161.15,117.22 157.56,120.81 157.56,121.91 157.71,122.07 157.96,122.07 158.11,122.22 158.11,122.56 157.96,122.72 157.71,122.72 157.56,122.87 157.56,123.21 157.71,123.37 157.96,123.37 158.11,123.52 158.11,123.86 157.96,124.02 157.71,124.02 157.56,124.17 157.56,124.51 157.71,124.67 157.96,124.67 158.11,124.82 158.11,125.16 157.96,125.32 157.71,125.32 157.56,125.47 157.56,125.81 157.71,125.97 157.96,125.97 158.11,126.12 158.11,126.46 157.96,126.62 157.71,126.62 157.56,126.77 157.56,127.11 157.71,127.27 157.96,127.27 158.11,127.42 158.11,127.76 157.96,127.92 157.71,127.92 157.56,128.07 157.56,128.42 157.71,128.57 157.96,128.57 158.11,128.72 158.11,129.07 157.96,129.22 157.71,129.22 157.56,129.37 157.56,129.72 157.71,129.87 157.96,129.87 158.11,130.02 158.11,130.37 157.96,130.52 157.71,130.52 157.56,130.67 157.56,131.02 157.71,131.17 157.96,131.17 158.11,131.32 158.11,131.67 157.96,131.82 157.71,131.82 157.56,131.97 157.56,132.32 157.71,132.47 157.96,132.47 158.11,132.62 158.11,132.97 157.96,133.12 157.71,133.12 157.56,133.27 157.56,133.57 145.33,145.8 137,145.8 135.78,144.58
M_DATA_B7: length 92.3
  TOP w0.14: U27.AH34 v1(128.49,142.64)
  L3 w0.14: 135.98,144.19 131.49,144.19 130.94,143.64 129.48,143.64 v1(128.49,142.64)
  L3 w0.152: 135.98,144.19 136.94,145.15 145.06,145.15 156.48,133.72 156.48,133.06 156.64,132.91 156.75,132.91 156.9,132.76 156.9,132.41 156.75,132.26 156.64,132.26 156.48,132.11 156.48,131.76 156.64,131.61 156.75,131.61 156.9,131.46 156.9,131.11 156.75,130.96 156.64,130.96 156.48,130.81 156.48,130.46 156.64,130.31 156.75,130.31 156.9,130.16 156.9,129.81 156.75,129.66 156.64,129.66 156.48,129.51 156.48,129.16 156.64,129.01 156.75,129.01 156.9,128.86 156.9,128.51 156.75,128.36 156.64,128.36 156.48,128.21 156.48,127.86 156.64,127.71 156.75,127.71 156.9,127.56 156.9,127.21 156.75,127.06 156.64,127.06 156.48,126.91 156.48,126.56 156.64,126.41 156.75,126.41 156.9,126.26 156.9,125.91 156.75,125.76 156.64,125.76 156.48,125.61 156.48,125.26 156.64,125.11 156.75,125.11 156.9,124.96 156.9,124.61 156.75,124.46 156.64,124.46 156.48,124.3 156.48,123.96 156.64,123.81 156.75,123.81 156.9,123.65 156.9,123.31 156.75,123.16 156.64,123.16 156.48,123 156.48,122.66 156.64,122.51 156.79,122.51 156.91,122.38 156.91,121.98 156.79,121.86 156.64,121.86 156.48,121.7 156.48,120.97 160.5,116.96 160.5,108.54 168.01,101.03 168.01,100.14 167.06,99.19 167.06,98.04 167.81,97.29 167.81,96.52 166.87,95.58 166.87,94.18 166.11,93.41 166.11,92.15 166.9,91.36 166.9,90.24 166.04,89.38 DIMM2.129
M_DATA_B8: length 80.9
  TOP w0.14: v1(129.41,139.93) 129.41,139.93 128.94,139.47 U27.AL34
  L3 w0.102: v1(129.41,139.93) 129.86,140.38 130.51,140.38 131.06,140.94 131.17,140.94
  L3 w0.14: 135.83,141.91 135.78,141.96 133.83,141.96 132.91,141.04 131.28,141.04 131.17,140.94
  L3 w0.152: 135.83,141.91 143.7,141.91 151.91,133.7 151.91,118.92 151.78,118.8 151.23,118.8 151.11,118.67 151.11,118.25 151.23,118.12 151.78,118.12 151.91,117.99 151.91,117.47 151.78,117.35 150.17,117.35 150.04,117.22 150.04,116.83 150.17,116.7 154.32,116.7 157.23,113.79 157.23,106.82 162.29,101.76 162.29,99.98 163.05,99.23 163.05,98.14 162.25,97.34 162.25,96.46 161.21,95.42 161.21,94.39 162.84,92.75 DIMM2.12
M_DATA_B9: length 81.7
  TOP w0.14: U27.AL35 129.86,139.46 130.32,139.92 v1(130.32,139.92)
  L3 w0.102: 135.82,141.26 135.34,141.74 134.06,141.74 133.14,140.82 131.37,140.82 130.48,139.92 v1(130.32,139.92)
  L3 w0.152: DIMM2.13 162.04,93.19 160.95,94.28 160.95,95.52 161.99,96.56 161.99,97.44 162.79,98.24 162.79,99.06 162.04,99.82 162.04,101.08 161.37,101.75 156.58,106.54 156.58,107.24 156.43,107.39 155.76,107.39 155.63,107.52 155.63,107.91 155.76,108.04 156.21,108.04 156.34,108.17 156.34,108.56 156.21,108.69 155.75,108.69 155.62,108.82 155.62,109.21 155.75,109.34 156.43,109.34 156.58,109.49 156.58,113.52 154.05,116.05 149.61,116.05 149.31,116.35 149.31,118.51 149.72,118.92 150.44,118.92 151.26,119.74 151.26,133.44 143.44,141.26 135.82,141.26
M_DATA_B10: length 81.9
  TOP w0.14: U27.AK31 v1(125.74,140.81)
  L3 w0.102: v1(125.74,140.81) 126.2,140.35 126.2,139.73 126.5,139.44 126.83,139.44 127.42,138.84 128.67,138.84 128.86,138.65 132.69,138.65 132.81,138.53
  L3 w0.152: 132.81,138.53 132.99,138.35 142.24,138.35 148.39,132.2 148.39,128.42 148.24,128.27 147.82,128.27 147.67,128.12 147.67,127.78 147.82,127.62 148.24,127.62 148.39,127.47 148.39,127.13 148.24,126.98 146.53,126.98 146.37,126.82 146.37,126.48 146.53,126.33 148.24,126.33 148.39,126.18 148.39,125.83 148.24,125.68 146.65,125.68 146.5,125.53 146.5,125.19 146.65,125.03 147.8,125.03 147.95,124.88 147.95,124.54 147.8,124.39 146.6,124.39 146.45,124.23 146.45,111.61 156.23,101.83 156.23,100.18 157.05,99.36 157.05,98.18 156.1,97.23 156.1,96.47 155.06,95.43 155.06,94.49 156.79,92.75 DIMM2.18
M_DATA_B11: length 82.5
  TOP w0.14: v1(125.74,139.9) U27.AL31
  L3 w0.102: v1(125.74,139.9) 126,139.64 126,138.92 126.4,138.52 128.65,138.52 128.79,138.39 130.21,138.39 131,137.59 132.63,137.59 132.83,137.79
  L3 w0.152: 132.83,137.79 133.14,138.1 135.4,138.1 135.83,137.67 137.46,137.67 138.31,136.82 142.86,136.82 146.18,133.49 146.18,132.46 146.33,132.31 147.36,132.31 147.52,132.16 147.52,131.81 147.36,131.66 146.33,131.66 146.18,131.51 146.18,131.17 146.33,131.01 147.62,131.01 147.74,130.89 147.74,130.49 147.62,130.37 146.33,130.37 146.18,130.21 146.18,129.87 146.33,129.72 147.54,129.72 147.69,129.57 147.69,129.22 147.54,129.07 146.33,129.07 146.18,128.92 146.18,128.58 146.33,128.42 146.78,128.42 146.93,128.27 146.93,127.93 146.78,127.78 146.39,127.78 145.38,126.77 145.38,126.27 145.76,125.88 145.76,111.38 155.95,101.19 155.95,100.1 156.79,99.25 156.79,98.35 155.8,97.37 155.8,96.53 154.81,95.53 154.81,94.38 156.04,93.15 DIMM2.19
M_DATA_B12: length 84.1
  TOP w0.14: U27.AK34 v1(128.49,140.81)
  L3 w0.102: v1(128.49,140.81) 128.94,141.27 129.59,141.27 129.86,141.54 129.86,141.9 130.15,142.19 131.87,142.19 131.89,142.21
  L3 w0.152: DIMM2.131 164.04,89.4 164.87,90.23 164.87,91.56 164.15,92.28 164.15,93.33 163.26,94.22 163.26,95.4 164.08,96.22 164.08,97.24 164.99,98.16 164.99,99.29 164.29,99.99 164.29,101.74 158.52,107.51 158.52,114.33 153.7,119.15 153.7,125.34 153.21,125.84 153.21,134.24 144.24,143.21 135.93,143.21 135.35,142.62 132.3,142.62 131.89,142.21
M_DATA_B13: length 83.2
  TOP w0.14: U27.AK35 129.86,140.38 v1(130.32,140.84)
  L3 w0.102: v1(130.32,140.84) 130.74,141.26 132.54,141.26 132.73,141.45
  L3 w0.127: 163.66,99.86 163.3,99.5 163.3,97.66 163.58,97.37
  L3 w0.152: 163.66,99.86 163.98,100.17 163.98,101.14 157.88,107.24 157.88,114.06 154.59,117.35 152.8,117.35 152.67,117.48 152.67,117.95 152.8,118.07 152.9,118.07 153.05,118.23 153.05,118.57 152.9,118.72 152.71,118.72 152.56,118.88 152.56,119.22 152.71,119.37 152.9,119.37 153.05,119.53 153.05,119.87 152.9,120.02 152.71,120.02 152.56,120.18 152.56,120.52 152.71,120.68 152.9,120.68 153.05,120.83 153.05,121.17 152.9,121.33 152.71,121.33 152.56,121.48 152.56,121.82 152.71,121.98 152.9,121.98 153.05,122.13 153.05,122.47 152.9,122.63 152.71,122.63 152.56,122.78 152.56,123.12 152.71,123.28 152.9,123.28 153.05,123.43 153.05,123.77 152.9,123.93 152.71,123.93 152.56,124.08 152.56,124.42 152.71,124.58 152.9,124.58 153.05,124.73 153.05,125.07 152.9,125.23 152.71,125.23 152.56,125.38 152.56,133.97 143.97,142.56 135.95,142.56 135.7,142.32 133.6,142.32 132.73,141.45 ; DIMM2.132 163.04,91.4 163.87,92.23 163.87,93.24 163.01,94.11 163.01,95.51 163.82,96.32 163.82,97.14 163.58,97.37
M_DATA_B14: length 85.2
  TOP w0.14: U27.AK32 v1(126.66,140.81)
  L3 w0.102: v1(126.66,140.81) 127.13,140.34 127.13,139.74 127.42,139.45 128.64,139.45 129.03,139.06 133.73,139.06 134.18,139.51
  L3 w0.152: 134.18,139.51 134.6,139.93 135.44,139.93 135.68,139.69 142.74,139.69 149.69,132.74 149.69,120.65 149.54,120.5 147.9,120.5 147.74,120.35 147.74,112.15 147.93,111.96 148.3,111.96 148.46,112.12 148.46,113.03 148.61,113.18 148.99,113.18 149.14,113.03 149.14,110.75 158.23,101.66 158.23,101.17 158.23,100.32 159.25,99.3 159.25,98.37 158.08,97.2 158.08,96.24 157.27,95.43 157.27,94.21 158.2,93.28 158.2,91.99 159.11,91.08 159.11,90.43 158.04,89.37 DIMM2.137
M_DATA_B15: length 84.2
  TOP w0.14: v1(126.67,139.91) 126.67,139.89 U27.AL32
  L3 w0.102: v1(126.67,139.91) 127.46,139.13 128.68,139.13 128.95,138.86 133.46,138.86 133.61,138.71 135.01,138.71
  L3 w0.152: 135.01,138.71 135.34,139.04 142.47,139.04 149.04,132.47 149.04,123.89 148.89,123.74 147.25,123.74 147.1,123.59 147.1,123.24 147.25,123.09 148.89,123.09 149.04,122.94 149.04,122.59 148.89,122.44 147.25,122.44 147.1,122.29 147.1,121.95 147.25,121.79 148.38,121.79 148.53,121.64 148.53,121.3 148.38,121.15 147.25,121.15 147.1,120.99 147.1,111.88 157.98,100.99 157.98,100.21 159,99.19 159,98.48 157.83,97.31 157.83,96.35 157.02,95.53 157.02,95.32 157.02,94.1 157.04,94.08 157.04,94.02 157.9,93.16 157.9,92.23 157.04,91.37 DIMM2.138
M_DATA_B16: length 69.9
  TOP w0.14: v1(130.33,136.24) 129.88,136.7 U27.AP35
  L3 w0.102: 135.68,136.53 135.48,136.73 130.82,136.73 v1(130.33,136.24)
  L3 w0.152: 135.68,136.53 137.33,134.87 139.26,134.87 139.41,134.72 139.41,134.37 139.29,134.25 139.24,134.21 137.91,134.21 137.76,134.06 137.76,133.68 137.91,133.53 138.12,133.53 138.27,133.38 138.27,133.12 138.12,132.97 137.91,132.97 137.74,132.79 137.74,130.07 139.48,128.33 139.48,126.76 139.63,126.61 142.97,126.61 143.12,126.45 143.12,126.11 142.97,125.96 141.98,125.96 141.83,125.81 141.83,125.45 141.98,125.3 143.6,125.3 143.82,125.08 143.82,110.02 152.14,101.7 152.14,100.38 153.26,99.27 153.26,98.32 152.19,97.25 152.19,96.37 151.2,95.38 151.2,94.36 152.14,93.42 152.14,92.53 153.82,90.85 DIMM2.21
M_DATA_B17: length 71.7
  TOP w0.14: v1(129.38,137.15) 129.38,137.21 128.97,137.61 U27.AN34
  L3 w0.102: 136.66,136.42 136.15,136.93 130.72,136.93 130.52,136.73 129.79,136.73 v1(129.38,137.15)
  L3 w0.152: DIMM2.22 153.04,94.29 153,94.33 153,95.46 153.99,96.45 153.99,97.51 154.88,98.4 154.88,99.09 153.84,100.13 153.84,100.97 144.47,110.34 144.47,125.35 143.77,126.05 143.77,127.13 143.62,127.28 140.28,127.28 140.12,127.43 140.12,127.81 140.28,127.97 144.73,127.97 144.89,128.12 144.89,132.96 142.32,135.52 137.56,135.52 136.66,136.42
M_DATA_B18: length 70
  TOP w0.14: U27.AN32 v1(127.57,137.16)
  L3 w0.102: 132.9,133.47 132.9,133.9 131.72,135.08 129.05,135.08 128.03,136.1 128.03,136.7 v1(127.57,137.16)
  L3 w0.152: 132.9,133.47 135.39,130.97 135.39,130.3 135.39,129.15 137.23,127.31 137.23,121.15 137.38,121 141.32,121 141.45,120.88 141.45,120.47 141.32,120.35 137.41,120.35 137.26,120.2 137.26,119.86 137.41,119.7 141.32,119.7 141.45,119.58 141.45,119.18 141.32,119.06 140.94,119.06 140.78,118.9 140.78,118.54 140.94,118.39 141.45,118.39 141.6,118.24 141.6,108.76 148.07,102.29 148.07,100.23 149.09,99.21 149.09,98.28 149.09,98.07 148.25,97.23 148.25,96.32 147.21,95.28 147.21,94.39 148.05,93.55 148.05,91.11 148.04,91.1 DIMM2.27
M_DATA_B19: length 73.6
  TOP w0.14: U27.AN31 v1(126.66,137.16)
  L3 w0.102: 130.36,134.58 128.94,134.58 127.76,135.76 127.41,135.76 127.12,136.05 127.12,136.7 v1(126.66,137.16)
  L3 w0.152: 130.36,134.58 131.46,133.48 131.46,132.55 131.63,132.38 132.15,132.38 132.44,132.09 132.44,131.23 132.83,130.84 132.99,130.84 133.14,130.68 133.14,129.18 133.91,128.41 134.46,128.41 134.61,128.26 134.61,127.64 135.2,127.05 135.78,127.05 135.93,126.9 135.93,117.24 136.11,117.06 138.73,117.06 138.88,116.91 138.88,116.57 138.73,116.41 136.11,116.41 135.96,116.26 135.96,115.92 136.11,115.77 140.2,115.77 140.3,115.67 140.3,115.22 140.2,115.12 136.11,115.12 135.96,114.97 135.96,114.6 136.11,114.45 140.18,114.45 140.3,114.33 140.3,107.77 146.22,101.85 146.22,100.3 147.26,99.26 147.26,98.35 146.07,97.16 146.07,96.27 145.23,95.43 145.23,94.49 146.96,92.75 DIMM2.28
M_DATA_B20: length 68
  TOP w0.14: v1(130.32,137.18) 129.89,137.61 U27.AN35
  L3 w0.102: 136.91,137.17 130.34,137.17 v1(130.32,137.18)
  L3 w0.152: 136.91,137.17 137.91,136.17 142.59,136.17 145.53,133.22 145.53,127.84 144.62,126.92 144.62,126.11 145.12,125.62 145.12,110.68 154.09,101.7 154.09,100.23 155.14,99.19 155.14,98.29 154.25,97.41 154.25,96.34 153.26,95.35 153.26,94.44 154.02,93.68 154.02,92.23 155.04,91.2 DIMM2.140
M_DATA_B21: length 70.9
  TOP w0.14: U27.AP34 128.97,136.7 v1(129.43,136.24)
  L3 w0.102: 136.85,134.77 135.58,136.04 133.97,136.04 133.71,135.79 129.88,135.79 v1(129.43,136.24)
  L3 w0.152: DIMM2.141 154.04,89.59 153.04,90.59 153.04,91.27 151.88,92.43 151.88,93.32 150.94,94.26 150.94,94.47 150.94,95.48 151.94,96.47 151.94,97.36 153,98.42 153,99.16 151.88,100.28 151.88,100.99 143.17,109.7 143.17,124.38 142.91,124.65 138.96,124.65 138.8,124.8 138.8,125.07 139.03,125.3 140.53,125.3 140.68,125.45 140.68,125.81 140.53,125.96 139.36,125.96 138.83,126.49 138.83,128.07 137.05,129.84 137.05,134.57 136.85,134.77
M_DATA_B22: length 71.8
  TOP w0.14: U27.AP32 v1(127.57,136.24)
  L3 w0.102: v1(127.57,136.24) 128.94,134.87 131.47,134.87 131.85,134.5
  L3 w0.14: 133.44,132.17 132.33,133.28 132.33,134.01 131.85,134.5
  L3 w0.152: 133.44,132.17 133.79,131.82 133.79,129.92 136.58,127.13 136.58,119.21 136.73,119.06 139.77,119.06 139.92,118.9 139.92,118.56 139.77,118.41 136.73,118.41 136.58,118.26 136.58,117.91 136.73,117.76 140.73,117.76 140.89,117.61 140.89,117.27 140.73,117.11 139.69,117.11 139.54,116.96 139.54,116.61 139.69,116.46 140.8,116.46 140.95,116.31 140.95,108.24 147.82,101.37 147.82,100.12 148.84,99.11 148.84,98.17 148,97.33 148,96.42 146.96,95.38 146.96,94.28 147.79,93.45 147.79,91.79 147.29,91.29 147.29,90.47 147.9,89.87 148.79,89.87 149.04,89.61 DIMM2.146
M_DATA_B23: length 72.8
  TOP w0.14: U27.AP31 126.21,136.7 v1(126.66,136.25)
  L3 w0.102: v1(126.66,136.25) 126.66,135.97 127.1,135.53 127.1,135.13 127.39,134.84 127.87,134.84 128.36,134.35 129.88,134.35 130.07,134.16
  L3 w0.152: 130.07,134.16 130.93,133.3 130.93,132.21 132.48,130.66 132.48,128.24 132.63,128.09 133.37,128.09 133.52,127.94 133.52,127.6 133.37,127.44 132.63,127.44 132.48,127.29 132.48,126.95 132.63,126.8 134.59,126.8 134.74,126.64 134.74,126.3 134.59,126.15 132.63,126.15 132.48,126 132.48,125.63 132.63,125.48 135.13,125.48 135.29,125.32 135.29,124.97 135.13,124.82 134.49,124.82 134.33,124.66 134.33,124.31 134.49,124.16 135.13,124.16 135.29,124 135.29,114.34 135.29,113.96 135.44,113.8 139.51,113.8 139.65,113.67 139.65,107.35 145.97,101.04 145.97,100.2 147.01,99.16 147.01,98.45 145.81,97.26 145.81,96.37 144.98,95.53 144.98,94.38 146,93.36 146,92.46 147.03,91.43 147.03,90.35 148.04,89.34 DIMM2.147
M_DATA_B24: length 69.6
  TOP w0.14: U27.AL29 v1(123.91,139.9)
  L3 w0.102: v1(123.91,139.9) 124.36,140.34 125.06,140.34 125.29,140.12 125.29,139.46 125.49,139.25 125.49,138.83 125.52,138.79 126.11,138.02 126.18,137.95 126.18,135.16 127.47,133.88 128.08,133.88
  L3 w0.152: DIMM2.30 144.83,92.75 143.2,94.39 143.2,95.4 144.24,96.44 144.24,97.26 145.08,98.09 145.08,99.34 144.26,100.16 144.26,100.99 144.26,101.75 139.01,107.01 139.01,113 138.85,113.16 134.87,113.16 134.64,113.39 134.64,114.07 134.64,121.95 134.51,122.07 134.31,122.07 134.16,122.22 134.16,122.61 134.31,122.76 134.49,122.76 134.61,122.89 134.61,123.25 134.46,123.41 131.95,123.41 131.82,123.53 131.82,123.93 131.95,124.05 133.53,124.05 133.69,124.21 133.69,124.55 133.53,124.7 131.95,124.7 131.82,124.83 131.82,127.03 131.79,127.05 131.79,130.89 131.61,131.08 131.35,131.08 131.07,130.8 130.67,130.8 130.17,131.3 130.17,133.42 129.6,133.99 128.19,133.99 128.08,133.88
M_DATA_B25: length 68.7
  TOP w0.14: v1(124.84,138.09) 124.83,138.11 124.79,138.11 U27.AM29
  L3 w0.102: v1(124.84,138.09) 125.78,137.16 125.78,134.99 126.96,133.81 126.96,133.78 127.24,133.49
  L3 w0.152: DIMM2.31 143.56,90.85 142.08,92.33 142.08,93.37 141.06,94.39 141.06,95.32 142.18,96.44 142.18,97.38 143.15,98.35 143.15,98.56 143.15,99.17 142.08,100.23 142.08,101.83 135.72,108.19 135.72,109.61 133.29,112.04 133.29,116.74 133.14,116.89 132.63,116.89 132.48,117.04 132.48,117.4 132.63,117.55 133.14,117.55 133.29,117.7 133.29,118.05 133.14,118.2 130.65,118.2 130.52,118.33 130.52,118.72 130.65,118.85 133.19,118.85 133.29,118.95 133.29,119.39 133.19,119.49 130.65,119.49 130.52,119.62 130.52,120.02 130.65,120.14 131.51,120.14 131.67,120.29 131.67,120.64 131.51,120.79 130.65,120.79 130.52,120.92 130.52,127.03 130.5,127.05 130.5,130.06 130.18,130.38 128.7,130.38 128.19,130.89 128.19,132.54 127.24,133.49
M_DATA_B26: length 63.7
  TOP w0.14: v1(123.88,136.25) 123.89,136.26 123.95,136.26 124.37,136.67 U27.AP29
  L3 w0.102: 125.06,133.2 124.83,133.43 124.83,135.29 123.88,136.24 v1(123.88,136.25)
  L3 w0.152: DIMM2.36 138.79,92.75 137.15,94.39 137.15,95.37 138.24,96.47 138.24,97.35 139.11,98.21 139.11,99.4 138.28,100.23 138.28,101.82 136.24,103.86 132.12,103.86 131.98,104 131.98,104.37 132.12,104.51 134.82,104.51 134.97,104.66 134.97,105 134.82,105.16 132.14,105.16 131.98,105.31 131.98,105.65 132.14,105.8 133.47,105.8 133.62,105.96 133.62,106.3 133.47,106.45 132.14,106.45 131.93,106.65 131.93,107.48 131.67,107.75 130.85,107.75 130.54,108.06 130.54,109.41 128.3,111.65 128.3,127.7 125.8,130.2 125.8,130.81 125.06,131.55 125.06,133.2
M_DATA_B27: length 66.4
  TOP w0.14: v1(123.91,135.29) 123.91,135.31 124.37,135.77 U27.AR29
  L3 w0.102: v1(123.91,135.29) 124.38,134.83 124.38,133.22
  L3 w0.152: 124.38,133.22 124.36,133.2 124.36,130.14 127.01,127.5 127.01,111.11 128.62,109.5 128.62,107.9 128.77,107.75 129.08,107.75 129.23,107.59 129.23,107.25 129.08,107.1 128.77,107.1 128.62,106.95 128.62,106.6 128.77,106.45 129.08,106.45 129.23,106.3 129.23,105.96 129.08,105.8 128.77,105.8 128.62,105.65 128.62,105.31 128.77,105.16 129.08,105.16 129.23,105 129.23,104.66 129.08,104.51 127.2,104.51 127.04,104.36 127.04,104.01 127.2,103.86 129.02,103.86 129.18,103.71 129.18,103.37 129.02,103.21 127.13,103.21 126.98,103.06 126.98,102.72 127.13,102.57 135.2,102.57 136.04,101.73 136.04,100.2 135.07,99.24 135.07,98.16 134.21,97.3 134.21,96.22 134.99,95.43 134.99,94.46 136.04,93.42 136.04,92.3 137.49,90.85 DIMM2.37
M_DATA_B28: length 67.5
  TOP w0.14: U27.AM28 v1(123.91,138.98)
  L3 w0.102: v1(123.91,138.98) 123.91,138.75 124.37,138.29 124.37,137.93 124.67,137.64 124.98,137.64 125.57,137.04 125.57,134.87 126.62,133.83 126.62,133.68 127.12,133.17
  L3 w0.152: DIMM2.149 145.6,87.05 144.12,88.54 144.12,89.32 142.8,90.65 142.8,91.25 141.83,92.22 141.83,93.27 140.81,94.28 140.81,95.43 141.93,96.55 141.93,97.49 142.89,98.45 142.89,99.06 141.83,100.13 141.83,101.12 135.07,107.87 135.07,109.35 132.64,111.77 132.64,116.05 132.49,116.2 130.52,116.2 130.37,116.36 130.37,116.7 130.52,116.85 131.49,116.85 131.64,117.01 131.64,117.35 131.49,117.5 130.03,117.5 129.88,117.65 129.88,128.64 127.56,130.95 127.56,132.73 127.12,133.17
M_DATA_B29: length 70
  TOP w0.14: U27.AL28 v1(123,139.9)
  L3 w0.102: v1(123,139.9) U27.AL28 125.01,139.44 125.29,139.17 125.29,138.38 125.98,137.68 125.98,135.08 127.38,133.67 127.42,133.67 127.89,133.21 128.29,133.21
  L3 w0.152: 128.29,133.21 129.51,131.98 129.51,131.03 129.81,130.73 130.25,130.73 130.45,130.53 130.99,130.53 131.12,130.4 131.12,127.08 131.17,127.03 131.17,122.83 131.27,122.73 133.39,122.73 133.51,122.62 133.51,122.2 133.39,122.09 132.28,122.09 132.12,121.93 132.12,121.59 132.28,121.44 133.84,121.44 133.99,121.28 133.99,113.81 133.99,113.12 134.6,112.51 138.13,112.51 138.36,112.28 138.36,106.72 144.01,101.07 144.01,100.05 144.82,99.24 144.82,98.2 143.99,97.36 143.99,96.55 142.94,95.51 142.94,94.28 144.09,93.14 144.09,92.2 145.04,91.25 DIMM2.150
M_DATA_B30: length 65.1
  TOP w0.14: U27.AR28 123.46,135.76 v1(123.03,135.33)
  L3 w0.152: v1(123.03,135.33) 122.56,134.86 122.56,133.91 123.26,133.2 123.26,130.65 126.36,127.56 126.36,110.85 127.97,109.23 127.97,105.52 127.6,105.16 126.66,105.16 126.33,104.83 126.33,102.34 126.81,101.85 133.27,101.85 133.98,101.14 133.98,100.23 133.01,99.26 133.01,98.35 133.95,97.41 133.95,96.24 133.06,95.35 133.06,94.44 133.95,93.56 133.95,92.41 134.92,91.44 134.92,90.5 136.04,89.38 136.04,88.52 136.54,88.01 139.08,88.01 DIMM2.155
M_DATA_B31: length 67.6
  TOP w0.14: v1(123.03,136.24) 123.46,136.67 U27.AP28
  L3 w0.102: 124.61,132.91 124.61,135.22 124.07,135.76 123.74,135.76 123.26,136.24 v1(123.03,136.24)
  L3 w0.152: 124.61,132.91 124.61,130.45 127.65,127.41 127.65,111.38 129.27,109.77 129.27,108.46 129.42,108.31 129.74,108.31 129.89,108.15 129.89,107.25 130.04,107.1 131.13,107.1 131.29,106.95 131.29,106.6 131.13,106.45 130.04,106.45 129.89,106.3 129.89,105.96 130.04,105.8 131.18,105.8 131.34,105.65 131.34,105.31 131.18,105.16 130.04,105.16 129.89,105 129.89,104.66 130.04,104.51 131.18,104.51 131.34,104.36 131.34,104.01 131.18,103.86 130.09,103.86 129.94,103.71 129.94,103.37 130.09,103.21 135.3,103.21 136.62,101.89 137.34,101.89 137.99,101.24 137.99,100.16 138.85,99.3 138.85,98.32 137.99,97.45 137.99,96.57 136.9,95.48 136.9,94.28 138.04,93.14 138.04,92.23 139.04,91.23 DIMM2.156
M_DATA_B32: length 69.1
  TOP w0.165: U27.AR12 v1(108.37,136.24)
  L3 w0.102: v1(108.37,136.24) 108.37,136.06 107.86,135.54 107.86,134.99
  L3 w0.152: 107.86,134.99 107.86,132.07 106.57,130.78 106.57,128.86 100.88,123.17 100.88,121.71 100.73,121.55 99.29,121.55 98.66,120.92 98.66,114.58 98.81,114.43 99.23,114.43 99.33,114.33 99.33,113.88 99.23,113.78 98.81,113.78 98.66,113.63 98.66,113.23 98.81,113.08 100.73,113.08 100.88,112.93 100.88,112.59 100.73,112.43 98.81,112.43 98.66,112.28 98.66,111.94 98.81,111.79 100.73,111.79 100.88,111.63 100.88,111.29 100.73,111.14 99.43,111.14 99.28,110.99 99.28,110.64 99.43,110.49 100.73,110.49 100.88,110.34 100.88,109.65 93.08,101.85 92.83,101.85 92.14,101.17 92.14,100.41 92.14,100.2 91.1,99.16 91.1,98.56 91.1,98.35 91.1,98.34 91.1,98.24 90.21,97.35 90.21,96.29 89.25,95.32 89.25,94.34 89.88,93.7 89.88,92.3 89.12,91.54 89.12,90.07 89.27,89.92 89.89,89.92 90.04,90.07 DIMM2.81
M_DATA_B33: length 67.6
  TOP w0.165: U27.AP12 108.38,137.15 v1(108.38,137.15)
  L3 w0.102: v1(108.38,137.15) 108.38,136.93 107.9,136.45 107.9,135.99 107.69,135.78
  L3 w0.152: DIMM2.82 89.04,92 88.89,91.85 88.08,91.85 87.93,92 87.93,93.14 88.99,94.21 88.99,95.43 89.96,96.39 89.96,97.56 90.85,98.45 90.85,99.26 91.89,100.3 91.89,101.63 98.01,107.75 98.01,109.01 98.17,109.17 99.46,109.17 99.61,109.32 99.61,109.66 99.46,109.81 98.17,109.81 98.01,109.97 98.01,110.31 98.17,110.46 98.49,110.46 98.63,110.6 98.63,110.97 98.49,111.11 98.17,111.11 98.01,111.26 98.01,111.82 97.86,111.97 97.49,111.97 97.34,112.12 97.34,112.47 97.49,112.62 97.86,112.62 98.01,112.77 98.01,113.11 97.86,113.27 97.49,113.27 97.34,113.42 97.34,113.76 97.49,113.91 97.86,113.91 98.01,114.07 98.01,114.41 97.86,114.56 97.49,114.56 97.34,114.71 97.34,115.06 97.49,115.21 97.86,115.21 98.01,115.36 98.01,115.7 97.86,115.86 97.49,115.86 97.34,116.01 97.34,116.35 97.49,116.5 97.86,116.5 98.01,116.66 98.01,117 97.86,117.15 97.49,117.15 97.34,117.3 97.34,117.65 97.49,117.8 97.86,117.8 98.01,117.95 98.01,118.29 97.86,118.45 97.49,118.45 97.34,118.6 97.34,118.94 97.49,119.09 97.86,119.09 98.01,119.25 98.01,119.59 97.86,119.74 97.49,119.74 97.34,119.89 97.34,120.24 97.49,120.39 97.86,120.39 98.01,120.54 98.01,121.38 98.84,122.2 100.04,122.2 100.23,122.39 100.23,123.43 106.27,129.47 106.27,131.17 106.83,131.73 106.83,132.94 107.56,133.67 107.56,135.65 107.69,135.78
M_DATA_B34: length 72.7
  TOP w0.165: U27.AL13 v1(109.28,139.9)
  L3 w0.102: v1(109.28,139.9) 108.82,140.36 107.48,140.36 105.33,138.21 105.33,135.28 103.95,133.9
  L3 w0.152: DIMM2.87 83.79,90.85 82.14,92.51 82.14,93.24 82.94,94.04 82.94,95.42 83.99,96.47 83.99,97.41 84.88,98.3 84.88,99.09 86,100.2 86,100.86 86,100.86 86,101.07 86,101.07 86,101.63 90.37,106 90.37,106.73 90.52,106.88 91.25,106.88 91.41,107.04 91.41,107.38 91.25,107.53 90.61,107.53 90.39,107.75 90.39,113.33 90.54,113.49 90.72,113.49 90.87,113.64 90.87,114.02 90.72,114.17 90.54,114.17 90.39,114.33 90.39,114.68 90.54,114.83 91.86,114.83 92.02,114.98 92.02,115.32 91.86,115.48 90.54,115.48 90.39,115.63 90.39,115.97 90.54,116.12 91.86,116.12 92.02,116.28 92.02,116.62 91.86,116.77 90.54,116.77 90.39,116.92 90.39,117.27 90.54,117.42 91.86,117.42 92.02,117.57 92.02,120.37 103.55,131.9 103.55,132.28 103.17,132.66 103.17,133.12 103.95,133.9
M_DATA_B35: length 72.6
  TOP w0.165: U27.AL12 v1(108.37,139.9)
  L3 w0.102: 105.63,138.19 107.14,139.7 108.17,139.7 v1(108.37,139.9)
  L3 w0.152: DIMM2.88 83.56,93.27 83.56,94.16 83.19,94.53 83.19,95.31 84.24,96.36 84.24,97.3 85.13,98.19 85.13,98.98 86.25,100.1 86.25,100.97 92.66,107.38 92.66,108.03 92.51,108.18 91.19,108.18 91.04,108.33 91.04,108.68 91.19,108.83 92.51,108.83 92.66,108.98 92.66,109.32 92.51,109.48 91.19,109.48 91.04,109.63 91.04,109.97 91.19,110.12 92.51,110.12 92.66,110.28 92.66,110.62 92.51,110.77 91.19,110.77 91.04,110.92 91.04,111.27 91.19,111.42 92.51,111.42 92.66,111.57 92.66,111.91 92.51,112.07 91.19,112.07 91.04,112.22 91.04,112.56 91.19,112.71 92.51,112.71 92.66,112.87 92.66,113.21 92.51,113.36 91.74,113.36 91.59,113.51 91.59,113.86 91.74,114.01 92.51,114.01 92.66,114.16 92.66,120.08 92.72,120.13 92.72,120.14 105.17,132.6 105.17,134.59 105.63,135.04 105.63,138.19
M_DATA_B36: length 70.4
  TOP w0.165: v1(109.28,135.33) U27.AR13
  L3 w0.152: v1(109.28,135.33) 109.28,134.69 108.53,133.94 108.53,131.27 107.43,130.18 107.43,129.41 107.76,129.08 107.76,128.22 102.18,122.63 102.18,120.41 102.02,120.26 100.11,120.26 99.96,120.11 99.96,119.76 100.11,119.61 102.02,119.61 102.18,119.46 102.18,119.11 102.02,118.96 100.11,118.96 99.96,118.81 99.96,118.47 100.11,118.31 102.02,118.31 102.18,118.16 102.18,117.82 102.02,117.67 100.22,117.67 100.07,117.51 100.07,117.17 100.22,117.02 102.02,117.02 102.18,116.87 102.18,109.04 94.26,101.12 94.26,100.05 93.21,99 93.21,98.22 92.07,97.08 92.07,96.39 91.08,95.4 91.08,94.06 91.94,93.19 91.94,92.09 91.05,91.19 91.05,90.28 91.97,89.36 91.97,88.24 91.81,88.09 91.19,88.09 91.04,88.24 DIMM2.200
M_DATA_B37: length 71.7
  TOP w0.165: v1(109.26,136.24) 109.71,136.7 U27.AP13
  L3 w0.102: 108.83,134.9 108.83,135.81 v1(109.26,136.24)
  L3 w0.14: 108.83,134.9 108.22,134.29 108.22,131.6 107.05,130.43
  L3 w0.152: DIMM2.201 90.04,86.51 89.89,86.36 89.27,86.36 89.12,86.51 89.12,87.5 90.04,88.42 90.04,89.19 90.79,89.94 90.79,91.37 90.14,92.02 90.14,93.29 90.81,93.95 90.81,95.49 91.8,96.48 91.8,97.16 91.81,97.18 91.81,97.18 92.96,98.33 92.96,99.14 93.97,100.15 93.97,101.83 101.53,109.39 101.53,113.63 101.38,113.78 100.14,113.78 99.99,113.93 99.99,114.28 100.14,114.43 101.38,114.43 101.53,114.58 101.53,114.92 101.38,115.08 99.42,115.08 99.31,115.19 99.31,115.61 99.42,115.72 101.38,115.72 101.53,115.88 101.53,116.24 101.4,116.37 99.52,116.37 99.31,116.58 99.31,120.65 99.56,120.91 101.29,120.91 101.53,121.15 101.53,122.9 107.05,128.42 107.05,130.43
M_DATA_B38: length 71.7
  TOP w0.165: U27.AM13 v1(109.28,138.98)
  L3 w0.102: v1(109.28,138.98) 108.83,138.53 107.66,138.53 107.61,138.58 107.24,138.58 106.4,137.75 106.4,134.9
  L3 w0.152: DIMM2.206 85.78,88.95 85.9,89.08 85.9,89.81 85.78,89.94 85.21,89.94 85.08,90.07 85.08,91.29 84.07,92.31 84.07,93.17 85.08,94.18 85.08,95.43 86.07,96.42 86.07,97.28 87.07,98.28 87.07,99.17 88.23,100.33 88.23,101.02 90.54,103.32 90.75,103.32 90.9,103.17 91.08,103.17 91.36,103.45 91.36,103.63 91.21,103.78 91.21,103.99 91.45,104.24 91.67,104.24 91.83,104.07 92.05,104.07 92.29,104.31 92.29,104.53 92.09,104.73 92.09,104.91 92.37,105.19 92.55,105.19 92.75,104.99 92.97,104.99 93.21,105.23 93.21,105.45 92.98,105.68 92.98,105.86 93.26,106.13 93.44,106.13 93.68,105.89 93.86,105.89 94.17,106.21 94.17,106.39 93.96,106.59 93.96,106.97 94.11,107.12 95,107.12 95.12,107.25 95.12,107.64 95,107.77 94.39,107.77 94.26,107.9 94.26,108.29 94.39,108.42 95.57,108.42 95.73,108.57 95.73,111.51 95.57,111.66 94.11,111.66 93.96,111.81 93.96,119.56 104.69,130.29 104.69,131.24 105.89,132.43 105.89,134.38 106.4,134.9
M_DATA_B39: length 72.3
  TOP w0.165: U27.AM12 v1(108.37,138.98)
  L3 w0.102: v1(108.37,138.98) 108.15,138.98 107.64,139.5 107.23,139.5 106.03,138.3 106.03,135.05
  L3 w0.152: DIMM2.207 84.71,87.05 84.88,87.22 84.88,87.71 84.09,88.49 84.09,89.59 84.83,90.32 84.83,91.19 83.81,92.2 83.81,93.27 84.83,94.29 84.83,95.22 84.83,95.22 84.83,95.43 84.83,95.53 85.82,96.52 85.82,97.39 86.79,98.36 86.79,99.27 87.88,100.36 87.88,101.68 93.31,107.11 93.31,108.91 93.46,109.07 94.94,109.07 95.08,109.21 95.08,109.57 94.94,109.71 93.46,109.71 93.31,109.87 93.31,110.21 93.46,110.36 94.91,110.36 95.06,110.51 95.06,110.86 94.91,111.01 93.46,111.01 93.31,111.16 93.31,119.81 93.36,119.86 93.36,119.88 104.36,130.87 104.36,131.27 105.63,132.54 105.63,134.65 106.03,135.05
M_DATA_B40: length 79
  TOP w0.165: v1(104.34,137.16) U27.AP10
  L3 w0.102: 102.42,133.36 102.42,134.09 103.2,134.87 103.6,134.87 103.88,135.15 103.88,136.7 v1(104.34,137.16)
  L3 w0.152: 102.42,133.36 101.97,132.92 100.99,132.92 99.43,131.36 99.43,130.63 99.66,130.4 99.66,129.97 99.25,129.56 99.04,129.56 98.54,130.06 98.33,130.06 98.09,129.82 98.09,129.6 98.58,129.1 98.58,128.89 98.34,128.65 98.12,128.65 97.63,129.14 97.41,129.14 97.17,128.9 97.17,128.68 97.66,128.19 97.66,127.97 97.42,127.73 97.21,127.73 96.71,128.23 96.5,128.23 96.25,127.98 96.25,127.77 96.75,127.27 96.75,127.06 96.51,126.81 96.29,126.81 95.79,127.31 95.58,127.31 95.34,127.07 95.34,126.85 95.83,126.35 95.83,126.14 95.59,125.9 95.37,125.9 94.88,126.39 94.66,126.39 94.42,126.15 94.42,125.93 94.92,125.44 94.92,125.22 94.67,124.98 94.46,124.98 93.96,125.48 93.75,125.48 93.5,125.23 93.5,125.02 94,124.52 94,124.31 93.76,124.06 93.54,124.06 93.04,124.56 92.83,124.56 92.59,124.32 92.59,124.1 93.08,123.61 93.08,123.39 92.84,123.15 92.62,123.15 92.13,123.64 91.91,123.64 91.67,123.4 91.67,123.18 92.17,122.69 92.17,122.47 91.92,122.23 91.71,122.23 91.22,122.71 91.01,122.71 90.77,122.47 90.77,122.26 91.25,121.77 91.25,121.56 90.7,121 90.7,120.16 90.54,120.01 89.77,120.01 89.24,119.48 89.24,118.9 89.05,118.71 88.41,118.71 87.94,118.25 87.94,111.59 88.09,111.44 88.92,111.44 89.07,111.28 89.07,110.94 88.92,110.79 88.09,110.79 87.94,110.64 87.94,110.29 88.09,110.14 88.92,110.14 89.07,109.99 89.07,109.65 88.92,109.49 88.09,109.49 87.94,109.34 87.94,109 88.09,108.85 88.92,108.85 89.07,108.69 89.07,108.35 88.92,108.2 88.09,108.2 87.94,108.05 87.94,107.7 88.09,107.55 88.92,107.55 89.07,107.4 89.07,107.06 88.92,106.9 88.09,106.9 87.94,106.75 87.94,105.5 83.79,101.35 83.79,100.11 83,99.32 83,98.48 81.83,97.31 81.83,96.45 81.02,95.63 81.02,94.56 81.04,94.53 DIMM2.90
M_DATA_B41: length 75.2
  TOP w0.165: U27.AP9 v1(103.43,137.16)
  L3 w0.102: v1(103.43,137.16) 102.97,136.7 102.97,136.02 101.85,134.9
  L3 w0.152: DIMM2.91 79.95,90.76 79.95,88.16 79.8,88.01 78.2,88.01 78.05,88.16 78.05,89.51 78.96,90.42 78.96,91.06 79.98,92.08 79.98,93.52 79.76,93.74 79.53,93.74 78.91,94.36 78.91,95.48 79.98,96.55 79.98,97.36 80.84,98.22 80.84,99.24 81.96,100.36 81.96,100.91 81.32,101.55 81.32,101.85 81.48,102.01 81.98,102.01 82.1,102.12 82.1,102.46 81.81,102.76 81.81,102.97 82.05,103.22 82.26,103.22 82.93,102.55 83.14,102.55 83.38,102.8 83.38,103.01 82.72,103.67 82.72,103.89 85.46,106.63 86.36,106.63 86.64,106.91 86.64,118.78 87.47,119.61 87.47,119.96 87.09,120.34 87.09,120.65 93.19,126.76 93.2,126.76 96.16,129.72 96.16,131.01 96.31,131.17 97.1,131.17 97.22,131.29 97.22,131.72 97.1,131.85 96.31,131.85 96.13,132.03 96.13,132.72 96.28,132.87 97.37,132.87 97.68,133.17 98.41,133.17 98.74,132.85 99.18,132.85 99.33,133 99.34,133 99.43,133.1 99.43,133.73 99.61,133.91 100.22,133.91 100.4,134.09 100.4,134.75 100.63,134.98 100.93,134.98 101.26,134.65 101.6,134.65 101.85,134.9
M_DATA_B42: length 76.7
  TOP w0.165: v1(101.6,137.16) 101.63,137.16 102.06,137.59 U27.AP7
  L3 w0.102: v1(101.6,137.16) 101.15,136.7 100.44,136.7 100.29,136.85
  L3 w0.152: DIMM2.96 75.04,91.88 74.8,91.64 74.29,91.64 73.98,91.94 73.98,92.86 74.28,93.16 74.28,93.84 74.06,94.06 73.36,94.06 73.07,94.36 73.07,95.4 74.21,96.54 74.21,97.27 75.08,98.15 75.08,99.25 76.07,100.23 76.07,101.3 76.55,101.78 76.55,101.99 75.96,102.58 75.96,102.79 76.21,103.04 76.42,103.04 77.01,102.45 77.22,102.45 77.47,102.7 77.47,102.91 77.1,103.28 77.1,103.49 77.34,103.74 77.56,103.74 77.92,103.37 78.14,103.37 78.38,103.61 78.38,103.83 78.11,104.09 78.11,104.31 78.36,104.55 78.57,104.55 78.84,104.29 79.06,104.29 79.3,104.53 79.3,104.74 79.03,105.01 79.03,105.23 79.27,105.47 79.49,105.47 79.76,105.2 79.97,105.2 80.21,105.44 80.21,105.66 79.95,105.93 79.95,106.14 80.19,106.39 80.41,106.39 80.67,106.12 80.89,106.12 81.13,106.36 81.13,106.58 80.86,106.84 80.86,107.06 81.11,107.3 81.32,107.3 81.59,107.03 81.81,107.03 82.26,107.49 82.26,107.8 82.05,108.01 82.05,108.4 82.56,108.91 83.61,108.91 83.76,109.06 83.76,109.4 83.61,109.56 82.72,109.56 82.57,109.71 82.57,110.05 82.72,110.21 83.61,110.21 83.76,110.36 83.76,110.7 83.61,110.86 82.72,110.86 82.58,111 82.58,113.82 82.09,114.31 82.09,121.96 82.71,122.58 83.66,122.58 83.84,122.76 83.84,123.29 89.75,129.21 89.75,129.21 93.43,132.88 93.43,134.28 95.64,136.5 96.82,136.5 97.27,136.95 100.19,136.95 100.29,136.85
M_DATA_B43: length 72.8
  TOP w0.165: U27.AP6 101.13,137.61 v1(100.69,137.16)
  L3 w0.152: DIMM2.97 73.44,90.85 73.23,91.07 73.23,91.56 72.97,91.82 72.56,91.82 72.08,92.3 72.08,93.69 72.81,94.43 72.81,95.5 73.96,96.65 73.96,97.49 74.79,98.32 74.79,99.3 74.83,99.34 74.83,99.35 75.81,100.33 75.81,101.32 75.41,101.73 75.41,102.9 76.21,103.7 76.43,103.7 81.9,109.16 81.9,113.49 81.44,113.95 81.44,122.24 82.95,123.75 83.35,123.75 84.58,124.98 84.58,125.19 84.41,125.37 84.41,125.6 84.63,125.83 84.86,125.83 85.05,125.64 85.27,125.64 85.51,125.88 85.51,126.1 85.26,126.35 85.26,126.57 85.5,126.81 85.72,126.81 85.97,126.56 86.18,126.56 86.43,126.8 86.43,127.02 86.17,127.27 86.17,127.48 86.42,127.72 86.63,127.72 86.88,127.47 87.1,127.47 87.34,127.72 87.34,127.93 87.09,128.18 87.09,128.4 87.33,128.64 87.55,128.64 87.8,128.39 88.02,128.39 88.26,128.63 88.26,128.85 88.01,129.1 88.01,129.31 88.25,129.56 88.47,129.56 88.72,129.31 88.93,129.31 89.18,129.55 89.18,129.76 88.92,130.02 88.92,130.23 89.17,130.47 89.38,130.47 89.63,130.22 89.85,130.22 90.09,130.47 90.09,130.68 89.84,130.93 89.84,131.15 90.08,131.39 90.3,131.39 90.55,131.14 90.77,131.14 91.01,131.38 91.01,131.6 90.76,131.85 90.76,132.06 91,132.31 91.21,132.31 91.47,132.06 91.68,132.06 91.92,132.3 91.92,132.51 91.67,132.77 91.67,132.98 91.92,133.22 92.13,133.22 92.38,132.97 92.6,132.97 92.84,133.21 92.84,134.4 95.19,136.75 96.71,136.75 97.16,137.21 100.64,137.21 v1(100.69,137.16)
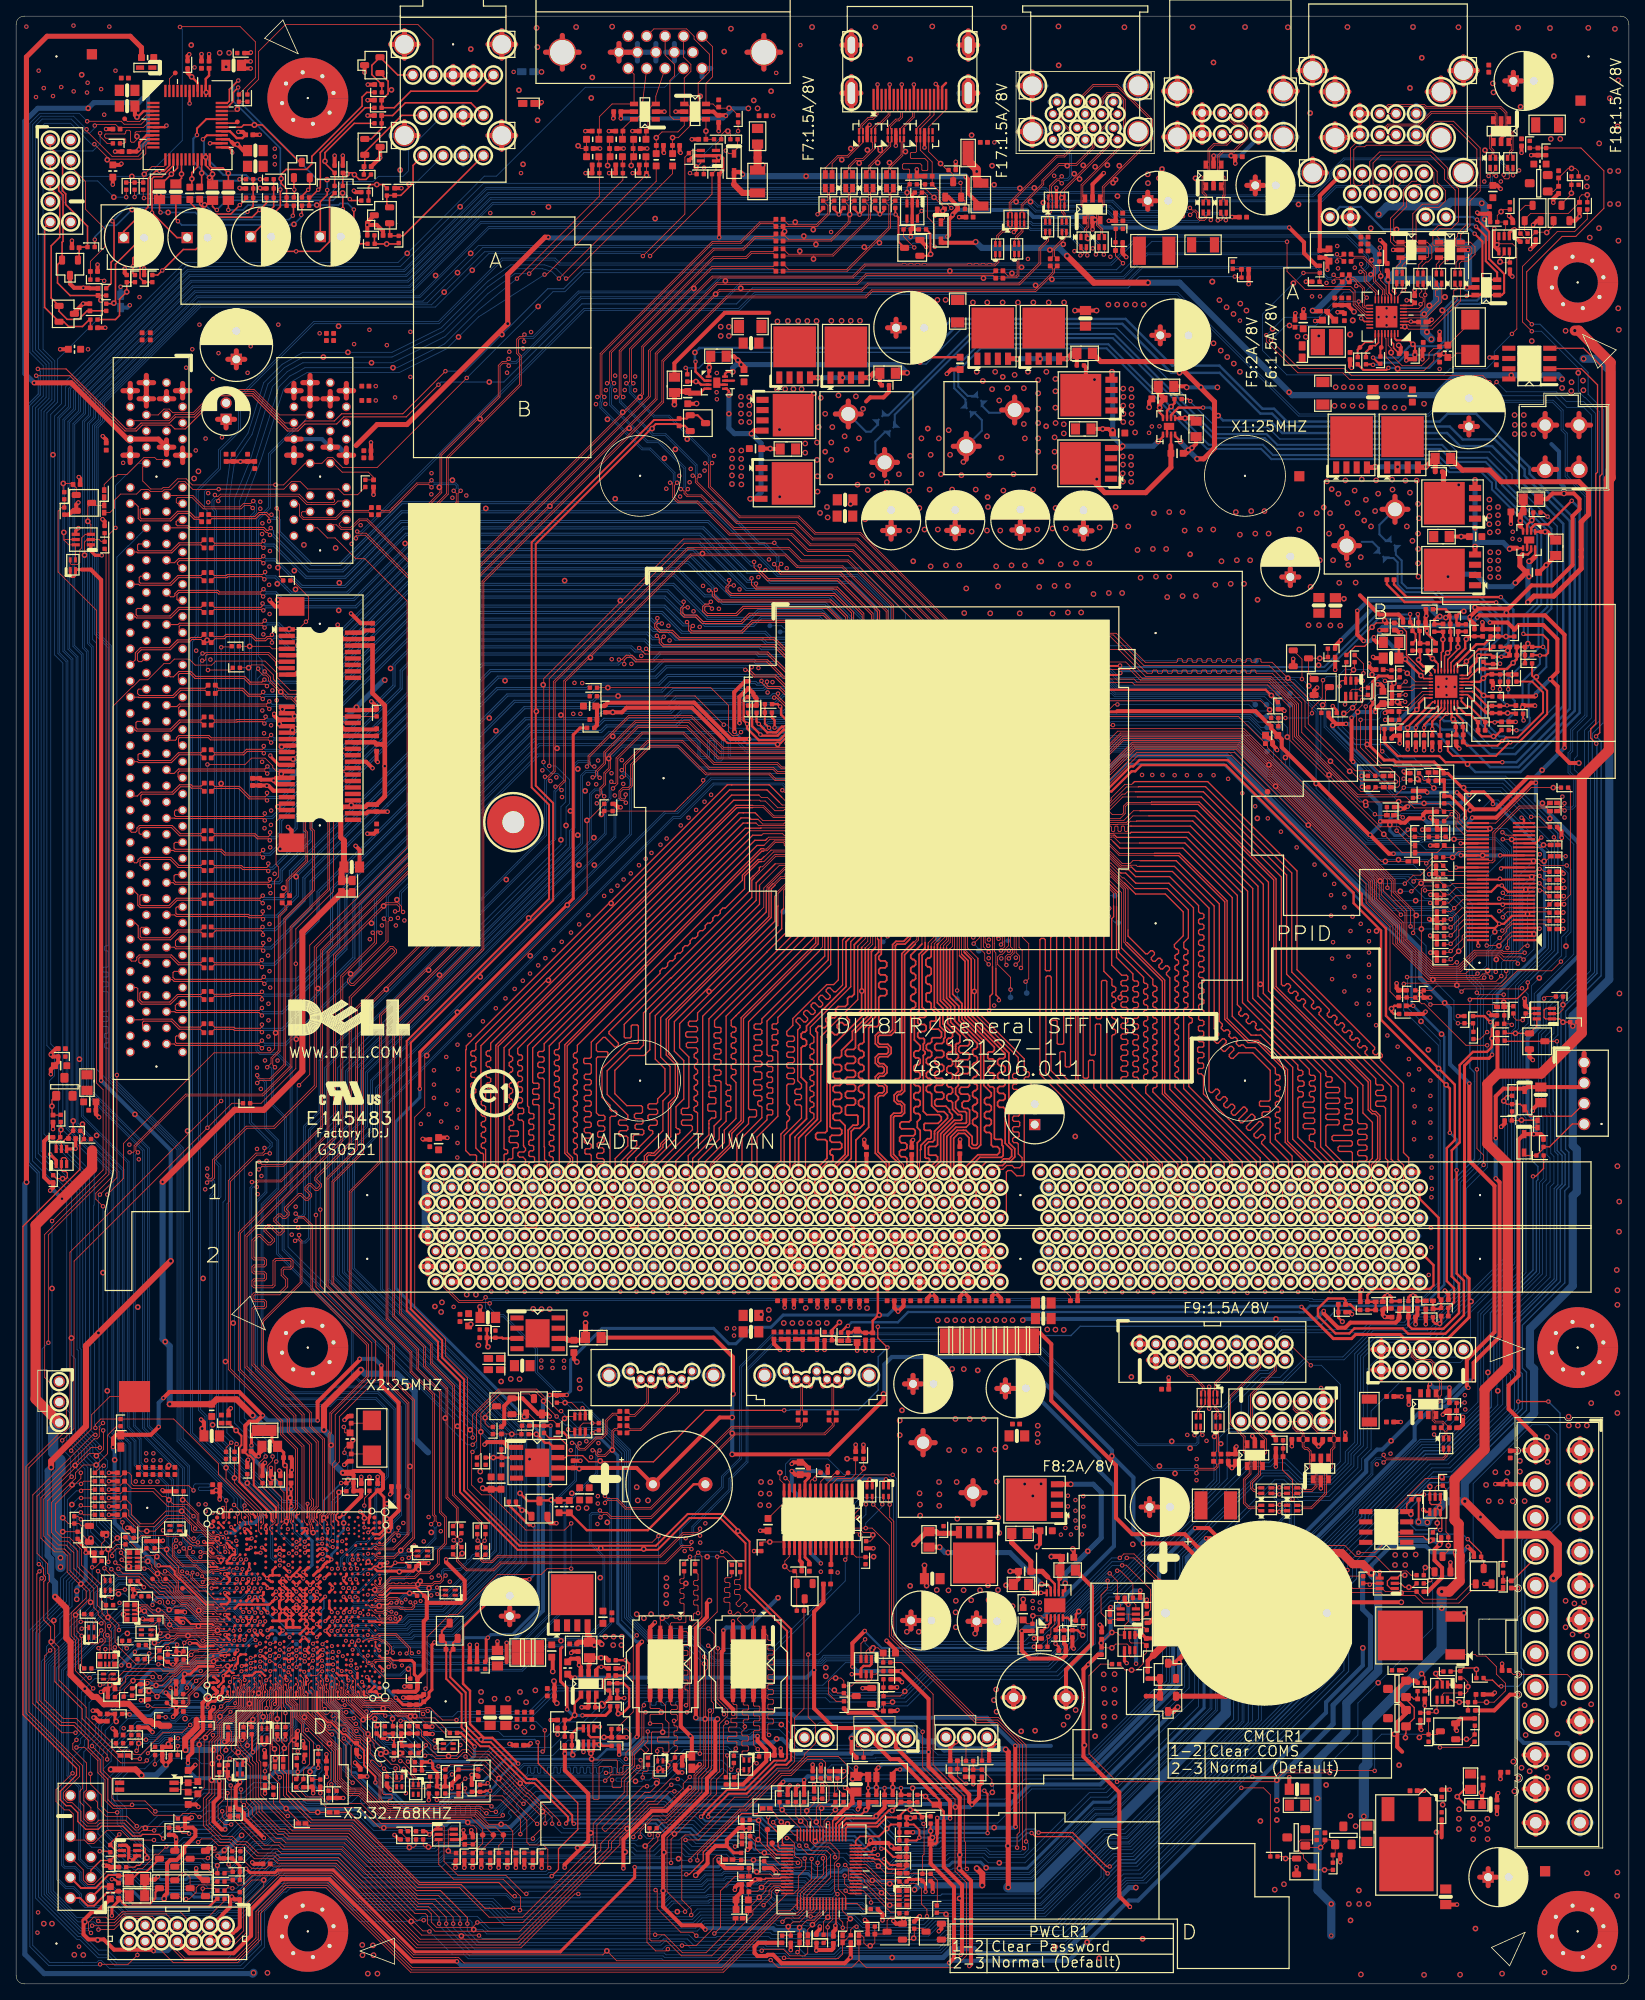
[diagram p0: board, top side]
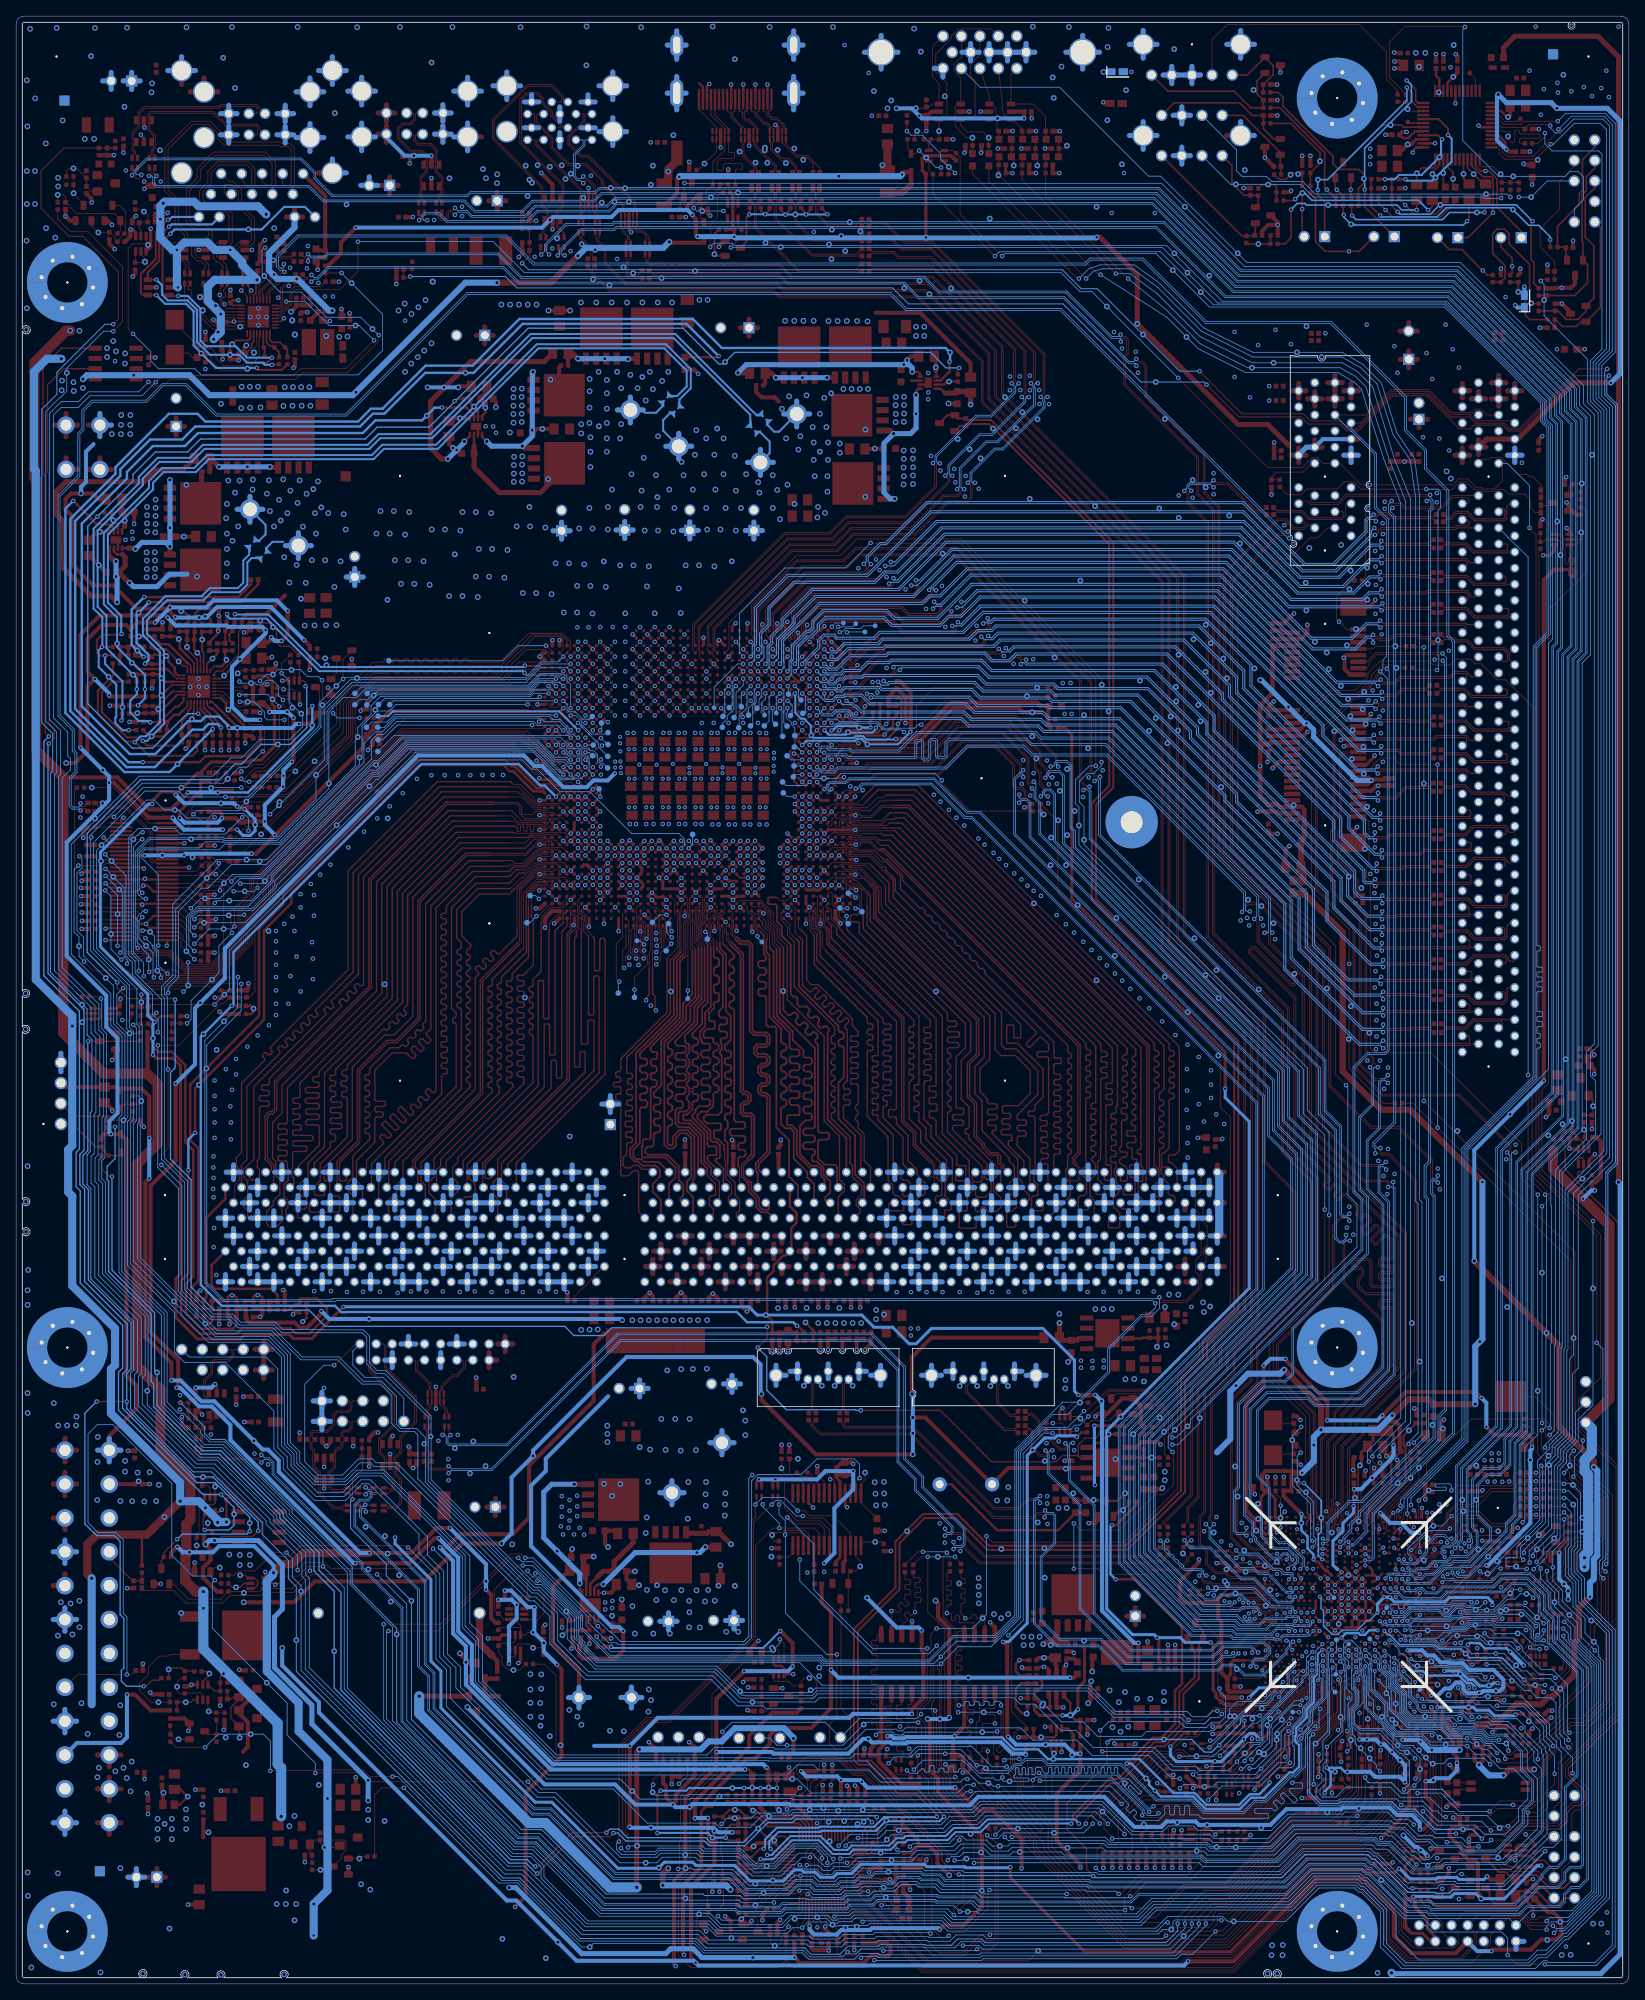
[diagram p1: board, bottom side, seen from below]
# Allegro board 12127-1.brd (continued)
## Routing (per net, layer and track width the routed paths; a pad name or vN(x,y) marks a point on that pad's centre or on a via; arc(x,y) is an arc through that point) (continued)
M_DATA_B44: length 77.5
  TOP w0.165: v1(104.34,136.24) 104.37,136.24 104.8,136.67 U27.AR10
  L3 w0.102: v1(104.34,136.24) 104.8,135.78 104.8,135.15 103.6,133.94
  L3 w0.14: 103.46,133.81 103.6,133.94
  L3 w0.152: DIMM2.209 82.04,86.69 82.19,86.54 82.77,86.54 82.92,86.69 82.92,87.46 82.04,88.34 82.04,89.36 83.03,90.35 83.03,91.24 81.79,92.47 81.79,94.14 81.27,94.66 81.27,95.53 82.09,96.34 82.09,97.2 83.25,98.37 83.25,99.21 84.07,100.03 84.07,101.04 84.65,101.63 85.08,101.63 89.72,106.27 89.72,107 89.74,107.03 89.74,112.08 89.59,112.24 88.74,112.24 88.59,112.39 88.59,112.73 88.74,112.88 89.59,112.88 89.74,113.04 89.74,113.38 89.59,113.53 88.74,113.53 88.59,113.68 88.59,114.03 88.74,114.18 89.59,114.18 89.74,114.33 89.74,114.68 89.59,114.83 88.74,114.83 88.59,114.98 88.59,115.32 88.74,115.48 89.59,115.48 89.74,115.63 89.74,115.97 89.59,116.12 88.74,116.12 88.59,116.28 88.59,116.62 88.74,116.77 89.59,116.77 89.74,116.92 89.74,117.27 89.59,117.42 88.74,117.42 88.59,117.57 88.59,117.91 88.74,118.07 91.2,118.07 91.36,118.22 91.36,118.56 91.2,118.71 90.04,118.71 89.88,118.87 89.88,119.21 90.04,119.36 91.22,119.36 91.37,119.51 91.37,120.64 100.36,129.63 100.36,130.71 100.51,130.86 101.3,130.86 101.45,131.01 101.45,132.09 101.69,132.33 102.56,132.33 102.71,132.49 102.71,133.06 103.46,133.81
M_DATA_B45: length 76.4
  TOP w0.165: U27.AR9 v1(103.43,136.24)
  L3 w0.152: DIMM2.210 81.63,88.95 81.78,88.8 81.78,88.14 81.63,87.99 80.43,87.99 80.28,88.14 80.28,89.69 81.04,90.45 81.04,91.6 80.29,92.35 80.29,93.69 79.99,93.99 79.63,93.99 79.16,94.46 79.16,95.38 80.29,96.51 80.29,97.31 81.09,98.12 81.09,99.14 82.21,100.25 82.21,101.14 82.6,101.52 83.05,101.52 84.33,102.8 84.33,103.02 83.65,103.69 83.65,103.91 83.9,104.15 84.11,104.15 84.79,103.48 85,103.48 85.24,103.72 85.24,103.93 84.57,104.61 84.57,104.82 84.81,105.06 85.03,105.06 85.7,104.39 85.92,104.39 86.16,104.63 86.16,104.85 85.49,105.52 85.49,105.74 85.73,105.98 85.95,105.98 86.62,105.31 86.83,105.31 87.29,105.77 87.29,118.52 88.14,119.36 88.19,119.36 88.48,119.65 88.48,119.87 87.96,120.39 87.96,120.61 88.25,120.89 88.46,120.89 89,120.36 89.2,120.36 89.45,120.61 89.45,120.82 88.95,121.33 88.95,121.54 89.19,121.78 89.4,121.78 89.9,121.29 90.06,121.29 90.36,121.58 90.36,121.75 89.86,122.24 89.86,122.51 96.74,129.39 96.74,130.48 96.89,130.63 98.85,130.63 99,130.78 99,131.35 98.44,131.91 98.44,132.13 98.68,132.37 98.9,132.37 99.12,132.15 99.34,132.15 101.25,134.07 101.91,134.07 102.56,134.72 102.56,135.23 103.43,136.1 v1(103.43,136.24)
M_DATA_B46: length 75.4
  TOP w0.165: U27.AR7 v1(101.6,136.24)
  L3 w0.102: v1(101.6,136.24) 101.01,135.66 99.53,135.66 99.04,135.16 95.54,135.16 95.45,135.08
  L3 w0.152: 95.45,135.08 94.5,134.13 94.5,132.13 85.13,122.76 85.13,121.46 84.96,121.29 83.66,121.29 83.5,121.13 83.5,118.95 83.64,118.82 84.17,118.82 84.33,118.66 84.33,118.32 84.17,118.17 83.64,118.17 83.48,118.01 83.48,117.61 83.63,117.46 84.33,117.46 84.5,117.3 84.5,116.98 84.33,116.82 83.62,116.82 83.47,116.66 83.47,116.32 83.62,116.17 84.89,116.17 85.07,115.99 85.07,115.67 84.92,115.51 84.33,115.51 84.16,115.35 84.16,115.03 84.33,114.86 84.92,114.86 85.07,114.71 85.07,108.46 78.07,101.47 78.07,100.26 77.29,99.48 77.29,98.37 77.28,98.37 77.28,98.34 76.07,97.13 76.07,96.34 75.29,95.57 75.29,94.42 76.24,93.47 76.24,92.15 77.06,91.34 77.06,90.01 76.79,89.75 76.38,89.75 76.01,89.38 76.01,88.32 76.32,88.01 76.79,88.01 77.17,87.64 77.17,86.65 76.81,86.3 76.21,86.3 76.04,86.47 DIMM2.215
M_DATA_B47: length 74.3
  TOP w0.165: v1(100.66,136.25) 101.1,136.7 U27.AR6
  L3 w0.102: 97.24,136.39 97.55,136.7 100.09,136.7 100.54,136.25 v1(100.66,136.25)
  L3 w0.152: DIMM2.216 75.31,88.68 75.31,87.96 75.15,87.8 74.2,87.8 74.03,87.96 74.03,89.52 74.44,89.93 75.07,89.93 75.28,90.14 75.28,91.29 75.92,91.93 75.92,93.27 74.87,94.32 74.87,95.52 75.81,96.46 75.81,97.23 77.03,98.45 77.03,99.58 77.79,100.34 77.79,102.1 84.42,108.73 84.42,111.43 84.26,111.59 83.4,111.59 83.23,111.76 83.23,112.08 83.4,112.24 84.23,112.24 84.4,112.41 84.4,112.72 84.23,112.89 83.44,112.89 83.28,113.05 83.28,113.37 83.44,113.54 84.26,113.54 84.42,113.7 84.42,114.02 84.26,114.19 83.15,114.19 82.99,114.35 82.99,114.74 83.15,114.9 83.32,114.9 83.49,115.07 83.49,115.39 83.32,115.55 82.97,115.55 82.82,115.7 82.82,121.78 82.97,121.93 84.27,121.93 84.48,122.15 84.48,123.02 94.25,132.79 94.25,134.38 95.33,135.45 95.33,135.82 95.74,136.24 97.09,136.24 97.24,136.39
M_DATA_B48: length 84.6
  TOP w0.165: U27.AM10 v1(105.26,138.98)
  L3 w0.102: 99.34,137.59 100.08,137.59 100.1,137.62 103.66,137.62 103.87,137.83 103.87,138.29 104.09,138.51 104.78,138.51 v1(105.26,138.98)
  L3 w0.152: 99.34,137.59 96.94,137.59 96.36,137.01 94.78,137.01 83.73,125.95 83.73,125.45 80.79,122.51 80.79,113.67 81.23,113.23 81.23,110.14 81.03,109.94 80.69,109.94 80.41,109.66 80.41,109.34 80.65,109.11 80.65,108.85 80.41,108.62 80.15,108.62 79.87,108.9 79.66,108.9 79.41,108.65 79.41,108.44 79.69,108.16 79.69,107.9 79.48,107.7 79.23,107.7 78.64,108.28 78.41,108.28 78.18,108.06 78.18,107.82 78.77,107.24 78.77,107.02 78.5,106.75 78.28,106.75 77.7,107.34 77.48,107.34 77.24,107.09 77.24,106.88 77.82,106.3 77.82,106.06 77.62,105.87 77.33,105.87 76.78,106.42 76.57,106.42 76.32,106.18 76.32,105.96 76.93,105.36 76.93,105.11 76.7,104.88 76.49,104.88 75.87,105.5 75.65,105.5 75.41,105.26 75.41,105.04 75.99,104.46 75.99,104.24 75.75,104 75.53,104 74.95,104.59 74.73,104.59 74.49,104.34 74.49,104.13 75.08,103.54 75.08,103.33 74.54,102.79 74.08,102.79 73.93,102.64 73.93,102.29 74.08,102.13 74.77,102.13 74.92,101.98 74.92,101.63 74.77,101.47 74.41,101.47 74.24,101.3 74.24,100.15 73.2,99.11 73.2,98.35 72.29,97.44 72.29,96.34 71.27,95.32 71.27,94.31 71.82,93.75 71.82,92.41 71.82,92.41 71.82,92.2 72.46,91.57 72.81,91.57 72.97,91.41 72.97,90.17 72.81,90.02 72.19,90.02 72.04,90.17 DIMM2.99
M_DATA_B49: length 84.4
  TOP w0.165: v1(105.26,139.9) U27.AL10
  L3 w0.102: v1(105.26,139.9) 105.26,139.6 105.1,139.44 104.2,139.44 103.29,138.53 100.81,138.53
  L3 w0.152: 100.81,138.53 99.54,138.53 99.04,138.04 94.9,138.04 82.13,125.27 82.13,124.76 80.14,122.77 80.14,113.38 80.55,112.97 80.55,110.73 78.84,109.02 78.21,109.02 77.75,108.56 77.53,108.56 77.33,108.77 77.09,108.77 76.87,108.54 76.87,108.31 77.07,108.1 77.07,107.89 76.8,107.61 76.58,107.61 75.9,108.29 75.9,108.48 76.07,108.65 76.07,108.88 75.84,109.11 75.61,109.11 75.44,108.94 75.23,108.94 75.19,108.97 75.01,108.97 74.76,108.73 74.76,108.52 76.12,107.16 76.12,106.94 75.88,106.7 75.66,106.7 74.37,107.99 74.15,107.99 73.91,107.75 73.91,107.54 75.21,106.24 75.21,106.02 74.96,105.78 74.75,105.78 73.77,106.76 73.55,106.76 73.31,106.52 73.31,106.3 74.29,105.32 74.29,105.11 74.05,104.86 73.83,104.86 73.74,104.95 73.42,104.95 73.28,104.81 73.28,103.92 73.42,103.78 74.03,103.78 74.2,103.62 74.2,103.37 74.03,103.2 73.47,103.2 73.32,103.05 73.32,101.7 73.98,101.04 73.98,100.25 72.94,99.21 72.94,98.45 72.03,97.54 72.03,96.46 71.04,95.47 71.04,95.45 71.01,95.42 71.01,94.37 70.88,94.24 70.23,94.24 70.02,94.03 70.02,93.77 70.3,93.49 70.8,93.49 71.04,93.25 DIMM2.100
M_DATA_B50: length 85
  TOP w0.165: U27.AL6 100.69,140.81 v1(100.69,140.85)
  L3 w0.102: 95.29,141.05 95.45,141.05 95.68,140.81 100.65,140.81 v1(100.69,140.85)
  L3 w0.152: DIMM2.105 66.04,91.59 65.89,91.74 64.99,91.74 64.04,92.69 64.04,93.65 63.29,94.39 63.29,95.5 64.08,96.28 64.08,97.21 65.29,98.42 65.29,99.12 66.11,99.94 66.11,100.48 66.29,100.67 66.29,101.25 67.24,102.2 67.75,102.2 69.09,103.54 69.09,116.9 69.25,117.06 71.15,117.06 71.35,117.26 71.35,117.57 71.2,117.72 69.28,117.72 69.13,117.88 69.13,118.22 69.28,118.37 71.2,118.37 71.35,118.52 71.35,118.87 71.2,119.02 70.17,119.02 70.02,119.18 70.02,119.56 70.17,119.71 71.2,119.71 71.35,119.86 71.35,120.95 71.72,121.31 72.84,121.31 72.97,121.44 72.97,122.56 73.38,122.97 75.84,122.97 75.98,123.11 75.98,123.43 75.79,123.62 75.01,123.62 74.88,123.75 74.88,124.14 75.01,124.27 75.77,124.27 75.98,124.47 75.98,125.11 91.92,141.05 95.29,141.05
M_DATA_B51: length 84.1
  TOP w0.165: U27.AM7 101.6,139.9 v1(101.6,139.92)
  L3 w0.102: v1(101.6,139.92) 101.13,140.39 100.5,140.39 100.27,140.61 94.89,140.61
  L3 w0.152: DIMM2.106 64.44,92.75 64.31,92.89 64.31,93.53 64.42,93.65 65.04,93.65 65.31,93.92 65.31,94.2 64.81,94.7 64.81,95.22 65.98,96.39 65.98,97.46 66.9,98.37 66.9,99.11 67.83,100.05 67.83,101.74 67.96,101.87 68.18,101.87 68.33,101.72 68.54,101.72 68.79,101.96 68.79,102.18 68.64,102.33 68.64,102.54 68.88,102.79 69.1,102.79 69.25,102.64 69.46,102.64 69.71,102.88 69.71,103.1 69.56,103.25 69.56,103.46 69.74,103.65 69.74,112.36 69.89,112.51 71.09,112.51 71.25,112.67 71.25,112.99 71.09,113.16 69.89,113.16 69.74,113.31 69.74,113.65 69.89,113.8 71.1,113.8 71.26,113.97 71.26,114.29 71.1,114.45 69.89,114.45 69.74,114.6 69.74,114.95 69.89,115.1 71.09,115.1 71.25,115.27 71.25,115.58 71.09,115.75 69.89,115.75 69.74,115.9 69.74,116.26 69.89,116.41 71.54,116.41 72,116.87 72,120.14 72.52,120.66 73.44,120.66 73.61,120.84 73.61,121.79 74.15,122.33 76.42,122.33 76.62,122.53 76.62,124.23 76.75,124.36 76.75,124.58 76.69,124.64 76.69,124.86 76.94,125.1 77.15,125.1 77.21,125.04 77.43,125.04 77.67,125.28 77.67,125.5 77.61,125.56 77.61,125.78 77.86,126.02 78.07,126.02 78.13,125.96 78.35,125.96 78.61,126.22 78.61,126.73 92.49,140.61 94.89,140.61
M_DATA_B52: length 85.3
  TOP w0.165: U27.AM9 v1(104.34,139.9)
  L3 w0.102: 99.26,138.76 103.2,138.76 v1(104.34,139.9)
  L3 w0.152: DIMM2.218 73.61,88.95 73.77,89.12 73.77,89.6 73.61,89.76 70.98,89.76 70.81,89.93 70.81,91.19 70.96,91.34 71.43,91.34 71.59,91.5 71.59,91.85 71.43,92.01 70.36,92.01 70.2,92.18 70.2,93.2 69.18,94.21 69.18,95.4 70.22,96.44 70.22,97.35 71.24,98.37 71.24,99.21 72.08,100.05 72.08,101.09 72.64,101.65 72.64,107.52 73.45,108.33 73.45,108.55 73.34,108.66 73.34,108.87 73.58,109.12 73.8,109.12 73.91,109.01 74.12,109.01 74.27,109.15 74.27,109.46 74.42,109.61 74.76,109.61 74.91,109.76 74.91,110.11 74.76,110.26 74.42,110.26 74.27,110.41 74.27,113.57 74.42,113.73 74.78,113.73 74.94,113.88 74.94,114.22 74.78,114.38 74.42,114.38 74.27,114.53 74.27,114.77 75.25,115.75 75.49,115.75 75.64,115.59 75.64,114.99 75.81,114.83 76.13,114.83 76.29,114.99 76.29,115.59 76.44,115.75 76.79,115.75 76.94,115.59 76.94,115.25 77.09,115.1 77.44,115.1 77.59,115.25 77.59,115.59 77.74,115.75 78.09,115.75 78.24,115.59 78.24,115.09 78.41,114.92 78.73,114.92 78.89,115.09 78.89,115.59 79.05,115.75 79.33,115.75 79.49,115.91 79.49,123.04 81.48,125.03 81.48,125.54 94.37,138.43 98.62,138.43 98.95,138.76 99.26,138.76
M_DATA_B53: length 85.4
  TOP w0.165: U27.AL9 v1(104.34,140.81)
  L3 w0.102: 98.6,138.89 98.7,138.99 103.14,138.99 103.88,139.73 U27.AL9 v1(104.34,140.81)
  L3 w0.152: 98.6,138.89 98.39,138.68 93.71,138.68 80.83,125.81 80.83,125.3 78.85,123.31 78.85,117.86 78.69,117.7 77.45,117.7 77.29,117.54 77.29,117.21 77.45,117.04 78.68,117.04 78.83,116.89 78.83,116.55 78.68,116.4 74.96,116.4 73.57,115.01 73.57,110.06 72.69,109.17 72.69,108.54 71.98,107.82 71.98,101.7 71.82,101.55 71.82,100.16 70.99,99.32 70.99,98.48 69.97,97.46 69.97,96.55 68.93,95.5 68.93,94.11 69.94,93.09 69.94,92.3 68.93,91.29 68.93,90.5 69.97,89.46 69.97,88.61 70.65,87.93 72.79,87.93 72.94,87.78 72.94,86.4 72.78,86.23 72.21,86.23 72.04,86.4 DIMM2.219
M_DATA_B54: length 84.6
  TOP w0.165: v1(100.68,139.92) 100.68,139.9 U27.AM6
  L3 w0.102: 94.84,140.21 95.04,140.41 100.16,140.41 100.65,139.92 v1(100.68,139.92)
  L3 w0.152: DIMM2.224 67.04,87.97 67.21,87.8 68.03,87.8 68.2,87.97 68.2,89.52 68.03,89.69 66.64,89.69 66.48,89.86 66.48,90.18 66.64,90.35 67.03,90.35 67.19,90.51 67.19,91.73 66.97,91.94 66.42,91.94 65.93,92.43 65.93,94.01 65.19,94.75 65.19,95.25 66.24,96.29 66.24,97.35 67.15,98.27 67.15,98.48 67.15,99.01 68.27,100.12 68.27,100.33 68.27,101.02 70.4,103.15 70.4,108.97 70.55,109.12 70.94,109.12 71.1,109.28 71.1,109.61 70.94,109.78 70.55,109.78 70.4,109.93 70.4,110.41 70.55,110.57 71.74,110.57 71.9,110.73 71.9,111.05 71.74,111.21 70.54,111.21 70.39,111.37 70.39,111.71 70.54,111.86 71.58,111.86 71.91,112.19 71.91,115.77 72.65,116.5 72.65,119.86 72.8,120.02 73.32,120.02 73.51,119.82 74.11,119.82 74.26,119.98 74.26,121.53 74.41,121.68 76.74,121.68 77.27,122.21 77.27,123.96 79.26,125.95 79.26,126.46 92.88,140.08 94.71,140.08 94.84,140.21
M_DATA_B55: length 85.2
  TOP w0.165: U27.AL7 101.6,140.81 v1(101.6,140.82)
  L3 w0.102: v1(101.6,140.82) 101.12,141.3 100.5,141.3 100.42,141.22 99.9,141.22
  L3 w0.152: DIMM2.225 66.04,86.72 66.19,86.56 66.85,86.56 67,86.72 67,87.58 66.64,87.93 64.15,87.93 64,88.09 64,89.31 65.07,90.37 65.07,91.24 63.79,92.52 63.79,93.54 63.04,94.29 63.04,95.39 63.04,95.6 63.82,96.39 63.82,97.31 65.04,98.53 65.04,99.23 65.85,100.05 65.85,100.59 66.04,100.77 66.04,101.78 66.49,102.23 66.49,102.69 66.04,103.14 66.04,103.61 66.19,103.76 68.29,103.76 68.45,103.91 68.45,118.95 91.25,141.76 97.25,141.76 97.78,141.22 99.9,141.22
M_DATA_B56: length 92.5
  TOP w0.165: U27.AJ6 v1(100.68,142.64)
  L3 w0.102: 99.05,142.71 99.44,143.1 100.12,143.1 100.58,142.64 v1(100.68,142.64)
  L3 w0.152: 99.05,142.71 98.6,142.26 90.82,142.26 90.67,142.1 90.67,142.09 67.8,119.22 67.8,108.46 67.65,108.31 65.98,108.31 65.83,108.15 65.83,107.81 65.98,107.66 67.65,107.66 67.8,107.51 67.8,107.16 67.65,107.01 64.89,107.01 64.74,106.86 64.74,106.51 64.89,106.36 67.65,106.36 67.8,106.21 67.8,105.87 67.65,105.71 64.89,105.71 64.74,105.56 64.74,105.22 64.89,105.07 67.65,105.07 67.8,104.91 67.8,104.57 67.65,104.42 64.86,104.42 64.71,104.27 64.71,103.92 64.86,103.77 65.25,103.77 65.4,103.62 65.4,103.28 65.25,103.12 64.86,103.12 64.71,102.97 64.71,102.63 64.86,102.48 65.25,102.48 65.4,102.32 65.4,101.98 65.25,101.83 64.86,101.83 64.13,101.09 64.13,100.23 63.09,99.19 63.09,98.35 63.09,98.14 62.22,97.28 62.22,96.58 62.22,96.37 61.18,95.33 61.18,94.46 62.89,92.75 DIMM2.108
M_DATA_B57: length 92
  TOP w0.165: v1(101.6,142.64) U27.AJ7
  L3 w0.102: 98.77,142.98 99.1,143.3 100.94,143.3 v1(101.6,142.64)
  L3 w0.152: 98.77,142.98 98.31,142.51 90.17,142.51 67.15,119.49 67.15,113.16 67,113 66.29,113 66.13,112.85 66.13,112.5 66.29,112.34 67.02,112.34 67.15,112.22 67.15,111.82 67.02,111.7 64.19,111.7 64.03,111.54 64.03,111.2 64.19,111.05 67,111.05 67.15,110.9 67.15,110.55 67,110.4 64.19,110.4 64.03,110.25 64.03,109.91 64.19,109.75 67,109.75 67.15,109.6 67.15,109.26 67,109.11 64.19,109.11 64.03,108.95 64.03,101.36 63.87,101.2 63.87,100.33 62.83,99.29 62.83,98.25 61.97,97.38 61.97,96.47 60.93,95.43 60.93,94.36 62.05,93.24 62.05,91.98 62.04,91.97 DIMM2.109
M_DATA_B58: length 92.3
  TOP w0.165: v1(100.68,145.39) U27.AF6
  L3 w0.152: v1(100.68,145.39) 100.12,145.95 95.25,145.95 94.89,145.59 89.19,145.59 64.28,120.68 64.28,118.66 64.13,118.5 62.1,118.5 61.12,117.52 61.12,113.06 60.97,112.9 60.07,112.9 59.94,112.78 59.94,112.37 60.07,112.24 60.96,112.24 61.09,112.11 61.09,111.72 60.96,111.59 59.16,111.59 59.03,111.47 59.03,111.07 59.16,110.95 60.99,110.95 61.11,110.82 61.11,110.42 60.99,110.3 59.17,110.3 59.02,110.15 59.02,109.8 59.17,109.65 60.99,109.65 61.11,109.52 61.11,109.13 60.99,109 59.17,109 59.02,108.85 59.02,101.9 58.16,101.04 58.16,100.3 57.09,99.23 57.09,98.43 57.09,98.22 56.25,97.38 56.25,96.39 55.14,95.28 55.14,94.46 56.85,92.75 DIMM2.114
M_DATA_B59: length 92.3
  TOP w0.165: U27.AE6 v1(101.6,145.39)
  L3 w0.102: 100.55,146.21 101.38,145.39 v1(101.6,145.39)
  L3 w0.152: 100.55,146.21 94.87,146.21 94.81,146.28 88.96,146.28 63.63,120.95 63.63,119.32 63.47,119.15 62.37,119.15 61.84,119.15 60.47,117.79 60.47,116.43 60.32,116.28 59.81,116.28 59.66,116.13 59.66,115.77 59.81,115.62 60.32,115.62 60.47,115.47 60.47,115.06 60.34,114.94 58.51,114.94 58.36,114.78 58.36,114.42 58.51,114.27 60.32,114.27 60.47,114.12 60.47,113.78 60.32,113.62 58.51,113.62 58.36,113.47 58.36,113.13 58.51,112.98 59.12,112.98 59.28,112.82 59.28,112.48 59.12,112.33 58.51,112.33 58.36,112.18 58.36,102.41 57.9,101.96 57.9,100.41 56.84,99.34 56.84,98.33 56,97.49 56,96.5 54.88,95.38 54.88,94.36 56.04,93.2 DIMM2.115
M_DATA_B60: length 92.7
  TOP w0.165: U27.AH7 v1(102.51,142.64)
  L3 w0.102: v1(102.51,142.64) 102.97,143.1 102.97,143.76 102.72,144.02 101.41,144.02 101.18,143.79 99.22,143.79 98.91,144.09 98.37,144.09
  L3 w0.152: DIMM2.227 63.88,87.05 62.1,88.84 62.1,89.33 60.88,90.55 60.88,91.18 59.79,92.27 59.79,93.49 58.82,94.46 58.82,95.38 59.94,96.49 59.94,97.49 60.93,98.48 60.93,99.21 61.99,100.28 61.99,101.9 62.15,102.06 62.59,102.06 62.74,102.21 62.74,114.54 62.74,115.46 62.89,115.61 65.73,115.61 65.85,115.74 65.85,116.14 65.73,116.27 64.23,116.27 64.08,116.42 64.08,116.76 64.23,116.92 65.73,116.92 65.85,117.04 65.85,120.03 89.66,143.84 95.14,143.84 95.4,144.09 98.37,144.09
M_DATA_B61: length 92.3
  TOP w0.165: v1(101.6,143.56) U27.AH6
  L3 w0.152: v1(101.6,143.56) 96.12,143.56 96.1,143.57 95.52,143.57 95.1,143.15 89.9,143.15 66.5,119.76 66.5,115.11 66.35,114.96 63.54,114.96 63.39,114.81 63.39,114.47 63.54,114.31 66.26,114.31 66.41,114.16 66.41,113.82 66.26,113.67 63.54,113.67 63.39,113.51 63.39,113.17 63.54,113.02 64.99,113.02 65.14,112.86 65.14,112.52 64.99,112.37 63.54,112.37 63.39,112.22 63.39,101.68 63.23,101.52 62.4,101.52 62.25,101.37 62.25,100.17 61.18,99.11 61.18,98.37 60.22,97.41 60.22,96.47 60.19,96.44 60.19,96.39 59.07,95.27 59.07,94.56 60.05,93.59 60.05,92.37 61.13,91.29 61.13,90.65 61.68,90.1 61.89,90.1 DIMM2.228
M_DATA_B62: length 92.6
  TOP w0.165: U27.AF7 v1(102.51,145.39)
  L3 w0.102: 101.09,146.1 101.35,145.84 102.06,145.84 v1(102.51,145.39)
  L3 w0.152: 101.09,146.1 100.69,146.5 95.17,146.5 94.73,146.94 88.71,146.94 57.7,115.93 57.7,102.49 56.25,101.04 56.25,100.07 55.29,99.11 55.29,98.35 55.26,98.32 55.26,98.29 54.17,97.2 54.17,96.39 53.18,95.4 53.18,94.44 54.2,93.42 54.2,92.31 55.29,91.22 55.29,90.55 55.82,90.02 57.3,90.02 58.04,89.27 DIMM2.233
M_DATA_B63: length 91.5
  TOP w0.165: v1(102.51,146.3) U27.AE7
  L3 w0.102: 100.03,146.76 102.05,146.76 v1(102.51,146.3)
  L3 w0.152: 100.03,146.76 95.47,146.76 94.63,147.6 88.45,147.6 57.05,116.2 57.05,103.94 56.9,103.78 56.61,103.78 56.46,103.63 56.46,103.29 56.61,103.14 56.9,103.14 57.05,102.98 57.05,102.73 56,101.68 56,100.18 55.01,99.19 55.01,98.4 53.92,97.31 53.92,96.5 52.93,95.51 52.93,94.33 53.94,93.32 53.94,92.2 55.03,91.11 55.03,90.39 55.67,89.76 56.23,89.76 DIMM2.234
M_DQS_A_DN0: length 71.8
  TOP w0.102: 140.82,146.55 140.79,146.55 140.75,146.5 137.78,146.5 137.33,146.06 137.33,145.21 137.14,145.01 135.92,145.01 135.54,145.39 134.9,145.39 134.77,145.26 133.33,145.26 133,144.93 U27.AE38
  TOP w0.165: DIMM1.6 168.6,100.65 168.36,100.9 168.36,101.45 169.13,102.23 169.13,107.66 168.61,108.18 168.28,108.18 167.96,108.5 167.96,111.95 156.25,123.67 156.25,137.01 146.71,146.55 140.82,146.55
M_DQS_A_DN1: length 61.5
  TOP w0.102: U27.AJ38 133.16,141.83 133.94,141.83 134.15,141.63 134.8,141.63 134.9,141.73 135.28,141.73 136.86,140.15 141.12,140.15 141.17,140.2 141.19,140.2
  TOP w0.165: 141.19,140.2 144.28,140.2 150.18,134.3 150.18,119.72 152.89,117.01 154.02,117.01 157.67,113.36 157.67,104.48 160.2,101.96 160.2,98.91 DIMM1.15
M_DQS_A_DN2: length 47.3
  TOP w0.102: 137.8,129.09 137.78,129.11 137.72,129.11 137.57,129.26 137.57,135.79 135.28,138.07 134.9,138.07 134.77,137.95 133.5,137.95 133.32,138.13 132.74,138.13 132.6,137.99 U27.AN38
  TOP w0.165: DIMM1.24 150.91,100.65 150.79,100.78 150.79,102.14 142.44,110.49 142.44,124.45 137.8,129.09
M_DQS_A_DN3: length 40
  TOP w0.102: U27.AU36 131.26,133.47 131.26,131.53 131.32,131.47 131.32,131
  TOP w0.165: 131.32,131 131.23,130.91 131.23,130.67 131.69,130.2 131.69,112.16 142.14,101.71 142.14,98.85 DIMM1.33
M_DQS_A_DN4: length 41.1
  TOP w0.102: 86.57,101.77 86.56,101.75 86.49,101.75 86.28,101.54 86.28,100.18 86.41,100.05 86.92,100.05 87.04,100.18 DIMM1.84 ; 99.6,130.78 99.61,130.8 99.61,130.86 99.8,131.05 100.02,131.05 100.11,130.95 100.36,130.95 100.68,131.28 100.68,131.66 100.58,131.76 100.58,132.29 100.34,132.53 100.18,132.53 100.07,132.64 100.07,132.89 U27.AW5
  TOP w0.165: 99.6,130.78 99.46,130.65 99.46,128.94 90.2,119.68 90.2,106.92 88.75,105.47 88.75,103.94 86.57,101.77
M_DQS_A_DN5: length 49.8
  TOP w0.102: 94.1,136.23 94.12,136.25 94.12,136.31 94.89,137.08 96.1,137.08 96.28,137.26 96.77,137.26 97.12,137.61 U27.AP2
  TOP w0.165: 94.1,136.23 93.64,135.77 93.64,132.23 80.91,119.49 80.91,115.3 82.04,114.17 82.04,109.94 81.18,109.08 81.18,105.04 80.21,104.07 80.21,103.74 79.19,102.72 78.71,102.72 78.67,102.76 78.43,102.76 78.2,102.53 78.2,102.29 78.24,102.25 78.24,101.77 77.8,101.33 77.8,100.99 77.89,100.9 77.89,98.91 DIMM1.93
M_DQS_A_DN6: length 59.7
  TOP w0.102: 92.68,140.46 92.71,140.46 92.75,140.51 93.11,140.51 94.13,141.52 95.14,141.52 95.25,141.41 95.25,141.19 95.66,140.79 96.04,140.79 96.16,140.92 96.9,140.92 97.08,141.09 97.31,141.09 U27.AK2 ; 68.62,101.43 68.6,101.41 68.54,101.41 68.27,101.14 68.27,99.67 68.38,99.57 69.2,99.57 69.33,99.69 69.33,100.37 DIMM1.102
  TOP w0.165: 92.68,140.46 92.48,140.46 68.34,116.32 68.34,103.11 69.01,102.44 69.01,101.82 68.62,101.43
M_DQS_A_DN7: length 68.4
  TOP w0.102: 91.31,145.85 91.34,145.85 91.38,145.89 92.63,145.89 93.9,144.62 95.51,144.62 95.66,144.47 96.1,144.47 96.2,144.57 96.81,144.57 97.17,144.93 U27.AF2
  TOP w0.165: 91.31,145.85 89.37,145.85 59.78,116.26 59.78,100.95 59.87,100.86 59.87,98.92 DIMM1.111
M_DQS_A_DP0: length 71.8
  TOP w0.102: U27.AE39 133.6,145.01 133.83,145.01 134.26,144.58 134.77,144.58 134.87,144.48 136.9,144.48 137.54,145.12 137.54,145.97 137.86,146.3 140.75,146.3 140.79,146.25 140.82,146.25
  TOP w0.165: DIMM1.7 168.06,98.78 168.06,101.57 168.84,102.35 168.84,107.54 168.49,107.89 168.16,107.89 167.67,108.38 167.67,111.83 155.96,123.55 155.96,136.89 146.59,146.25 140.82,146.25
M_DQS_A_DP1: length 61.5
  TOP w0.102: 141.19,139.9 141.17,139.9 141.12,139.95 136.77,139.95 135.68,141.04 135.51,141.04 135.25,140.79 134.84,140.79 134.71,140.91 134.16,140.91 134,141.07 134,141.48 133.86,141.63 133.6,141.63 133.48,141.5 133.48,141.31 U27.AJ39
  TOP w0.165: DIMM1.16 159.04,99.69 159.17,99.57 159.78,99.57 159.91,99.69 159.91,101.83 157.38,104.36 157.38,113.24 153.9,116.72 152.77,116.72 149.89,119.6 149.89,134.18 144.16,139.9 141.19,139.9
M_DQS_A_DP2: length 47.3
  TOP w0.102: U27.AN39 133.92,137.61 134.05,137.49 134.05,137.48 134.26,137.26 134.8,137.26 134.9,137.16 135.28,137.16 135.39,137.26 135.81,137.26 137.36,135.7 137.36,129.18 137.58,128.96 137.58,128.9 137.6,128.88
  TOP w0.165: 137.6,128.88 142.15,124.33 142.15,110.37 150.5,102.02 150.5,101.27 150.21,100.98 150.21,98.92 DIMM1.25
M_DQS_A_DP3: length 40
  TOP w0.102: 130.78,130.7 130.42,131.06 130.42,132.32 130.63,132.53 130.95,132.53 131.05,132.63 131.05,132.94 130.95,133.04 U27.AV36
  TOP w0.165: 130.78,130.7 131.4,130.08 131.4,112.04 141.85,101.59 141.85,100 141.72,99.87 141.17,99.87 141.04,100 DIMM1.34
M_DQS_A_DP4: length 41.1
  TOP w0.102: 86.37,101.97 86.35,101.96 86.35,101.89 86.08,101.63 86.08,98.79 DIMM1.85 ; 99.39,130.99 99.41,131.01 99.47,131.01 99.77,131.31 99.77,131.67 99.87,131.77 99.87,133.37 100.23,133.73 U27.AV5
  TOP w0.165: 86.37,101.97 88.46,104.06 88.46,105.59 89.9,107.04 89.9,119.8 99.17,129.06 99.17,130.77 99.39,130.99
M_DQS_A_DP5: length 49.8
  TOP w0.102: 93.89,136.44 93.9,136.45 93.92,136.45 93.94,136.42 94.8,137.28 95.27,137.28 95.34,137.35 95.34,137.61 95.72,137.99 96.1,137.99 96.12,137.97 98.11,137.97 98.4,137.68 U27.AP3
  TOP w0.165: DIMM1.94 77.51,101.12 77.51,101.45 77.95,101.9 77.95,102.13 77.91,102.17 77.91,102.65 78.31,103.06 78.79,103.06 78.83,103.01 79.07,103.01 79.92,103.87 79.92,104.19 80.89,105.16 80.89,109.21 81.74,110.06 81.74,114.05 80.62,115.18 80.62,119.61 93.35,132.35 93.35,135.9 93.89,136.44
M_DQS_A_DP6: length 59.7
  TOP w0.102: 92.68,140.75 92.71,140.75 92.75,140.71 93.03,140.71 94.04,141.73 95.22,141.73 95.4,141.55 95.48,141.55 95.65,141.73 96.05,141.73 96.17,141.6 96.76,141.6 96.93,141.43 97.12,141.43 97.3,141.6 97.67,141.6 98.12,141.15 98.28,141.15 U27.AK3 ; DIMM1.103 68.07,98.78 68.07,101.23 68.4,101.55 68.4,101.61 68.41,101.63
  TOP w0.165: 68.41,101.63 68.72,101.94 68.72,102.32 68.05,102.99 68.05,116.44 92.36,140.75 92.68,140.75
M_DQS_A_DP7: length 68.3
  TOP w0.102: U27.AF3 98.04,145.28 96.2,145.28 96.1,145.39 95.58,145.39 95.43,145.23 95.43,144.98 95.27,144.82 93.98,144.82 92.71,146.1 91.38,146.1 91.34,146.14 91.31,146.14
  TOP w0.165: 91.31,146.14 89.25,146.14 59.49,116.38 59.49,101.1 DIMM1.112
M_DQS_B_DN0: length 92
  TOP w0.127: U27.AF34 v1(129.4,144.47)
  L3 w0.102: 136.25,146.11 136.24,146.09 136.24,146.02 135.88,145.67 133.22,145.67 132.48,144.93 129.63,144.93 129.4,144.7 v1(129.4,144.47)
  L3 w0.165: DIMM2.6 168.89,92.75 168.58,93.07 168.58,93.8 169.16,94.39 169.16,95.28 170.21,96.32 170.21,97.36 169.23,98.34 169.23,99.17 170.26,100.2 170.26,101.07 164.04,107.28 164.04,112.46 163.74,112.76 163.07,112.76 162.77,112.46 162.77,109.19 162.64,109.06 162.23,109.06 162.11,109.19 162.11,117.6 159.05,120.65 159.05,133.43 145.74,146.74 136.88,146.74 136.25,146.11
M_DQS_B_DN1: length 82.1
  TOP w0.127: U27.AK33 v1(127.57,140.81)
  L3 w0.102: v1(127.57,140.81) 127.95,140.44 128.23,140.44 129.2,139.47 133.3,139.47 134.41,140.57 135.18,140.57 135.23,140.62 135.25,140.62
  L3 w0.165: DIMM2.15 160.04,91.72 160.17,91.85 160.17,93.57 159.18,94.56 159.18,95.38 160.2,96.39 160.2,97.28 161.19,98.27 161.19,99.31 160.22,100.28 160.22,101.9 154.62,107.51 154.62,109.38 155.92,110.67 155.92,113.3 153.79,115.42 148.9,115.42 148.68,115.64 148.68,119.3 148.93,119.55 150.18,119.55 150.63,120 150.63,133.17 143.19,140.62 135.25,140.62
M_DQS_B_DN2: length 69.7
  TOP w0.127: U27.AN33 v1(128.49,137.16)
  L3 w0.102: v1(128.49,137.16) 128.94,136.7 128.94,136.08 129.48,135.55 132.96,135.55 134.45,134.06 135.8,134.06 136.3,133.56 136.3,132.69 136.35,132.64 136.35,132.61
  L3 w0.165: DIMM2.24 150.9,92.61 150.34,92.61 150.22,92.74 150.22,93.5 149.2,94.51 149.2,95.38 150.22,96.39 150.22,97.28 151.18,98.25 151.18,99.34 150.19,100.33 150.19,101.7 142.54,109.35 142.54,121.46 142.06,121.95 138.3,121.95 138.18,122.07 138.18,122.62 138.3,122.75 142.21,122.75 142.52,123.06 142.52,123.72 142.21,124.02 138.51,124.02 138.17,124.36 138.17,127.69 136.35,129.51 136.35,132.61
M_DQS_B_DN3: length 68.7
  TOP w0.165: U27.AN29 v1(123.91,137.16)
  L3 w0.102: v1(123.91,137.16) 123.91,137.14 124.36,136.69 124.36,136.05 125.09,135.31 125.09,134.77 126.18,133.68 126.18,133.07 126.13,133.02 126.13,132.99
  L3 w0.165: DIMM2.33 141.2,91.69 140.34,91.69 139.88,92.15 139.88,93.29 138.91,94.26 138.91,95.48 139.9,96.47 139.9,97.46 140.87,98.42 140.87,99.21 139.93,100.15 139.93,101.55 133.52,107.96 133.52,108.45 133.96,108.89 133.96,109.12 133.72,109.36 133.49,109.36 132.94,108.81 132.51,108.81 132.05,109.28 132.05,109.71 132.59,110.26 132.59,110.49 132.35,110.72 132.12,110.72 131.63,110.23 131.2,110.23 130.73,110.7 130.73,111.13 131.66,112.06 131.66,112.23 131.37,112.52 131.19,112.52 130.07,111.4 129.44,111.4 128.94,111.9 128.94,114.25 129.29,114.59 131.53,114.59 131.7,114.76 131.7,115.09 131.53,115.25 129.29,115.25 128.94,115.6 128.94,128.41 126.13,131.22 126.13,132.99
M_DQS_B_DN4: length 71.9
  TOP w0.165: U27.AN13 v1(109.28,138.07)
  L3 w0.102: 106.22,131.76 106.24,131.78 106.24,131.85 106.55,132.16 106.55,134.14 106.96,134.55 106.96,136.44 107.14,136.63 107.54,136.63 107.91,136.99 107.91,137.34 108.18,137.61 108.83,137.61 v1(109.28,138.07)
  L3 w0.165: DIMM2.84 87.04,92.45 86.84,92.25 86.36,92.25 86.16,92.46 86.16,93.42 87.22,94.49 87.22,95.45 88.14,96.37 88.14,97.33 89.2,98.4 89.2,99.24 90.25,100.28 90.25,101.47 90.78,102.01 91.39,102.01 93.83,104.44 93.83,104.45 96.66,107.28 96.66,108.09 96.82,108.26 97.08,108.26 97.38,108.56 97.38,109.22 97.08,109.53 96.8,109.53 96.67,109.65 96.67,110.06 96.8,110.19 97.08,110.19 97.38,110.49 97.38,111.15 97.08,111.46 96.82,111.46 96.66,111.62 96.66,112.28 96.28,112.66 95.06,112.66 94.89,112.83 94.89,113.16 95.06,113.33 96.35,113.33 96.7,113.67 96.7,114.25 96.35,114.6 95.06,114.6 94.89,114.76 94.89,115.09 95.06,115.26 96.35,115.26 96.7,115.6 96.7,116.18 96.35,116.53 95.06,116.53 94.89,116.69 94.89,117.02 95.06,117.19 96.35,117.19 96.7,117.53 96.7,118.11 96.35,118.46 95.06,118.46 94.89,118.62 94.89,118.95 95.06,119.12 96.35,119.12 96.7,119.46 96.7,120.97 105.84,130.11 105.84,131.38 106.22,131.76
M_DQS_B_DN5: length 77
  TOP w0.165: U27.AR8 v1(102.51,136.24)
  L3 w0.102: v1(102.51,136.24) 102.51,136.22 101.55,135.25 99.73,135.25 98.23,133.75 97.51,133.75 97.36,133.91 96.01,133.91 95.96,133.86 95.94,133.86
  L3 w0.165: DIMM2.93 77.47,91.43 77.47,91.92 77.6,92.05 77.9,92.05 78.26,92.41 78.26,93.55 77.22,94.59 77.22,95.4 78.18,96.37 78.18,97.23 79.17,98.22 79.17,99.14 80.21,100.18 80.21,101.14 79.98,101.37 79.98,102.06 85.32,107.39 85.55,107.39 86.02,107.86 86.02,117.15 85.29,117.88 85.29,118.26 85.45,118.42 85.7,118.42 86,118.73 86,119.39 85.7,119.69 84.61,119.69 84.48,119.82 84.48,120.23 84.61,120.35 85.9,120.35 86.84,121.29 86.84,121.78 86.28,122.34 86.28,122.57 86.51,122.81 86.74,122.81 87.31,122.24 87.79,122.24 88.2,122.66 88.2,123.14 87.64,123.71 87.64,123.94 87.88,124.17 88.11,124.17 88.67,123.61 89.16,123.61 89.57,124.02 89.57,124.51 89.01,125.07 89.01,125.3 89.24,125.54 89.48,125.54 90.04,124.98 90.53,124.98 90.94,125.39 90.94,125.88 90.37,126.44 90.37,126.67 90.61,126.91 90.84,126.91 91.41,126.34 91.89,126.34 92.3,126.76 92.3,127.24 91.74,127.8 91.74,128.04 91.98,128.27 92.21,128.27 92.77,127.71 93.26,127.71 93.67,128.12 93.67,128.61 93.11,129.17 93.11,129.4 93.22,129.52 93.34,129.64 93.58,129.64 94.18,129.03 94.72,129.03 95.28,129.59 95.28,130.12 94.56,130.83 94.56,131.11 95.4,131.95 95.4,133.68 95.58,133.86 95.94,133.86
M_DQS_B_DN6: length 85.6
  TOP w0.165: v1(103.41,139.92) 103.41,139.88 U27.AM8
  L3 w0.102: 94.61,139.29 94.64,139.29 94.69,139.34 95.15,139.34 95.59,139.79 96.93,139.79 97.03,139.69 97.03,139.46 97.23,139.26 102.25,139.26 102.51,139.51 102.51,140.19 102.68,140.36 103.24,140.36 103.41,140.19 v1(103.41,139.92)
  L3 w0.165: DIMM2.102 69.04,92.18 68.84,91.97 68.3,91.97 68.1,92.18 68.1,93.62 67.74,93.98 67.31,93.98 67.13,94.16 67.13,95.63 67.26,95.76 67.91,95.76 68.2,96.05 68.2,97.54 68.37,97.71 68.85,97.71 69.16,98.03 69.16,99.16 70.15,100.15 70.15,101.42 70.33,101.6 70.99,101.6 71.35,101.95 71.35,108.08 72.06,108.8 72.06,109.47 72.87,110.28 72.87,115.19 74.71,117.03 74.71,117.79 74.36,118.14 73.87,118.14 73.7,118.3 73.7,118.63 73.87,118.8 75.25,118.8 75.38,118.67 75.38,117.32 75.68,117.02 76.35,117.02 76.65,117.32 76.65,118.65 76.81,118.81 77.85,118.81 78.2,119.16 78.2,119.74 77.85,120.08 75.34,120.08 75.21,120.21 75.21,120.62 75.34,120.75 77.69,120.75 78.22,121.27 78.22,123.57 80.21,125.56 80.21,126.07 93.43,139.29 94.61,139.29
M_DQS_B_DN7: length 92.4
  TOP w0.165: U27.AG6 v1(100.68,144.47)
  L3 w0.102: v1(100.68,144.47) 100.24,144.92 98.53,144.92 97.73,145.72 95.66,145.72 94.85,144.91 94.11,144.91 94.06,144.96 94.04,144.96
  L3 w0.165: 94.04,144.96 89.45,144.96 64.92,120.43 64.92,118.16 64.62,117.86 63.09,117.86 61.75,116.51 61.75,108.41 61.58,108.24 59.97,108.24 59.66,107.94 59.66,107.28 59.97,106.97 61.29,106.97 61.42,106.84 61.42,106.44 61.29,106.31 59.94,106.31 59.65,106.02 59.65,105.33 59.94,105.04 61.16,105.04 61.29,104.91 61.29,104.51 61.16,104.38 59.97,104.38 59.66,104.07 59.66,103.42 59.97,103.11 61.16,103.11 61.29,102.98 61.29,102.58 61.16,102.45 60.29,102.45 59.83,101.99 59.83,100.16 58.88,99.21 58.88,98.37 57.89,97.38 57.89,96.39 56.85,95.35 56.85,94.36 57.84,93.37 57.84,92.13 58.27,91.69 59.2,91.69 DIMM2.111
M_DQS_B_DP0: length 92
  TOP w0.127: v1(130.32,144.47) U27.AF35
  L3 w0.102: 136.47,145.9 136.45,145.88 136.38,145.88 135.97,145.47 133.3,145.47 132.56,144.73 130.57,144.73 v1(130.32,144.47)
  L3 w0.165: DIMM2.7 168.27,91.08 168.27,93.93 168.86,94.51 168.86,95.4 169.9,96.44 169.9,97.23 168.92,98.21 168.92,99.3 169.95,100.33 169.95,100.94 163.74,107.15 163.74,112.33 163.61,112.46 163.2,112.46 163.07,112.33 163.07,109.07 162.77,108.76 162.11,108.76 161.8,109.07 161.8,117.48 158.75,120.53 158.75,133.3 145.62,146.43 137,146.43 136.47,145.9
M_DQS_B_DP1: length 82.1
  TOP w0.127: U27.AL33 128.03,139.48 v1(127.6,139.91)
  L3 w0.102: v1(127.6,139.91) 127.92,140.23 128.15,140.23 129.12,139.26 130.59,139.26 130.59,139.27 133.39,139.27 134.49,140.37 135.18,140.37 135.23,140.32 135.25,140.32
  L3 w0.165: 135.25,140.32 143.06,140.32 150.33,133.05 150.33,120.13 150.06,119.86 148.81,119.86 148.37,119.42 148.37,115.52 148.77,115.12 153.66,115.12 155.61,113.17 155.61,110.8 154.32,109.5 154.32,107.38 159.92,101.78 159.92,100.15 160.88,99.19 160.88,98.4 159.89,97.41 159.89,96.52 158.88,95.5 158.88,94.44 159.87,93.45 159.87,91.97 159.74,91.85 159.17,91.85 159.04,91.97 DIMM2.16
M_DQS_B_DP2: length 69.8
  TOP w0.127: v1(128.49,136.28) 128.48,136.28 128.47,136.28 128.44,136.31 128.42,136.31 U27.AP33
  L3 w0.102: v1(128.49,136.28) 128.49,136.25 129.39,135.35 132.88,135.35 134.37,133.86 135.71,133.86 136.09,133.48 136.09,132.69 136.04,132.64 136.04,132.61
  L3 w0.165: DIMM2.25 150.01,90.88 150.01,92.51 149.91,92.61 149.91,93.37 148.89,94.39 148.89,95.5 149.91,96.52 149.91,97.41 150.88,98.37 150.88,99.21 149.89,100.2 149.89,101.57 142.24,109.22 142.24,121.34 141.94,121.64 138.18,121.64 137.87,121.95 137.87,122.75 138.18,123.06 142.09,123.06 142.21,123.18 142.21,123.59 142.09,123.72 138.39,123.72 137.87,124.23 137.87,127.56 136.04,129.39 136.04,132.61
M_DQS_B_DP3: length 68.7
  TOP w0.165: U27.AN28 v1(123.91,138.07)
  L3 w0.102: v1(123.91,138.07) 124.36,137.63 124.36,137.34 124.36,137.34 124.36,136.98 124.63,136.71 125.01,136.71 125.3,136.42 125.3,134.85 126.38,133.76 126.38,133.07 126.43,133.02 126.43,132.99
  L3 w0.165: 126.43,132.99 126.43,131.35 129.25,128.54 129.25,115.72 129.41,115.56 131.66,115.56 132,115.21 132,114.63 131.66,114.29 129.41,114.29 129.25,114.12 129.25,112.03 129.57,111.71 129.94,111.71 131.06,112.83 131.49,112.83 131.96,112.36 131.96,111.93 131.04,111 131.04,110.82 131.32,110.54 131.5,110.54 132,111.03 132.48,111.03 132.89,110.62 132.89,110.13 132.35,109.59 132.35,109.41 132.64,109.12 132.82,109.12 133.36,109.66 133.85,109.66 134.26,109.25 134.26,108.76 133.82,108.32 133.82,108.09 140.23,101.68 140.23,100.28 141.17,99.34 141.17,98.3 140.21,97.33 140.21,96.34 139.22,95.35 139.22,94.39 140.18,93.42 140.18,92.28 140.46,92 140.84,92 141.04,92.2 DIMM2.34
M_DQS_B_DP4: length 72
  TOP w0.165: v1(108.37,138.07) 108.37,138.07 108.83,137.62 U27.AN12
  L3 w0.102: v1(108.37,138.07) 108.29,138.07 107.86,137.63 107.21,137.63 106.99,137.42 106.99,136.76 106.76,136.53 106.76,134.63 106.34,134.22 106.34,132.24 106.09,131.99 106.02,131.99 106,131.97
  L3 w0.165: 106,131.97 105.54,131.51 105.54,130.24 96.39,121.09 96.39,119.59 96.23,119.42 94.93,119.42 94.59,119.08 94.59,118.49 94.93,118.15 96.23,118.15 96.39,117.99 96.39,117.66 96.23,117.49 94.93,117.49 94.59,117.15 94.59,116.56 94.93,116.22 96.23,116.22 96.39,116.06 96.39,115.73 96.23,115.56 94.93,115.56 94.59,115.22 94.59,114.63 94.93,114.29 96.23,114.29 96.39,114.13 96.39,113.8 96.23,113.63 94.93,113.63 94.59,113.29 94.59,112.7 94.93,112.36 96.15,112.36 96.35,112.16 96.35,111.49 96.7,111.15 96.95,111.15 97.08,111.02 97.08,110.62 96.95,110.49 96.67,110.49 96.37,110.19 96.37,109.53 96.67,109.22 96.95,109.22 97.08,109.09 97.08,108.69 96.95,108.56 96.7,108.56 96.35,108.22 96.35,107.41 93.52,104.58 93.52,104.57 91.26,102.31 90.65,102.31 89.94,101.6 89.94,100.41 88.9,99.36 88.9,98.53 87.83,97.46 87.83,96.49 86.92,95.58 86.92,94.61 85.85,93.55 85.85,92.33 86.14,92.04 86.14,90.96 DIMM2.85
M_DQS_B_DP5: length 77
  TOP w0.165: U27.AP8 102.52,137.16 v1(102.51,137.16)
  L3 w0.102: v1(102.51,137.16) 102.06,136.7 102.06,136.05 101.46,135.45 99.78,135.45 99.64,135.45 98.15,133.96 97.6,133.96 97.44,134.11 96.01,134.11 95.96,134.16 95.94,134.16
  L3 w0.165: DIMM2.94 77.04,92.56 77.25,92.35 77.78,92.35 77.95,92.53 77.95,93.42 76.91,94.46 76.91,95.53 77.88,96.49 77.88,97.36 78.87,98.35 78.87,99.26 79.91,100.3 79.91,101.02 79.68,101.24 79.68,102.18 85.19,107.7 85.42,107.7 85.71,107.99 85.71,117.03 84.99,117.75 84.99,118.39 85.33,118.73 85.57,118.73 85.7,118.85 85.7,119.26 85.57,119.39 84.48,119.39 84.18,119.69 84.18,120.35 84.48,120.66 85.77,120.66 86.53,121.42 86.53,121.65 86.06,122.12 85.97,122.21 85.97,122.7 86.38,123.11 86.87,123.11 87.43,122.55 87.67,122.55 87.9,122.78 87.9,123.02 87.34,123.58 87.34,124.06 87.75,124.48 88.24,124.48 88.8,123.92 89.03,123.92 89.27,124.15 89.27,124.38 88.7,124.95 88.7,125.43 89.12,125.84 89.6,125.85 90.17,125.28 90.4,125.28 90.63,125.52 90.63,125.75 90.07,126.31 90.07,126.8 90.48,127.21 90.97,127.21 91.53,126.65 91.77,126.65 92,126.88 92,127.12 91.44,127.68 91.44,128.16 91.85,128.58 92.34,128.58 92.9,128.01 93.13,128.01 93.37,128.25 93.37,128.48 92.8,129.04 92.8,129.53 93.22,129.94 93.7,129.94 94.31,129.34 94.59,129.34 94.97,129.72 94.97,130 94.26,130.71 94.26,131.24 95.1,132.08 95.1,133.81 95.45,134.16 95.94,134.16
M_DQS_B_DP6: length 85.6
  TOP w0.165: U27.AL8 v1(103.43,140.81)
  L3 w0.102: 94.61,139.6 94.64,139.6 94.69,139.55 95.06,139.55 95.51,139.99 97.02,139.99 97.23,139.78 97.23,139.55 97.32,139.46 102.17,139.46 102.3,139.6 102.3,140.28 102.59,140.57 103.18,140.57 v1(103.43,140.81)
  L3 w0.165: DIMM2.103 68.04,91.8 67.79,92.05 67.79,93.5 67.62,93.68 67.18,93.68 66.83,94.03 66.83,95.76 67.13,96.06 67.78,96.06 67.89,96.18 67.89,97.67 68.25,98.02 68.72,98.02 68.86,98.15 68.86,99.29 69.85,100.28 69.85,101.55 70.21,101.9 70.87,101.9 71.04,102.08 71.04,108.21 71.75,108.92 71.75,109.6 72.56,110.41 72.56,115.32 74.4,117.16 74.4,117.67 74.24,117.83 73.74,117.83 73.4,118.17 73.4,118.76 73.74,119.1 75.38,119.1 75.68,118.8 75.68,117.45 75.8,117.33 76.22,117.33 76.34,117.45 76.34,118.78 76.69,119.12 77.73,119.12 77.89,119.28 77.89,119.61 77.73,119.78 75.21,119.78 74.9,120.09 74.9,120.74 75.21,121.05 77.57,121.05 77.91,121.4 77.91,123.7 79.9,125.69 79.9,126.19 93.31,139.6 94.61,139.6
M_DQS_B_DP7: length 92.4
  TOP w0.165: U27.AG7 v1(101.6,144.47)
  L3 w0.102: 94.04,144.66 94.06,144.66 94.11,144.71 94.93,144.71 95.74,145.52 97.64,145.52 98.45,144.71 99.2,144.71 99.31,144.6 99.31,144.17 99.5,143.99 101,143.99 101.49,144.47 v1(101.6,144.47)
  L3 w0.165: 94.04,144.66 89.58,144.66 65.23,120.31 65.23,118.03 64.74,117.55 63.22,117.55 62.05,116.38 62.05,108.28 61.71,107.94 60.1,107.94 59.97,107.81 59.97,107.4 60.1,107.28 61.42,107.28 61.72,106.97 61.72,106.31 61.42,106.01 60.07,106.01 59.96,105.89 59.96,105.46 60.07,105.35 61.29,105.35 61.59,105.04 61.59,104.38 61.29,104.08 60.1,104.08 59.97,103.95 59.97,103.54 60.1,103.41 61.29,103.41 61.59,103.11 61.59,102.45 61.29,102.14 60.41,102.14 60.13,101.87 60.13,100.04 59.18,99.09 59.18,98.25 58.19,97.26 58.19,96.27 57.15,95.22 57.15,94.49 58.14,93.5 58.14,92.25 58.39,92 58.98,92 59.21,92.23 59.21,92.59 DIMM2.112
M_MAA_A0: length 44.9
  TOP w0.102: 107.64,130.39 108.27,131.02 108.27,132.09 108.77,132.59 108.89,132.59 109.3,132.99 109.3,133.51 U27.AU13
  TOP w0.216: DIMM1.188 103.04,99.01 104.14,100.11 104.14,104.62 105.73,106.21 105.73,118.52 105.9,118.69 106.76,118.69 106.98,118.91 106.98,122.31 107.19,122.53 107.75,122.53 107.97,122.75 107.97,123.18 107.75,123.39 107.19,123.39 106.98,123.61 106.98,124.04 107.19,124.26 107.75,124.26 107.97,124.47 107.97,124.9 107.75,125.12 107.19,125.12 106.98,125.34 106.98,125.77 107.19,125.98 107.75,125.98 107.97,126.2 107.97,126.63 107.75,126.85 107.19,126.85 106.98,127.06 106.98,127.38 107.29,127.69 107.29,130.04 107.64,130.39
M_MAA_A1: length 46.4
  TOP w0.102: 112.72,129.12 112.72,130.6 113.04,130.93 113.04,132.48 U27.AV16
  TOP w0.14: 111.75,101.86 111.79,101.83 111.79,100.34 111.75,100.31 111.75,100.28
  TOP w0.165: 111.75,100.28 110.83,99.36 110.83,97.81 110.28,97.25 110.28,95.9 110.67,95.5 110.67,95.12 110.5,94.95 DIMM1.181
  TOP w0.216: 111.75,101.86 111.75,101.87 111.75,101.88 111.75,104.29 112.12,104.65 112.12,105.83 111.75,106.19 111.75,106.91 112.12,107.27 112.12,107.7 111.9,107.92 111.54,107.92 111.33,108.14 111.33,108.57 111.54,108.78 111.9,108.78 112.12,109 112.12,109.43 111.9,109.65 111.54,109.65 111.33,109.86 111.33,110.29 111.54,110.51 111.9,110.51 112.12,110.73 112.12,111.16 111.9,111.37 111.54,111.37 111.33,111.59 111.33,112.02 111.54,112.24 111.9,112.24 112.12,112.45 112.12,112.89 111.9,113.1 111.54,113.1 111.33,113.32 111.33,113.75 111.54,113.96 111.9,113.96 112.12,114.18 112.12,114.61 111.9,114.83 111.54,114.83 111.33,115.04 111.33,115.48 111.54,115.69 111.9,115.69 112.12,115.91 112.12,116.33 111.39,117.06 111.39,120.05 111.97,120.62 111.97,127.66 112.66,128.34 112.66,128.4 112.72,128.47 112.72,129.12
M_MAA_A2: length 45.9
  TOP w0.102: 112.34,128.95 112.34,130.51 112.82,130.99 112.82,132.31 112.6,132.53 112.48,132.53 112.15,132.85 112.15,133.63 U27.AU16
  TOP w0.14: 110.47,101.38 110.3,101.21 110.3,99.01 DIMM1.61
  TOP w0.216: 112.34,128.95 110.95,127.56 110.95,127.24 111.16,127.03 111.33,127.03 111.55,126.81 111.55,126.38 111.33,126.16 111.16,126.16 110.95,125.95 110.95,125.51 111.16,125.3 111.33,125.3 111.55,125.08 111.55,124.65 111.33,124.43 111.16,124.43 110.95,124.22 110.95,123.79 111.16,123.57 111.33,123.57 111.55,123.35 111.55,122.92 111.33,122.71 111.16,122.71 110.95,122.49 110.95,122.06 111.16,121.84 111.33,121.84 111.55,121.63 111.55,121.2 111.33,120.98 111.16,120.98 110.95,120.76 110.95,107.11 110.73,106.89 109.81,106.89 109.59,106.67 109.59,106.24 109.81,106.03 111.28,106.03 111.5,105.81 111.5,105.38 111.28,105.16 109.78,105.16 109.57,104.95 109.57,104.5 109.78,104.29 110.25,104.29 110.47,104.07 110.47,103.64 110.25,103.42 109.76,103.42 109.54,103.21 109.54,102.78 109.76,102.56 110.25,102.56 110.47,102.34 110.47,101.38
M_MAA_A3: length 45.7
  TOP w0.102: 113.1,128.69 113.1,129.07 113.86,129.83 113.86,130.83 113.75,130.93 113.75,131.41 113.4,131.77 U27.AW17
  TOP w0.14: 112.13,103.4 112.13,102.08 112.03,101.98 112.03,101.76 112.03,101.76 112.03,101.07 112.03,99.92 111.29,99.18 111.29,97.93 111.66,97.56
  TOP w0.165: 111.66,97.56 111.66,96.98 111.53,96.85 DIMM1.180
  TOP w0.216: 112.13,103.4 112.19,103.46 112.19,103.97 113.02,104.8 113.35,104.8 113.47,104.93 113.47,105.71 113.35,105.84 112.73,105.84 112.6,105.97 112.6,106.58 112.73,106.71 114.34,106.71 114.73,107.1 114.73,107.49 114.45,107.77 112.93,107.77 112.5,108.2 112.5,115.11 112.73,115.34 112.73,115.56 112.5,115.79 112.5,116.54 112.64,116.68 112.64,117.11 112.51,117.24 112.03,117.24 111.81,117.45 111.81,117.88 112.03,118.1 112.64,118.1 112.85,118.32 112.85,118.75 112.64,118.96 112.03,118.96 111.81,119.18 111.81,119.61 112.03,119.83 112.64,119.83 112.85,120.04 112.85,120.62 112.35,121.13 112.35,127.54 113.1,128.29 113.1,128.69
M_MAA_A4: length 48.4
  TOP w0.102: 113.48,128.64 113.48,128.99 114.06,129.57 114.06,130.91 113.96,131.01 113.96,132.09 113.51,132.53 113.39,132.53 113.07,132.85 113.07,133.63 U27.AU17
  TOP w0.165: 112.31,101.09 112.31,100.99 112.29,100.97 112.29,99 DIMM1.59
  TOP w0.216: 113.48,128.64 113.48,127.41 113.26,127.19 113.04,127.19 112.83,126.98 112.83,126.33 113.04,126.11 113.26,126.11 113.48,125.9 113.48,125.25 113.26,125.03 113.04,125.03 112.83,124.82 112.83,124.17 113.04,123.95 113.26,123.95 113.48,123.74 113.48,123.09 113.26,122.87 112.98,122.87 112.85,122.75 112.85,121.92 112.98,121.8 113.26,121.8 113.48,121.58 113.48,120.96 114.07,120.37 114.07,119.51 113.94,119.38 113.49,119.38 113.36,119.25 113.36,118.52 113.49,118.39 114.37,118.39 114.76,118 114.76,117.46 114.62,117.32 113.67,117.32 113.54,117.2 113.54,116.81 113.32,116.6 113.09,116.6 112.88,116.38 112.88,115.95 113.09,115.74 113.32,115.74 113.54,115.52 113.54,115.09 113.32,114.87 113.09,114.87 112.88,114.66 112.88,114.22 113.09,114.01 113.32,114.01 113.54,113.79 113.54,113.36 113.32,113.14 113.09,113.14 112.88,112.93 112.88,112.5 113.09,112.28 113.32,112.28 113.54,112.06 113.54,111.63 113.32,111.42 113.09,111.42 112.88,111.2 112.88,110.77 113.09,110.55 113.32,110.55 113.54,110.34 113.54,108.89 114.27,108.15 115.06,108.15 115.51,107.71 115.51,107.34 113.89,105.72 113.89,105.41 113.89,105.41 113.89,104.64 113.68,104.42 113.18,104.42 112.71,103.95 112.71,102.5 112.84,102.37 113.16,102.37 113.28,102.25 113.28,102.06 112.31,101.09
M_MAA_A5: length 45.3
  TOP w0.102: 113.86,128.58 113.86,128.96 114.98,130.08 114.98,131.1 114.31,131.77 U27.AW18
  TOP w0.216: DIMM1.58 113.04,100.96 114.27,102.2 114.27,102.54 114.06,102.76 113.26,102.76 113.13,102.88 113.13,103.71 113.26,103.84 114.06,103.84 114.27,104.05 114.27,105.56 116.1,107.39 116.1,107.77 115.75,108.13 115.75,108.38 115.3,108.83 114.13,108.83 113.92,109.05 113.92,109.48 114.13,109.7 114.82,109.7 115.04,109.91 115.04,110.34 114.82,110.56 114.13,110.56 113.92,110.78 113.92,111.21 114.13,111.42 114.82,111.42 115.04,111.64 115.04,112.07 114.82,112.29 114.13,112.29 113.92,112.5 113.92,112.93 114.13,113.15 114.82,113.15 115.04,113.37 115.04,113.8 114.82,114.01 114.13,114.01 113.92,114.23 113.92,114.66 114.13,114.88 114.82,114.88 115.04,115.09 115.04,115.53 114.82,115.74 114.13,115.74 113.92,115.96 113.92,116.39 114.13,116.6 114.82,116.6 115.04,116.82 115.04,117.2 115.19,117.35 115.19,118.11 114.55,118.75 114.55,120.42 113.86,121.11 113.86,128.58
M_MAA_A6: length 46.2
  TOP w0.102: 114.38,129.01 115.19,129.82 115.19,131.18 114.67,131.7 114.67,132.29 114.43,132.53 114.25,132.53 113.74,133.04 U27.AV17
  TOP w0.165: DIMM1.178 112.8,97.09 112.8,99.47 113.21,99.87 113.36,99.87 113.82,100.33 113.82,100.58 113.82,100.58
  TOP w0.216: 114.38,129.01 114.24,128.88 114.24,121.67 114.94,120.98 114.94,119.05 116.13,117.86 116.13,117.48 115.91,117.26 115.63,117.26 115.42,117.04 115.42,116.61 115.63,116.4 115.91,116.4 116.13,116.18 116.13,115.75 115.91,115.53 115.63,115.53 115.42,115.32 115.42,114.88 115.63,114.67 115.91,114.67 116.13,114.45 116.13,114.02 115.91,113.8 115.63,113.8 115.42,113.59 115.42,113.16 115.63,112.94 115.91,112.94 116.13,112.73 116.13,112.29 115.91,112.08 115.63,112.08 115.42,111.86 115.42,111.43 115.63,111.21 115.91,111.21 116.13,111 116.13,110.57 115.91,110.35 115.63,110.35 115.42,110.13 115.42,109.7 115.63,109.49 115.91,109.49 116.13,109.27 116.13,108.45 116.79,107.78 117.14,107.78 117.27,107.66 117.27,107.22 117.14,107.09 116.34,107.09 114.66,105.41 114.66,102.04 113.82,101.21 113.82,100.58
M_MAA_A7: length 48.3
  TOP w0.102: 115,128.47 115,128.74 115.59,129.33 115.59,131.35 115.12,131.82 115.12,132.52 114.87,132.77 114.87,133.4 114.67,133.6 114.67,134.51 U27.AT18
  TOP w0.216: 115,128.47 115,122.07 115.89,121.18 115.89,119.26 118.24,116.92 118.24,116.54 118.02,116.32 117.11,116.32 116.89,116.1 116.89,115.67 117.11,115.46 118.02,115.46 118.24,115.24 118.24,114.81 118.02,114.59 117.11,114.59 116.89,114.38 116.89,113.94 117.11,113.73 118.02,113.73 118.24,113.51 118.24,113.08 118.02,112.86 117.11,112.86 116.89,112.65 116.89,112.22 117.11,112 118.02,112 118.24,111.79 118.24,111.4 118.02,111.19 117.2,111.19 116.99,110.97 116.99,110.54 117.2,110.32 118.02,110.32 118.24,110.11 118.24,109.66 118.02,109.45 117.53,109.45 117.32,109.23 117.32,108.78 117.53,108.56 118.02,108.56 118.24,108.34 118.24,106.65 117.81,106.22 116.55,106.22 115.42,105.09 115.42,101.03 DIMM1.56
M_MAA_A8: length 46.9
  TOP w0.102: U27.AU18 114.31,133.59 114.67,133.24 114.67,132.69 114.9,132.45 114.9,131.75 115.39,131.26 115.39,129.53 114.62,128.76 114.62,128.47
  TOP w0.165: DIMM1.177 113.54,95.46 113.54,96.09 114.04,96.59 114.04,97.51 113.82,97.74 113.39,97.74 113.26,97.87 113.26,99.19 114.27,100.2 114.27,100.96
  TOP w0.216: 114.27,100.96 114.27,101.12 115.04,101.88 115.04,105.25 116.5,106.71 117.75,106.71 117.86,106.81 117.86,108 117.69,108.17 116.95,108.17 116.51,108.6 116.51,109.35 116.85,109.69 116.85,109.99 116.51,110.33 116.51,111.08 116.85,111.42 116.85,111.72 116.51,112.06 116.51,112.81 116.85,113.15 116.85,113.45 116.51,113.79 116.51,114.53 116.85,114.87 116.85,115.17 116.51,115.51 116.51,115.95 116.51,116.47 116.64,116.6 116.85,116.6 117.04,116.79 117.04,117.57 115.51,119.1 115.51,121.02 114.62,121.91 114.62,128.47
M_MAA_A9: length 48.9
  TOP w0.102: 115.77,128.31 116.11,128.65 116.11,131.42 115.58,131.94 115.58,133.2 115.34,133.45 115.22,133.45 114.9,133.77 114.9,134.54 U27.AT19
  TOP w0.216: 115.77,128.31 115.77,122.38 116.91,121.24 116.91,119.47 118.74,117.65 119.62,116.77 119.62,104.04 119.19,103.61 118.52,103.61 118.17,103.95 118.17,104.91 117.63,105.46 116.87,105.46 116.27,104.86 116.27,100.98 116.26,100.98 116.26,100.05 116.82,99.49 116.82,98.33 116.04,97.55 DIMM1.175
M_MAA_A10: length 45.1
  TOP w0.102: 106.56,128.57 106.56,130.36 107.48,131.29 107.48,131.7 U27.AW11
  TOP w0.216: DIMM1.70 103.18,102.79 103.18,105.87 103.78,106.48 104.27,106.48 104.39,106.6 104.39,107.59 104.27,107.72 102.97,107.72 102.84,107.85 102.84,108.74 103.06,108.96 103.87,108.96 104.09,109.18 104.09,109.61 103.87,109.82 103.06,109.82 102.84,110.04 102.84,110.47 103.06,110.69 103.87,110.69 104.09,110.9 104.09,111.34 103.87,111.55 103.06,111.55 102.84,111.77 102.84,112.2 103.06,112.41 103.87,112.41 104.09,112.63 104.09,113.06 103.87,113.28 103.06,113.28 102.84,113.49 102.84,113.93 103.06,114.14 103.87,114.14 104.09,114.36 104.09,114.79 103.87,115.01 103.06,115.01 102.84,115.22 102.84,115.65 103.06,115.87 103.87,115.87 104.09,116.09 104.09,117.96 106.06,119.94 106.06,127.99 106.56,128.49 106.56,128.57
M_MAA_A11: length 46.2
  TOP w0.102: U27.AV19 115.23,132.78 115.36,132.65 115.36,131.87 115.84,131.39 115.84,129.14 115.39,128.68 115.39,128.43
  TOP w0.216: 115.39,128.43 115.39,122.23 116.39,121.22 116.39,119.42 119.2,116.61 119.2,116.15 118.99,115.94 118.83,115.94 118.62,115.72 118.62,115.29 118.83,115.08 118.99,115.08 119.2,114.86 119.2,114.43 118.99,114.21 118.83,114.21 118.62,114 118.62,113.56 118.83,113.35 118.99,113.35 119.2,113.13 119.2,112.7 118.99,112.48 118.83,112.48 118.62,112.27 118.62,111.84 118.83,111.62 118.99,111.62 119.2,111.41 119.2,110.97 118.99,110.76 118.83,110.76 118.62,110.54 118.62,110.11 118.83,109.89 118.99,109.89 119.2,109.68 119.2,109.25 118.99,109.03 118.83,109.03 118.62,108.81 118.62,108.38 118.83,108.17 118.99,108.17 119.2,107.95 119.2,107.52 118.99,107.3 118.83,107.3 118.62,107.09 118.62,106.66 118.83,106.44 118.99,106.44 119.2,106.22 119.2,104.16 119.03,103.99 118.75,103.99 118.55,104.18 118.55,105.07 117.79,105.84 117.47,105.84 116.71,105.84 115.89,105.02 115.89,101.14 115.88,101.13 115.88,99.89 116.04,99.73 DIMM1.55
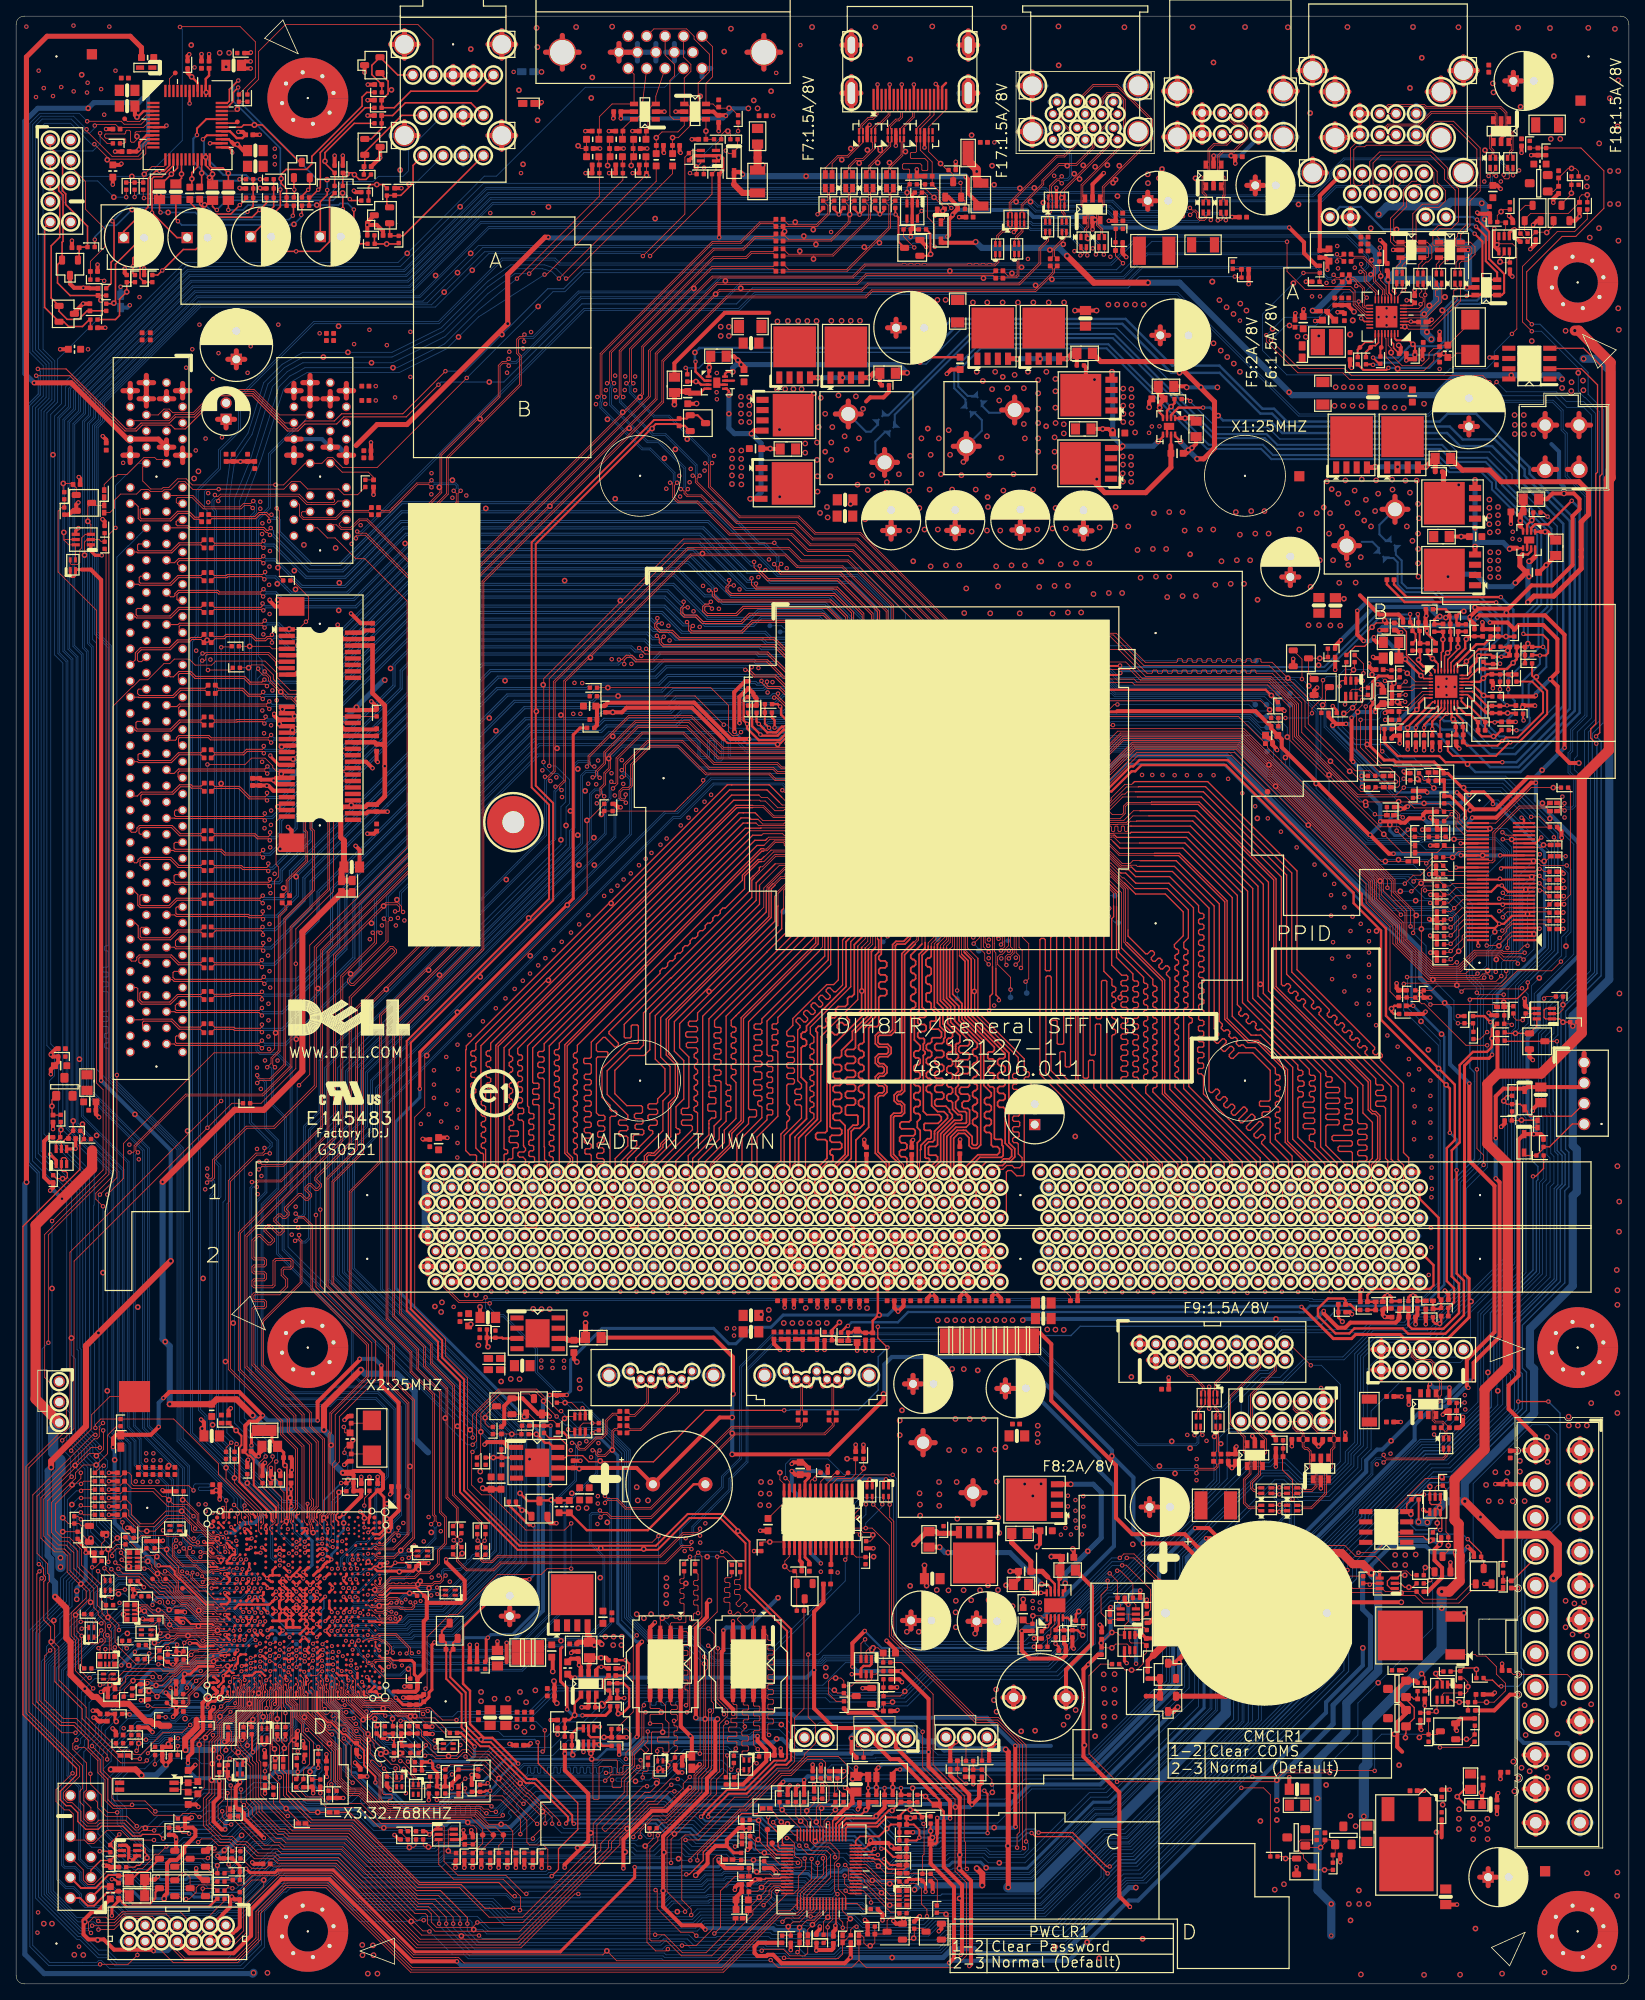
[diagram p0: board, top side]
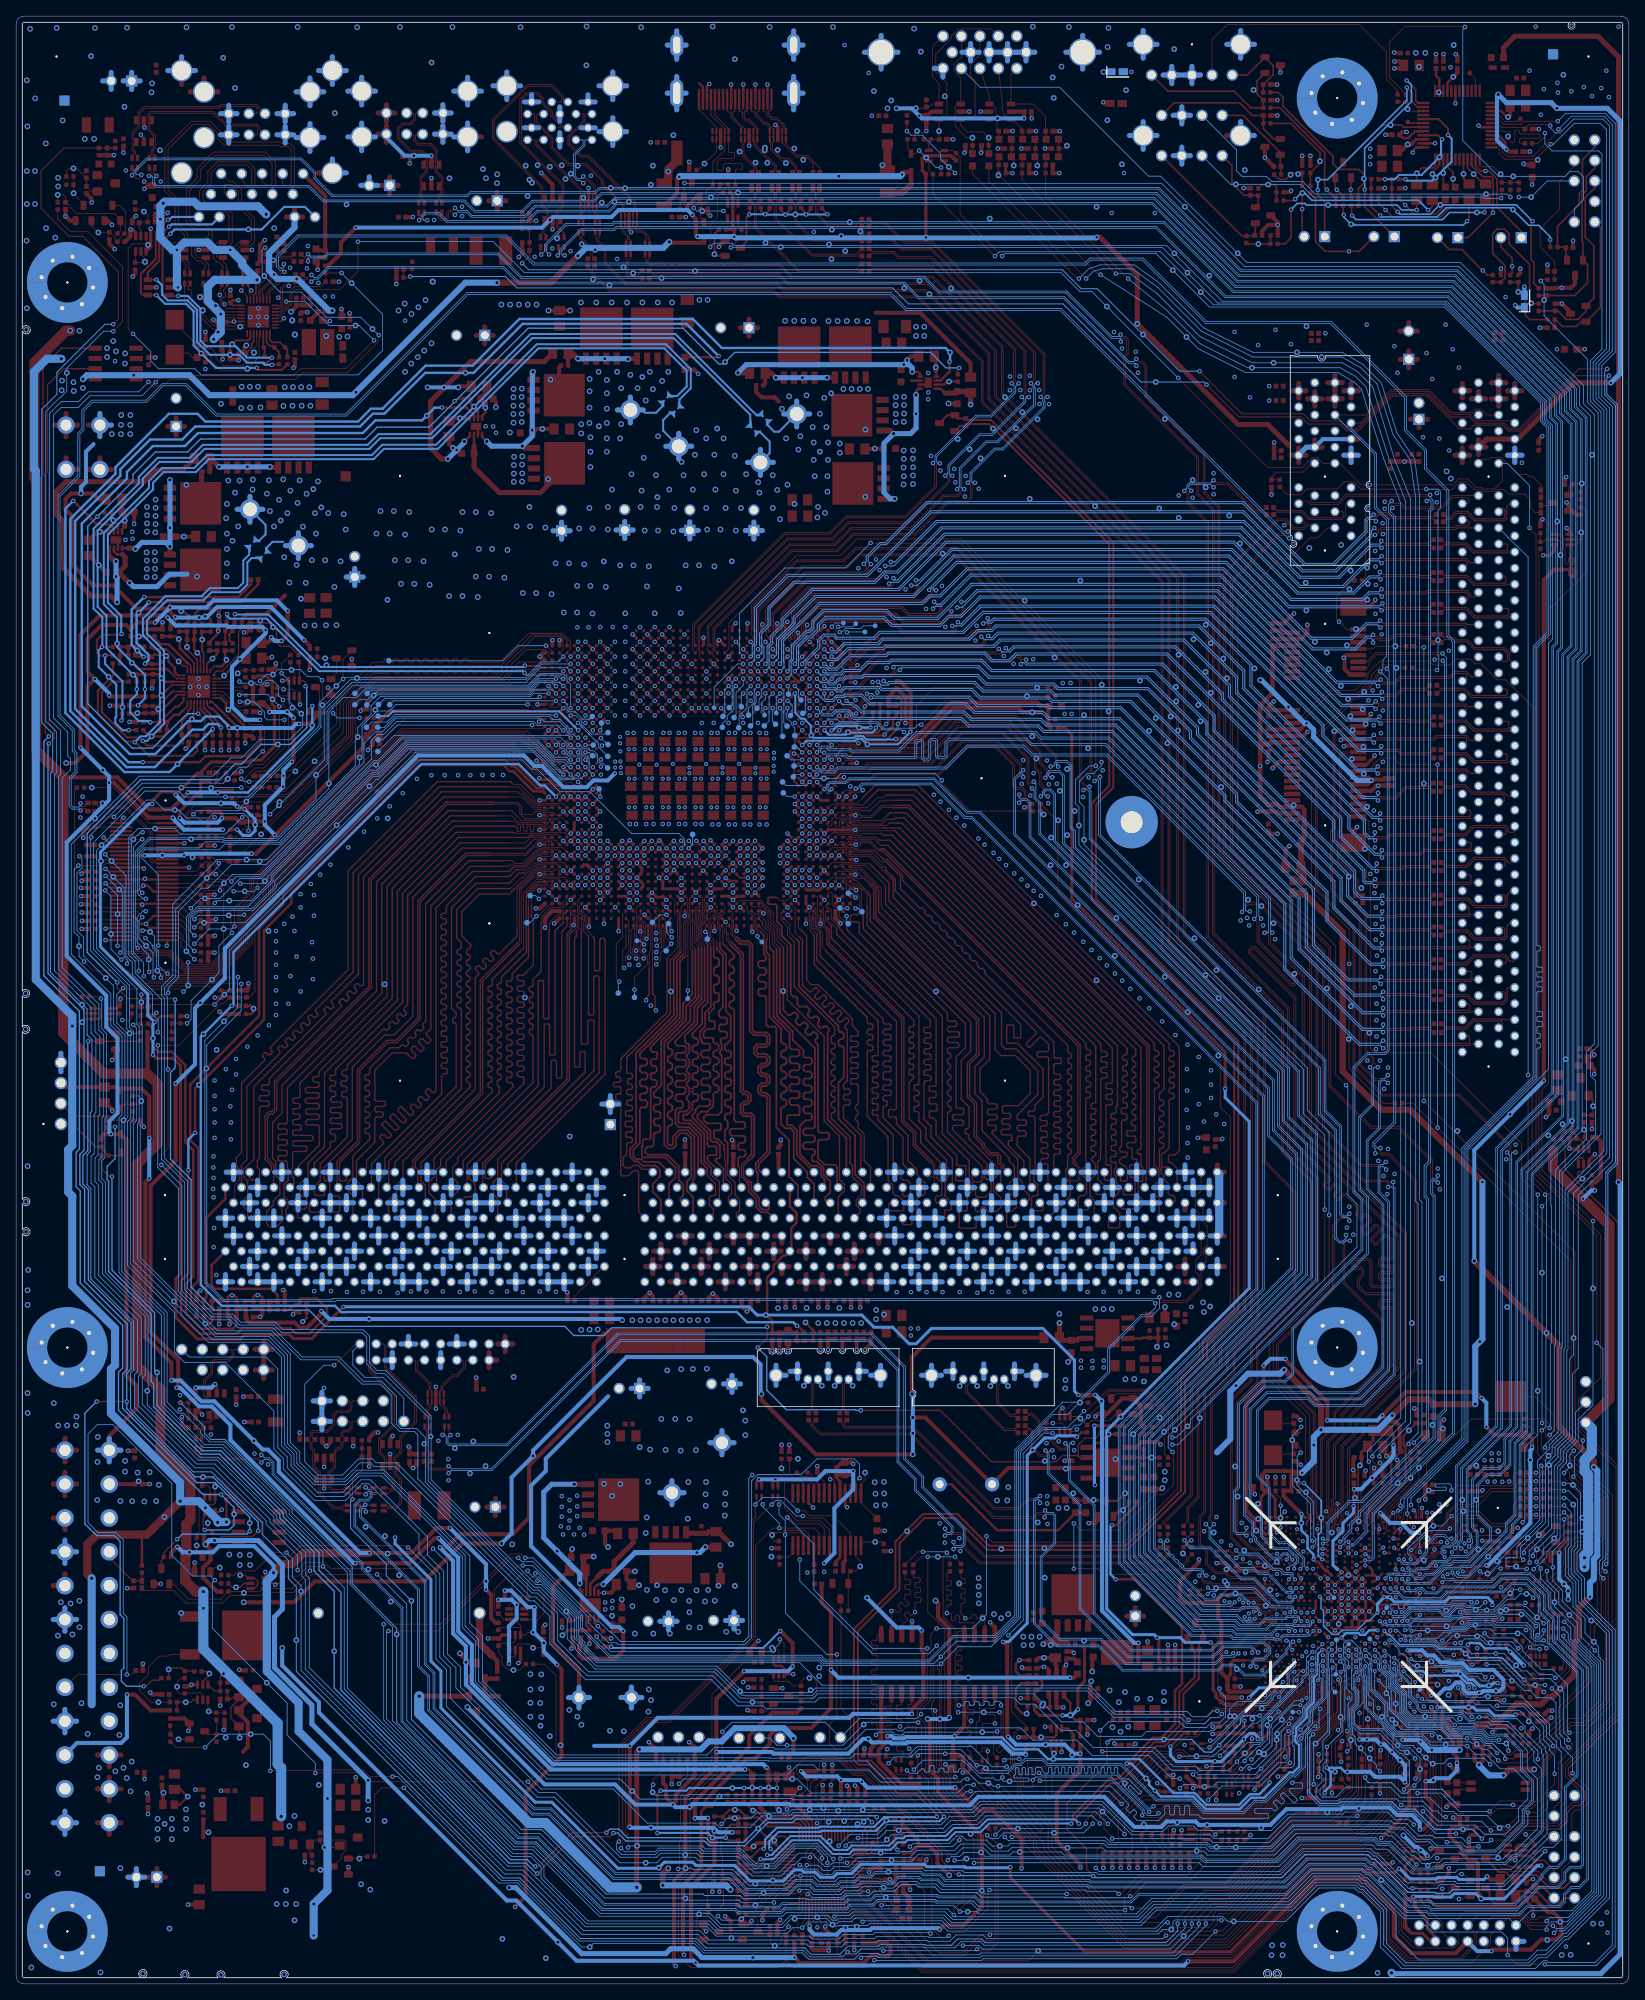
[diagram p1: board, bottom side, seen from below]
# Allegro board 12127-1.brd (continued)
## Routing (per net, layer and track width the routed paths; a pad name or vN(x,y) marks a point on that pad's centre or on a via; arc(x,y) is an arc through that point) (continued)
M_MAA_A12: length 47.8
  TOP w0.102: U27.AU19 115.8,133.38 115.8,132.08 116.37,131.51 116.37,128.42 116.15,128.2
  TOP w0.216: 116.15,128.2 116.15,122.71 117.3,121.56 117.3,121.27 117.3,119.63 120,116.93 120,111.42 120.93,110.49 120.93,110.11 120.71,109.89 120.31,109.89 120.09,109.68 120.09,109.25 120.31,109.03 120.71,109.03 120.93,108.81 120.93,108.38 120.71,108.17 120.31,108.17 120.09,107.95 120.09,107.52 120.31,107.3 120.71,107.3 120.93,107.09 120.93,106.65 120.71,106.44 120.31,106.44 120.09,106.22 120.09,105.79 120.31,105.58 120.71,105.58 120.93,105.36 120.93,104.03 121.15,103.81 121.69,103.81 121.97,103.54 121.97,103.1 121.68,102.81 119.26,102.81 117.82,101.37 117.82,99.67 117.26,99.11 117.26,97.76 117.63,97.4 117.63,97.16 117.33,96.85 DIMM1.174
M_MAA_A13: length 41
  TOP w0.102: U27.AY10 104.05,131.38 104.05,130.36 103.26,129.58
  TOP w0.216: 103.26,129.58 102.92,129.24 102.92,123.67 98.02,118.77 98.02,118.22 97.8,118.01 97.57,118.01 97.36,117.79 97.36,117.36 97.57,117.14 97.8,117.14 98.02,116.93 98.02,116.5 97.8,116.28 97.57,116.28 97.36,116.06 97.36,112.42 98.02,111.76 98.02,107.26 95.96,105.21 95.96,100.38 94.82,99.24 94.82,98.43 94.82,98.42 94.82,97.08 DIMM1.196
M_MAA_A14: length 48
  TOP w0.102: U27.AT20 116.47,134.54 116.47,132.83 116.43,132.79 116.43,132.13 116.97,131.59 116.97,127.51 117,127.49
  TOP w0.216: 117,127.49 117.68,126.81 117.68,121.12 117.68,120.11 117.68,119.79 120.27,117.2 121.31,116.16 121.31,115.77 121.09,115.56 120.62,115.56 120.5,115.43 120.5,114.82 120.62,114.69 121.09,114.69 121.31,114.48 121.31,114.05 121.09,113.83 120.76,113.83 120.55,113.62 120.55,113.18 120.76,112.97 121.09,112.97 121.31,112.75 121.31,112.32 121.09,112.1 120.76,112.1 120.55,111.89 120.55,111.46 120.76,111.24 121.09,111.24 121.31,111.02 121.31,104.85 121.44,104.72 122.14,104.72 122.27,104.6 122.27,103.99 122.4,103.86 122.4,102.7 122.2,102.49 119.5,102.49 118.23,101.22 118.23,100 119.04,99.19 DIMM1.172
M_MAA_A15: length 45.3
  TOP w0.102: 117.55,127.97 117.55,133.46 U27.AU21
  TOP w0.216: 117.55,127.97 117.64,127.88 117.64,127.86 118.44,127.06 118.44,120.8 118.44,120.11 123.11,115.43 123.11,104.29 123.84,103.56 123.84,102.54 123.28,101.98 122.84,101.98 122.33,101.47 120.7,101.47 120.16,100.93 120.16,100.08 121.05,99.19 121.05,98.22 120.04,97.21 DIMM1.171
M_MAA_B0: length 59.2
  TOP w0.216: U27.AL19 115.26,139.44 v1(115.68,139.86)
  L3 w0.102: 115.23,137.34 115.23,139.41 v1(115.68,139.86)
  L3 w0.191: 115.23,137.34 115.19,137.29 115.19,134.08 115.74,133.53 115.74,126.91 109.31,120.48 109.31,120.47 109.28,120.44 109.28,105.1 106.25,102.07 106.25,100.37 106.25,100.13 105.19,99.07 105.19,98.29 104.11,97.21 104.11,96.42 103.15,95.47 103.15,94.25 102.1,93.19 102.1,92.31 101.11,91.32 101.11,90.27 102.43,88.95 DIMM2.188
M_MAA_B1: length 59.8
  TOP w0.216: U27.AK23 v1(119.34,140.81)
  L3 w0.102: 118.6,128.24 118.6,128.47 118.22,128.84 118.22,130.9 118.64,131.32 118.64,137.67 118.89,137.92 U27.AK23 v1(119.34,140.81)
  L3 w0.191: DIMM2.181 110.04,89.48 110.81,90.25 110.81,91.49 110.15,92.15 110.15,93.56 109.27,94.43 109.27,95.31 110.27,96.3 110.27,97.42 111.14,98.3 111.14,98.33 111.16,98.35 111.16,98.59 111.16,98.99 112.27,100.11 112.27,100.35 112.27,101 113.39,102.11 113.39,102.12 113.56,102.29 113.56,113.7 114.22,114.36 114.22,119.81 118.6,124.19 118.6,128.24
M_MAA_B2: length 63.4
  TOP w0.216: U27.AM22 v1(118.43,138.98)
  L3 w0.102: v1(118.43,138.98) 117.98,138.54 117.98,137.9 118.4,137.48 118.4,131.59 118.31,131.5
  L3 w0.191: DIMM2.61 109.86,91.03 109.86,93.43 108.98,94.31 108.98,94.55 108.98,94.56 108.98,95.43 109.97,96.43 109.97,97.58 110.86,98.47 110.86,99.11 111.98,100.23 111.98,101.12 113.09,102.23 113.09,107.09 112.9,107.28 112.27,107.28 112.11,107.44 112.11,107.87 112.27,108.04 112.9,108.04 113.09,108.23 113.09,108.61 112.9,108.8 112.27,108.8 112.11,108.97 112.11,109.4 112.27,109.56 112.9,109.56 113.09,109.75 113.09,114.17 113.28,114.36 113.58,114.36 113.77,114.55 113.77,114.93 113.58,115.12 113.28,115.12 113.09,115.31 113.09,115.69 113.28,115.88 113.58,115.88 113.77,116.07 113.77,116.45 113.58,116.64 113.28,116.64 113.09,116.83 113.09,117.21 113.28,117.4 113.58,117.4 113.77,117.6 113.77,117.98 113.58,118.17 113.28,118.17 113.09,118.36 113.09,118.74 113.28,118.93 113.58,118.93 113.77,119.12 113.77,119.5 113.58,119.69 113.28,119.69 113.09,119.88 113.09,120.33 113.38,120.62 113.65,120.62 113.89,120.38 114.16,120.38 114.43,120.65 114.43,120.92 114.19,121.15 114.19,121.42 114.46,121.69 114.73,121.69 114.97,121.46 115.24,121.46 115.5,121.73 115.5,122 115.27,122.23 115.27,122.5 116.84,124.07 117.11,124.07 117.35,123.84 117.62,123.84 117.89,124.11 117.89,124.38 117.65,124.61 117.65,124.88 118.16,125.39 118.16,126.4 117.93,126.63 117.93,131.12 118.31,131.5
M_MAA_B3: length 57.2
  TOP w0.216: v1(119.34,138.07) U27.AM23
  L3 w0.102: v1(119.34,138.07) 119.34,137.88 118.84,137.38 118.84,132.21 119.22,131.82 119.22,128.72 119.04,128.54 119.04,128.3
  L3 w0.191: DIMM2.180 111.04,88.33 111.23,88.14 111.77,88.14 111.96,88.33 111.96,89.58 111.77,89.77 111.46,89.77 111.27,89.96 111.27,91.56 111.97,92.26 111.97,93.28 110.81,94.44 110.81,95.49 111.87,96.54 111.87,97.4 112.81,98.35 112.81,99.31 113.94,100.45 113.94,101.24 114,101.3 114,113.52 114.67,114.19 114.67,119.5 119.04,123.87 119.04,128.3
M_MAA_B4: length 59.6
  TOP w0.216: v1(119.37,137.16) 119.34,137.16 U27.AP23
  L3 w0.191: DIMM2.59 112.26,91.07 112.26,93.4 111.1,94.56 111.1,95.36 112.16,96.42 112.16,97.28 113.1,98.23 113.1,99.19 114.27,100.36 114.27,101.05 114.45,101.22 114.45,102.6 114.64,102.79 115.05,102.79 115.25,102.98 115.25,103.36 115.05,103.55 114.64,103.55 114.45,103.74 114.45,104.13 114.64,104.32 115.05,104.32 115.25,104.51 115.25,104.89 115.05,105.08 114.64,105.08 114.45,105.27 114.45,105.65 114.64,105.84 115.05,105.84 115.25,106.03 115.25,106.41 115.05,106.6 114.64,106.6 114.45,106.79 114.45,107.17 114.64,107.36 115.05,107.36 115.25,107.55 115.25,107.94 115.05,108.13 114.64,108.13 114.45,108.32 114.45,108.7 114.64,108.89 115.05,108.89 115.25,109.08 115.25,109.46 115.05,109.65 114.64,109.65 114.45,109.84 114.45,110.22 114.64,110.41 115.05,110.41 115.25,110.6 115.25,110.98 115.05,111.17 114.64,111.17 114.45,111.36 114.45,111.75 114.64,111.94 115.05,111.94 115.25,112.13 115.25,112.51 115.05,112.7 114.64,112.7 114.45,112.89 114.45,113.33 115.12,114.01 115.12,119.32 119.49,123.69 119.49,124.05 119.49,128.57 119.61,128.69 119.61,131.27 119.99,131.65 119.99,136.53 v1(119.37,137.16)
M_MAA_B5: length 58
  TOP w0.216: U27.AL23 v1(119.34,139.9)
  L3 w0.191: DIMM2.58 113.04,94.21 112.98,94.27 112.98,95.15 112.98,95.5 113.82,96.33 113.82,97.24 114.98,98.4 114.98,99.37 115.82,100.2 115.82,101.42 115.69,101.55 115.69,116.15 115.88,116.34 117.09,116.34 117.28,116.53 117.28,116.91 117.09,117.1 115.88,117.1 115.69,117.29 115.69,117.67 115.88,117.86 117.09,117.86 117.28,118.05 117.28,118.43 117.09,118.62 115.88,118.62 115.69,118.81 115.69,119.16 115.88,119.35 117.09,119.35 117.28,119.55 117.28,120.85 117.33,120.89 120.02,123.59 120.02,131.08 120.57,131.62 120.57,135.99 120.83,136.25 120.83,138.41 v1(119.34,139.9)
M_MAA_B6: length 52.5
  TOP w0.102: v1(120.61,126.43) 120.12,126.92 120.12,127.79 119.67,128.23 119.67,131.08 U27.AY24
  L3 w0.191: DIMM2.178 113.04,91.34 113.85,92.15 113.85,93.82 113.27,94.39 113.27,95.38 114.11,96.22 114.11,97.12 115.27,98.28 115.27,99.25 116.11,100.08 116.11,100.26 116.13,100.29 116.13,112.67 116.31,112.84 117.53,112.84 117.72,113.04 117.72,113.42 117.53,113.61 116.31,113.61 116.13,113.78 116.13,114.19 116.31,114.37 117.53,114.37 117.72,114.56 117.72,114.94 117.53,115.13 116.31,115.13 116.13,115.31 116.13,115.71 116.31,115.89 117.51,115.89 117.72,116.1 117.72,120.66 117.77,120.71 120.5,123.44 120.5,126.31 v1(120.61,126.43)
M_MAA_B7: length 54.8
  TOP w0.102: v1(120.56,128.72) 120.17,129.11 120.17,130.59 120.36,130.79 120.36,132.43 120.71,132.78 U27.AV25
  L3 w0.191: v1(120.56,128.72) 121.08,128.72 121.32,128.49 121.32,126.81 121.35,126.78 121.42,126.71 121.42,123.1 118.66,120.34 118.61,120.29 118.61,112.14 118.43,111.96 117.24,111.96 117.05,111.77 117.05,111.38 117.24,111.19 118.42,111.19 118.61,111 118.61,110.62 118.42,110.43 117.24,110.43 117.05,110.24 117.05,109.86 117.24,109.67 118.42,109.67 118.61,109.48 118.61,109.1 118.42,108.91 117.24,108.91 117.05,108.72 117.05,105.92 117.24,105.73 118.42,105.73 118.61,105.54 118.61,103.89 118.42,103.7 117.18,103.7 116.99,103.5 116.99,102.21 117.18,102.02 118.42,102.02 118.61,101.83 118.61,101.51 118.27,101.17 118.27,100.25 117.11,99.09 117.11,98.28 117.11,98.04 116.27,97.19 116.27,96.29 115.18,95.2 115.18,93.83 115.04,93.69 DIMM2.56
M_MAA_B8: length 56.2
  TOP w0.102: v1(120.61,127.95) 119.96,128.6 119.96,130.82 120.16,131.01 120.16,133 120.6,133.45 121.12,133.45 U27.AU26
  L3 w0.102: v1(120.61,127.95) 121.07,127.5 121.07,126.21 120.97,126.11 120.97,125.86
  L3 w0.191: 120.97,125.86 120.97,123.29 118.21,120.53 118.17,120.48 118.17,112.66 117.9,112.4 116.74,112.4 116.58,112.23 116.58,105.45 116.74,105.28 117.51,105.28 117.7,105.09 117.7,104.33 117.51,104.14 116.77,104.14 116.58,103.95 116.58,101.77 116.77,101.57 117.79,101.57 117.98,101.38 117.98,100.37 116.82,99.21 116.82,98.16 115.98,97.31 115.98,96.41 114.85,95.29 114.85,94.18 114.27,93.61 114.27,92.36 115.13,91.5 115.13,90.49 114.04,89.4 DIMM2.177
M_MAA_B9: length 53.2
  TOP w0.102: U27.AW25 121.09,131.75 121.09,126.11
  TOP w0.178: 121.09,126.11 121.08,126.1 121.08,122.78 120.77,122.47 120.77,120.82 v1(120.66,120.72)
  L3 w0.191: v1(120.66,120.72) 119.5,119.55 119.5,119.11 119.69,118.92 120.67,118.92 120.86,118.72 120.86,118.34 120.67,118.15 119.69,118.15 119.5,117.96 119.5,117.58 119.69,117.39 120.67,117.39 120.86,117.2 120.86,116.82 120.67,116.63 119.69,116.63 119.5,116.44 119.5,102.01 120.16,101.35 120.16,100.27 119.19,99.3 119.19,99.26 119.17,99.24 119.17,98.13 118.15,97.11 118.15,96.44 117.11,95.4 117.11,94.24 116.11,93.24 116.11,92.3 117,91.41 117,90.39 116.04,89.44 DIMM2.175
M_MAA_B10: length 61.2
  TOP w0.216: U27.AP18 114.31,136.66 v1(113.89,136.24)
  L3 w0.102: 114.52,133.22 114.52,133.51 114.35,133.68 114.35,135.77 v1(113.89,136.24)
  L3 w0.191: DIMM2.70 101.41,93.13 101.41,94.01 101.17,94.25 101.17,95.45 102.1,96.38 102.1,96.41 102.1,97.05 103.21,98.15 103.21,99.09 104.24,100.13 104.24,100.37 104.24,101.28 104.43,101.47 105.35,101.47 105.57,101.69 105.57,102.77 108.4,105.6 108.4,120.81 108.43,120.84 108.43,120.85 108.59,121.01 108.59,121.28 108.43,121.44 108.43,121.71 108.7,121.98 108.97,121.98 109.13,121.82 109.4,121.82 109.67,122.09 109.67,122.36 109.51,122.52 109.51,122.79 109.78,123.06 110.05,123.06 110.2,122.9 110.47,122.9 110.74,123.17 110.74,123.44 110.58,123.59 110.58,123.86 110.85,124.13 111.12,124.13 111.28,123.97 111.55,123.97 111.82,124.24 111.82,124.51 111.66,124.67 111.66,124.94 111.93,125.21 112.2,125.21 112.36,125.05 112.63,125.05 112.9,125.32 112.9,125.59 112.74,125.75 112.74,126.02 113.01,126.29 113.28,126.29 113.44,126.13 113.71,126.13 114.13,126.55 114.35,126.55 114.64,126.85 114.64,127.45 114.45,127.64 113.95,127.64 113.76,127.83 113.76,128.15 113.95,128.34 114.81,128.34 115,128.53 115,128.84 114.81,129.03 113.98,129.03 113.78,129.22 113.78,129.6 113.98,129.79 114.81,129.79 115.06,130.04 115.06,130.81 114.81,131.06 114.15,131.06 113.96,131.25 113.96,131.56 114.15,131.75 114.81,131.75 115,131.94 115,132.25 114.81,132.44 114.15,132.44 113.96,132.63 113.96,132.88 114.15,133.07 114.37,133.07 114.52,133.22
M_MAA_B11: length 52
  TOP w0.102: U27.AY25 120.71,130.4 v1(120.62,130.3)
  L3 w0.191: DIMM2.55 116.04,91.95 115.81,92.18 115.81,93.36 116.81,94.36 116.81,95.52 117.85,96.56 117.85,97.23 118.88,98.25 118.88,99.36 118.9,99.38 118.9,99.42 119.87,100.39 119.87,101.23 118.64,102.46 117.63,102.46 117.44,102.65 117.44,103.06 117.63,103.25 118.71,103.25 119.06,103.59 119.06,105.98 118.86,106.17 117.66,106.17 117.49,106.34 117.49,106.77 117.66,106.93 118.8,106.93 118.99,107.12 118.99,107.53 118.8,107.72 117.68,107.72 117.49,107.91 117.49,108.27 117.68,108.46 118.92,108.46 119.06,108.6 119.06,120.11 119.1,120.16 119.1,120.16 121.86,122.92 121.86,126.68 121.71,126.83 121.61,126.93 121.61,128.93 121.18,129.35 121.18,129.74 v1(120.62,130.3)
M_MAA_B12: length 54
  TOP w0.102: 121.51,125.91 121.51,126.35 121.5,126.63 121.5,127.84 121.3,128.03 121.3,129 121.3,129 121.3,132.71 U27.AV26
  TOP w0.178: 121.51,125.91 121.51,122.63 121.87,122.27 v1(121.87,121.98)
  L3 w0.191: v1(121.87,121.98) 121.84,121.95 121.84,121.01 121.3,120.47 121.3,116.34 121.11,116.15 120.13,116.15 119.94,115.96 119.94,115.52 120.13,115.33 121.73,115.33 121.92,115.14 121.92,114.76 121.73,114.57 120.13,114.57 119.94,114.38 119.94,102.2 120.44,101.7 121.72,101.7 121.91,101.51 121.91,100.17 120.81,99.07 120.81,98.43 120.72,98.35 120.72,98.21 119.82,97.31 119.82,96.41 118.98,95.57 118.98,95.39 118.98,94.46 117.98,93.46 117.98,92.3 118.87,91.4 118.87,90.18 117.65,88.95 DIMM2.174
M_MAA_B13: length 58.1
  TOP w0.216: U27.AR15 111.57,135.81 v1(111.14,136.24)
  L3 w0.102: v1(111.14,136.24) 111.14,135.93 111.57,135.5 111.57,133.29 111.18,132.89
  L3 w0.191: DIMM2.196 95.04,88.45 94.85,88.26 94.37,88.26 94.1,88.52 94.1,89.51 94.95,90.36 94.95,91.4 95.88,92.33 95.88,93.17 95.02,94.03 95.02,95.61 95.81,96.4 95.81,97.24 97,98.42 97,99.44 97.81,100.26 97.81,102.22 104.41,108.81 104.41,122.51 109.82,127.93 109.82,131.54 111.18,132.89
M_MAA_B14: length 53.4
  TOP w0.102: v1(122.12,128.14) 122.59,128.61 122.59,129.86 122.15,130.3 122.15,130.82 122.19,130.86 122.19,131.37 122.53,131.72 122.65,131.72 122.87,131.94 122.87,132.35 122.54,132.68 U27.AV27
  L3 w0.102: v1(122.12,128.14) 122.63,127.64 122.63,126.92 122.33,126.63 122.33,125.65
  L3 w0.191: DIMM2.172 119.04,89.93 119.17,90.06 119.17,91.53 118.27,92.42 118.27,93.34 119.27,94.34 119.27,95.45 120.11,96.29 120.11,97.19 121.17,98.24 121.17,99.01 122.37,100.21 122.37,102.02 122.18,102.21 120.58,102.21 120.39,102.4 120.39,113.93 120.58,114.12 122.22,114.12 122.37,114.27 122.37,115.56 122.18,115.75 121.94,115.75 121.75,115.94 121.75,116.39 121.94,116.58 122.18,116.58 122.37,116.77 122.37,117.15 122.18,117.34 121.94,117.34 121.75,117.53 121.75,117.91 121.94,118.1 122.18,118.1 122.37,118.29 122.37,118.67 122.18,118.86 121.94,118.86 121.75,119.05 121.75,119.6 121.94,119.79 122.18,119.79 122.37,119.98 122.37,124.71 122.33,124.75 122.33,125.65
M_MAA_B15: length 51.8
  TOP w0.102: U27.AY28 123.51,130.85 123.77,130.59 123.77,127.81 v1(123.11,127.16)
  L3 w0.191: v1(123.11,127.16) 123.39,126.88 123.39,123.96 123.82,123.53 123.82,111.9 123.63,111.71 121.47,111.71 121.28,111.52 121.28,103.37 121.47,103.17 122.91,103.17 123.24,102.85 123.24,94.65 123.1,94.51 122.34,93.75 120.8,93.75 120.15,93.1 120.15,92.36 121.02,91.48 121.02,90.4 120.04,89.42 DIMM2.171
M_ODT_A0: length 47.5
  TOP w0.102: U27.AW10 105.15,132.69 105.15,131.93 104.33,131.1 104.33,130.06 104.03,129.76
  TOP w0.165: DIMM1.195 95.35,95.64 95.35,96.09 95.81,96.55 95.81,97.18 95.15,97.84 95.15,98.95 96.29,100.09 96.29,100.34 96.29,101.48 96.59,101.77 96.59,104.95 96.61,104.98 96.61,105.06 98.93,107.38 98.93,107.87 98.77,108.03 98.62,108.03 98.45,108.2 98.45,108.53 98.62,108.69 98.77,108.69 98.93,108.86 98.93,109.19 98.77,109.35 98.62,109.35 98.45,109.52 98.45,109.85 98.62,110.02 98.77,110.02 98.93,110.18 98.93,110.51 98.77,110.68 98.62,110.68 98.45,110.84 98.45,111.17 98.62,111.34 98.77,111.34 98.93,111.5 98.93,111.83 98.77,112 98.62,112 98.45,112.16 98.45,112.49 98.62,112.66 98.77,112.66 98.93,112.82 98.93,113.15 98.77,113.32 98.62,113.32 98.45,113.48 98.45,113.81 98.62,113.98 98.77,113.98 98.93,114.14 98.93,114.47 98.77,114.64 98.62,114.64 98.45,114.8 98.45,115.13 98.62,115.3 98.77,115.3 98.93,115.46 98.93,115.79 98.77,115.96 98.62,115.96 98.45,116.12 98.45,116.45 98.62,116.62 98.77,116.62 98.93,116.78 98.93,117.37 98.49,117.82 98.49,118.63 103.51,123.65 103.51,129.24 104.03,129.76
M_ODT_A1: length 45.8
  TOP w0.102: 102.97,130.96 U27.AY8
  TOP w0.165: 102.97,130.96 101.97,129.96 101.97,124.5 101.38,123.91 100.53,123.91 96.32,119.7 96.32,118.85 95.57,118.1 95.57,117.69 95.73,117.53 96.35,117.53 96.52,117.36 96.52,117.03 96.35,116.87 95.73,116.87 95.57,116.7 95.57,116.37 95.73,116.2 96.35,116.2 96.52,116.04 96.52,115.71 96.35,115.54 95.73,115.54 95.57,115.38 95.57,115.05 95.73,114.88 96.35,114.88 96.52,114.72 96.52,114.39 96.35,114.22 95.73,114.22 95.57,114.06 95.57,113.73 95.73,113.56 96.35,113.56 96.52,113.4 96.52,113.07 96.35,112.9 95.73,112.9 95.57,112.74 95.57,112.41 95.73,112.24 96.35,112.24 96.52,112.08 96.52,111.75 96.35,111.58 95.73,111.58 95.57,111.42 95.57,109.15 95.73,108.99 95.75,108.99 95.91,108.82 95.91,108.49 95.75,108.33 95.73,108.33 95.57,108.16 95.57,107.83 95.73,107.67 95.75,107.67 95.91,107.5 95.91,107.17 95.75,107.01 95.73,107.01 95.57,106.84 95.57,106.1 94.84,105.38 94.84,102.09 94.04,101.29 DIMM1.77
M_ODT_B0: length 61.4
  TOP w0.165: U27.AM17 112.94,138.98 v1(112.92,138.98)
  L3 w0.102: v1(112.92,138.98) 112.5,138.56 112.5,137.9 112.22,137.62 111.81,137.62 111.56,137.36 111.56,136.83 111.61,136.78 111.61,136.04 111.77,135.87 111.77,133.07 110.2,131.5
  L3 w0.152: DIMM2.195 96.04,89.39 97.02,90.37 97.02,91.36 96.23,92.15 96.23,93.22 95.29,94.16 95.29,95.33 96.11,96.14 96.11,97.15 97.27,98.31 97.27,99.33 98.09,100.15 98.09,100.37 98.09,101.73 104.92,108.56 104.92,122.3 110.15,127.53 110.15,131.44 110.2,131.5
M_ODT_B1: length 59.4
  TOP w0.165: U27.AL16 v1(112.03,139.9)
  L3 w0.102: 109.77,137.65 110.64,138.53 111.32,138.53 112.03,139.23 v1(112.03,139.9)
  L3 w0.152: DIMM2.77 93.52,90.85 92.19,92.18 92.19,93.41 92.91,94.12 92.91,95.43 93.97,96.5 93.97,97.62 94.79,98.44 94.79,99.29 95.88,100.38 95.88,101.8 102.82,108.75 102.82,122.36 109.22,128.76 109.22,134.12 109.77,134.67 109.77,137.65
M_RAS_A_N: length 48.1
  TOP w0.102: 105.3,128.45 105.93,129.08 105.93,130.59 106.75,131.41 106.75,132.83 107.48,133.56 108.7,133.56 108.83,133.69 U27.AU12
  TOP w0.216: 105.3,128.45 105.3,120.39 100.94,116.03 100.94,106.3 101.16,106.09 102.17,106.09 102.39,105.87 102.39,105.44 102.17,105.22 101.16,105.22 100.94,105.01 100.94,104.57 101.16,104.36 102.17,104.36 102.39,104.14 102.39,103.71 102.17,103.49 101.16,103.49 100.94,103.28 100.94,102.92 101.07,102.79 101.17,102.79 101.3,102.67 101.3,102.11 101.17,101.98 100.71,101.98 99.87,101.14 99.87,100.37 99.04,99.53 99.04,98.08 99.13,97.99 99.21,97.99 99.67,97.54 99.67,97.11 99.42,96.85 DIMM1.192
M_RAS_B_N: length 61.8
  TOP w0.216: v1(113.86,138.98) U27.AM18
  L3 w0.102: 112.99,132.92 112.99,135.95 113.23,136.19 113.23,136.51 113.6,136.89 113.6,138.73 v1(113.86,138.98)
  L3 w0.191: 112.99,132.92 112.99,131.11 112.9,131.01 112.9,127.43 107.51,122.04 107.51,105.98 104.7,103.17 102.24,103.17 102.05,102.98 102.05,102.6 102.24,102.41 103.33,102.41 103.52,102.22 103.52,101.84 103.33,101.65 102.29,101.65 102.1,101.46 102.1,100.21 101.11,99.22 101.11,98.12 100.2,97.21 100.2,96.48 99.1,95.38 99.1,94.21 99.98,93.33 99.98,92.11 99.04,91.18 99.04,90.35 99.05,90.35 99.46,89.94 99.46,89.37 DIMM2.192
M_SBS_A0: length 47.2
  TOP w0.102: 105.68,128.37 106.23,128.92 106.23,130.49 107.1,131.35 107.1,131.83 107.92,132.65 108.43,132.65 U27.AV12
  TOP w0.216: DIMM1.71 99.75,99.05 99.75,99.79 100.19,100.23 100.19,101.01 100.63,101.45 101.39,101.45 102.8,102.86 102.8,106.43 102.15,107.08 101.54,107.08 101.32,107.3 101.32,107.73 101.54,107.94 102.15,107.94 102.36,108.16 102.36,108.59 102.15,108.81 101.54,108.81 101.32,109.02 101.32,109.46 101.54,109.67 102.15,109.67 102.36,109.89 102.36,110.32 102.15,110.54 101.54,110.54 101.32,110.75 101.32,111.18 101.54,111.4 102.15,111.4 102.36,111.62 102.36,112.05 102.15,112.26 101.54,112.26 101.32,112.48 101.32,112.91 101.54,113.13 102.15,113.13 102.36,113.34 102.36,113.77 102.15,113.99 101.54,113.99 101.32,114.21 101.32,114.64 101.54,114.85 102.15,114.85 102.36,115.07 102.36,115.75 103.71,117.09 103.71,118.12 105.68,120.09 105.68,128.37
M_SBS_A1: length 41.8
  TOP w0.102: U27.AY11 106.83,130.12 106.83,129.59
  TOP w0.216: 106.83,129.59 106.97,129.45 106.97,127.94 106.57,127.55 106.57,119.91 105.13,118.47 105.13,116.8 104.91,116.58 104.69,116.58 104.47,116.37 104.47,115.93 104.69,115.72 104.91,115.72 105.13,115.5 105.13,115.07 104.91,114.85 104.69,114.85 104.47,114.64 104.47,114.21 104.69,113.99 104.91,113.99 105.13,113.78 105.13,113.34 104.91,113.13 104.69,113.13 104.47,112.91 104.47,112.48 104.69,112.26 104.91,112.26 105.13,112.05 105.13,111.62 104.91,111.4 104.69,111.4 104.47,111.18 104.47,110.75 104.69,110.54 104.91,110.54 105.13,110.32 105.13,109.89 104.91,109.67 104.69,109.67 104.47,109.46 104.47,109.03 104.69,108.81 104.91,108.81 105.13,108.59 105.13,106.61 104.62,106.1 103.94,106.1 103.56,105.71 103.56,102.34 101.88,100.66 101.88,100.02 101.04,99.18 DIMM1.190
M_SBS_A2: length 45.9
  TOP w0.102: U27.AT21 116.7,134.51 116.7,132.76 116.64,132.69 116.64,132.21 117.25,131.61 117.25,127.69
  TOP w0.216: DIMM1.52 120.32,101.93 122.08,101.93 122.45,102.3 123.15,102.3 123.46,102.61 123.46,103.43 122.65,104.24 122.65,108.48 122.43,108.69 121.93,108.69 121.72,108.91 121.72,109.34 121.93,109.56 122.43,109.56 122.65,109.77 122.65,110.2 122.43,110.42 121.93,110.42 121.72,110.64 121.72,111.07 121.93,111.28 122.43,111.28 122.65,111.5 122.65,111.93 122.43,112.15 121.93,112.15 121.72,112.36 121.72,112.79 121.93,113.01 122.43,113.01 122.65,113.23 122.65,113.66 122.43,113.87 121.93,113.87 121.72,114.09 121.72,114.52 121.93,114.74 122.43,114.74 122.65,114.95 122.65,115.36 120.54,117.47 118.06,119.95 118.06,120.96 118.06,126.87 117.25,127.69
M_SBS_B0: length 58.5
  TOP w0.216: U27.AK17 v1(113.86,140.81)
  L3 w0.102: 113.39,133.06 113.39,135.75 113.43,135.8 113.43,136.43 113.86,136.85 113.86,138.34 114.33,138.81 114.33,140.34 v1(113.86,140.81)
  L3 w0.191: DIMM2.71 100.53,91.34 100.53,92 100.27,92.25 100.27,93.3 100.88,93.9 100.88,95.61 101.81,96.53 101.81,97.17 102.91,98.27 102.91,98.97 102.91,99.21 103.95,100.25 103.95,101.44 103.95,101.74 104.14,101.93 104.83,101.93 105.02,102.12 105.02,102.87 107.95,105.8 107.95,121.86 108.41,122.32 112.81,126.72 113.54,126.72 113.73,126.91 113.73,127.34 113.32,127.75 113.32,129.7 113.92,130.29 113.92,130.75 113.39,131.29 113.39,133.06
M_SBS_B1: length 58.5
  TOP w0.216: U27.AL18 114.74,139.01 v1(114.77,139.01)
  L3 w0.102: 114.33,137.82 114.33,138.28 114.77,138.72 v1(114.77,139.01)
  L3 w0.191: DIMM2.190 100.29,88.95 100.09,89.15 100.09,89.64 100.82,90.36 100.82,91.44 101.81,92.43 101.81,93.32 102.86,94.37 102.86,95.59 103.82,96.54 103.82,97.33 104.89,98.41 104.89,99.19 105.96,100.25 105.96,102.54 108.84,105.42 108.84,120.63 108.87,120.66 108.87,120.66 114.76,126.55 115.37,127.16 115.37,133.2 114.7,133.86 114.7,136.96 114.33,137.33 114.33,137.82
M_SBS_B2: length 54.3
  TOP w0.102: U27.AW28 123.46,131.77 123.13,131.44 123.13,130.99 123.31,130.8 123.31,128.61 123.57,128.36 123.57,127.93 123.3,127.66 122.97,127.66 122.66,127.35 122.66,126.49 v1(122.81,126.34)
  L3 w0.191: v1(122.81,126.34) 122.82,126.33 122.82,122.55 123.01,122.36 123.18,122.36 123.37,122.17 123.37,121.79 123.18,121.6 123.01,121.6 122.82,121.41 122.82,121.03 123.01,120.84 123.18,120.84 123.37,120.65 123.37,120.27 123.18,120.08 123.01,120.08 122.82,119.89 122.82,119.51 123.01,119.32 123.18,119.32 123.37,119.12 123.37,118.74 123.18,118.55 123.01,118.55 122.82,118.36 122.82,117.98 123.01,117.79 123.18,117.79 123.37,117.6 123.37,117.22 123.18,117.03 123.01,117.03 122.82,116.84 122.82,116.46 123.01,116.27 123.18,116.27 123.37,116.08 123.37,115.7 123.18,115.51 123.01,115.51 122.82,115.31 122.82,114.89 123.01,114.69 123.2,114.69 123.37,114.52 123.37,113.86 123.2,113.68 121.02,113.68 120.83,113.49 120.83,113.11 121.02,112.92 123.18,112.92 123.37,112.73 123.37,112.34 123.18,112.15 121.02,112.15 120.83,111.96 120.83,102.83 121.02,102.64 122.62,102.64 122.81,102.45 122.81,97.19 121.01,95.39 121.01,94.72 DIMM2.52
M_SCKE_A0: length 46.9
  TOP w0.102: U27.AV22 117.75,132.82 117.75,128.13 117.9,127.99 117.9,127.97 118.87,126.99
  TOP w0.165: 118.87,126.99 118.87,120.62 118.87,120.62 118.87,120.28 124.28,114.88 124.28,113.06 124.11,112.89 123.74,112.89 123.57,112.73 123.57,112.4 123.74,112.23 124.05,112.23 124.18,112.11 124.18,111.7 124.05,111.57 123.74,111.57 123.57,111.41 123.57,111.08 123.74,110.91 124.11,110.91 124.28,110.75 124.28,110.42 124.11,110.25 123.74,110.25 123.57,110.09 123.57,109.76 123.74,109.59 124.11,109.59 124.28,109.43 124.28,109.1 124.11,108.93 123.74,108.93 123.57,108.77 123.57,108.44 123.74,108.27 124.31,108.27 124.43,108.14 124.43,107.74 124.31,107.61 123.74,107.61 123.57,107.45 123.57,107.12 123.74,106.95 124.33,106.95 124.46,106.82 124.46,106.42 124.33,106.29 123.74,106.29 123.57,106.13 123.57,105.8 123.74,105.63 124.26,105.63 124.38,105.5 124.38,105.1 124.26,104.97 123.74,104.97 123.57,104.8 123.57,104.47 123.74,104.31 124.11,104.31 124.28,104.14 124.28,102.91 124.75,102.44 124.75,101.5 124.45,101.19 123.8,101.19 123.51,101.49 122.85,101.49 122.36,101 121.39,101 DIMM1.50
M_SCKE_A1: length 49.7
  TOP w0.102: U27.AT23 118.33,134.31 118.33,132.75 117.98,132.41 117.98,128.45 119.28,127.16
  TOP w0.165: 119.28,127.16 119.28,120.45 125.02,114.71 125.02,113.28 125.18,113.11 125.49,113.11 125.65,112.95 125.65,112.62 125.49,112.45 125.18,112.45 125.02,112.29 125.02,111.96 125.18,111.79 125.78,111.79 125.91,111.66 125.91,111.38 125.78,111.25 125.15,111.25 125.02,111.12 125.02,110.45 125.15,110.32 125.5,110.32 125.63,110.2 125.63,109.69 125.47,109.54 125.15,109.54 125.02,109.41 125.02,100.33 124.89,100.2 124.08,100.2 123.43,100.85 122.99,100.85 122.8,100.66 122.8,95.71 DIMM1.169
M_SCKE_B0: length 50.5
  TOP w0.102: U27.AW29 124.02,131.77 124.02,127.86 124.44,127.44 124.44,126.86 v1(123.96,126.38)
  L3 w0.152: v1(123.96,126.38) 124,126.33 124,124.08 124.33,123.75 124.33,111.39 124.14,111.19 121.95,111.19 121.79,111.04 121.79,110.54 121.94,110.39 123,110.39 123.16,110.24 123.16,109.93 123,109.78 121.94,109.78 121.79,109.63 121.79,103.8 121.94,103.66 123.41,103.66 123.63,103.44 123.63,101.21 125.82,99.02 125.82,95.38 123.2,92.75 DIMM2.50
M_SCKE_B1: length 49.1
  TOP w0.102: U27.AY29 124.37,128.52 124.76,128.13 124.76,126.13 v1(124.61,125.97)
  L3 w0.152: DIMM2.169 123.18,88.19 123.18,91.85 126.08,94.74 126.08,99.34 124.04,101.38 124.04,103.48 122.31,105.21 122.31,108.9 122.69,109.28 123.21,109.28 124.83,110.9 124.83,123.96 124.61,124.19 v1(124.61,125.97)
M_SCS_A_N0: length 47.1
  TOP w0.102: 104.37,128.68 105.3,129.61 105.3,130.85 106.1,131.64 106.1,132.75 107.67,134.32 110.29,134.32 U27.AU14
  TOP w0.165: DIMM1.193 98.04,97.57 97.29,98.32 97.29,99.14 97.89,99.75 97.89,105.12 99.8,107.02 99.8,117.47 100.17,117.85 100.17,117.85 103.18,120.86 103.18,120.86 104.37,122.05 104.37,128.68
M_SCS_A_N1: length 48.2
  TOP w0.102: U27.AV9 103.38,133.45 103.38,130.33 102.84,129.79
  TOP w0.165: DIMM1.76 95.25,100.86 95.25,105.21 97.4,107.35 97.4,108.81 97.23,108.98 96.74,108.98 96.57,109.14 96.57,109.47 96.74,109.64 97.23,109.64 97.4,109.8 97.4,110.13 97.23,110.3 96.74,110.3 96.57,110.46 96.57,110.79 96.74,110.96 97.23,110.96 97.4,111.12 97.4,111.53 96.93,112 96.93,118.29 97.21,118.58 97.21,118.81 96.73,119.3 96.73,119.53 96.96,119.77 97.19,119.77 97.68,119.28 97.91,119.28 98.15,119.51 98.15,119.75 97.66,120.24 97.66,120.47 97.89,120.7 98.13,120.7 98.62,120.21 98.85,120.21 99.08,120.45 99.08,120.68 98.59,121.17 98.59,121.4 98.83,121.64 99.06,121.64 99.55,121.15 99.78,121.15 100.02,121.38 100.02,121.61 99.53,122.1 99.53,122.34 99.76,122.57 99.99,122.57 100.48,122.08 100.72,122.08 100.95,122.32 100.95,122.55 100.46,123.04 100.46,123.27 100.7,123.5 100.93,123.5 101.42,123.02 101.65,123.02 102.49,123.85 102.49,129.41 102.59,129.52 102.59,129.54 102.84,129.79
M_SCS_B_N0: length 59.4
  TOP w0.165: U27.AP17 113.37,136.7 v1(112.92,137.16)
  L3 w0.102: v1(112.92,137.16) 112.56,136.8 112.51,136.75 112.51,132.87 111.51,131.86
  L3 w0.152: DIMM2.193 98.04,89.61 97.29,90.36 97.29,91.17 97.79,91.67 97.79,93.37 97.25,93.91 97.25,95.3 98.28,96.33 98.28,97.2 99.03,97.95 99.04,97.95 99.17,98.08 99.17,99.05 100.27,100.15 100.27,101.11 101.16,102.01 101.16,103.4 101.85,104.09 102.49,104.09 104.48,106.08 106.24,106.08 106.55,106.38 106.55,122.46 111.51,127.42 111.51,131.86
M_SCS_B_N1: length 62.4
  TOP w0.165: U27.AN15 111.11,138.07 v1(111.09,138.07)
  L3 w0.152: DIMM2.76 95.04,93.09 94.53,93.6 93.9,93.6 93.16,94.34 93.16,95.33 94.28,96.45 94.28,97.47 95.06,98.25 95.06,99.21 96.13,100.28 96.13,101.26 103.89,109.02 103.89,109.52 103.74,109.67 103.47,109.67 103.32,109.82 103.32,110.13 103.47,110.28 103.74,110.28 103.89,110.43 103.89,110.73 103.74,110.89 103.47,110.89 103.32,111.04 103.32,111.34 103.47,111.5 103.74,111.5 103.89,111.65 103.89,111.95 103.74,112.11 103.47,112.11 103.32,112.26 103.32,112.56 103.47,112.72 103.74,112.72 103.89,112.87 103.89,113.17 103.74,113.33 103.47,113.33 103.32,113.48 103.32,113.78 103.47,113.94 103.74,113.94 103.89,114.09 103.89,114.39 103.74,114.54 103.47,114.54 103.32,114.7 103.32,115 103.47,115.15 103.74,115.15 103.89,115.31 103.89,115.61 103.74,115.76 103.47,115.76 103.32,115.92 103.32,116.22 103.47,116.37 103.74,116.37 103.89,116.53 103.89,116.83 103.74,116.98 103.47,116.98 103.32,117.14 103.32,117.44 103.47,117.59 103.74,117.59 103.89,117.75 103.89,118.05 103.74,118.2 103.47,118.2 103.32,118.35 103.32,118.66 103.47,118.81 103.74,118.81 103.89,118.96 103.89,119.27 103.74,119.42 103.47,119.42 103.32,119.57 103.32,119.88 103.47,120.03 103.74,120.03 103.89,120.18 103.89,120.49 103.74,120.64 103.47,120.64 103.32,120.79 103.32,121.1 103.47,121.25 103.74,121.25 103.89,121.4 103.89,122.73 109.47,128.31 109.47,131.93 109.66,132.11 109.66,133.87 110.3,134.52 110.3,137.29 v1(111.09,138.07)
M_WE_A_N: length 46
  TOP w0.102: 104.86,128.52 105.62,129.28 105.62,130.75 106.41,131.54 106.41,132.78 107.59,133.96 U27.AU11
  TOP w0.216: 104.86,128.52 104.86,120.76 104.24,120.15 103.94,120.15 103.66,120.42 103.36,120.42 103.05,120.12 103.05,119.81 103.33,119.53 103.33,119.23 103.02,118.92 102.72,118.92 102.44,119.2 102.13,119.2 101.83,118.9 101.83,118.59 102.11,118.31 102.11,118.01 101.8,117.7 101.5,117.7 101.22,117.98 100.91,117.98 100.61,117.67 100.61,117.37 100.88,117.09 100.88,116.79 100.56,116.46 100.56,105.77 100.34,105.55 99.37,105.55 99.15,105.34 99.15,104.9 99.37,104.69 100.34,104.69 100.56,104.47 100.56,102.37 99.76,101.57 98.49,101.57 98.2,101.28 98.2,98.91 DIMM1.73
M_WE_B_N: length 58.8
  TOP w0.216: U27.AK16 v1(112.94,140.81)
  L3 w0.102: 112.5,131.37 112.74,131.61 112.74,136.32 112.91,136.48 113.39,136.96 113.39,140.37 v1(112.94,140.81)
  L3 w0.191: DIMM2.73 98.09,90.9 98.09,93.27 98.81,93.99 98.81,95.54 99.82,96.55 99.82,97.25 100.81,98.24 100.81,99.14 100.82,99.15 100.82,99.34 101.81,100.33 101.81,101.08 101.57,101.32 101.57,103.17 102.05,103.66 103.31,103.66 105.21,105.56 106.46,105.56 107.06,106.17 107.06,122.23 108.44,123.6 108.44,123.61 112.5,127.68 112.5,131.37
MCLK: length 6.6
  TOP w0.102: U61.41 105.37,14.4 107.35,12.42 v2(108.33,12.42) 108.64,12.42 RN7.1
MDAT: length 6.7
  TOP w0.102: RN7.2 108.46,10.92 106.55,12.83 v2(106.17,12.83) 105,14 U61.40
ME_CNTL: length 76.9
  TOP w0.102: v1(8.03,57.61) 7.66,57.98 R846.1 ; v1(4.22,41.35) 3.54,40.68 3.54,35.19 5.85,32.89 7.49,32.89 8.46,31.93 8.46,31.92 12.97,27.41 15.9,27.41 v1(16.21,27.71) ; U29.W35 35.13,39.61 34.79,39.27 v3(34.78,39.27) ; v1(9.43,51.65) 9.8,51.65 R636.1
  BOTTOM w0.102: v1(8.03,57.61) 8.05,57.58 8.05,57.37 8.05,55.02 9.43,53.64 v1(9.43,51.65) 9.43,49.97 8.22,48.76 8.22,47.42 5.92,45.12 5.92,43.05 v1(4.22,41.35) ; v3(34.78,39.27) 34.78,40.01 35.39,40.62 35.39,42.18 34.95,42.62 34.39,42.62 33.3,41.53 33.3,41.22 33.07,41 33.07,40.52 32.78,40.23 32.78,40.09 32.28,39.59 32.28,39.2 32.34,39.14 32.34,35.83 31.67,35.16 31.67,33.72 28.84,30.89 25.55,30.89 24.66,30 19.63,30 19.47,29.83 18.96,29.83 v2(18.87,29.74) 18.21,29.08 17.57,29.08 16.21,27.72 v1(16.21,27.71)
ME_CNTL_1: length 3.7
  TOP w0.102: v2(5.78,57.8) 6.49,57.09 R846.2 7.79,57.09 8.08,56.79 Q82.B
ME_CNTL_2: length 3.8
  TOP w0.102: v2(5.78,56.07) R847.2 7.83,56.07 Q82.E
MEM_BOOT: length 2.9
  TOP w0.305: PU8.10 v1(127.1,48.49)
  TOP w0.508: PR111.1 125.58,49.17 126.26,48.49 v1(127.1,48.49)
MEM_BOOT_1: length 2.9
  TOP w0.508: PR111.2 124.31,50.19 PC69.1 v2(123.27,51.16)
MEM_COMP_3: length 1.8
  TOP w0.305: PR86.1 128.9,42.98 v1(128.9,42.18) 129.3,41.78 PC63.2
MEM_CS: length 2.1
  TOP w0.305: PR106.1 127.22,43.72 v1(127.85,44.35) 128.3,44.81 PU8.2
MEM_EN: length 31.1
  TOP w0.102: R422.2 127.9,42.92 128.01,43.03 v1(128.01,43.06) 128.33,43.37 128.33,44.12 128.8,44.59 PU8.3 ; U53.3 104.77,42.21 v1(105.28,42.72)
  BOTTOM w0.102: v1(105.28,42.72) 105.28,42.24 v2(106.12,41.4) 106.32,41.2 126.25,41.2 128.01,42.96 v1(128.01,43.06)
MEM_FB: length 5.3
  TOP w0.305: PU8.4 129.3,44.43 128.91,44.03 PR86.2 128.93,43.85 PR87.2 PR85.1 131.64,43.85 v2(132.26,43.23)
MEM_HG: length 17.8
  TOP w0.305: PU8.9 128.3,49.12 127.88,49.54 v6(127.18,49.54)
  TOP w0.635: PR127.1 v6(114.53,54.15)
  BOTTOM w0.635: v6(114.53,54.15) 115.2,53.48 v2(115.57,53.48) 123.24,53.48 v6(127.18,49.54)
MEM_HG_1: length 6.4
  TOP w0.635: Q34.4 116.78,55.87 PR126.1 114.33,55.87 114.11,56.08 PR127.2 112.93,56.08 v2(111.35,54.51)
MEM_LG: length 20.3
  TOP w0.305: PU8.6 130.1,48.78 v6(130.1,49.68)
  TOP w0.635: v6(130.78,61.95) Q43.4
  BOTTOM w0.635: v6(130.1,49.68) 130.1,50.85 v2(132.9,53.65) 134.57,55.32 134.57,60.96 133.58,61.95 v6(130.78,61.95)
MEM_LX: length 22.4
  TOP w0.305: PU8.8 128.8,49.58 127.94,50.44
  TOP w0.635: L50.1 118.67,62.41 ; L50.1 120.17,60.91 ; L50.1 118.67,59.41 ; L50.1 117.17,60.91 ; 127.94,50.44 127.23,51.16 PC69.2 125.83,52.35 123.47,54.71 PR110.1
  BOTTOM w0.635: 118.67,59.41 L50.1 ; L50.1 120.17,60.91 ; L50.1 118.67,62.41 ; L50.1 117.17,60.91
  vias: v2(125.07,61.98) v2(126.09,60.5) v2(127.1,62) v6(112.04,60.83) v6(112.09,59.44) v6(112.12,58.06) v6(114.45,62.23) v6(114.5,60.71) v6(114.48,59.28) v6(116.64,62.23) v6(116.71,57.68) v6(121.62,62.28) v6(121.79,57.84) v6(121.92,55.91)
MEM_PG: length 4.2
  TOP w0.102: PC72.1 125.37,44.65 PR109.2 126.03,45.59 v2(126.09,45.64) 127.14,45.64 127.39,45.39 PU8.1
MEM_RF: length 3
  TOP w0.305: v2(131.78,46.18) 131.42,45.81 PR84.1 130.78,45.04 130.43,45.39 PU8.5
MEM_SNB: length 3.9
  TOP w0.508: PR110.2 125.73,56.18 PC73.1 126.97,54.56 v2(126.59,54.18)
MEM_VCC: length 5.9
  TOP w0.305: 129.36,50.24 129.3,50.18 PU8.7
  TOP w0.635: 129.36,50.24 129.44,50.32 PR83.1 129.44,51.87 129.64,52.08 PC65.1 129.51,53.01 128.4,53.01 v2(128.37,52.98)
MEM_VIN: length 27.2
  TOP w0.635: 109.92,45.06 TC29.1 ; TC29.1 110.97,44 ; TC29.1 110.97,46.11 ; TC29.1 112.03,45.06 ; TC41.1 119.1,46.01 ; TC41.1 118.05,44.96 ; TC41.1 120.16,44.96 ; TC41.1 119.1,43.9 ; L45.1 123.7,36.81 ; L45.1 122.4,35.51 ; L45.1 123.7,34.21 ; L45.1 125,35.51
  BOTTOM w0.635: TC29.1 112.03,45.06 ; TC29.1 110.97,44 ; TC29.1 109.92,45.06 ; TC29.1 110.97,46.11 ; 119.1,43.9 TC41.1 ; TC41.1 118.05,44.96 ; TC41.1 120.16,44.96 ; TC41.1 119.1,46.01 ; L45.1 125,35.51 ; L45.1 123.7,34.21 ; L45.1 123.7,36.81 ; L45.1 122.4,35.51
  vias: v2(110.87,49.35) v2(112.9,49.38) v2(120.52,49.43) v2(122.76,49.43) v2(124.64,31.32) v2(126.36,31.39) v6(110.46,43.66) v6(111.94,43.66) v6(113.37,47.51) v6(114.17,48.84) v6(114.58,47.42) v6(115.21,44.2) v6(115.62,48.79) v6(116.54,47.5) v6(116.51,46.08) v6(116.54,44.22) v6(117.5,48.82) v6(118.44,47.57) v6(118.92,43.43) v6(119.53,48.82) v6(120.6,47.6) v6(120.98,43.43) v6(121.26,35.18) v6(121.54,36.5) v6(121.59,33.76) v6(121.77,48.84) v6(123.27,43.43) v6(123.57,46.84)
MIC1_JD: length 8.6
  TOP w0.102: v1(13.65,221.55) R68.2
  BOTTOM w0.102: AUDF1.6 10.11,223.56 v2(12.12,221.55) v1(13.65,221.55)
MIC1_L: length 17.9
  TOP w0.203: AUDF1.1 4.23,227.72 5.77,226.19 5.77,222.34 6.15,221.96 6.15,220.63 6.66,220.12 6.68,220.12 8.85,217.94 L1.2 7.89,215.37 C5.1 7.81,213.9 Q9.1
MIC1_R: length 22.8
  TOP w0.203: AUDF1.3 4.23,225.13 5.28,224.08 5.28,222.35 5.82,221.82 5.82,216.08 5.7,215.96 Q9.2 5.13,213.19 5.13,210.92 6.69,209.36 C6.1 L2.2
MIC1_VREFO_L: length 13.6
  TOP w0.254: v1(23.16,228.73) 23.67,229.23 U2.28 ; R9.1 v1(30.25,223.77)
  BOTTOM w0.254: v1(30.25,223.77) 29.03,223.77 28.5,224.31 25.7,224.31 v2(23.5,226.52) 23.29,226.72 23.29,228.6 v1(23.16,228.73)
MIC1_VREFO_R: length 15.4
  TOP w0.254: U2.32 23.59,231.23 22.43,230.07 v1(22.43,229.26) ; v1(27.71,223.77) R10.1
  BOTTOM w0.254: v1(27.71,223.77) 27.53,223.59 24.36,223.59 v2(23.98,223.98) 21.97,225.98 21.97,228.8 v1(22.43,229.26)
MIC2-VREFO: length 12
  TOP w0.203: D1.3 35.17,225.87 30.53,230.5 v5(29.55,230.5) 28.22,230.5 27.94,230.23 U2.30
MIC2_JD: length 34.1
  TOP w0.102: AUDJK1.3 51.69,241.1 49.83,242.95 33.4,242.95 30.07,239.62 30.07,236.17 28.68,234.77 R5.2
MIC2_LL: length 21.2
  TOP w0.203: R48.2 R49.2 33.54,222.58 32.87,223.25 v2(32.87,223.85) 32.87,224.38 33.48,224.99 35.99,224.99 36.68,225.68 36.68,226.62 42.9,232.84 42.9,233.96 43.48,234.54 FL1.1
MIC2_RR: length 16.3
  TOP w0.203: R26.2 R27.2 36.5,221.51 v1(37.47,222.48) 37.72,222.73 37.72,227.08 43.28,232.64 FL2.1
MINI1_WAKE#: length 9.1
  TOP w0.102: R269.1 34.23,174.02 36.27,171.98 36.27,169.24 v1(35.94,168.91) 34.98,167.95 MINI1.1
MINI_CLKREQ#_WLAN: length 210
  TOP w0.102: U29.P39 37.78,37.22 arc(37.79,37.14) 37.82,37.07 arc(37.84,37.04) 37.86,37.02 37.96,36.91 37.99,36.88 38.02,36.8 38.03,36.76 38.03,36.6 37.99,36.56 37.99,36.55 37.99,34.37 v1(38.28,34.08) ; v1(21.45,18.63) 20.59,18.63 20.05,19.16 R560.1 20.04,19.37 R554.1 18.83,19.51 15.59,19.51 15.16,19.08 14.76,19.08 13.54,20.29 10.26,20.29 9.89,19.92 8.92,19.92 8.39,20.45 8.39,22.06 8.23,22.22 7.91,22.55 7.91,23.91 8.23,24.24 8.23,27.07 1.59,33.71 1.59,64.01 6.09,68.51 6.68,69.11 6.68,90.73 v1(25.43,109.47) ; v1(25.43,165.74) 25.47,165.78 26.65,165.78 R304.2
  BOTTOM w0.102: v1(38.28,34.08) 38.42,33.94 38.42,31.78 38.8,31.39 39.34,31.39 39.86,30.87 39.86,23.55 38.4,22.09 35.87,22.09 35.66,22.29 29.51,22.29 28.59,21.37 26.68,21.37 23.94,18.63 v1(21.45,18.63) ; v1(25.43,165.74) v2(25.43,148.84) v1(25.43,109.47)
MINI_CLKREQ#_WLAN_C: length 6.1
  TOP w0.102: MINI1.7 31.75,165.55 31.45,165.86 v2(28.96,165.86) 28.4,165.86 28.39,165.86 R304.1
MINI_POWER_CTRL: length 143.8
  TOP w0.165: v1(39.17,30.93) 39.09,31.01 38.85,31.01 36.18,33.69 36.18,35.98 U29.V41 ; R2239.1 8.39,105.36 R713.1 7.91,104.26 7.91,101 0.84,93.94 0.84,33.38 7.49,26.73 7.49,25.9 5.47,23.87 5.47,22.83 6.21,22.09 6.79,22.09 7.65,21.22 7.65,20.14 8.61,19.18 10.2,19.18 10.57,19.55 13.24,19.55 14.45,18.33 15.47,18.33 15.67,18.54 17.71,18.54 v1(18.24,18.01)
  BOTTOM w0.165: v1(18.24,18.01) 19.38,19.15 v2(20.57,19.15) 24.02,19.15 26.53,21.66 28.47,21.66 29.39,22.58 35.78,22.58 35.99,22.37 38.28,22.37 39.58,23.67 39.58,30.52 v1(39.17,30.93)
MINI_POWER_CTRL_1: length 4.3
  TOP w0.165: Q108.5 5.61,104.27 6.17,104.83 C680.1 6.49,105.21 R2239.2 v2(7.07,107.01)
MINI_POWER_CTRL_2: length 6.2
  TOP w0.165: Q108.3 6.26,102.27 6.1,102.44 5.74,102.44 5.61,102.31 Q108.2 5.61,100.89 5.77,100.74 6.17,100.74 6.35,100.56 6.35,100 6.2,99.85 v2(5.77,99.85) 5.02,99.85 R368.2
MINI_POWER_CTRL_3: length 3.6
  TOP w0.165: R2240.1 5.54,106.5 5.56,106.48 v2(5.56,105.92) 5.47,105.83 R369.2 4.96,104.47 Q108.6
MTST_ID: length 53.7
  TOP w0.102: v1(35.79,39.99) 35.46,40.32 U29.W34 ; v1(14.96,19.56) 13.74,20.78 11.17,20.78 10.08,21.86 10.08,22.54 LEDH1.11 ; R565.1 v1(37.47,29.38)
  BOTTOM w0.102: v1(35.79,39.99) 35.4,39.6 35.4,38.96 35.22,38.78 35.22,32.85 35.55,32.52 35.55,31.29 v1(37.47,29.38) 37.47,27.62 37.92,27.17 37.92,26.43 37.57,26.07 37.57,24.84 38.3,24.1 38.3,23.52 37.95,23.16 36.32,23.16 35.1,24.38 29.58,24.38 28.34,23.14 24.71,23.14 22.94,21.36 21.72,21.36 21.23,20.88 17.59,20.88 v2(16.03,19.32) 15.79,19.56 v1(14.96,19.56)
P25_GND: length 8.2
  TOP w0.102: U22.25 U23.25 101.73,55.78 102.16,56.21 104.83,56.21 105.07,55.97 105.94,55.97 v2(106.25,55.66) 106.25,55.22 105.93,54.9 R472.1
P_GNT_N1: length 5.5
  TOP w0.102: R413.1 21.13,40.21 v1(21.72,40.79) 22.09,41.17 22.62,41.17 22.65,41.19 24.67,41.19 24.69,41.18 25.04,41.18 25.3,41.25 U29.AU31
P_GNT_N2: length 7.3
  TOP w0.102: U29.AV31 22.65,41.49 22.54,41.37 21.65,41.37 21.06,40.78 19.56,40.78 19.51,40.83 R841.1 v1(18.8,41.63)
P_GNT_N3: length 20.2
  TOP w0.102: v3(36.81,42.18) 37.02,42.39 U29.R30 ; v1(39.09,24.73) 39.09,24.6 R840.1
  BOTTOM w0.102: v1(39.09,24.73) 39.09,29.57 v2(38.86,29.8) 37.33,31.32 37.33,39.01 37.44,39.11 37.44,41.46 36.81,42.08 v3(36.81,42.18)
P_INTA_N: length 10.4
  TOP w0.102: U29.AU29 25.58,42.65 25.18,43.05 23.75,43.05 23.58,43.21 19.99,43.21 19.61,42.83 19.29,42.83 19.04,42.57 18.01,42.57 17.73,42.29 v2(17.14,42.29) 16.73,42.71 RN65.1
P_INTB_N: length 12.4
  TOP w0.102: U29.AU27 25.44,44.01 25.08,44.37 24.76,44.37 24.61,44.22 24.29,44.22 24.23,44.27 20.16,44.27 18.08,46.35 v4(17.64,46.35) 16.89,46.35 16.24,47 RN3.4
P_INTC_N: length 8.7
  TOP w0.102: U29.AW28 23.79,43.33 23.7,43.42 19.89,43.42 19.58,43.11 v2(18.82,43.11) 18.39,43.11 18.21,42.93 17.58,42.93 17.32,43.18 17.32,43.76 17.18,43.91 RN65.2
P_INTD_N: length 11.9
  TOP w0.102: U29.AV27 24.78,44.07 24.73,44.01 24.2,44.01 24.15,44.06 19.51,44.06 v4(19.03,44.54) 19.03,45.08 18.26,45.85 17.04,45.85 16.12,46.76 15.52,46.76 15.11,46.35 RN3.3
P_INTH_N: length 13.6
  TOP w0.102: RN3.2 15.14,45.85 15.52,46.23 v2(15.9,46.23) 16.51,45.62 18.03,45.62 18.44,45.21 18.44,44.41 18.99,43.86 24.07,43.86 24.12,43.81 24.69,43.81 24.79,43.71 26.18,43.71 26.31,43.84 U29.AT27
P_PME#: length 28.4
  TOP w0.102: v3(33.83,41.46) 33.84,41.46 34.11,41.74 U29.AA31 ; v1(17.21,27.23) 17.21,28.35 R698.2
  BOTTOM w0.102: v1(17.21,27.23) 17.96,27.98 22.31,27.98 22.99,27.3 v2(24.33,27.3) 24.52,27.3 26.79,29.57 28.09,29.57 32.75,34.22 32.75,38.04 32.93,38.22 32.93,38.99 33.2,39.26 33.2,40.27 33.35,40.42 33.35,40.99 v3(33.83,41.46)
P_REQ_N1: length 25.5
  TOP w0.102: v1(11.53,44.37) 11.53,43.94 11.79,43.69 11.79,41.54 12.2,41.12 RN2.1 ; U29.AH26 30.87,44.69 30.87,44.95 v3(30.89,44.97)
  BOTTOM w0.102: v3(30.89,44.97) 30.68,44.75 30.68,44.74 30.43,44.49 30.13,44.49 30,44.37 27.27,44.37 26.71,44.93 22.1,44.93 21.79,45.24 20.58,45.24 20.49,45.33 16.32,45.33 15.83,45.82 v2(13.34,45.82) 12.98,45.82 v1(11.53,44.37)
P_REQ_N2: length 25.6
  TOP w0.102: v1(11.33,43.23) 11.55,43.01 RN2.2 ; U29.AJ26 29.97,44.63 v3(30.26,44.91)
  BOTTOM w0.102: v3(30.26,44.91) 29.92,44.57 27.35,44.57 26.79,45.13 22.19,45.13 21.88,45.44 20.67,45.44 20.55,45.55 16.42,45.55 15.58,46.39 v2(15.22,46.39) 13.09,46.39 11.53,44.83 11.34,44.83 11.07,44.56 11.07,43.48 v1(11.33,43.23)
P_REQ_N3: length 16.6
  TOP w0.102: RN2.3 11.05,41.48 v1(11.07,41.5) ; v1(12.24,41.73) 12.24,41.58 12.83,41 12.83,40.65 v2(13.98,39.5) 14.35,39.12 17.9,39.12 18.24,38.79 19.55,38.79 19.72,38.95 19.72,38.95 20.1,39.33 20.1,39.33 20.34,39.57 21.44,39.57 22.3,40.44 24.23,40.44 U29.AW33
  BOTTOM w0.102: v1(11.07,41.5) 12.01,41.5 v1(12.24,41.73)
PCH_CONFIG_JUMPER: length 16.7
  TOP w0.102: R683.1 49.44,27.52 48.82,28.14 47.13,28.14 v1(46.81,27.82) ; v3(40.55,35.16) 40.5,35.2 40.5,35.5 40.2,35.81 40.2,36.41 40.03,36.57 40.03,36.99 40.07,37.03 40.07,37.5 39.75,37.82 U29.L38
  BOTTOM w0.102: v1(46.81,27.82) 45.9,28.73 v2(45.87,28.73) 45.75,28.73 44.58,29.9 44.58,31.61 44.3,31.88 44.3,32.25 41.39,35.16 v3(40.55,35.16)
PCH_GP8: length 4.1
  TOP w0.102: R707.1 49.59,17.18 49.33,16.92 v2(48.77,16.92) 48.58,17.11 R458.2 47.69,18.8 R71.2
PCH_GP15: length 22.5
  TOP w0.102: v1(20.07,30.46) 19.9,30.29 R72.2 ; U29.AC32 32.84,41.42 v3(32.7,41.42)
  BOTTOM w0.102: v1(20.07,30.46) 20.09,30.46 20.13,30.42 23.36,30.42 v2(23.47,30.53) 24.23,31.29 28.67,31.29 30.12,32.75 30.12,34.74 31.94,36.56 31.94,38.97 31.87,39.03 31.87,40.22 31.92,40.27 31.92,40.65 v3(32.7,41.42)
PCH_GP35: length 4.8
  TOP w0.102: U29.M40 39.15,36.81 39.15,35.09 40.54,33.71 40.9,33.71 v1(40.92,33.69)
  BOTTOM w0.102: TP90.1 40.94,33.71 v1(40.92,33.69)
PCH_GP38: length 15.5
  TOP w0.102: v1(43.44,33.76) 43.18,33.76 41.76,35.18 41.76,35.53 41.73,35.56 41.15,36.14 U29.H41 ; v1(47.65,27.64) 47.83,27.64 48.96,26.51 48.96,26.2 49.88,25.28 RN64.1
  BOTTOM w0.102: v1(43.44,33.76) 44.83,32.37 v2(44.83,32.11) 44.83,30.33 45.73,29.44 45.97,29.44 47.65,27.76 v1(47.65,27.64)
PCH_GP44: length 20.4
  TOP w0.102: U29.AA36 33.92,39.27 v3(33.83,39.27) ; RN42.4 27.42,27.41 26.9,27.94 v1(26.49,27.94) 26.24,27.69 R395.1
  BOTTOM w0.102: v3(33.83,39.27) 33.63,39.07 33.6,39.07 33.33,38.8 33.33,38.39 33.63,38.09 33.73,38.09 33.98,37.84 33.98,36.81 33.53,36.36 33.53,34.6 34.21,33.92 34.21,32.26 33.4,31.45 30.79,31.45 28.25,28.91 27.74,28.91 v2(27.53,28.7) 27.25,28.7 v1(26.49,27.94)
PCH_GP45: length 15.5
  TOP w0.102: R676.1 34.92,28.13 v1(34.92,28.83) 34.92,29.53 R655.1 ; v3(35.83,40.69) 35.49,41.03 U29.W32
  BOTTOM w0.102: v1(34.92,28.83) 34.47,29.29 v2(34.47,30.23) 34.47,31.54 34.82,31.9 34.82,34.76 34.34,35.25 34.34,35.99 34.99,36.64 34.99,38.89 35.2,39.09 35.2,40.03 35.83,40.66 v3(35.83,40.69)
PCH_GP48: length 18
  TOP w0.102: v3(40.75,34.55) 40.27,34.55 39.56,35.26 39.56,36.39 39.77,36.59 U29.L40 ; v1(48.08,26.67) 48.24,26.67 48.73,26.18 48.73,26.11 49.23,25.61 RN64.2
  BOTTOM w0.102: v3(40.75,34.55) 41.71,34.55 43.04,33.22 v2(43.04,32.75) 44.25,31.54 44.25,29.55 46.6,27.2 47.32,27.2 47.85,26.67 v1(48.08,26.67)
PCH_GP69: length 13.4
  TOP w0.102: U29.AV35 24.82,39.49 24.59,39.72 22.45,39.72 21.68,38.95 20.64,38.95 20.33,38.64 20.33,38.63 19.79,38.1 19.6,38.1 19.2,37.7 19.2,37.4 18.15,36.35 18.15,36.31 v2(17.47,35.63) 16.92,36.18 R1549.1 16.09,36.18 15.89,35.98 15.88,35.98 15.88,35.94 15.77,35.84 14.47,35.84 R615.1
PCH_GP70_PU: length 24.9
  TOP w0.102: U29.AK28 29.26,43.1 29.69,42.67 v3(29.69,42.63) ; RN35.2 11.63,38.43 11.52,38.32 11.52,37.69 10.88,37.05 v1(10.4,37.05)
  BOTTOM w0.102: v1(10.4,37.05) v2(11.63,37.05) 12.95,37.05 16.01,40.11 20.35,40.11 20.41,40.17 22.06,40.17 22.18,40.28 22.71,40.28 24.24,41.81 28.52,41.81 29.31,42.6 29.66,42.6 v3(29.69,42.63)
PCH_GP71_PU: length 17.2
  TOP w0.102: v3(27,40.29) 26.98,40.29 26.81,40.12 U29.AT34 ; v1(17.81,38.02) 17.11,38.72 13.33,38.72 12.38,37.77 RN35.1
  BOTTOM w0.102: v3(27,40.29) 26.69,39.98 v2(24.49,39.98) 23.98,39.47 22.51,39.47 22.39,39.35 20.76,39.35 19.92,38.51 18.29,38.51 v1(17.81,38.02)
PCH_GP72_PU: length 8.2
  TOP w0.102: U29.AJ40 30.13,36.67 30.13,35.73 29.74,35.34 29.74,33.91 28.19,32.36 R646.1 28.19,31.74 28.63,31.31 28.63,29.62 v4(28.68,29.57)
PCH_GP74_PU: length 6.3
  TOP w0.102: U29.AJ39 30.28,37.34 30.28,37.26 30.45,36.91 30.48,36.81 30.48,36.59 30.34,36.44 30.34,35.63 29.95,35.24 29.95,33.83 29.36,33.24 v2(29.36,32.77) 29.21,32.62 R508.1
PCH_GPIO16: length 16.6
  TOP w0.102: RN66.2 47.19,26.05 47.04,26.19 v1(47.04,26.72) ; U29.M39 38.84,37.25 38.84,36.61 38.95,36.5 38.95,35.01 40.91,33.05 41.77,33.05 v1(41.88,32.93)
  BOTTOM w0.102: v1(47.04,26.72) 46.3,26.72 43.69,29.34 v2(43.69,30.28) 43.69,31.35 42.1,32.93 v1(41.88,32.93)
PCH_INTRUDER_N: length 5.6
  TOP w0.102: R502.1 24.07,32.22 24.55,32.7 24.55,33.51 v1(25.43,34.39) 26.04,35 26.43,35 26.9,35.47 26.9,36.18 U29.AR41
PCH_INTVRMEN: length 6.7
  TOP w0.102: R515.2 R514.2 21.01,35.94 21.76,36.68 21.76,37 v1(22.32,37.56) 22.59,37.83 22.9,37.83 23.91,38.83 24.77,38.83 24.85,38.92 U29.AV36
PCH_JTAG_RST_R: length 44.9
  TOP w0.102: U29.W37 35.64,37.86 35.64,37.03 35.67,36.96 35.7,36.92 35.7,36.51 35.66,36.47 35.66,36 35.94,35.72 35.94,33.53 40.3,29.18 40.3,25.51 41.53,24.28 42.83,24.28 45.82,21.29 57.1,21.29 58.6,19.79 v2(60.15,19.79) 60.73,19.79 61.59,18.93 61.59,16.63 C1672.1 63.01,16.24 R712.1 64.08,16.25 R765.2 R562.1
PCH_JTAG_TCK: length 37.6
  TOP w0.102: C575.1 R816.1 57.12,17.78 57.12,19.21 56.65,19.68 56.34,19.68 v2(56.01,20.02) 55.65,20.37 45.44,20.37 42.45,23.37 41.15,23.37 39.38,25.13 39.38,28.8 34.94,33.24 34.94,34.65 34.34,35.24 34.34,35.61 34.39,35.67 34.39,36.84 U29.Y40
PCH_JTAG_TDI: length 40.9
  TOP w0.102: R817.2 60.91,16.23 R764.1 59.86,17.16 60.43,17.73 TP105.1 59.44,19.46 58.55,19.46 56.95,21.06 45.73,21.06 42.73,24.05 41.43,24.05 40.07,25.42 40.07,29.08 35.69,33.46 35.69,35.68 35.46,35.91 35.46,36.56 35.5,36.6 35.5,36.75 arc(35.49,36.81) 35.46,36.86 35.43,36.94 35.43,37.36 U29.W39
PCH_JTAG_TDO: length 40.1
  TOP w0.102: R818.1 55.6,16.22 R811.2 57.86,17.45 TP87.1 57.86,19.18 56.44,20.6 45.54,20.6 42.54,23.6 41.24,23.6 39.61,25.23 39.61,28.89 35.18,33.32 35.18,35.59 35.05,35.72 35.05,36.38 34.89,36.54 34.89,36.91 35.01,37.03 35.01,37.29 34.85,37.46 34.85,37.75 U29.Y38
PCH_JTAG_TMS: length 39.4
  TOP w0.102: R766.2 58.78,16.23 R812.1 57.7,16.57 59.18,18.06 TP104.1 56.82,20.83 45.63,20.83 42.64,23.83 41.34,23.83 39.84,25.32 39.84,28.99 35.43,33.39 35.43,35.65 35.25,35.83 35.25,36.5 35.23,36.51 U29.W40
PCH_MEPWROK_R: length 26.5
  TOP w0.102: R581.2 26.67,21.81 26.67,24.53 v1(26.6,24.6) ; v3(33.81,40.78) 33.82,40.78 34.07,41.03 U29.AA32
  BOTTOM w0.102: v3(33.81,40.78) 33.81,40.59 33.4,40.18 33.4,39.18 33.13,38.9 33.13,38.13 32.95,37.96 32.95,34.89 34.01,33.83 34.01,32.34 33.32,31.65 30.49,31.65 28.1,29.26 27.17,29.26 25.9,27.99 v2(25.9,26.64) 25.9,25.3 v1(26.6,24.6)
PCH_RI: length 23.8
  TOP w0.102: R536.1 17.12,29.39 v3(16.33,28.6) ; U29.AE36 31.63,38.89 v3(31.52,38.78)
  BOTTOM w0.102: v3(16.33,28.6) 17.3,29.57 17.8,29.57 18.55,30.31 19.27,30.31 19.54,30.59 19.85,30.9 20.42,30.9 20.7,30.62 22.32,30.62 23.26,31.56 28.18,31.56 v2(28.92,32.3) 29.9,33.27 29.9,34.8 31.52,36.42 v3(31.52,38.78)
PCH_RTCRST_DOWN: length 3.2
  TOP w0.102: CMCLR1.1 119.77,29.97 R492.1
PCH_RTCRST_PULLUP: length 137.8
  TOP w0.102: CMCLR1.2 117.8,30.53 R497.1 116.74,27.65 C422.1 R499.2 116.73,25.77 117.68,24.82 v1(117.81,24.82) ; U29.AR38 27.65,37.9 27.93,37.62 27.93,37.47 27.97,37.44 27.97,37 28.01,36.95 28.01,36.53 27.88,36.4 27.88,35.96 27.99,35.86 27.99,34.46 26.65,33.12 26.32,33.12 25.25,32.05 25.25,30.71 24.64,30.1 24.64,23.42 23.93,22.71 23.93,19.91 25.55,18.29 26.82,18.29 27.48,17.63 28.62,17.63 30.01,16.23 32.15,16.23 32.71,15.67 39.97,15.67 50.11,5.54 62.14,5.54 73.47,16.86 73.47,17.7 78.4,22.63 79.12,22.63 81.18,24.69 v1(81.25,24.69)
  BOTTOM w0.102: v1(117.81,24.82) 117.21,25.42 v2(103.73,25.42) 103.14,25.42 101.4,23.67 83.24,23.67 82.22,24.69 v1(81.25,24.69)
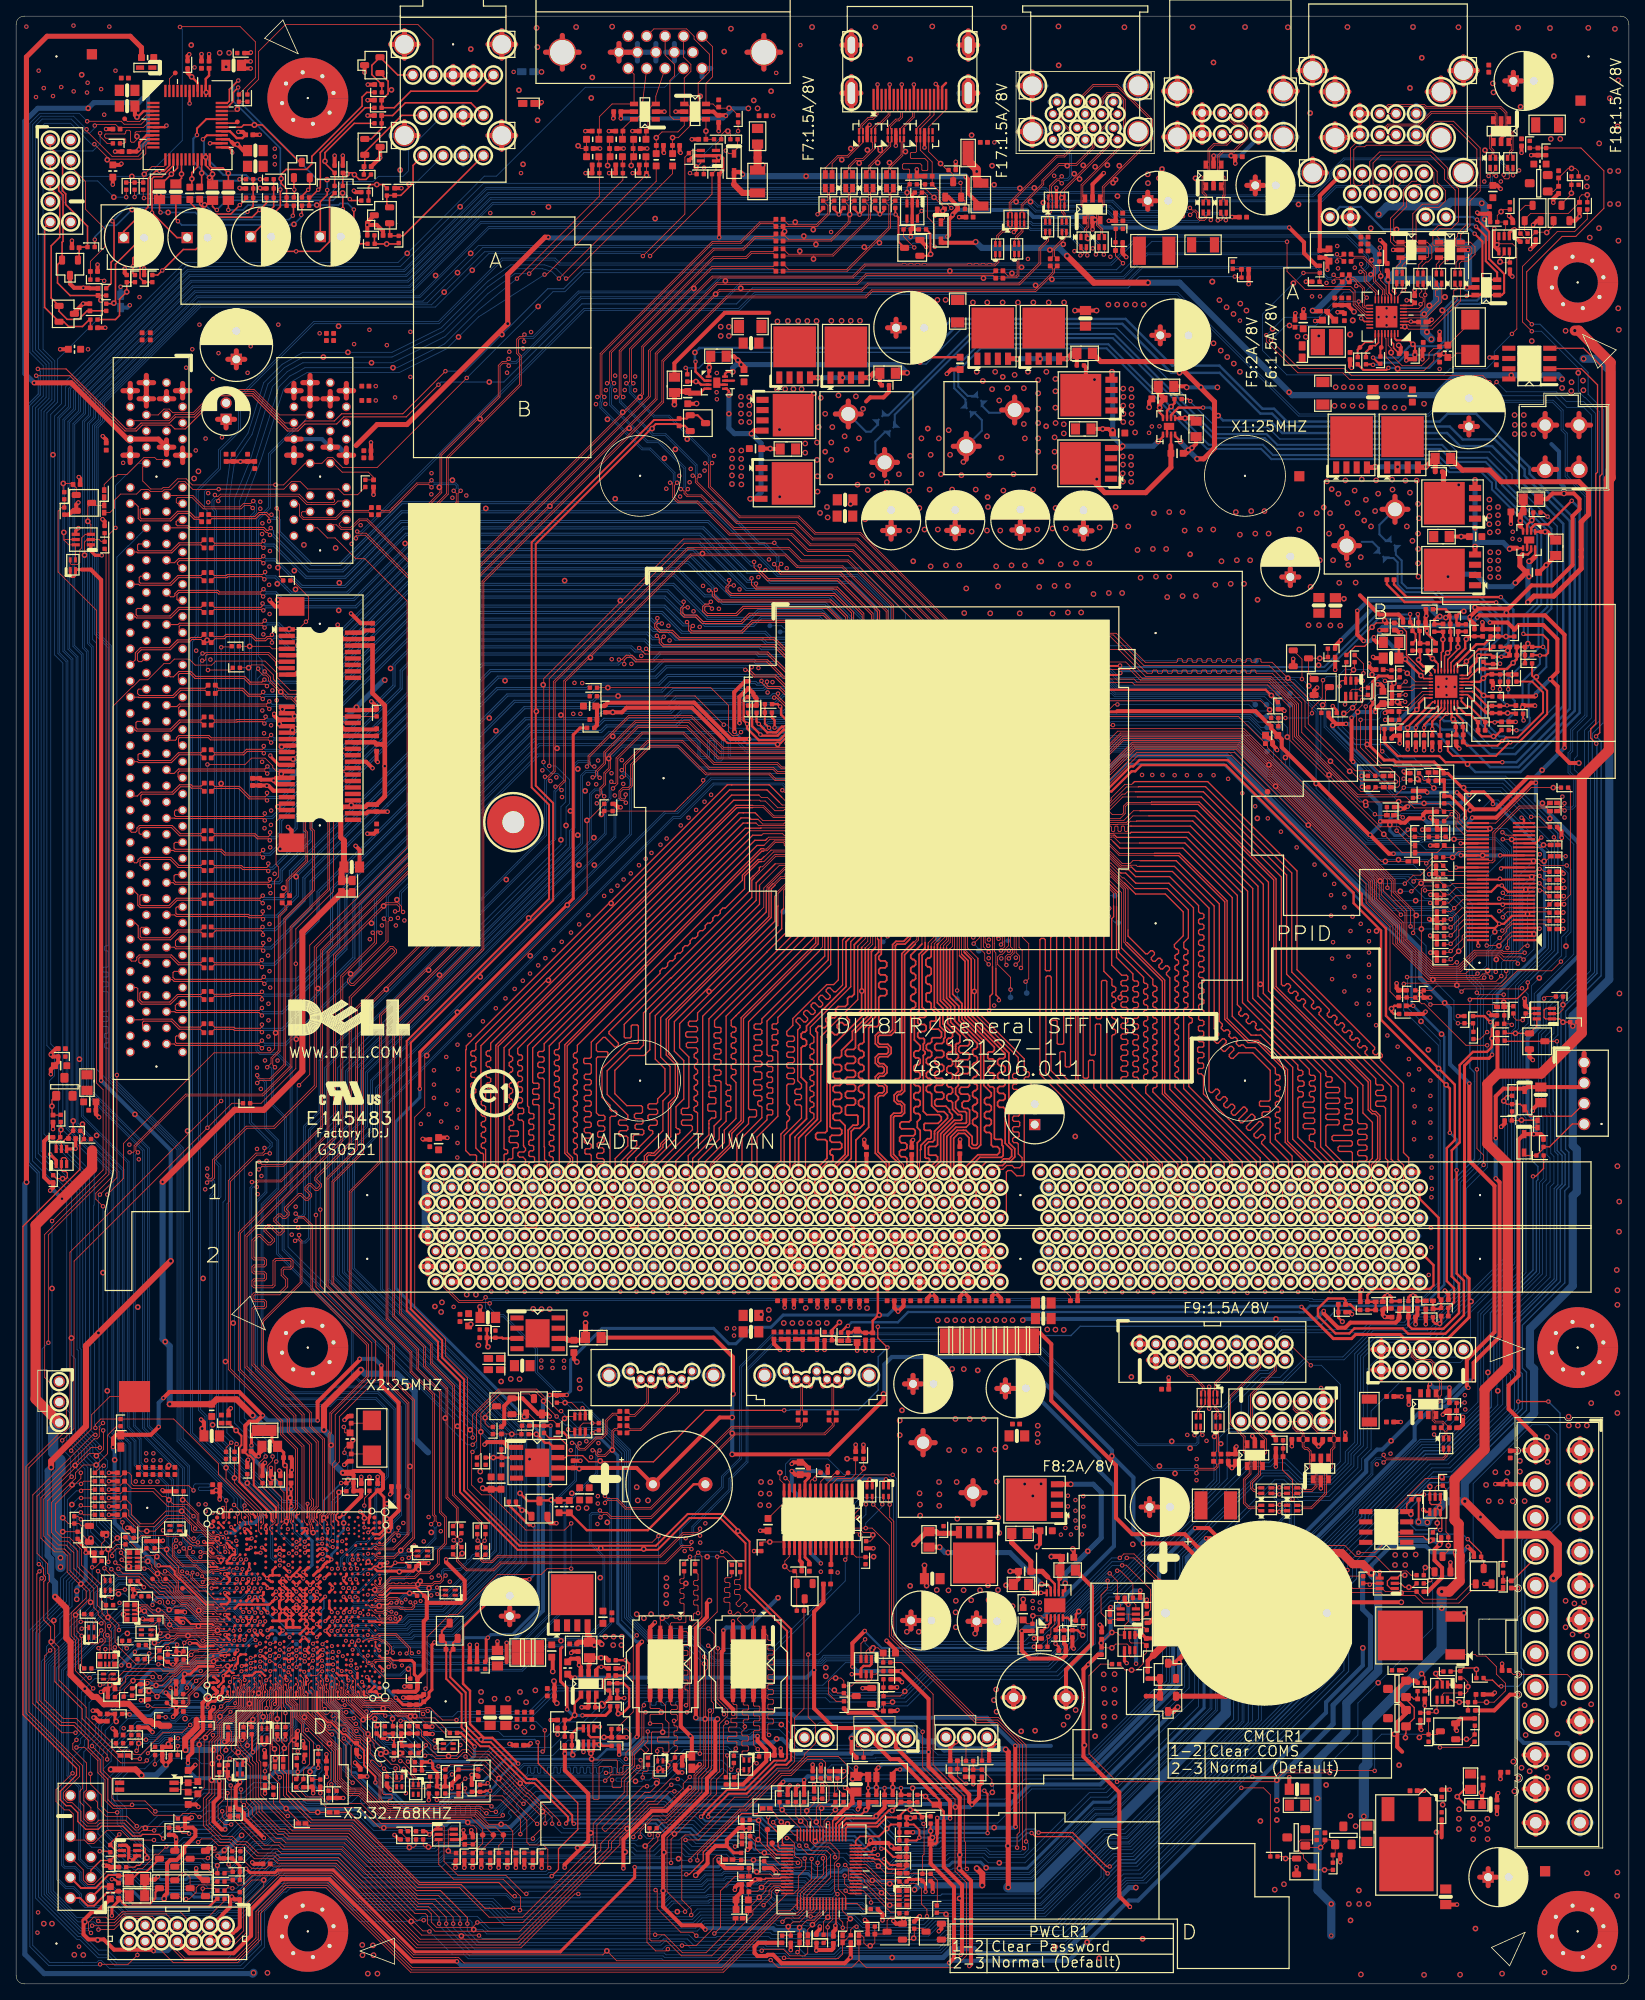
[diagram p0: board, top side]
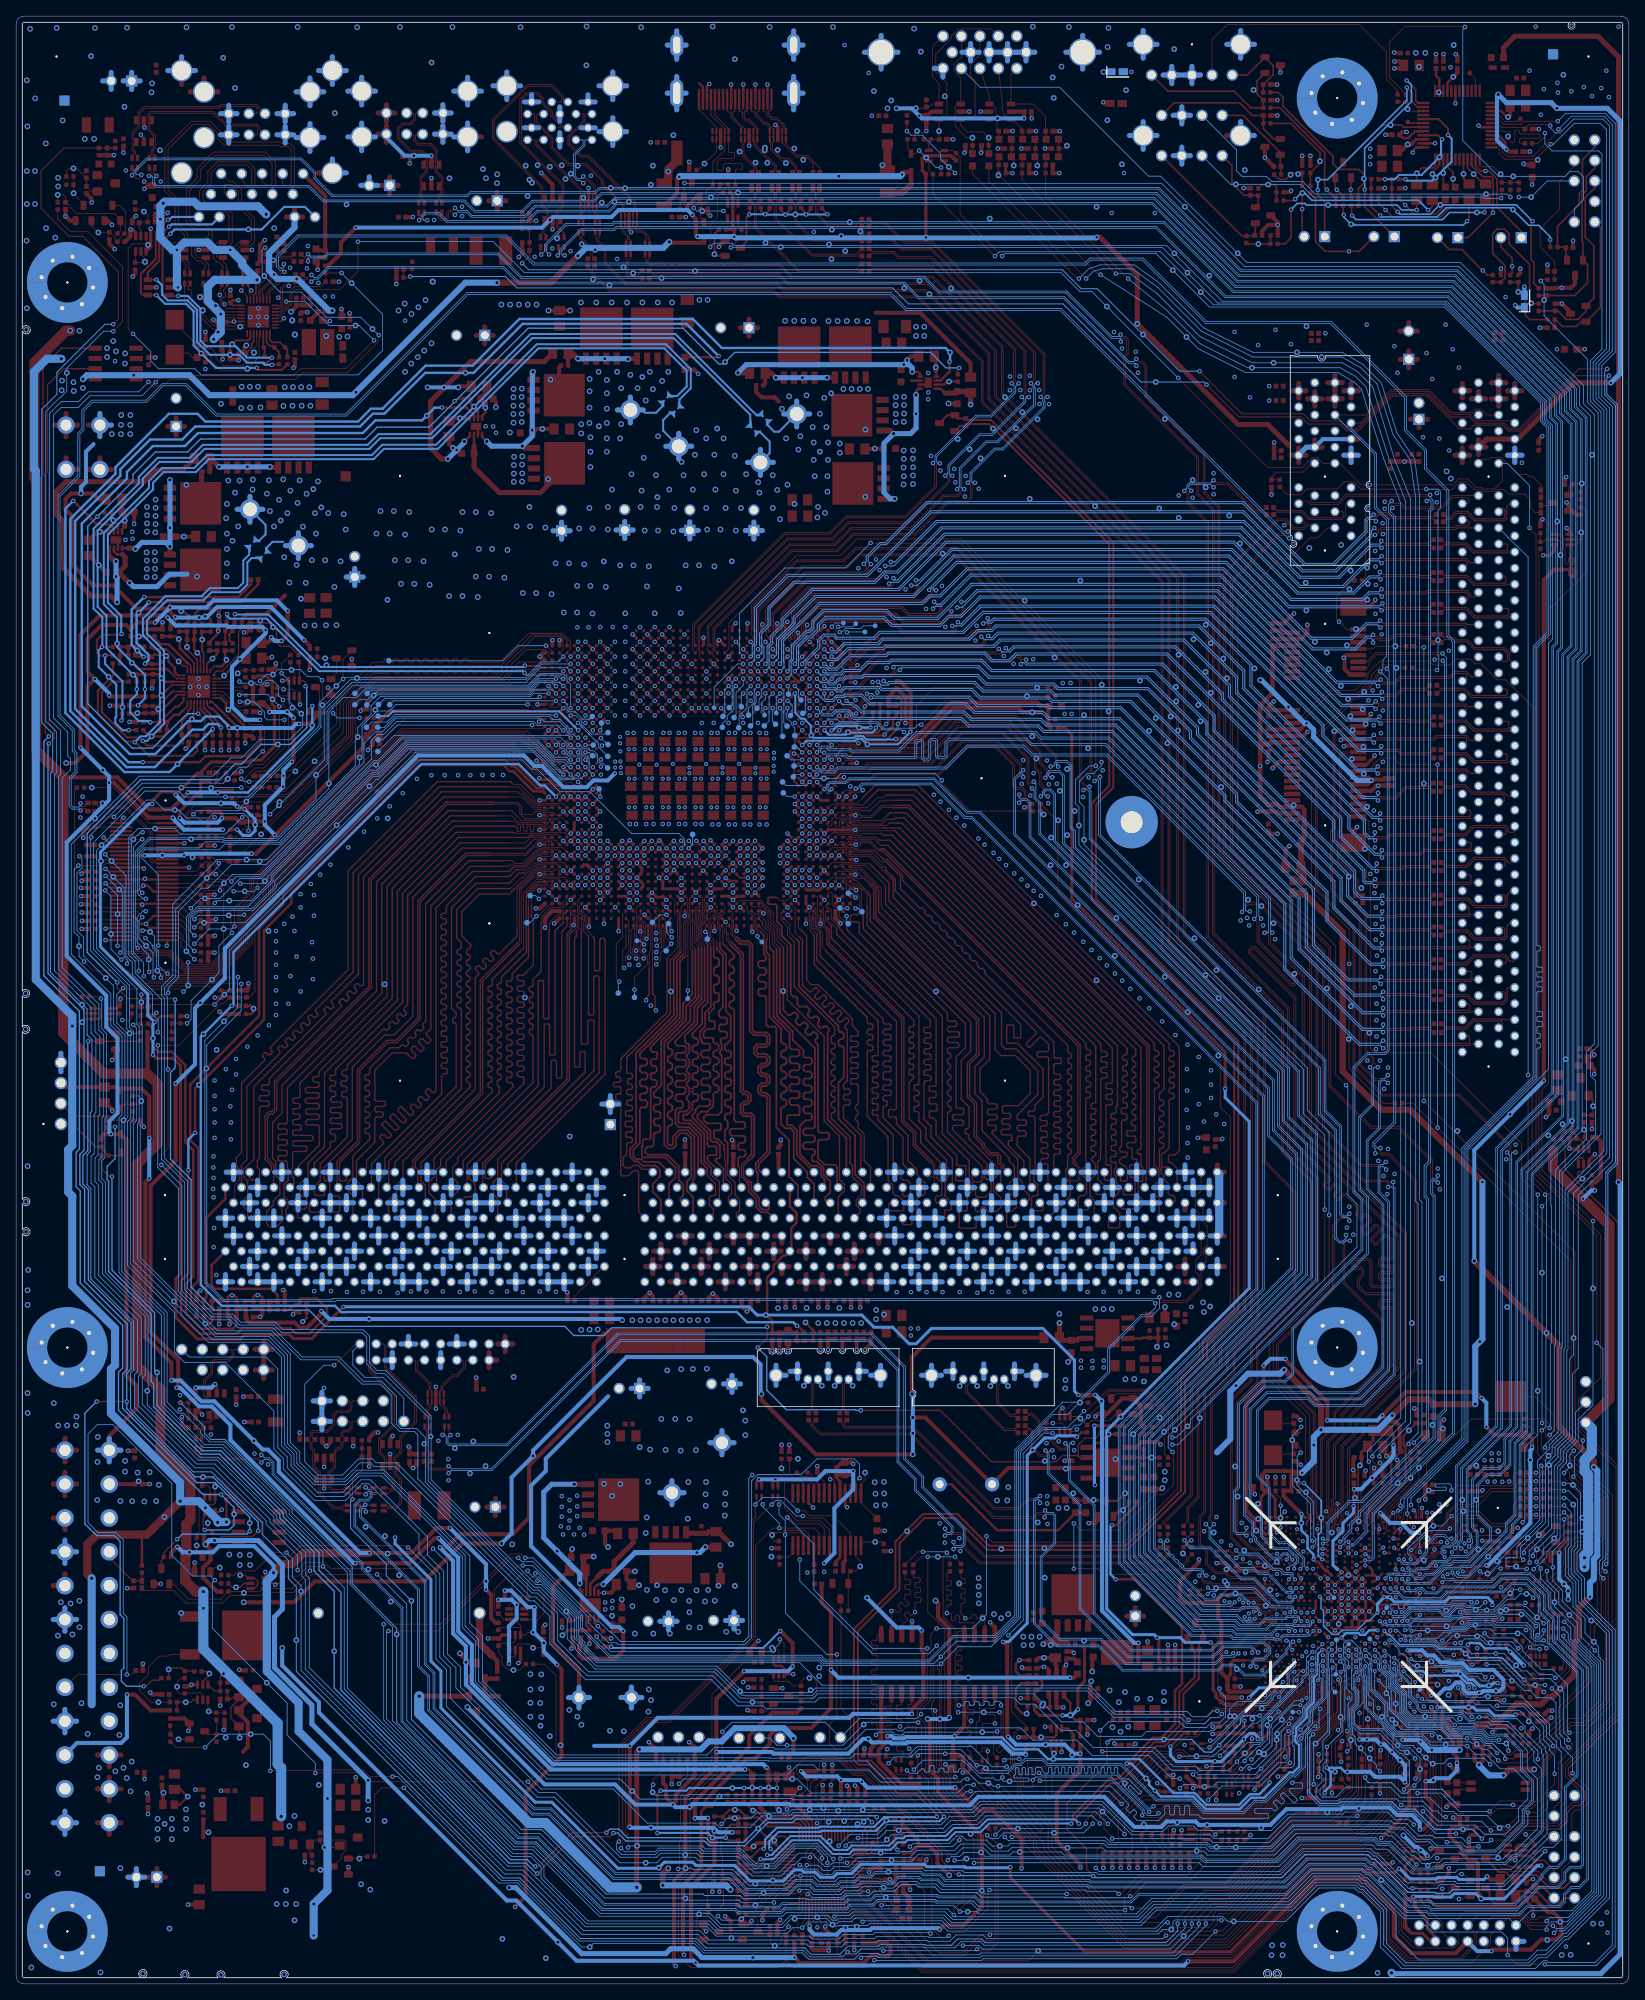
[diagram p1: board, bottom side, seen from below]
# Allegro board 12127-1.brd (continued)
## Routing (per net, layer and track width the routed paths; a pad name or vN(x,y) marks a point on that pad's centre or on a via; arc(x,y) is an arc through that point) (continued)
PCH_RTCX1: length 17.9
  TOP w0.102: U29.AN40 27.5,36.6 27.48,36.57 27.48,35.79 27.58,35.69 27.58,34.63 27.34,34.38 26.16,34.38 25.64,33.86 25.18,33.86 24.75,33.43 24.75,32.61 24.59,32.45 24.59,31.82 24.26,31.5 24,31.5 22.71,30.2 v2(22.71,29.68) 22.71,25.27 R553.1 22.38,24.94 C443.1 19.59,24.94 X3.1
PCH_RTCX2: length 20.2
  TOP w0.102: X3.4 21.03,24.08 C423.1 22.33,23.77 R553.2 23.32,24.36 23.32,30.37 24.23,31.28 24.33,31.28 24.79,31.74 24.79,32.37 25.28,32.86 v2(25.28,33.16) 26.3,34.18 27.42,34.18 27.79,34.54 27.79,35.77 27.68,35.88 27.68,36.49 27.81,36.61 27.81,36.87 27.77,36.91 27.77,37.35 U29.AN39
PCH_SATA_LED_N: length 144.8
  TOP w0.102: U29.J39 40.64,37.3 40.64,36.53 40.6,36.49 40.6,35.99 41.25,35.34 41.25,34.99 41.6,34.64
  TOP w0.165: v1(83.11,13.58) 83.48,13.58 85.21,15.31 85.21,16.34 89.97,21.11 91.91,21.11 SR732.1 ; v1(64.67,29.95) 64.74,29.87 64.74,27.33 69.65,22.42 69.65,19.13 67.26,16.74 67.26,14.2 v1(66.42,13.36) ; R583.1 49.97,28.64 50.8,29.46 v1(50.8,29.59) ; v1(45.79,33.26) 45.55,33.5 44.25,33.5 43.81,33.07 43.17,33.07 41.6,34.64 ; v1(10.36,16.45) 11.55,16.45 R2234.1
  BOTTOM w0.165: v1(10.36,16.45) 15.14,11.68 21.84,11.68 22.27,11.25 23.97,11.25 24.08,11.35 27.39,11.35 31.5,15.46 31.81,15.46 32.36,16.01 40.17,16.01 43.01,13.18 66.24,13.18 v1(66.42,13.36) 66.49,13.43 82.96,13.43 v1(83.11,13.58) ; v1(45.79,33.26) 47.71,33.26 48.16,32.81 48.16,32.31 50.8,29.67 v1(50.8,29.59) 50.88,29.59 51.72,28.75 52.65,28.75 54.21,30.31 v2(57.66,30.31) 64.31,30.31 v1(64.67,29.95)
PCH_SIO_DPWROK: length 8.6
  TOP w0.102: R604.1 91.03,19.27 R572.1 ; U61.7 94.75,14.8 93.49,16.05 92.99,16.05 v2(92.79,16.26) 92.25,16.26 91.67,16.84 91.67,17.67 R572.1 ; R572.1 R708.1
PCH_SIO_DPWROK_1: length 116.6
  TOP w0.102: v1(9.21,26.06) 9.21,24.79 10.57,23.43 10.57,22.06 11.37,21.26 v1(12.53,21.26) ; v1(89.15,17.02) 89.55,17.41 R708.2 ; v1(16.33,34.49) 16.66,34.49 16.91,34.25 21.03,34.25 21.54,34.76 21.54,35.74 24.21,38.41 24.89,38.41 U29.AV38
  BOTTOM w0.102: v1(12.53,21.26) 12.53,19.83 16.36,16 20.59,16 20.71,16.12 24.06,16.12 24.77,15.42 25.46,15.42 26.46,16.42 26.76,16.42 29.17,18.83 29.64,18.83 29.95,19.15 41.47,19.15 44.16,16.46 52.05,16.46 52.53,16.94 64.66,16.94 65.12,17.4 76.7,17.4 77.01,17.09 v2(78,17.09) 78.95,17.09 79.68,17.83 82.19,17.83 82.68,18.31 83.4,18.31 84.31,17.4 88.77,17.4 v1(89.15,17.02) ; v1(9.21,26.06) 9.21,28.35 9.87,29.01 9.87,29.55 10.56,30.25 10.56,31.9 13.03,34.37 16.21,34.37 v1(16.33,34.49)
PCH_SPKR1: length 2.9
  TOP w0.305: R648.2 61.99,59.49 v2(62.74,58.74) 63.15,58.74 Q53.B
PCH_SRTCRSTB_PULLUP: length 137.9
  TOP w0.102: v3(26.58,33.74) 26.58,33.7 25.02,32.13 25.02,30.81 24.28,30.07 24.28,23.57 23.57,22.86 23.57,19.76 25.4,17.93 26.67,17.93 27.33,17.27 28.47,17.27 29.87,15.88 32,15.88 32.56,15.32 39.83,15.32 49.96,5.18 62.29,5.18 73.83,16.72 73.83,17.55 78.55,22.28 79.5,22.28 81.1,23.88 v1(81.64,23.88) ; C420.1 R498.1 ; R498.1 118.68,26.57 R497.2 ; R498.1 119.75,26.56 R481.2 121.01,25.32 v1(121.01,24.71) ; v3(27.17,34.8) 27.27,34.91 27.27,36.42 27.24,36.45 27.13,36.71 U29.AR39
  BOTTOM w0.102: v1(121.01,24.71) 121.21,24.51 121.21,23.9 v2(121.06,23.75) 120.7,23.39 116.68,23.39 116.61,23.47 103.38,23.47 103.23,23.32 82.7,23.32 82.14,23.88 v1(81.64,23.88) ; v3(27.17,34.8) 27.17,34.32 v3(26.58,33.74)
PCH_SYSPWROK: length 21.2
  TOP w0.102: v3(34.75,41.37) 35.12,41.74 U29.W31 ; R759.2 31.9,24.5 R590.2 v1(30.86,26.37) C3315.1
  BOTTOM w0.102: v1(30.86,26.37) 31.29,26.8 31.29,27.13 v2(32.16,27.99) 33.93,29.77 33.93,30.61 34.26,30.94 34.26,31.62 34.62,31.98 34.62,34.09 33.93,34.77 33.93,36.19 34.39,36.64 34.39,38.92 34.34,38.97 34.34,40.48 34.33,40.49 34.33,40.84 34.75,41.26 v3(34.75,41.37)
PCIE_RCOMP: length 5.6
  TOP w0.203: R695.2 48.3,52.22 v1(47.02,52.22) 46.53,51.74 44.78,51.74 44.75,51.77 44.4,51.77 44.05,51.41 U29.C13
PCIEX1_PRSNT2_N: length 251.9
  TOP w0.102: U29.N40 38.47,36.65 38.75,36.38 38.75,34.92 40.83,32.84 41.33,32.84 41.92,32.25 v1(42.14,32.25) ; v1(68.83,57.1) 68.01,56.27 63.22,56.27 60.97,58.53 59.26,60.24 58.85,60.65 57.71,60.65 56.49,61.87 56.49,65.86 v1(56.59,65.96) ; v1(68.83,51.49) 65.84,51.49 65.1,50.75 59.69,50.75 54.74,45.8 53.74,45.8 50.97,43.02 50.97,36.8 v1(50.77,36.6) ; v1(45.62,26.7) 45.97,26.34 R687.1 46.34,25.72 46.93,25.13 47.57,25.13 47.84,25.39 RN66.1 ; v1(65.56,31.45) 65.56,29.01 65.36,28.81 v1(65.29,28.81) ; SLOT1.B17 37.36,180.55 38.61,179.3 39.55,179.3 42.13,176.72 43.24,176.72 48.49,171.47 48.49,140.87 36.41,128.79 36.41,112.76 v1(35.08,111.43)
  BOTTOM w0.102: v1(68.83,57.1) v1(68.83,51.49) ; v1(65.29,28.81) 59.04,28.81 56.67,26.44 53.84,26.44 53.38,25.98 46.33,25.98 v1(45.62,26.7) 43.14,29.18 43.14,31.25 v1(42.14,32.25) ; v1(56.59,65.96) 57.12,66.5 57.12,67.89 v2(56.31,68.71) 56.31,68.78 33.72,91.37 33.72,96.69 34.85,97.82 34.85,111.2 v1(35.08,111.43) ; v1(50.77,36.6) 50.77,36.29 50.03,35.55 50.03,33.11 50.77,32.36 51.8,32.36 52.38,31.78 55,31.78 55.73,32.51 64.49,32.51 v1(65.56,31.45)
PCIEX16_PRSNT2_N: length 175.1
  TOP w0.102: v1(12.5,112.7) 12.5,99.97 v1(10.39,97.87) ; U29.AT30 25.85,42.04 25.54,41.72 25.28,41.72 24.94,42.06 24.79,42.06 24.52,42.33 23.54,42.33 23.32,42.12 22.94,42.12 22.38,42.68 21.25,42.68 v1(20.85,42.29) 20.76,42.2 R427.1 ; v1(10.79,68.63) 10.85,68.58 10.85,66.27 10.34,65.76 9.06,65.76 3.43,60.13 3.43,55.52 5.03,53.92 6.01,53.92 6.13,53.81 6.68,53.25 6.68,51.23 9.14,48.76 9.14,47.8 7.19,45.85 7.19,43.29 7.72,42.76 7.72,39.11 8.88,37.94 v1(9.11,37.94)
  BOTTOM w0.102: SLOT2.B17 14.99,179.39 14.99,179.36 13.93,178.31 13.88,178.31 12.5,176.92 v1(12.5,112.7) ; v1(20.85,42.29) 20.37,42.77 18.38,42.77 17.67,42.06 14.82,42.06 11.11,38.35 9.53,38.35 v1(9.11,37.94) ; v1(10.79,68.63) 10.77,68.63 10.29,69.11 10.29,80.65 v2(10.21,80.72) 10.21,97.69 v1(10.39,97.87)
PCIRST1#: length 6.3
  TOP w0.102: R568.2 R601.1 91.36,14.35 v2(91.83,13.88) 92.11,13.6 93.58,13.6 93.79,13.39 94.51,13.39 94.73,13.6 U61.10
PCIRST3#: length 156.7
  TOP w0.102: Q38.D 97.7,47.65 R429.1 97.7,34.14 96.55,32.98 96.55,27.56 95.73,26.75 94.38,26.75 90.78,23.14 89.08,23.14 84.4,18.47 82.96,18.47 82.55,18.06 82.55,10.44 83.72,9.27 v1(83.72,8.53) ; v1(112.95,8.38) 112.95,9.22 112.27,9.91 112.27,11.82 111.63,12.46 110.98,12.46 110.73,12.2 110.1,12.2 109.6,12.7 R756.1 109.28,12.95 107.31,12.95 105.47,14.8 U61.42
  BOTTOM w0.102: v1(112.95,8.38) 112.47,7.9 110.21,7.9 v2(110.06,8.05) 109.72,8.39 104.93,8.39 104.5,8.83 96.83,8.83 96.37,9.28 84.47,9.28 v1(83.72,8.53) 83.51,8.32 60.92,8.32 59.03,10.22 42.2,10.22 39.07,13.35 33.46,13.35 32.91,12.8 32.6,12.8 27.88,8.08 25.46,8.08 24.64,7.27 LPC1.3
PECI_PCH: length 46.1
  TOP w0.102: R578.1 v1(78.55,18.49) ; U29.G40 41.86,36.74 41.86,36 42.16,35.7 42.16,35.35 43.01,34.51 46.25,34.51 47.44,33.33 48.44,33.33 49.27,32.5 51.73,32.5 53.3,30.93 53.3,30.86 53.53,30.63 55,30.63 56.79,28.84 58.65,28.84 63.49,24 63.61,24 67.34,20.28 v1(67.34,19.86)
  BOTTOM w0.102: v1(67.34,19.86) 67.94,19.25 v2(75.77,19.25) 77.79,19.25 v1(78.55,18.49)
PECI_REQ_N: length 16.3
  TOP w0.102: R566.1 53.78,31.13 51.93,32.98 49.67,32.98 v2(49.45,33.2) 49.12,33.53 47.52,33.53 46.34,34.71 43.09,34.71 42.37,35.44 42.37,35.78 42.08,36.07 42.08,37.68 41.69,38.06 U29.G38
PECI_SIO_R: length 4.9
  TOP w0.102: R674.2 98.17,6.76 v2(98.76,7.34) 100.47,9.06 U61.26
PEG_COMP: length 6.3
  TOP w0.305: R307.2 94.45,158.68 v1(94.74,158.39) 94.87,158.27 94.87,157.38 95.89,156.36 97.94,156.36 U27.P3
PLTRST*_LPC: length 7.9
  TOP w0.102: U61.13 93.58,12.4 92.98,11.8 92.98,11.54 v2(92.15,10.72) 90.81,9.37 C484.1 90.81,8.64 90.3,8.13 R600.1
PLTRST_CPU_N: length 228.9
  TOP w0.102: v1(181.16,113.4) 181.16,103.58 181.99,102.74 v1(181.99,101.55) ; R416.1 174.63,139.19 v1(174.88,138.95) 175.62,139.69 R660.1 ; U29.F41 42.57,36.06 42.57,35.52 43.17,34.92 46.42,34.92 47.61,33.73 50.2,33.73 v1(50.47,33.47)
  BOTTOM w0.102: v1(181.99,101.55) 179.45,99.01 179.45,85.92 175.87,82.35 173.46,82.35 172.45,81.34 168.12,81.34 164.53,77.74 159.96,77.74 156.94,74.73 154.7,74.73 152.83,72.86 152.83,69.4 152.29,68.86 150.34,68.86 149.25,67.77 149.25,62.22 135.85,48.82 135.18,48.82 131.66,45.3 131.66,42.8 130.63,41.76 130.63,41.48 128.19,39.04 113.25,39.04 110,35.79 101.26,35.79 100.72,36.32 67.17,36.32 63.92,33.07 55.61,33.07 54.8,32.26 52.58,32.26 51.82,33.02 50.92,33.02 v1(50.47,33.47) ; v1(174.88,138.95) 174.86,138.93 174.86,138.62 v2(176.35,137.13) 180.21,133.27 180.21,124.92 181.6,123.53 181.6,122.72 181.23,122.35 181.23,113.47 v1(181.16,113.4)
PLTRST_LAN_N: length 330.4
  TOP w0.102: v1(166.5,208.61) 166.5,208.16 167.33,207.33 U12.19 ; v1(86.59,6.25) 87.35,7.01 87.35,11.53 89.15,13.34 R568.1 ; v1(155.61,203.79) 159.1,200.3 164.72,200.3 165.61,199.42 181.89,199.42 v1(182.7,198.6)
  BOTTOM w0.102: v1(166.5,208.61) 164.15,208.61 161.17,205.64 v2(157.91,205.64) 157.46,205.64 v1(155.61,203.79) ; v1(182.7,198.6) 184.37,196.93 190.85,196.93 192.3,195.48 194.41,195.48 195.36,194.53 195.36,156.99 193.6,155.22 193.6,152.27 193.27,151.94 193.27,150.53 194.28,149.51 194.28,126.03 189.74,121.49 189.74,118.28 189.14,117.68 189.14,107.63 189.35,107.42 189.35,102.6 189.74,102.21 189.74,99.69 189.27,99.23 189.27,88.03 183.99,82.75 183.99,75.5 184.35,75.13 184.35,71.89 177.41,64.95 175.08,64.95 168.03,57.9 168.03,57.45 164.08,53.5 164.08,53.1 164.08,50.75 163.65,50.32 163.65,39.23 139.02,14.59 136.93,14.59 129.43,7.09 114.32,7.09 113.15,5.92 101.6,5.92 101.25,5.56 98.01,5.56 97.45,6.12 93.75,6.12 93.52,6.35 86.69,6.35 v1(86.59,6.25)
PLTRST_MINI_N: length 17.4
  TOP w0.102: R478.2 v2(28.83,163.19) 29.18,163.55 30.66,163.55 31.89,162.31 31.89,161.8 33.78,159.92 37.16,159.92 40.73,156.35 MINI1.22
PLTRST_N: length 285.8
  TOP w0.102: v1(17.12,19.02) 15.61,19.02 15.31,18.72 14.61,18.72 13.4,19.94 10.41,19.94 10.04,19.57 8.77,19.57 8.04,20.3 8.04,21.38 6.95,22.47 6.37,22.47 5.85,22.99 5.85,23.71 7.88,25.74 7.88,26.92 1.23,33.57 1.23,64.16 5.73,68.66 6.23,69.16 6.23,72.51 3.54,75.2 3.54,92.92 11.15,100.53 11.15,177.76 R24.1 ; R600.2 89.22,7.53 85.55,3.86 82.63,3.86 80.4,6.09 v1(79.25,6.09) ; v1(27.89,24.1) 27.89,22.53 v1(28.24,22.17) 28.8,21.62 28.8,20.79 32.05,17.55 32.7,17.55 33.25,16.99 40.52,16.99 49.62,7.89 v1(50.54,7.89) ; v3(33.76,38.64) 34.08,38.32 U29.AA37
  BOTTOM w0.102: v1(27.89,24.1) 27.89,24.1 27.2,24.79 27.2,27.61 28.14,28.55 28.39,28.55 30.86,31.01 33.37,31.01 34.42,32.06 34.42,34 33.73,34.69 33.73,36.28 34.18,36.73 34.18,38.22 v3(33.76,38.64) ; v1(50.54,7.89) 50.57,7.93 56.26,7.93 56.54,7.65 56.54,6.94 v2(56.75,6.74) 57.81,6.74 58.36,6.19 79.15,6.19 v1(79.25,6.09) ; v1(17.12,19.02) 18.26,20.17 23.62,20.17 25.5,22.05 28.12,22.05 v1(28.24,22.17)
PLTRST_PCIE_SLOTS_N: length 64
  TOP w0.102: v1(23.79,162.92) 26.58,162.92 R478.1 ; R488.2 42.35,184.66 40.67,184.66 39.96,185.36 36.15,185.36 35.24,186.27 34.13,186.27 33.2,185.34 25.12,185.34 v1(25.12,185.35) 25.12,185.35 25.09,185.31 21.91,185.31 20.95,186.27 20.16,186.27 19.16,185.27 18.35,185.27 18.11,185.04 16.69,185.04 16.43,185.29 15.49,185.29 14.94,184.73 12.95,184.73 12.19,183.97 12.19,183.01 11.62,182.44 R561.2
  BOTTOM w0.102: v1(23.79,162.92) 23.64,163.07 23.64,164.7 23.68,164.74 v2(23.68,166.62) 23.68,182.7 23.36,183.01 23.36,185.05 23.66,185.35 v1(25.12,185.35)
PLTRST_PEG_PCIE_SLOTS_N: length 13.2
  TOP w0.102: RN22.4 6.71,176.12 6.83,176 7.62,176 7.9,176.28 7.9,177.83 8.13,178.05 8.13,179.3 8.58,179.75 Q48.3 9.27,180.97 v2(8.89,181.36) 8.89,183.17 Q44.C 9.68,183.32 R561.1 R533.1
PLTRST_PEG_SLOTS_N: length 10.1
  TOP w0.102: SLOT2.A11 18.17,189.03 17.42,189.03 17.18,189.27 15.85,189.27 13.72,187.15 12.6,187.15 12.4,186.94 11.94,186.94 10.92,185.93 R533.2
PLTRST_SL_X1_N: length 7.4
  TOP w0.102: SLOT1.A11 39.34,188.55 40.44,187.45 43.69,187.45 44.32,186.82 C140.1 R488.1
PLTRST_TPM_N: length 9.7
  TOP w0.102: U23.16 U22.16 95.88,52.98 95.33,52.43 v2(95.33,51.77) 95.91,51.18 R442.2 96.81,50.91 Q38.S 96.81,46.29 R429.2
PRIVACY_MSR_EN_N: length 12.1
  TOP w0.102: R867.1 v2(190.63,148.34) 187.88,148.34 183.48,143.93 XDPC1.60
PS_ON_N: length 108.8
  TOP w0.102: v1(155.23,50.77) 163.34,50.77 165.57,48.54 169.22,48.54 169.61,48.15 173.48,48.15 174.41,47.22 178.92,47.22 180.47,48.77 184.09,48.77 R489.1 ; v1(106.02,10.08) 106.02,10.59 105.01,11.6 U61.34
  BOTTOM w0.102: v1(155.23,50.77) 151.56,47.09 151.56,32.67 137.53,18.63 135,18.63 127.01,10.64 117.04,10.64 v2(116.99,10.59) 116.78,10.38 110.35,10.38 110.06,10.08 v1(106.02,10.08)
PSPWRGD: length 195.2
  TOP w0.102: v1(175.36,50.06) 174.96,49.66 R491.1 ; R778.1 134.47,39.65 133.05,38.23 133.05,28.55 v1(136.53,25.07) 156.01,25.07 157.1,26.16 162.86,26.16 v1(162.89,26.14) ; U61.6 96.77,15.2 v1(96.95,15.01) ; C438.1 185.67,38.35 v1(186.26,38.35) 192.38,38.35 ATX1.8
  BOTTOM w0.102: v1(136.53,25.07) 135.19,23.74 133.1,23.74 125.06,15.7 120.56,15.7 120.07,16.19 115.61,16.19 115.21,15.8 110.46,15.8 108.53,13.87 105.32,13.87 102.98,16.21 101.32,16.21 100.91,15.79 100.91,15.75 99.71,14.55 99.2,14.55 98.74,15.01 v1(96.95,15.01) ; v1(186.26,38.35) 186.26,45.49 186.72,45.95 186.72,55.04 187.66,55.98 189.87,55.98 191.08,57.2 191.08,68.17 189.92,69.34 187.99,69.34 180.7,62.05 180.7,53.16 178.1,50.57 175.87,50.57 v1(175.36,50.06) 175.67,49.76 175.67,44.09 v2(168.91,37.34) 166.4,34.82 166.4,30.86 162.89,27.36 v1(162.89,26.14)
PSPWRGD_INV: length 104.9
  TOP w0.102: v1(163.56,51.23) 165.77,49.02 Q50.6 169.42,49.02 169.81,48.63 171.54,48.63 171.55,48.64 R477.2 174.61,47.7 178.6,47.7 180.46,49.56 181.01,49.56 Q58.G ; R402.2 189.74,122.43 v1(189.48,122.17)
  BOTTOM w0.102: v1(163.56,51.23) 163.56,53.48 167.68,57.6 167.68,58.05 174.94,65.3 177.27,65.3 183.74,71.78 v2(183.74,73.53) 183.64,73.64 183.64,82.89 188.92,88.18 188.92,99.38 189.38,99.84 189.38,102.06 189.2,102.24 189,102.45 189,107.27 188.79,107.48 188.79,117.83 189.38,118.42 189.38,122.07 v1(189.48,122.17)
PSPWRGD_INV_B1: length 2.9
  TOP w0.102: Q42.5 175.97,57.92 176.23,57.66 v2(176.23,57.15) 176.23,56.64 175.69,56.1 R467.1
PSPWRGD_L: length 9.1
  TOP w0.102: R778.2 137.53,38.91 v2(138.33,38.91) 138.96,38.91 139.75,39.7 139.75,40.64 140.16,41.05 C3320.1 139.84,42.27 138.28,42.27 138.1,42.44 Q73.2
PW_CLEAR: length 154.2
  TOP w0.102: v3(27.95,38.76) 28.08,38.89 U29.AM36 ; v1(88.14,32.41) 87.71,31.98 87.71,26.15 86.84,25.29 86.84,23.55 81.22,17.93 v1(81.22,15) ; v1(104.4,29.6) 105.09,28.91 R367.2
  BOTTOM w0.102: v1(88.14,32.41) 88.16,32.44 94.61,32.44 v2(94.89,32.16) 94.91,32.16 97.47,29.59 104.4,29.59 v1(104.4,29.6) 104.41,29.59 105.65,29.59 106.54,30.48 PWCLR1.2 ; v1(81.22,15) 81.2,15.02 53.31,15.02 52.84,14.55 43.37,14.55 40.68,17.24 31.85,17.24 31.3,16.69 29.92,16.69 26.87,13.64 24.15,13.64 23.97,13.82 21.54,13.82 21.16,14.2 14.59,14.2 10.15,18.64 10.15,28.6 10.35,28.81 10.35,29.32 11.05,30.02 11.05,31.4 13.53,33.88 16.43,33.88 17.14,34.59 18.97,34.59 19.3,34.92 26.12,34.92 26.94,35.75 26.94,37.76 v3(27.95,38.76)
PWM1_BT: length 3
  TOP w0.305: U16.1 189,180.06
  TOP w0.508: 189,180.06 v2(189.61,180.06) 189.9,180.06 R266.2
PWM1_BT_1: length 3
  TOP w0.508: R266.1 v2(189.75,175.92) 188.86,175.03 C201.1
PWM1_EN: length 2.7
  TOP w0.305: R156.1 188.15,181.67 187.96,181.48 v2(187.96,181.48) 187.96,181.48 187.38,180.9 U16.3
PWM1_HG: length 44.3
  TOP w0.305: 188.38,177 U16.8
  TOP w0.635: R268.2 179.35,187.71 182.73,187.71 184.17,186.27 193.82,186.27 194.99,185.1 194.99,182.19 194.09,181.29 194.09,177.84 194.09,175.5 190.68,172.09 188.24,172.09 v6(187.48,171.32) ; 188.38,177 187.78,176.4 v6(187.62,176.4)
  BOTTOM w0.635: v6(187.62,176.4) v2(187.62,174.5) 187.48,174.36 v6(187.48,171.32)
PWM1_HG_1: length 11.6
  TOP w0.635: R197.2 175.98,189.14 R268.1 175.87,189.15 v6(174.83,188.11) 174.76,188.04 Q31.4 ; v6(168.53,188.11) 168.45,188.04 Q27.4
  BOTTOM w0.635: v6(168.53,188.11) v2(171.32,188.11) v6(174.83,188.11)
PWM1_LG: length 16.8
  TOP w0.305: U16.5 186.11,178.03
  TOP w0.635: v6(180.92,186.49) Q28.4 ; Q30.4 v6(180.92,178.23) ; 186.11,178.03 185.32,178.03 v6(185.22,177.93)
  BOTTOM w0.635: v6(185.22,177.93) 184.4,178.74 181.43,178.74 v6(180.92,178.23) v2(180.92,180.54) v6(180.92,186.49)
PWM1_LX: length 36.4
  TOP w0.305: U16.7 187.88,177.65 187.47,177.24 186.82,177.24
  TOP w0.635: L27.1 171,184.44 ; L27.1 172.6,182.84 ; L27.1 169.39,182.84 ; L27.1 171,181.24 ; 186.82,177.24 186.49,176.91 186.49,175.82 C201.2 185.98,173.74 v6(185.93,173.74) ; Q28.5 177.01,183.69 177.01,187.36 R197.1
  BOTTOM w0.254: L27.1 169.06,180.91 169.06,179.74 169.83,178.97 G1.1
  BOTTOM w0.635: v6(185.93,173.74) 185.45,173.25 182.52,173.25 180.97,174.8 178.82,174.8 ; L27.1 172.6,182.84 ; L27.1 171,181.24 ; L27.1 171,184.44 ; L27.1 169.39,182.84
  vias: v2(163.14,185.34) v2(167.18,181.46) v2(177.57,174.5) v2(178.89,185.88) v6(162.56,186.31) v6(163.98,184.77) v6(164.85,186.44) v6(165.1,183.64) v6(165.99,185.17) v6(166.37,182.37) v6(166.88,186.56) v6(167.39,184.02) v6(168.02,180.72) v6(168.53,182.63) v6(168.66,186.44) v6(168.91,184.78) v6(170.64,186.54) v6(170.69,185.29) v6(172.29,186.41) v6(172.47,180.72) v6(172.85,184.91) v6(173.16,178.94) v6(173.69,186.41) v6(173.86,183.51) v6(173.86,179.83) v6(173.86,177.93) v6(173.86,176.15) v6(173.91,174.5) v6(173.96,181.74)
PWM1_SNB: length 2.5
  TOP w0.508: R190.2 177.73,179.46 v2(179.2,179.46) C235.1
PWM1_VCC: length 4.3
  TOP w0.305: 186.54,180.75 186.88,180.41 U16.4
  TOP w0.635: R182.2 C237.2 186.54,182.17 v2(186.54,181.43) 186.54,180.75
PWM2_BT: length 2.8
  TOP w0.305: 144.25,194.15 U8.1
  TOP w0.508: R270.2 145.96,194.15 v2(144.96,194.15) 144.25,194.15
PWM2_BT_1: length 3
  TOP w0.508: C241.1 145.15,189.79 v2(145.81,190.46) 146.33,190.97 R270.1
PWM2_EN: length 2.8
  TOP w0.305: R177.2 143.65,196 v2(143.23,195.58) 142.72,195.07 U8.3
PWM2_HG: length 30.2
  TOP w0.305: U8.8 143.72,191.94 v6(144.4,191.26)
  TOP w0.635: v6(146.46,189.1) 147.27,189.1 148.62,190.45 148.62,196.19 143.64,201.17 134.49,201.17 R180.2
  BOTTOM w0.635: v6(146.46,189.1) v2(145.36,190.2) 144.4,191.16 v6(144.4,191.26)
PWM2_HG_1: length 11.4
  TOP w0.508: R181.2 131.55,200.7 R180.1
  TOP w0.635: R180.1 130.99,202.18 v6(130.33,201.52) Q13.4 ; Q16.4 124.05,201.52 v6(124.1,201.46)
  BOTTOM w0.635: v6(130.33,201.52) 127.01,201.52 v2(127,201.52) 124.16,201.52 v6(124.1,201.46)
PWM2_LG: length 18.1
  TOP w0.305: v6(141.63,191.26) 142.22,191.85 U8.5
  TOP w0.635: Q29.4 135.89,198.96 v6(135.89,199.9) ; Q15.4 136.98,190.45 v6(137.21,190.68)
  BOTTOM w0.635: v6(135.89,199.9) 135.99,199.8 v2(135.99,192.66) 135.99,191.9 v6(137.21,190.68) 141.05,190.68 v6(141.63,191.26)
PWM2_LX: length 34.2
  TOP w0.305: U8.7 143.22,190.79 143.21,190.77
  TOP w0.508: 132.66,197.64 132.66,200.44 R181.1
  TOP w0.635: L40.1 125.43,195.16 ; L40.1 123.83,196.76 ; L40.1 123.83,193.56 ; L40.1 122.23,195.16 ; 133.86,186.06 135,184.91 140.08,184.91 143.21,188.04 C241.2 143.21,190.77
  BOTTOM w0.254: G10.1 119.82,195.64 120.65,194.82 122.05,194.82
  BOTTOM w0.635: L40.1 125.43,195.16 ; L40.1 123.83,193.56 ; L40.1 122.23,195.16 ; L40.1 123.83,196.76
  vias: v2(122.35,199.26) v2(127.74,193.14) v2(133.73,198.93) v2(134.01,186.59) v6(119.13,199.9) v6(119.89,198.75) v6(121.03,197.74) v6(121.41,199.9) v6(121.92,196.34) v6(122.94,197.87) v6(123.83,199.52) v6(124.97,197.87) v6(124.97,193.42) v6(125.09,191.64) v6(125.48,199.9) v6(126.75,198.88) v6(126.75,197.23) v6(126.75,195.33) v6(126.75,193.55) v6(126.75,191.64) v6(126.75,189.99) v6(127.76,199.9) v6(128.78,191.77) v6(128.78,189.99) v6(128.78,188.09) v6(128.88,199.01) v6(128.88,197.49) v6(128.88,195.45) v6(128.91,193.55) v6(129.92,193.4) v6(129.92,192.25)
PWM2_SNB: length 2.9
  TOP w0.508: R196.2 v2(134.75,192.81) 135.46,192.81 C239.1
PWM2_VCC: length 4.7
  TOP w0.305: v2(141.81,195.45) 141.81,194.84 142.22,194.43 U8.4
  TOP w0.635: v2(141.81,195.45) 141.81,195.99 C180.2 142.37,196.6 141.63,197.33 R259.2
PWM3_BT: length 2.6
  TOP w0.305: U18.1 85.88,199.87 85.95,199.95
  TOP w0.508: R267.2 85.95,201.65 v2(85.95,200.43) 85.95,199.95
PWM3_BT_1: length 3.1
  TOP w0.508: C204.1 90.27,200.56 v2(89.49,201.34) 89,201.83 R267.1
PWM3_EN: length 2.8
  TOP w0.305: U18.3 84.93,198.3 84.54,198.69 v2(84.3,198.69) R203.1
PWM3_HG: length 25.6
  TOP w0.305: v6(88.87,199.9) 88.16,199.9 87.91,199.65 U18.8
  TOP w0.635: R195.2 109.09,199.77 v6(110.49,199.77)
  BOTTOM w0.635: v6(88.87,199.9) 88.87,200.38 89.28,200.79 v2(89.92,200.79) 109.47,200.79 v6(110.49,199.77)
PWM3_HG_1: length 11.5
  TOP w0.508: R195.1 107.11,198.46 R193.2
  TOP w0.635: Q26.4 98.47,199.17 v6(99.44,199.17) ; Q32.4 v6(105.79,199.17) 106.34,199.72 R195.1
  BOTTOM w0.635: v6(105.79,199.17) v2(102.49,199.17) v6(99.44,199.17)
PWM3_LG: length 20.7
  TOP w0.305: U18.5 88.1,197.8 88.4,197.51 v6(88.4,197.03)
  TOP w0.635: Q22.4 91.57,192.61 v6(91.19,192.23) ; v6(91.03,184.15) Q23.4
  BOTTOM w0.635: v6(88.4,197.03) 88.39,197.02 v2(88.39,194.69) 88.39,192.91 89.08,192.23 v6(91.19,192.23) 92.38,191.03 92.38,184.94 91.59,184.15 v6(91.03,184.15)
PWM3_LX: length 23.4
  TOP w0.305: U18.7 89.02,198.8
  TOP w0.508: 105.41,196.22 105.92,196.72 107.57,196.72 108.24,197.4 R193.1
  TOP w0.635: 103.2,193.06 L39.1 ; L39.1 101.6,194.67 ; L39.1 103.2,196.27 ; L39.1 104.8,194.67
  BOTTOM w0.254: L39.1 105.4,192.47 105.98,192.47 106.81,193.3 G8.1
  BOTTOM w0.635: L39.1 103.2,196.27 ; L39.1 103.2,193.06 ; L39.1 101.6,194.67 ; L39.1 104.8,194.67
  vias: v2(94.67,192.74) v2(94.69,184.4) v2(98.93,197.23) v2(100.33,189.99) v6(94.36,197.76) v6(95.38,197.76) v6(96.39,197.76) v6(97.41,197.76) v6(97.85,191.01) v6(97.85,189.87) v6(99.31,191.13) v6(99.32,188.98) v6(99.39,186.94) v6(99.39,185.04) v6(99.52,193.04) v6(99.78,196.67) v6(100.33,194.69) v6(100.97,186.94) v6(101.09,191.13) v6(101.09,188.98) v6(101.22,193.04) v6(101.98,196.98) v6(102.74,191.9) v6(103,190.25) v6(104.14,196.85) v6(104.52,191.64) v6(105.03,195.3)
PWM3_SNB: length 2.3
  TOP w0.508: C236.1 v2(93.52,190.37) 93.57,190.32 R245.2
PWM3_VCC: length 6.1
  TOP w0.305: U18.4 85.36,197.8 84.81,197.26
  TOP w0.635: 84.81,197.26 83.49,197.26 C177.2 81.79,197.46 R248.2 v2(81.64,195.83)
PWM_CSN4: length 4.4
  TOP w0.203: U52.21 180.7,161.06 181.23,160.53
  TOP w0.305: 181.23,160.53 v2(181.99,159.77) 182.12,159.64 R242.2
PWR_BTNJ_C: length 26.5
  TOP w0.102: v1(18.64,17.04) 17.68,16.08 17.24,16.08 17.02,15.86 17.02,15.65 15.68,14.31 15.1,14.31 14.7,13.92 12.52,13.92 12.5,13.94 11.28,13.94 9.65,12.31 8.91,12.31 8.33,12.89 8.33,14.13 LEDH1.6 ; R632.2 R625.2 26.8,16.61 26.26,17.14 25.11,17.14 24.27,17.98 22.99,17.98 v1(22.58,17.58)
  BOTTOM w0.102: v1(22.58,17.58) 20.84,17.58 20.23,16.97 18.72,16.97 v1(18.64,17.04)
PWR_DEBUG: length 68.6
  TOP w0.102: v1(178.8,119.11) R794.1 180.67,119.11 R159.2 180.72,119.07 R806.2 ; U27.N40 134.43,155.83 134.61,155.65 152.26,155.65 171,136.91 171,135.43 173.38,133.05 173.38,130.68 173.24,130.54 v1(173.24,130.32)
  BOTTOM w0.102: v1(173.24,130.32) 174.85,128.71 174.85,125.37 v2(175.7,124.53) 178.31,121.92 178.31,119.61 v1(178.8,119.11)
PWR_LED_G: length 13.6
  TOP w0.254: Q59.C 16.13,13.88 15.27,13.88 14.32,12.93 R644.2 13.55,13.4 C479.1 12.61,13.49 12.35,13.49 12.32,13.51 11.46,13.51 9.83,11.88 8.04,11.88 LEDH1.4
PWR_LED_Y: length 14.4
  TOP w0.254: Q71.C 17.27,11.37 17.27,10.61 16.63,9.97 14.41,9.97 14.02,10.36 R734.2 13.45,11.49 C496.1 12.39,11.49 12.22,11.33 11.26,11.33 11,11.07 11,11.03 9.66,9.7 8.88,9.7 7.92,10.65 LEDH1.2
PWR_LEDJ2: length 6.9
  TOP w0.102: Q59.B 20.02,14.54 21.01,15.52 Q60.C 23.7,15.52 v1(23.77,15.59) 24.52,16.33 25.67,16.33 R670.2
PWR_LEDJ3: length 2.8
  TOP w0.102: v4(24.96,14.68) R672.1 24.3,13.72 Q60.B
PWRBTN_N: length 86.1
  TOP w0.102: v1(102.87,11.56) 103.23,11.2 U61.33 ; R632.1 27.98,15.56 29.21,14.33 30.95,14.33 C472.1 31.79,14.61 39.53,14.61 49.67,4.47 62.59,4.47 69.27,11.15 v1(69.72,11.15)
  BOTTOM w0.102: v1(102.87,11.56) 102.72,11.7 101.79,11.7 101.16,11.07 97.76,11.07 97.3,11.53 95.51,11.53 94.96,12.08 92.31,12.08 92.11,11.87 91.21,11.87 90.4,12.69 88.27,12.69 87.97,12.38 85.92,12.38 85.23,11.68 80.37,11.68 v2(80.24,11.56) 79.83,11.15 v1(69.72,11.15)
PWRGD_3V: length 361.2
  TOP w0.102: R2230.1 72.93,146.29 70.81,144.17 70.81,135.2 50.67,115.06 50.67,108.71 49.43,107.47 49.43,83.81 53.26,79.98 53.26,77.83 55.98,75.12 55.98,61.37 62.59,54.76 78.89,54.76 v1(79.65,55.52) ; v1(9.41,29.49) 10.79,28.11 10.79,26.46 11.89,25.37 11.89,23.04 12.24,22.68 15.98,22.68 v1(17.27,21.39) ; v1(87.78,33.44) 87.78,33.99 86.56,35.21 86.56,43.36 v1(85.85,44.07) ; 104.52,2.92 105.44,2.01 116.36,2.01 117.86,3.51 117.86,12.54 116.43,13.97 116.43,22.88 112.42,26.9 v1(112.42,31.27) ; 104.52,2.92 103.61,2.01 94.51,2.01 v1(93.57,2.95) ; 104.52,2.92 R866.2 ; U29.AT40 26.59,36.68 26.59,35.89 26.62,35.86 26.62,35.51 26.37,35.26 25.75,35.26 v3(25.66,35.36) ; v1(26.21,23.65) 26.21,22.1 26.06,21.95 26.06,20.9 26.2,20.76 R581.1 R810.1 27.69,20.61 27.69,20.33 30.82,17.2 32.55,17.2 33.11,16.64 40.37,16.64 50.44,6.57 51.19,6.57 v1(51.26,6.5)
  BOTTOM w0.102: v1(93.57,2.95) 93.52,2.9 80.3,2.9 80.08,3.12 56.07,3.12 55.5,3.68 54.08,3.68 v1(51.26,6.5) ; v1(79.65,55.52) 79.65,45.83 80.14,45.34 v2(80.14,45.34) 80.14,45.34 81.41,44.07 v1(85.85,44.07) ; v1(112.42,31.27) 111.25,32.44 99.64,32.44 DB1.1 95.4,32.92 88.3,32.92 v1(87.78,33.44) ; v1(17.27,21.39) 21.03,21.39 23.3,23.65 v1(26.21,23.65) ; v3(25.66,35.36) 25.45,35.15 16.18,35.15 15.75,34.72 12.89,34.72 10.21,32.04 10.21,30.6 9.41,29.81 v1(9.41,29.49)
PWRGD_3V_B_1: length 4.3
  TOP w0.102: Q80.D 112.47,6.85 R696.2 111.38,5.74 v2(111.3,5.66) 111.13,5.49 Q79.B
PWROK3: length 17
  TOP w0.102: U61.36 104.95,12.4 107.8,9.55 107.8,9.55 108.11,9.23 108.11,9.23 108.46,8.89 109.41,8.89 R754.1 109.54,8.57 109.25,8.28 108.43,8.28 108.01,7.86 Q79.C 107.71,6.17 C516.1 ; C516.1 106.49,5.09 106.12,4.72 v2(105.92,4.72) 105.49,4.72 105.13,5.08 105.13,5.74 104.84,6.03 R866.1 ; C516.1 R755.1
Q37_2: length 2.5
  TOP w0.102: R256.2 165.99,163.07 v2(165.85,162.93) 165.52,162.6 Q37.2
Q37_5: length 2.9
  TOP w0.102: Q37.5 165.52,160.37 165.68,160.53 v1(166.83,160.53) 166.88,160.53 167.07,160.72 R254.2
Q37_6: length 4.5
  TOP w0.102: R255.2 165.1,157.61 v2(165.74,158.24) 166.17,158.68 Q37.6 167.52,159.71 R254.1
Q44_PIN2: length 3.9
  TOP w0.102: Q44.B 7.45,185.52 C191.1 6.92,186.06 v2(5.84,186.06) 5.84,185.1 R525.2
Q46_PIN2: length 4
  TOP w0.102: Q67.2 69.93,71.04 68.9,72.07 v2(68.07,72.07) R788.2
Q46_PIN3: length 8.8
  TOP w0.102: Q67.3 68.27,70.36 v2(68.01,70.1) R183.2 66.61,69.85 64.44,69.85 63.62,70.67 Q78.G 63.2,70.64 Q77.G
Q46_PIN6: length 3.5
  TOP w0.102: Q67.6 70.58,67.97 70.38,67.77 69.37,67.77 69.28,67.85 Q67.4 68.72,68.48 68.45,68.75 v1(68.45,68.75)
Q48_PIN2: length 5.4
  TOP w0.102: v2(8.48,177.16) 8.48,178.79 8.79,179.1 Q48.2 10.29,179.1 10.55,178.83 R24.2 R25.1
Q48_PIN5: length 6
  TOP w0.102: v2(5.92,179.98) 5.92,179.06 5.97,179.01 ; 5.97,179.01 6.53,178.45 Q48.6 7.36,178.41 RN22.3 ; 5.97,179.01 6.06,179.1 Q48.5
Q51_D: length 3.6
  TOP w0.102: R2233.2 161.86,158.41 v2(162.03,158.57) 162.38,158.93 162.38,160.32 Q56.D
Q54_B: length 4
  TOP w0.102: Q57.B 106.95,33.83 C252.1 107.57,33.85 R312.2 108.52,34.79 v2(108.69,34.95)
Q54_C: length 3
  TOP w0.102: v2(101.47,36.42) 101.84,36.06 R311.1 103.02,35.68 Q57.C
Q62_PIN2: length 3.5
  TOP w0.165: v1(12.8,18.54) 11.68,17.42 R2234.2 12.36,16.54 Q62.2
Q62_PIN6: length 6.6
  TOP w0.165: 16,16.26 16,16.76 15.58,17.19 Q62.6 ; 16,16.26 15.72,16.54 Q62.5 ; 16,16.26 16.23,16.03 v2(16.23,15.62) 15.31,14.7 14.93,14.7 14.71,14.48 R2235.2
Q69_GATE: length 10.9
  TOP w0.102: 137.45,44.2 137.45,44.46 137.92,44.93 137.92,45.85 ; 137.45,44.2 139.89,44.2 R773.2 ; 137.45,44.2 Q73.3 136.83,43.26 136.51,43.57 v2(135.89,43.57) 135.05,42.74 C505.1 ; 137.92,45.85 Q69.2 ; 137.92,45.85 Q69.5
Q73_GATE: length 6.5
  TOP w0.102: Q73.6 138.75,40.68 138.61,40.54 138.17,40.54 138.1,40.61 Q73.5 138.1,41.81 137.77,42.14 136.36,42.14 v2(135.89,41.67) 135.2,41.67 135.15,41.72 R776.2
QF2_1: length 4
  TOP w0.102: R707.2 50.48,17.18 50.7,16.97 v2(51.13,16.97) 51.48,16.97 51.69,17.17 51.69,18.14 52.08,18.54 QF2.2
QF2_2: length 5.1
  TOP w0.102: 53.59,18.53 v2(53.59,16.48) 53.86,16.22 R616.2 ; 53.59,18.53 53.6,18.54 QF2.5 ; 53.59,18.53 53.59,19.05 53.74,19.19 QF2.6
REAR_USB3_RX0+: length 14.2
  TOP w0.102: v1(129.67,223.27) 129.34,223.6 129.11,223.6 128.4,222.88 128.4,221.64 U15.9 U15.2 128.51,220 128.36,219.86 128.36,219.65 128.02,219.31 128.02,219.2 128.19,219.03 L22.3
  BOTTOM w0.102: 130.89,224.46 130.89,226.85 129.69,228.05 129.69,228.56 129.79,228.66 USB3R1.15 ; 130.89,224.46 130.89,224.08 130.43,223.62 130.02,223.62 v1(129.67,223.27) ; 130.89,224.46 v2(131.21,224.46)
REAR_USB3_RX0-: length 14.2
  TOP w0.102: v1(129.67,224.14) 129.34,223.81 129.02,223.81 128.18,222.97 128.18,221.71 U15.10 U15.1 128.01,220 128.15,219.86 128.15,219.74 127.81,219.4 127.81,219.2 127.64,219.03 L22.4
  BOTTOM w0.102: v2(130.35,225.45) 130.67,225.45 ; 130.67,225.45 130.67,226.76 129.47,227.96 129.47,228.56 129.37,228.66 USB3R1.14 ; 130.67,225.45 130.67,224.17 130.34,223.84 129.97,223.84 v1(129.67,224.14)
REAR_USB3_RX1+: length 23.2
  TOP w0.102: USB3R1.6 129.79,231.86 129.69,231.76 129.69,230.97 131.57,229.08 131.57,228.09 130.01,226.53 129.1,226.53 123.79,221.22 ; 123.79,221.22 v2(124.01,220.99) ; 123.79,221.22 123.37,220.8 123.37,219.68 123.5,219.55 U10.9 U10.2 123.5,218.04 123.38,217.92 123.38,217.56 123.05,217.23 122.36,217.23 121.82,216.69 121.82,216.43 121.99,216.26 L19.3
REAR_USB3_RX1-: length 23.2
  TOP w0.102: 124.7,222.44 v2(124.48,222.66) ; 124.7,222.44 129.01,226.75 129.92,226.75 131.36,228.18 131.36,228.99 129.47,230.88 129.47,231.76 129.37,231.86 USB3R1.5 ; 124.7,222.44 123.15,220.89 123.15,219.67 123,219.52 U10.10 U10.1 123,218.09 123.16,217.93 123.16,217.65 122.96,217.45 122.27,217.45 121.61,216.78 121.61,216.43 121.44,216.26 L19.4
REAR_USB3_TX0+: length 13.9
  TOP w0.102: 131.65,224.03 130.01,222.39 U15.6 U15.5 130.01,220 129.86,219.86 129.86,219.76 130.08,219.54 130.08,219.2 130.25,219.03 L24.3 ; 131.65,224.03 v2(131.88,223.8) ; 131.65,224.03 135.64,228.02 135.64,228.58 135.72,228.66 USB3R1.18
REAR_USB3_TX0-: length 13.9
  TOP w0.102: USB3R1.17 135.3,228.66 135.42,228.54 135.42,228.11 132.57,225.26 ; 132.57,225.26 129.51,222.19 U15.7 U15.4 129.51,220 129.65,219.86 129.65,219.67 129.86,219.45 129.86,219.2 129.7,219.03 L24.4 ; 132.57,225.26 v2(132.33,225.5)
REAR_USB3_TX1+: length 23.5
  TOP w0.102: 125.55,221.23 124.85,220.53 124.85,219.68 125,219.54 U10.6 U10.5 125,217.77 124.86,217.62 124.86,217.27 124.19,216.59 124.19,216.35 124.35,216.18 L18.3 ; 125.55,221.23 127.43,223.11 127.43,223.57 129.36,225.5 131.52,225.5 133.68,227.66 133.68,228.85 135.71,230.89 135.71,231.72 135.85,231.86 USB3R1.9 ; 125.55,221.23 v2(125.8,220.98)
REAR_USB3_TX1-: length 23.5
  TOP w0.102: 126.49,222.48 v2(126.26,222.71) ; 126.49,222.48 124.64,220.62 124.64,219.68 124.5,219.55 U10.7 U10.4 124.5,217.77 124.64,217.62 124.64,217.35 123.97,216.68 123.97,216.36 123.8,216.19 L18.4 ; 126.49,222.48 127.22,223.2 127.22,223.66 129.27,225.72 131.43,225.72 133.46,227.75 133.46,228.94 135.5,230.98 135.5,231.67 135.31,231.86 USB3R1.8
RED_CRT: length 12.5
  TOP w0.102: L6.2 72.26,229.68 C14.1 72.33,231.53 73.91,233.11 U1.4 76.63,236.79 VGA1.1
RI1#: length 5.2
  TOP w0.102: U61.63 97.27,19.31 v2(95,21.59) 94.67,21.92 R669.2
ROSC: length 5.7
  TOP w0.203: 175.29,158.57 175.68,158.97 U52.9
  TOP w0.305: 175.29,158.57 172.56,155.85 v2(172.56,155.76) 172.57,155.75 R219.1
RSMRST*: length 6
  TOP w0.102: U61.43 106.34,15.2 v2(106.93,14.61) 107.82,13.72 R733.1
RSMRST*_R: length 5.1
  TOP w0.102: Q80.G 115.25,5.49 115.57,5.82 115.57,8.38 v2(115.32,8.64) 115.13,8.83 R865.2
RSMRST_SIO_N: length 124.9
  TOP w0.102: R757.1 112.39,15.88 112.6,16.08 112.6,19.76 v1(112.52,19.84) ; R757.1 112.33,13.72 R733.2 ; R757.1 R668.1 114.24,12.83 114.24,9.78 R865.1 ; U29.AM40 28.27,36.68 28.52,36.44 28.52,34.41 26.82,32.72 26.49,32.72 25.65,31.88 25.65,30.5 25.35,30.19 25.35,28.64 25.7,28.29 25.7,27.85 25.65,27.8 25.65,25.47 25.76,25.37 25.76,22.88 25.04,22.17 25.04,20.55 25.83,19.76 v1(26.67,19.76)
  BOTTOM w0.102: v1(112.52,19.84) 111.81,20.55 v2(110.9,20.55) 108.86,20.55 108.23,21.18 104.2,21.18 103.8,21.59 81.5,21.59 81.24,21.86 80.67,22.42 80.46,22.63 65.28,22.63 61.55,18.9 57.78,18.9 57.09,19.58 53.98,19.58 53.42,19.02 44.34,19.02 42.31,21.05 35.51,21.05 35.25,21.3 29.92,21.3 29,20.38 27.29,20.38 v1(26.67,19.76)
RST1#: length 9.7
  TOP w0.102: U61.57 99.67,19.43 99.23,19.87 v2(99.23,20.08) 99.23,21.89 99.8,22.45 100.51,22.45 100.81,22.76 100.81,24.47 R658.1 R657.1
RTL_ISOLATE: length 5.5
  TOP w0.102: R19.1 184.42,220.03 v2(184.15,219.76) 183.68,219.29 R21.2 184.65,218.47 C76.1 184.72,217.67 184.53,217.47 Q64.2
RTL_ISOLATE_N: length 72.9
  TOP w0.102: v1(185.5,204.6) 186.11,205.21 186.11,215.24 185.57,215.77 184.02,215.77 183.88,215.92 Q64.3 ; v1(159.64,212.15) R144.1 161.63,212.12 R145.2 162.24,210.46 164.6,210.46 165.53,210.46 166.04,209.96 166.04,208.3 167.41,206.93 U12.20
  BOTTOM w0.102: v1(185.5,204.6) 183.31,202.41 183.31,201.24 182.34,200.28 177.83,200.28 177.06,199.52 157.58,199.52 154.55,202.55 154.55,207.04 v2(158.4,210.89) 159.58,212.06 159.58,212.09 v1(159.64,212.15)
RTL_ISOLATE_R: length 4.2
  TOP w0.102: Q64.5 184.53,214.48 184.02,213.97 v5(184.02,213.54) 184.14,213.42 185.22,213.42 R134.1 185.18,213.51 Q64.6
SATA1GP: length 8.5
  TOP w0.102: R538.1 R619.1 44.7,32.66 v2(44.48,32.89) 44.02,32.89 43.94,32.82 43.09,32.82 40.97,34.94 40.97,35.32 40.97,35.33 40.4,35.9 40.4,36.66 U29.J40
SATA2GP: length 11.3
  TOP w0.102: U29.H40 41.09,36.64 40.81,36.36 40.81,36.07 41.01,35.87 41.13,35.87 41.55,35.44 41.55,35.02 43.26,33.32 43.66,33.32 44.25,33.91 46.02,33.91 46.69,33.25 v2(46.69,32.87) 46.69,31.99 R597.2 R577.2
SATA3GP: length 21.3
  TOP w0.102: U29.N41 38.47,34.88 40.74,32.61 41.1,32.61 41.91,31.8 42.39,31.8 43.1,31.09 43.1,30.77 43.42,30.45 43.74,30.45 44.39,29.8 44.39,29.35 v5(45.24,28.5) 46.51,27.23 47.24,27.23 47.55,26.92 47.55,26.37 47.77,26.14 48.09,26.14 48.25,25.98 48.25,25.91 48.75,25.41 48.75,24.43 48.98,24.2 50.88,24.2 R620.1 51.35,24.66 R598.2
SATA_LED_OUT: length 5.5
  TOP w0.165: Q62.3 12.27,15.89 R2236.2 10.48,15.3 9.27,14.1 LEDH1.3
SATA_RXN0_C: length 5.6
  TOP w0.102: C363.1 101.17,71.16 101.17,74.34 SATA0.5
  BOTTOM w0.102: SATA0.5 100.56,74.75 100.08,74.27 v2(100.08,74.17)
SATA_RXN1_C: length 11.2
  TOP w0.102: SATA1.3 82.03,74.2 82.03,73.44 77.41,68.82 76.15,68.82 C359.1
  BOTTOM w0.102: v2(80.82,74.14) 80.82,74.3 81.27,74.74 SATA1.3
SATA_RXP0_C: length 5.5
  TOP w0.102: SATA0.6 101.39,74.53 101.39,71.11 C364.1
  BOTTOM w0.102: SATA0.6 101.83,74.73 102.31,74.24 v2(102.31,74.17)
SATA_RXP1_C: length 11.3
  TOP w0.102: SATA1.2 82.25,74.67 82.25,73.35 77.5,68.61 76.03,68.61 C360.1
  BOTTOM w0.102: v2(82.98,74.14) 82.98,74.27 82.54,74.71 SATA1.2
SATA_TXN0_C: length 5.5
  TOP w0.102: C362.1 97.53,71.14 97.53,74.47 SATA0.3
  BOTTOM w0.102: v2(98.5,74.17) 98.5,74.27 98.02,74.76 SATA0.3
SATA_TXN1_C: length 7.5
  TOP w0.102: C358.1 76.03,70.38 76.76,70.38 78.43,72.06 78.43,74.66 SATA1.5
  BOTTOM w0.102: SATA1.5 78.73,74.69 79.17,74.24 v2(79.17,74.14)
SATA_TXP0_C: length 5.5
  TOP w0.102: SATA0.2 97.31,74.39 97.31,71.14 C361.1
  BOTTOM w0.102: v2(96.27,74.17) 96.27,74.27 96.75,74.75 SATA0.2
SATA_TXP1_C: length 7.4
  TOP w0.102: C357.1 76.15,70.6 76.67,70.6 78.22,72.15 78.22,74.2 SATA1.6
  BOTTOM w0.102: SATA1.6 77.46,74.72 77.01,74.27 v2(77.01,74.14)
SATAHDR_RX_DN0: length 83
  TOP w0.102: U29.B28 44.62,43.15 44.9,43.43 47.15,43.43 48.88,41.69 48.88,41.19 v3(49.07,41) ; C363.2 101.22,69.51 101.22,69.29 100.23,68.3 89.06,68.3 78.7,57.94 73.81,57.94 73.3,58.45 72.65,58.45 v1(72.39,58.7)
  BOTTOM w0.102: 72.78,50.37 v2(72.44,50.37) ; 72.78,50.37 72.78,52.9 71.08,54.6 71.08,58.15 71.39,58.46 72.15,58.46 v1(72.39,58.7) ; 72.78,50.37 72.78,45.09 70.54,42.85 65.39,42.85 62.37,39.83 51.33,39.83 50.44,40.72 49.35,40.72 v3(49.07,41)
SATAHDR_RX_DN1: length 57.6
  TOP w0.102: C359.2 74.53,68.88 74.21,68.88 73.89,68.56 73.89,66.52 72.96,65.6 72.25,65.6 72.1,65.75 72.1,65.89 v1(72.35,66.14) ; v1(46.71,41.07) 46.55,41.24 46.55,41.82 45.75,42.62 45.4,42.62 arc(45.06,42.84) 44.65,42.92 44.53,42.92 44.53,42.92 arc(44.42,42.91) 44.31,42.87 arc(44.2,42.82) 44.07,42.81 43.99,42.81 arc(43.48,42.72) U29.D30
  BOTTOM w0.102: v1(72.35,66.14) 72.12,65.91 72.12,64.85 ; 72.12,64.85 72.12,63.28 68.17,59.33 68.17,46.49 62.12,40.44 51.51,40.44 50.27,41.68 46.89,41.68 46.71,41.5 v1(46.71,41.07) ; 72.12,64.85 v2(72.44,64.85)
SATAHDR_RX_DP0: length 83
  TOP w0.102: v1(72.46,57.84) 72.85,58.23 73.21,58.23 73.72,57.72 78.79,57.72 89.15,68.08 100.32,68.08 101.43,69.2 101.43,69.65 C364.2 ; U29.A28 45.14,43.21 47.06,43.21 48.67,41.61 48.67,41.22 v3(48.41,40.97)
  BOTTOM w0.102: 72.23,53.76 71.3,54.69 71.3,58.06 71.48,58.24 72.34,58.24 72.46,58.12 v1(72.46,57.84) ; 72.23,53.76 73,52.99 73,45 70.63,42.63 65.48,42.63 62.46,39.61 51.24,39.61 50.35,40.5 48.98,40.5 48.51,40.97 v3(48.41,40.97) ; 72.23,53.76 v2(72.49,54.03)
SATAHDR_RX_DP1: length 57.5
  TOP w0.102: C360.2 74.53,68.66 74.3,68.66 74.1,68.47 74.1,66.43 73.05,65.38 72.16,65.38 71.88,65.66 71.88,66.04 71.76,66.16 v1(71.49,66.16) ; v1(45.99,41.09) 46.33,41.43 46.33,41.73 45.66,42.4 45.3,42.4 arc(45.01,42.63) 44.65,42.71 44.53,42.71 arc(44.47,42.7) 44.41,42.68 arc(44.25,42.61) 44.07,42.59 43.99,42.59 arc(43.85,42.56) U29.C30
  BOTTOM w0.102: 69.14,60.6 67.96,59.42 67.96,46.58 62.03,40.65 51.6,40.65 50.36,41.9 46.8,41.9 v1(45.99,41.09) ; 69.14,60.6 71.91,63.37 71.91,65.94 71.68,66.16 v1(71.49,66.16) ; 69.14,60.6 v2(68.91,60.83)
SATAHDR_TX_DN0: length 84.8
  TOP w0.102: v1(42.47,42.57) 42.37,42.57 42.08,42.28 U29.F31 ; v1(73.02,59.63) 73.35,59.96 74.49,59.96 75.58,58.86 78.76,58.86 88.82,68.92 97.24,68.92 97.53,69.21 97.53,69.58 C362.2
  BOTTOM w0.102: v1(73.02,59.63) 73.02,59.89 73.2,60.07 73.48,60.07 73.63,59.92 73.63,57.23 ; 73.63,57.23 v2(73.31,57.23) ; 73.63,57.23 73.63,44.75 70.9,42.02 65.74,42.02 62.71,39 50.97,39 50.33,39.64 48.86,39.64 47.62,38.4 45.31,38.4 42.61,41.11 42.61,41.47 42.11,41.96 42.11,42.47 42.21,42.57 v1(42.47,42.57)
SATAHDR_TX_DN1: length 63.3
  TOP w0.102: v1(46.19,39.3) 46.41,39.52 46.41,39.73 46.16,39.98 44.67,39.98 U29.B34 ; v1(68.94,67.08) 69.16,67.08 69.48,66.76 69.48,66.53 69.82,66.19 70.59,66.19 72,67.6 72.68,67.6 73.28,68.2 73.28,69.77 74.05,70.54 74.43,70.54 C358.2
  BOTTOM w0.102: v1(68.94,67.08) 69.27,67.08 69.39,66.95 69.39,65.25 69.28,65.14 69.28,62.48 66.6,59.79 ; 66.6,59.79 v2(66.37,60.02) ; 66.6,59.79 66.21,59.4 66.21,46 61.69,41.48 51.87,41.48 50.94,42.41 45.17,42.41 44.41,41.64 44.41,40.99 45.25,40.14 46.27,40.14 46.55,39.87 46.55,39.66 v1(46.19,39.3)
SATAHDR_TX_DP0: length 84.8
  TOP w0.102: v1(73.02,60.5) 73.35,60.17 74.58,60.17 75.18,59.58 75.67,59.08 78.67,59.08 88.73,69.14 97.16,69.14 97.31,69.3 97.31,69.58 C361.2 ; U29.H31 41.32,42.1 v1(41.66,42.44)
  BOTTOM w0.102: v2(71.7,42.01) 71.45,42.27 ; 71.45,42.27 73.85,44.66 73.85,60.01 73.57,60.29 73.23,60.29 v1(73.02,60.5) ; 71.45,42.27 70.99,41.81 65.83,41.81 62.8,38.79 50.88,38.79 50.24,39.42 48.95,39.42 47.71,38.19 45.22,38.19 42.39,41.02 42.39,41.38 41.9,41.87 41.9,42.19 v1(41.66,42.44)
SATAHDR_TX_DP1: length 63.3
  TOP w0.102: C357.2 74.63,70.76 73.96,70.76 73.06,69.86 73.06,68.29 72.59,67.82 71.91,67.82 70.5,66.41 69.91,66.41 69.7,66.62 69.7,66.85 v1(69.88,67.03) ; v1(46.93,39.36) 46.62,39.67 46.62,39.82 46.25,40.2 44.46,40.2 44.19,39.93 U29.C34
  BOTTOM w0.102: 69.5,63.88 69.5,62.39 66.42,59.31 66.42,45.91 61.78,41.26 51.78,41.26 50.85,42.19 45.26,42.19 44.62,41.55 44.62,41.08 45.34,40.36 46.36,40.36 46.76,39.96 46.76,39.53 v1(46.93,39.36) ; 69.5,63.88 v2(69.82,63.88) ; 69.5,63.88 69.5,65.05 69.61,65.16 69.61,66.76 v1(69.88,67.03)
SATARBIAS_PCH: length 8.7
  TOP w0.102: v2(48.64,39.04) 48.88,38.8 R576.1 45.84,37.85 44.44,39.26 44.44,39.52 44.26,39.69 44,39.69 43.93,39.62 43.61,39.62 43.43,39.8 43.43,40.26 U29.D33
SB3V: length 614.8
  TOP w0.254: v1(29.36,28.73) 29.26,28.83 29.26,30.9 R508.2 ; C526.1 20.08,45.42 20.88,45.42 21.68,44.62 24.33,44.62 U29.AW26 ; U29.AK20 29.63,47.87 v3(29.63,47.96) 29.64,47.95 29.97,47.62 U29.AJ20 ; U29.AM33 U29.AN33 27.51,40.52 27.51,40.25 27.51,40.24 27.51,39.8 U29.AP35 ; R676.2 34.92,26.99 v1(34.92,26.29) 34.92,25.59 R573.2
  TOP w0.305: U29.P20 38.3,48.02 v3(38.32,48.02) ; R183.1 67.88,68.39 v1(68.45,67.81) ; U29.AH18 30.68,48.29 v3(30.35,47.96) 30.36,47.95 30.36,47.95 30.68,47.62 U29.AH20 ; U29.AP35 27.19,39.48 27.19,39.21 27.16,39.18 v3(27.16,39.16) ; v3(31.17,46.04) 31.17,46.07 U29.AH22 ; R255.1 163.77,157.95 v1(163.27,158.45) ; R565.2 v1(37.47,26.8)
  TOP w0.356: RN36.3 30.46,29.89 30.66,29.69 v1(30.78,29.69) 30.91,29.69 31.11,29.89 RN36.4
  TOP w0.381: v1(8.64,53.47) 8.64,53.94 7.87,54.7 7.87,54.93 R847.1 ; v1(112.78,11.43) 112.78,12.38 R757.2 112.2,12.95 110.68,12.95 R756.2 ; R594.2 v1(33.4,30.3) ; v1(32.48,30.3) 32.48,30.39 32.38,30.48 R621.2
  TOP w0.508: R419.1 194.16,119.25 ; v1(75.31,14.33) 75.31,17.93 78.85,21.46 80.64,21.46 83.54,24.35 v1(83.57,24.35) ; R768.1 135.64,46.61 v1(135.74,46.71) ; R730.1 139.38,48.74 v1(139.41,48.77) ; v1(138.13,9.55) 136.8,10.87 136.8,23.75 132.36,28.19 132.36,39.01 v1(132.94,39.6) 134.18,40.83 R776.1 ; v1(8.64,53.47) R456.1 R636.2 ; v1(178.69,147.74) 180.78,145.64 183.49,145.64 187.45,149.61 194.16,149.61 ; R405.1 v1(37.72,23.65) ; v1(76.96,30.63) 77.09,30.76 77.09,41.91 v1(77.6,42.42) ; 183.74,112.88 183.71,112.92 R400.1 R399.1 ; R369.1 3.96,104.98 3.48,104.5 3.48,100.03 4.13,99.38 R368.1 4.6,98.76 v1(4.22,98.37) ; v1(56.62,14.4) 56.62,14.48 56.63,14.49 R811.1 ; R134.2 185.24,212.01 v1(185.55,211.71) ; v1(112.07,8.37) 112.02,8.37 R696.1 ; v1(107.44,7.87) 107.44,8.64 106.87,9.21 R556.2 ; R82.1 188.44,215.77 v1(187.78,215.11) ; R574.2 19.14,27.73 v6(18.58,27.17) 18.12,27.62 R698.1 R536.2 19.14,29.39 R72.1 ; R616.1 54.48,15.25 v1(54.48,14.4) ; R817.1 v1(60.92,14.4) ; v1(68.02,14.43) 68.02,14.78 70.95,17.71 70.95,23.59 68.05,26.49 v1(68.05,28.55) 68.03,28.56 R607.1 ; v1(20.7,44.79) 20.66,44.84 20.38,44.84 C526.1 ; R795.2 174.79,147.94 v1(174.99,147.74) ; R766.1 v1(58.79,14.4) ; v1(64.06,14.4) 64.06,14.55 64.08,14.58 R765.1 ; v1(95.12,25.04) 94.67,24.59 R669.1 ; R570.2 92.77,14.35 93.73,14.35 v1(94.23,13.84) ; v1(99.67,7.11) 99.67,6.78 99.25,6.36 R680.1 ; v1(97.71,25.27) R484.2 ; v1(102.67,26.38) R526.2 R535.2 ; v1(30.72,18.09) 28.24,20.56 28.24,21.16 27.76,21.65 R810.2 27.23,21.96 27.23,24.38 27.76,24.91 v1(27.76,25.02) ; v1(9.52,33.88) 10.06,33.88 10.41,33.53 C412.1
  TOP w0.762: v6(11.73,26.59) 14.81,26.59 v6(15.54,25.86)
  TOP w1.27: MECLR1.3 2.41,72.53 2.41,94.08 v1(5.69,97.36) 9.42,101.09 9.42,103.35 ; v6(176.78,48.64) 177.71,48.64 179.01,49.94 179.01,53.12 178.89,53.24 178.89,57.02 178.38,57.53 178.38,62.53 182.1,66.26 182.1,73.7 184.98,76.58 184.98,101.66 182.45,104.19 182.45,111.58 183.74,112.88 189.12,112.88 194.16,117.92 194.16,149.61 197.51,152.96 197.51,186.55 197.74,186.78 197.74,201.04 193.78,205 v6(193.29,205)
  BOTTOM w0.178: v3(38.32,48.02) 38.17,47.87 38.17,46.56 37.87,46.25 37.87,44.42 36.78,43.33 36.09,43.33 35.56,43.87 33.68,43.87 32.48,45.06 32.16,45.06 v3(31.17,46.04)
  BOTTOM w0.305: v1(19.15,36.7) 19.15,36.91 19.55,37.3 20.11,37.3 21.04,38.23 25.01,38.23 25.57,38.79 26.79,38.79 v3(27.16,39.16) ; v1(163.27,158.45) v2(163.27,156.06) 163.27,155.71 171.24,147.74 v1(174.99,147.74) ; v1(34.92,26.29) 35.2,26.29 35.71,26.8 v1(37.47,26.8) 36.98,26.31 36.98,24.59 37.72,23.85 v1(37.72,23.65)
  BOTTOM w0.381: v1(68.45,67.81) 68.61,67.97 70.92,67.97 71.2,67.69 72.44,67.69 v2(73.94,66.19) 74.61,65.52 74.61,44.73 76.92,42.42 v1(77.6,42.42) ; v1(16.92,46.99) 16.92,47.32 17.51,47.92 22.25,47.92 22.8,47.37 26.4,47.37 29.11,47.37 29.49,47.75 29.49,47.81 v3(29.63,47.96) 29.64,47.96 v3(30.35,47.96) 31.17,47.13 v3(31.17,46.04)
  BOTTOM w0.508: v1(33.4,30.3) v1(32.48,30.3) 31.39,30.3 v1(30.78,29.69) 30.33,29.69 v1(29.36,28.73) v2(28.4,27.76) 27.76,27.13 v1(27.76,25.02) 28.42,25.68 31.47,25.68 32.08,26.29 v1(34.92,26.29) ; v1(68.05,28.55) 68.83,28.55 69.95,29.67 v2(72.34,29.67) 76,29.67 v1(76.96,30.63) ; v1(83.57,24.35) 83.59,24.33 94.41,24.33 v1(95.12,25.04) 95.35,25.27 v1(97.71,25.27) 98.17,25.73 102.02,25.73 v1(102.67,26.38) ; v6(7.52,47.69) v6(7.52,48.72) 7.52,49.07 v2(8.03,49.59) 8.64,50.19 8.64,53.47 v1(8.64,53.47) ; v1(139.41,48.77) 138.62,48.77 136.56,46.71 v1(135.74,46.71) 135.74,43.54 134.57,42.37 v2(134.57,42.27) 134.57,41.22 v1(132.94,39.6) ; v1(178.69,147.74) v1(174.99,147.74) ; v1(4.22,98.37) 4.67,98.37 v1(5.69,97.36)
  BOTTOM w0.762: v6(15.54,25.86) 17.35,25.86 18.58,27.09 v6(18.58,27.17)
  BOTTOM w1.27: MECLR1.3 4.6,68.86 4.6,65.86 5.49,64.97 5.49,63.59 5.05,63.15 5.05,53.58 5.5,53.14 v6(5.5,52.83) v6(5.5,51.69) ; v6(167.13,20.76) 167.13,26.8 167.56,27.23 167.56,32.31 176.78,41.53 v2(176.78,46.58) v6(176.78,48.64)
  vias: v1(13.34,31.7) v2(166.52,11.58) v6(165.28,9.91) v6(165.48,20.83) v6(166.12,19.56) v6(166.55,9.91) v6(167.69,9.91) v6(192.15,204.98) v6(194.79,223.95) v6(194.79,222.88)
SB5V: length 452.9
  TOP w0.508: R606.1 74.78,29.48 v1(74.78,28.42) ; v1(105.23,43.76) 103.71,42.24 v1(103.71,39.34) ; v1(118.21,2.21) 118.41,2.41 118.41,12.78 117.02,14.17 v2(117.02,16) 117.02,23.09 113.16,26.95 v1(113.16,28.75) 113.16,35.33 v1(109.7,38.79) R414.1 ; R477.1 175.08,48.64 176.83,50.39 176.83,51.59 175.9,52.53 175.9,53.85 v6(176.52,54.48) 176.72,54.68 R469.1 ; v1(126.21,41.81) R422.1
  TOP w0.635: v6(1.3,99.42) 1.28,99.43 1.28,238.94 3.84,241.5 14.15,241.5 15.54,240.11 L8.2
  BOTTOM w0.254: v1(126.21,41.81) 126.06,41.66 107.34,41.66 v1(105.23,43.76)
  BOTTOM w0.508: v1(109.7,38.79) 104.27,38.79 v1(103.71,39.34) ; v1(113.16,28.75) 106.28,28.75 106.08,28.55 96.8,28.55 94.97,30.38 v2(94.31,30.38) 93.88,29.95 91.52,29.95 91.39,29.82 89.65,29.82 89.49,29.97 77.89,29.97 76.47,28.55 74.9,28.55 v1(74.78,28.42)
  BOTTOM w0.635: v6(1.3,99.42) 1.08,99.2 1.08,3.67 3.48,1.27 29.34,1.27 ; v6(176.52,54.48) 176.03,54.98 v2(175.39,54.98) 169.99,54.98 166.98,51.97 166.98,46.47 167.96,45.49 167.96,39.19 163.32,34.56 163.32,32.23 v2(156.34,25.25) v6(156.34,22.73)
  BOTTOM w1.016: 29.34,1.27 v6(29.44,1.37)
  vias: v2(134.31,3.19) v2(156.34,20.32) v6(31.17,1.37) v6(43.61,1.27) v6(44.81,1.27) v6(156.34,21.59)
SB_PWR_ON_R: length 4.7
  TOP w0.102: U61.31 102.47,9.06 v2(103.45,8.08) 103.06,7.68 103.06,6.6 R720.1
SENSE_A: length 7
  TOP w0.102: R68.1 R73.1 R79.1 15.76,224.27 v2(15.89,224.4) 16.85,225.36 18.32,225.36 18.51,225.55 U2.13
SENSE_B: length 4.1
  TOP w0.102: R5.1 R8.1 27.64,232.66 v2(27.43,232.46) 27.2,232.23 U2.34
SER_IRQ: length 137.5
  TOP w0.102: v1(66.47,19.86) 66.47,20.64 63.46,23.65 63.32,23.65 62.06,24.91 62.06,24.93 58.51,28.49 56.64,28.49 56.1,29.03 55.3,29.03 54.58,28.31 52.21,28.31 51.44,29.09 51.44,29.6 50.48,30.56 50.46,30.56 50.27,30.75 50.27,31.46 R585.1 49.43,32.3 49.19,32.3 48.36,33.12 47.35,33.12 46.17,34.31 42.92,34.31 41.96,35.27 41.96,35.61 41.87,35.7 41.66,35.92 41.66,36.5 41.46,36.69 41.46,37.01 41.76,37.3 U29.G39 ; U23.27 U22.27 103.03,52.82 v1(102.82,52.6) ; v1(85.83,41.94) 86.21,41.55 86.21,35.06 86.49,34.78 86.49,33.69 86.22,33.43 86.22,26.71 85.04,25.53 85.04,23.8 79.66,18.42 v1(79.58,18.42) 79.58,17.73 78.59,16.74 78.59,5.51 78.77,5.33 80.65,5.33 82.5,3.48 86.26,3.48 91.36,8.59 91.36,9.12 93.37,11.13 93.37,11.58 93.96,12.17 94.76,12.17 94.94,12 U61.14
  BOTTOM w0.102: v1(79.58,18.42) 79.2,18.03 78.22,18.03 77.53,18.72 v2(71.27,18.72) 67.62,18.72 v1(66.47,19.86) ; v1(102.82,52.6) 102.82,49.96 93.8,40.94 86.82,40.94 v1(85.83,41.94)
SIO_EUP_N: length 8.1
  TOP w0.102: R605.2 92,20.35 v2(92.08,20.27) 92.2,20.14 92.2,17.65 93.57,16.28 93.59,16.28 94.27,15.6 U61.5
SIO_GND: length 50
  TOP w0.203: U61.44 105.77,15.6 105.77,15.6 106.26,15.6 106.26,15.6 106.32,15.6 106.48,15.44 106.98,15.44 108.2,14.22 110.11,14.22 110.36,14.48 110.36,14.67 R774.1
  TOP w0.254: C481.2 v1(105.66,24.28) G7.2 ; v1(120.47,18.69) 120.47,23.55 v1(120.07,23.95) ; R774.1 R775.1 C493.2 R738.2 111.66,17.78 v1(112.01,18.14) 112.01,19.08 111.33,19.76 C494.2 C490.2 R729.2 ; R710.2 C486.2 v1(109.73,24.28) ; C482.2 v1(107.7,24.28)
  BOTTOM w0.254: v1(105.66,24.28) v1(107.7,24.28) v1(109.73,24.28) v2(111.18,24.28) 116.59,24.28 116.92,23.95 v1(120.07,23.95) ; v1(112.01,18.14) v2(113.64,18.14) 114.22,18.72 120.45,18.72 v1(120.47,18.69)
SIO_PWRLED_N: length 86.8
  TOP w0.102: v1(102.82,14.73) 103.2,14.35 103.2,12.95 103.36,12.8 U61.37 ; v1(26.34,14.81) 26.86,14.29 R671.2 26.02,13.89 R672.2
  BOTTOM w0.102: v1(26.34,14.81) 26.99,15.46 27.16,15.46 29.34,17.63 30.91,17.63 31.46,18.18 41.07,18.18 43.76,15.49 52.45,15.49 52.93,15.98 70.03,15.98 70.41,16.36 v2(75.54,16.36) 76.38,16.36 76.76,15.98 79.19,15.98 80.08,16.87 82.63,16.87 83.42,16.08 88.08,16.08 88.95,15.2 95.39,15.2 96.55,14.05 98.34,14.05 98.8,13.59 100.11,13.59 100.75,14.22 102.16,14.22 102.67,14.73 v1(102.82,14.73)
SIO_SATA_LED: length 4.9
  TOP w0.102: SR732.2 94.23,20.99 94.23,20.74 v2(94.89,20.09) 96.54,18.44 U61.64
SIO_SUSACK_N: length 7.4
  TOP w0.102: R702.2 89.85,15.42 R602.1 v2(91.44,15.35) 92.25,15.35 92.37,15.24 92.75,15.24 R570.1 93.21,14.78 93.93,14.78 94.41,14.3 94.42,14.3 94.72,14 U61.9
SIO_SUSLED_N: length 96.4
  TOP w0.102: U61.58 99.27,17.67 99.47,17.48 100.99,17.48 102.06,16.41 102.06,15.54 101.47,14.96 101.47,11.51 v1(101.85,11.13) ; R767.2 26.02,12.88 R760.2 27.5,12.24 28.09,12.24 29.26,13.41 32.24,13.41 32.57,13.74 39.17,13.74 49.31,3.61 72.77,3.61 v2(73.25,4.09) 74.47,2.87 86.91,2.87 94.34,10.3 v1(94.34,11.48)
  BOTTOM w0.102: v1(101.85,11.13) 101.71,11.13 101.3,10.72 97.61,10.72 97.15,11.18 95.36,11.18 95.05,11.48 v1(94.34,11.48)
SIO_VCORE: length 6.4
  TOP w0.102: U61.12 93.27,12.8 v2(92.43,11.96) 91.95,11.48 90.92,11.48 C461.1 90.81,11.37 C460.1
SIO_VIN0: length 7.9
  TOP w0.203: U61.52 101.67,19.53
  TOP w0.254: 101.67,19.53 101.67,19.83 102.79,20.95 104.78,20.95 v2(105.38,21.56)
  TOP w0.508: v2(105.38,21.56) 105.66,21.84 C481.1 R684.1
SIO_VIN0_1: length 1.9
  TOP w0.305: G3.1 v2(106.68,24.36)
  TOP w0.508: v2(106.68,24.36) R684.2
SIO_VIN1: length 9.5
  TOP w0.203: U61.51 102.07,19.48
  TOP w0.254: 102.07,19.48 102.07,19.65 102.95,20.52 106.38,20.52 v2(106.65,20.8)
  TOP w0.508: v2(106.65,20.8) 107.7,21.84 C482.1 R693.1
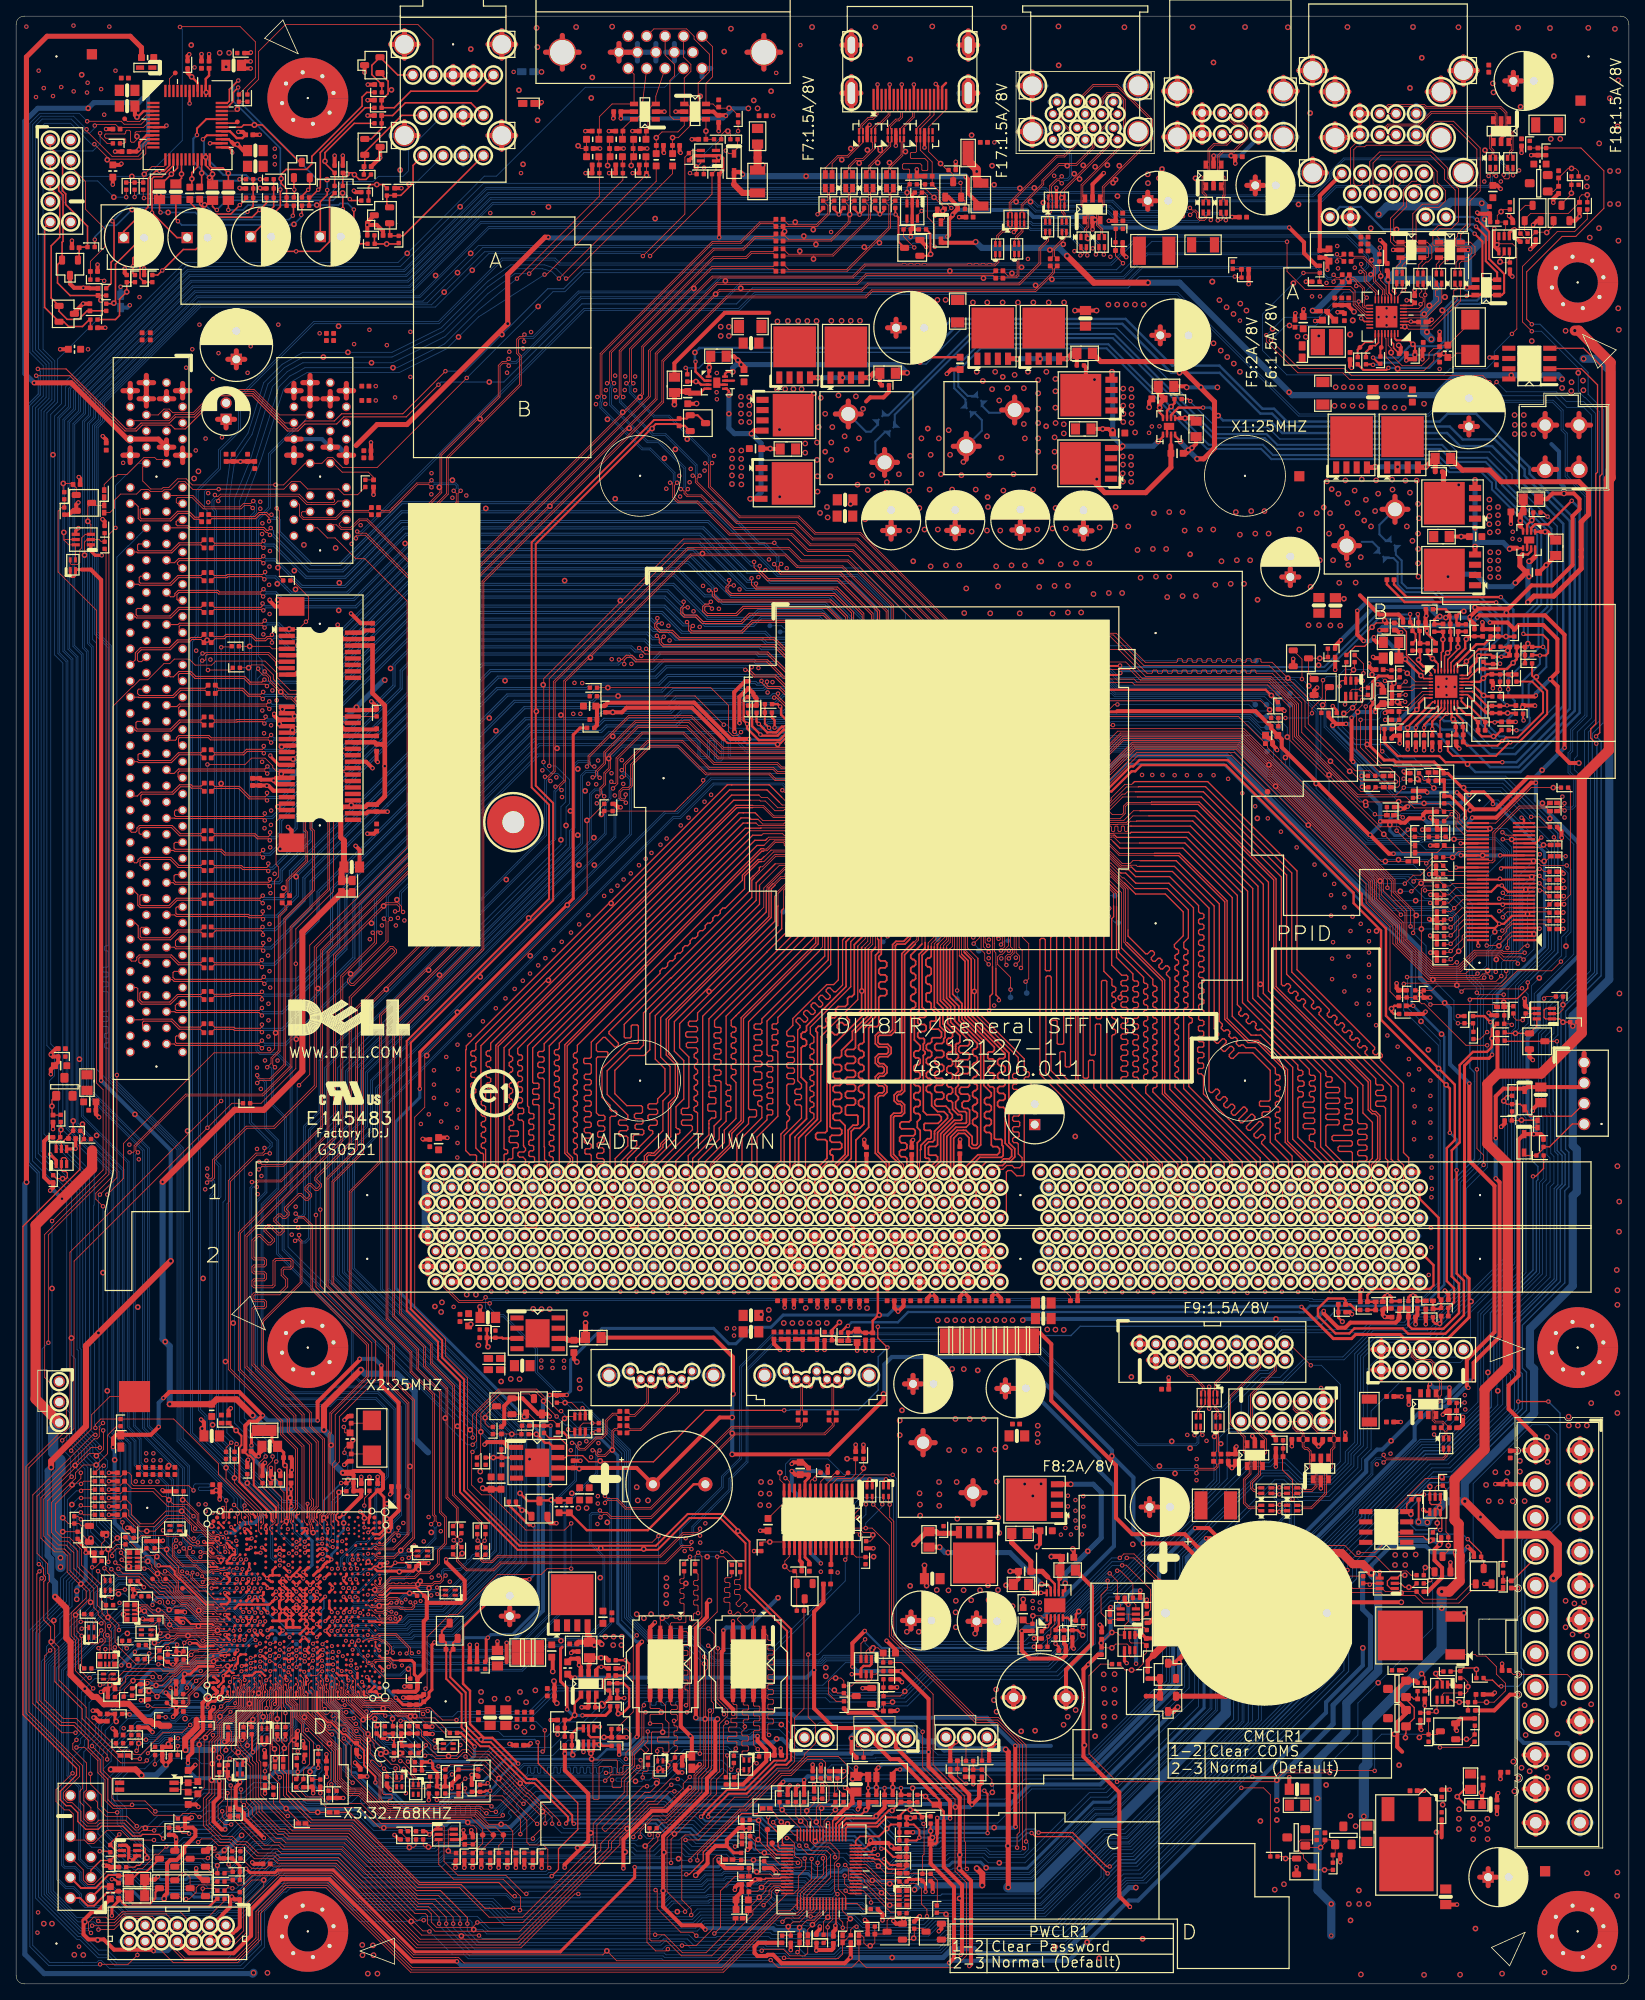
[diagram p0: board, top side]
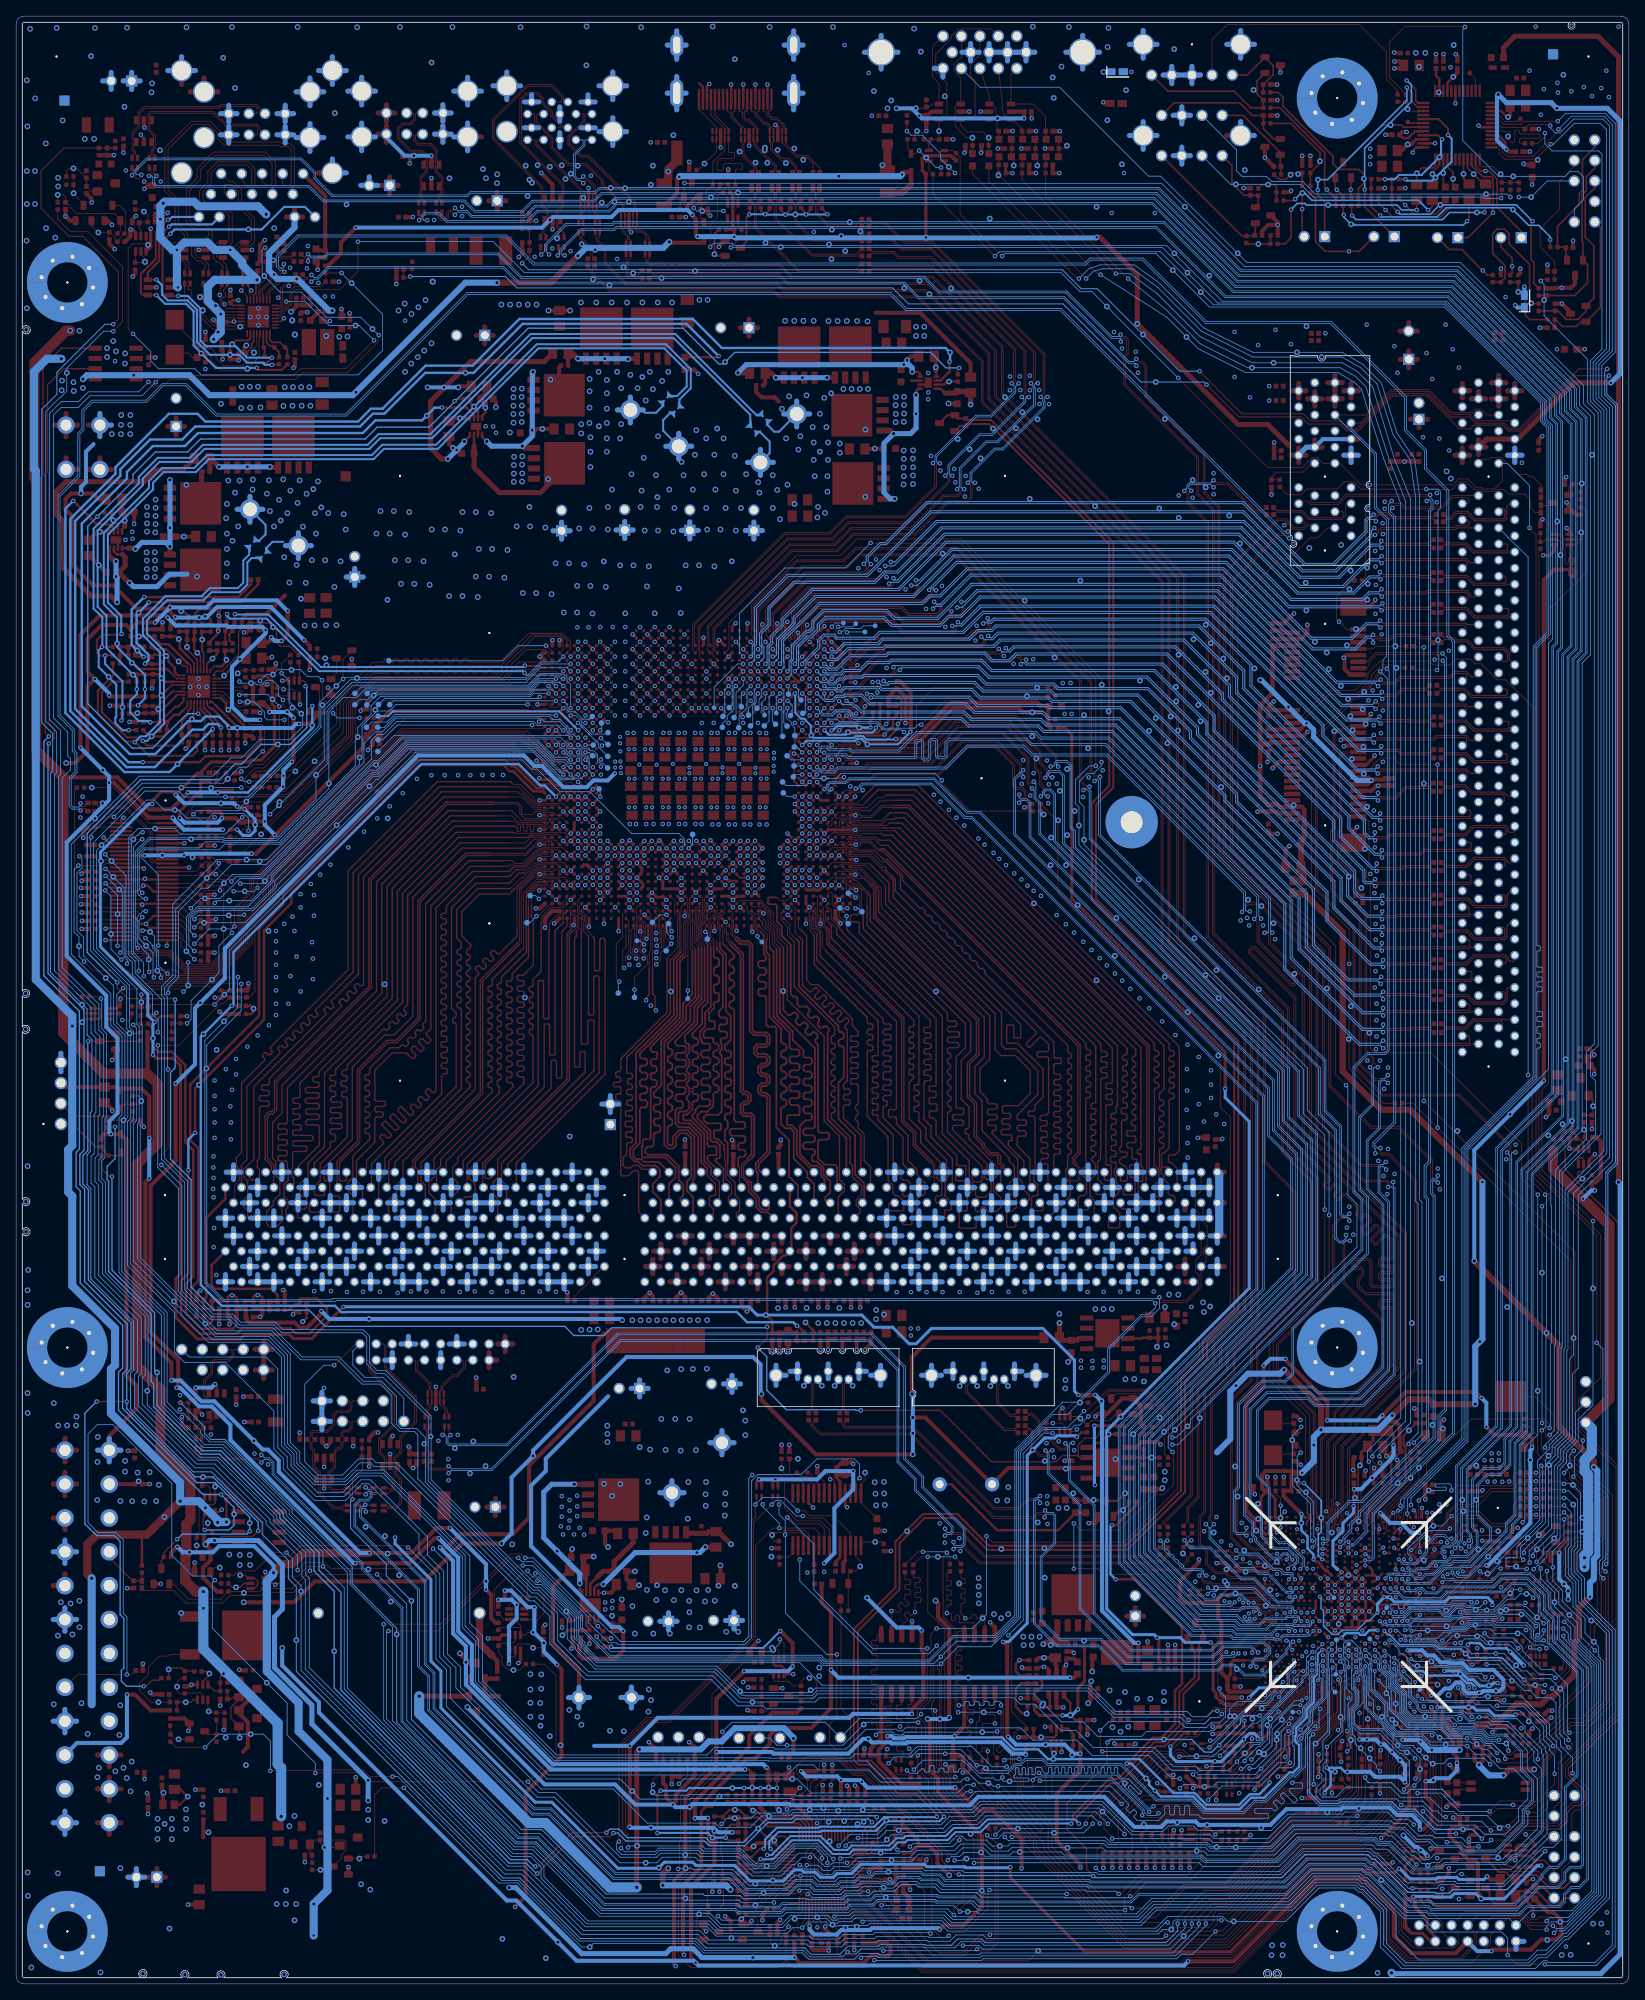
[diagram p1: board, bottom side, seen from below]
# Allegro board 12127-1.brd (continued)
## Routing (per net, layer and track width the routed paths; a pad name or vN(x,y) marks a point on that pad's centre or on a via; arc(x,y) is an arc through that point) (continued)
SIO_VIN1_1: length 1.9
  TOP w0.305: G4.1 v2(108.71,24.36)
  TOP w0.508: v2(108.71,24.36) R693.2
SIO_VIN2: length 11.6
  TOP w0.203: U61.50 102.47,19.41 102.68,19.62
  TOP w0.254: 102.68,19.62 102.97,19.91 106.63,19.91 108.22,21.5 v2(108.62,21.5) 109.66,22.54 C486.1 R710.1 R703.1
SIO_VIN2_1: length 2.6
  TOP w0.254: G5.1 113.79,22.23 v2(112.78,23.24) 112.59,23.43 R703.2
SIO_VIN3: length 12.9
  TOP w0.203: U61.49 102.87,19.28 103.1,19.51
  TOP w0.254: 103.1,19.51 106.81,19.51 107.95,20.65 C490.1 109.54,20.82 110.31,21.59 v2(110.87,21.59) 111.51,21.59 112.33,20.76 R729.1 112.45,20.76 R723.1
SIO_VIN3_1: length 1.9
  TOP w0.254: G6.1 v2(113.41,18.95) R723.2
SIO_VIN4: length 8.8
  TOP w0.203: 105.28,18.29 104.65,18.29 104.11,17.75 U61.48
  TOP w0.254: 105.28,18.29 107.01,18.29 v2(107.98,19.25) 108.48,19.76 C494.1 R739.1 R738.1
SLP_A#: length 2.8
  TOP w0.102: U29.AN37 27.11,38.25 27.11,38.25 26.93,38.25 26.7,38.01 26.7,37.6 v3(26.52,37.42)
  BOTTOM w0.102: TP85.1 26.52,37.11 v3(26.52,37.42)
SLP_LAN_B1: length 11
  TOP w0.102: Q109.B 190.66,218.01 v2(189.81,217.17) 189.78,217.21 R82.2 187.71,216.47 187.71,216.29 R108.1 187.44,216.17 187.15,216.46 187.13,216.46 R705.2 186.41,217.18 186.41,219.79 187.16,220.54 Q110.C
SLP_LAN_B2: length 12.2
  TOP w0.102: R107.2 v2(194.84,221.84) 194.16,221.84 193.88,221.56 C3321.1 192.49,219.53 187.81,219.53 187.08,218.8 Q110.B 187.08,217.4 R705.1
SLP_LAN_G2: length 6.4
  TOP w0.102: R106.2 193.76,224.75 193.4,225.12 v2(192.89,225.12) 192.47,225.12 C383.2 C64.1 190.65,222.26 Q6.G
SLP_LAN_G3: length 4.1
  TOP w0.102: R106.1 R70.2 v2(192.87,222.05) 192.87,221.93 191.64,220.7 Q109.C
SLP_LAN_N_C: length 9.6
  TOP w0.102: U29.AU36 25.45,38.61 24.13,38.61 21.33,35.82 21.33,34.84 20.98,34.49 19.05,34.49 TP88.1
SLP_S3_N: length 424.3
  TOP w0.102: R486.1 165.02,50.56 163.82,51.77 v1(161.95,51.77) ; v1(71.46,68.29) 71.81,68.64 R789.1 ; R256.1 167.08,163.69 v1(167.08,162.51) ; U29.AK40 29.55,36.78 29.13,36.36 29.13,34.16 27.36,32.39 27.36,30.74 27.21,30.59 27.21,29.88 27.16,29.84 27.16,29.23 28.59,27.8 28.59,27.4 29.03,26.96 29.03,22.76 29.77,22.02 29.77,21.19 32.45,18.52 33.1,18.52 33.65,17.96 40.92,17.96 49.66,9.22 50.95,9.22 51.49,8.69 51.49,7.67 52.14,7.01 56.59,7.01 v1(57.2,7.62) 62.86,7.62 72.02,16.78 72.02,19.66 75.77,23.41 75.77,24.88 77.62,26.73 77.62,27.56 v1(77.45,27.74) ; v1(102.51,6.96) 102.51,7.63 102.07,8.07 U61.30 ; v1(76.96,43.22) 76.53,42.79 76.53,33.73 74.71,31.92 R623.1 75.72,31.6 76.25,31.06 76.25,29.31 75.62,28.67 v1(75.62,27.89)
  BOTTOM w0.102: v1(167.08,162.51) 166.14,161.57 166.14,159 v2(164.64,157.51) 164.47,157.33 164.47,155.9 166.08,154.28 169.8,154.28 172.06,152.02 173.35,152.02 175.62,149.76 184.72,149.76 193.17,141.31 193.17,127.68 188.26,122.78 188.26,118.89 186.87,117.49 186.87,107.75 187.24,107.37 187.24,88.19 181.99,82.94 181.99,72.01 181.99,71.72 176.77,66.5 174.44,66.5 166.48,58.54 166.48,58.09 161.95,53.56 v1(161.95,51.77) 159.31,49.12 159.31,36.57 138.52,15.79 136.2,15.79 134.9,14.49 134.9,13.12 129.22,7.44 114.17,7.44 113,6.27 104.38,6.27 103.7,6.96 v1(102.51,6.96) 101.8,7.67 99.57,7.67 99.09,7.19 97.96,7.19 97.91,7.24 94.39,7.24 94.16,7.47 85.39,7.47 84.47,6.55 58.51,6.55 57.43,7.62 v1(57.2,7.62) ; v1(76.96,43.22) 75.11,45.08 75.11,65.78 72.6,68.29 v1(71.46,68.29) ; v1(77.45,27.74) 77.3,27.89 v1(75.62,27.89)
SLP_S3_N_Q46: length 3.2
  TOP w0.102: R789.2 v1(71.44,69.53) 70.32,69.53 69.93,69.15 Q67.5
SLP_S4_N: length 186.8
  TOP w0.102: v1(102.74,13.41) 102.74,12.42 103.16,12 U61.35 ; v1(21.16,36.72) 21.16,37.13 22.38,38.34 23.13,38.34 23.82,39.03 24.68,39.03 24.87,39.22 25.13,39.22 25.17,39.19 25.57,39.19 25.89,39.51 U29.AT35 ; v1(117.91,14.25) 117.73,14.43 117.73,17.58 117.58,17.73 117.58,23.32 113.72,27.18 113.72,35.92 109.77,39.86 R302.1 ; R737.2 26.31,12.02 26.64,12.02 26.82,11.84 v1(26.82,11.85)
  BOTTOM w0.102: v1(117.91,14.25) 117.82,14.34 v2(116.97,14.34) 116.19,14.34 116.05,14.2 111.12,14.2 109.16,12.24 104.68,12.24 103.51,13.41 v1(102.74,13.41) 102.69,13.36 101.11,13.36 100.47,12.73 98.44,12.73 97.99,13.18 96.19,13.18 95.04,14.34 87.59,14.34 87.28,14.03 82.6,14.03 82.39,13.82 66.06,13.82 65.81,13.56 43.17,13.56 40.33,16.4 32.2,16.4 31.65,15.85 31.34,15.85 27.34,11.85 v1(26.82,11.85) 23.85,11.85 23.36,12.34 21.69,12.34 21.43,12.09 15.5,12.09 10.65,16.94 9.36,16.94 8.39,17.91 8.39,28.77 8.95,29.33 8.95,29.99 9.85,30.89 9.85,32.19 13.37,35.71 17.9,35.71 18.06,35.55 20.12,35.55 21.16,36.59 v1(21.16,36.72)
SLP_S4_N_R: length 4.7
  TOP w0.102: R302.2 C143.1 106.88,41.68 v2(106.27,41.68) 105.84,41.68 105.42,41.26 U53.2
SLP_S5_N: length 3.1
  TOP w0.102: v3(34.75,40.66) 34.75,40.66 34.75,40.06 U29.AA35
  BOTTOM w0.102: TP86.1 35.18,41.7 35.18,41.1 v3(34.75,40.66)
SLP_SUS_FET: length 7
  TOP w0.102: 159.87,17.14 160.1,16.92 v2(161.77,16.92) 162.31,17.45 C529.2 163.03,17.84 Q90.G 163.58,16.24 C528.1 163.31,15.04 R682.2
SLP_SUS_FET_L: length 8.8
  TOP w0.102: R682.1 v2(162.26,14.14) 161.11,14.14 DQ61.C 159.64,15.61 159.64,16 159.08,16.56 159.08,17.61 159.31,17.84 R711.2
SLP_SUSB: length 169.3
  TOP w0.102: v1(151.94,24.31) 154.69,24.31 155.54,23.46 R709.2 ; U29.AK38 29.55,37.59 29.86,37.29 29.86,35.76 29.54,35.44 29.54,34 27.76,32.22 27.76,30.57 27.61,30.42 27.61,30.05 27.87,29.8 27.87,29.54 29.3,28.11 29.3,28.1 29.3,27.69 29.74,27.25 29.74,23.05 30.48,22.31 30.48,21.51 32.76,19.23 33.39,19.23 33.95,18.67 41.22,18.67 49.9,9.98 51.61,9.98 53.33,8.26 v1(53.33,7.47)
  BOTTOM w0.102: v1(53.33,7.47) 53.33,7.07 56.57,3.83 80.37,3.83 80.59,3.61 92.89,3.61 93.04,3.76 95.35,3.76 96.06,3.05 101.68,3.05 102.47,3.84 114.71,3.84 115.88,5 128.42,5 v2(128.85,4.57) 129.86,4.57 137.79,12.51 140.14,12.51 v1(151.94,24.31)
SLP_SUSB_L_2: length 2.5
  TOP w0.102: DQ61.B v2(157.43,15.54) 157.17,15.8 R709.1
SLP_WLAN_N: length 10.4
  TOP w0.102: U29.AL39 28.63,37.25 28.63,36.61 28.72,36.52 28.72,34.33 26.91,32.51 26.59,32.51 26.29,32.21 R563.1 26.29,31.71 26.72,31.28 26.72,30.11 26.01,29.4 v4(26.01,28.98)
SMB_CLK_MAIN: length 335.1
  TOP w0.102: Q69.4 136.98,47.02 136.59,47.41 R751.2 136.59,49.92 v1(135.61,50.9) ; DIMM1.118 53.04,99.39 53.04,98.32 53.77,97.59 53.77,96.01 53.31,95.55 53.31,93.02 DIMM2.118 53.04,90.42 53.75,89.71 53.75,88.3 53.33,87.87 53.33,86.38 54.97,84.73 57.81,84.73 v1(58.22,85.14) ; v1(184.32,142.8) 184.69,142.43 XDPC1.53 ; v1(184.78,125.6) 184.78,124.76 184.11,124.09 172.35,124.09 172.26,124 v1(172.09,124)
  BOTTOM w0.102: v1(184.78,125.6) 184.78,126.86 185.67,127.75 185.67,141.71 v2(185.47,141.91) 184.58,142.8 v1(184.32,142.8) ; v1(172.09,124) 172.09,120.68 176.36,116.4 176.36,86.99 174.21,84.84 160.87,84.84 160.74,84.96 58.39,84.96 v1(58.22,85.14) 58.22,83.74 59.23,82.73 60.4,82.73 64.39,78.74 64.39,75.82 69.6,70.61 71.42,70.61 75.92,66.12 75.92,45.59 78.53,42.98 83.69,42.98 86.74,39.93 99.53,39.93 99.53,39.93 99.72,39.93 99.96,40.17 100.3,40.51 126.46,40.51 130,44.06 130,45.62 135.28,50.9 v1(135.61,50.9)
SMB_CLK_RESUME: length 435.2
  TOP w0.102: v1(136.55,51.23) 136.55,51.23 136.93,51.23 138.49,49.67 R730.2 138.49,47.36 138.86,46.99 Q69.3 ; v1(77.39,18.21) 77.39,18.92 78.79,20.32 80.5,20.32 84.3,24.12 84.3,25.8 85.51,27.01 85.51,38.87 85.75,39.12 85.75,40.14 v1(85.32,40.56) ; MINI1.30 40.61,153.15 40.61,153.16 34.21,159.56 33.63,159.56 31.54,161.65 31.54,162.04 30.84,162.74 v1(30.82,162.74) ; SLOT2.B5 17.61,194.55 18.34,195.27 18.97,195.27 19.42,194.83 21.95,194.83 24.83,197.7 29.51,197.7 32.66,194.55 SLOT1.B5 ; v1(56.62,67.74) 56.62,70.57 59.8,73.75 64.56,73.75 67.28,71.02 v1(67.59,71.02) ; U29.AG36 30.73,38.89 30.29,39.33 v3(30.25,39.33)
  BOTTOM w0.102: v3(30.25,39.33) 30.25,39.03 29.38,38.15 29.38,37.12 28.19,35.94 28.19,33.72 27.08,32.61 22.73,32.61 21.79,31.66 21.31,31.66 21.03,31.94 19.28,31.94 18.83,31.5 18.03,31.5 17.3,30.76 16.73,30.76 16.52,30.96 15.28,30.96 13.21,28.89 13.21,26.6 11.82,25.22 11.82,22.62 12.99,21.45 12.99,19.88 16.51,16.36 20.44,16.36 20.98,16.89 24.05,16.89 24.79,17.63 26.41,17.63 27.97,19.19 29.49,19.19 29.8,19.5 41.62,19.5 44.3,16.81 51.9,16.81 52.38,17.3 64.52,17.3 64.97,17.75 76.94,17.75 v1(77.39,18.21) ; SLOT1.B5 36.45,194.53 34.45,192.53 34.41,192.53 31.52,189.65 31.52,183.01 30.04,181.53 30.04,164.6 30.51,164.13 30.51,163.05 v1(30.82,162.74) 29.96,161.88 29.96,115.81 30.31,115.46 32.44,115.46 34.21,113.68 34.21,98.18 33.22,97.19 33.22,91.1 54.36,69.96 54.36,69.52 v2(54.73,69.14) 56.13,67.74 v1(56.62,67.74) ; v1(67.59,71.02) 69.63,68.97 72.74,68.97 75.69,66.02 75.69,45.49 78.69,42.49 83.39,42.49 v1(85.32,40.56) 86.19,39.7 99.43,39.7 99.81,39.7 100.19,40.07 100.4,40.28 127.77,40.28 129.46,41.97 129.46,42.34 130.26,43.14 130.26,45.56 135.15,50.44 135.89,50.44 136.55,51.11 v1(136.55,51.23)
SMB_DATA_MAIN: length 335.6
  TOP w0.102: v1(172.49,124.84) 174.4,124.84 174.92,124.31 183.53,124.31 v1(184.18,124.97) ; v1(58.72,84.38) 58.6,84.51 54.88,84.51 53.04,86.34 DIMM2.238 52.45,89.54 52.45,90.23 52.77,90.55 52.77,91.16 52.31,91.62 52.31,93.99 52.83,94.51 52.83,96.64 DIMM1.238 ; v1(184.37,141.94) 184.56,141.94 184.56,141.93 XDPC1.51 ; Q69.1 139.49,45.2 R752.2 140.67,46.37 140.67,48.92 137.67,51.92 137.19,51.92 v1(137.16,51.89)
  BOTTOM w0.102: v1(172.49,124.84) 172.54,124.79 172.54,121.03 v2(174.22,119.35) 176.59,116.98 176.59,86.89 174.31,84.61 160.4,84.61 160.27,84.73 59.05,84.73 58.72,84.4 v1(58.72,84.38) 58.72,83.85 59.59,82.98 60.47,82.98 64.64,78.81 64.64,75.89 68.4,72.14 70.22,72.14 76.15,66.21 76.15,45.69 78.63,43.21 83.79,43.21 86.84,40.16 99.62,40.16 100,40.53 100,40.6 100.14,40.74 126.36,40.74 129.75,44.12 129.75,45.7 135.94,51.89 v1(137.16,51.89) ; v1(184.37,141.94) 184.47,141.94 185.45,140.96 185.45,127.89 184.19,126.63 184.19,124.98 v1(184.18,124.97)
SMB_DATA_RESUME: length 436.6
  TOP w0.102: U29.AG32 31.1,41.03 v3(31.49,41.42) ; SLOT2.B6 14.43,193.83 18.95,193.83 19.72,194.6 22.05,194.6 24.92,197.47 29.42,197.47 33.34,193.55 SLOT1.B6 ; v1(56.62,66.85) 57.1,67.34 57.1,70.73 59.89,73.52 64.36,73.52 65.53,72.34 65.53,71.86 v1(67.03,70.36) ; MINI1.32 40.86,152.35 34.74,158.46 34.74,158.7 34.11,159.33 33.54,159.33 31.31,161.56 31.31,161.94 30.97,162.28 30.63,162.28 30.02,162.89 v1(30.02,163.09) ; v1(135.36,49.99) 135.36,49.02 134.54,48.21 134.54,45.99 R768.2 135.94,45.2 Q69.6 ; v1(76.53,18.21) 76.53,18.38 78.98,20.83 80.69,20.83 84.07,24.21 84.07,25.89 85.28,27.1 85.28,39.69 v1(85.29,39.7)
  BOTTOM w0.102: SLOT1.B6 34.45,192.9 31.29,189.74 31.29,183.11 29.81,181.63 29.81,163.29 v1(30.02,163.09) 29.73,162.8 29.73,115.71 30.22,115.23 32.35,115.23 33.99,113.59 33.99,98.27 32.99,97.28 32.99,91 53.21,70.78 v2(53.21,70.15) 53.21,69.57 55.93,66.85 v1(56.62,66.85) ; v1(76.53,18.21) 71.52,18.21 71.49,18.19 64.94,18.19 64.28,17.53 52.29,17.53 51.81,17.04 44.4,17.04 41.71,19.73 29.71,19.73 29.4,19.42 27.8,19.42 26.31,17.93 24.61,17.93 23.79,17.12 20.88,17.12 20.35,16.59 16.61,16.59 13.22,19.97 13.22,21.54 12.05,22.71 12.05,25.12 13.44,26.51 13.44,28.8 15.37,30.73 16.43,30.73 16.63,30.53 17.39,30.53 18.13,31.27 18.93,31.27 19.4,31.74 20.9,31.74 21.18,31.46 21.87,31.46 22.82,32.4 27.16,32.4 28.4,33.64 28.4,35.86 29.58,37.04 29.58,38.07 30.71,39.2 30.71,40.6 31.49,41.37 v3(31.49,41.42) ; v1(67.03,70.36) 68.1,69.29 68.67,69.29 69.21,68.75 72.64,68.75 75.46,65.93 75.46,45.4 78.59,42.27 78.64,42.27 79.1,41.81 83.19,41.81 v1(85.29,39.7) 85.52,39.47 99.34,39.47 99.91,39.47 100.49,40.06 127.87,40.06 129.69,41.87 129.69,42.15 130.49,42.95 130.49,45.46 135.01,49.99 v1(135.36,49.99)
SMLICLK_PCH: length 139.8
  TOP w0.102: v3(29.1,39.1) 29.21,39.21 U29.AK36 ; v1(84.48,15.32) 84.48,16.09 89.83,21.44 90.56,21.44 94.95,25.83 96.11,25.83 98.11,27.84 99.97,27.84 100.38,27.43 100.38,25.95 R535.1 101.47,24.85 101.47,23.56 R667.2
  BOTTOM w0.102: v1(84.48,15.32) 84.02,15.77 83.01,15.77 82.47,16.31 v2(80.34,16.31) 79.78,15.75 53.03,15.75 52.54,15.27 43.66,15.27 40.98,17.95 31.56,17.95 31.01,17.4 29.62,17.4 26.57,14.35 24.47,14.35 24.24,14.57 23.31,14.57 22.85,15.04 15.37,15.04 14.38,16.02 13.88,16.02 10.86,19.05 10.86,26.7 11.79,27.63 11.79,28.83 15.12,32.17 17.13,32.17 17.43,32.47 19.8,32.47 20.74,33.41 21.17,33.41 21.34,33.25 26.86,33.25 27.58,33.98 27.58,35.69 27.58,36.19 28.77,37.38 28.77,38.41 28.91,38.55 28.91,38.9 v3(29.1,39.1)
SMLICLK_PCH_SIO: length 5.5
  TOP w0.102: U61.56 100.07,19.36 99.77,19.66 99.77,21.67 v2(99.88,21.78) 100.07,21.97 101.03,21.97 R667.1
SMLIDATA_PCH: length 144.5
  TOP w0.102: U29.AK33 29.48,40.5 29.15,40.5 v3(29.09,40.43) ; v1(83.62,15.32) 83.62,15.55 89.74,21.67 90.4,21.67 94.84,26.11 96.06,26.11 98.15,28.19 101.98,28.19 103.23,26.95 103.23,26.09 102.63,25.49 R526.1 101.85,24.19 R673.2
  BOTTOM w0.102: v3(29.09,40.43) 28.41,39.76 28.41,38.64 27.15,37.37 27.15,35.67 26.08,34.6 26.08,34.23 25.71,33.86 20.5,33.86 20.2,33.56 17.52,33.56 16.83,32.88 13.87,32.88 12.88,31.89 12.88,31.17 10.83,29.12 10.83,28.6 10.63,28.4 10.63,18.95 13.79,15.8 14.28,15.8 15.27,14.81 22.75,14.81 23.23,14.33 24.15,14.33 24.35,14.12 26.67,14.12 29.72,17.17 31.1,17.17 31.65,17.72 40.88,17.72 43.57,15.04 52.64,15.04 53.12,15.52 v2(82.14,15.52) 82.47,15.52 82.68,15.32 v1(83.62,15.32)
SMLIDATA_PCH_SIO: length 5.3
  TOP w0.102: U61.55 100.47,19.28 100.3,19.45 100.19,19.57 100.19,20.18 v2(101.6,21.59) 102.55,22.54 R673.1
SMLINK0_CLK: length 24.4
  TOP w0.102: v1(16.1,30.28) 15.76,30.28 R33.1 ; v3(31.49,40.66) 31.86,41.03 U29.AE32
  BOTTOM w0.102: v3(31.49,40.66) 30.93,40.1 30.93,39.13 29.78,37.99 29.78,36.95 28.93,36.1 v2(28.93,34.75) 28.93,33.89 27.24,32.2 22.9,32.2 21.96,31.25 21.06,31.25 20.78,31.54 19.48,31.54 18.99,31.04 18.24,31.04 17.48,30.28 v1(16.1,30.28)
SMLINK0_DATA: length 25.9
  TOP w0.102: v3(31.45,40.01) 31.48,39.98 31.79,39.98 U29.AE35 ; R34.1 15.18,29.15 v1(14.94,28.91)
  BOTTOM w0.102: v1(14.94,28.91) 14.94,29.54 v2(15.21,29.82) 16.29,29.82 16.52,30.05 17.6,30.05 18.36,30.81 19.08,30.81 19.6,31.33 20.63,31.33 20.92,31.05 22.08,31.05 23.02,32 27.33,32 29.46,34.13 29.46,36.35 30.05,36.93 30.05,37.96 31.14,39.06 31.14,39.7 v3(31.45,40.01)
SOP_ENABLE_GP33: length 14.5
  TOP w0.102: U29.AV26 25.29,44.55 25.19,44.65 24.74,44.65 24.5,44.89 22.89,44.89 20.95,46.84 19.71,46.84 19.27,46.39 v2(18.99,46.39) 18.29,47.09 18.29,47.52 18.01,47.8 17.56,47.8 16.72,48.64 15.56,48.64 15.26,48.93 R423.1 14.19,49.25 R552.1
SOUT1: length 6.3
  TOP w0.102: U61.59 98.87,19.39 98.6,19.66 98.6,20.4 98.04,20.95 v2(98.04,21.46) 98.96,22.38 R641.1 R642.1
SPEED_100: length 38.1
  TOP w0.267: UR109.2 168.21,200.83 v1(168.28,200.76) ; v1(181.05,217.9) 182.26,216.69 182.26,213.63 183.67,212.22 U11.3 v1(182.6,211.32)
  BOTTOM w0.267: v1(168.28,200.76) 169.11,200.76 169.38,201.03 171.35,201.03 172.32,202 v2(173.47,202) 175.96,202 177.57,203.61 177.57,207.57 178.74,208.74 181.18,208.74 181.91,209.48 181.91,210.63 v1(182.6,211.32) ; v1(181.05,217.9) 180.98,217.9 180.7,218.18 175.71,218.18 RJ45.L3
SPEED_100_N: length 3.8
  TOP w0.203: U12.26 168.95,203.52 168.57,203.13 168.18,203.13 TP3.1
  TOP w0.267: TP3.1 167.39,202.34 UR109.1
SPEED_1000: length 39.4
  TOP w0.267: UR108.2 167.07,200.13 169.93,200.13 v1(170.18,200.38) ; v1(182.61,209.41) U11.1 184.24,209.41 184.53,209.7 184.53,212.04 182.68,213.89 182.68,217.26 v1(181.17,218.76)
  BOTTOM w0.267: v1(170.18,200.38) 175.23,200.38 v2(177.04,202.18) 177.02,202.2 177.99,203.17 177.99,207.4 178.91,208.32 181.53,208.32 v1(182.61,209.41) ; RJ45.L4 180.67,219.1 181.01,218.76 v1(181.17,218.76)
SPEED_1000_N: length 4.4
  TOP w0.203: U12.25 168.55,203.86 168.25,203.56 167.28,203.56 TP4.1
  TOP w0.267: UR108.1 166.37,202.64 TP4.1
SPI_CLK: length 114.1
  TOP w0.102: RN62.3 89.62,26.55 v1(89.53,26.47) ; v1(78.23,24.51) 77.78,24.51 72.67,19.41 72.67,19.23 72.97,18.93 73.15,18.93 77.95,23.72 78.45,23.72 78.59,23.72 79.76,24.89 79.76,25.35 79.63,25.48 79.1,25.48 78.97,25.6 78.97,26.32 79.1,26.45 RN60.3 ; U29.U39 36.25,37.18 36.25,36.42 36.7,35.97 36.7,33.49 38.69,31.51 39.43,31.51 39.9,31.04 39.9,30.51 40.9,29.5 40.9,29.31 40.91,29.31 40.91,25.77 v1(41.73,24.94)
  BOTTOM w0.102: v1(89.53,26.47) 89.18,26.11 88.27,26.11 87.71,26.67 87.48,26.67 87.38,26.57 87.38,26.37 87.28,26.26 86.88,26.26 86.77,26.37 86.77,26.97 86.65,27.1 86.29,27.1 86.16,26.97 86.16,26.37 86.06,26.26 85.66,26.26 85.55,26.37 85.55,26.62 85.43,26.75 85.07,26.75 84.94,26.62 84.94,26.37 84.84,26.26 84.44,26.26 84.34,26.37 84.34,26.87 84.21,27 83.85,27 83.73,26.87 83.73,26.37 83.62,26.26 83.22,26.26 83.12,26.37 83.12,26.57 83.01,26.67 82.4,26.67 80.62,24.89 v2(79.43,24.89) 79.22,24.89 78.84,24.51 v1(78.23,24.51) 64.24,24.51 62.03,22.3 62.03,22.07 62.33,21.77 62.33,21.62 61.96,21.25 61.82,21.25 61.48,21.59 61.34,21.59 61.05,21.3 61.05,21.15 61.39,20.82 61.39,20.67 60.98,20.27 58.35,20.27 57.56,21.06 57.56,21.95 57.43,22.07 57.08,22.07 56.95,21.95 56.95,21.06 56.85,20.95 56.44,20.95 56.34,21.06 56.34,21.95 56.21,22.07 55.86,22.07 55.73,21.95 55.73,21.06 55.63,20.95 55.22,20.95 55.12,21.06 55.12,21.97 55.02,22.07 54.61,22.07 54.51,21.97 54.51,21.06 54.41,20.95 53.41,20.95 52.98,20.52 44.81,20.52 44.68,20.65 44.68,21.01 44.81,21.13 46.28,21.13 46.41,21.26 46.41,21.62 46.28,21.74 44.29,21.74 44.01,21.46 43.87,21.46 43.58,21.75 43.58,21.89 44.05,22.37 44.05,22.55 43.8,22.8 43.62,22.8 43.15,22.32 43,22.32 42.72,22.61 42.72,22.76 43.2,23.24 43.2,23.42 42.95,23.67 42.77,23.67 41.58,22.48 41.4,22.48 41.15,22.73 41.15,22.91 42.11,23.88 42.11,24.06 41.96,24.21 40.61,24.21 40.49,24.33 40.49,24.81 40.61,24.94 v1(41.73,24.94)
SPI_CLK_1: length 13.4
  TOP w0.102: U30CN1.6 79.88,35.18 80.54,34.52 80.54,32.74 80.95,32.33 80.95,30.71 80.85,30.61 79.63,30.61 79.53,30.51 79.53,30.1 79.63,30 80.85,30 80.95,29.9 80.95,28.83 80.85,28.73 80.31,28.73 80.21,28.83 80.21,29.18 80.11,29.29 79.6,29.29 79.5,29.18 v1(79.5,28.85) 79.56,28.8 RN60.2
SPI_CLK_2: length 13.4
  TOP w0.102: U35CN1.6 90.17,34.67 90.27,34.57 90.73,34.57 90.83,34.47 90.83,34.06 90.73,33.96 90.14,33.96 90.04,33.86 90.04,33.45 90.14,33.35 90.73,33.35 90.83,33.25 90.83,32.84 90.73,32.74 90.27,32.74 90.17,32.64 90.17,32.33 90.37,32.13 v1(90.37,31.9) 90.37,31.65 89.99,31.27 89.99,30.86 90.09,30.76 90.7,30.76 90.81,30.66 90.81,30.23 90.7,30.12 90.09,30.12 89.99,30.02 89.99,29.62 90.09,29.51 90.7,29.51 90.81,29.41 90.81,28.98 90.7,28.88 90.12,28.88 90.02,28.78 90.02,28.21 90.25,27.97 RN62.2
SPI_CS0_N: length 99.9
  TOP w0.102: U30CN1.1 83.12,43.67 83.31,43.48 83.31,42.05 83.21,41.94 82.85,41.94 82.73,41.82 82.73,41.46 82.85,41.33 83.21,41.33 83.31,41.23 83.31,40.83 83.21,40.72 82.85,40.72 82.73,40.6 82.73,40.24 82.85,40.11 83.21,40.11 83.31,40.01 83.31,39.61 83.21,39.51 82.85,39.51 82.73,39.38 82.73,39.02 82.85,38.9 83.21,38.9 83.31,38.79 83.31,38.39 83.21,38.29 82.85,38.29 82.73,38.16 82.73,37.8 82.85,37.68 83.21,37.68 83.31,37.57 83.31,37.17 83.21,37.07 83.03,37.07 82.93,36.97 82.93,36.56 83.03,36.46 83.21,36.46 83.31,36.36 83.31,34.77 v1(83.08,34.54) ; v1(77.85,34.54) 77.6,34.29 77.6,30.15 76.23,28.78 76.23,27.29 76.03,27.1 75.39,27.1 75.26,26.97 75.26,26.33 75.1,26.16 74.65,26.16 74.55,26.27 74.55,27.64 74.43,27.76 71.65,27.76 71.53,27.64 71.53,23.01 71.65,22.89 72.16,22.89 72.29,23.01 72.29,26.85 72.42,26.97 73.76,26.97 73.89,26.85 73.89,26.29 73.76,26.16 v1(73.15,26.16) ; U29.R38 37.23,37.67 37.54,37.35 37.54,36.98 37.42,36.86 37.42,36.57 37.58,36.41 37.58,33.86 38.74,32.7 39.19,32.7 39.89,32 40.85,32 41.15,31.7 41.15,31.5 42.09,30.56 42.6,30.56 43.68,29.47 43.68,27.41 45.1,25.98 45.24,25.85 45.24,22.94 46.21,21.97 57.68,21.97 57.99,21.67 58.52,21.67 58.83,21.36 59.46,21.36 v1(59.49,21.34)
  BOTTOM w0.102: v1(77.85,34.54) 77.85,34.87 77.98,35 78.64,35 78.75,34.9 78.75,34.65 78.85,34.54 79.25,34.54 79.36,34.65 79.36,34.9 79.46,35 79.86,35 79.97,34.9 79.97,34.65 80.07,34.54 80.47,34.54 80.57,34.65 80.57,34.9 80.68,35 81.08,35 81.18,34.9 81.18,34.65 81.29,34.54 81.69,34.54 81.79,34.65 81.79,34.9 81.9,35 82.3,35 82.4,34.9 82.4,34.65 82.51,34.54 v1(83.08,34.54) ; v1(73.15,26.16) 72.87,25.88 63.52,25.88 v2(62.51,24.87) 62.51,24.39 59.49,21.37 v1(59.49,21.34)
SPI_CS1_N: length 104
  TOP w0.102: v1(73.91,25.28) 73.91,24.46 74.04,24.33 74.93,24.33 75.06,24.46 75.06,25.37 76.71,27.03 76.71,28.45 77.39,29.13 77.53,29.13 77.99,28.68 78.13,28.68 78.42,28.96 78.42,29.11 77.96,29.56 77.96,29.7 78.33,30.07 v1(78.33,31.29) ; v3(37.92,40.08) 37.83,40.08 U29.R35 ; v1(40.71,31.52) 40.74,31.52 41.94,30.33 42.52,30.33 42.67,30.18 42.67,29.97 43.45,29.19 43.45,27.31 45.01,25.76 45.01,22.85 46.12,21.74 57.53,21.74 58.12,21.16 v1(58.32,21.16) ; U35CN1.1 93.22,43.17 93.22,42.7 93.32,42.6 93.8,42.6 93.9,42.5 93.9,42.1 93.8,41.99 93.32,41.99 93.22,41.89 93.22,41.49 93.32,41.38 93.8,41.38 93.9,41.28 93.9,40.88 93.8,40.77 93.32,40.77 93.22,40.67 93.22,40.27 93.32,40.16 93.8,40.16 93.9,40.06 93.9,39.66 93.8,39.56 93.32,39.56 93.22,39.45 93.22,39.05 93.32,38.95 93.8,38.95 93.9,38.84 93.9,38.44 93.8,38.34 93.32,38.34 93.22,38.23 93.22,37.83 93.32,37.73 93.8,37.73 93.9,37.62 93.9,37.22 93.8,37.12 93.32,37.12 93.22,37.02 93.22,36.61 93.32,36.51 93.8,36.51 93.9,36.41 93.9,36 93.8,35.9 93.32,35.9 93.22,35.8 93.22,35.39 93.32,35.29 93.8,35.29 93.9,35.19 93.9,34.78 93.8,34.68 93.32,34.68 93.22,34.58 93.22,34.17 93.32,34.07 93.8,34.07 93.9,33.97 93.9,33.56 93.8,33.46 93.32,33.46 93.22,33.36 93.22,32.95 93.32,32.85 93.8,32.85 93.9,32.75 93.9,32.34 93.8,32.24 93.32,32.24 93.22,32.14 93.22,31.02 v1(93.37,30.87)
  BOTTOM w0.102: v1(78.33,31.29) 78.41,31.21 v2(80.18,31.21) 80.19,31.22 89.76,31.22 90.09,30.89 90.95,30.89 91.28,31.22 93.02,31.22 v1(93.37,30.87) ; v3(37.92,40.08) 38.38,39.63 38.38,38.07 38.14,37.84 38.14,35.41 39.66,33.9 39.66,32.56 v1(40.71,31.52) ; v1(58.32,21.16) 58.6,20.88 59.68,20.88 60.12,21.32 60.12,21.58 64.2,25.65 73.54,25.65 v1(73.91,25.28)
SPI_IO2: length 101.3
  TOP w0.102: R542.1 87.75,52.96 v1(86.94,52.96) 86.94,46.12 84.82,44.01 84.82,28.59 v1(84.79,28.55) ; R512.1 82.83,52.22 v1(83.57,52.96) ; v3(38.86,31.93) 38.72,31.93 36.96,33.69 36.96,36.4 U29.U40 ; v1(88.19,28.32) 88.19,25.79 R504.2
  BOTTOM w0.102: v1(88.19,28.32) 87.96,28.55 v1(84.79,28.55) 83.01,28.55 80.57,26.11 76.99,26.11 76,27.1 75.41,27.1 74.83,27.69 72.75,27.69 72.16,27.1 63.02,27.1 59.73,23.81 59.73,23.81 58.6,22.68 54.27,22.68 52.72,21.13 47.75,21.13 46.36,22.53 44.96,22.53 41.83,25.65 41.39,25.65 40.11,26.93 40.11,30.91 39.09,31.93 v3(38.86,31.93) ; v1(86.94,52.96) 86.94,52.96 v2(85.7,52.96) v1(83.57,52.96)
SPI_IO3: length 78.6
  TOP w0.102: RN60.4 80.58,26.45 80.87,26.75 v1(80.87,27.1) ; v1(91.82,27.36) 91.54,27.36 90.9,26.72 RN62.4 90.9,26.2 90.63,25.93 89.37,25.93 R631.2 ; v3(37.96,38.75) 37.79,38.75 37.29,38.25 U29.U37
  BOTTOM w0.102: v1(91.82,27.36) 91.03,28.14 89.02,28.14 88.11,29.06 82.83,29.06 v1(80.87,27.1) 80.14,27.1 v2(79.76,26.72) 79.5,26.47 76.96,26.47 76.1,27.33 75.51,27.33 74.93,27.91 72.62,27.91 72.03,27.33 62.93,27.33 58.51,22.91 54.18,22.91 52.63,21.36 47.85,21.36 46.45,22.75 45.09,22.75 41.96,25.88 41.48,25.88 40.56,26.8 40.56,29.73 41.08,30.25 41.08,30.61 40.82,30.87 40.72,30.87 39.88,31.72 39.88,32.06 39.46,32.48 39.46,33.81 37.94,35.33 37.94,38.74 v3(37.96,38.75)
SPI_MISO: length 96.7
  TOP w0.102: R610.1 84.2,53.09 v1(84.58,53.47) 85.04,53.01 85.04,45.52 83.54,44.02 83.54,34.07 83.18,33.71 v1(83.18,33.69) ; v3(37.96,39.39) 37.46,38.89 U29.R36 ; v1(73.05,25.2) 73.77,25.92 75.17,25.92 76.45,27.2 76.45,28.68 77.85,30.08 77.85,33.48 v1(78.05,33.69) ; v1(60.35,20.9) 60.1,20.65 58.06,20.65 57.2,21.51 46.02,21.51 41.55,25.98 41.55,29.52 40.65,30.43 v1(40.64,30.43) ; R612.1 88.17,53.58 v1(87.55,53.58)
  BOTTOM w0.102: v3(37.96,39.39) 37.96,39.35 37.54,38.93 37.54,35.45 39.24,33.74 39.24,32.25 39.67,31.82 39.67,31.63 40.39,30.91 40.39,30.67 v1(40.64,30.43) ; v1(73.05,25.2) 64.06,25.2 60.35,21.49 v1(60.35,20.9) ; v1(78.05,33.69) v2(80.01,33.69) v1(83.18,33.69) ; v1(84.58,53.47) 84.69,53.58 v1(87.55,53.58)
SPI_MISO_ROM_1: length 14.5
  TOP w0.102: U30CN1.2 81.15,44.68 81.25,44.78 82.96,44.78 83.06,44.88 83.06,45.57 83.16,45.67 83.44,45.67 83.54,45.57 83.54,45.12 83.64,45.02 83.9,45.02 84,45.12 84,45.87 84.1,45.97 v1(84.57,45.97) 84.57,46.87 84.47,46.98 84.12,46.98 84.02,47.08 84.02,47.48 84.12,47.59 84.47,47.59 84.57,47.69 84.57,48.09 84.47,48.2 84.12,48.2 84.02,48.3 84.02,48.7 84.12,48.81 84.47,48.81 84.57,48.91 84.57,49.31 84.47,49.41 84.12,49.41 84.02,49.52 84.02,49.92 84.12,50.02 84.47,50.02 84.57,50.13 84.57,50.8 R610.2
SPI_MISO_ROM_2: length 13.3
  TOP w0.102: R612.2 89.79,50.22 89.69,50.12 89.18,50.12 89.08,50.02 89.08,49.61 89.18,49.51 89.69,49.51 89.79,49.41 89.79,49 89.69,48.9 89.18,48.9 89.08,48.8 89.08,48.39 89.18,48.29 89.69,48.29 89.79,48.19 89.79,47.74 89.29,47.24 89.29,47.06 89.54,46.81 89.72,46.81 90.22,47.3 90.36,47.3 90.65,47.02 90.65,46.87 90.27,46.49 90.27,46.31 90.52,46.06 90.7,46.06 91.08,46.44 91.23,46.44 v1(91.44,46.23) U35CN1.2
SPI_MOSI: length 102.7
  TOP w0.102: R505.2 78.36,26.47 78.23,26.34 77.83,26.34 77.7,26.21 v1(77.7,25.59) ; v1(58.95,22.01) 58.71,22.25 46.25,22.25 46.13,22.38 46.13,22.76 46.25,22.89 46.51,22.89 46.63,23.01 46.63,23.34 46.51,23.47 45.59,23.47 45.47,23.6 45.47,25.95 45.2,26.21 43.94,27.47 43.94,27.64 44.06,27.76 44.23,27.76 45.05,26.93 45.2,26.93 45.34,27.08 45.34,27.22 43.91,28.66 43.91,29.63 42.75,30.78 42.15,30.78 41.76,31.17 41.76,31.38 40.93,32.21 39.98,32.21 39.63,32.56 39.63,32.7 39.78,32.85 39.78,32.99 39.63,33.14 39.49,33.14 39.34,32.99 39.2,32.99 39.05,33.13 39.05,33.28 39.2,33.42 39.2,33.57 39.06,33.71 38.91,33.71 38.63,33.43 38.3,33.43 37.78,33.94 37.78,36.66 U29.P40 ; R629.2 89,26.9 v1(88.67,26.57)
  BOTTOM w0.102: v1(58.95,22.01) 59.17,21.79 59.59,21.79 62.07,24.28 62.07,24.44 61.95,24.56 61.78,24.56 60.75,23.54 60.59,23.54 60.47,23.66 60.47,23.83 62.04,25.4 62.72,25.4 63.4,26.08 63.4,26.77 63.5,26.87 63.7,26.87 63.81,26.77 63.81,26.21 63.91,26.11 64.14,26.11 64.25,26.21 64.25,26.77 64.35,26.87 64.55,26.87 64.65,26.77 64.65,26.21 64.75,26.11 64.96,26.11 65.06,26.21 65.06,26.77 65.16,26.87 65.36,26.87 65.47,26.77 65.47,26.21 65.57,26.11 65.77,26.11 65.87,26.21 65.87,26.77 65.97,26.87 66.18,26.87 66.28,26.77 66.28,26.21 66.38,26.11 66.58,26.11 66.69,26.21 66.69,26.77 66.79,26.87 66.99,26.87 67.09,26.77 67.09,26.21 67.19,26.11 67.4,26.11 67.5,26.21 67.5,26.77 67.6,26.87 67.8,26.87 67.91,26.77 67.91,26.21 68.01,26.11 68.21,26.11 68.31,26.21 68.31,26.77 68.41,26.87 68.62,26.87 68.72,26.77 68.72,26.21 68.82,26.11 69.02,26.11 69.13,26.21 69.13,26.77 69.23,26.87 69.43,26.87 69.53,26.77 69.53,26.21 69.63,26.11 69.84,26.11 69.94,26.21 69.94,26.77 70.04,26.87 70.24,26.87 70.35,26.77 70.35,26.21 70.45,26.11 70.65,26.11 70.75,26.21 70.75,26.77 70.85,26.87 71.06,26.87 71.16,26.77 71.16,26.21 71.26,26.11 71.46,26.11 71.57,26.21 71.57,26.77 71.67,26.87 71.87,26.87 71.97,26.77 71.97,26.21 72.07,26.11 72.45,26.11 72.76,26.42 72.76,26.7 72.89,26.82 73.48,26.82 73.61,26.7 73.61,26.06 73.74,25.93 73.92,25.93 74.02,26.04 74.02,26.72 74.12,26.82 74.33,26.82 74.43,26.72 74.43,26.04 74.53,25.93 74.73,25.93 74.84,26.04 74.84,26.72 74.94,26.82 75.14,26.82 75.24,26.72 75.24,26.04 75.34,25.93 75.55,25.93 75.65,26.04 75.65,26.72 75.75,26.82 75.95,26.82 76.06,26.72 76.06,26.04 76.28,25.81 76.28,25.65 76.16,25.53 74.49,25.53 74.37,25.41 74.37,25.24 74.49,25.12 v2(76.81,25.12) 77.6,25.12 77.7,25.22 v1(77.7,25.59) 78.02,25.27 78.56,25.27 78.82,25.53 80.39,25.53 82.6,27.74 87.5,27.74 v1(88.67,26.57)
SPI_MOSI_1: length 12.9
  TOP w0.102: R505.1 78.79,28.49 78.79,31.14 78.89,31.24 80.09,31.24 80.19,31.34 80.19,32.18 80.09,32.28 v1(78.61,32.28) 78.61,33.32 78.71,33.43 79.81,33.43 79.91,33.53 79.91,34.04 79.81,34.14 78.71,34.14 78.61,34.24 U30CN1.5
SPI_MOSI_2: length 13
  TOP w0.102: R629.1 89,28.93 v1(89.25,29.18) 89.38,29.31 89.38,29.92 89.28,30.02 88.34,30.02 88.21,30.15 88.21,30.53 88.34,30.66 89.28,30.66 89.38,30.76 89.38,31.14 89.28,31.24 88.47,31.24 88.37,31.34 88.37,31.75 88.47,31.85 89.28,31.85 89.38,31.95 89.38,32.28 89.28,32.38 88.75,32.38 88.65,32.49 88.65,32.84 88.75,32.94 89.28,32.94 89.38,33.05 89.38,34.54 89.28,34.65 89,34.65 88.9,34.75 U35CN1.5
SPI_WP_N_1: length 13.6
  TOP w0.102: U30CN1.3 79.88,45.62 80.01,45.75 80.29,45.75 80.42,45.62 80.42,45.47 80.54,45.34 80.82,45.34 80.95,45.47 80.95,45.67 81.08,45.8 81.43,45.8 81.56,45.67 81.56,45.47 81.69,45.34 v1(82.3,45.34) 82.83,45.87 82.83,47.09 82.73,47.19 82.45,47.19 82.32,47.32 82.32,47.67 82.45,47.8 82.73,47.8 82.83,47.9 82.83,48.31 82.73,48.41 82.45,48.41 82.32,48.54 82.32,48.89 82.45,49.02 82.73,49.02 82.83,49.12 82.83,49.53 82.73,49.63 82.45,49.63 82.32,49.76 82.32,50.11 82.45,50.24 82.73,50.24 82.83,50.34 R512.2
SPI_WP_N_2: length 12.9
  TOP w0.102: U35CN1.3 90.17,44.45 89.47,45.15 89.47,45.29 89.86,45.68 89.86,45.85 89.61,46.11 89.43,46.11 89.04,45.72 88.9,45.72 v1(88.52,46.1) 88.52,47.22 88.42,47.32 87.91,47.32 87.78,47.44 87.78,47.8 87.91,47.93 88.42,47.93 88.52,48.03 88.52,48.44 88.42,48.54 87.96,48.54 87.83,48.66 87.83,49.02 87.96,49.15 88.42,49.15 88.52,49.25 88.52,49.65 88.42,49.76 88.01,49.76 87.88,49.88 87.88,50.24 88.01,50.37 88.63,50.37 88.75,50.49 R542.2
SPKR: length 88
  TOP w0.305: v1(58.78,23.95) 58.22,23.95 58.08,23.81 R701.2 R649.1 ; v1(62.26,27.31) 59.07,30.51 58,30.51 56.29,32.22 56.29,36.35 55.42,37.21 55.42,44.25 61.34,50.16 v1(63.65,50.16) ; v1(64.11,56.87) 63.6,56.87 61.1,59.37 R648.1 ; v3(38.03,41.43) 37.72,41.43 37.36,41.07 U29.R32
  BOTTOM w0.203: 38.88,38.19 38.64,38.43 38.64,39.86 38.58,39.92 38.58,40.88 v3(38.03,41.43)
  BOTTOM w0.305: v1(62.26,27.31) 61.71,27.31 v2(59.87,25.48) 59.49,25.1 59.49,24.66 v1(58.78,23.95) 58.06,23.24 54.04,23.24 52.49,21.69 48.23,21.69 46.84,23.08 45.23,23.08 42.1,26.21 41.62,26.21 40.89,26.94 40.89,29.59 41.24,29.93 41.38,30.08 41.38,30.74 41.25,30.87 41.25,31.75 39.97,33.03 39.97,34.02 39.05,34.94 39.05,37.42 39.08,37.45 39.08,37.98 38.88,38.19 ; v1(64.11,56.87) 64.29,56.69 64.29,50.8 v1(63.65,50.16)
SST_CTL_R: length 22.9
  TOP w0.102: R579.2 12.88,36.18 12.88,36.74 13.59,37.45 13.59,38.05 13.78,38.24 16.75,38.24 v1(16.94,38.05) ; U29.AJ31 29.89,41.87 v3(30.23,42.21)
  BOTTOM w0.102: v3(30.23,42.21) 30.19,42.16 29.2,42.16 28.51,41.48 28.51,41.19 28.27,40.94 28.02,40.94 27.42,40.34 27.42,40.12 26.72,39.42 v2(26.24,39.42) 26.09,39.27 22.6,39.27 22.48,39.15 20.85,39.15 19.82,38.13 18.82,38.13 18.26,37.57 17.42,37.57 v1(16.94,38.05)
SST_HOLDJ_1: length 13.3
  TOP w0.102: U30CN1.7 81.15,34.7 81.28,34.57 81.89,34.57 81.99,34.47 81.99,34.11 81.89,34.01 81.28,34.01 81.15,33.88 81.15,33.55 81.28,33.43 81.86,33.43 81.99,33.3 81.99,32.74 81.86,32.61 v1(81.58,32.61) 81.58,32.08 81.68,31.98 81.89,31.98 81.99,31.88 81.99,31.47 81.89,31.37 81.68,31.37 81.58,31.27 81.58,30.86 81.68,30.76 81.89,30.76 81.99,30.66 81.99,30.25 81.89,30.15 81.68,30.15 81.58,30.05 81.58,29.64 81.68,29.54 81.89,29.54 81.99,29.44 81.99,29.03 81.89,28.93 81.81,28.93 81.7,28.82 R507.2 81.28,27.65 RN60.1
SST_HOLDJ_2: length 13.3
  TOP w0.102: RN62.1 90.9,27.91 91.08,28.09 92.04,28.09 R630.2 92.14,28.94 v1(91.97,29.11) 91.44,29.64 91.44,31.29 91.54,31.4 92.13,31.4 92.23,31.5 92.23,31.9 92.13,32.01 91.54,32.01 91.44,32.11 91.44,32.51 91.54,32.62 92.13,32.62 92.23,32.72 92.23,33.12 92.13,33.22 91.54,33.22 91.44,33.33 91.44,33.73 91.54,33.83 92.13,33.83 92.23,33.94 92.23,34.34 92.13,34.44 91.54,34.44 91.44,34.55 U35CN1.7
SUS_LED4: length 6.6
  TOP w0.102: Q71.B 20.21,10.88 20.56,10.53 v1(21.08,10.53) 21.48,10.53 22.33,11.38 22.33,11.91 22.68,12.27 24.27,12.27 24.7,12.7 R767.1
SUS_LED5: length 3
  TOP w0.102: Q72.B 23.14,11.22 v1(23.14,11.81) 24.7,11.81 R737.1
SUS_LED6: length 3.7
  TOP w0.102: Q71.E 20.44,13.61 v1(20.75,13.61) 21.16,13.61 21.58,13.2 Q72.C
SUS_STAT_N: length 6.7
  TOP w0.102: R594.1 v1(33.4,33.58) 33.4,34.17 33.17,34.4 33.17,36.02 33.13,36.06 33.13,36.38 33.17,36.41 33.17,36.83 arc(33.15,36.92) 33.11,36.99 33.11,37.86 U29.AD37
SUS_WARN_5VDUAL: length 4.7
  TOP w0.102: R769.2 176.23,30.92 Q70.C ; R769.2 174.38,30.92 v2(174.02,30.56) ; R769.2 R823.2
SUS_WARN_5VDUAL_L: length 3.5
  TOP w0.102: R824.2 R823.1 175.95,33.62 v2(176.12,33.79) 176.21,33.88 Q49.4
SUS_WARNB: length 189.5
  TOP w0.102: R762.1 180.17,29.34 176.58,29.34 v1(176.57,29.32) ; v1(153.31,25.7) 156.13,25.7 156.87,26.44 156.88,26.44 156.95,26.52 162.62,26.52 162.7,26.59 163.08,26.59 163.21,26.47 168.43,26.47 v1(168.48,26.42) ; R666.1 97.16,4.19 v1(96.9,3.94) ; v1(55.06,7.47) 55.06,8.26 52.37,10.95 49.8,10.95 41.47,19.28 34.5,19.28 30.35,23.43 30.35,27.51 30.12,27.73 30.12,29.69 30.1,29.71 30.1,33.4 30.35,33.66 30.35,35.03 30.78,35.46 30.78,36.12 U29.AG41
  BOTTOM w0.102: v1(153.31,25.7) 152.65,25.7 139.76,12.81 137.67,12.81 130.16,5.31 115.76,5.31 114.59,4.14 102.34,4.14 101.55,3.35 97.49,3.35 v1(96.9,3.94) 96.68,3.72 95.87,3.72 95.25,4.34 92.89,4.34 92.66,4.57 87.43,4.57 87.33,4.47 83.59,4.47 82.81,5.25 80.42,5.25 79.96,4.79 57.13,4.79 55.06,6.86 v1(55.06,7.47) ; v1(168.48,26.42) 168.48,30.1 169.34,30.96 v2(170.92,30.96) 174.93,30.96 v1(176.57,29.32)
SUS_WARNB_L: length 3.7
  TOP w0.102: R747.1 180.87,31.99 R762.2 180.28,30.33 v2(179.86,30.33) Q70.B
SUS_WARNB_R: length 5.7
  TOP w0.102: R666.2 v2(97.16,6.99) 98.07,7.9 98.96,7.9 100.07,9.01 U61.25
SUSACK_N: length 92.2
  TOP w0.102: v1(54.2,7.47) 54.2,8.26 51.99,10.46 49.85,10.46 41.34,18.98 34.25,18.98 30.04,23.18 30.04,27.38 29.82,27.6 29.82,29.85 29.9,29.93 29.9,33.49 30.15,33.74 30.15,35.14 30.55,35.54 30.55,36.22 30.58,36.37 30.64,36.46 30.69,36.5 30.69,36.85 30.69,36.85 30.68,36.93 30.68,36.93 30.63,37.04 30.5,37.32 30.5,37.94 U29.AJ37 ; R702.1 87.46,15.91 86.85,15.91 86.44,15.49 86.44,6.86 84.33,4.75 v1(82.58,4.75)
  BOTTOM w0.102: v1(82.58,4.75) 82.56,4.77 80.62,4.77 80.16,4.31 56.84,4.31 v2(55.22,5.94) 54.2,6.96 v1(54.2,7.47)
SUSCLK: length 17.1
  TOP w0.102: v3(35.73,38.69) 35.7,38.69 35.5,38.9 U29.W36 ; R2215.1 38.61,24.07 38.61,24.9 39.03,25.32 39.03,28.65 36.19,31.49 v1(36.06,31.49)
  BOTTOM w0.102: v1(36.06,31.49) 35.76,31.79 v2(35.76,33.07) 35.76,37.42 35.65,37.53 35.65,37.88 35.73,37.96 v3(35.73,38.69)
SW_ON_N: length 290.3
  TOP w0.102: R637.1 v1(192.15,139.83) ; v1(104.22,7.09) 103.86,7.09 103.5,6.73 R727.2 103.44,6.03 102.92,5.51 102.92,5.5 102.76,5.33 102.68,5.33 R720.2 102.49,3.68 101.93,3.12 95.33,3.12 v1(95.22,3.23) ; U29.AK41 29.47,35.88 29.33,35.74 29.33,34.08 27.56,32.3 27.56,30.66 27.41,30.51 27.41,29.97 27.51,29.86 27.51,29.38 28.94,27.95 28.94,27.54 29.38,27.11 29.38,22.91 30.12,22.16 30.12,21.36 32.61,18.87 33.24,18.87 33.8,18.31 41.07,18.31 49.81,9.58 51.13,9.58 52.45,8.26 v1(52.45,7.47)
  BOTTOM w0.102: v1(95.22,3.23) 95.05,3.4 93.19,3.4 93.04,3.25 80.45,3.25 80.23,3.47 56.22,3.47 52.45,7.24 v1(52.45,7.47) ; v1(192.15,139.83) 191.83,139.51 191.83,138.37 192.45,137.75 192.45,130.61 191.63,129.78 191.63,127.47 v2(188.89,124.73) 187.91,123.75 187.91,119.03 186.51,117.64 186.51,107.6 186.89,107.23 186.89,88.34 181.64,83.08 181.64,71.86 176.63,66.85 174.29,66.85 166.13,58.69 166.13,58.24 158.93,51.04 158.93,36.69 138.38,16.14 136.05,16.14 134.54,14.64 134.54,13.27 129.07,7.8 114.02,7.8 112.85,6.63 104.67,6.63 v1(104.22,7.09)
SYS_EUP_CTRL: length 4.2
  TOP w0.102: U61.27 100.87,8.47 v2(100.66,8.26) 100.13,7.72 100.13,6.11 R680.2
SYS_FAN_CTRL_SIO: length 5
  TOP w0.165: TP169.1 93.17,17.09 94.26,16 U61.4
SYS_FAN_TACH_SIO: length 2.5
  TOP w0.165: TP168.1 93.75,17.12 94.47,16.4 U61.3
SYS_TEMP_SIO: length 78.3
  TOP w0.203: U61.45 106.86,16
  TOP w0.254: v1(68.2,19.88) 68.2,20.01 68.45,20.27 68.45,20.7 64.26,24.89 63.21,24.89 58.64,29.46 57.57,29.46 55.24,31.79 55.24,35.92 53.34,37.82 53.34,41.44 C498.1 53.3,42.32 Q61.B 52.79,43.76 Q61.C ; 106.86,16 v1(106.86,15.99)
  BOTTOM w0.254: v1(68.2,19.88) 68.71,20.4 79.53,20.4 80.6,19.33 83.71,19.33 84.7,18.34 89.67,18.34 89.95,18.06 90.84,18.06 91.75,17.14 96.38,17.14 96.91,16.61 98.53,16.61 99.35,17.44 ; v2(99.11,17.68) 99.35,17.44 ; 99.35,17.44 100.23,18.31 103.99,18.31 106.34,15.96 106.84,15.96 v1(106.86,15.99)
TCM_BA0: length 3.8
  TOP w0.102: U23.9 U22.9 98.48,62.34 98.71,62.57 v1(99.05,62.57) 99.05,62.9 99.54,63.4 R457.1
TCM_BA1: length 6.5
  TOP w0.102: U23.3 U22.3 102.38,62.14 102.6,62.36 103.78,62.36 105.08,63.65 v2(105.08,63.93) R476.1
TCM_CLK_RUN: length 3.8
  TOP w0.102: R438.1 92.64,54.8 v2(93.46,54.8) U23.15 U22.15
TCM_NC5#: length 8
  TOP w0.102: U23.5 U22.5 101.08,61.9 101.84,62.66 103.53,62.66 104.11,63.25 C400.1 v2(103.05,65.11)
TCM_NCP: length 6.7
  TOP w0.102: C381.1 95.23,59.7 U23.14 U22.14 95.23,61.99 94.72,62.51 v2(94.72,63.4)
TD_IREF: length 5.4
  TOP w0.102: v1(43.18,59.31) 43.18,60.2 43.81,60.83 R133.2 ; v3(43.18,56.59) 43.26,56.51 U29.C3
  BOTTOM w0.102: v1(43.18,59.31) 43.19,59.3 v2(43.19,57.76) 43.18,57.75 v3(43.18,56.59)
TESTLOW_1: length 34.6
  TOP w0.102: U27.P6 v1(100.68,156.36) ; R798.1 73.38,160.73 v2(73.38,160.73) 73.39,160.73 86.15,160.73 88.34,158.53 88.34,155.3 88.85,154.79 89.46,154.79 v1(89.89,155.22)
  BOTTOM w0.102: v1(89.89,155.22) 90.17,155.5 92.48,155.5 93.29,156.31 98.31,156.31 98.71,155.91 100.24,155.91 v1(100.68,156.36)
TESTLOW_2: length 30.7
  TOP w0.102: U27.N5 v1(99.77,156.36) ; R804.1 72.05,159.7 v2(74.65,159.7) 84.2,159.7 v1(87.76,156.14)
  BOTTOM w0.102: v1(87.76,156.14) 88.14,156.14 88.57,155.7 92.4,155.7 93.21,156.51 97.87,156.51 98.17,156.82 99.29,156.82 99.75,156.36 v1(99.77,156.36)
TP_CPU_G38: length 27.6
  TOP w0.102: U27.G38 v1(132.14,161.84)
  BOTTOM w0.102: TP103.1 157.2,160.81 136.45,160.81 134.97,162.29 132.87,162.29 132.43,161.84 v1(132.14,161.84)
TP_CPU_H37: length 25.9
  TOP w0.102: U27.H37 v1(132.14,160.93)
  BOTTOM w0.102: v1(132.14,160.93) 132.6,161.39 133.25,161.39 133.44,161.58 135.11,161.58 136.33,160.35 156.13,160.35 TP107.1
TP_CPU_H38: length 26.9
  TOP w0.102: U27.H38 v1(133.06,160.93)
  BOTTOM w0.102: TP108.1 157.33,159.28 156.45,159.28 155.66,160.07 136.33,160.07 135.02,161.37 133.56,161.37 133.34,161.16 133.29,161.16 v1(133.06,160.93)
TP_CPU_J38: length 25.1
  TOP w0.102: U27.J38 v1(133.06,160.02)
  BOTTOM w0.102: TP109.1 155.27,159.84 136.27,159.84 135.65,160.46 133.5,160.46 v1(133.06,160.02)
TP_CPU_K37: length 5.7
  TOP w0.102: U27.K37 v1(132.14,159.1)
  BOTTOM w0.102: v1(132.14,159.1) U27.K37 131.69,158.02 131.4,157.73 130.64,157.73 129.74,156.83 128.89,156.83 TP111.1
TP_CPU_K39: length 21.5
  TOP w0.102: U27.K39 v1(133.06,159.1)
  BOTTOM w0.102: TP110.1 153.19,159.1 v1(133.06,159.1)
TP_CPU_M38: length 24.9
  TOP w0.102: U27.M38 v1(133.06,157.27)
  BOTTOM w0.102: TP113.1 155.88,156.46 154.03,156.46 153.08,157.41 133.78,157.41 133.64,157.27 v1(133.06,157.27)
TP_CPU_N36: length 6.3
  TOP w0.102: U27.N36 v1(130.32,156.36)
  BOTTOM w0.102: TP165.1 127.52,153.11 127.54,153.11 127.8,153.37 127.8,153.82 130.32,156.34 v1(130.32,156.36)
TP_CPU_T35: length 6
  TOP w0.102: v1(130.32,153.61) U27.T35
  BOTTOM w0.102: v1(130.32,153.61) 130.05,153.61 129.59,153.16 129.08,153.16 128.83,152.91 128.37,152.91 127.93,152.46 127.93,151.64 127.67,151.38 127.25,151.38 TP112.1
TP_DISP_J12: length 3.7
  TOP w0.102: U27.J12 v1(107.08,160.02)
  BOTTOM w0.102: v1(107.08,160.02) 107.08,159.33 107.53,158.89 107.53,158 107.19,157.67 TP76.1
TP_DISP_K11: length 3.3
  TOP w0.102: U27.K11 v1(105.26,160.02)
  BOTTOM w0.102: v1(105.26,160.02) 105.73,159.54 105.73,157.59 TP77.1
TP_H_CATERR_N: length 6.5
  TOP w0.102: U27.M36 v1(131.23,157.27)
  BOTTOM w0.102: v1(131.23,157.27) 130.58,157.27 129.86,156.55 129.86,156.17 128.68,154.99 126.77,154.99 TP166.1
TP_PCH_AE30: length 1.6
  TOP w0.102: U29.AE30 32.01,42.24 31.56,42.24 v3(31.5,42.18)
  BOTTOM w0.102: v3(31.5,42.18) 32.12,42.8 TP41.1
TP_PCH_AN16: length 8
  TOP w0.102: U29.AW23 24.35,45.95 23.23,45.95 21.45,47.73 20.67,47.73 19.74,48.66 19.74,49.24 18.76,50.22 TP56.1
TP_PCH_AT26: length 11.6
  TOP w0.102: TP50.1 16.93,50.22 17.35,49.8 17.35,49.72 18.05,49.02 18.47,49.02 20.46,47.04 21.12,47.04 23.05,45.11 24.58,45.11 24.82,44.87 25.82,44.87 U29.AT26
TP_PCH_AV22: length 5.3
  TOP w0.102: TP53.1 20.99,49.05 23.32,46.72 24.83,46.72 U29.AV22
TP_PCH_P19: length 1.7
  TOP w0.102: v3(37.3,48.64) 37.7,48.24 U29.P19
  BOTTOM w0.102: v3(37.3,48.64) 36.57,47.92 TP51.1
TP_PCH_TACH2: length 18.1
  TOP w0.102: v1(13.71,41.61) 13.14,42.17 R647.1 ; U29.AM28 28.55,42.89 v3(28.32,42.65)
  BOTTOM w0.102: v1(13.71,41.61) 14.53,42.42 17.53,42.42 18.29,43.18 v2(21.31,43.18) 21.82,43.18 22.88,42.12 23.47,42.12 24,42.66 26.54,42.66 26.91,43.02 27.87,43.02 28.24,42.65 v3(28.32,42.65)
TP_PCH_TACH3: length 11.1
  TOP w0.102: R679.1 15.89,36.75 16.51,36.75 16.76,37.01 v2(17.35,37.01) 18.11,37.01 18.16,37.06 18.18,37.06 19.42,38.3 19.66,38.3 20.53,39.17 21.61,39.17 22.36,39.92 24.57,39.92 24.77,40.12 U29.AV34
TP_PEG_A4: length 2.3
  TOP w0.102: v1(98.83,168.28) 98.83,168.27 U27.A4
  BOTTOM w0.102: v1(98.83,168.28) 98.37,168.75 TP79.1
TP_PEG_B3: length 3.9
  TOP w0.102: U27.B3 98.4,167.95 v1(98.07,168.28)
  BOTTOM w0.102: TP78.1 96.28,168.26 98.05,168.26 v1(98.07,168.28)
TP_PEG_C2: length 6.5
  TOP w0.102: U27.C2 97.48,167.24 v1(97.86,167.62)
  BOTTOM w0.102: v1(97.86,167.62) 97.6,167.62 97.17,168.05 95.26,168.05 94.92,168.4 TP36.1
TP_PEG_D1: length 5
  TOP w0.102: U27.D1 96.57,167.19 v1(96.98,167.6)
  BOTTOM w0.102: TP35.1 96.93,167.64 v1(96.98,167.6)
TP_RSVD_AB6: length 4.4
  TOP w0.102: v1(101.6,149.04) U27.AB6
  BOTTOM w0.102: v1(101.6,149.04) 102.04,148.6 104.51,148.6 TP167.1
TP_RSVD_AB33: length 1.7
  TOP w0.102: U27.AB33 v1(127.57,147.21)
  BOTTOM w0.102: v1(127.57,147.21) 127.57,148.03 TP125.1
TP_RSVD_AB36: length 28.2
  TOP w0.102: U27.AB36 130.78,147.67 131.14,148.03 133.33,148.03 133.96,148.66 135.45,148.66 139.12,152.33 150.69,152.33 TP126.1
TP_RSVD_AC8: length 2.3
  TOP w0.102: U27.AC8 v1(103.43,147.21)
  BOTTOM w0.102: v1(103.43,147.21) 104.38,147.21 TP129.1
TP_RSVD_AK20: length 2.6
  TOP w0.102: U27.AK20 v1(116.6,140.81)
  BOTTOM w0.102: v1(116.6,140.81) 116.11,141.3 TP160.1
TP_RSVD_AT40: length 2.1
  TOP w0.102: v1(135.17,134.54) 134.84,134.87 U27.AT40
  BOTTOM w0.102: v1(135.17,134.54) 135.57,134.94 TP164.1
TP_RSVD_AU1: length 1.9
  TOP w0.102: v1(95.88,134.7) 96.4,134.7 U27.AU1
  BOTTOM w0.102: TP155.1 96.43,135.24 v1(95.88,134.7)
TP_RSVD_AU27: length 13.4
  TOP w0.102: U27.AU27 123.08,133.42 123.08,131.74 122.92,131.58 122.92,130.9 123.07,130.74 123.07,128.74 122.63,128.29 122.63,127.99 122.3,127.66 122.03,127.66 121.71,127.34 121.71,126.96 121.72,126.95 121.72,126.41 123.32,124.82 v1(123.32,123.29)
  BOTTOM w0.102: TP154.1 v1(123.32,123.29)
TP_RSVD_AU39: length 4.1
  TOP w0.102: v1(135.48,132.39) 135.27,132.39 133.71,133.96 U27.AU39
  BOTTOM w0.102: v1(135.48,132.39) 136.29,131.59 TP153.1
TP_RSVD_AV1: length 1.9
  TOP w0.102: U27.AV1 95.97,133.36 v1(95.9,133.36)
  BOTTOM w0.102: v1(95.9,133.36) 95.53,133.36 TP128.1
TP_RSVD_AV2: length 1.8
  TOP w0.102: U27.AV2 96.91,133.39 v1(96.91,133.38)
  BOTTOM w0.102: TP139.1 97.81,133.38 v1(96.91,133.38)
TP_RSVD_AV20: length 11.1
  TOP w0.102: v1(116.7,123.17) 116.7,131.48 116.14,132.04 U27.AV20
  BOTTOM w0.102: TP32.1 116.71,123.16 v1(116.7,123.17)
TP_RSVD_AV24: length 2.8
  TOP w0.102: v1(119.34,132.57) 119.34,132.6 119.78,133.04 U27.AV24
  BOTTOM w0.102: TP152.1 120.16,132.57 v1(119.34,132.57)
TP_RSVD_AV29: length 10.9
  TOP w0.102: v1(125.19,124.28) 125.22,124.28 125.58,124.64 125.58,128.98 124.79,129.77 124.79,132.62 U27.AV29
  BOTTOM w0.102: v1(125.19,124.28) 125.32,124.14 TP151.1
TP_RSVD_AW2: length 1.9
  TOP w0.102: U27.AW2 97.02,132.57 v1(97.02,132.39)
  BOTTOM w0.102: v1(97.02,132.39) 97.02,131.67 TP127.1
TP_RSVD_AW12: length 3.5
  TOP w0.102: v1(108.07,129.91) 108.07,130.53 108.48,130.94 108.48,131.78 U27.AW12
  BOTTOM w0.102: v1(108.07,129.91) 108.07,129.74 TP34.1
TP_RSVD_AW23: length 4.8
  TOP w0.102: v1(118.7,129.76) 118.7,129.77 119.22,130.3 119.22,131.68 118.89,132.02 U27.AW23
  BOTTOM w0.102: TP150.1 119.35,131.21 119.35,130.41 v1(118.7,129.76)
TP_RSVD_AW24: length 4.8
  TOP w0.102: U27.AW24 119.71,132.13 119.46,131.87 119.46,129.72 118.75,129.01 v1(118.75,128.99)
  BOTTOM w0.102: v1(118.75,128.99) 119.39,128.35 TP149.1
TP_RSVD_AW27: length 4.8
  TOP w0.102: v1(122.14,128.88) 122.3,129.04 122.3,129.78 121.94,130.14 121.94,130.97 121.97,131 121.97,131.52 122.54,132.09 U27.AW27
  BOTTOM w0.102: v1(122.14,128.88) 122.61,129.35 TP33.1
TP_RSVD_AY18: length 1.8
  TOP w0.102: v1(114.53,130.46) 114.53,131 U27.AY18
  BOTTOM w0.102: TP148.1 114.28,130.22 v1(114.53,130.46)
TP_RSVD_C39: length 21.5
  TOP w0.102: v1(134.29,165.93) 134.25,165.89 134.19,165.89 133.52,165.22 U27.C39
  BOTTOM w0.102: TP147.1 139.61,164.07 137.75,165.93 v1(134.29,165.93)
TP_RSVD_H12: length 3.8
  TOP w0.102: U27.H12 v1(107.08,160.93)
  BOTTOM w0.102: v1(107.08,160.93) 107.08,160.92 107.54,160.46 107.54,159.67 107.87,159.34 107.87,158.44 TP159.1
TP_RSVD_H14: length 6.4
  TOP w0.102: v1(108.91,160.92) 108.46,161.37 U27.H14
  BOTTOM w0.102: v1(108.91,160.92) 109.37,160.46 109.37,158.22 109.53,158.06 109.53,158.04 110.05,157.52 110.08,157.52 110.34,157.26 110.34,155.82 TP138.1
TP_RSVD_H15: length 5.9
  TOP w0.102: U27.H15 v1(109.83,161.84)
  BOTTOM w0.102: TP136.1 110.72,157.4 110.72,160.12 109.83,161.01 v1(109.83,161.84)
TP_RSVD_H16: length 4.6
  TOP w0.102: v1(110.74,161.84) U27.H16
  BOTTOM w0.102: TP135.1 111.2,158.62 111.2,161.39 v1(110.74,161.84)
TP_RSVD_J8: length 2.7
  TOP w0.102: v1(103.43,160.93) U27.J8
  BOTTOM w0.102: v1(103.43,160.93) U27.J8 102.97,159.49 TP131.1
TP_RSVD_J9: length 1.7
  TOP w0.102: v1(104.31,160.93) 104.29,160.91 104.29,160.91 104.27,160.88 104.27,160.85 U27.J9
  BOTTOM w0.102: TP137.1 104.22,160.84 v1(104.31,160.93)
TP_RSVD_J10: length 6
  TOP w0.102: v1(105.28,160.92) 105.28,160.91 104.84,160.47 U27.J10
  BOTTOM w0.102: v1(105.28,160.92) 105.28,160.84 104.8,160.36 104.8,156.36 TP141.1
TP_RSVD_J13: length 4.7
  TOP w0.102: U27.J13 v1(108,160.93)
  BOTTOM w0.102: TP143.1 109.18,158.14 109.17,158.15 109.17,158.22 108.46,158.93 108.46,160.47 v1(108,160.93)
TP_RSVD_J15: length 2.4
  TOP w0.102: U27.J15 v1(109.83,160.02)
  BOTTOM w0.102: TP158.1 110.07,159.78 v1(109.83,160.02)
TP_RSVD_J16: length 6.5
  TOP w0.102: U27.J16 v1(110.74,160.93)
  BOTTOM w0.102: TP134.1 112.43,156.25 111.82,156.86 111.82,157.25 111,158.07 111,160.68 v1(110.74,160.93)
TP_RSVD_J17: length 4.7
  TOP w0.102: U27.J17 v1(111.66,160.93)
  BOTTOM w0.102: TP157.1 112.11,157.4 112.11,160.47 v1(111.66,160.93)
TP_RSVD_J40: length 21
  TOP w0.102: v1(135.08,159.59) 135.05,159.56 U27.J40
  BOTTOM w0.102: TP156.1 154.31,159.38 135.28,159.38 v1(135.08,159.59)
TP_RSVD_K8: length 3.4
  TOP w0.102: U27.K8 v1(102.51,160.02)
  BOTTOM w0.102: TP140.1 102.14,157.85 102.14,159.64 v1(102.51,160.02)
TP_RSVD_K12: length 5.1
  TOP w0.102: U27.K12 v1(106.17,160.02)
  BOTTOM w0.102: TP142.1 106.63,156.59 106.63,159.57 106.18,160.02 v1(106.17,160.02)
TP_RSVD_K13: length 5.1
  TOP w0.102: U27.K13 v1(108,160.02)
  BOTTOM w0.102: TP130.1 108.9,156 108.64,156.25 108.64,157.54 108.67,157.56 108.67,158.43 108.23,158.87 108.23,159.79 v1(108,160.02)
TP_RSVD_L10: length 2.8
  TOP w0.102: U27.L10 v1(104.34,159.1)
  BOTTOM w0.102: v1(104.34,159.1) 103.76,158.52 103.76,157.48 TP118.1
TP_RSVD_L12: length 2.8
  TOP w0.102: v1(106.17,158.19) 106.18,158.19 U27.L12
  BOTTOM w0.102: TP120.1 106.22,156.6 106.22,157.78 106.17,157.83 v1(106.17,158.19)
TP_RSVD_M10: length 4.6
  TOP w0.102: v1(104.34,158.19) 104.37,158.16 104.37,158.15 104.79,157.73 U27.M10
  BOTTOM w0.102: TP117.1 103.44,155.74 103.87,156.17 103.87,156.41 104.5,157.05 104.5,157.49 104.34,157.65 v1(104.34,158.19)
TP_RSVD_M11: length 4.3
  TOP w0.102: v1(105.28,158.19) 105.33,158.14 105.33,158.11 U27.M11
  BOTTOM w0.102: TP119.1 105.03,154.8 105.03,157.94 v1(105.28,158.19)
TP_RSVD_N38: length 23.6
  TOP w0.102: v1(136.02,156.09) 135.98,156.06 134.98,156.06 134.67,156.36 133.06,156.36 U27.N38
  BOTTOM w0.102: TP145.1 154.55,154.28 152.74,156.09 v1(136.02,156.09)
TP_RSVD_P33: length 1.6
  TOP w0.102: U27.P33 v1(127.57,155.44)
  BOTTOM w0.102: TP123.1 127.41,155.6 v1(127.57,155.44)
TP_RSVD_P37: length 25.9
  TOP w0.102: U27.P37 v1(131.23,155.44)
  BOTTOM w0.102: TP144.1 154.36,155.8 152.98,157.18 133.86,157.18 133.47,156.79 132.54,156.79 131.23,155.49 v1(131.23,155.44)
TP_RSVD_R33: length 1.9
  TOP w0.102: v1(127.48,154.49) 127.61,154.49 U27.R33
  BOTTOM w0.102: TP122.1 126.68,153.68 v1(127.48,154.49)
TP_RSVD_R34: length 1.6
  TOP w0.102: U27.R34 v1(129.4,153.61)
  BOTTOM w0.102: v1(129.4,153.61) 128.44,153.61 TP163.1
TP_RSVD_R36: length 25.5
  TOP w0.102: U27.R36 v1(131.23,154.53)
  BOTTOM w0.102: TP146.1 153.14,154.81 131.51,154.81 v1(131.23,154.53)
TP_RSVD_T34: length 1.7
  TOP w0.102: U27.T34 v1(129.4,152.7)
  BOTTOM w0.102: v1(129.4,152.7) 128.92,152.7 TP162.1
TP_RSVD_U8: length 1.9
  TOP w0.102: U27.U8 v1(102.51,152.7)
  BOTTOM w0.102: TP124.1 103.19,153.38 v1(102.51,152.7)
TP_RSVD_V7: length 2.7
  TOP w0.102: U27.V7 v1(102.51,151.79)
  BOTTOM w0.102: TP161.1 103.9,151.78 102.52,151.78 v1(102.51,151.79)
TP_RSVD_W8: length 1.7
  TOP w0.102: U27.W8 v1(102.51,150.87)
  BOTTOM w0.102: TP121.1 102.66,151.02 v1(102.51,150.87)
TP_RSVD_Y8: length 1.9
  TOP w0.102: U27.Y8 v1(102.51,149.96)
  BOTTOM w0.102: v1(102.51,149.96) 103.33,149.96 TP116.1
TP_TPM_PIN6: length 4.8
  TOP w0.102: TP6.1 102.72,62.92 101.45,62.92 100.43,61.89 U22.6 U23.6
TP_TPM_PIN7: length 4.4
  TOP w0.102: TP7.1 101.61,63.4 100.95,62.74 100.23,62.74 99.78,62.29 U22.7 U23.7
TP_V_1P05_USBSUS_INT: length 1.5
  TOP w0.102: U29.AJ22 29.97,46.47 v3(30.41,46.02)
  BOTTOM w0.102: TP49.1 30.41,46.27 v3(30.41,46.02)
TPEV_CFG_RCOMP: length 22.7
  TOP w0.305: R797.1 156.46,158.97 v2(155.66,159.77) 154.96,160.47 U27.H40
TSD-_1: length 75.2
  TOP w0.254: R774.2 108.42,14.73 v1(107.67,15.48) ; Q61.E 54.19,42.27 C498.2 53.85,41.14 53.85,38.03 55.75,36.13 55.75,32 57.78,29.97 58.85,29.97 63.42,25.4 64.47,25.4 68.96,20.91 68.96,20.06 v1(69.16,19.86)
  BOTTOM w0.254: v1(107.67,15.48) 107.65,15.46 106.13,15.46 103.78,17.81 100.44,17.81 98.74,16.1 96.7,16.1 96.16,16.64 91.54,16.64 90.63,17.55 89.74,17.55 89.46,17.83 84.49,17.83 83.5,18.82 81.64,18.82 ; 81.64,18.82 80.39,18.82 79.32,19.89 69.14,19.89 v1(69.16,19.86) ; 81.64,18.82 v2(81.64,18.59)
TSD-_2: length 264.6
  TOP w0.254: R775.2 108.76,15.75 107.74,16.77 v1(107.3,16.77) ; Q12.E 82.93,193.21 C497.2 82,193.42 79.32,193.42 64.44,178.54 64.44,148.57 66.6,146.41 66.6,134.36 48.95,116.71 48.95,83.69 52.83,79.8 52.83,77.66 55.55,74.94 55.55,61.19 62.41,54.33 79.34,54.33 83.28,58.27 87.54,58.27 90.96,54.85 90.96,49.13 96.11,43.97 96.11,27.76 95.53,27.18 94.2,27.18 90.6,23.58 88.38,23.58 85.83,21.02 v1(85.83,20.72)
  BOTTOM w0.254: v1(107.3,16.77) 107.11,16.95 107.11,17.91 106.65,18.37 105.66,19.35 100.52,19.35 100.39,19.48 95.66,19.48 ; 95.66,19.48 93.57,19.48 92.38,20.68 85.87,20.68 v1(85.83,20.72) ; 95.66,19.48 v2(95.66,19.84)
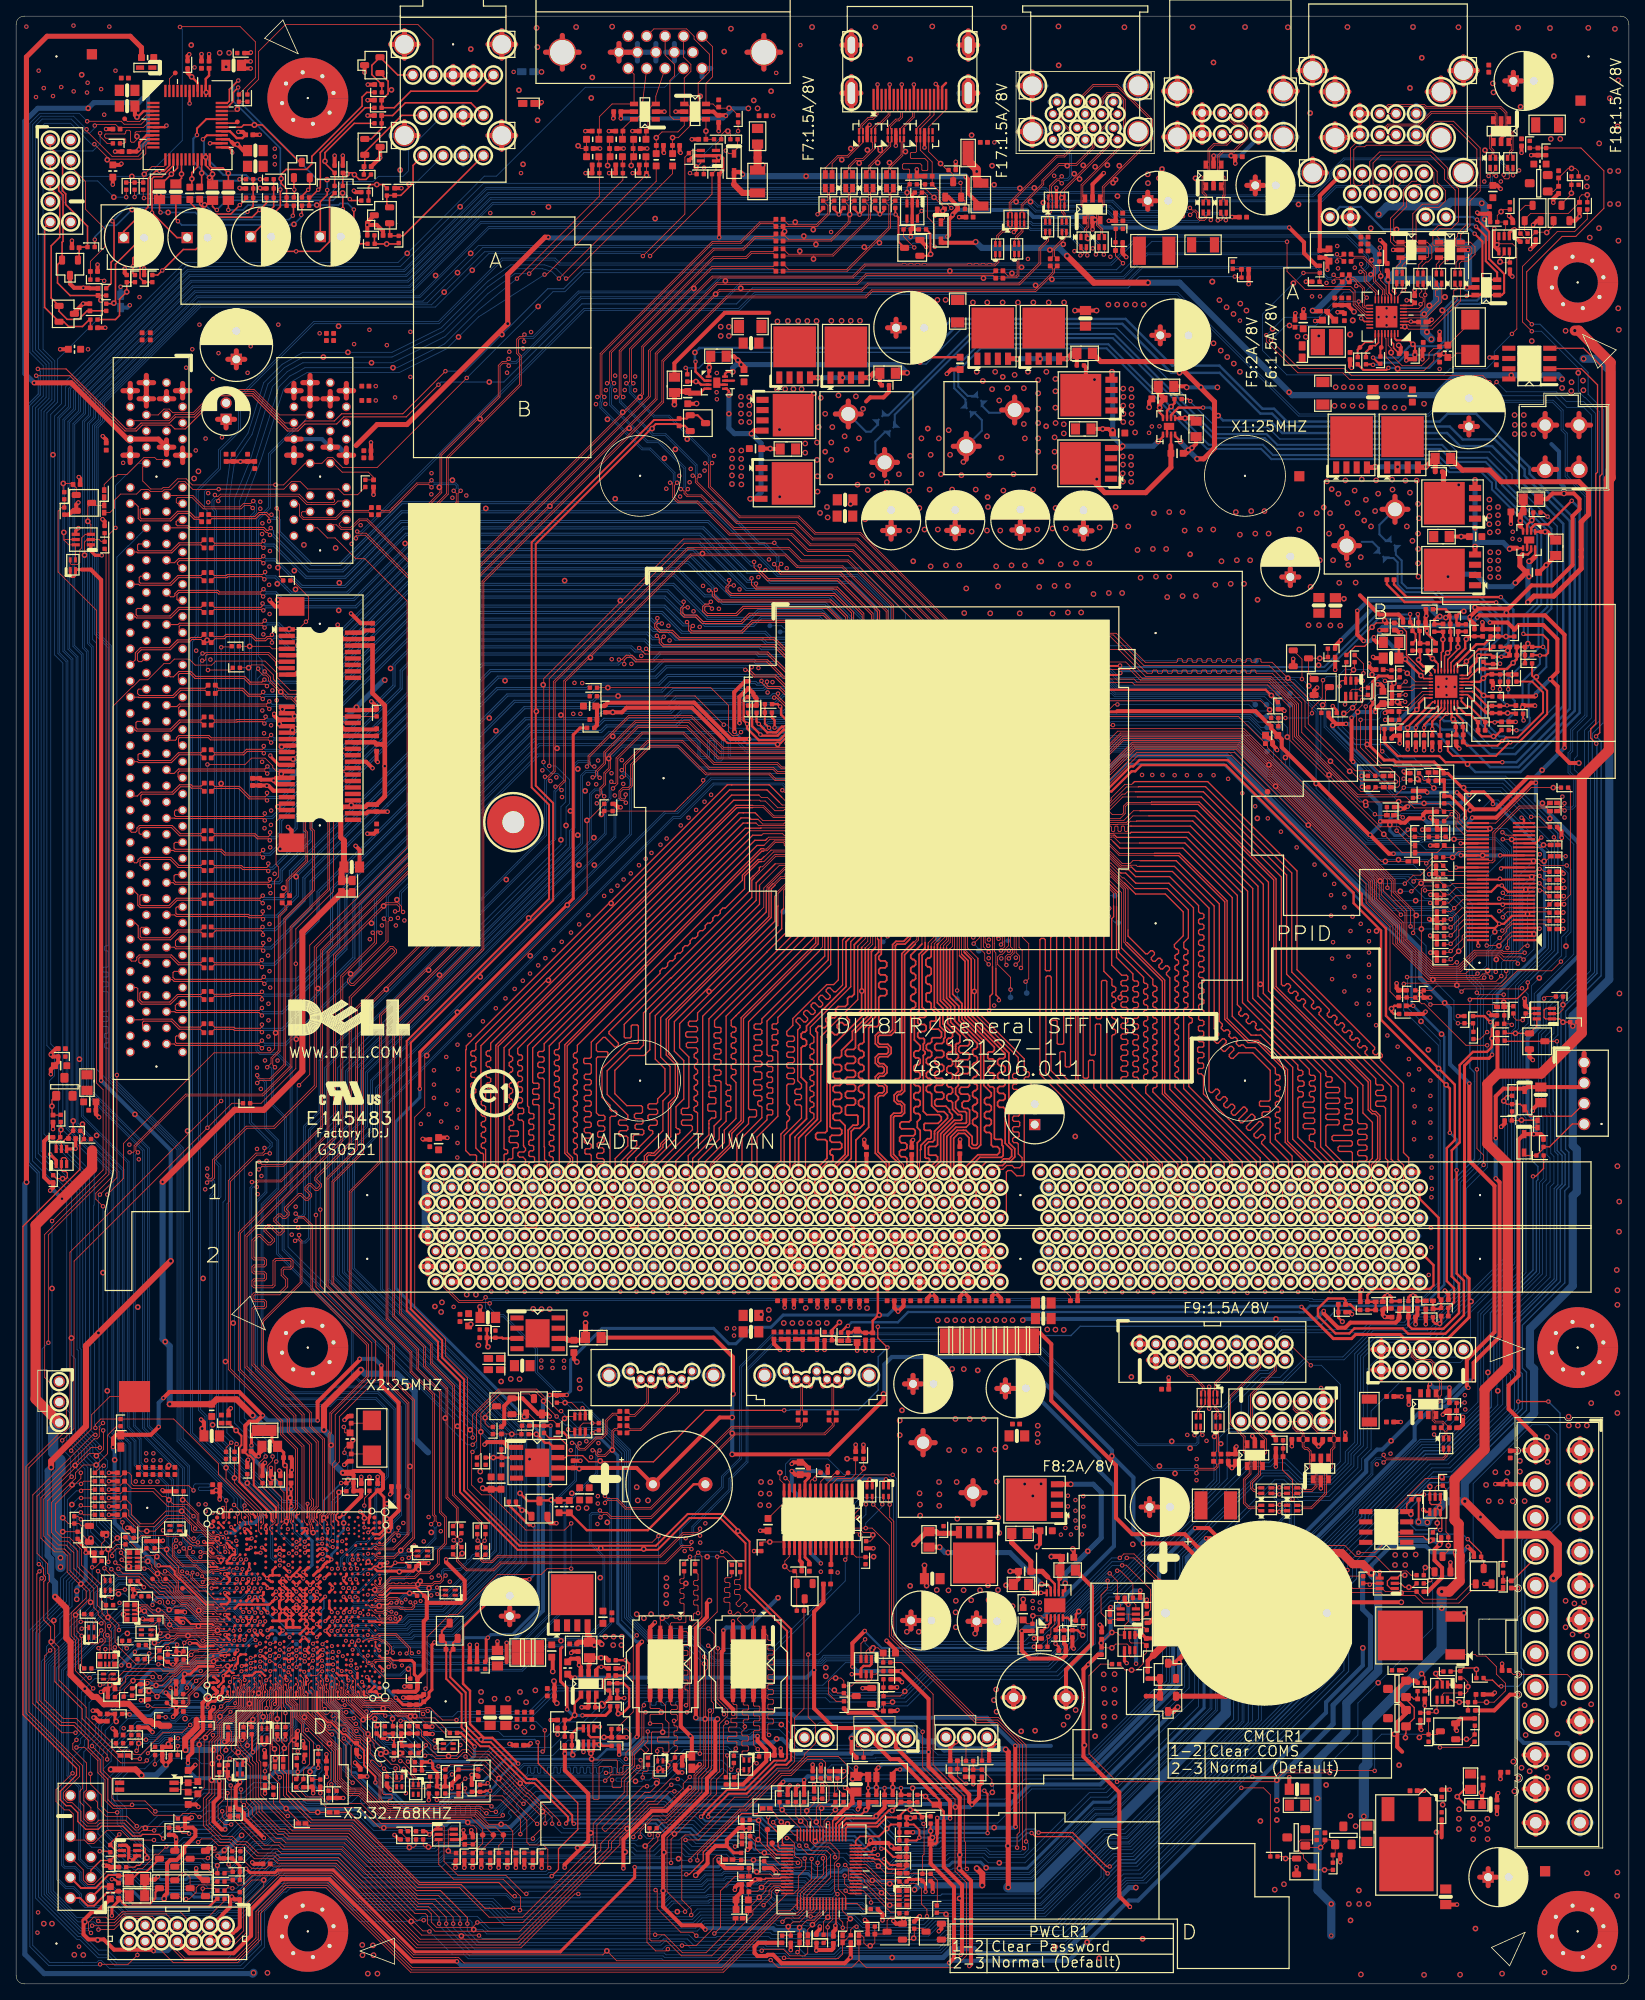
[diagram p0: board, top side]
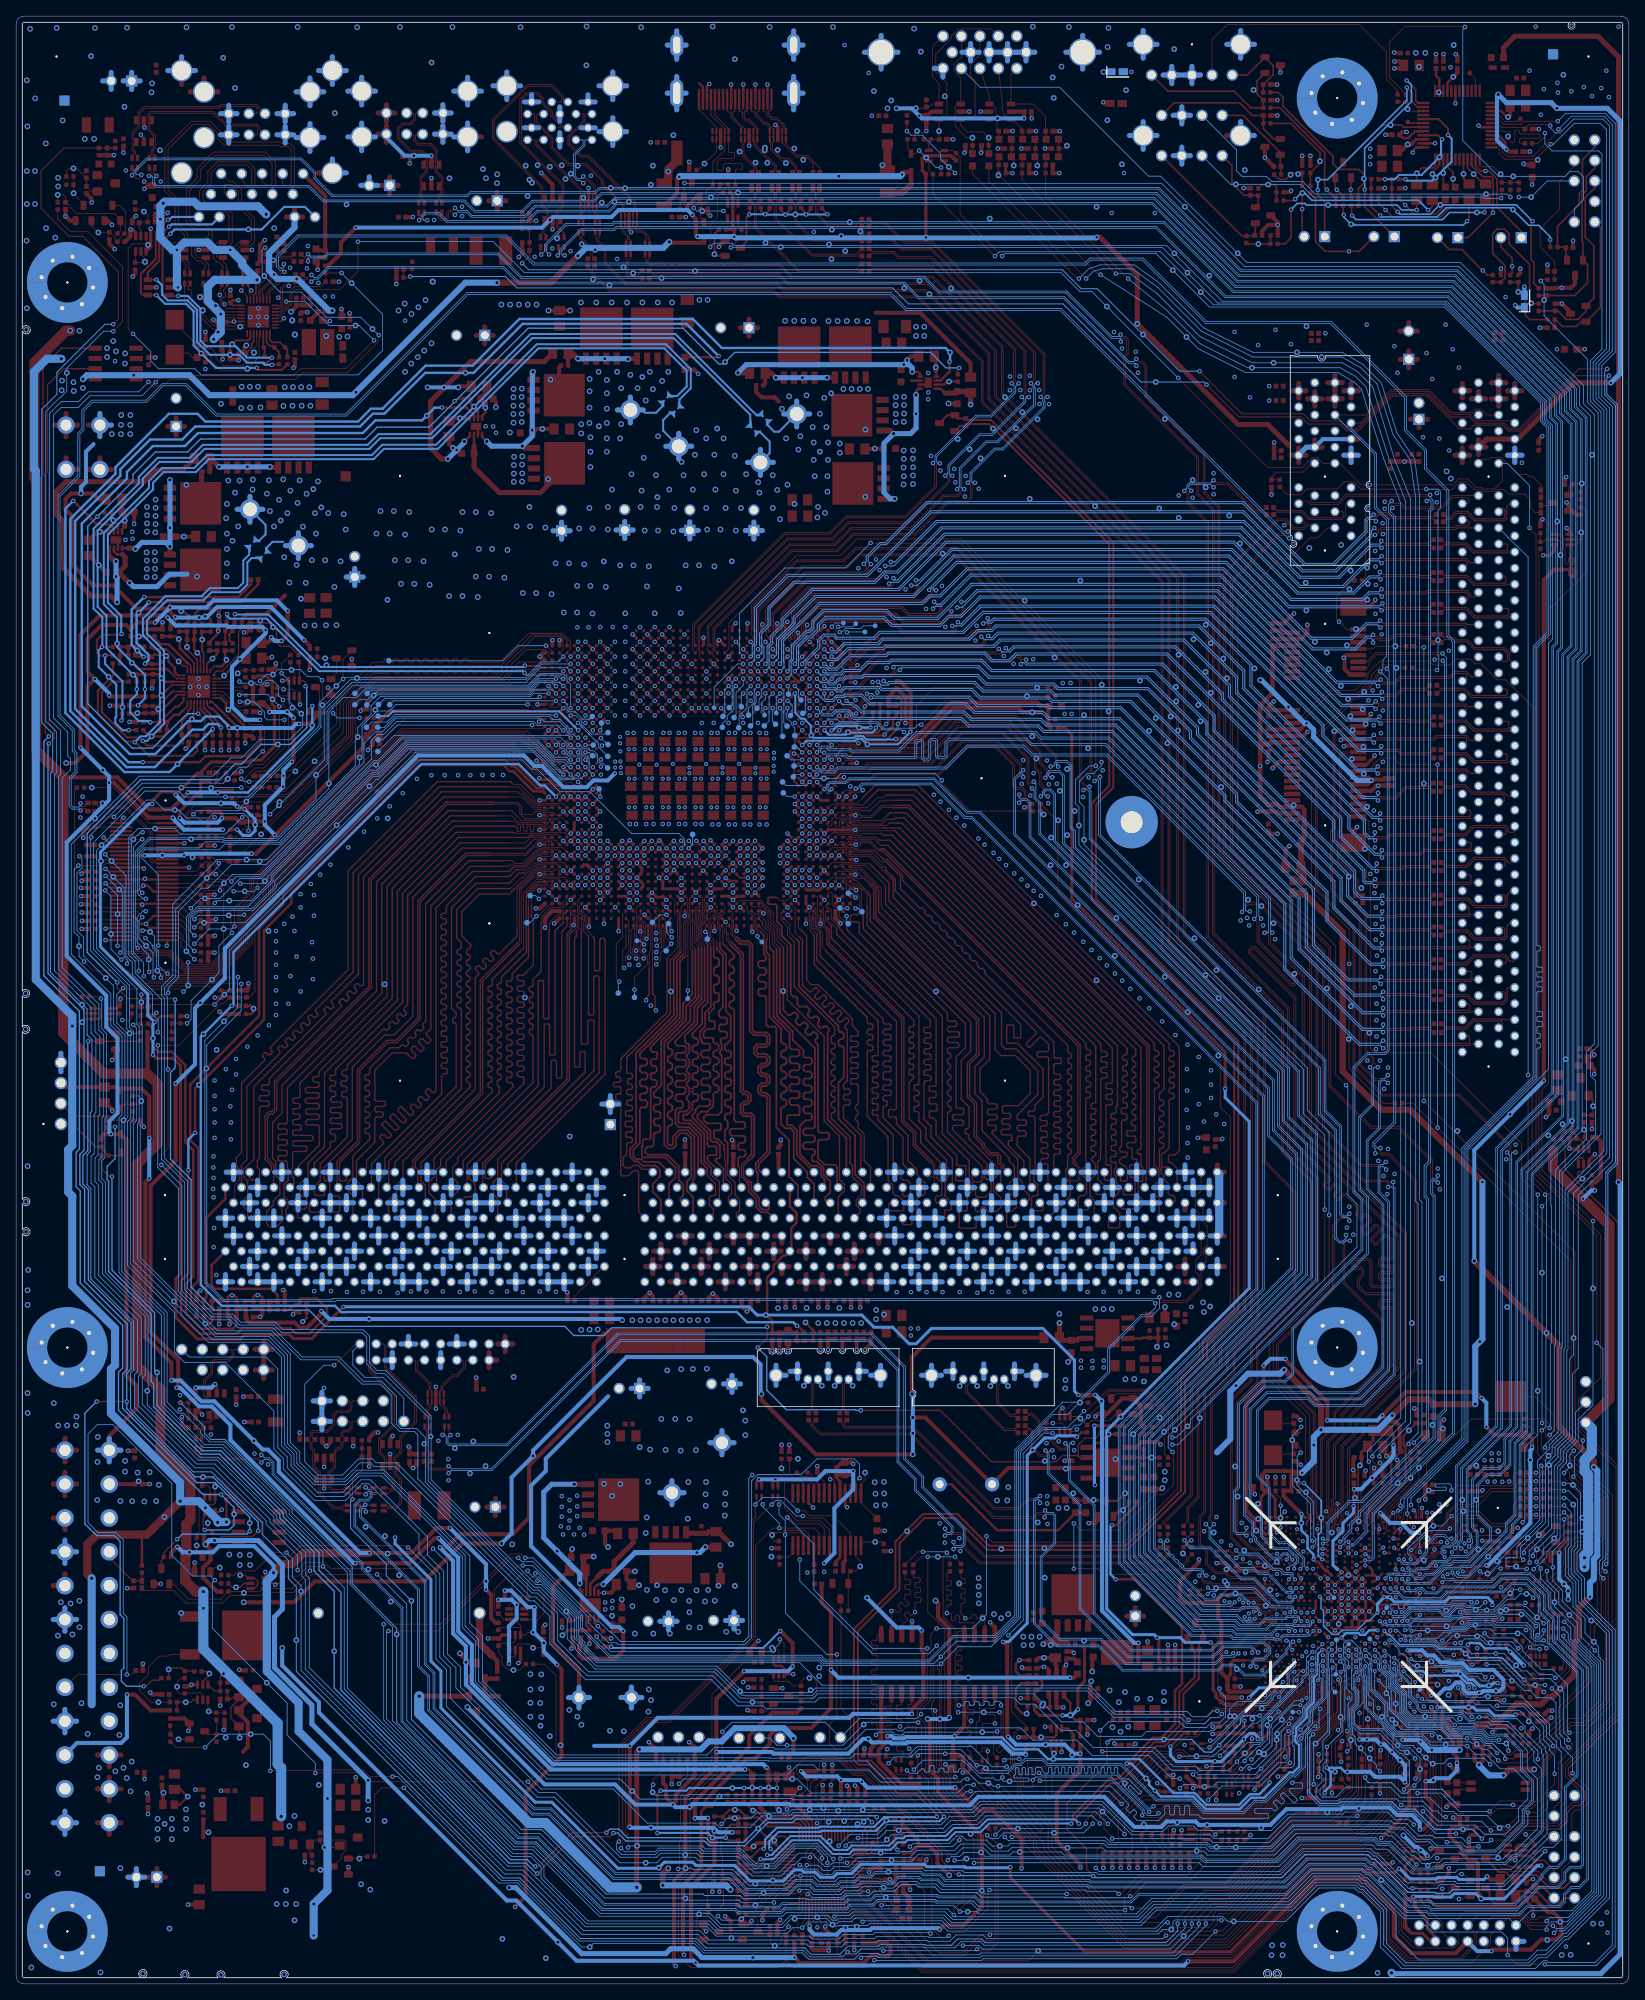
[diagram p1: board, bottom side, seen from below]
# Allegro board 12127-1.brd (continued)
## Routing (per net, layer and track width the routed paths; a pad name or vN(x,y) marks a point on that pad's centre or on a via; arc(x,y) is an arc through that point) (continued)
U17_VCC: length 3.4
  TOP w0.508: R2246.2 68.8,40.32 C195.1 69.8,40.22 v1(69.8,39.52) 70.04,39.28 U17.6
USB3_RX0_DN: length 219.2
  TOP w0.102: R677.1 54.59,57.17 54.59,58.97 53.31,60.25 53.31,73.79 50.53,76.57 50.53,78.94 46.71,82.76 46.71,118.85 52.35,124.49 52.73,124.87 ; 52.73,124.87 v2(52.5,125.09) ; 52.73,124.87 56.92,129.06 56.92,174.22 79.26,196.56 79.26,202.2 87.17,210.11 104.8,210.11 105.59,210.9 124.36,210.9 126.85,213.39 126.85,215.24 127.81,216.2 127.81,216.56 127.64,216.73 L22.1
USB3_RX0_DP: length 219.2
  TOP w0.102: 50.63,122.47 57.14,128.97 57.14,174.13 79.48,196.47 79.48,202.11 87.26,209.89 104.89,209.89 105.68,210.68 124.45,210.68 127.06,213.3 127.06,215.15 128.02,216.11 128.02,216.56 128.19,216.73 L22.2 ; 50.63,122.47 v2(50.88,122.22) ; 50.63,122.47 46.93,118.76 46.93,82.85 50.75,79.03 50.75,76.66 53.53,73.88 53.53,60.34 54.81,59.06 54.81,57.19 R681.1
USB3_RX1_DN: length 231.9
  TOP w0.102: v1(51.46,57) 51.85,57.4 51.85,57.92 51.66,58.11 51.66,73.05 48.86,75.86 48.86,78.28 41.31,85.82 41.31,98.26 45.06,102.01 45.06,120.14 55.04,130.12 55.04,174.67 77.6,197.23 77.6,203.05 86.31,211.76 103.73,211.76 105.22,213.25 109.86,213.25 109.96,213.35 110.27,213.35 110.38,213.25 110.69,213.25 110.79,213.35 111.11,213.35 111.21,213.25 111.53,213.25 111.63,213.35 111.95,213.35 112.05,213.25 112.37,213.25 112.47,213.35 112.79,213.35 112.89,213.25 117.97,213.25 118.07,213.35 118.39,213.35 118.49,213.25 118.81,213.25 118.91,213.35 119.23,213.35 119.33,213.25 119.65,213.25 119.75,213.35 120.07,213.35 120.17,213.25 120.48,213.25 120.59,213.35 120.9,213.35 121.01,213.25 121.32,213.25 121.65,213.58 121.65,213.75 121.44,213.97 L19.1 ; v3(41.99,49.08) 41.68,48.77 U29.G18
  BOTTOM w0.102: 51.85,55.98 51.85,56.51 51.85,56.61 v1(51.46,57) ; 51.85,55.98 v2(51.49,55.98) ; 51.85,55.98 51.85,55.3 48.18,51.64 46.49,51.64 45.83,50.97 44.74,50.97 42.42,48.65 41.85,48.65 41.76,48.74 41.76,48.85 v3(41.99,49.08)
USB3_RX1_DP: length 231.9
  TOP w0.102: v1(52.46,57) 52.07,57.38 52.07,58.01 51.88,58.2 51.88,73.14 49.07,75.95 49.07,78.37 41.53,85.91 41.53,98.17 45.28,101.92 45.28,120.05 55.26,130.03 55.26,174.58 77.81,197.14 77.81,202.96 86.4,211.54 103.82,211.54 105.31,213.03 121.41,213.03 121.87,213.49 121.87,213.79 121.99,213.91 L19.2 ; U29.H18 40.97,48.79 v3(41.26,49.08)
  BOTTOM w0.102: 47.52,51.42 v2(47.52,51.1) ; 47.52,51.42 46.58,51.42 45.92,50.76 44.82,50.76 42.51,48.44 41.76,48.44 41.54,48.65 41.54,48.8 v3(41.26,49.08) ; 47.52,51.42 48.27,51.42 52.06,55.21 52.06,56.51 52.06,56.58 52.06,56.61 v1(52.46,57)
USB3_RX2_DN: length 125.5
  TOP w0.102: L51.1 146.33,68.25 v1(146.13,68.05) ; v1(83.75,53.92) 83.54,54.13 82.58,54.13 80.54,52.1 60.12,52.1 59.25,51.22 55.82,51.22 54.6,52.43 54.6,52.84 R678.1
  BOTTOM w0.102: 143.31,66.95 v2(143.31,67.27) ; 143.31,66.95 139.17,66.95 125.41,80.71 93.86,80.71 89.71,76.56 89.71,65.18 87.46,62.93 87.46,61.63 82.32,56.49 82.32,54.51 82.7,54.13 83.54,54.13 v1(83.75,53.92) ; 143.31,66.95 146.25,66.95 146.46,67.16 146.46,67.72 v1(146.13,68.05)
USB3_RX2_DN_P: length 21
  TOP w0.102: R677.2 54.6,55.46 54.6,55.34 v1(54.26,55.01) 54.6,54.67 54.6,54.56 R678.2 ; U29.F20 42.55,47.64 42.55,47.85 42.4,48 v3(42.08,48)
  BOTTOM w0.102: 44.72,48.63 46.41,50.32 48.03,50.32 51.89,54.18 54.36,54.18 54.72,54.54 54.72,54.78 54.49,55.01 v1(54.26,55.01) ; 44.72,48.63 v2(44.48,48.87) ; 44.72,48.63 43.52,47.43 41.95,47.43 41.77,47.61 41.77,47.85 41.92,48 v3(42.08,48)
USB3_RX2_DP: length 125.5
  TOP w0.102: v1(83.75,54.78) 83.75,54.51 83.58,54.34 82.49,54.34 80.45,52.31 60.03,52.31 59.16,51.44 55.91,51.44 54.82,52.52 54.82,52.86 R689.1 ; v1(147.12,68.06) 146.88,68.3 L51.2
  BOTTOM w0.102: 145.59,66.74 139.08,66.74 125.32,80.49 93.95,80.49 89.93,76.47 89.93,65.09 87.68,62.84 87.68,61.54 82.54,56.4 82.54,54.6 82.79,54.34 83.58,54.34 83.75,54.51 v1(83.75,54.78) ; 145.59,66.74 v2(145.59,66.42) ; 145.59,66.74 146.34,66.74 146.67,67.07 146.67,67.88 146.86,68.06 v1(147.12,68.06)
USB3_RX2_DP_P: length 21
  TOP w0.102: R681.2 54.81,55.47 54.81,55.32 v1(55.13,55.01) 54.81,54.69 54.81,54.57 R689.2 ; v3(41.37,48) 41.68,47.69 U29.G20
  BOTTOM w0.102: v1(55.13,55.01) 54.94,54.82 54.94,54.45 54.45,53.96 51.98,53.96 49.67,51.65 ; 49.67,51.65 48.12,50.1 46.49,50.1 43.61,47.22 41.86,47.22 41.55,47.52 41.55,47.82 v3(41.37,48) ; 49.67,51.65 v2(49.91,51.41)
USB3_TX0_C_DN: length 216.7
  TOP w0.102: 126.66,210.38 126.34,210.06 106.1,210.06 105.32,209.28 88.1,209.28 80.09,201.27 80.09,196.22 57.78,173.92 57.78,128.32 47.54,118.07 47.54,83.1 51.37,79.27 51.37,76.9 54.14,74.13 54.14,60.59 57.58,57.15 57.58,57.05 R690.1 ; 126.66,210.38 128.56,212.28 128.56,212.7 C453.1 ; 126.66,210.38 v2(126.42,210.62)
USB3_TX0_C_DP: length 216.7
  TOP w0.102: C403.1 128.78,212.69 128.78,212.19 128.2,211.61 ; 128.2,211.61 126.43,209.84 106.19,209.84 105.41,209.07 88.19,209.07 80.3,201.18 80.3,196.13 58,173.83 58,128.23 47.75,117.98 47.75,83.19 51.59,79.36 51.59,76.99 54.36,74.22 54.36,60.68 57.8,57.24 57.8,57.06 R692.1 ; 128.2,211.61 v2(128.46,211.36)
USB3_TX0_EMI_DN: length 4.5
  TOP w0.102: C453.2 128.56,214.22 128.56,215.01 ; 128.56,215.01 128.56,215.18 129.86,216.48 129.86,216.67 129.7,216.84 L24.1 ; 128.56,215.01 v2(128.19,215.01)
USB3_TX0_EMI_DP: length 4.4
  TOP w0.102: 129.63,215.94 v2(129.86,215.71) ; 129.63,215.94 130.08,216.39 130.08,216.67 130.25,216.84 L24.2 ; 129.63,215.94 128.78,215.09 128.78,214.24 C403.2
USB3_TX1_C_DN: length 224.2
  TOP w0.102: 115.8,212.05 121.11,212.05 C452.1 ; 115.8,212.05 v2(115.8,212.39) ; 115.8,212.05 105.37,212.05 104.25,210.93 86.83,210.93 78.42,202.53 78.42,196.89 55.86,174.33 55.86,129.6 45.89,119.62 45.89,82.42 49.7,78.61 49.7,76.19 52.49,73.39 52.49,58.46 53.12,57.82 53.12,54.65 52.25,53.77 52.25,52.12 51.21,51.08 49.96,51.08 49.36,50.48 46.43,50.48 45.23,49.28 44.89,49.28 44.48,49.69 44.48,49.9 U29.B15
USB3_TX1_C_DP: length 224.2
  TOP w0.102: 119.96,211.84 v2(119.96,211.51) ; 119.96,211.84 121.15,211.84 C401.1 ; 119.96,211.84 105.46,211.84 104.34,210.72 86.92,210.72 78.64,202.44 78.64,196.8 56.08,174.24 56.08,129.51 46.1,119.53 46.1,82.51 49.91,78.7 49.91,76.28 52.7,73.48 52.7,58.55 53.34,57.91 53.34,54.56 52.46,53.68 52.46,52.03 51.3,50.86 50.05,50.86 49.45,50.27 46.52,50.27 45.32,49.06 44.8,49.06 44.35,49.51 U29.B16
USB3_TX1_EMI_DN: length 5.2
  TOP w0.102: v2(123.49,212.12) 123.49,211.77 ; 123.49,211.77 123.99,211.77 124.14,211.92 124.14,213.61 123.8,213.94 L18.1 ; 123.49,211.77 123.02,211.77 C452.2
USB3_TX1_EMI_DP: length 5.1
  TOP w0.102: L18.2 124.35,212.86 ; 124.35,212.86 124.35,211.83 124.08,211.56 122.42,211.56 C401.2 ; 124.35,212.86 v2(124.68,212.86)
USB3_TX2_C_DN: length 121.8
  TOP w0.102: v1(84.81,55.58) 84.66,55.73 82.75,55.73 79.95,52.92 59.75,52.92 59.07,52.24 57.87,52.24 57.58,52.52 57.58,52.82 R691.1 ; v1(146.37,64.19) 146.63,63.93 148.59,63.93 148.84,64.19 148.84,64.45 C430.1
  BOTTOM w0.102: 141.78,63.87 141.08,63.87 125.07,79.88 94.21,79.88 90.54,76.21 90.54,64.78 88.39,62.64 88.39,61.29 86.16,59.06 85.51,58.41 83.81,56.71 83.81,55.99 84.05,55.75 84.64,55.75 v1(84.81,55.58) ; 141.78,63.87 v2(141.78,64.21) ; 141.78,63.87 146.05,63.87 v1(146.37,64.19)
USB3_TX2_C_DN_P: length 20.8
  TOP w0.102: v1(52.39,50.63) 52.65,50.63 52.74,50.53 52.74,50.1 52.53,49.89 51.84,49.89 51.57,49.62 50.11,49.62 ; R691.2 57.58,54.51 57.58,54.62 v1(57.24,54.96) 57.18,55.02 R690.2 ; 50.11,49.62 v2(50.11,49.94) ; 50.11,49.62 49.51,49.62 49.41,49.72 49.1,49.72 48.99,49.62 48.68,49.62 48.57,49.72 48.26,49.72 48.16,49.62 47.84,49.62 47.74,49.72 47.42,49.72 47.32,49.62 47,49.62 46.9,49.72 46.58,49.72 46.48,49.62 46.16,49.62 45.25,48.7 44.64,48.7 44.55,48.8 U29.B18
  BOTTOM w0.102: v1(57.24,54.96) 57.51,54.96 57.58,54.89 57.58,54.04 57.38,53.84 57.24,53.84 57.02,53.62 57.02,53.48 56.79,53.25 56.65,53.25 56.42,53.03 56.42,52.88 56.2,52.66 56.06,52.66 55.83,52.43 55.83,52.29 55.61,52.07 55.46,52.07 55.24,51.84 55.24,51.7 55.01,51.47 53.02,51.47 52.74,51.19 52.74,50.77 52.6,50.63 v1(52.39,50.63)
USB3_TX2_C_DP: length 121.8
  TOP w0.102: C431.1 149.06,64.44 149.06,64.1 148.68,63.72 146.49,63.72 146.37,63.6 v1(146.37,63.33) ; R699.1 57.8,52.82 57.8,52.61 57.96,52.45 58.98,52.45 59.66,53.14 79.86,53.14 82.66,55.94 84.52,55.94 84.81,56.24 v1(84.81,56.45)
  BOTTOM w0.102: v1(146.37,63.33) 146.05,63.65 143.71,63.65 ; v2(143.71,63.3) 143.71,63.65 ; 143.71,63.65 140.99,63.65 124.98,79.67 94.3,79.67 90.75,76.12 90.75,64.69 88.61,62.55 88.61,61.2 86.31,58.9 85.66,58.25 84.02,56.62 84.02,56.08 84.14,55.97 84.52,55.97 84.81,56.26 v1(84.81,56.45)
USB3_TX2_C_DP_P: length 20.8
  TOP w0.102: R699.2 57.8,54.51 57.8,54.65 v1(58.1,54.96) 58.2,55.05 R692.2 ; 51.21,49.4 51.66,49.4 51.93,49.67 52.62,49.67 52.96,50.01 52.96,50.33 v1(53.26,50.63) ; 51.21,49.4 v2(51.21,49.07) ; 51.21,49.4 46.25,49.4 45.34,48.49 44.48,48.49 44.08,48.88 U29.C18
  BOTTOM w0.102: v1(53.26,50.63) 52.96,50.93 52.96,51.1 53.11,51.26 55.1,51.26 57.8,53.95 57.8,54.65 v1(58.1,54.96)
USB3_TX2_EMI_DN: length 3.9
  TOP w0.102: L32.1 148.77,68.84 148.89,68.72 148.89,67.87 ; 148.89,67.87 148.89,66.08 C430.2 ; 148.89,67.87 v4(148.59,67.87)
USB3_TX2_EMI_DP: length 3.9
  TOP w0.102: 149.11,66.98 149.11,65.99 C431.2 ; 149.11,66.98 149.11,68.64 149.32,68.86 L32.2 ; 149.11,66.98 v4(149.4,66.98)
USB_EXT2_DN10: length 21.8
  TOP w0.102: TR26.2 159.29,58.66 159.54,58.92 160.67,58.92 162.5,60.74 162.5,62.31 UU38.3 162.5,62.81 162.5,63.31 163.22,64.03 163.22,66.18 163.54,66.5 163.54,67.11 C375.1 163.51,67.94 163.51,68.31 163.22,68.61 161.47,68.61 160.74,69.33 160.74,70.52 160.22,71.04 158.85,71.04 158.58,71.31 158.58,72.15 158.73,72.29 USBF2.3
USB_EXT2_DN11: length 13.9
  TOP w0.102: TR27.2 159.23,60.82 159.49,61.07 160.72,61.07 161.32,61.67 161.32,63.4 160.59,64.12 160.59,65 UU38.6 160.59,65.51 160.59,66.08 160.18,66.48 159.91,66.48 159.71,66.68 159.71,67.11 C393.1 159.71,67.91 159.71,68.31 159.35,68.67 158.87,68.67 158.56,68.98 158.56,69.66 158.65,69.75 USBF2.4
USB_EXT2_DP10: length 21.8
  TOP w0.102: TR26.3 159.32,59.35 159.54,59.13 160.58,59.13 162.28,60.83 162.28,63.4 163,64.12 163,65 UU38.4 163,65.51 163,66.27 163.33,66.59 163.33,67.11 C392.1 163.3,67.88 163.3,68.22 163.13,68.39 161.38,68.39 160.53,69.24 160.53,70.43 160.13,70.83 158.76,70.83 158.37,71.22 158.37,72.11 158.19,72.29 USBF2.5
USB_EXT2_DP11: length 13.9
  TOP w0.102: USBF2.6 158.24,69.75 158.34,69.65 158.34,68.89 158.78,68.45 159.26,68.45 159.49,68.22 159.49,67.91 C404.1 159.49,67.11 159.49,66.59 159.82,66.27 160.09,66.27 160.38,65.99 160.38,64.03 161.1,63.31 161.1,62.81 UU38.1 161.1,62.31 161.1,61.76 160.63,61.29 159.49,61.29 159.27,61.5 TR27.3
USB_EXT_DN0: length 29.1
  TOP w0.102: 134.05,225.08 132.07,223.09 132.07,220.48 132.8,219.75 132.8,218.97 UU43.1 132.8,218.43 132.8,217.95 132.51,217.65 132.51,217.37 132.38,217.25 132.17,217.25 132.04,217.12 TR20.1 ; 134.05,225.08 137.33,228.35 137.33,233.59 136.63,234.29 135.36,234.29 134.87,233.81 134.87,233.22 133.71,232.05 133.71,231.62 132.51,230.43 132.51,230.23 132.58,230.16 USB3R1.11 ; 134.05,225.08 v2(133.81,225.32)
USB_EXT_DN1: length 30.7
  TOP w0.102: 137.06,225.2 134.7,222.83 134.7,221.65 UU43.4 134.7,221.14 134.7,220.6 133.97,219.88 133.97,218.07 134.53,217.51 134.53,217.06 134.28,216.8 TR19.1 ; 137.06,225.2 v2(136.8,225.45) ; 137.06,225.2 140.73,228.87 140.73,231.08 136.5,235.31 133.63,235.31 132.36,234.03 132.36,233.48 132.48,233.36 USB3R1.2
USB_EXT_DN2: length 16.3
  TOP w0.102: TR23.4 150.07,221.03 149.81,221.28 149.81,221.63 149.92,221.74 149.92,224.05 149.18,224.79 149.18,225.32 UU42.4 149.18,225.85 149.18,226.62 149.71,227.15 151.07,227.15 152.04,228.11 152.74,228.81 152.74,230.14 152.12,230.76 151.11,230.76 150.69,231.18 150.69,231.81 150.87,231.99 USBCN1.2
USB_EXT_DN3: length 12
  TOP w0.102: USBCN1.6 150.88,229.37 150.69,229.18 150.69,228.54 150.15,228 148.63,228 148.03,227.4 148.03,224.68 147.29,223.95 147.29,223.14 UU42.1 147.29,222.64 147.29,222.17 147.66,221.8 147.66,221.28 147.89,221.05 TR24.4
USB_EXT_DN4: length 16.8
  TOP w0.102: USBF1.4 172.9,78.67 173,78.57 173,77.8 173.61,77.19 175.36,77.19 175.64,76.91 175.64,75.67 176.53,74.78 176.53,73.68 U26.4 176.36,72.94 176.36,72.22 175.61,71.47 175.61,69.88 175.93,69.56 176.85,69.56 177.05,69.35 177.05,69.28 C373.1 177.22,68.48 177.22,68.02 177,67.81 TR18.1
USB_EXT_DN8: length 23
  TOP w0.102: TR9.1 184.95,226.58 185.21,226.84 185.21,227.26 185.42,227.47 185.42,228.08 UU12.6 185.42,228.71 185.42,229.49 184.66,230.25 184.66,231.98 184.05,232.59 174.8,232.59 174.57,232.82 170.23,232.82 170.1,232.69 170.1,232.04 170.23,231.91 RJ45.U2
USB_EXT_DN9: length 22.1
  TOP w0.102: RJ45.U6 170.21,229.29 170.08,229.42 170.08,230.26 170.21,230.39 173.99,230.39 175.55,231.95 183.3,231.95 183.43,231.83 183.43,231.32 UU12.3 183.43,230.86 183.43,229.91 182.75,229.24 182.75,227.58 183.05,227.29 183.05,226.86 182.79,226.61 TR10.1
USB_EXT_DN10: length 26.1
  TOP w0.102: USBF3.8 153.77,79.35 154.13,78.99 154.13,76.53 150.37,72.77 150.37,69.61 152.19,67.79 152.19,65.89 152.92,65.17 152.92,64.47 UU37.1 152.92,63.96 152.92,63.31 152.19,62.58 152.19,59.59 152.86,58.93 153.95,58.93 154.21,58.66 TR22.1
USB_EXT_DN11: length 21
  TOP w0.102: TR25.1 153.89,60.82 153.65,61.06 153.46,61.06 153.1,61.42 153.1,62.19 154.1,63.19 154.1,65.19 154.82,65.91 154.82,66.66 UU37.4 154.82,67.17 154.82,67.48 153.09,69.22 153.09,73.13 156.04,76.09 156.04,77.18 155.87,77.35 USBF3.12
USB_EXT_DP0: length 29.1
  TOP w0.102: USB3R1.12 132.19,230.16 132.3,230.26 132.3,230.52 133.49,231.71 133.49,232.14 134.66,233.31 134.66,233.9 135.27,234.51 136.72,234.51 137.54,233.68 137.54,228.26 135.07,225.79 ; 135.07,225.79 132.28,223 132.28,221.65 UU43.6 132.28,221.14 132.28,220.57 133.02,219.84 133.02,217.86 132.73,217.56 TR20.4 ; 135.07,225.79 v2(135.33,225.53)
USB_EXT_DP1: length 30.7
  TOP w0.102: USB3R1.3 132.01,233.36 132.14,233.49 132.14,234.12 133.54,235.52 136.59,235.52 140.94,231.17 140.94,228.78 136.12,223.95 ; TR19.4 134.96,216.8 134.75,217.02 134.75,217.6 134.19,218.16 134.19,218.45 UU43.3 134.19,218.95 134.19,219.79 134.91,220.51 134.91,222.74 136.12,223.95 ; 136.12,223.95 v2(136.35,223.72)
USB_EXT_DP2: length 16.3
  TOP w0.102: USBCN1.3 150.36,231.99 150.47,231.88 150.47,231.09 151.02,230.54 152.03,230.54 152.53,230.05 152.53,228.9 151.74,228.12 151.74,228.12 150.98,227.36 149.62,227.36 148.97,226.71 148.97,224.7 149.7,223.96 149.7,223.14 UU42.3 149.7,222.64 149.7,221.83 149.59,221.72 149.59,221.25 149.39,221.04 TR23.1
USB_EXT_DP3: length 12
  TOP w0.102: USBCN1.7 150.28,229.37 150.47,229.18 150.47,228.63 150.06,228.22 148.54,228.22 147.81,227.49 147.81,225.85 UU42.6 147.81,225.32 147.81,224.77 147.07,224.04 147.07,222.08 147.44,221.71 147.44,221.28 147.21,221.05 TR24.1
USB_EXT_DP4: length 16.8
  TOP w0.102: TR18.4 177.68,67.82 177.43,68.07 177.43,68.64 C374.1 176.94,69.77 176.02,69.77 175.82,69.97 175.82,70.28 U26.3 175.82,70.79 175.82,71.38 176.58,72.14 176.58,72.85 176.75,73.01 176.75,74.87 175.86,75.76 175.86,77 175.45,77.41 173.7,77.41 173.22,77.89 173.22,78.57 173.32,78.67 USBF1.6
USB_EXT_DP8: length 23
  TOP w0.102: RJ45.U3 169.89,232.67 169.89,232.78 170.14,233.03 174.66,233.03 174.89,232.8 184.14,232.8 184.87,232.07 184.87,231.32 UU12.1 184.87,230.86 184.87,230.34 185.63,229.58 185.63,227.38 185.43,227.17 185.43,226.84 185.63,226.63 TR9.4
USB_EXT_DP9: length 22.2
  TOP w0.102: RJ45.U7 169.86,230.02 169.86,230.35 170.12,230.61 173.9,230.61 175.46,232.17 183.39,232.17 183.64,231.92 183.64,229.82 182.97,229.15 182.97,228.63 UU12.4 182.97,228.17 182.97,227.67 183.26,227.37 183.26,226.8 183.47,226.58 TR10.4
USB_EXT_DP10: length 26
  TOP w0.102: USBF3.9 154.46,79.35 154.34,79.24 154.34,76.44 150.58,72.68 150.58,69.7 152.41,67.88 152.41,67.17 UU37.6 152.41,66.65 152.41,65.98 153.13,65.26 153.13,63.22 152.41,62.49 152.41,59.68 152.95,59.14 153.95,59.14 154.15,59.35 TR22.4
USB_EXT_DP11: length 21
  TOP w0.102: USBF3.11 156.42,77.35 156.26,77.19 156.26,76 153.3,73.04 153.3,69.3 155.04,67.57 155.04,65.82 154.32,65.1 154.32,64.47 UU37.3 154.32,63.97 154.32,63.11 153.31,62.1 153.31,61.51 153.55,61.27 153.65,61.27 153.89,61.5 TR25.4
USB_OC0_R_N: length 9.8
  TOP w0.102: U29.AE40 32.18,36.98 32.14,36.94 32.14,36.57 31.95,36.38 31.95,35.17 31.65,34.87 31.65,34.49 31.72,34.42 31.72,33.48 31.65,33.4 31.65,32.36 31.74,32.27
  TOP w0.127: R521.1 32.11,29.07 v2(32.04,29.13) 31.75,29.43 31.75,29.67 31.74,29.68 31.74,32.27
USB_OC1_R_N: length 24
  TOP w0.127: v3(31.01,37.64) 31.02,37.64 31.55,38.17 U29.AF37 ; v1(15.34,27.91) 14.26,27.91 R496.1
  BOTTOM w0.127: v3(31.01,37.64) 31.01,37.59 30.07,36.65 v2(30.07,36.04) 29.68,35.65 29.68,34 27.45,31.78 23.17,31.78 22.23,30.84 20.79,30.84 20.51,31.12 19.73,31.12 19.17,30.56 18.45,30.56 17.7,29.81 16.9,29.81 15.33,28.23 15.33,27.93 v1(15.34,27.91)
USB_OC2_R_N: length 10
  TOP w0.102: U29.AD39 32.72,37.1 32.9,36.92 32.93,36.88 32.96,36.8 32.97,36.76 32.97,36.5 32.93,36.46 32.93,34.28 32.93,34.28
  TOP w0.127: 32.93,34.28 32.93,29.98 33.26,29.66 v2(33.26,29.21) 33.12,29.08 R523.1
USB_OC3_R_N: length 5.1
  TOP w0.102: U29.AD40 32.66,36.66 32.72,36.59 32.72,34.38 32.51,34.16
  TOP w0.127: 32.51,34.16 32.39,34.04 v2(32.39,32.86) 32.38,32.86 R621.1
USB_OC4_R_N: length 19.5
  TOP w0.102: 31.5,32.11 31.45,32.16 31.45,33.49 31.52,33.56 31.52,34.33 31.45,34.41 31.45,34.95 31.45,35.14 31.72,35.41 31.72,36.48 31.86,36.61 31.86,37.08 31.55,37.39 U29.AF39
  TOP w0.127: 31.5,32.11 31.5,25.98 32.69,24.79 32.69,22.53 v2(33.48,21.75) 34.99,20.23 R493.1
USB_OC5_R_N: length 18.9
  TOP w0.127: U29.AC41 33.41,34.86 34.07,34.2 34.07,30.05 33.8,29.78 33.8,25.97 33.79,25.96 33.79,23.86 33.8,23.85 34.08,23.57 36.38,21.27 v2(37.4,21.27) R483.1
USB_OC6_R_N: length 5.4
  TOP w0.102: U29.AF40 31.55,36.6 31.45,36.49 31.45,35.44 31.04,35.03 v1(31.04,34.19) 31.04,33.47 31.17,33.34 31.17,32.9 31.11,32.84 31.11,32.81
  TOP w0.127: 31.11,32.81 RN36.1
USB_OC7_R_N: length 5.9
  TOP w0.102: v2(30.63,33.12) 30.56,33.2 30.56,34.92 31.17,35.53 31.17,36.37 30.94,36.6 U29.AG40
  TOP w0.127: v2(30.63,33.12) 30.63,32.48 30.46,32.31 RN36.2
USB_OC_01*: length 363.3
  TOP w0.127: v1(53.24,199.97) 47.96,194.69 40.35,194.69 39.46,193.8 35.81,193.8 34.83,192.81 33.73,192.81 29.37,197.18 24.99,197.18 22.1,194.29 19.75,194.29 19.01,193.54 15.49,193.54 14.76,192.81 13.64,192.81 6.2,200.25 v1(2.7,200.25) ; v1(14.38,22.2) 14.25,22.07 12.14,22.07 11.38,22.83 11.38,25.35 10.43,26.31 10.43,27.81 8.94,29.29 8.94,30.24 7.14,32.04 5.49,32.04 2.57,34.97 2.57,50.83 v1(2.9,51.16) ; R521.2 32.11,26.2 v1(32.7,25.61) ; UR99.2 136.36,216.5 136.33,216.47 UR106.1 UC117.1 136.33,214.29 v1(137.26,213.36)
  BOTTOM w0.127: v1(2.7,200.25) 3,199.95 3,197.04 1.66,195.7 1.66,101.84 2.86,100.65 2.86,52.67 3.01,52.51 3.29,52.24 3.29,51.55 v1(2.9,51.16) ; v1(14.38,22.2) 21.23,22.2 23.16,24.12 27.08,24.12 27.56,23.63 28.13,23.63 29.44,24.94 32.26,24.94 32.7,25.38 v1(32.7,25.61) ; v1(137.26,213.36) 136.46,212.56 70.27,212.56 67.91,210.2 65.93,210.2 v2(60.25,204.52) 55.7,199.97 v1(53.24,199.97)
USB_OC_23*: length 343.3
  TOP w0.127: R496.2 12.76,28.32 8.95,32.13 8.95,32.13 8.19,32.89 8.19,34.08 4.81,37.47 4.81,41.55 4.28,42.08 4.28,44.27 3.43,45.12 3.43,49.89 3.63,50.1 3.63,50.49 3.4,50.72 3.4,51.54 2.9,52.04 v1(2.82,52.04) ; v1(52.37,198.3) 48.39,194.31 40.64,194.31 39.75,193.42 35.81,193.42 34.95,192.56 33.63,192.56 29.26,196.93 25.1,196.93 20.98,192.81 19.68,192.81 19.21,193.29 15.64,193.29 14.91,192.56 13.51,192.56 6.65,199.42 v1(2.49,199.42) ; v1(151.13,211.71) 151.26,211.58 UC97.1 UC107.1 151.89,212.66 UR98.2
  BOTTOM w0.127: v1(2.49,199.42) 2.74,199.16 2.74,197.14 1.41,195.81 1.41,101.73 2.6,100.54 2.6,52.26 v1(2.82,52.04) ; v1(52.37,198.3) 52.7,198.63 v2(58.67,198.63) 60.48,198.63 70.17,208.32 89.33,208.32 91.31,210.3 137.9,210.3 139.31,211.71 v1(151.13,211.71)
USB_OC_45*: length 194.2
  TOP w0.127: R428.1 C390.1 R418.1 179.59,72.04 v1(179.63,72.09) ; v1(61.65,9.37) 58.14,9.37 55.21,12.3 49.94,12.3 41.9,20.33 36.71,20.33 33.52,23.52 33.52,26.06 33.3,26.28 33.12,26.46 R523.2
  BOTTOM w0.127: v1(61.65,9.37) 61.9,9.63 80.66,9.63 81.3,10.26 85.81,10.26 86.01,10.45 93.21,10.45 93.78,9.88 96.62,9.88 97.07,9.42 104.74,9.42 105.18,8.99 110.44,8.99 110.78,9.33 127.27,9.33 135.52,17.59 137.96,17.59 152.81,32.44 v2(152.81,43.33) 152.81,44.09 158.33,49.62 158.33,51.73 174.11,67.51 175.9,67.51 176.63,68.25 176.63,69.09 v1(179.63,72.09)
USB_OC_89*: length 373.4
  TOP w0.127: v1(187.96,205.79) 187.32,206.43 187.32,212.29 191.72,216.69 193.42,216.69 196.9,220.17 196.9,224.82 194.07,227.65 UR119.1 UC133.1 UR118.2 ; v1(55.96,7.47) 55.96,8.23 52.62,11.57 49.63,11.57 41.6,19.6 36.18,19.6 R493.2
  BOTTOM w0.127: v1(55.96,7.47) 55.96,6.56 57.41,5.11 79.83,5.11 80.29,5.57 83.24,5.57 84.02,4.79 87.19,4.79 87.3,4.89 92.82,4.89 93.05,4.66 96.84,4.66 97.83,3.67 101.42,3.67 102.21,4.46 114.46,4.46 115.62,5.63 130.03,5.63 137.54,13.13 139.62,13.13 165.25,38.76 v2(165.25,42.62) 165.25,49.26 166.23,50.24 166.23,52.49 169.49,55.75 169.49,57.21 175.77,63.49 178.02,63.49 185.81,71.28 185.81,71.69 185.81,75.74 185.45,76.1 185.45,82.14 190.73,87.42 190.73,98.62 191.2,99.09 191.2,102.82 190.81,103.2 190.81,108.03 190.6,108.23 190.6,117.07 191.2,117.67 191.2,120.88 195.74,125.43 195.74,150.12 195.47,150.4 195.47,155.02 196.82,156.38 196.82,195.23 194.94,197.11 194.94,199.83 188.98,205.79 v1(187.96,205.79)
USB_OC_1011*: length 164.7
  TOP w0.127: v1(61.82,10.87) 61.56,10.87 59.87,12.56 50.04,12.56 42.01,20.59 41.33,21.27 R483.2 ; UR100.1 UR107.1 UC118.1 157.05,65.32 157.05,63.73 158.29,62.48 v1(158.29,60.1)
  BOTTOM w0.127: v1(61.82,10.87) 62.01,10.68 69.92,10.68 69.99,10.76 80.3,10.76 80.86,11.32 85.38,11.32 86.08,12.01 88.12,12.01 88.42,12.32 90.25,12.32 91.06,11.51 93.65,11.51 94.22,10.93 97.05,10.93 97.51,10.48 101.87,10.48 101.97,10.58 109.85,10.58 110.22,10.95 114.63,10.95 114.82,11.14 126.81,11.14 134.8,19.13 137.32,19.13 150.98,32.78 v2(150.98,47.5) 154.1,50.62 154.1,52.07 158.52,56.49 158.52,59.87 v1(158.29,60.1)
USB_PCH_DN0: length 288.2
  TOP w0.102: TR20.2 132.04,215.17 132.41,214.81 132.41,214.55 132.2,214.34 v1(131.98,214.34) ; v3(22.85,52.93) 22.85,52.98 23.03,53.15 23.23,53.35 23.56,53.35 24.09,52.82 24.98,52.82 U29.AV10
  BOTTOM w0.102: 95.3,217.69 125.51,217.69 125.78,217.42 129.87,217.42 132.41,214.88 132.41,214.53 132.22,214.34 v1(131.98,214.34) ; 95.3,217.69 v2(95.3,217.31) ; 95.3,217.69 58.66,217.69 50.06,209.09 22.47,209.09 9.84,196.46 9.84,194.2 9.07,193.42 9.07,166.29 9.55,165.81 9.55,110.61 16.51,103.65 16.51,69.22 21.51,64.21 21.51,55.02 22.25,54.28 23.01,54.28 23.29,54 23.29,53.37 v3(22.85,52.93)
USB_PCH_DN1: length 291.7
  TOP w0.102: v1(133.91,214.44) 134.28,214.81 TR19.2 ; v1(21.54,54.05) 21.29,53.8 21.29,53.19 21.97,52.5 24.56,52.5 24.92,52.14 U29.AV11
  BOTTOM w0.102: 133.16,216.67 134.26,215.57 134.26,214.8 v1(133.91,214.44) ; 133.16,216.67 v2(132.92,216.43) ; 133.16,216.67 131.77,218.06 126.02,218.06 125.77,218.31 57.67,218.31 49.07,209.72 22.22,209.72 9.22,196.72 9.22,194.46 8.45,193.68 8.45,165.75 8.93,165.27 8.93,110.35 9.17,110.11 15.89,103.39 15.89,68.96 20.85,63.99 20.85,55.03 21.29,54.59 21.29,54.3 v1(21.54,54.05)
USB_PCH_DN2: length 316
  TOP w0.102: U29.AN14 28.06,51.06 v3(28.06,51.44) ; v1(150.02,218.7) 150.07,218.75 TR23.3
  BOTTOM w0.102: v1(150.02,218.7) 149.77,218.95 149.77,219.27 149.37,219.67 147.54,219.67 146.52,218.66 136.68,218.66 135.41,219.93 126.49,219.93 125.53,220.89 59.06,220.89 48.72,210.55 21.87,210.55 8.38,197.07 8.38,194.8 7.05,193.47 7.05,165.85 8.09,164.81 8.09,107.56 10.21,105.44 ; v3(28.06,51.44) 27.73,51.1 26.4,51.1 26.13,51.37 25.03,51.37 24.1,52.3 22.53,52.3 21.93,52.9 20.04,52.9 18.71,54.23 18.71,56.1 19.3,56.69 19.3,62.43 17.94,63.79 16.03,63.79 15.28,64.54 15.28,67.5 13.79,68.99 13.79,101.86 10.21,105.44 ; 10.21,105.44 v2(9.98,105.21)
USB_PCH_DN3: length 318.7
  TOP w0.102: TR24.3 147.89,219.49 147.66,219.25 147.66,218.96 147.35,218.66 146.77,218.66 146.39,219.04 146.39,219.52 146.18,219.74 145.97,219.74 v1(145.59,219.35) ; v3(30.2,50.27) 29.97,50.04 U29.AJ16
  BOTTOM w0.102: 8,106.37 7.66,106.71 7.66,164.57 6.64,165.59 6.64,193.64 7.98,194.97 7.98,197.23 21.76,211.02 48.62,211.02 58.89,221.3 125.7,221.3 126.66,220.33 135.58,220.33 135.82,220.09 136.85,219.06 143.55,219.06 144.17,219.68 145.26,219.68 v1(145.59,219.35) ; 8,106.37 v2(8.23,106.6) ; 8,106.37 11.46,102.91 13.39,100.98 13.39,68.82 14.86,67.34 14.86,64.39 16,63.25 17.56,63.25 18.88,61.92 18.88,58.08 17.27,56.46 17.27,55.09 19.88,52.49 21.73,52.49 22.14,52.08 23.08,52.08 24.26,50.9 25.2,50.9 25.73,50.37 26.44,50.37 26.92,50.85 28.75,50.85 28.83,50.93 29.7,50.93 29.93,50.7 29.93,50.54 v3(30.2,50.27)
USB_PCH_DN4: length 268.7
  TOP w0.102: TR18.2 177,65.85 177.23,65.62 177.23,65.52 176.92,65.2 169.77,65.2 169.59,65.38 v1(169.59,65.59) ; U29.AU15 25.73,50.24 25.42,49.93 24.82,49.93 24.63,50.13 23.93,50.13 23.88,50.08 23.41,50.08 v3(23.14,49.81)
  BOTTOM w0.102: v3(23.14,49.81) 22.91,50.04 21.79,50.04 21.54,49.78 16.99,49.78 16.03,50.75 12.31,50.75 9.98,48.42 9.98,46.63 8.85,45.5 8.85,42.73 5.22,39.1 5.22,13.04 6.2,12.06 7.16,12.06 8.1,11.13 8.1,10.21 8.62,9.69 12.68,9.69 13.64,8.72 24.72,8.72 25.05,9.06 27.48,9.06 32.2,13.78 32.51,13.78 33.06,14.33 39.48,14.33 42.61,11.2 60.85,11.2 61.79,10.26 80.4,10.26 81.03,10.9 85.55,10.9 85.74,11.09 93.48,11.09 94.05,10.52 96.88,10.52 97.34,10.06 105.01,10.06 105.44,9.63 110.18,9.63 110.52,9.97 127,9.97 135.26,18.22 137.69,18.22 152.04,32.57 152.04,46.66 156.55,51.17 ; v1(169.59,65.59) 169.23,65.23 168.61,65.23 168.03,64.66 168.03,63.25 156.98,52.2 156.98,51.6 156.55,51.17 ; v2(156.31,51.41) 156.55,51.17
USB_PCH_DN5: length 126.4
  TOP w0.102: v1(19.81,54.23) 19.58,54 19.58,53.09 20.73,51.94 22.35,51.94 23.11,51.18 23.95,51.18 24.18,51.41 24.7,51.41 arc(24.77,51.39) 24.83,51.35 24.97,51.35 arc(25.09,51.37) 25.2,51.43 arc(25.28,51.48) 25.38,51.5 25.68,51.5 U29.AU12 ; MINI1.36 41.01,150.75 40.74,150.48 40.04,150.48 38.66,149.1 38.66,135.77 33.99,131.09 33.99,113.79 30.52,110.32 21.02,110.32 14.63,103.94 14.63,103.23 14.52,103.11 v1(14.07,103.11)
  BOTTOM w0.102: v1(19.81,54.23) 19.38,54.66 19.38,55.17 19.51,55.3 19.51,55.75 19.95,56.2 19.95,63.71 19.16,64.5 ; v1(14.07,103.11) 14.43,103.11 14.54,103 14.54,69.12 19.16,64.5 ; 19.16,64.5 v2(18.94,64.27)
USB_PCH_DN8: length 355.6
  TOP w0.102: v3(21.21,51) 21.21,50.85 21.34,50.72 21.54,50.72 21.67,50.6 21.67,50.3 22.8,49.17 23.57,49.17 24.02,49.62 24.38,49.62 U29.AW16 ; v1(184.48,224.33) 184.48,223.95 184.61,223.82 185.04,223.82 185.17,223.95 185.17,224.76 184.95,224.98 TR9.2
  BOTTOM w0.102: 136.58,222.03 128.13,222.03 127.62,222.54 58.37,222.54 48.16,212.33 21.31,212.33 6.73,197.75 6.73,195.49 5.4,194.16 5.4,165.05 6.42,164.03 6.42,106.16 12.1,100.47 12.1,68.34 13.6,66.84 13.6,57.91 14.58,56.93 14.58,56.01 19.96,50.62 21.1,50.62 21.21,50.74 v3(21.21,51) ; 136.58,222.03 v2(136.58,221.69) ; 136.58,222.03 143.6,222.03 144.02,221.62 160.83,221.62 163.07,223.85 163.07,224.54 164.72,226.19 183.74,226.19 185.17,224.76 185.17,224.46 185.04,224.33 v1(184.48,224.33)
USB_PCH_DN9: length 353.3
  TOP w0.102: v3(28.13,50.2) 27.84,49.91 U29.AN16 ; v1(182.6,224.17) 182.93,224.5 182.93,224.8 182.79,224.94 TR10.2
  BOTTOM w0.102: 129.67,221.17 136.01,221.17 137.28,219.9 143.07,219.9 144.36,221.2 161.84,221.2 163.65,223.01 182.54,223.01 182.84,223.32 182.84,223.93 v1(182.6,224.17) ; 129.67,221.17 v2(129.67,221.49) ; 129.67,221.17 128.39,221.17 127.42,222.14 58.54,222.14 48.33,211.92 21.48,211.92 7.14,197.58 7.14,195.32 5.8,193.99 5.8,165.24 6.82,164.22 6.82,106.33 12.55,100.61 12.55,68.47 13.61,67.4 13.61,67.4 13.77,67.25 14.01,67.01 14.01,58.08 14.99,57.1 15.11,56.97 15.11,56.07 19.55,51.63 20.74,51.63 20.92,51.44 22.81,51.44 24.69,49.55 27.48,49.55 v3(28.13,50.2)
USB_PCH_DN10: length 245.9
  TOP w0.102: U29.AJ18 30.25,48.56 30.33,48.64 v3(30.33,49.05) ; TR26.1 156.76,58.66 v1(156.64,58.55) 156.53,58.66 TR22.2
  BOTTOM w0.102: 154.5,55.28 149.16,49.94 149.16,39.69 148.07,38.6 148.07,34.19 135.69,21.82 133.64,21.82 125.61,13.79 111.29,13.79 109.33,11.84 104.51,11.84 103.4,12.95 101.28,12.95 100.64,12.32 98.27,12.32 97.82,12.78 96.03,12.78 95.42,13.39 94.04,13.39 93.5,13.93 87.76,13.93 87.45,13.63 85.41,13.63 84.71,12.93 66.88,12.93 66.69,12.74 42.83,12.74 39.99,15.58 32.54,15.58 31.99,15.03 31.68,15.03 26.96,10.31 24.53,10.31 24.2,9.97 14.16,9.97 10.88,13.25 10.88,13.58 9.92,14.54 8.93,14.54 7.99,15.48 7.99,24.42 6.52,25.89 6.52,38.64 10.1,42.22 10.1,44.95 11.23,46.08 11.23,47.9 12.83,49.51 14.5,49.51 15.52,48.49 22.5,48.49 23.28,47.71 27.99,47.71 28.69,48.41 29.82,48.41 30.33,48.92 v3(30.33,49.05) ; 154.5,55.28 v2(154.25,55.52) ; 154.5,55.28 157.2,57.98 157.2,58.88 157.12,58.95 156.74,58.95 156.64,58.85 v1(156.64,58.55)
USB_PCH_DN11: length 251.9
  TOP w0.102: U29.AP18 27.36,48.85 v3(27.36,49.07) ; TR25.2 156.53,60.82 v1(156.66,60.7) 156.78,60.82 TR27.1
  BOTTOM w0.102: 152.27,50.9 150.22,48.84 150.22,39.37 148.95,38.1 148.95,33.88 136,20.94 133.95,20.94 125.96,12.95 111.64,12.95 109.68,11 104.17,11 103.05,12.12 101.62,12.12 100.99,11.48 97.93,11.48 97.47,11.94 95.68,11.94 95.13,12.48 92.14,12.48 91.94,12.28 91.38,12.28 91.25,12.41 90.57,13.09 88.1,13.09 87.8,12.79 85.76,12.79 85.06,12.09 67.23,12.09 67.04,11.9 42.48,11.9 39.64,14.74 32.89,14.74 32.34,14.19 32.03,14.19 27.31,9.47 24.88,9.47 24.55,9.13 13.81,9.13 11.07,11.87 8.75,11.87 7.84,12.79 7.84,13.75 7.24,14.35 5.97,14.35 5.63,14.69 5.63,38.93 9.26,42.57 9.26,45.3 10.39,46.43 10.39,48.25 12.48,50.34 15.82,50.34 16.84,49.33 23.08,49.33 23.81,48.59 25.04,48.59 25.59,49.14 26.23,49.14 26.51,48.85 27.15,48.85 v3(27.36,49.07) ; 152.27,50.9 158.1,56.73 158.1,59.42 157.43,60.1 156.41,60.1 156.08,60.43 156.08,60.95 156.24,61.1 156.35,61.1 156.66,60.79 v1(156.66,60.7) ; 152.27,50.9 v2(152.5,50.67)
USB_PCH_DP0: length 288.2
  TOP w0.102: TR20.3 132.73,214.46 v1(132.84,214.34) ; v3(22.85,53.57) 23.65,53.57 24.18,53.04 24.82,53.04 24.87,53.09 25.46,53.09 U29.AU10
  BOTTOM w0.102: v1(132.84,214.34) 132.63,214.56 132.63,214.97 129.96,217.64 125.87,217.64 125.6,217.91 58.57,217.91 52.26,211.59 ; v2(52.02,211.84) 52.26,211.59 ; 52.26,211.59 49.97,209.31 22.39,209.31 9.63,196.55 9.63,194.29 8.85,193.51 8.85,166.2 9.33,165.72 9.33,110.52 16.29,103.56 16.29,69.13 21.3,64.12 21.3,54.93 22.16,54.06 22.92,54.06 23.08,53.91 23.08,53.79 v3(22.85,53.57)
USB_PCH_DP1: length 291.7
  TOP w0.102: v1(20.78,54) 21.07,53.71 21.07,53.1 21.88,52.29 24.29,52.29 U29.AW11 ; v1(134.88,214.44) 134.96,214.51 TR19.3
  BOTTOM w0.102: v1(134.88,214.44) 134.48,214.84 134.48,215.66 131.86,218.27 126.11,218.27 125.86,218.53 79.25,218.53 ; 79.25,218.53 57.58,218.53 48.98,209.93 22.13,209.93 9,196.81 9,194.55 8.23,193.77 8.23,165.66 8.71,165.18 8.71,110.26 9.08,109.9 15.67,103.3 15.67,68.87 20.64,63.9 20.64,54.94 21.07,54.5 21.07,54.3 v1(20.78,54) ; 79.25,218.53 v2(79.25,218.9)
USB_PCH_DP2: length 316.1
  TOP w0.102: v3(27.36,51.53) 26.87,51.53 26.75,51.41 26.75,50.96 26.87,50.83 U29.AP14 ; TR23.2 149.39,219.47 149.66,219.2 149.66,219 149.56,218.9 149.56,218.82 149.41,218.68 v1(149.02,218.68)
  BOTTOM w0.102: v1(149.02,218.68) 149.46,218.68 149.56,218.77 149.56,219.18 149.28,219.46 147.63,219.46 146.61,218.44 136.59,218.44 135.32,219.71 126.4,219.71 125.44,220.68 66.01,220.68 ; v3(27.36,51.53) 27.15,51.32 26.49,51.32 26.22,51.59 25.12,51.59 24.19,52.51 22.62,52.51 22.02,53.11 20.13,53.11 18.92,54.32 18.92,56.01 19.52,56.6 19.52,62.52 18.03,64.01 16.12,64.01 15.49,64.63 15.49,67.59 14.01,69.08 14.01,101.95 8.31,107.65 8.31,164.9 7.26,165.94 7.26,193.38 8.6,194.72 8.6,196.98 21.96,210.34 48.81,210.34 59.15,220.68 66.01,220.68 ; 66.01,220.68 v2(66.01,220.34)
USB_PCH_DP3: length 318.6
  TOP w0.102: U29.AK16 29.26,49.94 v3(29.51,50.19) ; TR24.2 147.21,219.46 147.44,219.23 147.44,219.05 147.26,218.87 146.86,218.87 146.61,219.13 146.61,219.61 146.27,219.95 145.83,219.95 v1(145.57,220.22)
  BOTTOM w0.102: 127.38,220.55 126.75,220.55 125.78,221.51 58.8,221.51 48.53,211.24 21.67,211.24 7.76,197.32 7.76,195.06 6.43,193.73 6.43,165.5 7.44,164.48 7.44,106.62 13.17,100.89 13.17,68.73 14.64,67.25 14.64,64.3 15.91,63.03 17.47,63.03 18.67,61.84 18.67,58.17 17.06,56.55 17.06,55 19.79,52.27 21.64,52.27 22.05,51.87 22.99,51.87 24.17,50.69 25.11,50.69 25.64,50.15 26.53,50.15 27.01,50.63 28.84,50.63 28.92,50.71 29.61,50.71 29.71,50.61 29.71,50.39 v3(29.51,50.19) ; 127.38,220.55 135.67,220.55 136.03,220.18 136.94,219.28 143.46,219.28 144.08,219.9 145.25,219.9 v1(145.57,220.22) ; 127.38,220.55 v2(127.38,220.88)
USB_PCH_DP4: length 268.6
  TOP w0.102: v3(23.07,50.55) 23.32,50.29 23.79,50.29 23.84,50.34 24.71,50.34 24.82,50.24 U29.AV15 ; TR18.3 177.68,65.85 177.45,65.62 177.45,65.43 177.01,64.98 169.91,64.98 v1(169.58,64.65)
  BOTTOM w0.102: v3(23.07,50.55) 22.78,50.25 21.7,50.25 21.45,50 17.08,50 16.12,50.97 12.22,50.97 9.77,48.51 9.77,46.72 8.64,45.59 8.64,42.82 5,39.19 5,12.95 6.11,11.85 7.07,11.85 7.89,11.04 7.89,10.12 8.53,9.47 12.59,9.47 13.55,8.51 24.8,8.51 25.14,8.84 27.57,8.84 32.29,13.57 32.6,13.57 33.15,14.12 39.39,14.12 42.52,10.99 60.76,10.99 61.7,10.05 80.49,10.05 81.12,10.68 85.64,10.68 85.83,10.87 93.39,10.87 93.96,10.3 96.79,10.3 97.25,9.84 104.92,9.84 105.35,9.41 110.27,9.41 110.61,9.75 127.09,9.75 135.35,18.01 137.78,18.01 152.26,32.49 152.26,46.57 153.31,47.62 ; 153.31,47.62 157.2,51.51 157.2,52.11 168.25,63.16 168.25,64.57 168.69,65.01 169.23,65.01 v1(169.58,64.65) ; 153.31,47.62 v2(153.54,47.4)
USB_PCH_DP5: length 126.5
  TOP w0.102: v1(15.1,103.1) 14.85,103.36 14.85,103.85 21.11,110.11 30.61,110.11 34.2,113.7 34.2,131 38.87,135.68 38.87,149.01 40.13,150.27 40.72,150.27 41.03,149.95 MINI1.38 ; v1(19.84,54.99) 19.37,54.52 19.37,53 20.64,51.73 22.26,51.73 23.02,50.97 24.04,50.97 24.27,51.19 24.36,51.19 24.36,51.19 24.61,51.19 arc(24.68,51.18) 24.74,51.14 24.97,51.14 arc(25.15,51.17) 25.32,51.25 25.62,51.25 arc(26.09,51.34) U29.AT12
  BOTTOM w0.102: 14.76,83.92 v2(15.09,83.92) ; 14.76,83.92 14.76,102.76 v1(15.1,103.1) ; 14.76,83.92 14.76,69.21 20.17,63.8 20.17,56.11 19.72,55.66 19.72,55.11 v1(19.84,54.99)
USB_PCH_DP8: length 355.6
  TOP w0.102: v3(21.89,51.01) 21.89,50.39 22.89,49.39 23.48,49.39 23.93,49.83 24.61,49.83 24.84,49.61 U29.AV16 ; TR9.3 v1(185.63,224.26)
  BOTTOM w0.102: v2(121.28,223.09) 121.28,222.76 ; 121.28,222.76 58.28,222.76 48.07,212.55 21.22,212.55 6.52,197.84 6.52,195.58 5.18,194.25 5.18,164.96 6.2,163.95 6.2,106.07 11.89,100.38 11.89,68.25 13.39,66.75 13.39,57.82 14.36,56.84 14.36,55.92 19.87,50.41 21.29,50.41 v3(21.89,51.01) ; 121.28,222.76 127.71,222.76 128.22,222.25 143.69,222.25 144.11,221.83 160.74,221.83 162.85,223.94 162.85,224.63 164.63,226.4 183.83,226.4 185.38,224.85 185.38,224.52 v1(185.63,224.26)
USB_PCH_DP9: length 353.3
  TOP w0.102: U29.AP16 27.35,49.63 27.53,49.81 27.53,50.03 v3(27.36,50.2) ; TR10.3 183.47,224.98 183.15,224.65 183.15,224.3 183.27,224.17 v1(183.53,224.17)
  BOTTOM w0.102: 159.03,220.98 161.93,220.98 163.74,222.8 182.63,222.8 183.06,223.23 183.06,224.05 183.18,224.17 v1(183.53,224.17) ; 159.03,220.98 144.45,220.98 143.16,219.68 137.19,219.68 135.92,220.95 128.3,220.95 127.33,221.92 58.63,221.92 48.42,211.71 21.57,211.71 7.35,197.49 7.35,195.23 6.02,193.9 6.02,165.33 7.04,164.31 7.04,106.42 12.76,100.7 12.76,68.56 14.22,67.1 14.22,58.17 15.14,57.25 15.33,57.06 15.33,56.16 19.64,51.84 20.83,51.84 21.02,51.65 22.9,51.65 24.78,49.77 27.39,49.77 27.52,49.9 27.52,50.04 v3(27.36,50.2) ; 159.03,220.98 v2(159.03,220.65)
USB_PCH_DP10: length 245.9
  TOP w0.102: U29.AK18 29.26,48.74 v3(29.57,49.05) ; TR22.3 156.63,59.35 v1(156.69,59.41) 156.76,59.35 TR26.4
  BOTTOM w0.102: v1(156.69,59.41) 156.69,59.41 156.93,59.17 157.21,59.17 157.41,58.97 157.41,57.89 156.43,56.9 ; v3(29.57,49.05) 29.15,48.63 28.6,48.63 27.9,47.93 23.37,47.93 22.59,48.7 15.61,48.7 14.59,49.72 12.74,49.72 11.01,47.99 11.01,46.17 9.88,45.03 9.88,42.31 6.3,38.73 6.3,25.8 7.77,24.33 7.77,15.39 8.84,14.33 9.83,14.33 10.67,13.49 10.67,13.16 14.07,9.75 24.29,9.75 24.62,10.09 27.05,10.09 31.77,14.81 32.08,14.81 32.63,15.36 39.9,15.36 42.74,12.52 66.78,12.52 66.97,12.71 84.8,12.71 85.5,13.41 87.54,13.41 87.85,13.72 93.41,13.72 93.95,13.17 95.33,13.17 95.94,12.56 97.73,12.56 98.18,12.1 100.73,12.1 101.37,12.74 103.31,12.74 104.42,11.62 109.42,11.62 111.38,13.58 125.7,13.58 133.73,21.6 135.78,21.6 148.29,34.1 148.29,38.51 149.38,39.6 149.38,49.85 156.43,56.9 ; v2(156.67,56.67) 156.43,56.9
USB_PCH_DP11: length 251.9
  TOP w0.102: v3(28.13,49.07) 28.13,48.85 U29.AN18 ; TR27.4 156.72,61.5 v1(156.66,61.56) 156.6,61.5 TR25.3
  BOTTOM w0.102: 154.18,53.11 v2(153.92,53.37) ; 154.18,53.11 157.89,56.82 157.89,59.33 157.34,59.88 156.32,59.88 155.87,60.34 155.87,61.04 156.15,61.32 156.41,61.32 v1(156.66,61.56) ; 154.18,53.11 150,48.93 150,39.46 148.73,38.19 148.73,33.97 135.91,21.16 133.86,21.16 125.87,13.17 111.55,13.17 109.59,11.21 104.26,11.21 103.14,12.33 101.53,12.33 100.9,11.7 98.02,11.7 97.56,12.15 95.77,12.15 95.22,12.7 92.05,12.7 91.85,12.5 91.47,12.5 90.66,13.31 88.01,13.31 87.71,13 85.67,13 84.97,12.31 67.14,12.31 66.95,12.12 42.57,12.12 39.73,14.95 32.8,14.95 32.25,14.4 31.94,14.4 27.22,9.68 24.79,9.68 24.46,9.35 13.9,9.35 11.16,12.09 8.84,12.09 8.05,12.88 8.05,13.84 7.33,14.57 6.06,14.57 5.84,14.78 5.84,38.84 9.47,42.48 9.47,45.21 10.6,46.34 10.6,48.16 12.57,50.13 15.73,50.13 16.75,49.11 22.99,49.11 23.72,48.37 25.13,48.37 25.68,48.92 26.14,48.92 26.42,48.64 27.69,48.64 v3(28.13,49.07)
USB_PWR_CRL1: length 242.3
  TOP w0.102: v1(57.4,5.99) 57.35,6.05 50.28,6.05 40.17,16.16 32.91,16.16 32.35,16.71 30.61,16.71 27.08,20.24 26.04,20.24 25.55,20.73 v1(25.55,21.41) ; U29.AC36 32.7,39.37 32.7,39.39 v3(32.7,39.39) ; R455.1 174.76,62.67 169.37,57.28 169.37,54.36 168.48,53.47 v1(166.47,53.47) ; R574.1 20.03,29.48 v1(20.04,29.49)
  BOTTOM w0.102: v1(166.47,53.47) 165.74,52.73 165.74,50.44 164.67,49.38 v2(164.67,48.67) 164.67,38.88 139.42,13.63 137.33,13.63 129.83,6.12 115.42,6.12 114.25,4.95 102,4.95 101.65,4.6 97.61,4.6 97.05,5.16 93.29,5.16 93.07,5.38 87.09,5.38 86.99,5.28 84.23,5.28 83.45,6.06 80.08,6.06 79.62,5.61 57.79,5.61 v1(57.4,5.99) ; v3(32.7,39.39) 32.7,38.28 32.55,38.13 32.55,34.31 28.92,30.68 25.68,30.68 24.59,29.59 20.27,29.59 20.19,29.51 20.07,29.51 v1(20.04,29.49) 19.01,28.46 17.74,28.46 15.95,26.67 14.28,26.67 12.53,24.92 12.53,22.91 13.7,21.74 13.7,20.17 15.31,18.57 17.93,18.57 19.05,19.68 23.83,19.68 v1(25.55,21.41)
USB_PWR_CRL1_B1: length 11.6
  TOP w0.102: Q42.2 175.97,61.54 176.21,61.79 R455.2 177.32,61.38 177.32,56.05 177.61,55.75 R469.2 v2(177.61,54.36) 177.61,53.72 Q45.C
USB_PWR_CRL2: length 110.6
  TOP w0.102: v1(101.55,15.7) 101.55,16.18 100.74,16.99 99.16,16.99 98.47,17.68 U61.60 98.47,19.36 98.12,19.71 98.12,20.12 97.31,20.93 97.31,22.14 R484.1 ; v1(151.38,54.1) 151.65,54.37 164.78,54.37 166.16,52.98 168.63,52.98 170.41,51.21 172.44,51.21 172.97,50.67 R485.1
  BOTTOM w0.102: v1(101.55,15.7) 102.54,15.7 103.48,14.76 103.75,14.76 105.12,13.38 108.73,13.38 110.66,15.32 115.41,15.32 115.81,15.71 119.87,15.71 120.56,15.01 v2(121.92,15.01) 125.12,15.01 133.26,23.15 135.38,23.15 146.63,34.41 146.63,38.98 147.94,40.29 147.94,50.66 v1(151.38,54.1)
USB_PWR_CRL2_B1: length 2.4
  TOP w0.102: Q45.B 175.37,51.63 v2(174.75,51.63) 174.56,51.44 R485.2
USBRBIAS_PCH: length 12
  TOP w0.127: U29.AU20 U29.AV20 24.56,47.71 23.55,48.72 22.73,48.72 20.72,50.73 20.41,50.73 20.16,50.98 20.16,51.75 18.67,53.24 v2(18.67,53.87) 18.53,54.01 R617.1
USBVCC01: length 12.4
  TOP w0.508: UU43.5 133.49,223.15 v1(134.87,224.54)
  TOP w0.635: 139.28,221.11 140.34,221.11 ; 140.34,221.11 140.34,222.16 ; 140.34,221.11 141.39,221.11 ; 140.34,221.11 140.34,220.05
  BOTTOM w0.635: 135.19,230.16 USB3R1.10 136.97,230.16 ; USB3R1.1 136.08,234.25 ; USB3R1.1 136.97,233.36 ; USB3R1.1 135.19,233.36
  vias: v2(136.03,223.33) v2(142.1,225.03) v6(140.34,224.38) v6(140.36,223.29) v6(141.73,223.9)
USBVCC23: length 19.5
  TOP w0.508: UU42.5 148.5,226.68 v1(148.51,226.69)
  TOP w0.635: UTC6.1 153.67,224.07 ; UTC6.1 153.67,221.96 ; UTC6.1 152.62,223.01 ; UTC6.1 154.72,223.01 ; USBCN1.5 155.11,229.37 ; USBCN1.5 154.08,228.34 ; USBCN1.5 154.08,230.4 ; USBCN1.1 154.08,233.02 ; USBCN1.1 154.08,230.96 ; USBCN1.1 153.05,231.99 ; USBCN1.1 155.11,231.99
  BOTTOM w0.508: USBCN1.5 154.08,228.96 151.81,226.69 v2(150.67,226.69) v1(148.51,226.69)
USBVCC45: length 14.2
  TOP w0.305: U26.5 175.13,74.16 v1(175.34,74.37)
  TOP w0.508: R418.2 v1(177.74,73.93)
  TOP w0.635: 168.23,78.67 USBF1.2 ; USBF1.2 170.37,78.67 ; USBF1.2 169.3,79.74 ; USBF1.2 169.3,77.6 ; USBF1.1 169.3,77.2 ; USBF1.1 168.23,76.13 ; USBF1.1 169.3,75.06 ; USBF1.1 170.37,76.13
  BOTTOM w0.508: v1(175.34,74.37) 175.77,73.93 v1(177.74,73.93)
USBVCC89: length 17.7
  TOP w0.406: v1(184.53,229.3) 184.53,229.24 184.15,228.85 UU12.5
  TOP w0.635: 184.62,235.97 UTC5.1 ; UTC5.1 185.67,237.02 ; UTC5.1 185.67,234.91 ; UTC5.1 186.73,235.97
  BOTTOM w0.635: RJ45.U5 174.66,229.29 ; RJ45.U5 172.6,229.29 ; RJ45.U5 173.63,228.26 ; RJ45.U5 173.63,230.32 ; UTC5.1 186.73,235.97 ; UTC5.1 185.67,237.02 ; UTC5.1 184.62,235.97 ; UTC5.1 185.67,234.91 ; RJ45.U1 173.63,232.94 ; RJ45.U1 174.66,231.91 ; RJ45.U1 172.6,231.91 ; RJ45.U1 173.63,230.88
  vias: v2(172.85,235.09) v2(182.16,227.37) v2(186.56,232.76) v6(183.13,235.66) v6(183.21,234.54)
USBVCC1011: length 30.6
  TOP w0.508: UU38.5 v1(161.8,64.08) ; UC80.1 UC79.1 151.21,66.51 v1(151.32,66.63) ; v1(155.12,68.38) 155.55,68.38 156.22,67.7 UR100.2 ; UU37.5 153.62,67.57 153.31,67.87 v1(153.31,67.95)
  TOP w0.635: USBF3.1 139.35,80.29 ; USBF3.1 138.41,79.35 ; USBF3.1 139.35,78.41 ; USBF3.1 140.29,79.35 ; 162.08,71.22 USBF2.1 ; USBF2.1 162.08,73.36 ; USBF2.1 163.15,72.29 ; 140.41,77.35 USBF3.19 ; USBF3.19 141.35,78.29 ; USBF3.19 141.35,76.41 ; UTC9.1 141.62,59.13 ; UTC9.1 140.56,60.19 ; UTC9.1 139.51,59.13 ; UTC9.1 140.56,58.08 ; 163.15,69.75 USBF2.2 162.08,70.82
  BOTTOM w0.635: USBF2.1 163.15,72.29 ; USBF2.1 162.08,71.22 ; USBF2.1 161.01,72.29 ; USBF2.1 162.08,73.36 ; USBF2.2 163.15,69.75 ; USBF2.2 161.01,69.75 ; USBF2.2 162.08,68.68 ; USBF2.2 162.08,70.82
  vias: v1(161.82,73.89)
V_1P5_DAC_FB: length 14.7
  TOP w0.254: R391.2 v2(27.28,68.62) 27.94,67.96 27.94,66.8 27.69,66.55 27.69,62.23 28.05,61.86 28.05,61.85 28.41,61.49 28.42,61.49 31.02,58.89 31.03,58.89 31.33,58.59 31.65,58.27 31.65,57.49 U29.AF2
V_1P5_DAC_FB_R:
  vias: v2(24.37,69.32)
V_1P05_DSW_INT_C: length 2
  TOP w0.381: v2(12.42,32.54) 12.26,32.7 R2225.2 12.24,33.46 C524.1
V_1P05_DSW_INT_R: length 14.9
  TOP w0.381: v1(14.07,33.4) 14,33.48 R2225.1 ; v3(23.75,34.29) 23.75,34.7 24.1,35.05 24.66,35.05 25.1,35.48 25.1,35.59 25.57,36.06 U29.AU41 25.57,36.63 25.74,36.8 U29.AU40
  BOTTOM w0.381: v1(14.07,33.4) 14.22,33.25 16.68,33.25 17.36,33.93 18.92,33.93 19.28,34.29 v2(19.89,34.29) v3(23.75,34.29)
V_1P05_LAN: length 12.7
  TOP w0.203: C91.1 170.81,202.86 170.81,203.37 170.55,203.63 U12.30 ; U12.8 173.12,208.13 C100.1 ; U12.3 v1(172.97,206.13) ; v1(166.8,206.53) 167.2,206.13 U12.22
  TOP w0.305: C93.1 173.11,206.07 173.05,206.13 v1(172.97,206.13) ; C100.1 173.11,208.76 v1(172.44,208.76)
  TOP w0.508: v6(171.45,203.17) 171.7,202.92 171.7,202.35 C91.1 ; C75.1 C83.1 C77.1 165.25,208 v6(165.91,207.34)
  vias: v2(161.54,204.34) v2(172.21,205.49) v6(158.91,204.27) v6(159.93,204.24)
V_1P5_PCH: length 212.5
  TOP w0.203: U29.A33 45.29,40.45 46.39,40.45 46.74,40.11 47.6,40.11
  TOP w0.254: U29.A19 45.45,48.21 46.37,49.12 49.62,49.12 R697.1
  TOP w0.292: v1(40.62,58.27) 40.19,57.84 U29.K1
  TOP w0.305: U29.B13 44.78,51.18 45.66,51.18 ; U29.N10 38.71,53.03 v3(39.12,52.63) 38.81,52.32 U29.N11 ; U29.C1 43.74,57.79 U29.C2 ; U29.A4 44.33,55.76 U29.B4
  TOP w0.356: U29.C1 43.87,57.91 43.87,60.19 C541.1 45.62,60.36 45.62,56.32 U29.A4 ; U29.N11 38.39,52.15 38.35,52.15 38.07,51.87 38.07,51.72 37.55,51.2 37.42,51.2 U29.T14
  TOP w0.381: 45.66,51.18 49.25,51.18 49.64,51.57 R695.1 ; R576.2 49.77,37.99 49.38,38.38 49.38,39.78 49.05,40.11 47.6,40.11
  TOP w0.508: R695.1 50.05,52.17 v1(51.13,52.17) ; v1(40.62,58.27) 42.8,60.45 C540.1 41.91,61.15 R694.2 R547.1 41.85,63.11 41.58,63.37 41.81,63.6 45.01,63.6 45.49,63.12 45.49,61.44 45.21,61.16 44.84,61.16 C541.1 ; R697.1 50.93,47.82 50.93,47.24 ; 50.93,47.24 50.93,45.34 50.55,44.96 50.55,38.63 R576.2 C568.1 49.77,36.47 49.52,36.22 47.4,36.22 47.37,36.25 46.78,36.25 ; 50.93,47.24 55.14,47.24 55.63,47.73 55.63,49.99 53.31,52.3 v1(53.31,52.63)
  TOP w0.762: v6(38.18,68.71) 38.18,71.58 v6(42.75,76.15) ; v1(18.16,99.44) 27.1,108.38 30.72,108.38 35.5,113.16 35.5,130.43 R99.1 R104.1 ; v6(19.05,71.88) L44.1 24.86,72.48 27.34,72.48 v6(29.34,70.48) ; v1(40.51,63.37) 41.58,63.37
  BOTTOM w0.305: v1(40.62,58.27) v2(40.62,57.15) 40.62,56.26 39.85,55.49 39.85,53.99 39.12,53.25 v3(39.12,52.63)
  BOTTOM w0.762: 51.08,65.91 49.43,67.56 49.43,73.46 v2(48.72,74.18) 47.23,75.67 43.23,75.67 v6(42.75,76.15) ; v6(19.05,71.88) 19.05,79.07 v2(18.49,79.63) 18.16,79.96 v1(18.16,99.44) ; v6(29.34,70.48) 31.11,68.71 v6(38.18,68.71) 39.06,67.82 v2(39.06,66.8) 39.06,64.82 v1(40.51,63.37)
  vias: v2(55.31,53.38) v6(57.56,63.53) v6(57.56,62.46)
V_1P05_PCH: length 361.1
  TOP w0.152: U29.AB2 33.58,57.35 33.9,57.67 33.9,58.05
  TOP w0.178: 33.9,58.05 33.9,58.99 v1(34.14,59.23)
  TOP w0.305: v1(182.83,119.25) 182.08,120.01 R159.1 ; U29.AP22 27.58,47.02 27.62,47.02 27.64,47.04 31.4,47.04 U29.AF20 ; v3(33.88,51.12) 33.72,51.12 U29.AC12
  TOP w0.356: U29.AB16 33.47,49.85 v3(33.07,50.26) 32.66,49.85 ; U29.P25 37.7,45.01 v3(37.3,44.61) 37.7,44.21 U29.P26 ; U29.V23 36.01,45.82 v3(35.61,45.42) ; v3(33.07,46.22) 32.66,45.82 U29.AD23 U29.AD25 ; v3(33.07,46.22) 33.47,45.82 U29.AB23 33.51,45.82 v3(33.91,45.42) ; v3(33.07,46.22) 32.67,46.63 U29.AD22 U29.AD20 32.66,47.43 v3(33.07,47.84) 32.67,48.24 32.66,48.24 ; v3(33.07,46.22) 33.2,46.35 33.22,46.35 U29.AB22 33.51,46.63 v3(33.91,46.22) 34.32,45.82 ; v3(33.92,48.65) 33.51,48.24 33.51,48.24 ; v3(33.92,48.65) 33.52,49.05 U29.AB17 33.47,49.05 v3(33.07,49.45) 32.67,49.85 32.66,49.85 ; v3(33.92,48.65) 34.33,48.24 ; v3(33.91,47.84) 34.32,47.43 U29.AA20 ; v3(33.91,47.84) 33.51,48.24 ; v3(33.91,47.84) 33.5,47.43 U29.AB20 ; v3(33.91,47.84) 34.3,48.24 34.33,48.24 ; 33.51,48.24 U29.AB19 ; U29.AA23 34.32,45.82 ; 34.32,45.82 v3(33.91,45.42) ; v3(32.22,47.84) 31.82,47.43 U29.AF20 ; U29.AB25 U29.AB26 U29.AA26 ; U29.AB25 33.51,45.01 v3(33.91,45.42) ; U29.AB25 U29.AD25 ; 35.2,45.82 v3(35.61,46.22) 36.01,46.63 36.01,46.63 ; 35.2,45.82 U29.W23 ; 35.2,45.82 v3(35.61,45.42) ; 34.32,45.01 34.34,44.99 U29.AA26 ; 34.32,45.01 v3(33.91,45.42) ; 34.32,45.01 U29.AA25 ; U29.V19 36.01,48.24 ; 36.01,48.24 v3(35.61,48.64) ; 36.01,48.24 36.01,48.24 v3(35.61,47.84) ; v3(35.61,48.64) 35.2,49.05 U29.W17 ; v3(35.61,48.64) 36.01,49.05 U29.V17 ; U29.V14 36.01,50.66 v3(35.61,51.05) 36.17,51.61 U29.U12 ; U29.P28 37.71,43.4 v3(37.29,42.98) ; U29.P16 37.71,49.85 v3(37.3,49.44) 37.69,49.05 U29.P17 ; U29.P23 37.7,45.82 v3(37.3,46.22) 37.7,46.63 U29.P22 ; 36.01,46.63 U29.V22 ; 36.01,46.63 v3(35.61,47.03) 36.01,47.43 36.01,47.43 ; U29.AD16 32.66,49.85 ; U29.AF23 31.84,45.82 v3(32.22,46.21) U29.AF22 ; U29.AA16 34.36,49.85 v3(34.76,49.45) 35.16,49.85 U29.W16 ; U29.AD19 32.66,48.24 ; 32.66,48.24 v3(33.07,48.64) 32.67,49.05 U29.AD17 ; U29.T20 36.89,47.43 v3(37.3,47.84) 36.89,48.24 U29.T19 ; 34.33,48.24 U29.AA19 ; U29.W26 U29.AA26 ; v3(35.61,47.84) 36.01,47.43 ; v3(35.61,47.84) 35.2,48.24 U29.W19 ; v3(35.61,50.26) 35.2,50.66 U29.W14 ; U29.T16 36.85,49.85 v3(36.45,49.45) 36.05,49.85 U29.V16 ; U29.P14 v3(37.32,50.26) ; v3(35.61,45.42) 35.2,45.01 U29.W25 ; v3(35.61,45.42) 36.01,45.01 U29.V25 ; v3(38.23,50.29) 38.77,50.83 U29.M14 ; U29.AD25 U29.AF25 ; 36.01,47.43 U29.V20 ; U29.AF19 31.84,48.24 v1(32.24,48.64)
  TOP w0.381: v1(183.04,115.21) 183.04,115.16 182.64,114.77 180.52,114.77 179.62,113.86 179.62,88.02 180.19,87.45 180.19,82.65 177.51,79.97 172.19,79.97 171.63,80.53 166.12,80.53 165.61,80.01 163.35,80.01 159.42,83.94 v1(159.4,83.94) ; v1(35.56,30.1) 35.69,29.97 35.69,29.4 C557.1 ; v1(29.18,66.78) 29.18,68.02 R772.1 ; v1(183.13,146.3) 183.13,146.69 182.01,147.81 180.57,147.81 v1(180.21,147.45) 177.56,150.1 R808.1 177.04,150.32 175.84,151.51 171.08,151.51 170.84,151.75 169.65,151.75 167.97,153.44 167.97,158.39 168.24,158.66 168.24,161.46 168.96,162.18 170.1,162.18 170.27,162.01 R109.1 ; C506.1 v1(34.09,61.34) 34.09,59.28 v1(34.14,59.23) ; R2216.1 v1(172.59,143.13) ; C615.1 v1(38.48,28.47)
  TOP w0.508: C527.1 61.54,29.59 61.38,29.75 v1(61.19,29.75) ; R411.1 171.4,145.92 171.65,145.67 v1(171.68,145.67) 171.75,145.75 172.16,145.75 172.4,145.98 v1(172.58,145.98) ; v1(68.28,73.03) 67.12,73.03 R788.1 66.99,72.96 66.93,73.03 v1(66.17,73.03) ; v1(42.03,27.43) 42.04,27.43 42.67,26.8 C463.1 ; v1(51.61,31.9) 51.51,31.9 51.49,31.88 50.84,31.88 C446.1 ; 60.83,39.88 v1(60.83,42.29)
  BOTTOM w0.381: 36.12,51.36 36.7,51.94 36.7,54.92 35.46,56.16 35.46,57.11 34.14,58.43 v1(34.14,59.23) ; v1(172.59,143.13) 171.87,142.41 170.95,142.41 170.36,143 v2(170.36,143.74) 170.36,144.4 171.63,145.67 v1(171.68,145.67) ; v1(183.13,146.3) 183.58,146.3 189.55,140.33 189.55,128.61 183.67,122.73 183.67,120.09 v1(182.83,119.25) 183.04,119.05 v2(183.04,117.25) v1(183.04,115.21) ; v1(159.4,83.94) 159.38,83.96 109.13,83.96 108.1,82.93 v2(107.04,82.93) 95.12,82.93 93.61,81.42 91.3,81.42 89.26,79.38 88.39,79.38 86.49,81.28 72.67,81.28 68.76,77.37 68.76,73.51 v1(68.28,73.03)
  BOTTOM w0.508: v1(60.83,42.29) 61.35,42.29 65.33,46.27 65.33,72.19 v2(65.41,72.26) v1(66.17,73.03) ; v1(172.58,145.98) 173,146.41 179.17,146.41 v1(180.21,147.45) ; v1(34.09,61.34) 33.22,61.34 v2(31.83,62.74) 29.42,65.14 29.42,65.26 29.18,65.5 v1(29.18,66.78)
  vias: v2(34.77,50.67) v2(35.99,44.63) v6(57.66,36.2) v6(57.66,35.05) v6(59.33,35.36) v6(60.99,35.36) v6(62.48,36.2) v6(63.25,34.92) v6(64.39,36.4)
V_1P05_PECI_VCOM: length 26.7
  TOP w0.254: U27.N35 130.25,155.51 130.25,155.51 v1(130.3,155.46)
  BOTTOM w0.254: TP133.1 153.87,157.2 153.28,157.79 132.64,157.79 v1(130.3,155.46)
V_1P5_RTC_INT: length 5
  TOP w0.356: C415.1 20.73,38.24 v2(20.9,38.42) 20.92,38.4 21.6,38.4 22.2,39.01 22.26,39.01 22.63,39.38 U29.AW35
V_1P5_STBY_INT: length 22
  TOP w0.305: U29.AH28 30.6,43.23 30.33,43.5 v3(30.33,43.77)
  TOP w0.381: C417.1 12.26,37 v1(12.96,37.71)
  BOTTOM w0.203: v3(30.33,43.77) 29.84,43.28 29.64,43.28 28.43,42.07 24.1,42.07 23.56,41.53 20.82,41.53 v2(20.24,40.95) 19.74,40.44 15.73,40.44 13.01,37.72 12.97,37.72 v1(12.96,37.71)
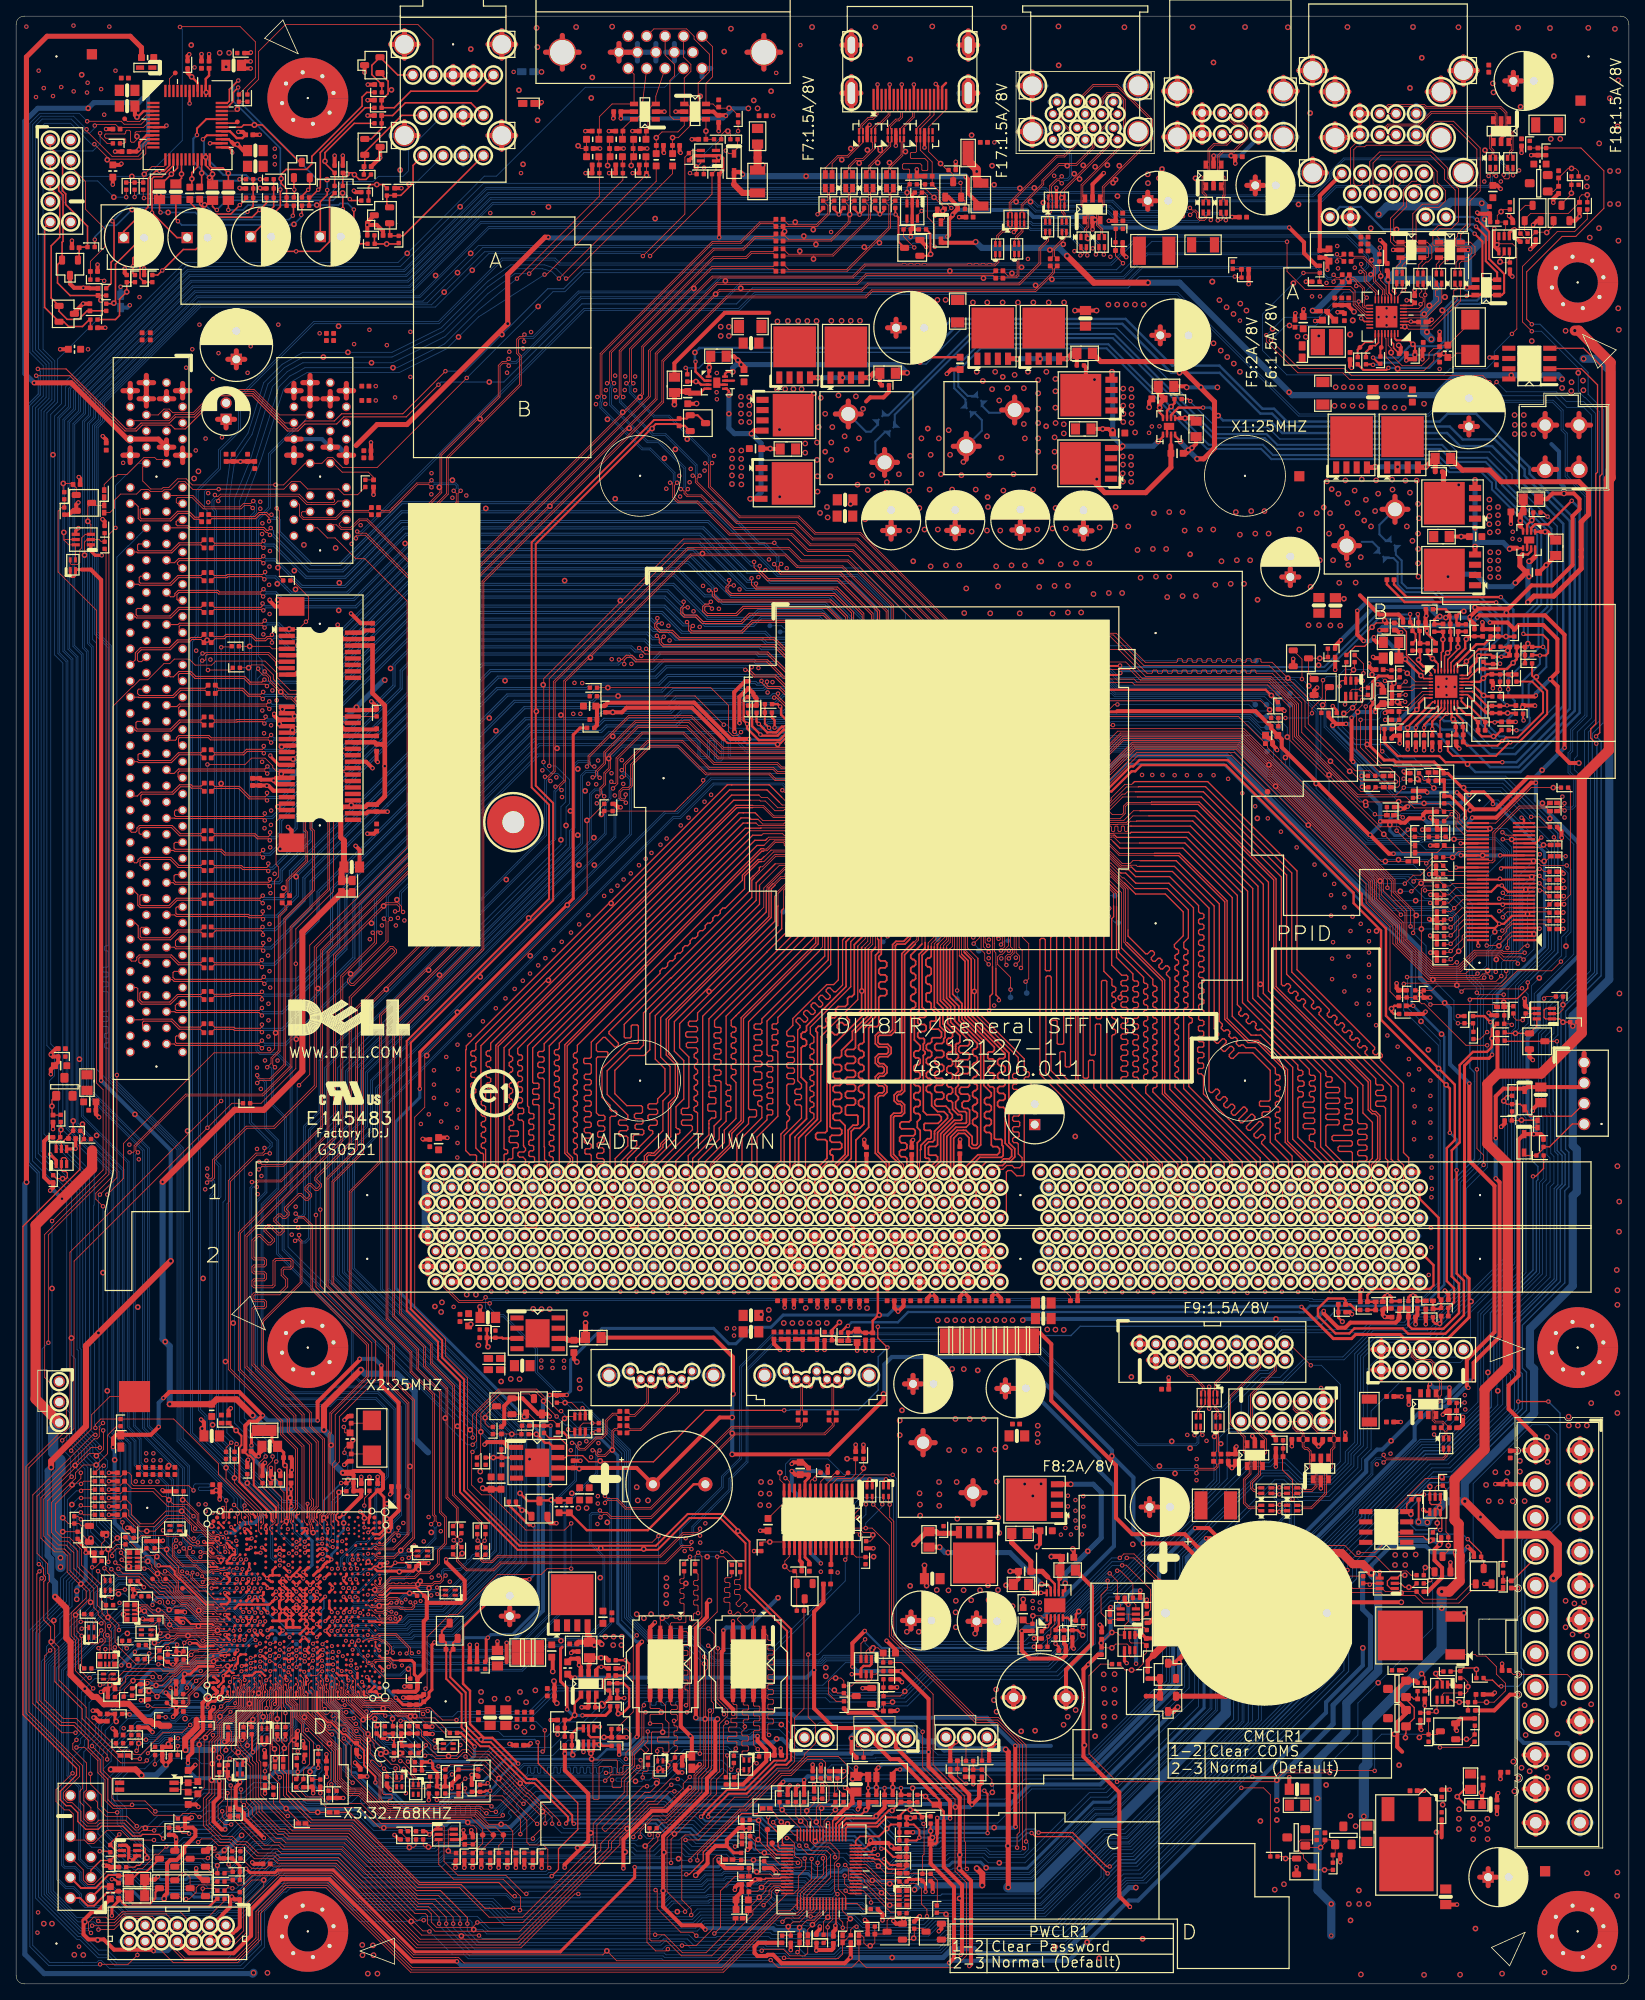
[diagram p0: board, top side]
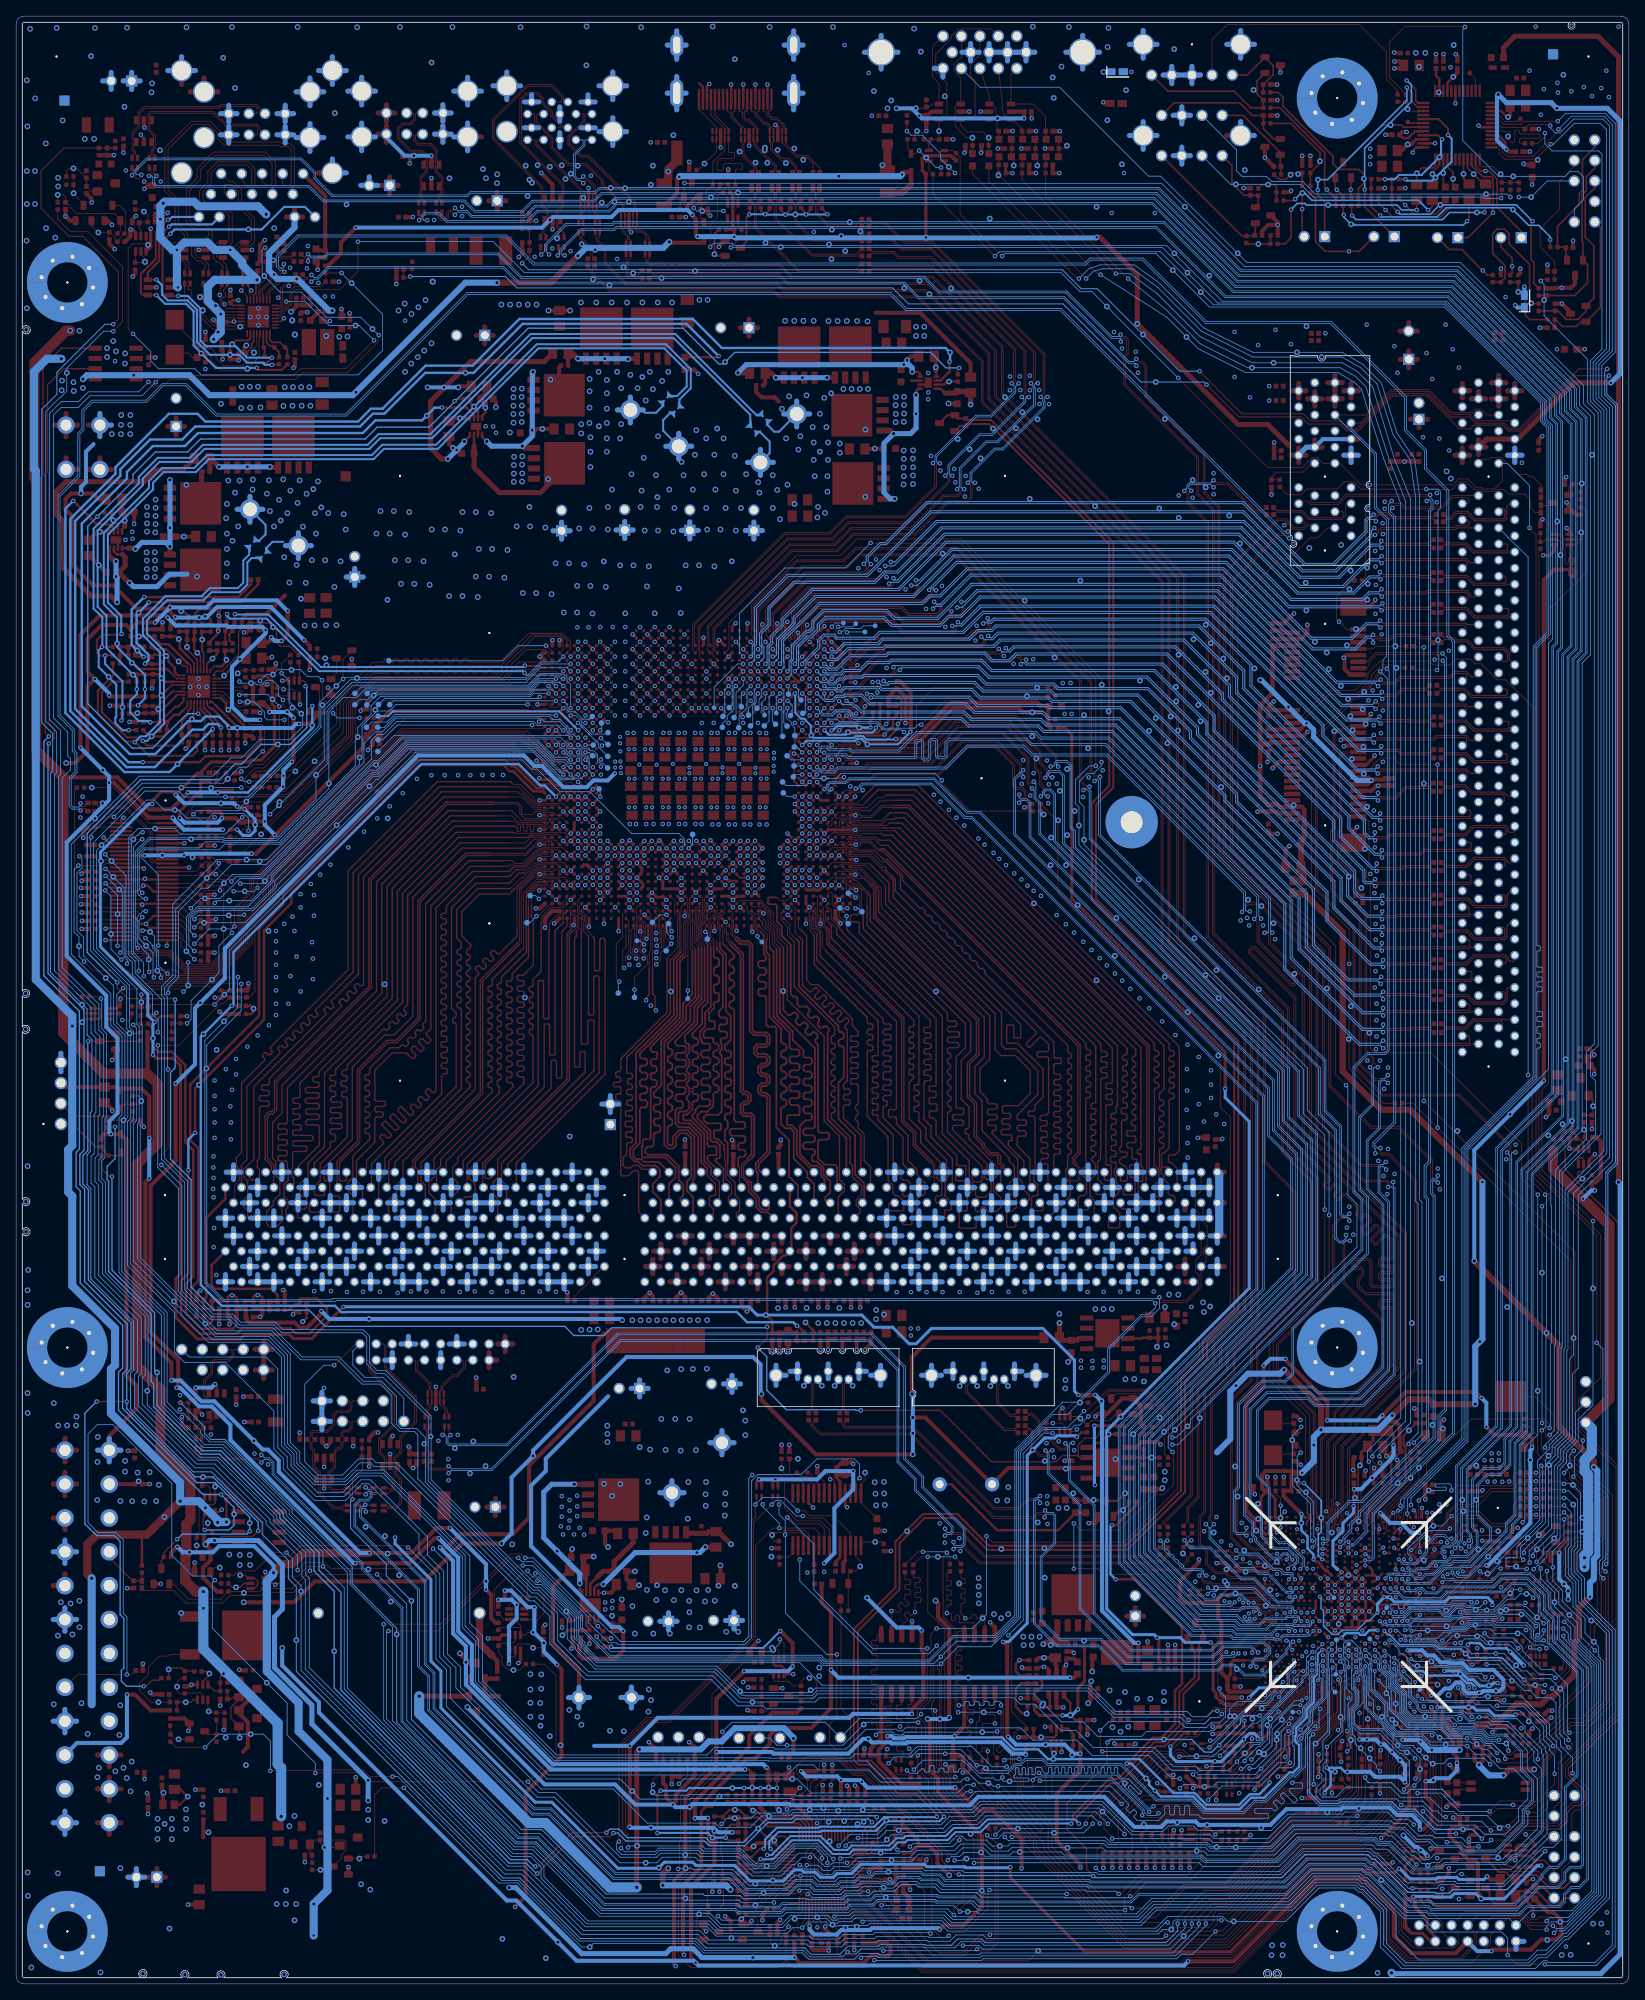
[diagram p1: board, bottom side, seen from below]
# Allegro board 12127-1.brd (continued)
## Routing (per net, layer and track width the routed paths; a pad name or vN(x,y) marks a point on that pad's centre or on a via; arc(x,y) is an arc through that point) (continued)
V_1P05_XCK_DCB_FB_R: length 11.6
  TOP w0.203: v2(33.35,64.29) 33.58,64.06 33.58,60.95 33.58,60.95 U29.AB1
  TOP w0.381: R772.2 31.72,67.35 C544.1 33.19,65.89 33.19,65.28 C545.1 33.16,64.48 v2(33.35,64.29)
V_1P05V: length 18.8
  TOP w0.381: v1(70.23,33.29) 73.09,33.29 73.67,33.87 R287.2 ; 67.72,41.76 67.51,41.55 67.51,37.52 68.33,36.7 v1(68.33,34.04)
  TOP w0.635: 60.16,45.59 TC22.1 ; TC22.1 61.21,44.54 ; TC22.1 61.21,46.65 ; TC22.1 62.27,45.59
  BOTTOM w0.381: v1(68.33,34.04) 69.08,33.29 v2(69.27,33.29) v1(70.23,33.29)
  vias: v2(67.56,42.55)
V_3P0_BAT_VREG: length 189.1
  TOP w0.305: R494.1 v1(25.2,25.15)
  TOP w0.381: v3(27.43,41.35) 27.43,41.3 27.12,41 U29.AP33
  TOP w0.508: v1(21.31,27.41) 21.31,28.14 21.84,28.68 21.84,30.15 23.18,31.49 R502.2 C569.1 23.11,33.08 23.11,34.84 v1(23.87,35.59) ; R515.1 19.75,34.92 v1(18.57,36.11) ; v1(25.2,25.15) 25.2,23.19 24.49,22.48 24.49,20.14 25.48,19.15 v1(25.93,19.15) ; R499.1 115.84,25.85 118.2,23.49 118.2,22.57 v1(118.54,22.23) 119.41,23.09 119.41,24.54 119.76,24.89 R481.1
  TOP w0.635: D26.3 143.5,33.77 v6(144.04,34.32)
  BOTTOM w0.508: v1(25.93,19.15) 25.93,19.99 26.89,20.94 28.76,20.94 29.69,21.86 35.49,21.86 35.7,21.65 42.5,21.65 44.44,19.71 v2(52.3,19.71) 53.31,19.71 53.74,20.14 57.32,20.14 58.01,19.46 61.32,19.46 65.05,23.19 78.34,23.19 80.69,23.19 81.73,22.15 103.97,22.15 104.12,22.3 116.1,22.3 v2(116.48,21.92) 118.24,21.92 v1(118.54,22.23) 123.22,22.23 125.72,24.73 134.46,24.73 v6(144.04,34.32) ; v1(25.2,25.15) 24.35,25.15 v2(24.25,25.25) 24,25.5 22.3,25.5 21.31,26.49 v1(21.31,27.41) ; v1(23.87,35.59) 22.85,36.61 22.19,36.61 21.43,37.37 20.9,37.37 20.52,36.99 20.52,36.51 20.04,36.04 18.9,36.04 18.83,36.11 v1(18.57,36.11) 18.29,36.11 18.07,36.33 v2(16.49,36.33) 16,36.33 15.57,36.76 15.57,37.72 16.79,38.94 19.76,38.94 20.58,39.76 22.23,39.76 22.35,39.88 23.34,39.88 24.18,40.72 24.99,40.72 25.63,41.35 v3(27.43,41.35)
V_3P3_A: length 360.5
  TOP w0.203: 92.33,12.95 92.84,12.95 92.96,13.08 94.74,13.08 94.86,13.2 U61.11
  TOP w0.254: R760.1 R671.1
  TOP w0.305: U29.AW38 24.56,38.06 U29.AV39 24.9,37.34 U29.AW39 23.97,37.34 v6(23.72,37.1)
  TOP w0.356: RN22.1 6.71,174.7 6.88,174.52 7.16,174.52 7.36,174.72 RN22.2 8.14,175.37
  TOP w0.381: R602.2 88.98,16.24 88.14,17.08 ; R670.1 R625.1 27.75,14.61 R671.1
  TOP w0.508: v1(24.97,15.88) 25.29,15.56 R670.1 ; v1(10.54,112.01) 10.54,174.09 9.26,175.37 8.14,175.37 ; 92.33,12.95 v1(91.66,12.95) 91.57,12.86 91.48,12.86 90.93,12.32 C462.1 ; R563.2 26.29,30.25 26.06,30.02 v1(25.83,30.02) ; R646.2 28.19,30.38 v1(28.06,30.24) ; R605.1 R604.2 89.62,19.33 88.14,17.84 88.14,17.08 86.71,17.08 85.75,16.12 85.75,14.94 v6(84.28,13.46) ; R635.2 92.04,5.09 91.57,4.62 91.57,3.84 91.95,3.45 93.07,3.45 93.22,3.61 93.88,3.61 94.92,2.57 102.76,2.57 v1(103.45,3.26) 103.5,3.31 R727.1 ; R367.1 103.61,28.66 v6(103.61,30.43) ; R537.1 176.78,18.16
  TOP w0.635: v6(123.04,11.96) 123.04,28.74 v6(122.71,29.07) ; 181.5,13.23 TC38.1 ; TC38.1 182.55,12.18 ; TC38.1 182.55,14.29 ; TC38.1 183.6,13.23 ; v6(150.01,35.67) D26.1
  TOP w0.762: 18.99,32 17.92,32 R656.2 17.03,32.25 16.69,32.59 16.1,32.59 13.96,34.73 R83.2 12.73,34.73 12.66,34.67 10.9,34.67 9.98,35.59 9.49,35.59 6.75,38.33 6.75,42.36 6.22,42.89 6.22,46.61 v1(4.83,48.01) ; v6(21.01,29.01) 20.96,29.05 20.96,30.37 22.38,31.79 22.38,32.74 ; v6(19.17,89.64) 8.66,79.13 8.66,69.14 4.34,64.82 v6(4.34,64.06)
  BOTTOM w0.508: v1(25.83,30.02) 26.06,30.25 26.95,30.25 28.04,30.25 v1(28.06,30.24) ; v1(24.97,15.88) 25.68,16.59 v2(25.84,16.59) 26.23,16.98 26.53,16.98 v6(27.97,18.41) ; v6(19.17,89.64) 19.17,103.38 v2(14.73,107.82) v1(10.54,112.01)
  BOTTOM w0.635: v1(103.45,3.26) v2(108.64,3.26) 114.95,3.26 116.04,4.36 118.83,4.36 119.44,3.75 129.84,3.75 138.03,11.94 v6(138.86,11.94)
  BOTTOM w0.762: v1(25.83,30.02) 24.82,29.01 v2(24.43,29.01) v6(21.01,29.01) ; v1(4.83,48.01) 4.83,49.73 4.34,50.22 4.34,52.68 3.91,53.11 3.91,63.63 v6(4.34,64.06) ; v6(103.61,30.43) 103.61,30.53 104.78,31.7 110.87,31.7 112.5,30.07 114.1,30.07 115.1,29.07 v6(122.71,29.07)
  BOTTOM w1.27: v6(123.04,11.96) 126.37,11.96 126.95,12.54 134.36,19.95 136.41,19.95 150.01,33.55 v6(150.01,35.67)
  vias: v6(20.95,32.89) v6(22.35,35.81) v6(156.08,11.68) v6(157.23,12.36)
V_3P3_BG: length 110.8
  TOP w0.254: C1673.1 28.77,65.51 28.98,65.51 29.46,65.02 29.46,61.84 32.22,59.08 U29.AE1 ; 46.15,56.26 45.12,55.23 44.55,55.23 U29.B6 ; U29.AW21 23.52,47.02 20.32,50.23 20.21,50.23 19.67,50.77 19.67,51.17 19.07,51.78 17.8,51.78 v1(17.68,51.89)
  TOP w0.508: v1(42.6,77.5) 42.6,77.37 37.39,72.16 v1(37.39,69.88) ; v1(12.01,66.57) 12.01,67.67 12.43,68.08 R97.1 16.7,68.08 v1(17.68,69.06) ; v1(45.29,76.68) 45.29,74.22 47.43,72.07 C398.1 47.43,58.67 46.48,57.72 46.48,56.59 46.15,56.26 ; C1673.1 28.42,66.23 28.42,69.22 28.93,69.72 29.82,69.72 v1(30.58,70.48) 27.67,73.4 19.02,73.4 v1(18.26,72.64)
  BOTTOM w0.508: v1(37.39,69.88) 31.19,69.88 v1(30.58,70.48) ; v1(12.01,66.57) 12.01,66.35 12.22,66.14 v2(12.22,64.97) 12.22,57.14 16.46,52.89 17.46,51.89 v1(17.68,51.89) ; v1(17.68,69.06) 17.68,72.06 v1(18.26,72.64) ; v1(42.6,77.5) 44.47,77.5 v1(45.29,76.68)
V_3P3_EPW: length 96.3
  TOP w0.254: v1(44.55,24.97) 44.55,25.7 43.15,27.11 43.15,28.93 42.57,29.51 42.49,29.51 42.21,29.79 C572.1 41.94,29.86 40.85,30.95 40.54,30.95 40.25,31.24 40.25,31.24 39.07,32.42 38.62,32.42 37.3,33.74 U29.R41
  TOP w0.508: C1669.1 82.59,27.13 R507.1 82.8,28.26 R409.1 83.79,30.56 v1(83.62,30.73) 82.42,31.93 U30CN1.8 ; R630.1 93.03,29.02 91.95,30.1 v1(91.95,30.73) ; R630.1 93.16,28.19 93.31,28.35 C1671.1 94.04,29.15 92.71,30.48 U35CN1.8 ; R630.1 93.03,27.62 90.13,24.73 R631.1 R504.1
  BOTTOM w0.305: v1(83.62,30.73) 83.44,30.56 77.72,30.56 76.25,29.08 73.25,29.08 72.04,27.87 v2(71.37,27.87) 60.67,27.87 56.47,23.67 53.86,23.67 52.41,22.22 48.31,22.22 47.02,23.52 45.83,23.52 44.55,24.79 v1(44.55,24.97)
  BOTTOM w0.508: v1(83.62,30.73) 83.74,30.61 89.76,30.61 89.91,30.45 91.13,30.45 91.4,30.73 v1(91.95,30.73)
V_3P3_LAN: length 81.3
  TOP w0.203: U12.11 170.55,209.38 170.26,209.68 170.26,211.18 v6(170.13,211.3)
  TOP w0.508: v1(179.93,210.36) U11.5 ; R150.1 160.85,207.42 v6(160.78,207.48) ; U6.5 v1(180.06,215.01) ; v6(170.13,211.3) 170.13,212.33 C86.1 ; U9.5 v1(173.46,215.01)
  TOP w0.635: RJ45.L2 166.49,219.1 ; RJ45.L2 164.45,219.1 ; RJ45.L2 165.47,218.08 ; RJ45.L2 165.47,220.12
  BOTTOM w0.762: RJ45.L2 165.47,217.79 168.63,214.63 168.63,212.42 167.61,211.4 v2(165.2,211.4) 165.11,211.4 161.18,207.48 v6(160.78,207.48)
  BOTTOM w1.016: v1(179.93,210.36) 180.06,210.49 v1(180.06,215.01) ; v6(168.99,219.43) 169.01,219.43 170,220.42 177.37,220.42 177.93,220.98 181.58,220.98 v6(181.76,220.8) 182.12,220.45 v2(182.12,218.82) 182.12,216.51 180.62,215.01 v1(180.06,215.01) ; v6(175.5,203.94) 174.62,204.81 v2(174.62,207.06) 176.23,208.66 176.23,210.46 175.39,211.3 v6(170.13,211.3) 171.96,213.13 171.96,213.51 v1(173.46,215.01) 175.34,215.01 176.25,215.93 179.15,215.93 v1(180.06,215.01)
V_3P3_LAN_VDDSREG: length 1.5
  TOP w0.508: C94.1 162.57,207.25 R150.2
  vias: v5(165.76,206.27)
V_3P3_PCIVAUX: length 47.9
  TOP w0.508: C240.1 44.62,155.55 MINI1.24 40.73,155.55 v1(39.97,156.32) ; v1(31.93,149.22) 32.25,149.55 MINI1.39 ; v1(31.93,149.22) 31.83,149.33 30.37,149.33 C424.1 29.32,149.49 C421.1 ; v1(31.93,149.22) 32.4,148.75 MINI1.41 ; C418.1 43.24,167.83 42.96,167.55 MINI1.2
  TOP w0.635: 34.45,188.65 SLOT1.B10 ; SLOT1.B10 33.55,189.55 ; SLOT1.B10 35.35,189.55 ; SLOT1.B10 34.45,190.45 ; 14.15,188.65 SLOT2.B10 ; SLOT2.B10 13.25,189.55 ; SLOT2.B10 15.05,189.55 ; SLOT2.B10 14.15,190.45
  BOTTOM w0.635: 33.55,189.55 SLOT1.B10 ; SLOT1.B10 34.45,190.45 ; SLOT1.B10 34.45,188.65 ; SLOT1.B10 35.35,189.55 ; SLOT2.B10 14.15,190.45 ; SLOT2.B10 15.05,189.55 ; SLOT2.B10 14.15,188.65 ; SLOT2.B10 13.25,189.55 ; v1(31.93,149.22) 33.71,149.22 39.09,154.61 39.09,155.52 39.89,156.32 v1(39.97,156.32) 40.22,156.32 v2(42.21,158.31) 45.57,161.67 v6(45.72,161.67)
  vias: v1(13.27,188.61) v2(4.57,189.61) v2(7.85,114.66) v6(22.07,186.66) v6(22.61,187.55) v6(35.69,178.44) v6(39.62,178.05)
V_5_CODEC: length 4.5
  TOP w0.305: U2.29 26.51,229.73 27.36,228.88 28.05,228.88 C3.1
  TOP w0.508: C3.1 28.11,229.64 v1(27.56,229.64)
  vias: v2(26.04,237.72) v6(25.25,239.45) v6(26.42,239.45)
V_5P0_A: length 223.4
  TOP w0.254: R459.1 173.93,57.29 v6(173.91,57.28)
  TOP w0.305: 184.4,55.7 R495.1
  TOP w0.508: 171.88,28.78 171.27,29.39 171.27,32.46 172.36,33.55 Q47.S 172.36,34.02 171.32,35.06 171.32,36.55 Q46.S 173.55,37.59 R471.1
  TOP w0.635: ATX1.9 193.95,34.03 ; ATX1.9 193.95,31.13 ; ATX1.9 192.5,32.58 ; ATX1.9 195.4,32.58
  TOP w1.016: v6(190.63,50.29) 191.18,50.85 191.18,54.49 189.97,55.7 183.79,55.7 v2(181.6,57.89) v6(179.65,59.84)
  BOTTOM w0.635: ATX1.9 193.95,34.03 ; ATX1.9 195.4,32.58 ; ATX1.9 193.95,31.13 ; ATX1.9 192.5,32.58
  BOTTOM w1.016: v6(173.91,57.28) 174.9,57.28 174.96,57.22 v6(175,57.22) 175,57.51 v2(176.53,59.03) 177.34,59.84 v6(179.65,59.84) 179.65,62.16 188.25,70.75 188.25,76.24 187.73,76.75 187.73,81.26 193.04,86.57 193.04,97.69 193.55,98.2 193.55,103.45 193.04,103.96 v2(193.04,118.77) 193.04,120.03 197.56,124.55 197.56,187.62 197.79,187.85 197.79,199.88 196.16,201.51 v6(194.39,201.51) ; v6(190.63,50.29) 190.63,34.67
  vias: v2(162.46,24.66) v2(171.5,27.13) v6(187.07,34.54) v6(187.2,30.86) v6(191.13,30.99) v6(191.9,34.8) v6(195.33,34.67)
V_5P0_CONN_CRT_L: length 3.2
  TOP w1.016: F7.1 TP2.1 L4.2
V_5P0_HDMI_CONN: length 2.2
  TOP w0.305: HDMI1.18 114.83,235.23 115.32,235.71
  vias: v2(118.49,229.24)
V_5P0_HDMI_CONN_L: length 3.4
  TOP w1.016: F17.1 119.13,223.79 v2(119.13,224.74) 119.13,224.99 L3.2
V_CPU_CORE: length 327.1
  TOP w0.305: G3.2 106.68,26.57
  TOP w0.508: 106.68,26.57 v1(106.93,26.82) ; R119.1 172,169.25 171.45,169.8 169.04,169.8 166.65,172.19 ; v1(157.94,52.17) 151.19,52.17 148.11,55.25 v1(147.57,55.25) ; v1(180.21,111.63) 180.21,102.08 183.33,98.96 183.33,80.82 179.91,77.39 179.91,74.09 v1(180.09,73.91)
  TOP w0.635: 124.53,179.22 TC3.1 ; TC3.1 123.48,180.28 ; TC3.1 125.59,180.28 ; TC3.1 124.53,181.33 ; TC12.1 158.01,175.5 ; TC12.1 159.07,174.45 ; TC12.1 158.01,173.4 ; TC12.1 156.96,174.45 ; 106.1,188.67 L39.2 ; L39.2 107.7,190.27 ; L39.2 109.3,188.67 ; L39.2 107.7,187.06 ; 116.23,190.66 L40.2 ; L40.2 119.43,190.66 ; L40.2 117.83,189.06 ; L40.2 117.83,192.26 ; 115.4,180.23 TC2.1 ; TC2.1 116.46,181.28 ; TC2.1 116.46,179.17 ; TC2.1 117.51,180.23 ; L27.2 166.6,178.34 ; L27.2 165,179.94 ; L27.2 163.39,178.34 ; L27.2 165,176.74 ; 108.51,179.16 TC1.1 ; TC1.1 107.45,180.21 ; TC1.1 109.56,180.21 ; TC1.1 108.51,181.27 ; TC10.1 133.41,180.19 ; TC10.1 132.36,179.13 ; TC10.1 131.3,180.19 ; TC10.1 132.36,181.24
  BOTTOM w0.254: G9.1 107.72,192.41 106.55,191.24 106.55,189.81 L39.2 ; G11.1 118.88,194.8 119.76,193.91 119.76,192.6 L40.2 ; G2.1 168.94,178.07 168.19,178.82 166.88,178.82
  BOTTOM w0.508: v1(180.09,73.91) 179.63,73.91 177.32,71.6 175.73,71.6 173.43,69.31 173.43,67.46 158.14,52.17 v1(157.94,52.17) ; v1(147.57,55.25) 145.17,52.85 145.17,43.71 143.48,42.02 143.48,37.28 133.45,27.24 107.36,27.24 v1(106.93,26.82) ; v3(125.75,150.1) 126.63,149.22 128.4,149.22 129.23,148.4 132.14,148.4 134.77,151.02 135.74,151.02 137.04,152.32 150.17,152.32 174.12,128.38 174.12,124.69 v2(177.15,121.65) 177.82,120.99 177.82,114.03 v1(180.21,111.63)
  BOTTOM w0.635: TC3.1 124.53,181.33 ; TC3.1 123.48,180.28 ; TC3.1 125.59,180.28 ; TC3.1 124.53,179.22 ; L40.2 117.83,192.26 ; L40.2 116.23,190.66 ; L40.2 117.83,189.06 ; L40.2 119.43,190.66 ; 106.1,188.67 L39.2 ; L39.2 107.7,187.06 ; L39.2 109.3,188.67 ; L39.2 107.7,190.27 ; TC1.1 109.56,180.21 ; TC1.1 108.51,181.27 ; TC1.1 107.45,180.21 ; TC1.1 108.51,179.16 ; TC2.1 116.46,181.28 ; TC2.1 116.46,179.17 ; TC2.1 115.4,180.23 ; TC2.1 117.51,180.23 ; 156.96,174.45 TC12.1 ; TC12.1 158.01,173.4 ; TC12.1 158.01,175.5 ; TC12.1 159.07,174.45 ; L27.2 165,179.94 ; L27.2 166.6,178.34 ; L27.2 165,176.74 ; L27.2 163.39,178.34 ; TC10.1 133.41,180.19 ; TC10.1 132.36,179.13 ; TC10.1 132.36,181.24 ; TC10.1 131.3,180.19
  vias: v1(106.99,155.09) v1(107.8,155.13) v1(108,156.36) v1(108.94,155.13) v1(109.7,155.13) v1(109.83,156.36) v1(110.84,155.13) v1(111.61,155.13) v1(111.66,156.36) v1(113,155.13) v1(113.49,156.36) v1(113.77,155.13) v1(114.96,156.36) v1(115.04,155.13) v1(115.31,158.19) v1(115.8,155.13) v1(117.14,159.1) v1(117.14,157.27) v1(117.07,155.13) v1(117.83,155.13) v1(118.97,168.25) v1(118.97,166.42) v1(118.97,164.59) v1(118.97,162.76) v1(118.97,160.93) v1(118.97,159.1) v1(118.97,157.27) v1(118.97,155.13) v1(119.73,155.13) v1(120.8,168.25) v1(120.8,166.42) v1(120.8,164.59) v1(120.8,162.76) v1(120.8,160.93) v1(120.8,159.1) v1(120.8,157.27) v1(121.13,155.13) v1(121.89,155.13) v1(122.63,168.25) v1(122.63,166.42) v1(122.63,164.59) v1(122.63,162.76) v1(122.63,160.93) v1(122.63,159.1) v1(122.63,157.27) v1(123.42,155.13) v1(124.18,155.13) v1(124.46,168.25) v1(124.46,166.42) v1(124.46,164.59) v1(124.46,162.76) v1(124.46,160.93) v1(124.46,159.1) v1(124.46,157.27) v1(125.74,166.42) v1(125.74,164.59) v1(125.74,162.76) v1(125.74,160.93) v1(125.74,159.1) v1(125.74,157.27) v1(126.01,168.25) v1(127.57,168.25) v1(127.57,166.42) v1(127.57,164.59) v1(127.57,162.76) v1(127.57,160.93) v1(127.57,159.1) v1(127.57,157.27) v1(129.01,168.21) v1(129.4,166.42) v1(129.4,164.59) v1(129.4,162.76) v1(129.4,160.93) v1(129.4,159.1) v1(129.4,158.19) v1(130.4,168.21) v2(103.48,183.51) v2(111.25,176.4) v2(113.06,192.86) v2(120.47,184.35) v2(127.13,176.38) v2(136.35,183.13) v2(145.59,177.27) v2(153.95,171.63) v2(162.15,183.08) v2(164.67,171.75) v3(106.02,152.66) v3(106.02,151.95) v3(106.05,151.03) v3(106.05,150.31) v3(108.31,150.79) v3(108.31,150.12) v3(110.34,151.29) v3(112.4,150.83) v3(112.4,150.15) v3(114.44,151.27) v3(116.51,150.83) v3(116.51,150.12) v3(118.56,151.28) v3(120.58,151.16) v3(122.72,151.18) v3(125,150.84) v3(125,150.13) v3(125.09,154.62) v3(125.09,153.83) v3(125.07,152.84) v3(125.07,151.59) v3(125.71,151.57) v3(125.71,150.83) v6(104.34,185.9) v6(105.28,181.61) v6(105.61,185.24) v6(106.17,187.07) v6(106.17,183.01) v6(107.82,184.91) v6(107.98,186.21) v6(109.47,187.2) v6(110.11,183.01) v6(110.74,185.17) v6(110.74,180.21) v6(110.87,189.48) v6(112.01,183.01) v6(112.27,191.64) v6(112.27,187.2) v6(112.65,180.34) v6(113.28,185.29) v6(113.41,189.61) v6(113.41,175.77) v6(114.3,180.34) v6(114.43,191.64) v6(114.43,183.01) v6(114.68,187.2) v6(115.32,175.9) v6(115.65,192.66) v6(115.82,189.61) v6(116.08,185.29) v6(116.97,175.9) v6(117.22,187.07) v6(117.47,188.72) v6(117.58,169.98) v6(117.83,173.03) v6(118.36,183.01) v6(118.49,180.09) v6(119,185.29) v6(120.4,191.9) v6(120.4,180.21) v6(120.52,183.13) v6(120.65,187.07) v6(120.8,169.95) v6(121.54,175.77) v6(121.77,173.29) v6(122.05,180.21) v6(122.17,189.23) v6(122.43,185.17) v6(122.56,183.13) v6(123.44,175.9) v6(123.7,187.2) v6(124.46,169.95) v6(125.09,175.9) v6(126.11,185.29) v6(126.62,183.13) v6(126.62,180.34) v6(126.87,173.23) v6(128.52,180.47) v6(128.52,169.93) v6(128.78,173.35) v6(128.91,183.01) v6(129.54,176.02) v6(130.18,180.47) v6(130.43,173.35) v6(130.43,170.05) v6(131.44,176.15) v6(132.08,170.05) v6(133.1,176.15) v6(133.6,172.34) v6(134.37,180.59) v6(135.51,172.47) v6(136.27,180.72) v6(137.16,172.47) v6(137.92,180.72) v6(139.06,177.8) v6(139.45,174.37) v6(140.97,177.93) v6(141.1,182.37) v6(141.35,174.5) v6(142.62,177.93) v6(142.75,171.96) v6(143,182.5) v6(143,174.5) v6(144.65,182.5) v6(144.65,172.09) v6(144.91,180.21) v6(146.3,172.09) v6(146.81,180.34) v6(148.46,180.34) v6(148.72,173.48) v6(149.48,176.4) v6(150.62,173.61) v6(151.26,182.5) v6(151.38,176.53) v6(151.76,179.71) v6(152.27,173.61) v6(153.03,176.53) v6(153.16,182.63) v6(153.67,179.83) v6(154.81,182.63) v6(155.32,179.83) v6(159.13,180.34) v6(159.38,182.25) v6(159.77,176.4) v6(160.53,173.23) v6(161.29,182.37) v6(161.67,176.53) v6(162.81,179.83) v6(162.94,182.37) v6(163.32,176.53) v6(164.08,173.74) v6(164.44,180.7) v6(165.2,175.95) v6(166.12,173.76) v6(166.75,176.91)
V_CPU_VCCIO2PCH: length 161.8
  TOP w0.305: U29.C39 43.78,37.77 43.55,38 43.55,38.01 v1(43.52,38.03)
  TOP w0.381: R200.1 69.94,155.74 69.09,154.89 69.09,134.57 50.06,115.54 v1(50.06,111) ; v1(51.87,42.34) 51.56,42.03 51.56,36.48 51.21,36.12 51.21,35.57 51.05,35.42 50.62,34.99 C370.1 50.17,34.61 C369.1 49.15,34.61 49.15,34.61 C368.1 47.98,34.61 47.11,35.48 v1(47.09,35.48) ; R333.2 58.3,40.07 58.3,42.73 v1(58.5,42.93)
  BOTTOM w0.381: v1(43.52,38.03) 44.85,36.7 45.87,36.7 v1(47.09,35.48) ; v1(51.87,42.34) 55.05,42.34 55.63,42.93 v1(58.5,42.93) 58.88,43.31 61.56,43.31 64.76,46.51 64.76,68.59 v2(63.02,70.32) 47.09,86.25 47.09,106.93 50.06,109.91 v1(50.06,111)
V_CPU_VCCIO_RIGHT: length 109.8
  TOP w0.279: XDPC1.43 v1(184.05,139.93) ; XDPC1.44 v1(179.17,139.93)
  TOP w0.305: v1(166.9,148.44) 167.08,148.44 167.15,148.37 R482.1 ; v1(166.85,149.79) R800.1
  TOP w0.356: 136.55,157.82 136.46,157.73 U27.L40
  TOP w0.381: v1(179.71,144.57) 179.71,145.41 177.84,147.28 R639.1 177.1,149.15 R808.2
  TOP w0.508: v1(165.81,151.54) 165.81,151.59 165.61,151.79 v1(165.61,157) ; R808.2 176.05,149.21 R424.1 ; 136.55,157.82 153.71,157.82 155.21,156.31 155.28,156.31 R340.2 155.64,155.64 C187.1 156.95,154.33 156.95,153.35 167.82,142.47 v1(167.92,142.47) 170.25,140.14 v1(170.81,140.14) ; v1(169.16,144.15) 171.53,144.15 171.68,143.99 172.23,143.99 172.77,144.53 v1(174.5,144.53) 174.5,145.04 174.81,145.35 176.19,145.35 R640.1 ; R102.1 R353.1 R226.1 169.52,158.77 C229.1 169.27,158.75 168.58,158.06 v1(168.58,157.71)
  BOTTOM w0.508: v1(165.81,151.54) 166.85,150.5 v1(166.85,149.79) 166.85,149.63 166.9,149.58 v1(166.9,148.44) 169.16,146.17 v1(169.16,144.15) 169.16,143.72 v1(167.92,142.47) ; v1(179.71,144.57) 179.13,144 175.03,144 v1(174.5,144.53) ; v1(165.61,157) 166.32,157.71 v2(166.37,157.71) v1(168.58,157.71) ; v1(170.81,140.14) 178.97,140.14 v1(179.17,139.93) v2(181.86,139.93) v1(184.05,139.93)
V_SM: length 292.7
  TOP w0.305: v1(108.35,141.74) 108.82,141.27 U27.AJ12 ; v1(109.6,26.58) 109.13,26.58 108.71,26.16 G4.2 ; U27.AJ25 120.71,141.32 v1(120.24,141.79) 119.8,141.35 U27.AJ24 ; v1(117.52,141.74) 117.06,141.27 U27.AJ21 ; U27.AJ17 113.4,141.3 v1(113.89,141.79) ; U27.AV13 v1(110.2,133.5) ; C581.1 172.66,81.66 173.09,81.23 176.99,81.23 178.93,83.17 178.93,86.83 178.03,87.73 178.03,103.35 179.02,104.34 179.02,113.93 180.66,115.57 182.41,115.57 183.01,116.17 183.01,118.4 R2227.1 ; U27.AW16 v1(112.03,131.67) ; U27.AU15 v1(111.11,133.5) ; U27.AJ20 116.14,141.3 v1(116.57,141.73) ; U27.AY14 v1(110.66,130.58)
  TOP w0.356: U27.AU20 v1(115.71,134.41) ; v1(113.86,133.5) U27.AV18 ; U27.AY12 108.83,130.66 108.71,130.55 v1(108.71,130.47) ; U27.AV10 v1(104.33,133.49) ; v1(107.31,132.75) 107.34,132.75 107.63,133.04 U27.AV11 ; U27.AY9 v1(104.33,132.57) ; U27.AT17 v1(113.86,134.41) ; U27.AV23 118.92,133.04 119.36,133.47 v1(119.36,133.52) 119.4,133.52 119.8,133.92 U27.AU24 ; U27.AJ9 v1(104.34,142.64) ; U27.AT22 117.53,134.43 117.49,134.43 v1(117.48,134.41) ; U27.AJ13 109.72,141.27 v1(109.26,141.73) ; U27.AV8 102.97,133.93 v1(103.41,134.4) ; v1(111.09,141.73) 111.55,141.27 U27.AJ15
  TOP w0.381: U27.AJ29 124.37,141.34 v1(123.93,141.79) 123.46,141.32 U27.AJ28
  TOP w0.508: C578.1 111.06,100.67 DIMM1.60 ; C582.1 117.03,100.66 DIMM1.54 ; v1(162.15,83.44) 162.15,83.13 163.92,81.37 164.83,81.37 165.46,81.99 171.07,81.99 171.45,82.37 171.45,82.61 C590.1 171.51,83.7 R857.1 171.59,83.78 R664.1 172.66,82.78 172.66,82.78 C581.1 ; v1(147.45,54.1) 146.58,54.1 144.92,55.77 138.42,55.77 136.4,57.78 136.4,64.29 128.37,72.31 128.37,79.32 126.99,80.7 R186.2 ; DIMM1.66 105.45,101.06 C577.1
  TOP w0.635: 117.14,87.05 DIMM2.173 ; DIMM2.173 118.94,87.05 ; DIMM2.173 118.04,87.96 ; 120.14,88.95 DIMM2.170 ; DIMM2.170 121.94,88.95 ; DIMM2.170 121.04,88.05 ; DIMM2.170 121.04,89.86 ; 93.14,87.05 DIMM2.197 ; DIMM2.197 94.04,87.96 ; DIMM2.197 94.04,86.15 ; DIMM2.197 94.94,87.05 ; 105.94,92.75 DIMM2.66 105.04,91.85 ; 99.04,91.85 DIMM2.72 ; DIMM2.72 99.94,92.75 ; DIMM2.72 98.14,92.75 ; 105.14,90.85 DIMM2.65 ; DIMM2.65 106.94,90.85 ; DIMM2.65 106.04,89.95 ; DIMM2.65 106.04,91.76 ; DIMM2.78 93.94,92.75 ; DIMM2.78 92.14,92.75 ; DIMM2.78 93.04,91.85 ; DIMM2.51 120.04,91.76 ; DIMM2.51 120.04,89.95 ; DIMM2.51 120.94,90.85 ; DIMM2.51 119.14,90.85 ; DIMM2.182 109.04,89.86 ; DIMM2.182 108.14,88.95 ; DIMM2.182 109.94,88.95 ; DIMM2.182 109.04,88.05 ; 96.14,88.95 DIMM2.194 ; DIMM2.194 97.04,88.05 ; DIMM2.194 97.94,88.95 ; DIMM2.194 97.04,89.86 ; 117.04,91.85 DIMM2.54 ; DIMM2.54 117.94,92.75 ; DIMM2.54 116.14,92.75 ; 114.14,88.95 DIMM2.176 ; DIMM2.176 115.04,88.05 ; DIMM2.176 115.04,89.86 ; DIMM2.176 115.94,88.95 ; 110.14,92.75 DIMM2.60 ; DIMM2.60 111.94,92.75 ; DIMM2.60 111.04,91.85 ; 108.04,86.15 DIMM2.183 ; DIMM2.183 108.94,87.05 ; DIMM2.183 108.04,87.96 ; DIMM2.57 114.04,91.76 ; DIMM2.57 114.04,89.95 ; DIMM2.57 113.14,90.85 ; DIMM2.57 114.94,90.85 ; DIMM2.191 100.04,87.96 ; DIMM2.191 99.14,87.05 ; DIMM2.191 100.94,87.05 ; DIMM2.191 100.04,86.15 ; 101.14,90.85 DIMM2.69 ; DIMM2.69 102.04,91.76 ; DIMM2.69 102.94,90.85 ; DIMM2.69 102.04,89.95 ; 111.14,87.05 DIMM2.179 ; DIMM2.179 112.04,87.96 ; DIMM2.179 112.94,87.05 ; DIMM2.179 112.04,86.15 ; 105.04,88.05 DIMM2.186 104.14,88.95 ; 95.14,90.85 DIMM2.75 ; DIMM2.75 96.94,90.85 ; DIMM2.75 96.04,89.95 ; DIMM2.75 96.04,91.76 ; DIMM2.189 102.94,87.05 ; DIMM2.189 102.04,87.96 ; DIMM2.189 101.14,87.05 ; DIMM2.189 102.04,86.15 ; DIMM2.62 109.94,92.75 ; DIMM2.62 109.04,91.85 ; DIMM2.62 108.14,92.75
  BOTTOM w0.508: v1(162.15,83.44) 161.16,82.45 v2(156.24,82.45) 124.99,82.45 v6(124.84,82.3) ; v1(109.6,26.58) 133.69,26.58 144.22,37.12 v2(144.22,39.88) 144.22,41.86 145.81,43.45 145.81,52.45 146.04,52.68 146.04,52.69 v1(147.45,54.1)
  vias: v1(106.92,143.77) v1(107.81,143.77) v1(108.95,143.77) v1(109.71,143.77) v1(110.86,143.77) v1(111.62,143.77) v1(112.89,143.77) v1(113.65,143.77) v1(114.99,143.82) v1(115.75,143.82) v1(117.02,143.82) v1(117.79,143.82) v1(119.06,143.82) v1(119.82,143.82) v1(120.96,143.82) v1(121.85,143.82) v1(123.12,143.82) v1(123.88,143.82) v2(70.64,83.08) v2(83.06,49.66) v2(89.51,56.13) v2(92.38,83.01) v6(64.12,83.69) v6(65.15,83.67) v6(66.17,83.67) v6(80.64,50.32) v6(80.64,49.28) v6(80.62,48.23) v6(80.62,47.19) v6(92.28,59.39) v6(92.38,62.25) v6(92.35,60.81) v6(93.34,83.57) v6(93.34,82.42) v6(93.34,59.33) v6(93.42,60.78) v6(93.52,62.2) v6(95.2,81.94) v6(96.27,81.94) v6(97.33,81.94) v6(97.92,83.82) v6(98.4,81.94) v6(99.47,81.94) v6(100.53,81.94) v6(101.98,83.82) v6(105.52,83.79) v6(114.3,82.3) v6(115.44,82.3) v6(116.46,82.3) v6(117.47,82.3) v6(118.49,82.3) v6(119.51,82.3) v6(120.52,82.3) v6(121.54,82.3) v6(122.56,82.3) v6(123.57,82.3)
V_SM_1:
  vias: v2(60.15,74.7)
V_SM_1P5_EN: length 5
  TOP w0.102: v2(110.21,36.27) 109.61,35.67 R312.1 107.56,35.69 R624.1 R627.2
V_SM_VTT: length 24.6
  TOP w0.635: 51.04,99.75 DIMM1.120 ; DIMM1.120 51.04,101.56 ; DIMM1.120 50.14,100.65 ; 51.04,91.85 DIMM2.120 ; DIMM2.120 50.14,92.75 ; DIMM2.120 51.04,93.66 ; 50.14,88.95 DIMM2.240 ; DIMM2.240 51.04,89.86 ; DIMM2.240 51.94,88.95 ; DIMM2.240 51.04,88.05 ; 51.04,95.95 DIMM1.240 ; DIMM1.240 50.14,96.85 ; DIMM1.240 51.04,97.76
  BOTTOM w0.635: 51.94,92.75 DIMM2.120 51.04,91.85 ; DIMM2.240 51.94,88.95 ; DIMM2.240 51.04,89.86 ; DIMM2.240 51.04,88.05
  BOTTOM w1.016: DIMM1.120 50.8,100.41 50.8,97.1 50.99,96.9 ; DIMM2.120 50.8,92.99 50.8,96.71 50.99,96.9 ; 50.99,96.9 DIMM1.240
  vias: v2(51.93,83.99) v6(52.7,83.31) v6(52.81,84.51)
V_VCCIOA_LOAD: length 10.9
  TOP w0.254: R307.1 R805.1 92.84,156.28 v1(93.37,155.75) ; U27.P4 v1(99.77,155.44)
  BOTTOM w0.254: v1(99.77,155.44) 99.22,154.89 97.13,154.89 v2(96.82,155.19) 96.79,155.16 93.84,155.16 93.37,155.63 v1(93.37,155.75)
VBOOT: length 119.1
  TOP w0.203: U52.10 176.34,158.56 175.92,158.14
  TOP w0.267: R221.1 v1(173.58,155.77) 173.58,156.06 175.67,158.14 175.92,158.14
  TOP w0.305: v1(147.19,195.45) 144.15,195.45 143.22,194.53 U8.2
  TOP w0.508: R2233.1 162.75,157.16 163.68,156.24 v1(164.92,156.24)
  BOTTOM w0.305: v1(147.19,195.45) 148.08,195.45 v2(149.07,194.46) 149.66,193.87 155.44,193.87 157.01,192.3 177.44,192.3 179.05,190.69 183.04,190.69 186.26,187.47 186.26,186.66 191.86,181.06 191.86,158.44 185.92,152.5 182.75,152.5 178.65,156.59 177.08,156.59 176.52,157.15 174.83,157.15 173.79,156.1 173.79,155.97 v1(173.58,155.77)
  BOTTOM w0.508: v1(173.58,155.77) 173.54,155.72 165.79,155.72 165.28,156.24 v1(164.92,156.24)
VGA_BLUE: length 201.5
  TOP w0.102: v1(32.26,64.77) 32.11,64.62 32.11,62.75 R425.1 32.77,61.37 33.22,60.91 33.22,57.68 33.3,57.61 33.3,57.2 32.91,56.81 U29.AC3 ; L13.1 78.11,225.62 C36.1 R32.2 78.17,224.35 65.77,211.95 v1(65.53,211.95)
  BOTTOM w0.102: v1(32.26,64.77) 32.41,64.92 32.41,66.07 28.3,70.18 28.3,183.58 30.4,189.1 33.16,197.73 34.05,198.62 36.07,199.8 47.5,199.8 53.4,202.76 54.53,203.88 v2(54.86,204.22) 55.24,204.6 57.34,206.7 v1(65.53,211.95)
VGA_BLUE_C_L: length 3.4
  TOP w0.102: L5.1 76.52,228.66 C23.1 76.58,227.52 L13.2 76.28,226.26 v2(76.28,225.48)
VGA_DACREFSET: length 9.3
  TOP w0.102: U29.AF5 31.74,56 31.43,56.31 31.43,56.64 31.71,56.91 31.82,56.91 32.11,57.21 32.11,57.51 31.93,57.68 31.93,58.62 28.66,61.89 v2(28.66,62.1) R393.1
VGA_DDC_PU: length 7.5
  TOP w0.102: v1(88.01,227.33) 88.39,226.95 D8.K 89.03,227.2 89.47,227.65 R16.1 ; v1(85.31,225.22) 85.28,225.19 R15.1
  BOTTOM w0.102: v1(85.31,225.22) 85.9,225.22 v2(87.12,226.44) v1(88.01,227.33)
VGA_DET: length 302.1
  TOP w0.102: v1(9.83,68.07) 9.51,68.07 2.07,60.64 2.07,34.76 5.69,31.14 v1(7.37,31.14) ; RN3.1 15.41,44.5 17.08,44.5 R596.1 17.72,44.05 17.81,43.96 17.81,43.54 v1(17.88,43.46) 18.06,43.64 19.04,43.64 19.06,43.62 23.79,43.62 23.8,43.61 24.61,43.61 24.89,43.32 U29.AV28
  BOTTOM w0.102: v1(7.37,31.14) 7.59,31.37 7.59,37.11 9.48,38.99 10.87,38.99 13.21,41.33 13.21,41.78 14.33,42.9 17.32,42.9 v1(17.88,43.46) ; v1(9.83,68.07) 9.25,68.65 9.25,79.17 9.1,79.32 9.1,100.93 5.24,104.78 5.24,115.6 4.29,116.55 4.29,194.61 5.63,195.95 5.63,198.21 20.85,213.44 47.35,213.44 v2(48.5,214.59) 58.06,224.16 59.56,224.16 70.59,235.18 80.43,235.18 VGA1.4
VGA_GREEN: length 201
  TOP w0.102: U29.AE2 32.5,57.12 32.5,59.68 30.56,61.62 R426.1 30.56,62.18 30.12,62.62 30.12,64.58 v1(30.94,65.4) ; v1(63.63,212.06) 75.25,223.69 R31.2 C35.1 75.18,225.62 L12.1
  BOTTOM w0.102: v1(30.94,65.4) 30.94,65.68 27.08,69.55 27.08,184.15 29.08,189.1 31.79,198.08 33.63,199.92 35.56,201.02 v2(44.07,201.02) 46.48,201.02 46.74,201.04 52.9,204.12 53.17,204.26 58.51,209.59 61.85,212.06 v1(63.63,212.06)
VGA_GREEN_C_L: length 3.4
  TOP w0.102: v2(73.36,225.48) 73.36,226.26 L12.2 73.66,227.52 C25.1 73.6,228.66 L7.1
VGA_HSYNC_3V: length 194.6
  TOP w0.102: v1(67.31,211.46) 79.38,223.52 L17.1 ; v1(27.34,66.94) 27.08,66.67 R850.2
  BOTTOM w0.102: v1(67.31,211.46) 66.42,212.34 65.28,212.67 61.59,212.67 58.46,210.4 53,204.94 46.61,201.73 v2(38.1,201.73) 35.56,201.73 33.26,200.42 31.23,198.38 29.24,192.11 27.13,188.97 26.44,184.28 26.44,97.03 26.14,96.73 26.14,68.34 27.34,67.13 v1(27.34,66.94)
VGA_HSYNC_3V_L: length 19.4
  TOP w0.102: VGA1.13 80.48,239.18 81.66,238 81.66,236.6 81.08,236.02 81.08,231.65 81.52,231.2 U24.3 82.85,230.43 82.07,229.64 80.1,229.64 v2(79.39,228.93) C18.1 79.38,227.95 L17.2
VGA_HSYNC_3V_R: length 10.2
  TOP w0.102: U29.AH3 30.38,56.79 30.68,57.1 30.68,57.87 30.37,58.19 30.37,58.56 30.38,58.57 30.38,58.83 27.08,62.13 v2(27.08,62.74) R850.1
VGA_PCH_DDCSCL: length 238.3
  TOP w0.102: U29.AL2 29.08,57.43 29.08,57.95 28.79,58.25 28.79,58.52 v3(28.63,58.68) ; U4.1 86.79,224.9 R66.2 86.3,221.93 v1(78.61,214.25)
  BOTTOM w0.102: v1(78.61,214.25) 78.08,214.78 58.09,214.78 v2(53.08,209.78) 51.51,208.2 22.81,208.2 10.71,196.1 10.71,193.84 10.44,193.57 9.93,193.07 9.93,167.48 11.63,165.78 11.63,112.42 20.44,103.61 20.44,67.57 27.88,60.13 27.88,59.13 28.32,58.68 v3(28.63,58.68)
VGA_PCH_DDCSDA: length 239.1
  TOP w0.102: U4.4 83.77,227.35 R65.2 82.93,226.5 82.93,219.46 v1(77.72,214.25) ; U29.AL3 29.13,56.68 28.8,57.01 28.8,57.9 28.21,58.49 28.21,59.2 v1(28.32,59.31)
  BOTTOM w0.102: v1(28.32,59.31) 28.32,60.07 20.71,67.68 20.71,103.67 11.86,112.52 11.86,165.87 10.16,167.58 10.16,192.97 10.53,193.34 10.93,193.75 10.93,196.01 22.85,207.92 51.99,207.92 v2(56.56,212.49) 58.62,214.55 77.42,214.55 v1(77.72,214.25)
VGA_RED: length 197.8
  TOP w0.102: L11.1 72.26,225.62 C34.1 R30.2 72.33,221.68 v1(62.1,211.46) ; U29.AC2 32.91,60.34 31.6,61.65 R412.1 31.14,62.55 31.14,64.21 31.8,64.87 v1(31.8,65.4)
  BOTTOM w0.102: v1(62.1,211.46) 57.41,207.63 53.14,203.36 47.24,200.41 v2(46.74,200.41) 35.81,200.41 34.7,199.76 33.93,199.36 32.6,198.03 29.79,189.23 27.69,183.84 27.69,69.8 31.8,65.68 v1(31.8,65.4)
VGA_RED_C_L: length 3.3
  TOP w0.102: C24.1 70.68,226.63 L11.2 ; C24.1 70.74,227.65 L6.1 ; C24.1 70.03,227.58 v2(69.69,227.92)
VGA_VSYNC_3V: length 197.1
  TOP w0.102: L20.1 81.41,224.47 68.39,211.46 v1(68.2,211.46) ; v1(26.68,67.11) 26.68,67.11 26.66,67.11 26.04,66.48 R852.2
  BOTTOM w0.102: v1(68.2,211.46) 66.97,212.68 65.53,213.16 61.34,213.16 58.5,211.12 52.72,205.35 46.61,202.31 v2(41.15,202.31) 35.56,202.31 32.99,200.82 30.7,198.54 28.76,192.31 26.57,189.11 25.96,184.53 25.96,97.23 25.65,96.93 25.65,68.13 v1(26.68,67.11)
VGA_VSYNC_3V_L: length 17.1
  TOP w0.102: VGA1.14 82.77,238.92 83.68,238.02 83.68,237.15 82.85,236.33 U24.1 83.25,233.11 83.54,232.82 83.54,230.35 82.12,228.93 v2(81.41,228.93) 81.39,228.92 C19.1 81.41,227.95 L20.2
VGA_VSYNC_3V_R: length 9.6
  TOP w0.102: R852.1 v2(26.04,64.01) 26.04,62.66 30.16,58.53 30.16,58.1 30.38,57.89 U29.AH2
VR_READY: length 300.9
  TOP w0.102: v1(190.7,142.17) 191.2,141.68 R819.1 ; v1(33.68,20.83) 33.45,20.83 31.9,22.38 R759.1 ; U52.7 174.55,159.86 172.62,157.93 171.64,157.93 C70.1 171.51,157.75 R84.2 170.93,156.16 169.53,156.16 169.19,155.82 169.19,153.06 v1(169.42,152.83)
  BOTTOM w0.102: v1(169.42,152.83) 171.45,150.8 172.38,150.8 v2(173.76,149.42) 174.29,148.88 184.36,148.88 190.7,142.53 v1(190.7,142.17) 190.75,142.12 190.75,128.11 186.29,123.65 186.29,118.42 185.8,117.93 185.8,107.31 186.18,106.93 186.18,89.08 180.37,83.27 180.37,78.32 179.11,77.06 174.06,77.06 168.03,71.04 168.03,66.31 166.87,65.14 166.87,63.82 162.99,59.94 159.13,59.94 157.05,62.02 156.28,62.02 150.04,55.78 150.04,53.44 147.46,50.86 147.46,40.49 146.15,39.18 146.15,35.43 134.89,24.17 125.95,24.17 121.72,19.94 113.3,19.94 112.74,19.38 108.97,19.38 107.52,20.83 104.06,20.83 103.65,21.23 81.35,21.23 80.31,22.28 65.43,22.28 61.65,18.49 51.89,18.49 51.41,18.01 44.8,18.01 42.11,20.69 33.81,20.69 v1(33.68,20.83)
VREG_PCIAUX_PCH_1: length 3.6
  TOP w0.165: Q39.G 4.45,109.59 v2(4.45,108.84) 4.45,107.86 C678.1 5.51,107.73 R2240.2
W1_DETECT_USB: length 159.2
  TOP w0.102: v1(23.72,151.21) 28.4,151.21 29.18,151.99 30.86,151.99 31.83,151.03 31.83,150.83 32.3,150.35 MINI1.37 ; v1(5.71,67.39) 7.16,68.83 7.16,80.01 7.19,80.04 7.19,89.62 v1(23.72,106.15) 26.76,109.19 R305.1 ; RN2.4 10.4,41.39 10.21,41.58 v1(10.21,41.63) 10.28,41.63 11.05,42.4 11.05,42.8 10.85,43 10.85,43.45 11.05,43.65 11.05,44.87 10.17,45.74 10.17,46.14 9.63,46.69 9.63,49.05 7.16,51.51 7.16,53.45 6.21,54.41 5.26,54.41 3.91,55.75 3.91,59.92 v1(6.88,62.89) ; U29.AR30 26.5,42.34 24.84,42.34 24.61,42.57 v1(23.14,42.57)
  BOTTOM w0.102: v1(6.88,62.89) 6.76,63.02 6.76,65.28 5.71,66.32 v1(5.71,67.39) ; v1(23.14,42.57) 22.3,43.41 22.11,43.41 21.78,43.74 20.24,43.74 19.65,44.33 19.26,44.33 18.94,44.01 17.18,44.01 16.64,43.46 v2(13.79,43.46) 13.28,43.46 11.83,42.01 10.59,42.01 v1(10.21,41.63) ; v1(23.72,106.15) v1(23.72,151.21)
W1_DETECT_USB_R: length 46.9
  TOP w0.102: R305.2 30.38,109.19 34.68,113.5 v1(34.68,126.49) 34.68,130.8 39.36,135.48 39.36,148.17 40.34,149.15 MINI1.40
WAKE_N: length 387
  TOP w0.102: v1(55.88,199.14) 44.77,188.03 40.5,188.03 39.25,189.27 38.65,189.27 37.93,188.55 SLOT1.B11 35.85,188.55 33.17,185.88 v1(32.16,185.88) 21.85,185.88 21.5,186.22 21.1,186.63 20.01,186.63 18.93,185.55 18.24,185.55 18.05,185.36 16.69,185.36 15.7,186.36 15.7,188.1 SLOT2.B11 ; v1(32.32,182.97) 32.64,182.65 32.64,174.5 R269.2 ; U12.21 167.48,206.53 165.81,208.2 165.81,209.68 165.38,210.11 159.84,210.11 157.61,212.34 v1(157.61,216.03) ; v1(3.16,50.29) 2.93,50.06 2.93,35.12 5.65,32.41 7.29,32.41 7.98,31.73 7.98,31.72 11.29,28.41 v1(11.29,27.84) ; U29.AK34 29.31,39.97 v3(29.1,39.77) ; v1(18.54,33.07) 18.48,33.13 R656.1 ; v1(3.99,79.5) 3.99,92.87 11.51,100.39 11.51,179.73 v1(12.32,180.54)
  BOTTOM w0.102: SLOT2.B11 15.08,188.55 12.32,185.79 v1(12.32,180.54) ; v1(11.29,27.84) 11.29,28.86 14.95,32.52 16.98,32.52 17.52,33.07 v1(18.54,33.07) 18.81,33.07 19.2,32.68 19.71,32.68 20.69,33.66 25.8,33.66 26.29,34.15 26.29,34.52 27.35,35.58 27.35,37.29 28.68,38.62 28.68,39.35 v3(29.1,39.77) ; v1(157.61,216.03) 157.58,216.05 140.84,216.05 136.98,212.19 70.42,212.19 68.06,209.83 66.57,209.83 v2(64.74,207.99) v1(55.88,199.14) ; v1(3.16,50.29) 3.66,50.79 3.66,52.39 3.23,52.82 3.23,78.73 v1(3.99,79.5) ; v1(32.16,185.88) 32.16,183.2 32.32,183.03 v1(32.32,182.97)
WIFI_RF_EN: length 203.2
  TOP w0.102: v1(10.77,69.55) 10.31,69.09 10.31,68.74 10.31,67.87 10.03,67.59 9.71,67.59 2.59,60.47 2.59,53.39 3.91,52.07 3.91,50.91 4.13,50.69 4.13,49.89 3.92,49.69 3.92,45.33 4.78,44.48 4.78,42.29 5.3,41.76 5.3,37.67 8.69,34.29 8.69,33.1 9.45,32.34 9.45,32.33 11.94,29.84 R546.1 12.38,29.6 13,28.98 14.07,28.98 14.61,28.45 15.49,28.45 18.2,31.15 20.59,31.15 21.54,32.11 v1(21.59,32.11) ; v1(10.77,96.42) 9.88,97.31 9.88,98.04 11.99,100.15 11.99,158.41 14.4,160.83 14.45,160.83 15.33,161.71 16.33,161.71 18.33,163.7 19.05,163.7 19.62,164.27 21.45,164.27 22.2,163.53 24.25,163.53 24.75,164.03 30.86,164.03 32.38,162.5 32.38,162 33.98,160.4 37.36,160.4 40.61,157.15 MINI1.20 44.69,157.15 R388.2 ; v3(30.27,39.98) 30.58,39.98 U29.AG35
  BOTTOM w0.102: v1(21.59,32.11) 22.29,32.81 26.99,32.81 27.99,33.81 27.99,35.86 27.99,36.03 29.17,37.21 29.17,38.24 29.76,38.82 29.76,39.46 v3(30.27,39.98) ; v1(10.77,69.55) v2(10.77,88.19) v1(10.77,96.42)
XCLK_RCOMP: length 12.2
  TOP w0.203: R547.2 v1(40.31,62.1) ; v3(38.03,52.64) 37.78,52.64 37.46,52.32 U29.R11
  BOTTOM w0.203: v3(38.03,52.64) 38.51,53.12 38.51,55.7 38.16,56.06 v2(38.16,57.78) 38.16,59.95 v1(40.31,62.1)
XDP_DBRESET_N: length 58.5
  TOP w0.102: XDPC1.48 177.34,140.93 C576.1 176.22,140.27 R264.2 171.89,140.27 v2(169.61,142.55) 157.96,154.2 157.96,158.29 155.19,161.07 138.71,161.07 138.39,161.39 U27.G40
XDP_PLTRST_N: length 3.7
  TOP w0.102: R637.2 189.7,139.22 v2(189.48,139.22) 189.08,139.22 188.86,139.43 XDPC1.41
XDP_PWR_DEBUG: length 29
  TOP w0.102: R806.1 181.57,117.16 v1(182.43,118.02) ; XDPC1.45 188.59,140.43 v1(188.95,140.07)
  BOTTOM w0.102: v1(182.43,118.02) 182.37,118.07 182.37,119.52 183.08,120.23 183.08,122.67 185.6,125.18 185.6,126.67 186.39,127.46 186.39,137.44 v2(188.18,139.23) 188.95,140 v1(188.95,140.07)
XDP_PWRGD: length 37.6
  TOP w0.102: v1(191.57,126.77) 190.43,125.62 186.15,125.62 184.25,123.73 176.11,123.73 175.57,123.19 R518.1 173.53,123.19 R519.2 ; v1(192.29,138.68) 189.1,138.68 188.85,138.93 XDPC1.39
  BOTTOM w0.102: v1(192.29,138.68) 192.81,138.16 192.81,130.43 192.2,129.82 v2(192.2,128.68) 192.2,127.39 v1(191.57,126.77)
XDP_VR_READY: length 3.4
  TOP w0.102: XDPC1.47 189.12,140.93 v2(189.41,141.22) R819.2
XTAL_25M_PCH_IN: length 19.1
  TOP w0.102: v1(40.72,65.86) 40.69,65.89 40.69,66.37 41.12,66.8 R430.1 41.55,66.66 C379.1 43.96,65.71 X2.1 ; v3(39.26,54.16) 38.85,54.16 U29.N7
  BOTTOM w0.102: v1(40.72,65.86) 41.14,65.44 41.14,64.18 41.12,64.17 41.12,62.53 v2(41.17,62.48) 41.17,61.84 39.08,59.75 39.08,55.45 38.84,55.21 38.84,54.58 v3(39.26,54.16)
XTAL_25M_PCH_OUT: length 21.8
  TOP w0.102: v1(40.63,69.07) 40.74,68.96 40.74,68.4 40.82,68.32 R430.2 41.41,69.39 C378.1 43.78,69.52 X2.2 ; v3(39.26,54.92) 38.8,54.92 U29.N6
  BOTTOM w0.102: v1(40.63,69.07) 41.74,67.96 v2(41.74,67.44) 41.74,61.84 39.47,59.56 39.47,55.13 v3(39.26,54.92)

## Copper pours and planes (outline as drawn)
5V_DUAL on TOP: 135.61,26.82 133.6,28.83 133.6,38.4 134.06,38.86 137.01,38.86 137.64,38.23 138.58,38.23 138.81,38 138.81,35.43 141.35,32.89 161.57,32.89 164.21,35.53 164.21,44.83 165.84,46.46 174.45,46.46 174.73,46.18 174.73,40.08 174.37,39.73 171.5,39.73 171.49,39.71 171.16,39.71 170.89,39.45 170.89,37.08 170.74,36.93 170.74,34.72 171.07,34.39 171.07,33.07 170.51,32.51 170.51,28.45 168.88,26.82 ; 2 cut-outs
5V_DUAL on TOP: 128.88,31.7 127.94,32.64 127.94,38 127.93,38.01 129.29,39.37 131.19,39.37 131.93,38.63 131.93,32.31 131.32,31.7
5V_DUAL on BOTTOM: 133.22,38.86 131.52,37.16 128.14,37.16 127.9,36.92 127.9,29.58 128.28,29.21 132.87,29.21 136.91,33.25 136.91,38.48 136.53,38.86
5VDUAL_USB_F on TOP: 165.7,54 164.94,54.76 150.64,54.76 148.56,56.84 148.56,61.29 148.87,61.59 151.28,61.59 151.61,61.26 151.61,59.49 153.01,58.09 162.41,58.09 165.29,60.97 165.29,63.04 164.82,63.51 164.82,65.74 165.29,66.21 165.29,69.66 166.09,70.46 169.77,70.46 170.27,69.96 170.27,68.06 168.64,66.43 168.64,59.27 168.81,59.11 168.81,54.41 168.4,54 ; 2 cut-outs
5VDUAL_USB_R on TOP: 190.02,228.27 189.76,228.52 189.76,231.19 190.07,231.5 191.85,231.5 192.35,230.99 192.35,228.68 191.95,228.27
5VDUAL_USB_R on TOP: 184.58,198.25 183.25,199.58 183.25,200.97 183.35,201.06 184.09,201.06 184.11,201.08 184.19,201.16 184.19,202.05 183.92,202.32 183.39,202.32 183.21,202.5 183.21,203.45 183.78,204.03 188.66,204.03 189.03,203.66 189.03,198.68 188.59,198.25 ; 1 cut-out
5VDUAL_USB_R on TOP: 151.38,205.61 147.07,209.93 145.03,209.93 142.14,212.83 142.14,216.81 142.6,217.27 146.2,217.27 146.43,217.04 146.43,213.87 147.83,212.47 148.72,212.47 153.42,207.77 153.42,206.76 152.27,205.61
5VDUAL_USB_R on L2VCC: 159.72,197.04 147.4,209.36 152.32,209.36 160.96,200.72 180.8,200.72 181.43,201.36 184.86,201.36 186.63,203.12 186.63,216.96 189.55,219.89 189.55,229.03 189.82,229.3 191.95,229.3 192.09,229.16 192.09,217.5 188.91,214.33 188.91,207.57 190.18,206.3 190.18,197.04
+5V_VGA on TOP: 90.93,229.36 90.42,229.87 90.42,232.66 90.68,232.92 92.33,232.92 92.46,232.79 92.46,231.01 92.71,230.76 92.71,229.49 92.58,229.36 ; 3 cut-outs
+5V_VGA on BOTTOM: 92.2,232.03 92.46,232.28 92.46,236.35 85.6,243.21 82.3,243.21 80.26,241.17 80.26,238.63 80.64,238.25 87.38,238.25 90.42,235.2 90.42,232.28 90.68,232.03
+12V on TOP: 36.27,195.05 35.03,196.29 34.09,196.29 32.13,198.25 24.71,198.25 22.86,196.39 19.89,196.39 19.02,195.53 15.47,195.53 14.68,196.32 12.98,196.32 11.86,197.43 11.86,201.35 14.61,204.09 40.13,204.09 42.9,201.32 42.9,201.29 43.18,201.02 43.18,195.83 42.39,195.05 ; 11 cut-outs
+12V on TOP: 98.48,49.07 98.37,49.17 98.37,50.14 98.48,50.24 100.25,50.24 100.41,50.09 100.41,49.2 100.28,49.07 ; 1 cut-out
+12V on L2VCC: 4.78,1.84 1.97,4.65 1.97,200.85 11.35,200.85 11.36,200.85 11.43,200.85 11.51,200.85 11.51,200.85 11.57,200.91 11.62,200.96 11.62,200.96 14.56,204.03 25.5,204.03 26.11,203.42 28.55,203.42 29.16,204.03 40.05,204.03 43.12,200.96 43.12,196.02 42.24,196.02 41.61,196.66 40.56,196.66 39.55,195.64 36.02,195.64 35,196.66 33.61,196.66 32.21,198.06 24.56,198.06 23.16,196.66 20.24,196.66 19.35,195.77 15.62,195.77 14.6,194.75 7.23,194.75 6.29,193.75 6.29,78.53 7.94,76.88 7.94,63.96 6.16,62.18 6.16,36.5 8.06,34.59 8.06,12.24 8.55,11.72 10.11,11.72 12.62,9.21 26.49,9.21 33.1,15.81 40.18,15.81 44.24,11.75 75.99,11.75 81.2,6.54 167.34,6.54 168.72,7.92 168.72,13.13 172.16,16.57 182.32,16.57 183.2,17.45 183.2,22.16 189.69,22.16 190.82,23.29 190.82,29 192.1,30.29 197.29,30.29 197.29,17.86 181.28,1.84 48.34,1.84 38.36,11.82 34.03,11.82 30.92,8.71 30.92,5.29 27.48,1.84
AGND on TOP: 58.72,227.13 57.2,228.65 49.91,228.65 48.84,227.58 48.44,227.58 45.97,230.05 45.97,242.9 46.28,243.21 62.87,243.21 62.92,243.15 62.92,229.29 60.76,227.13 ; 2 cut-outs
AGND on TOP: 30.15,224.51 29.9,224.76 29.9,228.07 30.12,228.3 31.52,228.3 32.38,227.43 32.38,224.84 32.05,224.51
AGND on BOTTOM: 21.34,243.21 62.36,243.21 62.99,242.57 62.99,228.85 59.18,225.04 48.39,225.04 47.24,223.9 38.61,223.9 29.97,232.54 29.97,234.57 27.94,236.6 27.94,239.52 27.18,240.28 24.77,240.28 24.38,239.9 24.38,239.01 24.13,238.76 21.21,238.76 20.95,239.01 20.95,242.82
AGND on L2VCC: 4.65,202.12 3.37,203.41 3.37,229.46 3.84,229.93 6.75,229.93 8.7,227.99 8.7,226.24 9.95,224.98 15.83,224.98 20.26,229.41 20.26,235.41 19.64,236.03 16.72,236.03 16.32,236.43 16.32,243.24 63.31,243.24 63.31,229.31 58.98,224.98 57.63,224.98 46.83,214.19 20.75,214.19 16.94,210.38 15.03,210.38 13.14,208.49 13.14,206.58 10.46,203.9 7.54,203.9 7.05,203.41 7.05,202.39 6.78,202.12
AGND on L3: 4.68,202.18 3.43,203.43 3.43,218.21 3.44,218.22 3.43,218.24 3.43,229.44 3.86,229.87 6.73,229.87 8.64,227.97 8.64,226.21 9.93,224.92 15.85,224.92 20.32,229.38 20.32,235.44 19.66,236.09 16.74,236.09 16.38,236.45 16.38,243.24 63.25,243.24 63.25,229.34 58.95,225.04 57.58,225.04 46.79,214.25 20.72,214.25 16.91,210.44 15.01,210.44 13.08,208.51 13.08,206.61 10.44,203.96 7.51,203.96 6.99,203.43 6.99,202.42 6.75,202.18
GND on TOP: 32,41.53 31.88,41.66 31.88,42.29 31.62,42.55 31.37,42.55 30.99,42.16 30.73,42.16 30.61,42.29 30.61,42.67 31.11,43.18 31.37,43.18 31.5,43.05 32.89,43.05 33.53,43.69 34.42,43.69 34.67,43.43 34.67,42.42 34.29,42.04 33.91,42.04 33.4,41.53 33.02,41.53 32.77,41.78 32.51,41.78 32.26,41.53
GND on TOP: 124.42,66.51 124.1,66.83 124.1,69.62 124.49,70 127.25,70 127.46,69.8 127.46,66.75 127.22,66.51 ; 2 cut-outs
GND on TOP: 14.84,62.09 14.71,62.23 14.71,63.37 14.81,63.47 19.89,63.47 20.09,63.27 20.09,62.15 20.03,62.09 ; 5 cut-outs
GND on TOP: 108.69,151.44 108.56,151.57 108.56,153.22 108.69,153.35 110.08,153.35 110.21,153.22 110.21,151.57 110.08,151.44
GND on TOP: 59.84,30.61 59.46,30.99 58.17,30.99 56.9,32.26 56.9,32.92 57.02,33.05 65.1,33.05 65.25,32.89 65.25,30.84 65.02,30.61 ; 5 cut-outs
GND on TOP: outline of 176 points within 100.05,145.63 134.72,168.05
GND on TOP: 25.02,57.02 24.89,57.15 24.38,57.15 24.13,57.4 24.13,58.55 24.38,58.8 25.15,58.8 25.31,58.64 25.31,57.19 25.15,57.02
GND on TOP: 100.33,181.13 99.2,182.26 99.2,182.74 99.19,182.75 99.19,182.91 101.09,184.81 102.26,184.81 102.41,184.66 102.41,181.36 102.18,181.13
GND on TOP: 18.03,55.88 17.86,56.06 17.86,56.77 18.58,57.49 19.6,57.49 19.81,57.28 19.81,55.98 19.71,55.88
GND on TOP: 161.26,197.15 161.06,197.36 161.06,199.16 161.19,199.29 164.06,199.29 164.8,198.55 176.25,198.55 176.4,198.4 176.4,197.41 176.15,197.15 ; 2 cut-outs
GND on TOP: 54.1,47.88 53.91,48.07 53.91,49.32 53.62,49.61 53.62,50.15 53.85,50.39 54.43,50.39 55.05,49.76 55.05,48.07 54.86,47.88
GND on TOP: 175.51,96.77 175.01,97.28 175.01,98.68 173.86,99.82 173.23,99.82 172.59,100.46 172.59,100.97 173.23,101.6 173.23,102.74 172.59,103.38 172.59,112.83 159.41,126.01 159.41,138.22 148.05,149.58 139.52,149.58 139.29,149.82 139.29,150.22 139.75,150.68 149.83,150.68 165.1,135.41 165.1,133.76 168.28,130.59 168.28,119.89 176.91,111.25 176.91,96.9 176.78,96.77
GND on TOP: outline of 93 points within 38.3,37.97 44.32,44.6
GND on TOP: 55.65,82.63 55.55,82.73 54.81,82.73 53.92,83.62 53.92,84.25 54.08,84.4 54.38,84.4 54.74,84.05 56.21,84.05 56.54,83.72 56.54,82.73 56.44,82.63 ; 3 cut-outs
GND on TOP: 63.12,75.84 63.04,75.92 63.04,77.44 63.27,77.67 63.27,80.67 63.07,80.87 61.26,80.87 61.13,81.01 61.13,81.57 61.21,81.66 62.97,81.66 63.6,82.3 65.89,82.3 66.07,82.12 66.07,77.9 66.32,77.65 68.2,77.65 68.35,77.5 68.35,76 68.2,75.84
GND on TOP: 175.01,67.79 174.85,67.94 174.85,70.94 174.96,71.04 175.16,71.04 175.23,70.97 175.23,69.75 175.79,69.19 176.05,69.19 176.12,69.11 176.12,67.84 176.07,67.79 ; 1 cut-out
GND on TOP: 140.39,192 140.16,192.23 140.16,193.27 140.49,193.6 143.71,193.6 143.79,193.52 143.79,192.84 143.64,192.68 141.4,192.68 140.72,192
GND on TOP: 120.88,151.44 120.75,151.57 120.75,153.22 120.88,153.35 122.27,153.35 122.4,153.22 122.4,151.57 122.27,151.44
GND on TOP: 125.17,130.23 125.09,130.3 125.09,133.88 124.76,134.21 124.16,134.21 124,134.06 122.94,134.06 122.28,134.72 122.28,135.03 122.43,135.18 122.71,135.18 122.91,134.98 124.08,134.98 124.54,135.43 124.54,137.36 125.04,137.87 125.6,137.87 125.88,137.59 125.88,136.47 126.52,135.84 126.8,135.84 126.95,135.99 130.38,135.99 130.4,135.97 130.45,135.97 130.63,136.14 130.63,136.4 130.45,136.58 130.45,136.78 130.68,137.01 130.99,137.01 131.55,136.45 132.78,136.45 132.89,136.55 133.08,136.55 133.65,135.98 135.14,135.98 135.43,135.69 135.43,135.36 135.25,135.18 134.14,135.18 133.35,134.39 133.35,134.34 132.74,133.73 132.51,133.73 132.38,133.86 132.38,134.47 132.03,134.82 132.03,135 131.88,135.15 131.5,135.15 131.37,135.03 131.37,134.7 131.55,134.52 131.55,134.29 131.37,134.11 131.11,134.11 130.4,134.82 130.4,135.08 130.28,135.2 129.62,135.2 129.51,135.1 129.51,133.81 129.69,133.63 129.69,133.35 129.13,132.79 129.13,131.34 129.24,131.24 129.24,130.91 128.55,130.23
GND on TOP: 39.88,52.96 39.62,53.21 39.62,56.13 41,57.51 42.59,57.51 42.82,57.28 42.82,56.46 43.13,56.16 43.43,56.16 43.48,56.21 43.86,56.21 43.96,56.11 43.96,55.07 43.56,54.66 43.56,54.18 43.48,54.1 43.48,53.85 43.89,53.44 43.89,53.19 43.71,53.01 43.05,53.01 42.47,53.59 41.53,53.59 41.27,53.34 41.27,53.09 41.15,52.96
GND on TOP: 116.94,151.44 116.81,151.57 116.81,153.22 116.94,153.35 118.24,153.35 118.35,153.23 118.35,151.58 118.21,151.44
GND on TOP: outline of 216 points within 0.79,0.77 199.23,243.21 ; 26 cut-outs
GND on TOP: 106.53,151.44 106.4,151.57 106.4,153.22 106.53,153.35 107.92,153.35 108.05,153.22 108.05,151.57 107.92,151.44
GND on TOP: 114.78,151.44 114.65,151.57 114.65,153.22 114.78,153.35 116.18,153.35 116.31,153.22 116.31,151.57 116.18,151.44
GND on TOP: 32.49,55.51 31.61,56.4 31.61,56.54 31.8,56.73 31.88,56.73 32.48,56.13 33.01,56.13 33.2,56.32 33.2,56.52 33.34,56.66 33.64,56.66 34.45,55.86 34.45,55.75 34.2,55.51 33.56,55.51 33.48,55.58 33.02,55.58 32.95,55.51
GND on TOP: 34.26,51.26 34.09,51.44 33.93,51.44 33.53,51.84 33.53,53.59 33.91,53.98 34.42,53.98 34.67,53.72 34.92,53.72 35.18,53.98 35.31,53.98 35.43,53.85 35.43,53.59 34.8,52.96 34.8,52.07 34.92,51.94 35.31,51.94 35.43,51.82 35.43,51.38 35.31,51.26
GND on TOP: 53.85,28.7 53.59,28.96 53.59,29.97 53.85,30.23 54.86,30.23 55.37,29.72 55.37,29.46 54.61,28.7
GND on TOP: 167.46,214.45 167.39,214.53 167.39,217.98 167.64,218.24 168.33,218.24 168.48,218.08 168.48,214.66 168.28,214.45 ; 3 cut-outs
GND on TOP: 42.95,42.93 42.69,43.18 42.69,43.61 42.72,43.64 42.72,44.5 42.47,44.76 42.03,44.76 41.93,44.86 41.93,45.59 42.69,46.35 42.69,47.85 42.24,48.31 42.24,48.64 42.52,48.92 42.52,49.33 42.95,49.76 43.61,49.76 43.71,49.66 43.71,49.23 43.46,48.97 43.46,48.77 43.84,48.39 43.84,47.83 43.2,47.19 43.2,46.79 43.51,46.48 43.51,46.23 43.9,45.83 43.9,44.56 43.46,44.12 43.46,43.76 43.86,43.36 43.86,43.03 43.76,42.93
GND on TOP: 73.84,41.53 73.63,41.73 73.63,42.06 72.69,43 72.69,43.51 72.14,44.07 72.14,45.09 72.47,45.42 75.77,45.42 75.92,45.26 75.92,41.94 75.51,41.53 ; 4 cut-outs
GND on TOP: 69.6,58.62 69.34,58.88 69.34,60.35 69.57,60.58 71.3,60.58 71.51,60.36 71.51,59.07 71.07,58.62 ; 2 cut-outs
GND on TOP: 88.75,185.06 88.02,185.79 88.02,195.41 89.81,197.21 92.84,197.21 93.34,196.7 93.34,193.5 91.52,193.5 91.22,193.21 90.64,193.21 90.17,192.74 90.17,191.39 90.68,190.88 91.57,190.88 91.71,190.74 91.71,190.13 93.24,188.59 93.24,185.24 93.07,185.06 ; 2 cut-outs
GND on TOP: 127.02,46.18 126.82,46.37 125.84,46.37 125.63,46.58 125.63,47.55 125.81,47.73 130.25,47.73 130.35,47.62 130.35,46.25 130.28,46.18
GND on TOP: 57.1,78.61 56.9,78.82 56.9,81.48 56.95,81.53 57.71,81.53 57.76,81.48 57.76,78.82 57.56,78.61 ; 3 cut-outs
GND on TOP: 135.41,185.9 135,186.31 135,189.61 137.11,189.61 137.87,190.37 137.87,190.98 137.01,191.85 137.01,193.22 136.8,193.42 135.2,193.42 135.01,193.62 135.01,197.99 135.18,198.17 138.31,198.17 138.32,198.16 138.71,198.16 139.17,197.7 139.17,186.56 138.51,185.9 ; 2 cut-outs
GND on TOP: 69.06,156.52 68.81,156.78 68.81,161.48 69.06,161.73 71.35,161.73 71.47,161.6 71.47,156.65 71.35,156.52 ; 9 cut-outs
GND on TOP: 86.66,196.11 86.44,196.34 86.44,200.1 86.49,200.15 87.25,200.15 87.35,200.05 87.35,196.37 87.1,196.11
GND on TOP: 186.39,186.89 186.03,187.25 186.03,189.53 186.49,189.99 194.56,189.99 195.07,189.48 195.07,188.09 193.88,186.89
GND on TOP: 110.72,151.44 110.59,151.57 110.59,153.22 110.72,153.35 112.11,153.35 112.24,153.22 112.24,151.57 112.11,151.44
GND on TOP: 159.77,167.89 159.51,168.15 159.51,170.31 159.77,170.56 164.72,170.56 165.23,170.05 165.23,168.28 164.85,167.89
GND on TOP: 42.92,50.52 42.77,50.67 42.77,50.95 42.54,51.18 42.54,52.2 42.59,52.25 43.48,52.25 43.61,52.12 43.61,51.82 43.46,51.66 43.46,51.16 43.51,51.11 43.76,51.11 43.91,50.95 43.91,50.65 43.79,50.52
GND on TOP: 112.75,151.44 112.62,151.57 112.62,153.22 112.75,153.35 114.15,153.35 114.27,153.22 114.27,151.57 114.15,151.44
GND on TOP: 2.39,230.4 2.08,230.71 2.08,234.85 2.06,234.87 2.06,237.67 2.24,237.85 3.33,237.85 4.27,236.91 5.64,236.91 6.01,237.27 10.76,237.27 11.56,238.07 15.77,238.07 15.98,237.87 15.98,237.29 15.85,237.16 13.54,237.16 13.39,237.01 13.39,232.28 12.37,231.27 10.54,231.27 10.53,231.25 8.41,231.25 7.56,230.4 ; 2 cut-outs
GND on TOP: 100.81,49.28 100.71,49.38 100.71,50.5 100.51,50.7 97.33,50.7 97.13,50.9 97.13,51.38 97.21,51.46 101.83,51.46 102.21,51.08 102.21,49.56 101.93,49.28 ; 2 cut-outs
GND on TOP: 88.27,79.76 87.76,80.26 87.76,83.69 88.27,84.2 90.68,84.2 90.93,83.95 90.93,80.01 90.68,79.76
GND on TOP: 123.04,151.57 123.04,153.22 123.16,153.35 124.23,153.35 124.37,153.22 124.37,151.57
GND on TOP: 160.46,208.8 160.3,208.97 160.3,209.47 160.55,209.73 165.28,209.73 165.56,209.45 165.56,209.02 165.34,208.8 ; 3 cut-outs
GND on TOP: 127.74,80.72 127.48,80.98 127.48,84.86 127.84,85.22 129.13,85.22 130.28,84.07 130.28,80.95 130.05,80.72
GND on TOP: 50.8,52.7 50.55,52.96 50.55,54.1 50.16,54.48 50.16,54.99 50.55,55.37 51.05,55.37 51.94,54.48 51.94,53.21 51.44,52.7
GND on TOP: 53.98,101.85 53.21,102.62 53.21,104.27 53.09,104.39 50.42,104.39 49.91,104.9 49.91,107.06 51.44,108.58 51.44,114.94 81.28,144.78 81.92,144.78 85.72,148.59 86.23,148.59 86.61,148.21 86.61,147.7 86.49,147.57 86.49,147.5 55.24,116.26 55.24,102.36 54.74,101.85 ; 4 cut-outs
